<?xml version="1.0" encoding="utf-8"?>
<device xmlns:xsi="http://www.w3.org/2001/XMLSchema-instance" xmlns:xsd="http://www.w3.org/2001/XMLSchema">
  <name>FM33A0XXEV</name>
  <version>1.0</version>
  <description>ARM 32-bit Cortex SC000 Microcontroller based device</description>
  <cpu>
    <name>SC000</name>
    <version>r1p0</version>
    <endian>little</endian>
    <mpuPresent>false</mpuPresent>
    <fpuPresent>false</fpuPresent>
    <nvicPrioBits>3</nvicPrioBits>
    <vendorSystickConfig>false</vendorSystickConfig>
  </cpu>
  <addressUnitBits>8</addressUnitBits>
  <width>32</width>
  <resetValue>0x00000000</resetValue>
  <resetMask>0xFFFFFFFF</resetMask>
  <peripherals>
    <peripheral>
      <name>PMU</name>
      <description>PMU module information</description>
      <groupName>PMU</groupName>
      <baseAddress>0x40002000</baseAddress>
      <size>32</size>
      <access>read-write</access>
      <addressBlock>
        <offset>0</offset>
        <size>0x14</size>
        <usage>registers</usage>
      </addressBlock>
      <registers>
        <register>
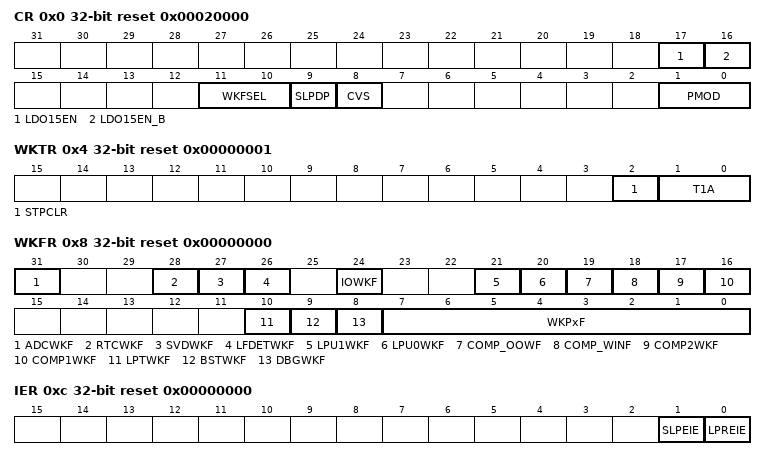
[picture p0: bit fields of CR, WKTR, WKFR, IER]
          <name>CR</name>
          <description>Power Management Control Register</description>
          <addressOffset>0x0</addressOffset>
          <size>32</size>
          <access>read-write</access>
          <resetValue>0x00020000</resetValue>
          <fields>
            <field>
              <name>LDO15EN</name>
              <description>LDO15EN  field description</description>
              <bitRange>[17:17]</bitRange>
              <access>read-only</access>
              <enumeratedValues>
                <enumeratedValue>
                  <name />
                  <description>LDO15处于工作状态</description>
                  <value>1</value>
                </enumeratedValue>
                <enumeratedValue>
                  <name />
                  <description>LDO15被关闭</description>
                  <value>0</value>
                </enumeratedValue>
              </enumeratedValues>
            </field>
            <field>
              <name>LDO15EN_B</name>
              <description>LDO15EN_B  field description</description>
              <bitRange>[16:16]</bitRange>
              <access>read-only</access>
              <enumeratedValues />
            </field>
            <field>
              <name>WKFSEL</name>
              <description>WKFSEL  field description</description>
              <bitRange>[11:10]</bitRange>
              <access>read-write</access>
              <enumeratedValues>
                <enumeratedValue>
                  <name />
                  <description>RCHF-8MHz</description>
                  <value>0</value>
                </enumeratedValue>
                <enumeratedValue>
                  <name />
                  <description>RCHF-16MHz</description>
                  <value>1</value>
                </enumeratedValue>
                <enumeratedValue>
                  <name />
                  <description>RCHF-24MHz</description>
                  <value>2</value>
                </enumeratedValue>
                <enumeratedValue>
                  <name />
                  <description>RCHF-32MHz</description>
                  <value>3</value>
                </enumeratedValue>
              </enumeratedValues>
            </field>
            <field>
              <name>SLPDP</name>
              <description>SLPDP  field description</description>
              <bitRange>[9:9]</bitRange>
              <access>read-write</access>
              <enumeratedValues>
                <enumeratedValue>
                  <name />
                  <description>DeepSleep模式使能，下关闭基准电压源</description>
                  <value>1</value>
                </enumeratedValue>
                <enumeratedValue>
                  <name />
                  <description>常规Sleep模式</description>
                  <value>0</value>
                </enumeratedValue>
              </enumeratedValues>
            </field>
            <field>
              <name>CVS</name>
              <description>CVS  field description</description>
              <bitRange>[8:8]</bitRange>
              <access>read-write</access>
              <enumeratedValues>
                <enumeratedValue>
                  <name />
                  <description>低功耗模式下不使能内核电压调整</description>
                  <value>0</value>
                </enumeratedValue>
                <enumeratedValue>
                  <name />
                  <description>低功耗模式下降低内核电压</description>
                  <value>1</value>
                </enumeratedValue>
              </enumeratedValues>
            </field>
            <field>
              <name>PMOD</name>
              <description>PMOD  field description</description>
              <bitRange>[1:0]</bitRange>
              <access>read-write</access>
              <enumeratedValues>
                <enumeratedValue>
                  <name />
                  <description>Active mode</description>
                  <value>0</value>
                </enumeratedValue>
                <enumeratedValue>
                  <name />
                  <description>LPRUN mode</description>
                  <value>1</value>
                </enumeratedValue>
                <enumeratedValue>
                  <name />
                  <description>Sleep mode / DeepSleep mode</description>
                  <value>2</value>
                </enumeratedValue>
                <enumeratedValue>
                  <name />
                  <description>RFU</description>
                  <value>3</value>
                </enumeratedValue>
              </enumeratedValues>
            </field>
          </fields>
        </register>
        <register>
          <name>WKTR</name>
          <description>Wakeup Time Register</description>
          <addressOffset>0x4</addressOffset>
          <size>32</size>
          <access>read-write</access>
          <resetValue>0x00000001</resetValue>
          <fields>
            <field>
              <name>STPCLR</name>
              <description>STPCLR  field description</description>
              <bitRange>[2:2]</bitRange>
              <access>read-write</access>
              <enumeratedValues>
                <enumeratedValue>
                  <name />
                  <description>Stop信号等待时钟建立后同步清零</description>
                  <value>0</value>
                </enumeratedValue>
                <enumeratedValue>
                  <name />
                  <description>Stop信号异步清零</description>
                  <value>1</value>
                </enumeratedValue>
              </enumeratedValues>
            </field>
            <field>
              <name>T1A</name>
              <description>T1A  field description</description>
              <bitRange>[1:0]</bitRange>
              <access>read-write</access>
              <enumeratedValues>
                <enumeratedValue>
                  <name />
                  <description>0us</description>
                  <value>0</value>
                </enumeratedValue>
                <enumeratedValue>
                  <name />
                  <description>2us</description>
                  <value>1</value>
                </enumeratedValue>
                <enumeratedValue>
                  <name />
                  <description>4us</description>
                  <value>2</value>
                </enumeratedValue>
                <enumeratedValue>
                  <name />
                  <description>8us</description>
                  <value>3</value>
                </enumeratedValue>
              </enumeratedValues>
            </field>
          </fields>
        </register>
        <register>
          <name>WKFR</name>
          <description>Wakeup Source Flags Register</description>
          <addressOffset>0x8</addressOffset>
          <size>32</size>
          <access>read-write</access>
          <resetValue>0x00000000</resetValue>
          <fields>
            <field>
              <name>ADCWKF</name>
              <description>ADCWKF  field description</description>
              <bitRange>[31:31]</bitRange>
              <access>read-only</access>
              <enumeratedValues />
            </field>
            <field>
              <name>RTCWKF</name>
              <description>RTCWKF  field description</description>
              <bitRange>[28:28]</bitRange>
              <access>read-only</access>
              <enumeratedValues />
            </field>
            <field>
              <name>SVDWKF</name>
              <description>SVDWKF  field description</description>
              <bitRange>[27:27]</bitRange>
              <access>read-only</access>
              <enumeratedValues />
            </field>
            <field>
              <name>LFDETWKF</name>
              <description>LFDETWKF  field description</description>
              <bitRange>[26:26]</bitRange>
              <access>read-only</access>
              <enumeratedValues />
            </field>
            <field>
              <name>IOWKF</name>
              <description>IOWKF  field description</description>
              <bitRange>[24:24]</bitRange>
              <access>read-only</access>
              <enumeratedValues />
            </field>
            <field>
              <name>LPU1WKF</name>
              <description>LPU1WKF  field description</description>
              <bitRange>[21:21]</bitRange>
              <access>read-only</access>
              <enumeratedValues />
            </field>
            <field>
              <name>LPU0WKF</name>
              <description>LPU0WKF  field description</description>
              <bitRange>[20:20]</bitRange>
              <access>read-only</access>
              <enumeratedValues />
            </field>
            <field>
              <name>COMP_OOWF</name>
              <description>COMP_OOWF  field description</description>
              <bitRange>[19:19]</bitRange>
              <access>read-only</access>
              <enumeratedValues />
            </field>
            <field>
              <name>COMP_WINF</name>
              <description>COMP_WINF  field description</description>
              <bitRange>[18:18]</bitRange>
              <access>read-only</access>
              <enumeratedValues />
            </field>
            <field>
              <name>COMP2WKF</name>
              <description>COMP2WKF  field description</description>
              <bitRange>[17:17]</bitRange>
              <access>read-only</access>
              <enumeratedValues />
            </field>
            <field>
              <name>COMP1WKF</name>
              <description>COMP1WKF  field description</description>
              <bitRange>[16:16]</bitRange>
              <access>read-only</access>
              <enumeratedValues />
            </field>
            <field>
              <name>LPTWKF</name>
              <description>LPTWKF  field description</description>
              <bitRange>[10:10]</bitRange>
              <access>read-only</access>
              <enumeratedValues />
            </field>
            <field>
              <name>BSTWKF</name>
              <description>BSTWKF  field description</description>
              <bitRange>[9:9]</bitRange>
              <access>read-only</access>
              <enumeratedValues />
            </field>
            <field>
              <name>DBGWKF</name>
              <description>DBGWKF  field description</description>
              <bitRange>[8:8]</bitRange>
              <access>read-write</access>
              <enumeratedValues />
            </field>
            <field>
              <name>WKPxF</name>
              <description>WKPxF  field description</description>
              <bitRange>[7:0]</bitRange>
              <access>read-write</access>
              <enumeratedValues />
            </field>
          </fields>
        </register>
        <register>
          <name>IER</name>
          <description>PMU Interrupt Enable Register</description>
          <addressOffset>0xc</addressOffset>
          <size>32</size>
          <access>read-write</access>
          <resetValue>0x00000000</resetValue>
          <fields>
            <field>
              <name>SLPEIE</name>
              <description>SLPEIE  field description</description>
              <bitRange>[1:1]</bitRange>
              <access>read-write</access>
              <enumeratedValues>
                <enumeratedValue>
                  <name />
                  <description>使能SLEEP错误中断</description>
                  <value>1</value>
                </enumeratedValue>
                <enumeratedValue>
                  <name />
                  <description>禁止SLEEP错误中断</description>
                  <value>0</value>
                </enumeratedValue>
              </enumeratedValues>
            </field>
            <field>
              <name>LPREIE</name>
              <description>LPREIE  field description</description>
              <bitRange>[0:0]</bitRange>
              <access>read-write</access>
              <enumeratedValues>
                <enumeratedValue>
                  <name />
                  <description>使能LPRUN错误中断</description>
                  <value>1</value>
                </enumeratedValue>
                <enumeratedValue>
                  <name />
                  <description>禁止LPRUN错误中断</description>
                  <value>0</value>
                </enumeratedValue>
              </enumeratedValues>
            </field>
          </fields>
        </register>
        <register>
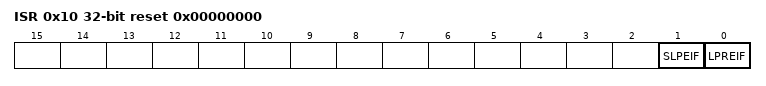
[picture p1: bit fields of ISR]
          <name>ISR</name>
          <description>PMU Interrupt and Status Register</description>
          <addressOffset>0x10</addressOffset>
          <size>32</size>
          <access>read-write</access>
          <resetValue>0x00000000</resetValue>
          <fields>
            <field>
              <name>SLPEIF</name>
              <description>SLPEIF  field description</description>
              <bitRange>[1:1]</bitRange>
              <access>read-write</access>
              <enumeratedValues>
                <enumeratedValue>
                  <name />
                  <description>在PMOD=2’h2后，CPU执行WFI/WFE指令前置位了SLEEPDEEP寄存器时置位</description>
                  <value>1</value>
                </enumeratedValue>
                <enumeratedValue>
                  <name />
                  <description>在PMOD=2’h2后，CPU正确进入SLEEP</description>
                  <value>0</value>
                </enumeratedValue>
              </enumeratedValues>
            </field>
            <field>
              <name>LPREIF</name>
              <description>LPREIF  field description</description>
              <bitRange>[0:0]</bitRange>
              <access>read-write</access>
              <enumeratedValues>
                <enumeratedValue>
                  <name />
                  <description>LPRUN Condition Error，即进入LPRUN时满足如下情况</description>
                  <value>1</value>
                </enumeratedValue>
                <enumeratedValue>
                  <name />
                  <description>LPRUN正常进入</description>
                  <value>0</value>
                </enumeratedValue>
              </enumeratedValues>
            </field>
          </fields>
        </register>
      </registers>
    </peripheral>
    <peripheral>
      <name>DBG</name>
      <description>DBG module information</description>
      <groupName>DBG</groupName>
      <baseAddress>0x40000000</baseAddress>
      <size>32</size>
      <access>read-write</access>
      <addressBlock>
        <offset>0</offset>
        <size>0x8</size>
        <usage>registers</usage>
      </addressBlock>
      <registers>
        <register>
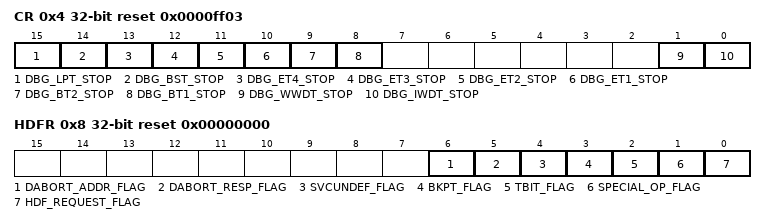
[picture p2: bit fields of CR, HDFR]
          <name>CR</name>
          <description>Debug Configuration Register</description>
          <addressOffset>0x4</addressOffset>
          <size>32</size>
          <access>read-write</access>
          <resetValue>0x0000ff03</resetValue>
          <fields>
            <field>
              <name>DBG_LPT_STOP</name>
              <description>DBG_LPT_STOP  field description</description>
              <bitRange>[15:15]</bitRange>
              <access>read-write</access>
              <enumeratedValues>
                <enumeratedValue>
                  <name />
                  <description>Debug时关闭LPTIM</description>
                  <value>1</value>
                </enumeratedValue>
                <enumeratedValue>
                  <name />
                  <description>Debug时保持LPTIM原来状态</description>
                  <value>0</value>
                </enumeratedValue>
              </enumeratedValues>
            </field>
            <field>
              <name>DBG_BST_STOP</name>
              <description>DBG_BST_STOP  field description</description>
              <bitRange>[14:14]</bitRange>
              <access>read-write</access>
              <enumeratedValues>
                <enumeratedValue>
                  <name />
                  <description>Debug时关闭BSTIM</description>
                  <value>1</value>
                </enumeratedValue>
                <enumeratedValue>
                  <name />
                  <description>Debug时保持BSTIM原来状态</description>
                  <value>0</value>
                </enumeratedValue>
              </enumeratedValues>
            </field>
            <field>
              <name>DBG_ET4_STOP</name>
              <description>DBG_ET4_STOP  field description</description>
              <bitRange>[13:13]</bitRange>
              <access>read-write</access>
              <enumeratedValues>
                <enumeratedValue>
                  <name />
                  <description>Debug时关闭ET4</description>
                  <value>1</value>
                </enumeratedValue>
                <enumeratedValue>
                  <name />
                  <description>Debug时保持ET4原来状态</description>
                  <value>0</value>
                </enumeratedValue>
              </enumeratedValues>
            </field>
            <field>
              <name>DBG_ET3_STOP</name>
              <description>DBG_ET3_STOP  field description</description>
              <bitRange>[12:12]</bitRange>
              <access>read-write</access>
              <enumeratedValues>
                <enumeratedValue>
                  <name />
                  <description>Debug时关闭ET3</description>
                  <value>1</value>
                </enumeratedValue>
                <enumeratedValue>
                  <name />
                  <description>Debug时保持ET3原来状态</description>
                  <value>0</value>
                </enumeratedValue>
              </enumeratedValues>
            </field>
            <field>
              <name>DBG_ET2_STOP</name>
              <description>DBG_ET2_STOP  field description</description>
              <bitRange>[11:11]</bitRange>
              <access>read-write</access>
              <enumeratedValues>
                <enumeratedValue>
                  <name />
                  <description>Debug时关闭ET2</description>
                  <value>1</value>
                </enumeratedValue>
                <enumeratedValue>
                  <name />
                  <description>Debug时保持ET2原来状态</description>
                  <value>0</value>
                </enumeratedValue>
              </enumeratedValues>
            </field>
            <field>
              <name>DBG_ET1_STOP</name>
              <description>DBG_ET1_STOP  field description</description>
              <bitRange>[10:10]</bitRange>
              <access>read-write</access>
              <enumeratedValues>
                <enumeratedValue>
                  <name />
                  <description>Debug时关闭ET1</description>
                  <value>1</value>
                </enumeratedValue>
                <enumeratedValue>
                  <name />
                  <description>Debug时保持ET1原来状态</description>
                  <value>0</value>
                </enumeratedValue>
              </enumeratedValues>
            </field>
            <field>
              <name>DBG_BT2_STOP</name>
              <description>DBG_BT2_STOP  field description</description>
              <bitRange>[9:9]</bitRange>
              <access>read-write</access>
              <enumeratedValues>
                <enumeratedValue>
                  <name />
                  <description>Debug时关闭BT2</description>
                  <value>1</value>
                </enumeratedValue>
                <enumeratedValue>
                  <name />
                  <description>Debug时保持BT2原来状态</description>
                  <value>0</value>
                </enumeratedValue>
              </enumeratedValues>
            </field>
            <field>
              <name>DBG_BT1_STOP</name>
              <description>DBG_BT1_STOP  field description</description>
              <bitRange>[8:8]</bitRange>
              <access>read-write</access>
              <enumeratedValues>
                <enumeratedValue>
                  <name />
                  <description>Debug时关闭BT1</description>
                  <value>1</value>
                </enumeratedValue>
                <enumeratedValue>
                  <name />
                  <description>Debug时保持BT1原来状态</description>
                  <value>0</value>
                </enumeratedValue>
              </enumeratedValues>
            </field>
            <field>
              <name>DBG_WWDT_STOP</name>
              <description>DBG_WWDT_STOP  field description</description>
              <bitRange>[1:1]</bitRange>
              <access>read-write</access>
              <enumeratedValues>
                <enumeratedValue>
                  <name />
                  <description>Debug时关闭WWDT</description>
                  <value>1</value>
                </enumeratedValue>
                <enumeratedValue>
                  <name />
                  <description>Debug时保持WWDT原来状态</description>
                  <value>0</value>
                </enumeratedValue>
              </enumeratedValues>
            </field>
            <field>
              <name>DBG_IWDT_STOP</name>
              <description>DBG_IWDT_STOP  field description</description>
              <bitRange>[0:0]</bitRange>
              <access>read-write</access>
              <enumeratedValues>
                <enumeratedValue>
                  <name />
                  <description>Debug时关闭IWDT</description>
                  <value>1</value>
                </enumeratedValue>
                <enumeratedValue>
                  <name />
                  <description>Debug时保持IWDT开启</description>
                  <value>0</value>
                </enumeratedValue>
              </enumeratedValues>
            </field>
          </fields>
        </register>
        <register>
          <name>HDFR</name>
          <description>HardFault Flag Register</description>
          <addressOffset>0x8</addressOffset>
          <size>32</size>
          <access>read-write</access>
          <resetValue>0x00000000</resetValue>
          <fields>
            <field>
              <name>DABORT_ADDR_FLAG</name>
              <description>DABORT_ADDR_FLAG  field description</description>
              <bitRange>[6:6]</bitRange>
              <access>read-write</access>
              <enumeratedValues>
                <enumeratedValue>
                  <name />
                  <description>地址非对齐访问错误</description>
                  <value>1</value>
                </enumeratedValue>
                <enumeratedValue>
                  <name />
                  <description>未进行地址非对齐访问</description>
                  <value>0</value>
                </enumeratedValue>
              </enumeratedValues>
            </field>
            <field>
              <name>DABORT_RESP_FLAG</name>
              <description>DABORT_RESP_FLAG  field description</description>
              <bitRange>[5:5]</bitRange>
              <access>read-write</access>
              <enumeratedValues>
                <enumeratedValue>
                  <name />
                  <description>总线传输中访问了非法地址导致HRESP为高产生错误</description>
                  <value>1</value>
                </enumeratedValue>
                <enumeratedValue>
                  <name />
                  <description>未访问非法地址</description>
                  <value>0</value>
                </enumeratedValue>
              </enumeratedValues>
            </field>
            <field>
              <name>SVCUNDEF_FLAG</name>
              <description>SVCUNDEF_FLAG  field description</description>
              <bitRange>[4:4]</bitRange>
              <access>read-write</access>
              <enumeratedValues />
            </field>
            <field>
              <name>BKPT_FLAG</name>
              <description>BKPT_FLAG  field description</description>
              <bitRange>[3:3]</bitRange>
              <access>read-write</access>
              <enumeratedValues>
                <enumeratedValue>
                  <name />
                  <description>执行了BKPT指令</description>
                  <value>1</value>
                </enumeratedValue>
                <enumeratedValue>
                  <name />
                  <description>未执行BKPT指令</description>
                  <value>0</value>
                </enumeratedValue>
              </enumeratedValues>
            </field>
            <field>
              <name>TBIT_FLAG</name>
              <description>TBIT_FLAG  field description</description>
              <bitRange>[2:2]</bitRange>
              <access>read-write</access>
              <enumeratedValues>
                <enumeratedValue>
                  <name />
                  <description>切换到ARM状态</description>
                  <value>1</value>
                </enumeratedValue>
                <enumeratedValue>
                  <name />
                  <description>处于Thumb-State</description>
                  <value>0</value>
                </enumeratedValue>
              </enumeratedValues>
            </field>
            <field>
              <name>SPECIAL_OP_FLAG</name>
              <description>SPECIAL_OP_FLAG  field description</description>
              <bitRange>[1:1]</bitRange>
              <access>read-write</access>
              <enumeratedValues>
                <enumeratedValue>
                  <name />
                  <description>执行了特殊指令代码，如试图在XN区域内取指</description>
                  <value>1</value>
                </enumeratedValue>
                <enumeratedValue>
                  <name />
                  <description>无特殊指令代码被执行</description>
                  <value>0</value>
                </enumeratedValue>
              </enumeratedValues>
            </field>
            <field>
              <name>HDF_REQUEST_FLAG</name>
              <description>HDF_REQUEST_FLAG  field description</description>
              <bitRange>[0:0]</bitRange>
              <access>read-write</access>
              <enumeratedValues>
                <enumeratedValue>
                  <name />
                  <description>hardfault 请求</description>
                  <value>1</value>
                </enumeratedValue>
                <enumeratedValue>
                  <name />
                  <description>无hardfault请求</description>
                  <value>0</value>
                </enumeratedValue>
              </enumeratedValues>
            </field>
          </fields>
        </register>
      </registers>
    </peripheral>
    <peripheral>
      <name>FLS</name>
      <description>FLS module information</description>
      <groupName>FLS</groupName>
      <baseAddress>0x40001000</baseAddress>
      <size>32</size>
      <access>read-write</access>
      <addressBlock>
        <offset>0</offset>
        <size>0x58</size>
        <usage>registers</usage>
      </addressBlock>
      <registers>
        <register>
          <name>RDCR</name>
          <description>Flash Read Control Register</description>
          <addressOffset>0x0</addressOffset>
          <size>32</size>
          <access>read-write</access>
          <resetValue>0x00000000</resetValue>
          <fields>
            <field>
              <name>WAIT</name>
              <description>WAIT  field description</description>
              <bitRange>[1:0]</bitRange>
              <access>read-write</access>
              <enumeratedValues>
                <enumeratedValue>
                  <name />
                  <description>0 wait cycle</description>
                  <value>0</value>
                </enumeratedValue>
                <enumeratedValue>
                  <name />
                  <description>0 wait cycle</description>
                  <value>3</value>
                </enumeratedValue>
                <enumeratedValue>
                  <name />
                  <description>1 wait cycle</description>
                  <value>1</value>
                </enumeratedValue>
                <enumeratedValue>
                  <name />
                  <description>2 wait cycles</description>
                  <value>2</value>
                </enumeratedValue>
              </enumeratedValues>
            </field>
          </fields>
        </register>
        <register>
          <name>PFCR</name>
          <description>Flash Prefetch Control Register</description>
          <addressOffset>0x4</addressOffset>
          <size>32</size>
          <access>read-write</access>
          <resetValue>0x00000000</resetValue>
          <fields>
            <field>
              <name>PRFTEN</name>
              <description>PRFTEN  field description</description>
              <bitRange>[0:0]</bitRange>
              <access>read-write</access>
              <enumeratedValues>
                <enumeratedValue>
                  <name />
                  <description>使能Prefetch</description>
                  <value>1</value>
                </enumeratedValue>
                <enumeratedValue>
                  <name />
                  <description>禁止Prefetch</description>
                  <value>0</value>
                </enumeratedValue>
              </enumeratedValues>
            </field>
          </fields>
        </register>
        <register>
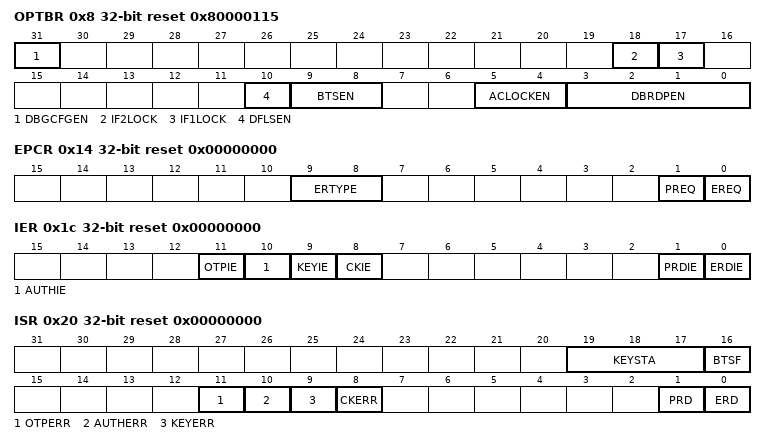
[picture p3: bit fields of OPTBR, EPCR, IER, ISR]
          <name>OPTBR</name>
          <description>Flash Option Bytes Register</description>
          <addressOffset>0x8</addressOffset>
          <size>32</size>
          <access>read-write</access>
          <resetValue>0x80000115</resetValue>
          <fields>
            <field>
              <name>DBGCFGEN</name>
              <description>DBGCFGEN  field description</description>
              <bitRange>[31:31]</bitRange>
              <access>read-only</access>
              <enumeratedValues>
                <enumeratedValue>
                  <name />
                  <description>屏蔽DBGCFG寄存器功能</description>
                  <value>0</value>
                </enumeratedValue>
                <enumeratedValue>
                  <name />
                  <description>DBGCFG寄存器使能</description>
                  <value>1</value>
                </enumeratedValue>
              </enumeratedValues>
            </field>
            <field>
              <name>IF2LOCK</name>
              <description>IF2LOCK  field description</description>
              <bitRange>[18:18]</bitRange>
              <access>read-only</access>
              <enumeratedValues>
                <enumeratedValue>
                  <name />
                  <description>未锁定</description>
                  <value>0</value>
                </enumeratedValue>
                <enumeratedValue>
                  <name />
                  <description>已锁定，锁定后软件不可改写本扇区</description>
                  <value>1</value>
                </enumeratedValue>
              </enumeratedValues>
            </field>
            <field>
              <name>IF1LOCK</name>
              <description>IF1LOCK  field description</description>
              <bitRange>[17:17]</bitRange>
              <access>read-only</access>
              <enumeratedValues>
                <enumeratedValue>
                  <name />
                  <description>未锁定</description>
                  <value>0</value>
                </enumeratedValue>
                <enumeratedValue>
                  <name />
                  <description>已锁定，锁定后软件不可改写本扇区</description>
                  <value>1</value>
                </enumeratedValue>
              </enumeratedValues>
            </field>
            <field>
              <name>DFLSEN</name>
              <description>DFLSEN  field description</description>
              <bitRange>[10:10]</bitRange>
              <access>read-only</access>
              <enumeratedValues>
                <enumeratedValue>
                  <name />
                  <description>无data flash</description>
                  <value>0</value>
                </enumeratedValue>
                <enumeratedValue>
                  <name />
                  <description>有data flash</description>
                  <value>1</value>
                </enumeratedValue>
              </enumeratedValues>
            </field>
            <field>
              <name>BTSEN</name>
              <description>BTSEN  field description</description>
              <bitRange>[9:8]</bitRange>
              <access>read-only</access>
              <enumeratedValues>
                <enumeratedValue>
                  <name />
                  <description>禁止BootSwap功能</description>
                  <value>0</value>
                </enumeratedValue>
                <enumeratedValue>
                  <name />
                  <description>禁止BootSwap功能</description>
                  <value>1</value>
                </enumeratedValue>
                <enumeratedValue>
                  <name />
                  <description>禁止BootSwap功能</description>
                  <value>3</value>
                </enumeratedValue>
                <enumeratedValue>
                  <name />
                  <description>允许BootSwap</description>
                  <value>2</value>
                </enumeratedValue>
              </enumeratedValues>
            </field>
            <field>
              <name>ACLOCKEN</name>
              <description>ACLOCKEN  field description</description>
              <bitRange>[5:4]</bitRange>
              <access>read-only</access>
              <enumeratedValues>
                <enumeratedValue>
                  <name />
                  <description>ACLOCK不使能</description>
                  <value>0</value>
                </enumeratedValue>
                <enumeratedValue>
                  <name />
                  <description>ACLOCK不使能</description>
                  <value>1</value>
                </enumeratedValue>
                <enumeratedValue>
                  <name />
                  <description>ACLOCK不使能</description>
                  <value>3</value>
                </enumeratedValue>
                <enumeratedValue>
                  <name />
                  <description>ACLOCK使能</description>
                  <value>2</value>
                </enumeratedValue>
              </enumeratedValues>
            </field>
            <field>
              <name>DBRDPEN</name>
              <description>DBRDPEN  field description</description>
              <bitRange>[3:0]</bitRange>
              <access>read-only</access>
              <enumeratedValues>
                <enumeratedValue>
                  <name />
                  <description>基本保护</description>
                  <value>f</value>
                </enumeratedValue>
                <enumeratedValue>
                  <name />
                  <description>熔断保护</description>
                  <value>a</value>
                </enumeratedValue>
                <enumeratedValue>
                  <name />
                  <description>DBRDP不使能，无保护</description>
                  <value>0</value>
                </enumeratedValue>
                <enumeratedValue>
                  <name />
                  <description>一旦进入熔断保护状态，无法退出。</description>
                  <value>0</value>
                </enumeratedValue>
              </enumeratedValues>
            </field>
          </fields>
        </register>
        <register>
          <name>EPCR</name>
          <description>Flash Erase/Program Control Register</description>
          <addressOffset>0x14</addressOffset>
          <size>32</size>
          <access>read-write</access>
          <resetValue>0x00000000</resetValue>
          <fields>
            <field>
              <name>ERTYPE</name>
              <description>ERTYPE  field description</description>
              <bitRange>[9:8]</bitRange>
              <access>read-write</access>
              <enumeratedValues>
                <enumeratedValue>
                  <name />
                  <description>Page Erase</description>
                  <value>0</value>
                </enumeratedValue>
                <enumeratedValue>
                  <name />
                  <description>Page Erase</description>
                  <value>3</value>
                </enumeratedValue>
                <enumeratedValue>
                  <name />
                  <description>Sector Erase</description>
                  <value>1</value>
                </enumeratedValue>
                <enumeratedValue>
                  <name />
                  <description>Chip Erase (SWD only)</description>
                  <value>2</value>
                </enumeratedValue>
              </enumeratedValues>
            </field>
            <field>
              <name>PREQ</name>
              <description>PREQ  field description</description>
              <bitRange>[1:1]</bitRange>
              <access>read-write</access>
              <enumeratedValues />
            </field>
            <field>
              <name>EREQ</name>
              <description>EREQ  field description</description>
              <bitRange>[0:0]</bitRange>
              <access>read-write</access>
              <enumeratedValues />
            </field>
          </fields>
        </register>
        <register>
          <name>KEY</name>
          <description>Flash Key Register</description>
          <addressOffset>0x18</addressOffset>
          <size>32</size>
          <access>read-write</access>
          <resetValue>0x00000000</resetValue>
          <fields>
            <field>
              <name>KEY</name>
              <description>KEY  field description</description>
              <bitRange>[31:0]</bitRange>
              <access>write-only</access>
              <enumeratedValues />
            </field>
          </fields>
        </register>
        <register>
          <name>IER</name>
          <description>Flash Interrupt Enable Register</description>
          <addressOffset>0x1c</addressOffset>
          <size>32</size>
          <access>read-write</access>
          <resetValue>0x00000000</resetValue>
          <fields>
            <field>
              <name>OTPIE</name>
              <description>OTPIE  field description</description>
              <bitRange>[11:11]</bitRange>
              <access>read-write</access>
              <enumeratedValues />
            </field>
            <field>
              <name>AUTHIE</name>
              <description>AUTHIE  field description</description>
              <bitRange>[10:10]</bitRange>
              <access>read-write</access>
              <enumeratedValues />
            </field>
            <field>
              <name>KEYIE</name>
              <description>KEYIE  field description</description>
              <bitRange>[9:9]</bitRange>
              <access>read-write</access>
              <enumeratedValues />
            </field>
            <field>
              <name>CKIE</name>
              <description>CKIE  field description</description>
              <bitRange>[8:8]</bitRange>
              <access>read-write</access>
              <enumeratedValues />
            </field>
            <field>
              <name>PRDIE</name>
              <description>PRDIE  field description</description>
              <bitRange>[1:1]</bitRange>
              <access>read-write</access>
              <enumeratedValues />
            </field>
            <field>
              <name>ERDIE</name>
              <description>ERDIE  field description</description>
              <bitRange>[0:0]</bitRange>
              <access>read-write</access>
              <enumeratedValues />
            </field>
          </fields>
        </register>
        <register>
          <name>ISR</name>
          <description>Flash Interrupt Status Register</description>
          <addressOffset>0x20</addressOffset>
          <size>32</size>
          <access>read-write</access>
          <resetValue>0x00000000</resetValue>
          <fields>
            <field>
              <name>KEYSTA</name>
              <description>KEYSTA  field description</description>
              <bitRange>[19:17]</bitRange>
              <access>read-only</access>
              <enumeratedValues>
                <enumeratedValue>
                  <name />
                  <description>Flash写保护状态，未输入KEY</description>
                  <value>0</value>
                </enumeratedValue>
                <enumeratedValue>
                  <name />
                  <description>全擦解锁状态</description>
                  <value>1</value>
                </enumeratedValue>
                <enumeratedValue>
                  <name />
                  <description>扇区擦解锁状态</description>
                  <value>2</value>
                </enumeratedValue>
                <enumeratedValue>
                  <name />
                  <description>编程解锁状态</description>
                  <value>3</value>
                </enumeratedValue>
                <enumeratedValue>
                  <name />
                  <description>KEY错误锁定状态，需要复位才能解锁</description>
                  <value>4</value>
                </enumeratedValue>
                <enumeratedValue>
                  <name />
                  <description>RFU</description>
                  <value>5</value>
                </enumeratedValue>
                <enumeratedValue>
                  <name />
                  <description>RFU</description>
                  <value>6</value>
                </enumeratedValue>
                <enumeratedValue>
                  <name />
                  <description>RFU</description>
                  <value>7</value>
                </enumeratedValue>
              </enumeratedValues>
            </field>
            <field>
              <name>BTSF</name>
              <description>BTSF  field description</description>
              <bitRange>[16:16]</bitRange>
              <access>read-only</access>
              <enumeratedValues>
                <enumeratedValue>
                  <name />
                  <description>启动程序区为Flash物理地址0000H~1FFFH</description>
                  <value>0</value>
                </enumeratedValue>
                <enumeratedValue>
                  <name />
                  <description>启动程序区为Flash物理地址2000H~3FFFH</description>
                  <value>1</value>
                </enumeratedValue>
              </enumeratedValues>
            </field>
            <field>
              <name>OTPERR</name>
              <description>OTPERR  field description</description>
              <bitRange>[11:11]</bitRange>
              <access>read-write</access>
              <enumeratedValues>
                <enumeratedValue>
                  <name />
                  <description>尝试对已编程的OTP字节进行编程</description>
                  <value>1</value>
                </enumeratedValue>
                <enumeratedValue>
                  <name />
                  <description>无OTP编程错误</description>
                  <value>0</value>
                </enumeratedValue>
              </enumeratedValues>
            </field>
            <field>
              <name>AUTHERR</name>
              <description>AUTHERR  field description</description>
              <bitRange>[10:10]</bitRange>
              <access>read-write</access>
              <enumeratedValues>
                <enumeratedValue>
                  <name />
                  <description>Flash访问权限错误</description>
                  <value>1</value>
                </enumeratedValue>
                <enumeratedValue>
                  <name />
                  <description>Flash访问没有发生权限错误</description>
                  <value>0</value>
                </enumeratedValue>
              </enumeratedValues>
            </field>
            <field>
              <name>KEYERR</name>
              <description>KEYERR  field description</description>
              <bitRange>[9:9]</bitRange>
              <access>read-write</access>
              <enumeratedValues />
            </field>
            <field>
              <name>CKERR</name>
              <description>CKERR  field description</description>
              <bitRange>[8:8]</bitRange>
              <access>read-write</access>
              <enumeratedValues />
            </field>
            <field>
              <name>PRD</name>
              <description>PRD  field description</description>
              <bitRange>[1:1]</bitRange>
              <access>read-write</access>
              <enumeratedValues />
            </field>
            <field>
              <name>ERD</name>
              <description>ERD  field description</description>
              <bitRange>[0:0]</bitRange>
              <access>read-write</access>
              <enumeratedValues />
            </field>
          </fields>
        </register>
        <register>
          <name>ACLOCK1</name>
          <description>Flash Application Code Lock Register1</description>
          <addressOffset>0x48</addressOffset>
          <size>32</size>
          <access>read-write</access>
          <resetValue>0x00000000</resetValue>
          <fields>
            <field>
              <name>LOCK1</name>
              <description>LOCK1  field description</description>
              <bitRange>[31:0]</bitRange>
              <access>read-write</access>
              <enumeratedValues>
                <enumeratedValue>
                  <name />
                  <description>当前Block允许SWD和软件读写</description>
                  <value>3</value>
                </enumeratedValue>
                <enumeratedValue>
                  <name />
                  <description>当前Block允许SWD读写，禁止软件读写，软件可以取指</description>
                  <value>1</value>
                </enumeratedValue>
                <enumeratedValue>
                  <name />
                  <description>当前Block允许SWD读写，禁止软件读写，软件可以取指</description>
                  <value>2</value>
                </enumeratedValue>
                <enumeratedValue>
                  <name />
                  <description>当前Block禁止SWD读写，禁止软件读写，软件可以取指</description>
                  <value>0</value>
                </enumeratedValue>
              </enumeratedValues>
            </field>
          </fields>
        </register>
        <register>
          <name>ACLOCK2</name>
          <description>Flash Application Code Lock Register2</description>
          <addressOffset>0x4c</addressOffset>
          <size>32</size>
          <access>read-write</access>
          <resetValue>0x00000000</resetValue>
          <fields>
            <field>
              <name>LOCK2</name>
              <description>LOCK2  field description</description>
              <bitRange>[31:0]</bitRange>
              <access>read-write</access>
              <enumeratedValues>
                <enumeratedValue>
                  <name />
                  <description>当前Block允许SWD和软件读写</description>
                  <value>3</value>
                </enumeratedValue>
                <enumeratedValue>
                  <name />
                  <description>当前Block允许SWD读写，禁止软件读写，软件可以取指</description>
                  <value>1</value>
                </enumeratedValue>
                <enumeratedValue>
                  <name />
                  <description>当前Block允许SWD读写，禁止软件读写，软件可以取指</description>
                  <value>2</value>
                </enumeratedValue>
                <enumeratedValue>
                  <name />
                  <description>当前Block禁止SWD读写，禁止软件读写，软件可以取指</description>
                  <value>0</value>
                </enumeratedValue>
              </enumeratedValues>
            </field>
          </fields>
        </register>
        <register>
          <name>ACLOCK3</name>
          <description>Flash Application Code Lock Register1</description>
          <addressOffset>0x50</addressOffset>
          <size>32</size>
          <access>read-write</access>
          <resetValue>0x00000000</resetValue>
          <fields>
            <field>
              <name>LOCK3</name>
              <description>LOCK3  field description</description>
              <bitRange>[31:0]</bitRange>
              <access>read-write</access>
              <enumeratedValues>
                <enumeratedValue>
                  <name />
                  <description>当前Block允许SWD和软件读写</description>
                  <value>3</value>
                </enumeratedValue>
                <enumeratedValue>
                  <name />
                  <description>当前Block允许SWD读写，禁止软件读写，软件可以取指</description>
                  <value>1</value>
                </enumeratedValue>
                <enumeratedValue>
                  <name />
                  <description>当前Block允许SWD读写，禁止软件读写，软件可以取指</description>
                  <value>2</value>
                </enumeratedValue>
                <enumeratedValue>
                  <name />
                  <description>当前Block禁止SWD读写，禁止软件读写，软件可以取指</description>
                  <value>0</value>
                </enumeratedValue>
              </enumeratedValues>
            </field>
          </fields>
        </register>
        <register>
          <name>ACLOCK4</name>
          <description>Flash Application Code Lock Register2</description>
          <addressOffset>0x54</addressOffset>
          <size>32</size>
          <access>read-write</access>
          <resetValue>0x00000000</resetValue>
          <fields>
            <field>
              <name>LOCK4</name>
              <description>LOCK4  field description</description>
              <bitRange>[31:0]</bitRange>
              <access>read-write</access>
              <enumeratedValues>
                <enumeratedValue>
                  <name />
                  <description>当前Block允许SWD和软件读写</description>
                  <value>3</value>
                </enumeratedValue>
                <enumeratedValue>
                  <name />
                  <description>当前Block允许SWD读写，禁止软件读写，软件可以取指</description>
                  <value>1</value>
                </enumeratedValue>
                <enumeratedValue>
                  <name />
                  <description>当前Block允许SWD读写，禁止软件读写，软件可以取指</description>
                  <value>2</value>
                </enumeratedValue>
                <enumeratedValue>
                  <name />
                  <description>当前Block禁止SWD读写，禁止软件读写，软件可以取指</description>
                  <value>0</value>
                </enumeratedValue>
              </enumeratedValues>
            </field>
          </fields>
        </register>
      </registers>
    </peripheral>
    <peripheral>
      <name>RMU</name>
      <description>RMU module information</description>
      <groupName>RMU</groupName>
      <baseAddress>0x40002800</baseAddress>
      <size>32</size>
      <access>read-write</access>
      <addressBlock>
        <offset>0</offset>
        <size>0x24</size>
        <usage>registers</usage>
      </addressBlock>
      <registers>
        <register>
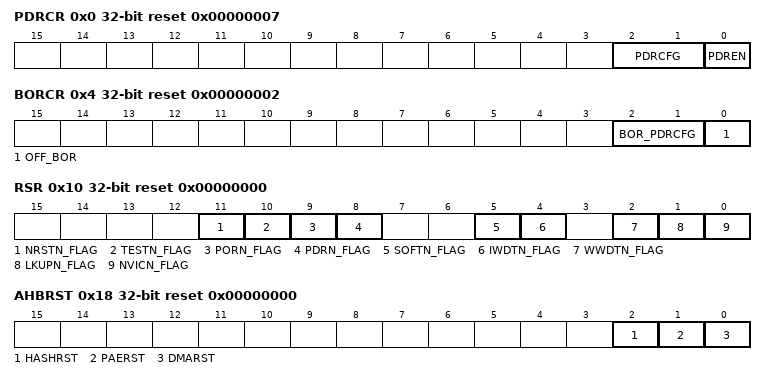
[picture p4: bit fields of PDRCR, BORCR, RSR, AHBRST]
          <name>PDRCR</name>
          <description>PDR Control Register</description>
          <addressOffset>0x0</addressOffset>
          <size>32</size>
          <access>read-write</access>
          <resetValue>0x00000007</resetValue>
          <fields>
            <field>
              <name>PDRCFG</name>
              <description>PDRCFG  field description</description>
              <bitRange>[2:1]</bitRange>
              <access>read-write</access>
              <enumeratedValues>
                <enumeratedValue>
                  <name />
                  <description>1.5V</description>
                  <value>0</value>
                </enumeratedValue>
                <enumeratedValue>
                  <name />
                  <description>1.25V（禁止使用）</description>
                  <value>1</value>
                </enumeratedValue>
                <enumeratedValue>
                  <name />
                  <description>1.35V</description>
                  <value>2</value>
                </enumeratedValue>
                <enumeratedValue>
                  <name />
                  <description>1.4V（默认）</description>
                  <value>3</value>
                </enumeratedValue>
              </enumeratedValues>
            </field>
            <field>
              <name>PDREN</name>
              <description>PDREN  field description</description>
              <bitRange>[0:0]</bitRange>
              <access>read-write</access>
              <enumeratedValues>
                <enumeratedValue>
                  <name />
                  <description>关闭下电复位</description>
                  <value>0</value>
                </enumeratedValue>
                <enumeratedValue>
                  <name />
                  <description>使能下电复位</description>
                  <value>1</value>
                </enumeratedValue>
              </enumeratedValues>
            </field>
          </fields>
        </register>
        <register>
          <name>BORCR</name>
          <description>BOR Control Register</description>
          <addressOffset>0x4</addressOffset>
          <size>32</size>
          <access>read-write</access>
          <resetValue>0x00000002</resetValue>
          <fields>
            <field>
              <name>BOR_PDRCFG</name>
              <description>BOR_PDRCFG  field description</description>
              <bitRange>[2:1]</bitRange>
              <access>read-write</access>
              <enumeratedValues>
                <enumeratedValue>
                  <name />
                  <description>1.7V</description>
                  <value>0</value>
                </enumeratedValue>
                <enumeratedValue>
                  <name />
                  <description>1.6V（默认）</description>
                  <value>1</value>
                </enumeratedValue>
                <enumeratedValue>
                  <name />
                  <description>1.65V</description>
                  <value>2</value>
                </enumeratedValue>
                <enumeratedValue>
                  <name />
                  <description>1.75V</description>
                  <value>3</value>
                </enumeratedValue>
              </enumeratedValues>
            </field>
            <field>
              <name>OFF_BOR</name>
              <description>OFF_BOR  field description</description>
              <bitRange>[0:0]</bitRange>
              <access>read-write</access>
              <enumeratedValues>
                <enumeratedValue>
                  <name />
                  <description>使能BOR</description>
                  <value>0</value>
                </enumeratedValue>
                <enumeratedValue>
                  <name />
                  <description>关闭BOR</description>
                  <value>1</value>
                </enumeratedValue>
              </enumeratedValues>
            </field>
          </fields>
        </register>
        <register>
          <name>RSTCFGR</name>
          <description>Reset Config Register</description>
          <addressOffset>0x8</addressOffset>
          <size>32</size>
          <access>read-write</access>
          <resetValue>0x00000000</resetValue>
          <fields>
            <field>
              <name>LKUPRST_EN</name>
              <description>LKUPRST_EN  field description</description>
              <bitRange>[1:1]</bitRange>
              <access>read-write</access>
              <enumeratedValues>
                <enumeratedValue>
                  <name />
                  <description>使能SC000 LOCKUP复位</description>
                  <value>1</value>
                </enumeratedValue>
                <enumeratedValue>
                  <name />
                  <description>屏蔽SC000 LOCKUP复位</description>
                  <value>0</value>
                </enumeratedValue>
              </enumeratedValues>
            </field>
          </fields>
        </register>
        <register>
          <name>SOFTRST</name>
          <description>Soft Reset Register</description>
          <addressOffset>0xc</addressOffset>
          <size>32</size>
          <access>read-write</access>
          <resetValue>0x00000000</resetValue>
          <fields>
            <field>
              <name>SOFTRST</name>
              <description>SOFTRST  field description</description>
              <bitRange>[31:0]</bitRange>
              <access>write-only</access>
              <enumeratedValues />
            </field>
          </fields>
        </register>
        <register>
          <name>RSR</name>
          <description>Reset Status Register</description>
          <addressOffset>0x10</addressOffset>
          <size>32</size>
          <access>read-write</access>
          <resetValue>0x00000000</resetValue>
          <fields>
            <field>
              <name>NRSTN_FLAG</name>
              <description>NRSTN_FLAG  field description</description>
              <bitRange>[11:11]</bitRange>
              <access>read-write</access>
              <enumeratedValues />
            </field>
            <field>
              <name>TESTN_FLAG</name>
              <description>TESTN_FLAG  field description</description>
              <bitRange>[10:10]</bitRange>
              <access>read-write</access>
              <enumeratedValues />
            </field>
            <field>
              <name>PORN_FLAG</name>
              <description>PORN_FLAG  field description</description>
              <bitRange>[9:9]</bitRange>
              <access>read-write</access>
              <enumeratedValues />
            </field>
            <field>
              <name>PDRN_FLAG</name>
              <description>PDRN_FLAG  field description</description>
              <bitRange>[8:8]</bitRange>
              <access>read-write</access>
              <enumeratedValues />
            </field>
            <field>
              <name>SOFTN_FLAG</name>
              <description>SOFTN_FLAG  field description</description>
              <bitRange>[5:5]</bitRange>
              <access>read-write</access>
              <enumeratedValues />
            </field>
            <field>
              <name>IWDTN_FLAG</name>
              <description>IWDTN_FLAG  field description</description>
              <bitRange>[4:4]</bitRange>
              <access>read-write</access>
              <enumeratedValues />
            </field>
            <field>
              <name>WWDTN_FLAG</name>
              <description>WWDTN_FLAG  field description</description>
              <bitRange>[2:2]</bitRange>
              <access>read-write</access>
              <enumeratedValues />
            </field>
            <field>
              <name>LKUPN_FLAG</name>
              <description>LKUPN_FLAG  field description</description>
              <bitRange>[1:1]</bitRange>
              <access>read-write</access>
              <enumeratedValues />
            </field>
            <field>
              <name>NVICN_FLAG</name>
              <description>NVICN_FLAG  field description</description>
              <bitRange>[0:0]</bitRange>
              <access>read-write</access>
              <enumeratedValues />
            </field>
          </fields>
        </register>
        <register>
          <name>PRSTEN</name>
          <description>Peripheral Reset Enable Register</description>
          <addressOffset>0x14</addressOffset>
          <size>32</size>
          <access>read-write</access>
          <resetValue>0x00000000</resetValue>
          <fields>
            <field>
              <name>PERHRSTEN</name>
              <description>PERHRSTEN  field description</description>
              <bitRange>[31:0]</bitRange>
              <access>write-only</access>
              <enumeratedValues />
            </field>
          </fields>
        </register>
        <register>
          <name>AHBRST</name>
          <description>AHB Peripheral Reset Register</description>
          <addressOffset>0x18</addressOffset>
          <size>32</size>
          <access>read-write</access>
          <resetValue>0x00000000</resetValue>
          <fields>
            <field>
              <name>HASHRST</name>
              <description>HASHRST  field description</description>
              <bitRange>[2:2]</bitRange>
              <access>read-write</access>
              <enumeratedValues>
                <enumeratedValue>
                  <name />
                  <description>不复位</description>
                  <value>0</value>
                </enumeratedValue>
                <enumeratedValue>
                  <name />
                  <description>复位</description>
                  <value>1</value>
                </enumeratedValue>
              </enumeratedValues>
            </field>
            <field>
              <name>PAERST</name>
              <description>PAERST  field description</description>
              <bitRange>[1:1]</bitRange>
              <access>read-write</access>
              <enumeratedValues>
                <enumeratedValue>
                  <name />
                  <description>不复位</description>
                  <value>0</value>
                </enumeratedValue>
                <enumeratedValue>
                  <name />
                  <description>复位</description>
                  <value>1</value>
                </enumeratedValue>
              </enumeratedValues>
            </field>
            <field>
              <name>DMARST</name>
              <description>DMARST  field description</description>
              <bitRange>[0:0]</bitRange>
              <access>read-write</access>
              <enumeratedValues>
                <enumeratedValue>
                  <name />
                  <description>不复位</description>
                  <value>0</value>
                </enumeratedValue>
                <enumeratedValue>
                  <name />
                  <description>复位</description>
                  <value>1</value>
                </enumeratedValue>
              </enumeratedValues>
            </field>
          </fields>
        </register>
        <register>
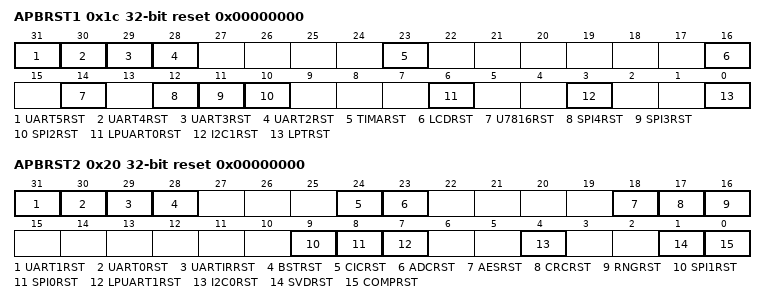
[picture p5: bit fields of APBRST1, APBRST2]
          <name>APBRST1</name>
          <description>APB Peripheral Reset Register1</description>
          <addressOffset>0x1c</addressOffset>
          <size>32</size>
          <access>read-write</access>
          <resetValue>0x00000000</resetValue>
          <fields>
            <field>
              <name>UART5RST</name>
              <description>UART5RST  field description</description>
              <bitRange>[31:31]</bitRange>
              <access>read-write</access>
              <enumeratedValues>
                <enumeratedValue>
                  <name />
                  <description>不复位</description>
                  <value>0</value>
                </enumeratedValue>
                <enumeratedValue>
                  <name />
                  <description>复位</description>
                  <value>1</value>
                </enumeratedValue>
              </enumeratedValues>
            </field>
            <field>
              <name>UART4RST</name>
              <description>UART4RST  field description</description>
              <bitRange>[30:30]</bitRange>
              <access>read-write</access>
              <enumeratedValues>
                <enumeratedValue>
                  <name />
                  <description>不复位</description>
                  <value>0</value>
                </enumeratedValue>
                <enumeratedValue>
                  <name />
                  <description>复位</description>
                  <value>1</value>
                </enumeratedValue>
              </enumeratedValues>
            </field>
            <field>
              <name>UART3RST</name>
              <description>UART3RST  field description</description>
              <bitRange>[29:29]</bitRange>
              <access>read-write</access>
              <enumeratedValues>
                <enumeratedValue>
                  <name />
                  <description>不复位</description>
                  <value>0</value>
                </enumeratedValue>
                <enumeratedValue>
                  <name />
                  <description>复位</description>
                  <value>1</value>
                </enumeratedValue>
              </enumeratedValues>
            </field>
            <field>
              <name>UART2RST</name>
              <description>UART2RST  field description</description>
              <bitRange>[28:28]</bitRange>
              <access>read-write</access>
              <enumeratedValues>
                <enumeratedValue>
                  <name />
                  <description>不复位</description>
                  <value>0</value>
                </enumeratedValue>
                <enumeratedValue>
                  <name />
                  <description>复位</description>
                  <value>1</value>
                </enumeratedValue>
              </enumeratedValues>
            </field>
            <field>
              <name>TIMARST</name>
              <description>TIMARST  field description</description>
              <bitRange>[23:23]</bitRange>
              <access>read-write</access>
              <enumeratedValues>
                <enumeratedValue>
                  <name />
                  <description>不复位</description>
                  <value>0</value>
                </enumeratedValue>
                <enumeratedValue>
                  <name />
                  <description>复位</description>
                  <value>1</value>
                </enumeratedValue>
              </enumeratedValues>
            </field>
            <field>
              <name>LCDRST</name>
              <description>LCDRST  field description</description>
              <bitRange>[16:16]</bitRange>
              <access>read-write</access>
              <enumeratedValues>
                <enumeratedValue>
                  <name />
                  <description>不复位</description>
                  <value>0</value>
                </enumeratedValue>
                <enumeratedValue>
                  <name />
                  <description>复位</description>
                  <value>1</value>
                </enumeratedValue>
              </enumeratedValues>
            </field>
            <field>
              <name>U7816RST</name>
              <description>U7816RST  field description</description>
              <bitRange>[14:14]</bitRange>
              <access>read-write</access>
              <enumeratedValues>
                <enumeratedValue>
                  <name />
                  <description>不复位</description>
                  <value>0</value>
                </enumeratedValue>
                <enumeratedValue>
                  <name />
                  <description>复位</description>
                  <value>1</value>
                </enumeratedValue>
              </enumeratedValues>
            </field>
            <field>
              <name>SPI4RST</name>
              <description>SPI4RST  field description</description>
              <bitRange>[12:12]</bitRange>
              <access>read-write</access>
              <enumeratedValues>
                <enumeratedValue>
                  <name />
                  <description>不复位</description>
                  <value>0</value>
                </enumeratedValue>
                <enumeratedValue>
                  <name />
                  <description>复位</description>
                  <value>1</value>
                </enumeratedValue>
              </enumeratedValues>
            </field>
            <field>
              <name>SPI3RST</name>
              <description>SPI3RST  field description</description>
              <bitRange>[11:11]</bitRange>
              <access>read-write</access>
              <enumeratedValues>
                <enumeratedValue>
                  <name />
                  <description>不复位</description>
                  <value>0</value>
                </enumeratedValue>
                <enumeratedValue>
                  <name />
                  <description>复位</description>
                  <value>1</value>
                </enumeratedValue>
              </enumeratedValues>
            </field>
            <field>
              <name>SPI2RST</name>
              <description>SPI2RST  field description</description>
              <bitRange>[10:10]</bitRange>
              <access>read-write</access>
              <enumeratedValues>
                <enumeratedValue>
                  <name />
                  <description>不复位</description>
                  <value>0</value>
                </enumeratedValue>
                <enumeratedValue>
                  <name />
                  <description>复位</description>
                  <value>1</value>
                </enumeratedValue>
              </enumeratedValues>
            </field>
            <field>
              <name>LPUART0RST</name>
              <description>LPUART0RST  field description</description>
              <bitRange>[6:6]</bitRange>
              <access>read-write</access>
              <enumeratedValues>
                <enumeratedValue>
                  <name />
                  <description>不复位</description>
                  <value>0</value>
                </enumeratedValue>
                <enumeratedValue>
                  <name />
                  <description>复位</description>
                  <value>1</value>
                </enumeratedValue>
              </enumeratedValues>
            </field>
            <field>
              <name>I2C1RST</name>
              <description>I2C1RST  field description</description>
              <bitRange>[3:3]</bitRange>
              <access>read-write</access>
              <enumeratedValues>
                <enumeratedValue>
                  <name />
                  <description>不复位</description>
                  <value>0</value>
                </enumeratedValue>
                <enumeratedValue>
                  <name />
                  <description>复位</description>
                  <value>1</value>
                </enumeratedValue>
              </enumeratedValues>
            </field>
            <field>
              <name>LPTRST</name>
              <description>LPTRST  field description</description>
              <bitRange>[0:0]</bitRange>
              <access>read-write</access>
              <enumeratedValues>
                <enumeratedValue>
                  <name />
                  <description>不复位</description>
                  <value>0</value>
                </enumeratedValue>
                <enumeratedValue>
                  <name />
                  <description>复位</description>
                  <value>1</value>
                </enumeratedValue>
              </enumeratedValues>
            </field>
          </fields>
        </register>
        <register>
          <name>APBRST2</name>
          <description>APB Peripheral Reset Register2</description>
          <addressOffset>0x20</addressOffset>
          <size>32</size>
          <access>read-write</access>
          <resetValue>0x00000000</resetValue>
          <fields>
            <field>
              <name>UART1RST</name>
              <description>UART1RST  field description</description>
              <bitRange>[31:31]</bitRange>
              <access>read-write</access>
              <enumeratedValues>
                <enumeratedValue>
                  <name />
                  <description>不复位</description>
                  <value>0</value>
                </enumeratedValue>
                <enumeratedValue>
                  <name />
                  <description>复位</description>
                  <value>1</value>
                </enumeratedValue>
              </enumeratedValues>
            </field>
            <field>
              <name>UART0RST</name>
              <description>UART0RST  field description</description>
              <bitRange>[30:30]</bitRange>
              <access>read-write</access>
              <enumeratedValues>
                <enumeratedValue>
                  <name />
                  <description>不复位</description>
                  <value>0</value>
                </enumeratedValue>
                <enumeratedValue>
                  <name />
                  <description>复位</description>
                  <value>1</value>
                </enumeratedValue>
              </enumeratedValues>
            </field>
            <field>
              <name>UARTIRRST</name>
              <description>UARTIRRST  field description</description>
              <bitRange>[29:29]</bitRange>
              <access>read-write</access>
              <enumeratedValues>
                <enumeratedValue>
                  <name />
                  <description>不复位</description>
                  <value>0</value>
                </enumeratedValue>
                <enumeratedValue>
                  <name />
                  <description>复位</description>
                  <value>1</value>
                </enumeratedValue>
              </enumeratedValues>
            </field>
            <field>
              <name>BSTRST</name>
              <description>BSTRST  field description</description>
              <bitRange>[28:28]</bitRange>
              <access>read-write</access>
              <enumeratedValues>
                <enumeratedValue>
                  <name />
                  <description>不复位</description>
                  <value>0</value>
                </enumeratedValue>
                <enumeratedValue>
                  <name />
                  <description>复位</description>
                  <value>1</value>
                </enumeratedValue>
              </enumeratedValues>
            </field>
            <field>
              <name>CICRST</name>
              <description>CICRST  field description</description>
              <bitRange>[24:24]</bitRange>
              <access>read-write</access>
              <enumeratedValues>
                <enumeratedValue>
                  <name />
                  <description>不复位</description>
                  <value>0</value>
                </enumeratedValue>
                <enumeratedValue>
                  <name />
                  <description>复位</description>
                  <value>1</value>
                </enumeratedValue>
              </enumeratedValues>
            </field>
            <field>
              <name>ADCRST</name>
              <description>ADCRST  field description</description>
              <bitRange>[23:23]</bitRange>
              <access>read-write</access>
              <enumeratedValues>
                <enumeratedValue>
                  <name />
                  <description>不复位</description>
                  <value>0</value>
                </enumeratedValue>
                <enumeratedValue>
                  <name />
                  <description>复位</description>
                  <value>1</value>
                </enumeratedValue>
              </enumeratedValues>
            </field>
            <field>
              <name>AESRST</name>
              <description>AESRST  field description</description>
              <bitRange>[18:18]</bitRange>
              <access>read-write</access>
              <enumeratedValues>
                <enumeratedValue>
                  <name />
                  <description>不复位</description>
                  <value>0</value>
                </enumeratedValue>
                <enumeratedValue>
                  <name />
                  <description>复位</description>
                  <value>1</value>
                </enumeratedValue>
              </enumeratedValues>
            </field>
            <field>
              <name>CRCRST</name>
              <description>CRCRST  field description</description>
              <bitRange>[17:17]</bitRange>
              <access>read-write</access>
              <enumeratedValues>
                <enumeratedValue>
                  <name />
                  <description>不复位</description>
                  <value>0</value>
                </enumeratedValue>
                <enumeratedValue>
                  <name />
                  <description>复位</description>
                  <value>1</value>
                </enumeratedValue>
              </enumeratedValues>
            </field>
            <field>
              <name>RNGRST</name>
              <description>RNGRST  field description</description>
              <bitRange>[16:16]</bitRange>
              <access>read-write</access>
              <enumeratedValues>
                <enumeratedValue>
                  <name />
                  <description>不复位</description>
                  <value>0</value>
                </enumeratedValue>
                <enumeratedValue>
                  <name />
                  <description>复位</description>
                  <value>1</value>
                </enumeratedValue>
              </enumeratedValues>
            </field>
            <field>
              <name>SPI1RST</name>
              <description>SPI1RST  field description</description>
              <bitRange>[9:9]</bitRange>
              <access>read-write</access>
              <enumeratedValues>
                <enumeratedValue>
                  <name />
                  <description>不复位</description>
                  <value>0</value>
                </enumeratedValue>
                <enumeratedValue>
                  <name />
                  <description>复位</description>
                  <value>1</value>
                </enumeratedValue>
              </enumeratedValues>
            </field>
            <field>
              <name>SPI0RST</name>
              <description>SPI0RST  field description</description>
              <bitRange>[8:8]</bitRange>
              <access>read-write</access>
              <enumeratedValues>
                <enumeratedValue>
                  <name />
                  <description>不复位</description>
                  <value>0</value>
                </enumeratedValue>
                <enumeratedValue>
                  <name />
                  <description>复位</description>
                  <value>1</value>
                </enumeratedValue>
              </enumeratedValues>
            </field>
            <field>
              <name>LPUART1RST</name>
              <description>LPUART1RST  field description</description>
              <bitRange>[7:7]</bitRange>
              <access>read-write</access>
              <enumeratedValues>
                <enumeratedValue>
                  <name />
                  <description>不复位</description>
                  <value>0</value>
                </enumeratedValue>
                <enumeratedValue>
                  <name />
                  <description>复位</description>
                  <value>1</value>
                </enumeratedValue>
              </enumeratedValues>
            </field>
            <field>
              <name>I2C0RST</name>
              <description>I2C0RST  field description</description>
              <bitRange>[4:4]</bitRange>
              <access>read-write</access>
              <enumeratedValues>
                <enumeratedValue>
                  <name />
                  <description>不复位</description>
                  <value>0</value>
                </enumeratedValue>
                <enumeratedValue>
                  <name />
                  <description>复位</description>
                  <value>1</value>
                </enumeratedValue>
              </enumeratedValues>
            </field>
            <field>
              <name>SVDRST</name>
              <description>SVDRST  field description</description>
              <bitRange>[1:1]</bitRange>
              <access>read-write</access>
              <enumeratedValues>
                <enumeratedValue>
                  <name />
                  <description>不复位</description>
                  <value>0</value>
                </enumeratedValue>
                <enumeratedValue>
                  <name />
                  <description>复位</description>
                  <value>1</value>
                </enumeratedValue>
              </enumeratedValues>
            </field>
            <field>
              <name>COMPRST</name>
              <description>COMPRST  field description</description>
              <bitRange>[0:0]</bitRange>
              <access>read-write</access>
              <enumeratedValues>
                <enumeratedValue>
                  <name />
                  <description>不复位</description>
                  <value>0</value>
                </enumeratedValue>
                <enumeratedValue>
                  <name />
                  <description>复位</description>
                  <value>1</value>
                </enumeratedValue>
              </enumeratedValues>
            </field>
          </fields>
        </register>
      </registers>
    </peripheral>
    <peripheral>
      <name>IWDT</name>
      <description>IWDT module information</description>
      <groupName>IWDT</groupName>
      <baseAddress>0x40011400</baseAddress>
      <size>32</size>
      <access>read-write</access>
      <addressBlock>
        <offset>0</offset>
        <size>0xc</size>
        <usage>registers</usage>
      </addressBlock>
      <registers>
        <register>
          <name>SERV</name>
          <description>IWDT Serve Register</description>
          <addressOffset>0x0</addressOffset>
          <size>32</size>
          <access>read-write</access>
          <resetValue>0x00000000</resetValue>
          <fields>
            <field>
              <name>IWDTSERV</name>
              <description>IWDTSERV  field description</description>
              <bitRange>[31:0]</bitRange>
              <access>write-only</access>
              <enumeratedValues />
            </field>
          </fields>
        </register>
        <register>
          <name>CFGR</name>
          <description>IWDT Config Register</description>
          <addressOffset>0x4</addressOffset>
          <size>32</size>
          <access>read-write</access>
          <resetValue>0x00000001</resetValue>
          <fields>
            <field>
              <name>IWDTOVP</name>
              <description>IWDTOVP  field description</description>
              <bitRange>[2:0]</bitRange>
              <access>read-write</access>
              <enumeratedValues>
                <enumeratedValue>
                  <name />
                  <description>125ms</description>
                  <value>0</value>
                </enumeratedValue>
                <enumeratedValue>
                  <name />
                  <description>500ms</description>
                  <value>0</value>
                </enumeratedValue>
                <enumeratedValue>
                  <name />
                  <description>2s</description>
                  <value>0</value>
                </enumeratedValue>
                <enumeratedValue>
                  <name />
                  <description>8s</description>
                  <value>0</value>
                </enumeratedValue>
                <enumeratedValue>
                  <name />
                  <description>当bit2为0时，休眠后仍使用短周期，而bit2为1时，休眠后自动使用4096s；非休眠状态下仅支持125ms/500ms/2s/8s四种周期。</description>
                  <value>0</value>
                </enumeratedValue>
              </enumeratedValues>
            </field>
          </fields>
        </register>
        <register>
          <name>CNTR</name>
          <description>IWDT Counter Register</description>
          <addressOffset>0x8</addressOffset>
          <size>32</size>
          <access>read-write</access>
          <resetValue>0x00000000</resetValue>
          <fields>
            <field>
              <name>IWDTCNT</name>
              <description>IWDTCNT  field description</description>
              <bitRange>[19:0]</bitRange>
              <access>read-only</access>
              <enumeratedValues />
            </field>
          </fields>
        </register>
      </registers>
    </peripheral>
    <peripheral>
      <name>WWDT</name>
      <description>WWDT module information</description>
      <groupName>WWDT</groupName>
      <baseAddress>0x40011800</baseAddress>
      <size>32</size>
      <access>read-write</access>
      <addressBlock>
        <offset>0</offset>
        <size>0x18</size>
        <usage>registers</usage>
      </addressBlock>
      <registers>
        <register>
          <name>CR</name>
          <description>WWDT Control Register</description>
          <addressOffset>0x0</addressOffset>
          <size>32</size>
          <access>read-write</access>
          <resetValue>0x00000000</resetValue>
          <fields>
            <field>
              <name>CON</name>
              <description>CON  field description</description>
              <bitRange>[7:0]</bitRange>
              <access>write-only</access>
              <enumeratedValues />
            </field>
          </fields>
        </register>
        <register>
          <name>CFGR</name>
          <description>WWDT Config Register</description>
          <addressOffset>0x4</addressOffset>
          <size>32</size>
          <access>read-write</access>
          <resetValue>0x00000003</resetValue>
          <fields>
            <field>
              <name>CFG</name>
              <description>CFG  field description</description>
              <bitRange>[2:0]</bitRange>
              <access>read-write</access>
              <enumeratedValues>
                <enumeratedValue>
                  <name />
                  <description>TPCLK * 4096 * 1</description>
                  <value>0</value>
                </enumeratedValue>
                <enumeratedValue>
                  <name />
                  <description>TPCLK * 4096 * 4</description>
                  <value>1</value>
                </enumeratedValue>
                <enumeratedValue>
                  <name />
                  <description>TPCLK * 4096 * 16</description>
                  <value>2</value>
                </enumeratedValue>
                <enumeratedValue>
                  <name />
                  <description>TPCLK * 4096 * 64</description>
                  <value>3</value>
                </enumeratedValue>
                <enumeratedValue>
                  <name />
                  <description>TPCLK * 4096 * 128</description>
                  <value>4</value>
                </enumeratedValue>
                <enumeratedValue>
                  <name />
                  <description>TPCLK * 4096 * 256</description>
                  <value>5</value>
                </enumeratedValue>
                <enumeratedValue>
                  <name />
                  <description>TPCLK * 4096 * 512</description>
                  <value>6</value>
                </enumeratedValue>
                <enumeratedValue>
                  <name />
                  <description>TPCLK * 4096 * 1024</description>
                  <value>7</value>
                </enumeratedValue>
              </enumeratedValues>
            </field>
          </fields>
        </register>
        <register>
          <name>CNTR</name>
          <description>WWDT Counter Register</description>
          <addressOffset>0x8</addressOffset>
          <size>32</size>
          <access>read-write</access>
          <resetValue>0x00000000</resetValue>
          <fields>
            <field>
              <name>CNT</name>
              <description>CNT  field description</description>
              <bitRange>[9:0]</bitRange>
              <access>read-only</access>
              <enumeratedValues />
            </field>
          </fields>
        </register>
        <register>
          <name>IER</name>
          <description>WWDT Interrupt Enable Register</description>
          <addressOffset>0xc</addressOffset>
          <size>32</size>
          <access>read-write</access>
          <resetValue>0x00000000</resetValue>
          <fields>
            <field>
              <name>IE</name>
              <description>IE  field description</description>
              <bitRange>[0:0]</bitRange>
              <access>read-write</access>
              <enumeratedValues>
                <enumeratedValue>
                  <name />
                  <description>中断使能禁止</description>
                  <value>0</value>
                </enumeratedValue>
                <enumeratedValue>
                  <name />
                  <description>中断使能打开</description>
                  <value>1</value>
                </enumeratedValue>
              </enumeratedValues>
            </field>
          </fields>
        </register>
        <register>
          <name>ISR</name>
          <description>WWDT Interrupt Status Register</description>
          <addressOffset>0x10</addressOffset>
          <size>32</size>
          <access>read-write</access>
          <resetValue>0x00000000</resetValue>
          <fields>
            <field>
              <name>NOVF</name>
              <description>NOVF  field description</description>
              <bitRange>[0:0]</bitRange>
              <access>read-write</access>
              <enumeratedValues>
                <enumeratedValue>
                  <name />
                  <description>无中断产生</description>
                  <value>0</value>
                </enumeratedValue>
                <enumeratedValue>
                  <name />
                  <description>中断标志置位</description>
                  <value>1</value>
                </enumeratedValue>
              </enumeratedValues>
            </field>
          </fields>
        </register>
        <register>
          <name>PSCR</name>
          <description>WWDT Prescaler Register</description>
          <addressOffset>0x14</addressOffset>
          <size>32</size>
          <access>read-write</access>
          <resetValue>0x00000000</resetValue>
          <fields>
            <field>
              <name>DIV_CNT</name>
              <description>DIV_CNT  field description</description>
              <bitRange>[11:0]</bitRange>
              <access>read-only</access>
              <enumeratedValues />
            </field>
          </fields>
        </register>
      </registers>
    </peripheral>
    <peripheral>
      <name>CMU</name>
      <description>CMU module information</description>
      <groupName>CMU</groupName>
      <baseAddress>0x40002400</baseAddress>
      <size>32</size>
      <access>read-write</access>
      <addressBlock>
        <offset>0</offset>
        <size>0x38</size>
        <usage>registers</usage>
      </addressBlock>
      <registers>
        <register>
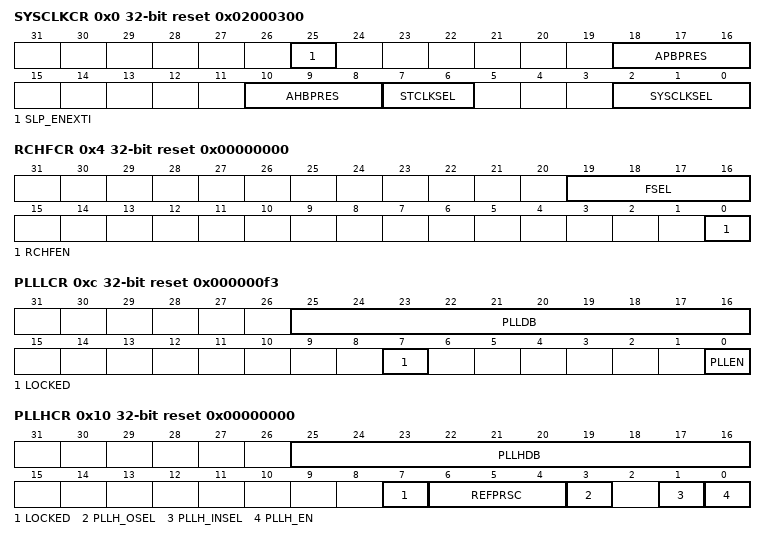
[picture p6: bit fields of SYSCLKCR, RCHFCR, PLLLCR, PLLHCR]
          <name>SYSCLKCR</name>
          <description>System Clock Control Register</description>
          <addressOffset>0x0</addressOffset>
          <size>32</size>
          <access>read-write</access>
          <resetValue>0x02000300</resetValue>
          <fields>
            <field>
              <name>SLP_ENEXTI</name>
              <description>SLP_ENEXTI  field description</description>
              <bitRange>[25:25]</bitRange>
              <access>read-write</access>
              <enumeratedValues>
                <enumeratedValue>
                  <name />
                  <description>Sleep/DeepSleep模式下使能外部引脚中断采样（采样时钟为LSCLK）</description>
                  <value>1</value>
                </enumeratedValue>
                <enumeratedValue>
                  <name />
                  <description>Sleep/DeepSleep模式下禁止外部引脚中断采样（将无法产生EXTI中断）</description>
                  <value>0</value>
                </enumeratedValue>
              </enumeratedValues>
            </field>
            <field>
              <name>APBPRES</name>
              <description>APBPRES  field description</description>
              <bitRange>[18:16]</bitRange>
              <access>read-write</access>
              <enumeratedValues>
                <enumeratedValue>
                  <name />
                  <description>不分频</description>
                  <value>0</value>
                </enumeratedValue>
                <enumeratedValue>
                  <name />
                  <description>2分频</description>
                  <value>4</value>
                </enumeratedValue>
                <enumeratedValue>
                  <name />
                  <description>4分频</description>
                  <value>5</value>
                </enumeratedValue>
                <enumeratedValue>
                  <name />
                  <description>8分频</description>
                  <value>6</value>
                </enumeratedValue>
                <enumeratedValue>
                  <name />
                  <description>16分频</description>
                  <value>7</value>
                </enumeratedValue>
              </enumeratedValues>
            </field>
            <field>
              <name>AHBPRES</name>
              <description>AHBPRES  field description</description>
              <bitRange>[10:8]</bitRange>
              <access>read-write</access>
              <enumeratedValues>
                <enumeratedValue>
                  <name />
                  <description>不分频</description>
                  <value>0</value>
                </enumeratedValue>
                <enumeratedValue>
                  <name />
                  <description>2分频</description>
                  <value>4</value>
                </enumeratedValue>
                <enumeratedValue>
                  <name />
                  <description>4分频</description>
                  <value>5</value>
                </enumeratedValue>
                <enumeratedValue>
                  <name />
                  <description>8分频</description>
                  <value>6</value>
                </enumeratedValue>
                <enumeratedValue>
                  <name />
                  <description>16分频</description>
                  <value>7</value>
                </enumeratedValue>
              </enumeratedValues>
            </field>
            <field>
              <name>STCLKSEL</name>
              <description>STCLKSEL  field description</description>
              <bitRange>[7:6]</bitRange>
              <access>read-write</access>
              <enumeratedValues>
                <enumeratedValue>
                  <name />
                  <description>SCLK</description>
                  <value>0</value>
                </enumeratedValue>
                <enumeratedValue>
                  <name />
                  <description>LSCLK</description>
                  <value>1</value>
                </enumeratedValue>
                <enumeratedValue>
                  <name />
                  <description>RFU</description>
                  <value>2</value>
                </enumeratedValue>
                <enumeratedValue>
                  <name />
                  <description>SYSCLK</description>
                  <value>3</value>
                </enumeratedValue>
              </enumeratedValues>
            </field>
            <field>
              <name>SYSCLKSEL</name>
              <description>SYSCLKSEL  field description</description>
              <bitRange>[2:0]</bitRange>
              <access>read-write</access>
              <enumeratedValues>
                <enumeratedValue>
                  <name />
                  <description>RCHF</description>
                  <value>0</value>
                </enumeratedValue>
                <enumeratedValue>
                  <name />
                  <description>XTHF</description>
                  <value>1</value>
                </enumeratedValue>
                <enumeratedValue>
                  <name />
                  <description>PLL_H</description>
                  <value>2</value>
                </enumeratedValue>
                <enumeratedValue>
                  <name />
                  <description>LSCLK</description>
                  <value>3</value>
                </enumeratedValue>
                <enumeratedValue>
                  <name />
                  <description>RCHF</description>
                  <value>0</value>
                </enumeratedValue>
              </enumeratedValues>
            </field>
          </fields>
        </register>
        <register>
          <name>RCHFCR</name>
          <description>RCHF Control Register</description>
          <addressOffset>0x4</addressOffset>
          <size>32</size>
          <access>read-write</access>
          <resetValue>0x00000000</resetValue>
          <fields>
            <field>
              <name>FSEL</name>
              <description>FSEL  field description</description>
              <bitRange>[19:16]</bitRange>
              <access>read-write</access>
              <enumeratedValues>
                <enumeratedValue>
                  <name />
                  <description>8MHz</description>
                  <value>0</value>
                </enumeratedValue>
                <enumeratedValue>
                  <name />
                  <description>16MHz</description>
                  <value>1</value>
                </enumeratedValue>
                <enumeratedValue>
                  <name />
                  <description>24MHz</description>
                  <value>2</value>
                </enumeratedValue>
                <enumeratedValue>
                  <name />
                  <description>32MHz</description>
                  <value>3</value>
                </enumeratedValue>
                <enumeratedValue>
                  <name />
                  <description>40MHz</description>
                  <value>7</value>
                </enumeratedValue>
                <enumeratedValue>
                  <name />
                  <description>48MHz</description>
                  <value>f</value>
                </enumeratedValue>
                <enumeratedValue>
                  <name />
                  <description>RFU</description>
                  <value>0</value>
                </enumeratedValue>
              </enumeratedValues>
            </field>
            <field>
              <name>RCHFEN</name>
              <description>RCHFEN  field description</description>
              <bitRange>[0:0]</bitRange>
              <access>read-write</access>
              <enumeratedValues>
                <enumeratedValue>
                  <name />
                  <description>使能RCHF</description>
                  <value>1</value>
                </enumeratedValue>
                <enumeratedValue>
                  <name />
                  <description>关闭RCHF</description>
                  <value>0</value>
                </enumeratedValue>
              </enumeratedValues>
            </field>
          </fields>
        </register>
        <register>
          <name>RCHFTR</name>
          <description>RCHF Trim Register</description>
          <addressOffset>0x8</addressOffset>
          <size>32</size>
          <access>read-write</access>
          <resetValue>0x00000000</resetValue>
          <fields>
            <field>
              <name>RCHFTRIM</name>
              <description>RCHFTRIM  field description</description>
              <bitRange>[7:0]</bitRange>
              <access>read-write</access>
              <enumeratedValues />
            </field>
          </fields>
        </register>
        <register>
          <name>PLLLCR</name>
          <description>PLL_L Control Register</description>
          <addressOffset>0xc</addressOffset>
          <size>32</size>
          <access>read-write</access>
          <resetValue>0x000000f3</resetValue>
          <fields>
            <field>
              <name>PLLDB</name>
              <description>PLLDB  field description</description>
              <bitRange>[25:16]</bitRange>
              <access>read-write</access>
              <enumeratedValues />
            </field>
            <field>
              <name>LOCKED</name>
              <description>LOCKED  field description</description>
              <bitRange>[7:7]</bitRange>
              <access>read-only</access>
              <enumeratedValues>
                <enumeratedValue>
                  <name />
                  <description>PLL_L已锁定</description>
                  <value>1</value>
                </enumeratedValue>
                <enumeratedValue>
                  <name />
                  <description>PLL_L未锁定</description>
                  <value>0</value>
                </enumeratedValue>
              </enumeratedValues>
            </field>
            <field>
              <name>PLLEN</name>
              <description>PLLEN  field description</description>
              <bitRange>[0:0]</bitRange>
              <access>read-write</access>
              <enumeratedValues>
                <enumeratedValue>
                  <name />
                  <description>使能PLL</description>
                  <value>1</value>
                </enumeratedValue>
                <enumeratedValue>
                  <name />
                  <description>关闭PLL</description>
                  <value>0</value>
                </enumeratedValue>
              </enumeratedValues>
            </field>
          </fields>
        </register>
        <register>
          <name>PLLHCR</name>
          <description>PLL_H Control Register</description>
          <addressOffset>0x10</addressOffset>
          <size>32</size>
          <access>read-write</access>
          <resetValue>0x00000000</resetValue>
          <fields>
            <field>
              <name>PLLHDB</name>
              <description>PLLHDB  field description</description>
              <bitRange>[25:16]</bitRange>
              <access>read-write</access>
              <enumeratedValues>
                <enumeratedValue>
                  <name />
                  <description>输出32倍频</description>
                  <value>1f</value>
                </enumeratedValue>
                <enumeratedValue>
                  <name />
                  <description>输出48倍频</description>
                  <value>2f</value>
                </enumeratedValue>
              </enumeratedValues>
            </field>
            <field>
              <name>LOCKED</name>
              <description>LOCKED  field description</description>
              <bitRange>[7:7]</bitRange>
              <access>read-only</access>
              <enumeratedValues>
                <enumeratedValue>
                  <name />
                  <description>PLLH已锁定</description>
                  <value>1</value>
                </enumeratedValue>
                <enumeratedValue>
                  <name />
                  <description>PLLH未锁定</description>
                  <value>0</value>
                </enumeratedValue>
              </enumeratedValues>
            </field>
            <field>
              <name>REFPRSC</name>
              <description>REFPRSC  field description</description>
              <bitRange>[6:4]</bitRange>
              <access>read-write</access>
              <enumeratedValues>
                <enumeratedValue>
                  <name />
                  <description>不分频</description>
                  <value>0</value>
                </enumeratedValue>
                <enumeratedValue>
                  <name />
                  <description>2分频</description>
                  <value>1</value>
                </enumeratedValue>
                <enumeratedValue>
                  <name />
                  <description>4分频</description>
                  <value>2</value>
                </enumeratedValue>
                <enumeratedValue>
                  <name />
                  <description>8分频</description>
                  <value>3</value>
                </enumeratedValue>
                <enumeratedValue>
                  <name />
                  <description>12分频</description>
                  <value>4</value>
                </enumeratedValue>
                <enumeratedValue>
                  <name />
                  <description>16分频</description>
                  <value>5</value>
                </enumeratedValue>
                <enumeratedValue>
                  <name />
                  <description>24分频</description>
                  <value>6</value>
                </enumeratedValue>
                <enumeratedValue>
                  <name />
                  <description>32分频</description>
                  <value>7</value>
                </enumeratedValue>
              </enumeratedValues>
            </field>
            <field>
              <name>PLLH_OSEL</name>
              <description>PLLH_OSEL  field description</description>
              <bitRange>[3:3]</bitRange>
              <access>read-write</access>
              <enumeratedValues>
                <enumeratedValue>
                  <name />
                  <description>选择PLLH一倍输出作为数字电路内的PLL时钟</description>
                  <value>0</value>
                </enumeratedValue>
                <enumeratedValue>
                  <name />
                  <description>选择PLLH两倍输出作为数字电路内的PLL时钟</description>
                  <value>1</value>
                </enumeratedValue>
              </enumeratedValues>
            </field>
            <field>
              <name>PLLH_INSEL</name>
              <description>PLLH_INSEL  field description</description>
              <bitRange>[1:1]</bitRange>
              <access>read-write</access>
              <enumeratedValues>
                <enumeratedValue>
                  <name />
                  <description>RCHF</description>
                  <value>0</value>
                </enumeratedValue>
                <enumeratedValue>
                  <name />
                  <description>XTHF</description>
                  <value>1</value>
                </enumeratedValue>
              </enumeratedValues>
            </field>
            <field>
              <name>PLLH_EN</name>
              <description>PLLH_EN  field description</description>
              <bitRange>[0:0]</bitRange>
              <access>read-write</access>
              <enumeratedValues>
                <enumeratedValue>
                  <name />
                  <description>使能PLLH</description>
                  <value>1</value>
                </enumeratedValue>
                <enumeratedValue>
                  <name />
                  <description>关闭PLLH</description>
                  <value>0</value>
                </enumeratedValue>
              </enumeratedValues>
            </field>
          </fields>
        </register>
        <register>
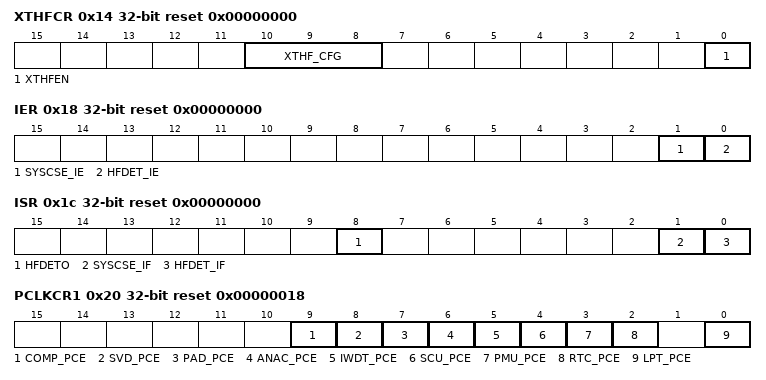
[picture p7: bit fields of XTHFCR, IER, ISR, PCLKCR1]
          <name>XTHFCR</name>
          <description>XTHF Control Register</description>
          <addressOffset>0x14</addressOffset>
          <size>32</size>
          <access>read-write</access>
          <resetValue>0x00000000</resetValue>
          <fields>
            <field>
              <name>XTHF_CFG</name>
              <description>XTHF_CFG  field description</description>
              <bitRange>[10:8]</bitRange>
              <access>read-write</access>
              <enumeratedValues>
                <enumeratedValue>
                  <name />
                  <description>最弱</description>
                  <value>0</value>
                </enumeratedValue>
                <enumeratedValue>
                  <name />
                  <description>最强</description>
                  <value>7</value>
                </enumeratedValue>
              </enumeratedValues>
            </field>
            <field>
              <name>XTHFEN</name>
              <description>XTHFEN  field description</description>
              <bitRange>[0:0]</bitRange>
              <access>read-write</access>
              <enumeratedValues>
                <enumeratedValue>
                  <name />
                  <description>关闭XTHF</description>
                  <value>0</value>
                </enumeratedValue>
                <enumeratedValue>
                  <name />
                  <description>使能XTHF</description>
                  <value>1</value>
                </enumeratedValue>
              </enumeratedValues>
            </field>
          </fields>
        </register>
        <register>
          <name>IER</name>
          <description>CMU Interrupt Enable Register</description>
          <addressOffset>0x18</addressOffset>
          <size>32</size>
          <access>read-write</access>
          <resetValue>0x00000000</resetValue>
          <fields>
            <field>
              <name>SYSCSE_IE</name>
              <description>SYSCSE_IE  field description</description>
              <bitRange>[1:1]</bitRange>
              <access>read-write</access>
              <enumeratedValues />
            </field>
            <field>
              <name>HFDET_IE</name>
              <description>HFDET_IE  field description</description>
              <bitRange>[0:0]</bitRange>
              <access>read-write</access>
              <enumeratedValues />
            </field>
          </fields>
        </register>
        <register>
          <name>ISR</name>
          <description>CMU Interrupt Status Register</description>
          <addressOffset>0x1c</addressOffset>
          <size>32</size>
          <access>read-write</access>
          <resetValue>0x00000000</resetValue>
          <fields>
            <field>
              <name>HFDETO</name>
              <description>HFDETO  field description</description>
              <bitRange>[8:8]</bitRange>
              <access>read-only</access>
              <enumeratedValues>
                <enumeratedValue>
                  <name />
                  <description>XTHF未停振</description>
                  <value>1</value>
                </enumeratedValue>
                <enumeratedValue>
                  <name />
                  <description>XTHF停振</description>
                  <value>0</value>
                </enumeratedValue>
              </enumeratedValues>
            </field>
            <field>
              <name>SYSCSE_IF</name>
              <description>SYSCSE_IF  field description</description>
              <bitRange>[1:1]</bitRange>
              <access>read-write</access>
              <enumeratedValues />
            </field>
            <field>
              <name>HFDET_IF</name>
              <description>HFDET_IF  field description</description>
              <bitRange>[0:0]</bitRange>
              <access>read-write</access>
              <enumeratedValues />
            </field>
          </fields>
        </register>
        <register>
          <name>PCLKCR1</name>
          <description>Peripheral bus Clock Control Register1</description>
          <addressOffset>0x20</addressOffset>
          <size>32</size>
          <access>read-write</access>
          <resetValue>0x00000018</resetValue>
          <fields>
            <field>
              <name>COMP_PCE</name>
              <description>COMP_PCE  field description</description>
              <bitRange>[9:9]</bitRange>
              <access>read-write</access>
              <enumeratedValues />
            </field>
            <field>
              <name>SVD_PCE</name>
              <description>SVD_PCE  field description</description>
              <bitRange>[8:8]</bitRange>
              <access>read-write</access>
              <enumeratedValues />
            </field>
            <field>
              <name>PAD_PCE</name>
              <description>PAD_PCE  field description</description>
              <bitRange>[7:7]</bitRange>
              <access>read-write</access>
              <enumeratedValues />
            </field>
            <field>
              <name>ANAC_PCE</name>
              <description>ANAC_PCE  field description</description>
              <bitRange>[6:6]</bitRange>
              <access>read-write</access>
              <enumeratedValues />
            </field>
            <field>
              <name>IWDT_PCE</name>
              <description>IWDT_PCE  field description</description>
              <bitRange>[5:5]</bitRange>
              <access>read-write</access>
              <enumeratedValues />
            </field>
            <field>
              <name>SCU_PCE</name>
              <description>SCU_PCE  field description</description>
              <bitRange>[4:4]</bitRange>
              <access>read-write</access>
              <enumeratedValues />
            </field>
            <field>
              <name>PMU_PCE</name>
              <description>PMU_PCE  field description</description>
              <bitRange>[3:3]</bitRange>
              <access>read-write</access>
              <enumeratedValues />
            </field>
            <field>
              <name>RTC_PCE</name>
              <description>RTC_PCE  field description</description>
              <bitRange>[2:2]</bitRange>
              <access>read-write</access>
              <enumeratedValues />
            </field>
            <field>
              <name>LPT_PCE</name>
              <description>LPT_PCE  field description</description>
              <bitRange>[0:0]</bitRange>
              <access>read-write</access>
              <enumeratedValues />
            </field>
          </fields>
        </register>
        <register>
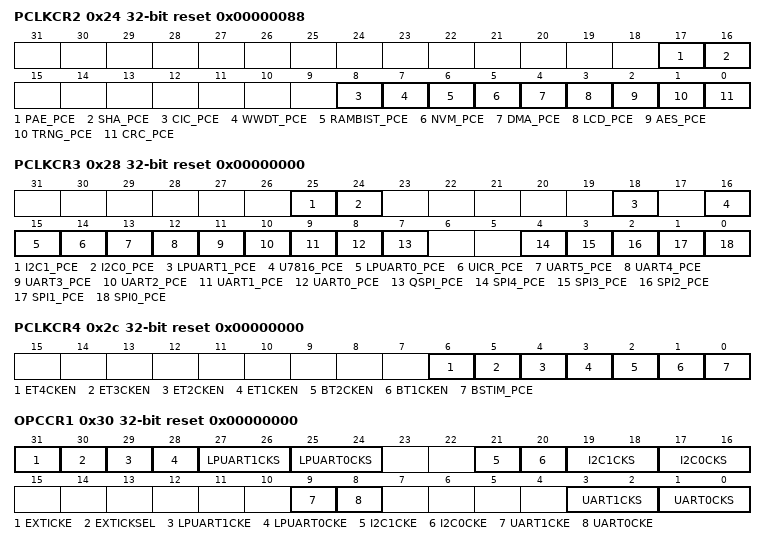
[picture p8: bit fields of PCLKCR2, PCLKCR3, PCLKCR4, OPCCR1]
          <name>PCLKCR2</name>
          <description>Peripheral bus Clock Control Register2</description>
          <addressOffset>0x24</addressOffset>
          <size>32</size>
          <access>read-write</access>
          <resetValue>0x00000088</resetValue>
          <fields>
            <field>
              <name>PAE_PCE</name>
              <description>PAE_PCE  field description</description>
              <bitRange>[17:17]</bitRange>
              <access>read-write</access>
              <enumeratedValues />
            </field>
            <field>
              <name>SHA_PCE</name>
              <description>SHA_PCE  field description</description>
              <bitRange>[16:16]</bitRange>
              <access>read-write</access>
              <enumeratedValues />
            </field>
            <field>
              <name>CIC_PCE</name>
              <description>CIC_PCE  field description</description>
              <bitRange>[8:8]</bitRange>
              <access>read-write</access>
              <enumeratedValues />
            </field>
            <field>
              <name>WWDT_PCE</name>
              <description>WWDT_PCE  field description</description>
              <bitRange>[7:7]</bitRange>
              <access>read-write</access>
              <enumeratedValues />
            </field>
            <field>
              <name>RAMBIST_PCE</name>
              <description>RAMBIST_PCE  field description</description>
              <bitRange>[6:6]</bitRange>
              <access>read-write</access>
              <enumeratedValues />
            </field>
            <field>
              <name>NVM_PCE</name>
              <description>NVM_PCE  field description</description>
              <bitRange>[5:5]</bitRange>
              <access>read-write</access>
              <enumeratedValues />
            </field>
            <field>
              <name>DMA_PCE</name>
              <description>DMA_PCE  field description</description>
              <bitRange>[4:4]</bitRange>
              <access>read-write</access>
              <enumeratedValues />
            </field>
            <field>
              <name>LCD_PCE</name>
              <description>LCD_PCE  field description</description>
              <bitRange>[3:3]</bitRange>
              <access>read-write</access>
              <enumeratedValues />
            </field>
            <field>
              <name>AES_PCE</name>
              <description>AES_PCE  field description</description>
              <bitRange>[2:2]</bitRange>
              <access>read-write</access>
              <enumeratedValues />
            </field>
            <field>
              <name>TRNG_PCE</name>
              <description>TRNG_PCE  field description</description>
              <bitRange>[1:1]</bitRange>
              <access>read-write</access>
              <enumeratedValues />
            </field>
            <field>
              <name>CRC_PCE</name>
              <description>CRC_PCE  field description</description>
              <bitRange>[0:0]</bitRange>
              <access>read-write</access>
              <enumeratedValues />
            </field>
          </fields>
        </register>
        <register>
          <name>PCLKCR3</name>
          <description>Peripheral bus Clock Control Register3</description>
          <addressOffset>0x28</addressOffset>
          <size>32</size>
          <access>read-write</access>
          <resetValue>0x00000000</resetValue>
          <fields>
            <field>
              <name>I2C1_PCE</name>
              <description>I2C1_PCE  field description</description>
              <bitRange>[25:25]</bitRange>
              <access>read-write</access>
              <enumeratedValues />
            </field>
            <field>
              <name>I2C0_PCE</name>
              <description>I2C0_PCE  field description</description>
              <bitRange>[24:24]</bitRange>
              <access>read-write</access>
              <enumeratedValues />
            </field>
            <field>
              <name>LPUART1_PCE</name>
              <description>LPUART1_PCE  field description</description>
              <bitRange>[18:18]</bitRange>
              <access>read-write</access>
              <enumeratedValues />
            </field>
            <field>
              <name>U7816_PCE</name>
              <description>U7816_PCE  field description</description>
              <bitRange>[16:16]</bitRange>
              <access>read-write</access>
              <enumeratedValues />
            </field>
            <field>
              <name>LPUART0_PCE</name>
              <description>LPUART0_PCE  field description</description>
              <bitRange>[15:15]</bitRange>
              <access>read-write</access>
              <enumeratedValues />
            </field>
            <field>
              <name>UICR_PCE</name>
              <description>UICR_PCE  field description</description>
              <bitRange>[14:14]</bitRange>
              <access>read-write</access>
              <enumeratedValues />
            </field>
            <field>
              <name>UART5_PCE</name>
              <description>UART5_PCE  field description</description>
              <bitRange>[13:13]</bitRange>
              <access>read-write</access>
              <enumeratedValues />
            </field>
            <field>
              <name>UART4_PCE</name>
              <description>UART4_PCE  field description</description>
              <bitRange>[12:12]</bitRange>
              <access>read-write</access>
              <enumeratedValues />
            </field>
            <field>
              <name>UART3_PCE</name>
              <description>UART3_PCE  field description</description>
              <bitRange>[11:11]</bitRange>
              <access>read-write</access>
              <enumeratedValues />
            </field>
            <field>
              <name>UART2_PCE</name>
              <description>UART2_PCE  field description</description>
              <bitRange>[10:10]</bitRange>
              <access>read-write</access>
              <enumeratedValues />
            </field>
            <field>
              <name>UART1_PCE</name>
              <description>UART1_PCE  field description</description>
              <bitRange>[9:9]</bitRange>
              <access>read-write</access>
              <enumeratedValues />
            </field>
            <field>
              <name>UART0_PCE</name>
              <description>UART0_PCE  field description</description>
              <bitRange>[8:8]</bitRange>
              <access>read-write</access>
              <enumeratedValues />
            </field>
            <field>
              <name>QSPI_PCE</name>
              <description>QSPI_PCE  field description</description>
              <bitRange>[7:7]</bitRange>
              <access>read-write</access>
              <enumeratedValues />
            </field>
            <field>
              <name>SPI4_PCE</name>
              <description>SPI4_PCE  field description</description>
              <bitRange>[4:4]</bitRange>
              <access>read-write</access>
              <enumeratedValues />
            </field>
            <field>
              <name>SPI3_PCE</name>
              <description>SPI3_PCE  field description</description>
              <bitRange>[3:3]</bitRange>
              <access>read-write</access>
              <enumeratedValues />
            </field>
            <field>
              <name>SPI2_PCE</name>
              <description>SPI2_PCE  field description</description>
              <bitRange>[2:2]</bitRange>
              <access>read-write</access>
              <enumeratedValues />
            </field>
            <field>
              <name>SPI1_PCE</name>
              <description>SPI1_PCE  field description</description>
              <bitRange>[1:1]</bitRange>
              <access>read-write</access>
              <enumeratedValues />
            </field>
            <field>
              <name>SPI0_PCE</name>
              <description>SPI0_PCE  field description</description>
              <bitRange>[0:0]</bitRange>
              <access>read-write</access>
              <enumeratedValues />
            </field>
          </fields>
        </register>
        <register>
          <name>PCLKCR4</name>
          <description>Peripheral bus Clock Control Register4</description>
          <addressOffset>0x2c</addressOffset>
          <size>32</size>
          <access>read-write</access>
          <resetValue>0x00000000</resetValue>
          <fields>
            <field>
              <name>ET4CKEN</name>
              <description>ET4CKEN  field description</description>
              <bitRange>[6:6]</bitRange>
              <access>read-write</access>
              <enumeratedValues />
            </field>
            <field>
              <name>ET3CKEN</name>
              <description>ET3CKEN  field description</description>
              <bitRange>[5:5]</bitRange>
              <access>read-write</access>
              <enumeratedValues />
            </field>
            <field>
              <name>ET2CKEN</name>
              <description>ET2CKEN  field description</description>
              <bitRange>[4:4]</bitRange>
              <access>read-write</access>
              <enumeratedValues />
            </field>
            <field>
              <name>ET1CKEN</name>
              <description>ET1CKEN  field description</description>
              <bitRange>[3:3]</bitRange>
              <access>read-write</access>
              <enumeratedValues />
            </field>
            <field>
              <name>BT2CKEN</name>
              <description>BT2CKEN  field description</description>
              <bitRange>[2:2]</bitRange>
              <access>read-write</access>
              <enumeratedValues />
            </field>
            <field>
              <name>BT1CKEN</name>
              <description>BT1CKEN  field description</description>
              <bitRange>[1:1]</bitRange>
              <access>read-write</access>
              <enumeratedValues />
            </field>
            <field>
              <name>BSTIM_PCE</name>
              <description>BSTIM_PCE  field description</description>
              <bitRange>[0:0]</bitRange>
              <access>read-write</access>
              <enumeratedValues />
            </field>
          </fields>
        </register>
        <register>
          <name>OPCCR1</name>
          <description>Peripheral Operation Clock Control Register1</description>
          <addressOffset>0x30</addressOffset>
          <size>32</size>
          <access>read-write</access>
          <resetValue>0x00000000</resetValue>
          <fields>
            <field>
              <name>EXTICKE</name>
              <description>EXTICKE  field description</description>
              <bitRange>[31:31]</bitRange>
              <access>read-write</access>
              <enumeratedValues />
            </field>
            <field>
              <name>EXTICKSEL</name>
              <description>EXTICKSEL  field description</description>
              <bitRange>[30:30]</bitRange>
              <access>read-write</access>
              <enumeratedValues>
                <enumeratedValue>
                  <name />
                  <description>外部引脚中断使用LSCLK采样</description>
                  <value>1</value>
                </enumeratedValue>
                <enumeratedValue>
                  <name />
                  <description>外部引脚中断使用HCLK采样</description>
                  <value>0</value>
                </enumeratedValue>
              </enumeratedValues>
            </field>
            <field>
              <name>LPUART1CKE</name>
              <description>LPUART1CKE  field description</description>
              <bitRange>[29:29]</bitRange>
              <access>read-write</access>
              <enumeratedValues />
            </field>
            <field>
              <name>LPUART0CKE</name>
              <description>LPUART0CKE  field description</description>
              <bitRange>[28:28]</bitRange>
              <access>read-write</access>
              <enumeratedValues />
            </field>
            <field>
              <name>LPUART1CKS</name>
              <description>LPUART1CKS  field description</description>
              <bitRange>[27:26]</bitRange>
              <access>read-write</access>
              <enumeratedValues>
                <enumeratedValue>
                  <name />
                  <description>LSCLK</description>
                  <value>0</value>
                </enumeratedValue>
                <enumeratedValue>
                  <name />
                  <description>RCHF分频（根据RCHF档位自动分频到32768Hz附近）</description>
                  <value>1</value>
                </enumeratedValue>
                <enumeratedValue>
                  <name />
                  <description>RFU</description>
                  <value>2</value>
                </enumeratedValue>
                <enumeratedValue>
                  <name />
                  <description>RFU</description>
                  <value>3</value>
                </enumeratedValue>
              </enumeratedValues>
            </field>
            <field>
              <name>LPUART0CKS</name>
              <description>LPUART0CKS  field description</description>
              <bitRange>[25:24]</bitRange>
              <access>read-write</access>
              <enumeratedValues>
                <enumeratedValue>
                  <name />
                  <description>LSCLK</description>
                  <value>0</value>
                </enumeratedValue>
                <enumeratedValue>
                  <name />
                  <description>RCHF分频（根据RCHF档位自动分频到32768Hz附近）</description>
                  <value>1</value>
                </enumeratedValue>
                <enumeratedValue>
                  <name />
                  <description>RFU</description>
                  <value>2</value>
                </enumeratedValue>
                <enumeratedValue>
                  <name />
                  <description>RFU</description>
                  <value>3</value>
                </enumeratedValue>
              </enumeratedValues>
            </field>
            <field>
              <name>I2C1CKE</name>
              <description>I2C1CKE  field description</description>
              <bitRange>[21:21]</bitRange>
              <access>read-write</access>
              <enumeratedValues />
            </field>
            <field>
              <name>I2C0CKE</name>
              <description>I2C0CKE  field description</description>
              <bitRange>[20:20]</bitRange>
              <access>read-write</access>
              <enumeratedValues />
            </field>
            <field>
              <name>I2C1CKS</name>
              <description>I2C1CKS  field description</description>
              <bitRange>[19:18]</bitRange>
              <access>read-write</access>
              <enumeratedValues>
                <enumeratedValue>
                  <name />
                  <description>APBCLK</description>
                  <value>0</value>
                </enumeratedValue>
                <enumeratedValue>
                  <name />
                  <description>RCHF</description>
                  <value>1</value>
                </enumeratedValue>
                <enumeratedValue>
                  <name />
                  <description>SYSCLK</description>
                  <value>2</value>
                </enumeratedValue>
                <enumeratedValue>
                  <name />
                  <description>APBCLK</description>
                  <value>3</value>
                </enumeratedValue>
              </enumeratedValues>
            </field>
            <field>
              <name>I2C0CKS</name>
              <description>I2C0CKS  field description</description>
              <bitRange>[17:16]</bitRange>
              <access>read-write</access>
              <enumeratedValues>
                <enumeratedValue>
                  <name />
                  <description>APBCLK</description>
                  <value>0</value>
                </enumeratedValue>
                <enumeratedValue>
                  <name />
                  <description>RCHF</description>
                  <value>1</value>
                </enumeratedValue>
                <enumeratedValue>
                  <name />
                  <description>SYSCLK</description>
                  <value>2</value>
                </enumeratedValue>
                <enumeratedValue>
                  <name />
                  <description>APBCLK</description>
                  <value>3</value>
                </enumeratedValue>
              </enumeratedValues>
            </field>
            <field>
              <name>UART1CKE</name>
              <description>UART1CKE  field description</description>
              <bitRange>[9:9]</bitRange>
              <access>read-write</access>
              <enumeratedValues />
            </field>
            <field>
              <name>UART0CKE</name>
              <description>UART0CKE  field description</description>
              <bitRange>[8:8]</bitRange>
              <access>read-write</access>
              <enumeratedValues />
            </field>
            <field>
              <name>UART1CKS</name>
              <description>UART1CKS  field description</description>
              <bitRange>[3:2]</bitRange>
              <access>read-write</access>
              <enumeratedValues>
                <enumeratedValue>
                  <name />
                  <description>APBCLK</description>
                  <value>0</value>
                </enumeratedValue>
                <enumeratedValue>
                  <name />
                  <description>RCHF</description>
                  <value>1</value>
                </enumeratedValue>
                <enumeratedValue>
                  <name />
                  <description>SYSCLK</description>
                  <value>2</value>
                </enumeratedValue>
                <enumeratedValue>
                  <name />
                  <description>RFU</description>
                  <value>3</value>
                </enumeratedValue>
              </enumeratedValues>
            </field>
            <field>
              <name>UART0CKS</name>
              <description>UART0CKS  field description</description>
              <bitRange>[1:0]</bitRange>
              <access>read-write</access>
              <enumeratedValues>
                <enumeratedValue>
                  <name />
                  <description>APBCLK</description>
                  <value>0</value>
                </enumeratedValue>
                <enumeratedValue>
                  <name />
                  <description>RCHF</description>
                  <value>1</value>
                </enumeratedValue>
                <enumeratedValue>
                  <name />
                  <description>SYSCLK</description>
                  <value>2</value>
                </enumeratedValue>
                <enumeratedValue>
                  <name />
                  <description>RFU</description>
                  <value>3</value>
                </enumeratedValue>
              </enumeratedValues>
            </field>
          </fields>
        </register>
        <register>
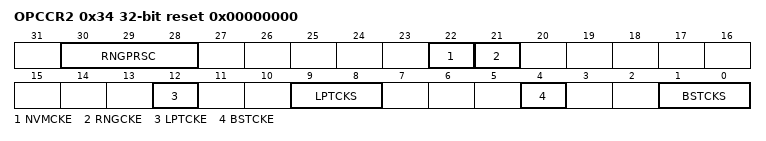
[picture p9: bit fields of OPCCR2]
          <name>OPCCR2</name>
          <description>Peripheral Operation Clock Control Register2</description>
          <addressOffset>0x34</addressOffset>
          <size>32</size>
          <access>read-write</access>
          <resetValue>0x00000000</resetValue>
          <fields>
            <field>
              <name>RNGPRSC</name>
              <description>RNGPRSC  field description</description>
              <bitRange>[30:28]</bitRange>
              <access>read-write</access>
              <enumeratedValues>
                <enumeratedValue>
                  <name />
                  <description>不分频</description>
                  <value>0</value>
                </enumeratedValue>
                <enumeratedValue>
                  <name />
                  <description>2分频</description>
                  <value>1</value>
                </enumeratedValue>
                <enumeratedValue>
                  <name />
                  <description>4分频</description>
                  <value>2</value>
                </enumeratedValue>
                <enumeratedValue>
                  <name />
                  <description>8分频</description>
                  <value>3</value>
                </enumeratedValue>
                <enumeratedValue>
                  <name />
                  <description>16分频</description>
                  <value>4</value>
                </enumeratedValue>
                <enumeratedValue>
                  <name />
                  <description>32分频</description>
                  <value>5</value>
                </enumeratedValue>
                <enumeratedValue>
                  <name />
                  <description>RFU</description>
                  <value>0</value>
                </enumeratedValue>
              </enumeratedValues>
            </field>
            <field>
              <name>NVMCKE</name>
              <description>NVMCKE  field description</description>
              <bitRange>[22:22]</bitRange>
              <access>read-write</access>
              <enumeratedValues />
            </field>
            <field>
              <name>RNGCKE</name>
              <description>RNGCKE  field description</description>
              <bitRange>[21:21]</bitRange>
              <access>read-write</access>
              <enumeratedValues />
            </field>
            <field>
              <name>LPTCKE</name>
              <description>LPTCKE  field description</description>
              <bitRange>[12:12]</bitRange>
              <access>read-write</access>
              <enumeratedValues />
            </field>
            <field>
              <name>LPTCKS</name>
              <description>LPTCKS  field description</description>
              <bitRange>[9:8]</bitRange>
              <access>read-write</access>
              <enumeratedValues>
                <enumeratedValue>
                  <name />
                  <description>APBCLK</description>
                  <value>0</value>
                </enumeratedValue>
                <enumeratedValue>
                  <name />
                  <description>LSCLK</description>
                  <value>1</value>
                </enumeratedValue>
                <enumeratedValue>
                  <name />
                  <description>RCLP</description>
                  <value>2</value>
                </enumeratedValue>
                <enumeratedValue>
                  <name />
                  <description>PLL_L</description>
                  <value>3</value>
                </enumeratedValue>
              </enumeratedValues>
            </field>
            <field>
              <name>BSTCKE</name>
              <description>BSTCKE  field description</description>
              <bitRange>[4:4]</bitRange>
              <access>read-write</access>
              <enumeratedValues />
            </field>
            <field>
              <name>BSTCKS</name>
              <description>BSTCKS  field description</description>
              <bitRange>[1:0]</bitRange>
              <access>read-write</access>
              <enumeratedValues>
                <enumeratedValue>
                  <name />
                  <description>APBCLK</description>
                  <value>0</value>
                </enumeratedValue>
                <enumeratedValue>
                  <name />
                  <description>LSCLK</description>
                  <value>1</value>
                </enumeratedValue>
                <enumeratedValue>
                  <name />
                  <description>RCLP</description>
                  <value>2</value>
                </enumeratedValue>
                <enumeratedValue>
                  <name />
                  <description>SYSCLK</description>
                  <value>3</value>
                </enumeratedValue>
              </enumeratedValues>
            </field>
          </fields>
        </register>
      </registers>
    </peripheral>
    <peripheral>
      <name>CDIF</name>
      <description>CDIF module information</description>
      <groupName>CDIF</groupName>
      <baseAddress>0x4001e000</baseAddress>
      <size>32</size>
      <access>read-write</access>
      <addressBlock>
        <offset>0</offset>
        <size>0x8</size>
        <usage>registers</usage>
      </addressBlock>
      <registers>
        <register>
          <name>CR</name>
          <description>CDIF Control Register</description>
          <addressOffset>0x0</addressOffset>
          <size>32</size>
          <access>read-write</access>
          <resetValue>0x00000005</resetValue>
          <fields>
            <field>
              <name>INTF_EN</name>
              <description>INTF_EN  field description</description>
              <bitRange>[3:0]</bitRange>
              <access>read-write</access>
              <enumeratedValues>
                <enumeratedValue>
                  <name />
                  <description>使能接口</description>
                  <value>a</value>
                </enumeratedValue>
                <enumeratedValue>
                  <name />
                  <description>关闭接口</description>
                  <value>0</value>
                </enumeratedValue>
              </enumeratedValues>
            </field>
          </fields>
        </register>
        <register>
          <name>PSCR</name>
          <description>CDIF Prescaler Register</description>
          <addressOffset>0x4</addressOffset>
          <size>32</size>
          <access>read-write</access>
          <resetValue>0x00000000</resetValue>
          <fields>
            <field>
              <name>PRSC</name>
              <description>PRSC  field description</description>
              <bitRange>[3:0]</bitRange>
              <access>read-write</access>
              <enumeratedValues>
                <enumeratedValue>
                  <name />
                  <description>1分频</description>
                  <value>0</value>
                </enumeratedValue>
                <enumeratedValue>
                  <name />
                  <description>2分频</description>
                  <value>1</value>
                </enumeratedValue>
                <enumeratedValue>
                  <name />
                  <description>4分频</description>
                  <value>2</value>
                </enumeratedValue>
                <enumeratedValue>
                  <name />
                  <description>8分频</description>
                  <value>3</value>
                </enumeratedValue>
                <enumeratedValue>
                  <name />
                  <description>16分频</description>
                  <value>4</value>
                </enumeratedValue>
                <enumeratedValue>
                  <name />
                  <description>32分频</description>
                  <value>5</value>
                </enumeratedValue>
                <enumeratedValue>
                  <name />
                  <description>64分频</description>
                  <value>6</value>
                </enumeratedValue>
                <enumeratedValue>
                  <name />
                  <description>128分频</description>
                  <value>7</value>
                </enumeratedValue>
              </enumeratedValues>
            </field>
          </fields>
        </register>
      </registers>
    </peripheral>
    <peripheral>
      <name>VRTC</name>
      <description>VRTC module information</description>
      <groupName>VRTC</groupName>
      <baseAddress>0x4001f800</baseAddress>
      <size>32</size>
      <access>read-write</access>
      <addressBlock>
        <offset>0</offset>
        <size>0x1c</size>
        <usage>registers</usage>
      </addressBlock>
      <registers>
        <register>
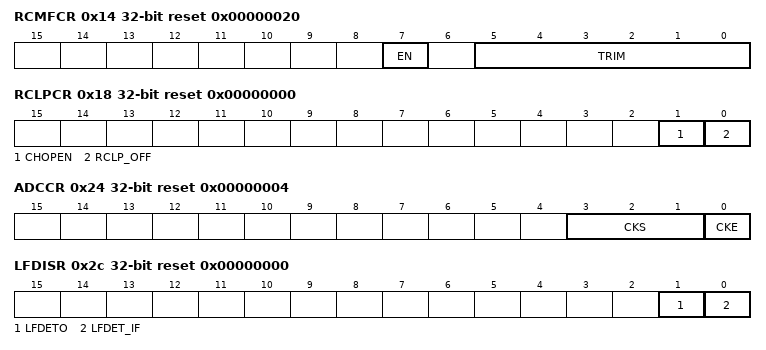
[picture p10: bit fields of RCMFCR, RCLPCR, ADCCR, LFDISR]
          <name>RCMFCR</name>
          <description>RCMF Control Register</description>
          <addressOffset>0x14</addressOffset>
          <size>32</size>
          <access>read-write</access>
          <resetValue>0x00000020</resetValue>
          <fields>
            <field>
              <name>EN</name>
              <description>EN  field description</description>
              <bitRange>[7:7]</bitRange>
              <access>read-write</access>
              <enumeratedValues>
                <enumeratedValue>
                  <name />
                  <description>关闭RCMF</description>
                  <value>0</value>
                </enumeratedValue>
                <enumeratedValue>
                  <name />
                  <description>使能RCMF</description>
                  <value>1</value>
                </enumeratedValue>
              </enumeratedValues>
            </field>
            <field>
              <name>TRIM</name>
              <description>TRIM  field description</description>
              <bitRange>[5:0]</bitRange>
              <access>read-write</access>
              <enumeratedValues />
            </field>
          </fields>
        </register>
        <register>
          <name>RCLPCR</name>
          <description>RCLP Control Register</description>
          <addressOffset>0x18</addressOffset>
          <size>32</size>
          <access>read-write</access>
          <resetValue>0x00000000</resetValue>
          <fields>
            <field>
              <name>CHOPEN</name>
              <description>CHOPEN  field description</description>
              <bitRange>[1:1]</bitRange>
              <access>read-write</access>
              <enumeratedValues />
            </field>
            <field>
              <name>RCLP_OFF</name>
              <description>RCLP_OFF  field description</description>
              <bitRange>[0:0]</bitRange>
              <access>read-write</access>
              <enumeratedValues>
                <enumeratedValue>
                  <name />
                  <description>使能RCLP</description>
                  <value>0</value>
                </enumeratedValue>
                <enumeratedValue>
                  <name />
                  <description>关闭RCLP</description>
                  <value>1</value>
                </enumeratedValue>
              </enumeratedValues>
            </field>
          </fields>
        </register>
        <register>
          <name>RCLPTR</name>
          <description>RCLP Control Register</description>
          <addressOffset>0x1c</addressOffset>
          <size>32</size>
          <access>read-write</access>
          <resetValue>0x00000000</resetValue>
          <fields>
            <field>
              <name>RCLP_TRIM</name>
              <description>RCLP_TRIM  field description</description>
              <bitRange>[7:0]</bitRange>
              <access>read-write</access>
              <enumeratedValues>
                <enumeratedValue>
                  <name />
                  <description>频率最低</description>
                  <value>0</value>
                </enumeratedValue>
                <enumeratedValue>
                  <name />
                  <description>频率最高</description>
                  <value>0</value>
                </enumeratedValue>
              </enumeratedValues>
            </field>
          </fields>
        </register>
        <register>
          <name>XTLFCR</name>
          <description>XTLF Control Register</description>
          <addressOffset>0x20</addressOffset>
          <size>32</size>
          <access>read-write</access>
          <resetValue>0x00000008</resetValue>
          <fields>
            <field>
              <name>XTLFIPW</name>
              <description>XTLFIPW  field description</description>
              <bitRange>[3:0]</bitRange>
              <access>read-write</access>
              <enumeratedValues>
                <enumeratedValue>
                  <name />
                  <description>850nA</description>
                  <value>0</value>
                </enumeratedValue>
                <enumeratedValue>
                  <name />
                  <description>800nA</description>
                  <value>1</value>
                </enumeratedValue>
                <enumeratedValue>
                  <name />
                  <description>750nA</description>
                  <value>2</value>
                </enumeratedValue>
                <enumeratedValue>
                  <name />
                  <description>700nA</description>
                  <value>3</value>
                </enumeratedValue>
                <enumeratedValue>
                  <name />
                  <description>650nA</description>
                  <value>4</value>
                </enumeratedValue>
                <enumeratedValue>
                  <name />
                  <description>600nA</description>
                  <value>5</value>
                </enumeratedValue>
                <enumeratedValue>
                  <name />
                  <description>550nA</description>
                  <value>6</value>
                </enumeratedValue>
                <enumeratedValue>
                  <name />
                  <description>500nA</description>
                  <value>7</value>
                </enumeratedValue>
                <enumeratedValue>
                  <name />
                  <description>450nA (default)</description>
                  <value>8</value>
                </enumeratedValue>
                <enumeratedValue>
                  <name />
                  <description>400nA</description>
                  <value>9</value>
                </enumeratedValue>
                <enumeratedValue>
                  <name />
                  <description>350nA</description>
                  <value>a</value>
                </enumeratedValue>
                <enumeratedValue>
                  <name />
                  <description>300nA</description>
                  <value>b</value>
                </enumeratedValue>
                <enumeratedValue>
                  <name />
                  <description>250nA</description>
                  <value>c</value>
                </enumeratedValue>
                <enumeratedValue>
                  <name />
                  <description>200nA</description>
                  <value>d</value>
                </enumeratedValue>
                <enumeratedValue>
                  <name />
                  <description>150nA</description>
                  <value>e</value>
                </enumeratedValue>
                <enumeratedValue>
                  <name />
                  <description>100nA</description>
                  <value>f</value>
                </enumeratedValue>
              </enumeratedValues>
            </field>
          </fields>
        </register>
        <register>
          <name>ADCCR</name>
          <description>ADC Clock Control Register</description>
          <addressOffset>0x24</addressOffset>
          <size>32</size>
          <access>read-write</access>
          <resetValue>0x00000004</resetValue>
          <fields>
            <field>
              <name>CKS</name>
              <description>CKS  field description</description>
              <bitRange>[3:1]</bitRange>
              <access>read-write</access>
              <enumeratedValues>
                <enumeratedValue>
                  <name />
                  <description>RCMF</description>
                  <value>0</value>
                </enumeratedValue>
                <enumeratedValue>
                  <name />
                  <description>RCMF/2</description>
                  <value>1</value>
                </enumeratedValue>
                <enumeratedValue>
                  <name />
                  <description>RCMF/4</description>
                  <value>2</value>
                </enumeratedValue>
                <enumeratedValue>
                  <name />
                  <description>RCMF/8</description>
                  <value>3</value>
                </enumeratedValue>
                <enumeratedValue>
                  <name />
                  <description>RCMF/16</description>
                  <value>4</value>
                </enumeratedValue>
                <enumeratedValue>
                  <name />
                  <description>RCMF/32</description>
                  <value>5</value>
                </enumeratedValue>
                <enumeratedValue>
                  <name />
                  <description>RCLP</description>
                  <value>6</value>
                </enumeratedValue>
                <enumeratedValue>
                  <name />
                  <description>XTLF</description>
                  <value>7</value>
                </enumeratedValue>
              </enumeratedValues>
            </field>
            <field>
              <name>CKE</name>
              <description>CKE  field description</description>
              <bitRange>[0:0]</bitRange>
              <access>read-write</access>
              <enumeratedValues>
                <enumeratedValue>
                  <name />
                  <description>关闭ADC工作时钟</description>
                  <value>0</value>
                </enumeratedValue>
                <enumeratedValue>
                  <name />
                  <description>使能ADC工作时钟</description>
                  <value>1</value>
                </enumeratedValue>
              </enumeratedValues>
            </field>
          </fields>
        </register>
        <register>
          <name>LFDIER</name>
          <description>LFDET Interrupt Enable Register</description>
          <addressOffset>0x28</addressOffset>
          <size>32</size>
          <access>read-write</access>
          <resetValue>0x00000000</resetValue>
          <fields>
            <field>
              <name>LFDET_IE</name>
              <description>LFDET_IE  field description</description>
              <bitRange>[0:0]</bitRange>
              <access>read-write</access>
              <enumeratedValues />
            </field>
          </fields>
        </register>
        <register>
          <name>LFDISR</name>
          <description>LFDET Interrupt Status Register</description>
          <addressOffset>0x2c</addressOffset>
          <size>32</size>
          <access>read-write</access>
          <resetValue>0x00000000</resetValue>
          <fields>
            <field>
              <name>LFDETO</name>
              <description>LFDETO  field description</description>
              <bitRange>[1:1]</bitRange>
              <access>read-only</access>
              <enumeratedValues>
                <enumeratedValue>
                  <name />
                  <description>XTLF正常</description>
                  <value>1</value>
                </enumeratedValue>
                <enumeratedValue>
                  <name />
                  <description>XTLF停振</description>
                  <value>0</value>
                </enumeratedValue>
              </enumeratedValues>
            </field>
            <field>
              <name>LFDET_IF</name>
              <description>LFDET_IF  field description</description>
              <bitRange>[0:0]</bitRange>
              <access>read-write</access>
              <enumeratedValues />
            </field>
          </fields>
        </register>
      </registers>
    </peripheral>
    <peripheral>
      <name>SVD</name>
      <description>SVD module information</description>
      <groupName>SVD</groupName>
      <baseAddress>0x40012800</baseAddress>
      <size>32</size>
      <access>read-write</access>
      <addressBlock>
        <offset>0</offset>
        <size>0x14</size>
        <usage>registers</usage>
      </addressBlock>
      <registers>
        <register>
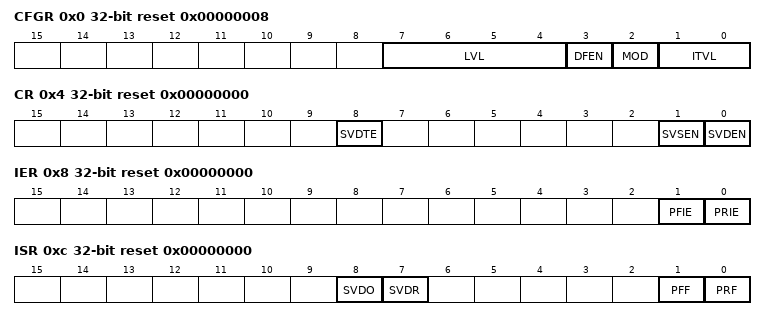
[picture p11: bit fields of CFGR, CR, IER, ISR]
          <name>CFGR</name>
          <description>SVD Config Register</description>
          <addressOffset>0x0</addressOffset>
          <size>32</size>
          <access>read-write</access>
          <resetValue>0x00000008</resetValue>
          <fields>
            <field>
              <name>LVL</name>
              <description>LVL  field description</description>
              <bitRange>[7:4]</bitRange>
              <access>read-write</access>
              <enumeratedValues />
            </field>
            <field>
              <name>DFEN</name>
              <description>DFEN  field description</description>
              <bitRange>[3:3]</bitRange>
              <access>read-write</access>
              <enumeratedValues>
                <enumeratedValue>
                  <name />
                  <description>启动SVD输出的数字滤波</description>
                  <value>1</value>
                </enumeratedValue>
                <enumeratedValue>
                  <name />
                  <description>关闭SVD输出的数字滤波</description>
                  <value>0</value>
                </enumeratedValue>
              </enumeratedValues>
            </field>
            <field>
              <name>MOD</name>
              <description>MOD  field description</description>
              <bitRange>[2:2]</bitRange>
              <access>read-write</access>
              <enumeratedValues>
                <enumeratedValue>
                  <name />
                  <description>间歇使能模式</description>
                  <value>1</value>
                </enumeratedValue>
                <enumeratedValue>
                  <name />
                  <description>常使能模式</description>
                  <value>0</value>
                </enumeratedValue>
                <enumeratedValue>
                  <name />
                  <description>间歇使能模式下必须开启数字滤波</description>
                  <value>0</value>
                </enumeratedValue>
              </enumeratedValues>
            </field>
            <field>
              <name>ITVL</name>
              <description>ITVL  field description</description>
              <bitRange>[1:0]</bitRange>
              <access>read-write</access>
              <enumeratedValues>
                <enumeratedValue>
                  <name />
                  <description>62.5ms</description>
                  <value>0</value>
                </enumeratedValue>
                <enumeratedValue>
                  <name />
                  <description>256ms</description>
                  <value>1</value>
                </enumeratedValue>
                <enumeratedValue>
                  <name />
                  <description>1s</description>
                  <value>2</value>
                </enumeratedValue>
                <enumeratedValue>
                  <name />
                  <description>4s</description>
                  <value>3</value>
                </enumeratedValue>
              </enumeratedValues>
            </field>
          </fields>
        </register>
        <register>
          <name>CR</name>
          <description>SVD Control Register</description>
          <addressOffset>0x4</addressOffset>
          <size>32</size>
          <access>read-write</access>
          <resetValue>0x00000000</resetValue>
          <fields>
            <field>
              <name>SVDTE</name>
              <description>SVDTE  field description</description>
              <bitRange>[8:8]</bitRange>
              <access>read-write</access>
              <enumeratedValues />
            </field>
            <field>
              <name>SVSEN</name>
              <description>SVSEN  field description</description>
              <bitRange>[1:1]</bitRange>
              <access>read-write</access>
              <enumeratedValues>
                <enumeratedValue>
                  <name />
                  <description>SVS通道关闭</description>
                  <value>0</value>
                </enumeratedValue>
                <enumeratedValue>
                  <name />
                  <description>SVS通道使能</description>
                  <value>1</value>
                </enumeratedValue>
              </enumeratedValues>
            </field>
            <field>
              <name>SVDEN</name>
              <description>SVDEN  field description</description>
              <bitRange>[0:0]</bitRange>
              <access>read-write</access>
              <enumeratedValues>
                <enumeratedValue>
                  <name />
                  <description>启动SVD</description>
                  <value>1</value>
                </enumeratedValue>
                <enumeratedValue>
                  <name />
                  <description>关闭SVD</description>
                  <value>0</value>
                </enumeratedValue>
              </enumeratedValues>
            </field>
          </fields>
        </register>
        <register>
          <name>IER</name>
          <description>SVD Interrupt Enable Register</description>
          <addressOffset>0x8</addressOffset>
          <size>32</size>
          <access>read-write</access>
          <resetValue>0x00000000</resetValue>
          <fields>
            <field>
              <name>PFIE</name>
              <description>PFIE  field description</description>
              <bitRange>[1:1]</bitRange>
              <access>read-write</access>
              <enumeratedValues />
            </field>
            <field>
              <name>PRIE</name>
              <description>PRIE  field description</description>
              <bitRange>[0:0]</bitRange>
              <access>read-write</access>
              <enumeratedValues />
            </field>
          </fields>
        </register>
        <register>
          <name>ISR</name>
          <description>SVD Interrupt Status Register</description>
          <addressOffset>0xc</addressOffset>
          <size>32</size>
          <access>read-write</access>
          <resetValue>0x00000000</resetValue>
          <fields>
            <field>
              <name>SVDO</name>
              <description>SVDO  field description</description>
              <bitRange>[8:8]</bitRange>
              <access>read-only</access>
              <enumeratedValues>
                <enumeratedValue>
                  <name />
                  <description>电源电压高于SVD当前阈值</description>
                  <value>1</value>
                </enumeratedValue>
                <enumeratedValue>
                  <name />
                  <description>电源电压低于SVD当前阈值</description>
                  <value>0</value>
                </enumeratedValue>
              </enumeratedValues>
            </field>
            <field>
              <name>SVDR</name>
              <description>SVDR  field description</description>
              <bitRange>[7:7]</bitRange>
              <access>read-only</access>
              <enumeratedValues />
            </field>
            <field>
              <name>PFF</name>
              <description>PFF  field description</description>
              <bitRange>[1:1]</bitRange>
              <access>read-write</access>
              <enumeratedValues />
            </field>
            <field>
              <name>PRF</name>
              <description>PRF  field description</description>
              <bitRange>[0:0]</bitRange>
              <access>read-write</access>
              <enumeratedValues />
            </field>
          </fields>
        </register>
        <register>
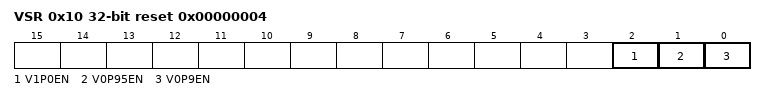
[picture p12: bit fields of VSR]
          <name>VSR</name>
          <description>SVD reference Voltage Select Register</description>
          <addressOffset>0x10</addressOffset>
          <size>32</size>
          <access>read-write</access>
          <resetValue>0x00000004</resetValue>
          <fields>
            <field>
              <name>V1P0EN</name>
              <description>V1P0EN  field description</description>
              <bitRange>[2:2]</bitRange>
              <access>read-write</access>
              <enumeratedValues>
                <enumeratedValue>
                  <name />
                  <description>使能1.0V基准输入</description>
                  <value>1</value>
                </enumeratedValue>
                <enumeratedValue>
                  <name />
                  <description>关闭1.0V基准输入</description>
                  <value>0</value>
                </enumeratedValue>
              </enumeratedValues>
            </field>
            <field>
              <name>V0P95EN</name>
              <description>V0P95EN  field description</description>
              <bitRange>[1:1]</bitRange>
              <access>read-write</access>
              <enumeratedValues>
                <enumeratedValue>
                  <name />
                  <description>使能0.95V基准输入</description>
                  <value>1</value>
                </enumeratedValue>
                <enumeratedValue>
                  <name />
                  <description>关闭0.95V基准输入</description>
                  <value>0</value>
                </enumeratedValue>
              </enumeratedValues>
            </field>
            <field>
              <name>V0P9EN</name>
              <description>V0P9EN  field description</description>
              <bitRange>[0:0]</bitRange>
              <access>read-write</access>
              <enumeratedValues>
                <enumeratedValue>
                  <name />
                  <description>使能0.9V基准输入</description>
                  <value>1</value>
                </enumeratedValue>
                <enumeratedValue>
                  <name />
                  <description>关闭0.9V基准输入</description>
                  <value>0</value>
                </enumeratedValue>
              </enumeratedValues>
            </field>
          </fields>
        </register>
      </registers>
    </peripheral>
    <peripheral>
      <name>AES</name>
      <description>AES module information</description>
      <groupName>AES</groupName>
      <baseAddress>0x40013800</baseAddress>
      <size>32</size>
      <access>read-write</access>
      <addressBlock>
        <offset>0</offset>
        <size>0x54</size>
        <usage>registers</usage>
      </addressBlock>
      <registers>
        <register>
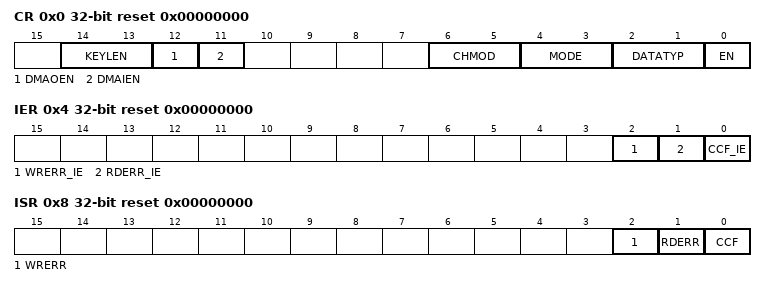
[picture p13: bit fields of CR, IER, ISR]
          <name>CR</name>
          <description>AES Control Register</description>
          <addressOffset>0x0</addressOffset>
          <size>32</size>
          <access>read-write</access>
          <resetValue>0x00000000</resetValue>
          <fields>
            <field>
              <name>KEYLEN</name>
              <description>KEYLEN  field description</description>
              <bitRange>[14:13]</bitRange>
              <access>read-write</access>
              <enumeratedValues>
                <enumeratedValue>
                  <name />
                  <description>128bit</description>
                  <value>0</value>
                </enumeratedValue>
                <enumeratedValue>
                  <name />
                  <description>192bit</description>
                  <value>1</value>
                </enumeratedValue>
                <enumeratedValue>
                  <name />
                  <description>256bit</description>
                  <value>2</value>
                </enumeratedValue>
                <enumeratedValue>
                  <name />
                  <description>保留</description>
                  <value>3</value>
                </enumeratedValue>
              </enumeratedValues>
            </field>
            <field>
              <name>DMAOEN</name>
              <description>DMAOEN  field description</description>
              <bitRange>[12:12]</bitRange>
              <access>read-write</access>
              <enumeratedValues>
                <enumeratedValue>
                  <name />
                  <description>不开启</description>
                  <value>0</value>
                </enumeratedValue>
                <enumeratedValue>
                  <name />
                  <description>开启</description>
                  <value>1</value>
                </enumeratedValue>
              </enumeratedValues>
            </field>
            <field>
              <name>DMAIEN</name>
              <description>DMAIEN  field description</description>
              <bitRange>[11:11]</bitRange>
              <access>read-write</access>
              <enumeratedValues>
                <enumeratedValue>
                  <name />
                  <description>不开启</description>
                  <value>0</value>
                </enumeratedValue>
                <enumeratedValue>
                  <name />
                  <description>开启</description>
                  <value>1</value>
                </enumeratedValue>
              </enumeratedValues>
            </field>
            <field>
              <name>CHMOD</name>
              <description>CHMOD  field description</description>
              <bitRange>[6:5]</bitRange>
              <access>read-write</access>
              <enumeratedValues>
                <enumeratedValue>
                  <name />
                  <description>ECB</description>
                  <value>0</value>
                </enumeratedValue>
                <enumeratedValue>
                  <name />
                  <description>CBC</description>
                  <value>1</value>
                </enumeratedValue>
                <enumeratedValue>
                  <name />
                  <description>CTR</description>
                  <value>2</value>
                </enumeratedValue>
                <enumeratedValue>
                  <name />
                  <description>使用MultH模块</description>
                  <value>3</value>
                </enumeratedValue>
              </enumeratedValues>
            </field>
            <field>
              <name>MODE</name>
              <description>MODE  field description</description>
              <bitRange>[4:3]</bitRange>
              <access>read-write</access>
              <enumeratedValues>
                <enumeratedValue>
                  <name />
                  <description>模式1</description>
                  <value>0</value>
                </enumeratedValue>
                <enumeratedValue>
                  <name />
                  <description>模式2</description>
                  <value>1</value>
                </enumeratedValue>
                <enumeratedValue>
                  <name />
                  <description>模式3</description>
                  <value>2</value>
                </enumeratedValue>
                <enumeratedValue>
                  <name />
                  <description>模式4</description>
                  <value>3</value>
                </enumeratedValue>
              </enumeratedValues>
            </field>
            <field>
              <name>DATATYP</name>
              <description>DATATYP  field description</description>
              <bitRange>[2:1]</bitRange>
              <access>read-write</access>
              <enumeratedValues>
                <enumeratedValue>
                  <name />
                  <description>32bit数据不交换</description>
                  <value>0</value>
                </enumeratedValue>
                <enumeratedValue>
                  <name />
                  <description>16bit数据半字交换</description>
                  <value>1</value>
                </enumeratedValue>
                <enumeratedValue>
                  <name />
                  <description>8bit数据字节交换</description>
                  <value>2</value>
                </enumeratedValue>
                <enumeratedValue>
                  <name />
                  <description>1bit数据比特交换</description>
                  <value>3</value>
                </enumeratedValue>
              </enumeratedValues>
            </field>
            <field>
              <name>EN</name>
              <description>EN  field description</description>
              <bitRange>[0:0]</bitRange>
              <access>read-write</access>
              <enumeratedValues>
                <enumeratedValue>
                  <name />
                  <description>不使能</description>
                  <value>0</value>
                </enumeratedValue>
                <enumeratedValue>
                  <name />
                  <description>使能</description>
                  <value>1</value>
                </enumeratedValue>
              </enumeratedValues>
            </field>
          </fields>
        </register>
        <register>
          <name>IER</name>
          <description>AES Interrupt Enable Register</description>
          <addressOffset>0x4</addressOffset>
          <size>32</size>
          <access>read-write</access>
          <resetValue>0x00000000</resetValue>
          <fields>
            <field>
              <name>WRERR_IE</name>
              <description>WRERR_IE  field description</description>
              <bitRange>[2:2]</bitRange>
              <access>read-write</access>
              <enumeratedValues />
            </field>
            <field>
              <name>RDERR_IE</name>
              <description>RDERR_IE  field description</description>
              <bitRange>[1:1]</bitRange>
              <access>read-write</access>
              <enumeratedValues />
            </field>
            <field>
              <name>CCF_IE</name>
              <description>CCF_IE  field description</description>
              <bitRange>[0:0]</bitRange>
              <access>read-write</access>
              <enumeratedValues />
            </field>
          </fields>
        </register>
        <register>
          <name>ISR</name>
          <description>AES Interrupt Status Register</description>
          <addressOffset>0x8</addressOffset>
          <size>32</size>
          <access>read-write</access>
          <resetValue>0x00000000</resetValue>
          <fields>
            <field>
              <name>WRERR</name>
              <description>WRERR  field description</description>
              <bitRange>[2:2]</bitRange>
              <access>read-write</access>
              <enumeratedValues />
            </field>
            <field>
              <name>RDERR</name>
              <description>RDERR  field description</description>
              <bitRange>[1:1]</bitRange>
              <access>read-write</access>
              <enumeratedValues />
            </field>
            <field>
              <name>CCF</name>
              <description>CCF  field description</description>
              <bitRange>[0:0]</bitRange>
              <access>read-write</access>
              <enumeratedValues>
                <enumeratedValue>
                  <name />
                  <description>计算完成</description>
                  <value>1</value>
                </enumeratedValue>
                <enumeratedValue>
                  <name />
                  <description>计算没有完成</description>
                  <value>0</value>
                </enumeratedValue>
              </enumeratedValues>
            </field>
          </fields>
        </register>
        <register>
          <name>DIR</name>
          <description>AES Data Input Register</description>
          <addressOffset>0xc</addressOffset>
          <size>32</size>
          <access>read-write</access>
          <resetValue>0x00000000</resetValue>
          <fields>
            <field>
              <name>DIN</name>
              <description>DIN  field description</description>
              <bitRange>[31:0]</bitRange>
              <access>read-write</access>
              <enumeratedValues>
                <enumeratedValue>
                  <name />
                  <description>把明文从MSB到LSB分4次写入。</description>
                  <value>0</value>
                </enumeratedValue>
                <enumeratedValue>
                  <name />
                  <description>无需使用数据输入寄存器</description>
                  <value>0</value>
                </enumeratedValue>
                <enumeratedValue>
                  <name />
                  <description>把密文从MSB到LSB分4次写入。</description>
                  <value>0</value>
                </enumeratedValue>
                <enumeratedValue>
                  <name />
                  <description>把乘数A或C从MSB到LSB分4次写入。</description>
                  <value>0</value>
                </enumeratedValue>
              </enumeratedValues>
            </field>
          </fields>
        </register>
        <register>
          <name>DOR</name>
          <description>AES Data Output Register</description>
          <addressOffset>0x10</addressOffset>
          <size>32</size>
          <access>read-write</access>
          <resetValue>0x00000000</resetValue>
          <fields>
            <field>
              <name>DOUT</name>
              <description>DOUT  field description</description>
              <bitRange>[31:0]</bitRange>
              <access>read-only</access>
              <enumeratedValues>
                <enumeratedValue>
                  <name />
                  <description>把密文从MSB到LSB分4次读出。</description>
                  <value>0</value>
                </enumeratedValue>
                <enumeratedValue>
                  <name />
                  <description>无需使用数据输输出寄存器</description>
                  <value>0</value>
                </enumeratedValue>
                <enumeratedValue>
                  <name />
                  <description>把明文从MSB到LSB分4次输出。</description>
                  <value>0</value>
                </enumeratedValue>
                <enumeratedValue>
                  <name />
                  <description>运算结果存储在IVR寄存器中，无需读取AES_DOUTR寄存器。</description>
                  <value>0</value>
                </enumeratedValue>
              </enumeratedValues>
            </field>
          </fields>
        </register>
        <register>
          <name>KEY0</name>
          <description>AES Key Register 0</description>
          <addressOffset>0x14</addressOffset>
          <size>32</size>
          <access>read-write</access>
          <resetValue>0x00000000</resetValue>
          <fields>
            <field>
              <name>KEYx</name>
              <description>KEYx  field description</description>
              <bitRange>[31:0]</bitRange>
              <access>write-only</access>
              <enumeratedValues>
                <enumeratedValue>
                  <name />
                  <description>此寄存器软件只可写，不可读；此寄存器内容不受WWDT复位影响</description>
                  <value>0</value>
                </enumeratedValue>
              </enumeratedValues>
            </field>
          </fields>
        </register>
        <register>
          <name>KEY1</name>
          <description>AES Key Register 1</description>
          <addressOffset>0x18</addressOffset>
          <size>32</size>
          <access>read-write</access>
          <resetValue>0x00000000</resetValue>
          <fields>
            <field>
              <name>KEYx</name>
              <description>KEYx  field description</description>
              <bitRange>[31:0]</bitRange>
              <access>write-only</access>
              <enumeratedValues>
                <enumeratedValue>
                  <name />
                  <description>此寄存器软件只可写，不可读；此寄存器内容不受WWDT复位影响</description>
                  <value>0</value>
                </enumeratedValue>
              </enumeratedValues>
            </field>
          </fields>
        </register>
        <register>
          <name>KEY2</name>
          <description>AES Key Register 2</description>
          <addressOffset>0x1c</addressOffset>
          <size>32</size>
          <access>read-write</access>
          <resetValue>0x00000000</resetValue>
          <fields>
            <field>
              <name>KEYx</name>
              <description>KEYx  field description</description>
              <bitRange>[31:0]</bitRange>
              <access>write-only</access>
              <enumeratedValues>
                <enumeratedValue>
                  <name />
                  <description>此寄存器软件只可写，不可读；此寄存器内容不受WWDT复位影响</description>
                  <value>0</value>
                </enumeratedValue>
              </enumeratedValues>
            </field>
          </fields>
        </register>
        <register>
          <name>KEY3</name>
          <description>AES Key Register 3</description>
          <addressOffset>0x20</addressOffset>
          <size>32</size>
          <access>read-write</access>
          <resetValue>0x00000000</resetValue>
          <fields>
            <field>
              <name>KEYx</name>
              <description>KEYx  field description</description>
              <bitRange>[31:0]</bitRange>
              <access>write-only</access>
              <enumeratedValues>
                <enumeratedValue>
                  <name />
                  <description>此寄存器软件只可写，不可读；此寄存器内容不受WWDT复位影响</description>
                  <value>0</value>
                </enumeratedValue>
              </enumeratedValues>
            </field>
          </fields>
        </register>
        <register>
          <name>KEY4</name>
          <description>AES Key Register 4</description>
          <addressOffset>0x24</addressOffset>
          <size>32</size>
          <access>read-write</access>
          <resetValue>0x00000000</resetValue>
          <fields>
            <field>
              <name>KEYx</name>
              <description>KEYx  field description</description>
              <bitRange>[31:0]</bitRange>
              <access>write-only</access>
              <enumeratedValues>
                <enumeratedValue>
                  <name />
                  <description>此寄存器软件只可写，不可读；此寄存器内容不受WWDT复位影响</description>
                  <value>0</value>
                </enumeratedValue>
              </enumeratedValues>
            </field>
          </fields>
        </register>
        <register>
          <name>KEY5</name>
          <description>AES Key Register 5</description>
          <addressOffset>0x28</addressOffset>
          <size>32</size>
          <access>read-write</access>
          <resetValue>0x00000000</resetValue>
          <fields>
            <field>
              <name>KEYx</name>
              <description>KEYx  field description</description>
              <bitRange>[31:0]</bitRange>
              <access>write-only</access>
              <enumeratedValues>
                <enumeratedValue>
                  <name />
                  <description>此寄存器软件只可写，不可读；此寄存器内容不受WWDT复位影响</description>
                  <value>0</value>
                </enumeratedValue>
              </enumeratedValues>
            </field>
          </fields>
        </register>
        <register>
          <name>KEY6</name>
          <description>AES Key Register 6</description>
          <addressOffset>0x2c</addressOffset>
          <size>32</size>
          <access>read-write</access>
          <resetValue>0x00000000</resetValue>
          <fields>
            <field>
              <name>KEYx</name>
              <description>KEYx  field description</description>
              <bitRange>[31:0]</bitRange>
              <access>write-only</access>
              <enumeratedValues>
                <enumeratedValue>
                  <name />
                  <description>此寄存器软件只可写，不可读；此寄存器内容不受WWDT复位影响</description>
                  <value>0</value>
                </enumeratedValue>
              </enumeratedValues>
            </field>
          </fields>
        </register>
        <register>
          <name>KEY7</name>
          <description>AES Key Register 7</description>
          <addressOffset>0x30</addressOffset>
          <size>32</size>
          <access>read-write</access>
          <resetValue>0x00000000</resetValue>
          <fields>
            <field>
              <name>KEYx</name>
              <description>KEYx  field description</description>
              <bitRange>[31:0]</bitRange>
              <access>write-only</access>
              <enumeratedValues>
                <enumeratedValue>
                  <name />
                  <description>此寄存器软件只可写，不可读；此寄存器内容不受WWDT复位影响</description>
                  <value>0</value>
                </enumeratedValue>
              </enumeratedValues>
            </field>
          </fields>
        </register>
        <register>
          <name>IVR0</name>
          <description>AES Initial Vector Register 0</description>
          <addressOffset>0x34</addressOffset>
          <size>32</size>
          <access>read-write</access>
          <resetValue>0x00000000</resetValue>
          <fields>
            <field>
              <name>IVRx</name>
              <description>IVRx  field description</description>
              <bitRange>[31:0]</bitRange>
              <access>read-write</access>
              <enumeratedValues />
            </field>
          </fields>
        </register>
        <register>
          <name>IVR1</name>
          <description>AES Initial Vector Register 1</description>
          <addressOffset>0x38</addressOffset>
          <size>32</size>
          <access>read-write</access>
          <resetValue>0x00000000</resetValue>
          <fields>
            <field>
              <name>IVRx</name>
              <description>IVRx  field description</description>
              <bitRange>[31:0]</bitRange>
              <access>read-write</access>
              <enumeratedValues />
            </field>
          </fields>
        </register>
        <register>
          <name>IVR2</name>
          <description>AES Initial Vector Register 2</description>
          <addressOffset>0x3c</addressOffset>
          <size>32</size>
          <access>read-write</access>
          <resetValue>0x00000000</resetValue>
          <fields>
            <field>
              <name>IVRx</name>
              <description>IVRx  field description</description>
              <bitRange>[31:0]</bitRange>
              <access>read-write</access>
              <enumeratedValues />
            </field>
          </fields>
        </register>
        <register>
          <name>IVR3</name>
          <description>AES Initial Vector Register 3</description>
          <addressOffset>0x40</addressOffset>
          <size>32</size>
          <access>read-write</access>
          <resetValue>0x00000000</resetValue>
          <fields>
            <field>
              <name>IVRx</name>
              <description>IVRx  field description</description>
              <bitRange>[31:0]</bitRange>
              <access>read-write</access>
              <enumeratedValues />
            </field>
          </fields>
        </register>
        <register>
          <name>H0</name>
          <description>AES MultH parameter Register 0</description>
          <addressOffset>0x44</addressOffset>
          <size>32</size>
          <access>read-write</access>
          <resetValue>0x00000000</resetValue>
          <fields>
            <field>
              <name>Hx</name>
              <description>Hx  field description</description>
              <bitRange>[31:0]</bitRange>
              <access>read-write</access>
              <enumeratedValues />
            </field>
          </fields>
        </register>
        <register>
          <name>H1</name>
          <description>AES MultH parameter Register 1</description>
          <addressOffset>0x48</addressOffset>
          <size>32</size>
          <access>read-write</access>
          <resetValue>0x00000000</resetValue>
          <fields>
            <field>
              <name>Hx</name>
              <description>Hx  field description</description>
              <bitRange>[31:0]</bitRange>
              <access>read-write</access>
              <enumeratedValues />
            </field>
          </fields>
        </register>
        <register>
          <name>H2</name>
          <description>AES MultH parameter Register 2</description>
          <addressOffset>0x4c</addressOffset>
          <size>32</size>
          <access>read-write</access>
          <resetValue>0x00000000</resetValue>
          <fields>
            <field>
              <name>Hx</name>
              <description>Hx  field description</description>
              <bitRange>[31:0]</bitRange>
              <access>read-write</access>
              <enumeratedValues />
            </field>
          </fields>
        </register>
        <register>
          <name>H3</name>
          <description>AES MultH parameter Register 3</description>
          <addressOffset>0x50</addressOffset>
          <size>32</size>
          <access>read-write</access>
          <resetValue>0x00000000</resetValue>
          <fields>
            <field>
              <name>Hx</name>
              <description>Hx  field description</description>
              <bitRange>[31:0]</bitRange>
              <access>read-write</access>
              <enumeratedValues />
            </field>
          </fields>
        </register>
      </registers>
    </peripheral>
    <peripheral>
      <name>PAE</name>
      <description>PAE module information</description>
      <groupName>PAE</groupName>
      <baseAddress>0x40001400</baseAddress>
      <size>32</size>
      <access>read-write</access>
      <addressBlock>
        <offset>0</offset>
        <size>0x20</size>
        <usage>registers</usage>
      </addressBlock>
      <registers>
        <register>
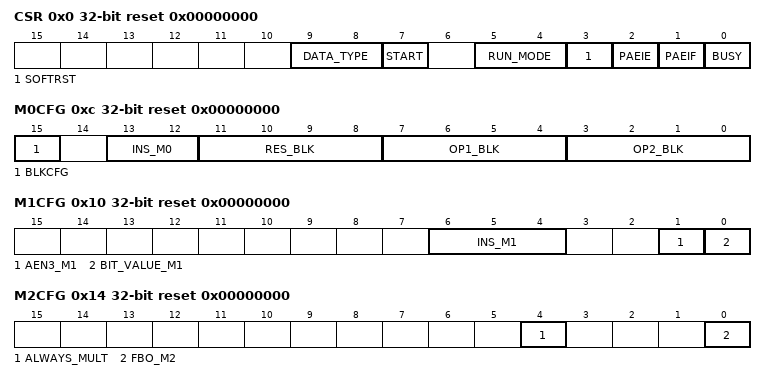
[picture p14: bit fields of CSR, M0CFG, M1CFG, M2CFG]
          <name>CSR</name>
          <description />
          <addressOffset>0x0</addressOffset>
          <size>32</size>
          <access>read-write</access>
          <resetValue>0x00000000</resetValue>
          <fields>
            <field>
              <name>DATA_TYPE</name>
              <description>DATA_TYPE  field description</description>
              <bitRange>[9:8]</bitRange>
              <access>read-write</access>
              <enumeratedValues>
                <enumeratedValue>
                  <name />
                  <description>不交换</description>
                  <value>0</value>
                </enumeratedValue>
                <enumeratedValue>
                  <name />
                  <description>half-word交换</description>
                  <value>1</value>
                </enumeratedValue>
                <enumeratedValue>
                  <name />
                  <description>byte交换</description>
                  <value>2</value>
                </enumeratedValue>
                <enumeratedValue>
                  <name />
                  <description>bit交换</description>
                  <value>3</value>
                </enumeratedValue>
              </enumeratedValues>
            </field>
            <field>
              <name>START</name>
              <description>START  field description</description>
              <bitRange>[7:7]</bitRange>
              <access>write-only</access>
              <enumeratedValues />
            </field>
            <field>
              <name>RUN_MODE</name>
              <description>RUN_MODE  field description</description>
              <bitRange>[5:4]</bitRange>
              <access>read-write</access>
              <enumeratedValues>
                <enumeratedValue>
                  <name />
                  <description />
                  <value>0</value>
                </enumeratedValue>
                <enumeratedValue>
                  <name />
                  <description>模式0，单次模运算，可配置4Block/16Block</description>
                  <value>0</value>
                </enumeratedValue>
                <enumeratedValue>
                  <name />
                  <description>模式1，单次点运算，固定16Block</description>
                  <value>1</value>
                </enumeratedValue>
                <enumeratedValue>
                  <name />
                  <description>模式2，32bit密钥连续RSA运算，固定4Block</description>
                  <value>2</value>
                </enumeratedValue>
                <enumeratedValue>
                  <name />
                  <description>模式3，32bit密钥连续ECC运算，固定16Block</description>
                  <value>3</value>
                </enumeratedValue>
              </enumeratedValues>
            </field>
            <field>
              <name>SOFTRST</name>
              <description>SOFTRST  field description</description>
              <bitRange>[3:3]</bitRange>
              <access>write-only</access>
              <enumeratedValues>
                <enumeratedValue>
                  <name />
                  <description>软件写SOFTRST之后，需插入至少一条NOP指令后，再写入PAE其他寄存器；在SOFTRST操作后立即写PAE寄存器可能写入失败。</description>
                  <value>0</value>
                </enumeratedValue>
              </enumeratedValues>
            </field>
            <field>
              <name>PAEIE</name>
              <description>PAEIE  field description</description>
              <bitRange>[2:2]</bitRange>
              <access>read-write</access>
              <enumeratedValues>
                <enumeratedValue>
                  <name />
                  <description>使能中断输出</description>
                  <value>1</value>
                </enumeratedValue>
                <enumeratedValue>
                  <name />
                  <description>禁止中断输出</description>
                  <value>0</value>
                </enumeratedValue>
              </enumeratedValues>
            </field>
            <field>
              <name>PAEIF</name>
              <description>PAEIF  field description</description>
              <bitRange>[1:1]</bitRange>
              <access>read-write</access>
              <enumeratedValues />
            </field>
            <field>
              <name>BUSY</name>
              <description>BUSY  field description</description>
              <bitRange>[0:0]</bitRange>
              <access>read-only</access>
              <enumeratedValues>
                <enumeratedValue>
                  <name />
                  <description>PAE正在运算中</description>
                  <value>1</value>
                </enumeratedValue>
                <enumeratedValue>
                  <name />
                  <description>PAE空闲</description>
                  <value>0</value>
                </enumeratedValue>
              </enumeratedValues>
            </field>
          </fields>
        </register>
        <register>
          <name>MLR</name>
          <description />
          <addressOffset>0x4</addressOffset>
          <size>32</size>
          <access>read-write</access>
          <resetValue>0x00000000</resetValue>
          <fields>
            <field>
              <name>PAE_MLR</name>
              <description>PAE_MLR  field description</description>
              <bitRange>[5:0]</bitRange>
              <access>read-write</access>
              <enumeratedValues>
                <enumeratedValue>
                  <name />
                  <description />
                  <value>0</value>
                </enumeratedValue>
                <enumeratedValue>
                  <name />
                  <description />
                  <value>0</value>
                </enumeratedValue>
              </enumeratedValues>
            </field>
          </fields>
        </register>
        <register>
          <name>MPR</name>
          <description />
          <addressOffset>0x8</addressOffset>
          <size>32</size>
          <access>read-write</access>
          <resetValue>0x00000000</resetValue>
          <fields>
            <field>
              <name>PAE_MPR</name>
              <description>PAE_MPR  field description</description>
              <bitRange>[31:0]</bitRange>
              <access>write-only</access>
              <enumeratedValues />
            </field>
          </fields>
        </register>
        <register>
          <name>M0CFG</name>
          <description />
          <addressOffset>0xc</addressOffset>
          <size>32</size>
          <access>read-write</access>
          <resetValue>0x00000000</resetValue>
          <fields>
            <field>
              <name>BLKCFG</name>
              <description>BLKCFG  field description</description>
              <bitRange>[15:15]</bitRange>
              <access>read-write</access>
              <enumeratedValues>
                <enumeratedValue>
                  <name />
                  <description>算法RAM配置为16 Block</description>
                  <value>1</value>
                </enumeratedValue>
                <enumeratedValue>
                  <name />
                  <description>算法RAM配置位4 Block</description>
                  <value>0</value>
                </enumeratedValue>
              </enumeratedValues>
            </field>
            <field>
              <name>INS_M0</name>
              <description>INS_M0  field description</description>
              <bitRange>[13:12]</bitRange>
              <access>read-write</access>
              <enumeratedValues>
                <enumeratedValue>
                  <name />
                  <description />
                  <value>0</value>
                </enumeratedValue>
                <enumeratedValue>
                  <name />
                  <description>蒙哥马利模乘</description>
                  <value>0</value>
                </enumeratedValue>
                <enumeratedValue>
                  <name />
                  <description>蒙哥马利模加</description>
                  <value>1</value>
                </enumeratedValue>
                <enumeratedValue>
                  <name />
                  <description>RFU</description>
                  <value>2</value>
                </enumeratedValue>
                <enumeratedValue>
                  <name />
                  <description>蒙哥马利模减</description>
                  <value>3</value>
                </enumeratedValue>
              </enumeratedValues>
            </field>
            <field>
              <name>RES_BLK</name>
              <description>RES_BLK  field description</description>
              <bitRange>[11:8]</bitRange>
              <access>read-write</access>
              <enumeratedValues />
            </field>
            <field>
              <name>OP1_BLK</name>
              <description>OP1_BLK  field description</description>
              <bitRange>[7:4]</bitRange>
              <access>read-write</access>
              <enumeratedValues>
                <enumeratedValue>
                  <name />
                  <description />
                  <value>0</value>
                </enumeratedValue>
              </enumeratedValues>
            </field>
            <field>
              <name>OP2_BLK</name>
              <description>OP2_BLK  field description</description>
              <bitRange>[3:0]</bitRange>
              <access>read-write</access>
              <enumeratedValues>
                <enumeratedValue>
                  <name />
                  <description />
                  <value>0</value>
                </enumeratedValue>
              </enumeratedValues>
            </field>
          </fields>
        </register>
        <register>
          <name>M1CFG</name>
          <description />
          <addressOffset>0x10</addressOffset>
          <size>32</size>
          <access>read-write</access>
          <resetValue>0x00000000</resetValue>
          <fields>
            <field>
              <name>INS_M1</name>
              <description>INS_M1  field description</description>
              <bitRange>[6:4]</bitRange>
              <access>read-write</access>
              <enumeratedValues>
                <enumeratedValue>
                  <name />
                  <description />
                  <value>0</value>
                </enumeratedValue>
                <enumeratedValue>
                  <name />
                  <description>Jacobin坐标倍点运算</description>
                  <value>0</value>
                </enumeratedValue>
                <enumeratedValue>
                  <name />
                  <description>混合坐标点加运算</description>
                  <value>1</value>
                </enumeratedValue>
                <enumeratedValue>
                  <name />
                  <description>RFU</description>
                  <value>2</value>
                </enumeratedValue>
                <enumeratedValue>
                  <name />
                  <description>蒙哥马利点乘倍点运算（ECDBL）</description>
                  <value>3</value>
                </enumeratedValue>
                <enumeratedValue>
                  <name />
                  <description>蒙哥马利点乘倍点点加运算（ECADDDBL）</description>
                  <value>4</value>
                </enumeratedValue>
                <enumeratedValue>
                  <name />
                  <description>蒙哥马利点乘Y坐标恢复运算（ECYRecover）</description>
                  <value>5</value>
                </enumeratedValue>
                <enumeratedValue>
                  <name />
                  <description>RFU</description>
                  <value>6</value>
                </enumeratedValue>
                <enumeratedValue>
                  <name />
                  <description>RFU</description>
                  <value>7</value>
                </enumeratedValue>
              </enumeratedValues>
            </field>
            <field>
              <name>AEN3_M1</name>
              <description>AEN3_M1  field description</description>
              <bitRange>[1:1]</bitRange>
              <access>read-write</access>
              <enumeratedValues>
                <enumeratedValue>
                  <name />
                  <description>A等于-3</description>
                  <value>1</value>
                </enumeratedValue>
                <enumeratedValue>
                  <name />
                  <description>A不等于-3</description>
                  <value>0</value>
                </enumeratedValue>
              </enumeratedValues>
            </field>
            <field>
              <name>BIT_VALUE_M1</name>
              <description>BIT_VALUE_M1  field description</description>
              <bitRange>[0:0]</bitRange>
              <access>read-write</access>
              <enumeratedValues>
                <enumeratedValue>
                  <name />
                  <description>当前位为1</description>
                  <value>1</value>
                </enumeratedValue>
                <enumeratedValue>
                  <name />
                  <description>当前位为0</description>
                  <value>0</value>
                </enumeratedValue>
              </enumeratedValues>
            </field>
          </fields>
        </register>
        <register>
          <name>M2CFG</name>
          <description />
          <addressOffset>0x14</addressOffset>
          <size>32</size>
          <access>read-write</access>
          <resetValue>0x00000000</resetValue>
          <fields>
            <field>
              <name>ALWAYS_MULT</name>
              <description>ALWAYS_MULT  field description</description>
              <bitRange>[4:4]</bitRange>
              <access>read-write</access>
              <enumeratedValues>
                <enumeratedValue>
                  <name />
                  <description>当前密钥位为0时同样进行模乘操作</description>
                  <value>1</value>
                </enumeratedValue>
                <enumeratedValue>
                  <name />
                  <description>当前密钥位为0时不进行模乘操作</description>
                  <value>0</value>
                </enumeratedValue>
              </enumeratedValues>
            </field>
            <field>
              <name>FBO_M2</name>
              <description>FBO_M2  field description</description>
              <bitRange>[0:0]</bitRange>
              <access>read-write</access>
              <enumeratedValues>
                <enumeratedValue>
                  <name />
                  <description>已找到为1的bit</description>
                  <value>1</value>
                </enumeratedValue>
                <enumeratedValue>
                  <name />
                  <description>未找到为1的bit</description>
                  <value>0</value>
                </enumeratedValue>
              </enumeratedValues>
            </field>
          </fields>
        </register>
        <register>
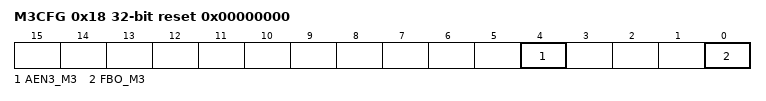
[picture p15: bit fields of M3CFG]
          <name>M3CFG</name>
          <description />
          <addressOffset>0x18</addressOffset>
          <size>32</size>
          <access>read-write</access>
          <resetValue>0x00000000</resetValue>
          <fields>
            <field>
              <name>AEN3_M3</name>
              <description>AEN3_M3  field description</description>
              <bitRange>[4:4]</bitRange>
              <access>read-write</access>
              <enumeratedValues>
                <enumeratedValue>
                  <name />
                  <description>A等于-3</description>
                  <value>1</value>
                </enumeratedValue>
                <enumeratedValue>
                  <name />
                  <description>A不等于-3</description>
                  <value>0</value>
                </enumeratedValue>
              </enumeratedValues>
            </field>
            <field>
              <name>FBO_M3</name>
              <description>FBO_M3  field description</description>
              <bitRange>[0:0]</bitRange>
              <access>read-write</access>
              <enumeratedValues>
                <enumeratedValue>
                  <name />
                  <description>已找到为1的bit</description>
                  <value>1</value>
                </enumeratedValue>
                <enumeratedValue>
                  <name />
                  <description>未找到为1的bit</description>
                  <value>0</value>
                </enumeratedValue>
              </enumeratedValues>
            </field>
          </fields>
        </register>
        <register>
          <name>WORD</name>
          <description />
          <addressOffset>0x1c</addressOffset>
          <size>32</size>
          <access>read-write</access>
          <resetValue>0x00000000</resetValue>
          <fields>
            <field>
              <name>PAE_WORD</name>
              <description>PAE_WORD  field description</description>
              <bitRange>[31:0]</bitRange>
              <access>write-only</access>
              <enumeratedValues />
            </field>
          </fields>
        </register>
      </registers>
    </peripheral>
    <peripheral>
      <name>HASH</name>
      <description>HASH module information</description>
      <groupName>HASH</groupName>
      <baseAddress>0x40001800</baseAddress>
      <size>32</size>
      <access>read-write</access>
      <addressBlock>
        <offset>0</offset>
        <size>0x8</size>
        <usage>registers</usage>
      </addressBlock>
      <registers>
        <register>
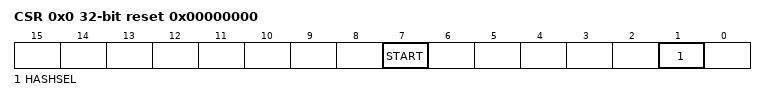
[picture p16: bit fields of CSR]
          <name>CSR</name>
          <description>Hash Control and Status Register</description>
          <addressOffset>0x0</addressOffset>
          <size>32</size>
          <access>read-write</access>
          <resetValue>0x00000000</resetValue>
          <fields>
            <field>
              <name>START</name>
              <description>START  field description</description>
              <bitRange>[7:7]</bitRange>
              <access>read-write</access>
              <enumeratedValues />
            </field>
            <field>
              <name>HASHSEL</name>
              <description>HASHSEL  field description</description>
              <bitRange>[1:1]</bitRange>
              <access>read-write</access>
              <enumeratedValues>
                <enumeratedValue>
                  <name />
                  <description>SHA256</description>
                  <value>0</value>
                </enumeratedValue>
                <enumeratedValue>
                  <name />
                  <description>SHA1</description>
                  <value>1</value>
                </enumeratedValue>
              </enumeratedValues>
            </field>
          </fields>
        </register>
        <register>
          <name>DTR</name>
          <description>Hash Data Type Register</description>
          <addressOffset>0x4</addressOffset>
          <size>32</size>
          <access>read-write</access>
          <resetValue>0x00000000</resetValue>
          <fields>
            <field>
              <name>DATA_TYPE</name>
              <description>DATA_TYPE  field description</description>
              <bitRange>[1:0]</bitRange>
              <access>read-write</access>
              <enumeratedValues>
                <enumeratedValue>
                  <name />
                  <description>不交换</description>
                  <value>0</value>
                </enumeratedValue>
                <enumeratedValue>
                  <name />
                  <description>half-word交换</description>
                  <value>1</value>
                </enumeratedValue>
                <enumeratedValue>
                  <name />
                  <description>byte交换</description>
                  <value>2</value>
                </enumeratedValue>
                <enumeratedValue>
                  <name />
                  <description>bit交换</description>
                  <value>3</value>
                </enumeratedValue>
              </enumeratedValues>
            </field>
          </fields>
        </register>
      </registers>
    </peripheral>
    <peripheral>
      <name>RNG</name>
      <description>RNG module information</description>
      <groupName>RNG</groupName>
      <baseAddress>0x40013c00</baseAddress>
      <size>32</size>
      <access>read-write</access>
      <addressBlock>
        <offset>0</offset>
        <size>0x20</size>
        <usage>registers</usage>
      </addressBlock>
      <registers>
        <register>
          <name>CR</name>
          <description>Random Number Generator Control Register</description>
          <addressOffset>0x0</addressOffset>
          <size>32</size>
          <access>read-write</access>
          <resetValue>0x00000000</resetValue>
          <fields>
            <field>
              <name>EN</name>
              <description>EN  field description</description>
              <bitRange>[0:0]</bitRange>
              <access>read-write</access>
              <enumeratedValues>
                <enumeratedValue>
                  <name />
                  <description>启动RNG</description>
                  <value>1</value>
                </enumeratedValue>
                <enumeratedValue>
                  <name />
                  <description>关闭RNG</description>
                  <value>0</value>
                </enumeratedValue>
              </enumeratedValues>
            </field>
          </fields>
        </register>
        <register>
          <name>DOR</name>
          <description>Random Number Generator Data Output Register</description>
          <addressOffset>0x4</addressOffset>
          <size>32</size>
          <access>read-write</access>
          <resetValue>0x00000000</resetValue>
          <fields>
            <field>
              <name>OUT</name>
              <description>OUT  field description</description>
              <bitRange>[31:0]</bitRange>
              <access>read-only</access>
              <enumeratedValues />
            </field>
          </fields>
        </register>
        <register>
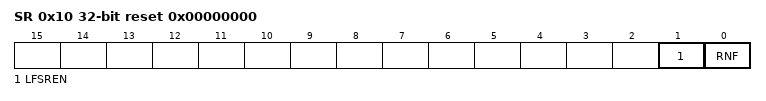
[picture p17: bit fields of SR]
          <name>SR</name>
          <description>Random Number Generator Status Register</description>
          <addressOffset>0x10</addressOffset>
          <size>32</size>
          <access>read-write</access>
          <resetValue>0x00000000</resetValue>
          <fields>
            <field>
              <name>LFSREN</name>
              <description>LFSREN  field description</description>
              <bitRange>[1:1]</bitRange>
              <access>read-only</access>
              <enumeratedValues>
                <enumeratedValue>
                  <name />
                  <description>LFSR在运行中，不可进行CRC验证</description>
                  <value>1</value>
                </enumeratedValue>
                <enumeratedValue>
                  <name />
                  <description>LFSR不在运行中，可进行CRC验证</description>
                  <value>0</value>
                </enumeratedValue>
                <enumeratedValue>
                  <name />
                  <description>本寄存器不会引起模块中断，仅供查询</description>
                  <value>0</value>
                </enumeratedValue>
              </enumeratedValues>
            </field>
            <field>
              <name>RNF</name>
              <description>RNF  field description</description>
              <bitRange>[0:0]</bitRange>
              <access>read-write</access>
              <enumeratedValues>
                <enumeratedValue>
                  <name />
                  <description>随机数未能通过质量检测</description>
                  <value>1</value>
                </enumeratedValue>
                <enumeratedValue>
                  <name />
                  <description>随机数通过质量检测</description>
                  <value>0</value>
                </enumeratedValue>
              </enumeratedValues>
            </field>
          </fields>
        </register>
        <register>
          <name>CRC_CR</name>
          <description>CRC Control Register</description>
          <addressOffset>0x14</addressOffset>
          <size>32</size>
          <access>read-write</access>
          <resetValue>0x00000000</resetValue>
          <fields>
            <field>
              <name>CRCEN</name>
              <description>CRCEN  field description</description>
              <bitRange>[0:0]</bitRange>
              <access>read-write</access>
              <enumeratedValues>
                <enumeratedValue>
                  <name />
                  <description>CRC使能</description>
                  <value>1</value>
                </enumeratedValue>
                <enumeratedValue>
                  <name />
                  <description>CRC关闭</description>
                  <value>0</value>
                </enumeratedValue>
              </enumeratedValues>
            </field>
          </fields>
        </register>
        <register>
          <name>CRC_DIR</name>
          <description>CRC Data input Register</description>
          <addressOffset>0x18</addressOffset>
          <size>32</size>
          <access>read-write</access>
          <resetValue>0x00000000</resetValue>
          <fields>
            <field>
              <name>CRCIN</name>
              <description>CRCIN  field description</description>
              <bitRange>[31:0]</bitRange>
              <access>read-write</access>
              <enumeratedValues />
            </field>
          </fields>
        </register>
        <register>
          <name>CRC_SR</name>
          <description>CRC Status Register</description>
          <addressOffset>0x1c</addressOffset>
          <size>32</size>
          <access>read-write</access>
          <resetValue>0x00000000</resetValue>
          <fields>
            <field>
              <name>CRCDONE</name>
              <description>CRCDONE  field description</description>
              <bitRange>[0:0]</bitRange>
              <access>read-write</access>
              <enumeratedValues>
                <enumeratedValue>
                  <name />
                  <description>CRC计算完成</description>
                  <value>1</value>
                </enumeratedValue>
                <enumeratedValue>
                  <name />
                  <description>CRC计算未完成</description>
                  <value>0</value>
                </enumeratedValue>
              </enumeratedValues>
            </field>
          </fields>
        </register>
      </registers>
    </peripheral>
    <peripheral>
      <name>COMP</name>
      <description>COMP module information</description>
      <groupName>COMP</groupName>
      <baseAddress>0x40015400</baseAddress>
      <size>32</size>
      <access>read-write</access>
      <addressBlock>
        <offset>0</offset>
        <size>0x14</size>
        <usage>registers</usage>
      </addressBlock>
      <registers>
        <register>
          <name>CR1</name>
          <description />
          <addressOffset>0x0</addressOffset>
          <size>32</size>
          <access>read-write</access>
          <resetValue>0x00000000</resetValue>
          <fields>
            <field>
              <name>PWRMOD</name>
              <description>PWRMOD  field description</description>
              <bitRange>[24:24]</bitRange>
              <access>read-write</access>
              <enumeratedValues>
                <enumeratedValue>
                  <name />
                  <description>低功耗模式</description>
                  <value>0</value>
                </enumeratedValue>
                <enumeratedValue>
                  <name />
                  <description>快速模式</description>
                  <value>1</value>
                </enumeratedValue>
              </enumeratedValues>
            </field>
            <field>
              <name>DFLEN</name>
              <description>DFLEN  field description</description>
              <bitRange>[23:19]</bitRange>
              <access>read-write</access>
              <enumeratedValues>
                <enumeratedValue>
                  <name />
                  <description>1次APBCLK采样</description>
                  <value>0</value>
                </enumeratedValue>
                <enumeratedValue>
                  <name />
                  <description>2次APBCLK采样</description>
                  <value>1</value>
                </enumeratedValue>
                <enumeratedValue>
                  <name />
                  <description>32次APBCLK采样</description>
                  <value>1f</value>
                </enumeratedValue>
              </enumeratedValues>
            </field>
            <field>
              <name>WINMODE</name>
              <description>WINMODE  field description</description>
              <bitRange>[18:18]</bitRange>
              <access>read-write</access>
              <enumeratedValues>
                <enumeratedValue>
                  <name />
                  <description>禁止窗口模式</description>
                  <value>0</value>
                </enumeratedValue>
                <enumeratedValue>
                  <name />
                  <description>使能窗口模式</description>
                  <value>1</value>
                </enumeratedValue>
              </enumeratedValues>
            </field>
            <field>
              <name>POLAR</name>
              <description>POLAR  field description</description>
              <bitRange>[17:17]</bitRange>
              <access>read-write</access>
              <enumeratedValues>
                <enumeratedValue>
                  <name />
                  <description>正向输出</description>
                  <value>0</value>
                </enumeratedValue>
                <enumeratedValue>
                  <name />
                  <description>取反输出</description>
                  <value>1</value>
                </enumeratedValue>
              </enumeratedValues>
            </field>
            <field>
              <name>DFEN</name>
              <description>DFEN  field description</description>
              <bitRange>[16:16]</bitRange>
              <access>read-write</access>
              <enumeratedValues>
                <enumeratedValue>
                  <name />
                  <description>禁止输出数字滤波</description>
                  <value>0</value>
                </enumeratedValue>
                <enumeratedValue>
                  <name />
                  <description>使能输出数字滤波</description>
                  <value>1</value>
                </enumeratedValue>
              </enumeratedValues>
            </field>
            <field>
              <name>CMP1OR</name>
              <description>CMP1OR  field description</description>
              <bitRange>[9:9]</bitRange>
              <access>read-only</access>
              <enumeratedValues />
            </field>
            <field>
              <name>CMP1OF</name>
              <description>CMP1OF  field description</description>
              <bitRange>[8:8]</bitRange>
              <access>read-only</access>
              <enumeratedValues />
            </field>
            <field>
              <name>V1NSEL</name>
              <description>V1NSEL  field description</description>
              <bitRange>[6:4]</bitRange>
              <access>read-write</access>
              <enumeratedValues>
                <enumeratedValue>
                  <name />
                  <description>COMP1_INN1</description>
                  <value>0</value>
                </enumeratedValue>
                <enumeratedValue>
                  <name />
                  <description>COMP1_INN2</description>
                  <value>1</value>
                </enumeratedValue>
                <enumeratedValue>
                  <name />
                  <description>VREF</description>
                  <value>2</value>
                </enumeratedValue>
                <enumeratedValue>
                  <name />
                  <description>3/4 VREF</description>
                  <value>3</value>
                </enumeratedValue>
                <enumeratedValue>
                  <name />
                  <description>1/2 VREF</description>
                  <value>4</value>
                </enumeratedValue>
                <enumeratedValue>
                  <name />
                  <description>1/4 VREF</description>
                  <value>5</value>
                </enumeratedValue>
                <enumeratedValue>
                  <name />
                  <description>1/8 VREF</description>
                  <value>6</value>
                </enumeratedValue>
                <enumeratedValue>
                  <name />
                  <description>RFU</description>
                  <value>7</value>
                </enumeratedValue>
              </enumeratedValues>
            </field>
            <field>
              <name>V1PSEL</name>
              <description>V1PSEL  field description</description>
              <bitRange>[2:1]</bitRange>
              <access>read-write</access>
              <enumeratedValues>
                <enumeratedValue>
                  <name />
                  <description>COMP1_INP1</description>
                  <value>0</value>
                </enumeratedValue>
                <enumeratedValue>
                  <name />
                  <description>COMP1_INP2</description>
                  <value>1</value>
                </enumeratedValue>
                <enumeratedValue>
                  <name />
                  <description>COMP1_INP3</description>
                  <value>2</value>
                </enumeratedValue>
                <enumeratedValue>
                  <name />
                  <description>COMP1_INP4</description>
                  <value>3</value>
                </enumeratedValue>
              </enumeratedValues>
            </field>
            <field>
              <name>CMP1EN</name>
              <description>CMP1EN  field description</description>
              <bitRange>[0:0]</bitRange>
              <access>read-write</access>
              <enumeratedValues>
                <enumeratedValue>
                  <name />
                  <description>关闭比较器1</description>
                  <value>0</value>
                </enumeratedValue>
                <enumeratedValue>
                  <name />
                  <description>使能比较器1</description>
                  <value>1</value>
                </enumeratedValue>
              </enumeratedValues>
            </field>
          </fields>
        </register>
        <register>
          <name>CR2</name>
          <description />
          <addressOffset>0x4</addressOffset>
          <size>32</size>
          <access>read-write</access>
          <resetValue>0x00000000</resetValue>
          <fields>
            <field>
              <name>PWRMOD</name>
              <description>PWRMOD  field description</description>
              <bitRange>[24:24]</bitRange>
              <access>read-write</access>
              <enumeratedValues>
                <enumeratedValue>
                  <name />
                  <description>低功耗模式</description>
                  <value>0</value>
                </enumeratedValue>
                <enumeratedValue>
                  <name />
                  <description>快速模式</description>
                  <value>1</value>
                </enumeratedValue>
              </enumeratedValues>
            </field>
            <field>
              <name>DFLEN</name>
              <description>DFLEN  field description</description>
              <bitRange>[23:19]</bitRange>
              <access>read-write</access>
              <enumeratedValues>
                <enumeratedValue>
                  <name />
                  <description>1次APBCLK采样</description>
                  <value>0</value>
                </enumeratedValue>
                <enumeratedValue>
                  <name />
                  <description>2次APBCLK采样</description>
                  <value>1</value>
                </enumeratedValue>
                <enumeratedValue>
                  <name />
                  <description>32次APBCLK采样</description>
                  <value>1f</value>
                </enumeratedValue>
              </enumeratedValues>
            </field>
            <field>
              <name>WINMODE</name>
              <description>WINMODE  field description</description>
              <bitRange>[18:18]</bitRange>
              <access>read-write</access>
              <enumeratedValues>
                <enumeratedValue>
                  <name />
                  <description>禁止窗口模式</description>
                  <value>0</value>
                </enumeratedValue>
                <enumeratedValue>
                  <name />
                  <description>使能窗口模式</description>
                  <value>1</value>
                </enumeratedValue>
              </enumeratedValues>
            </field>
            <field>
              <name>POLAR</name>
              <description>POLAR  field description</description>
              <bitRange>[17:17]</bitRange>
              <access>read-write</access>
              <enumeratedValues>
                <enumeratedValue>
                  <name />
                  <description>正向输出</description>
                  <value>0</value>
                </enumeratedValue>
                <enumeratedValue>
                  <name />
                  <description>取反输出</description>
                  <value>1</value>
                </enumeratedValue>
              </enumeratedValues>
            </field>
            <field>
              <name>DFEN</name>
              <description>DFEN  field description</description>
              <bitRange>[16:16]</bitRange>
              <access>read-write</access>
              <enumeratedValues>
                <enumeratedValue>
                  <name />
                  <description>禁止输出数字滤波</description>
                  <value>0</value>
                </enumeratedValue>
                <enumeratedValue>
                  <name />
                  <description>使能输出数字滤波</description>
                  <value>1</value>
                </enumeratedValue>
              </enumeratedValues>
            </field>
            <field>
              <name>CMP2OR</name>
              <description>CMP2OR  field description</description>
              <bitRange>[9:9]</bitRange>
              <access>read-only</access>
              <enumeratedValues />
            </field>
            <field>
              <name>CMP2OF</name>
              <description>CMP2OF  field description</description>
              <bitRange>[8:8]</bitRange>
              <access>read-only</access>
              <enumeratedValues />
            </field>
            <field>
              <name>V2NSEL</name>
              <description>V2NSEL  field description</description>
              <bitRange>[6:4]</bitRange>
              <access>read-write</access>
              <enumeratedValues>
                <enumeratedValue>
                  <name />
                  <description>COMP2_INN1</description>
                  <value>0</value>
                </enumeratedValue>
                <enumeratedValue>
                  <name />
                  <description>COMP2_INN2</description>
                  <value>1</value>
                </enumeratedValue>
                <enumeratedValue>
                  <name />
                  <description>VREF</description>
                  <value>2</value>
                </enumeratedValue>
                <enumeratedValue>
                  <name />
                  <description>3/4 VREF</description>
                  <value>3</value>
                </enumeratedValue>
                <enumeratedValue>
                  <name />
                  <description>1/2 VREF</description>
                  <value>4</value>
                </enumeratedValue>
                <enumeratedValue>
                  <name />
                  <description>1/4 VREF</description>
                  <value>5</value>
                </enumeratedValue>
                <enumeratedValue>
                  <name />
                  <description>1/8 VREF</description>
                  <value>6</value>
                </enumeratedValue>
                <enumeratedValue>
                  <name />
                  <description>REFIN (PD6)</description>
                  <value>7</value>
                </enumeratedValue>
              </enumeratedValues>
            </field>
            <field>
              <name>V2PSEL</name>
              <description>V2PSEL  field description</description>
              <bitRange>[3:1]</bitRange>
              <access>read-write</access>
              <enumeratedValues>
                <enumeratedValue>
                  <name />
                  <description>COMP2_INP1</description>
                  <value>0</value>
                </enumeratedValue>
                <enumeratedValue>
                  <name />
                  <description>COMP2_INP2</description>
                  <value>1</value>
                </enumeratedValue>
                <enumeratedValue>
                  <name />
                  <description>COMP1_INP1</description>
                  <value>2</value>
                </enumeratedValue>
                <enumeratedValue>
                  <name />
                  <description>COMP1_INP2</description>
                  <value>3</value>
                </enumeratedValue>
                <enumeratedValue>
                  <name />
                  <description>AVREF</description>
                  <value>4</value>
                </enumeratedValue>
                <enumeratedValue>
                  <name />
                  <description>VDD15</description>
                  <value>5</value>
                </enumeratedValue>
                <enumeratedValue>
                  <name />
                  <description>RFU</description>
                  <value>0</value>
                </enumeratedValue>
              </enumeratedValues>
            </field>
            <field>
              <name>CMP2EN</name>
              <description>CMP2EN  field description</description>
              <bitRange>[0:0]</bitRange>
              <access>read-write</access>
              <enumeratedValues>
                <enumeratedValue>
                  <name />
                  <description>关闭比较器2</description>
                  <value>0</value>
                </enumeratedValue>
                <enumeratedValue>
                  <name />
                  <description>使能比较器2</description>
                  <value>1</value>
                </enumeratedValue>
              </enumeratedValues>
            </field>
          </fields>
        </register>
        <register>
          <name>ICR</name>
          <description />
          <addressOffset>0x8</addressOffset>
          <size>32</size>
          <access>read-write</access>
          <resetValue>0x00000040</resetValue>
          <fields>
            <field>
              <name>OOW_IE</name>
              <description>OOW_IE  field description</description>
              <bitRange>[9:9]</bitRange>
              <access>read-write</access>
              <enumeratedValues />
            </field>
            <field>
              <name>WIN_IE</name>
              <description>WIN_IE  field description</description>
              <bitRange>[8:8]</bitRange>
              <access>read-write</access>
              <enumeratedValues />
            </field>
            <field>
              <name>BUFBYP</name>
              <description>BUFBYP  field description</description>
              <bitRange>[7:7]</bitRange>
              <access>read-write</access>
              <enumeratedValues>
                <enumeratedValue>
                  <name />
                  <description>不Bypass比较器Buffer</description>
                  <value>0</value>
                </enumeratedValue>
                <enumeratedValue>
                  <name />
                  <description>Bypass比较器Buffer</description>
                  <value>1</value>
                </enumeratedValue>
              </enumeratedValues>
            </field>
            <field>
              <name>BUF_OFF</name>
              <description>BUF_OFF  field description</description>
              <bitRange>[6:6]</bitRange>
              <access>read-write</access>
              <enumeratedValues>
                <enumeratedValue>
                  <name />
                  <description>使能比较器Buffer</description>
                  <value>0</value>
                </enumeratedValue>
                <enumeratedValue>
                  <name />
                  <description>禁止比较器Buffer</description>
                  <value>1</value>
                </enumeratedValue>
              </enumeratedValues>
            </field>
            <field>
              <name>CMP2SEL</name>
              <description>CMP2SEL  field description</description>
              <bitRange>[5:4]</bitRange>
              <access>read-write</access>
              <enumeratedValues>
                <enumeratedValue>
                  <name />
                  <description>比较器2输出上升或下降沿产生中断</description>
                  <value>0</value>
                </enumeratedValue>
                <enumeratedValue>
                  <name />
                  <description>比较器2输出上升或下降沿产生中断</description>
                  <value>3</value>
                </enumeratedValue>
                <enumeratedValue>
                  <name />
                  <description>比较器2输出上升沿产生中断</description>
                  <value>1</value>
                </enumeratedValue>
                <enumeratedValue>
                  <name />
                  <description>比较器2输出下降沿产生中断</description>
                  <value>2</value>
                </enumeratedValue>
              </enumeratedValues>
            </field>
            <field>
              <name>CMP1SEL</name>
              <description>CMP1SEL  field description</description>
              <bitRange>[3:2]</bitRange>
              <access>read-write</access>
              <enumeratedValues>
                <enumeratedValue>
                  <name />
                  <description>比较器1输出上升或下降沿产生中断</description>
                  <value>0</value>
                </enumeratedValue>
                <enumeratedValue>
                  <name />
                  <description>比较器1输出上升或下降沿产生中断</description>
                  <value>3</value>
                </enumeratedValue>
                <enumeratedValue>
                  <name />
                  <description>比较器1输出上升沿产生中断</description>
                  <value>1</value>
                </enumeratedValue>
                <enumeratedValue>
                  <name />
                  <description>比较器1输出下降沿产生中断</description>
                  <value>2</value>
                </enumeratedValue>
              </enumeratedValues>
            </field>
            <field>
              <name>CMP2IE</name>
              <description>CMP2IE  field description</description>
              <bitRange>[1:1]</bitRange>
              <access>read-write</access>
              <enumeratedValues />
            </field>
            <field>
              <name>CMP1IE</name>
              <description>CMP1IE  field description</description>
              <bitRange>[0:0]</bitRange>
              <access>read-write</access>
              <enumeratedValues />
            </field>
          </fields>
        </register>
        <register>
          <name>ISR</name>
          <description />
          <addressOffset>0xc</addressOffset>
          <size>32</size>
          <access>read-write</access>
          <resetValue>0x00000000</resetValue>
          <fields>
            <field>
              <name>OOW_IF</name>
              <description>OOW_IF  field description</description>
              <bitRange>[3:3]</bitRange>
              <access>read-write</access>
              <enumeratedValues />
            </field>
            <field>
              <name>WIN_IF</name>
              <description>WIN_IF  field description</description>
              <bitRange>[2:2]</bitRange>
              <access>read-write</access>
              <enumeratedValues />
            </field>
            <field>
              <name>CMP2IF</name>
              <description>CMP2IF  field description</description>
              <bitRange>[1:1]</bitRange>
              <access>read-write</access>
              <enumeratedValues />
            </field>
            <field>
              <name>CMP1IF</name>
              <description>CMP1IF  field description</description>
              <bitRange>[0:0]</bitRange>
              <access>read-write</access>
              <enumeratedValues />
            </field>
          </fields>
        </register>
        <register>
          <name>PCR</name>
          <description />
          <addressOffset>0x10</addressOffset>
          <size>32</size>
          <access>read-write</access>
          <resetValue>0x00000000</resetValue>
          <fields>
            <field>
              <name>HSCMPBUF_EN</name>
              <description>HSCMPBUF_EN  field description</description>
              <bitRange>[2:2]</bitRange>
              <access>read-write</access>
              <enumeratedValues>
                <enumeratedValue>
                  <name />
                  <description>关闭</description>
                  <value>0</value>
                </enumeratedValue>
                <enumeratedValue>
                  <name />
                  <description>使能</description>
                  <value>1</value>
                </enumeratedValue>
              </enumeratedValues>
            </field>
            <field>
              <name>HSCMP2_EN</name>
              <description>HSCMP2_EN  field description</description>
              <bitRange>[1:1]</bitRange>
              <access>read-write</access>
              <enumeratedValues>
                <enumeratedValue>
                  <name />
                  <description>关闭</description>
                  <value>0</value>
                </enumeratedValue>
                <enumeratedValue>
                  <name />
                  <description>使能</description>
                  <value>1</value>
                </enumeratedValue>
              </enumeratedValues>
            </field>
            <field>
              <name>HSCMP1_EN</name>
              <description>HSCMP1_EN  field description</description>
              <bitRange>[0:0]</bitRange>
              <access>read-write</access>
              <enumeratedValues>
                <enumeratedValue>
                  <name />
                  <description>关闭</description>
                  <value>0</value>
                </enumeratedValue>
                <enumeratedValue>
                  <name />
                  <description>使能</description>
                  <value>1</value>
                </enumeratedValue>
              </enumeratedValues>
            </field>
          </fields>
        </register>
      </registers>
    </peripheral>
    <peripheral>
      <name>I2C0</name>
      <description>I2C0 module information</description>
      <groupName>I2C</groupName>
      <baseAddress>0x40012400</baseAddress>
      <size>32</size>
      <access>read-write</access>
      <addressBlock>
        <offset>0</offset>
        <size>0x24</size>
        <usage>registers</usage>
      </addressBlock>
      <registers>
        <register>
          <name>CFGR</name>
          <description>I2C0 Master Config Register</description>
          <addressOffset>0x0</addressOffset>
          <size>32</size>
          <access>read-write</access>
          <resetValue>0x00000000</resetValue>
          <fields>
            <field>
              <name>AUTOEND</name>
              <description>AUTOEND  field description</description>
              <bitRange>[17:17]</bitRange>
              <access>read-write</access>
              <enumeratedValues>
                <enumeratedValue>
                  <name />
                  <description>DMA指定长度传输完成后，自动发送STOP时序</description>
                  <value>1</value>
                </enumeratedValue>
                <enumeratedValue>
                  <name />
                  <description>DMA指定长度传输完成后，等待软件接管</description>
                  <value>0</value>
                </enumeratedValue>
              </enumeratedValues>
            </field>
            <field>
              <name>MSP_DMAEN</name>
              <description>MSP_DMAEN  field description</description>
              <bitRange>[16:16]</bitRange>
              <access>read-write</access>
              <enumeratedValues>
                <enumeratedValue>
                  <name />
                  <description>关闭DMA功能</description>
                  <value>0</value>
                </enumeratedValue>
                <enumeratedValue>
                  <name />
                  <description>使能DMA功能</description>
                  <value>1</value>
                </enumeratedValue>
              </enumeratedValues>
            </field>
            <field>
              <name>TOEN</name>
              <description>TOEN  field description</description>
              <bitRange>[1:1]</bitRange>
              <access>read-write</access>
              <enumeratedValues>
                <enumeratedValue>
                  <name />
                  <description>使能超时功能，超时周期由MSPTO寄存器定义</description>
                  <value>1</value>
                </enumeratedValue>
                <enumeratedValue>
                  <name />
                  <description>关闭超时功能</description>
                  <value>0</value>
                </enumeratedValue>
              </enumeratedValues>
            </field>
            <field>
              <name>MSPEN</name>
              <description>MSPEN  field description</description>
              <bitRange>[0:0]</bitRange>
              <access>read-write</access>
              <enumeratedValues />
            </field>
          </fields>
        </register>
        <register>
          <name>CR</name>
          <description>I2C0 Master Control Register</description>
          <addressOffset>0x4</addressOffset>
          <size>32</size>
          <access>read-write</access>
          <resetValue>0x00000000</resetValue>
          <fields>
            <field>
              <name>RCEN</name>
              <description>RCEN  field description</description>
              <bitRange>[3:3]</bitRange>
              <access>read-write</access>
              <enumeratedValues>
                <enumeratedValue>
                  <name />
                  <description>主机接收使能</description>
                  <value>1</value>
                </enumeratedValue>
                <enumeratedValue>
                  <name />
                  <description>接收禁止</description>
                  <value>0</value>
                </enumeratedValue>
              </enumeratedValues>
            </field>
            <field>
              <name>PEN</name>
              <description>PEN  field description</description>
              <bitRange>[2:2]</bitRange>
              <access>read-write</access>
              <enumeratedValues />
            </field>
            <field>
              <name>RSEN</name>
              <description>RSEN  field description</description>
              <bitRange>[1:1]</bitRange>
              <access>read-write</access>
              <enumeratedValues />
            </field>
            <field>
              <name>SEN</name>
              <description>SEN  field description</description>
              <bitRange>[0:0]</bitRange>
              <access>read-write</access>
              <enumeratedValues />
            </field>
          </fields>
        </register>
        <register>
          <name>IER</name>
          <description>I2C0 Master Interrupt Enable Register</description>
          <addressOffset>0x8</addressOffset>
          <size>32</size>
          <access>read-write</access>
          <resetValue>0x00000000</resetValue>
          <fields>
            <field>
              <name>WCOLE</name>
              <description>WCOLE  field description</description>
              <bitRange>[6:6]</bitRange>
              <access>read-write</access>
              <enumeratedValues>
                <enumeratedValue>
                  <name />
                  <description>允许写冲突中断</description>
                  <value>1</value>
                </enumeratedValue>
                <enumeratedValue>
                  <name />
                  <description>禁止写冲突中断</description>
                  <value>0</value>
                </enumeratedValue>
              </enumeratedValues>
            </field>
            <field>
              <name>TOE</name>
              <description>TOE  field description</description>
              <bitRange>[5:5]</bitRange>
              <access>read-write</access>
              <enumeratedValues>
                <enumeratedValue>
                  <name />
                  <description>允许超时中断</description>
                  <value>1</value>
                </enumeratedValue>
                <enumeratedValue>
                  <name />
                  <description>禁止超时中断</description>
                  <value>0</value>
                </enumeratedValue>
              </enumeratedValues>
            </field>
            <field>
              <name>SE</name>
              <description>SE  field description</description>
              <bitRange>[4:4]</bitRange>
              <access>read-write</access>
              <enumeratedValues>
                <enumeratedValue>
                  <name />
                  <description>允许START时序中断</description>
                  <value>1</value>
                </enumeratedValue>
                <enumeratedValue>
                  <name />
                  <description>禁止START时序中断</description>
                  <value>0</value>
                </enumeratedValue>
              </enumeratedValues>
            </field>
            <field>
              <name>PE</name>
              <description>PE  field description</description>
              <bitRange>[3:3]</bitRange>
              <access>read-write</access>
              <enumeratedValues>
                <enumeratedValue>
                  <name />
                  <description>允许STOP时序中断</description>
                  <value>1</value>
                </enumeratedValue>
                <enumeratedValue>
                  <name />
                  <description>禁止STOP时序中断</description>
                  <value>0</value>
                </enumeratedValue>
              </enumeratedValues>
            </field>
            <field>
              <name>NACKE</name>
              <description>NACKE  field description</description>
              <bitRange>[2:2]</bitRange>
              <access>read-write</access>
              <enumeratedValues>
                <enumeratedValue>
                  <name />
                  <description>允许收到NACK产生中断</description>
                  <value>1</value>
                </enumeratedValue>
                <enumeratedValue>
                  <name />
                  <description>禁止产生NACK中断</description>
                  <value>0</value>
                </enumeratedValue>
              </enumeratedValues>
            </field>
            <field>
              <name>TXIE</name>
              <description>TXIE  field description</description>
              <bitRange>[1:1]</bitRange>
              <access>read-write</access>
              <enumeratedValues>
                <enumeratedValue>
                  <name />
                  <description>允许发送完成中断</description>
                  <value>1</value>
                </enumeratedValue>
                <enumeratedValue>
                  <name />
                  <description>禁止发送完成中断</description>
                  <value>0</value>
                </enumeratedValue>
              </enumeratedValues>
            </field>
            <field>
              <name>RXIE</name>
              <description>RXIE  field description</description>
              <bitRange>[0:0]</bitRange>
              <access>read-write</access>
              <enumeratedValues>
                <enumeratedValue>
                  <name />
                  <description>允许接收完成中断</description>
                  <value>1</value>
                </enumeratedValue>
                <enumeratedValue>
                  <name />
                  <description>禁止接收完成中断</description>
                  <value>0</value>
                </enumeratedValue>
              </enumeratedValues>
            </field>
          </fields>
        </register>
        <register>
          <name>ISR</name>
          <description>I2C0 Master Interrupt Status Register</description>
          <addressOffset>0xc</addressOffset>
          <size>32</size>
          <access>read-write</access>
          <resetValue>0x00000000</resetValue>
          <fields>
            <field>
              <name>WCOL</name>
              <description>WCOL  field description</description>
              <bitRange>[6:6]</bitRange>
              <access>read-write</access>
              <enumeratedValues />
            </field>
            <field>
              <name>TO</name>
              <description>TO  field description</description>
              <bitRange>[5:5]</bitRange>
              <access>read-write</access>
              <enumeratedValues>
                <enumeratedValue>
                  <name />
                  <description>发生SCL超时</description>
                  <value>1</value>
                </enumeratedValue>
                <enumeratedValue>
                  <name />
                  <description>没有发生SCL超时</description>
                  <value>0</value>
                </enumeratedValue>
              </enumeratedValues>
            </field>
            <field>
              <name>S</name>
              <description>S  field description</description>
              <bitRange>[4:4]</bitRange>
              <access>read-only</access>
              <enumeratedValues />
            </field>
            <field>
              <name>P</name>
              <description>P  field description</description>
              <bitRange>[3:3]</bitRange>
              <access>read-only</access>
              <enumeratedValues />
            </field>
            <field>
              <name>ACKSTA</name>
              <description>ACKSTA  field description</description>
              <bitRange>[2:2]</bitRange>
              <access>read-write</access>
              <enumeratedValues>
                <enumeratedValue>
                  <name />
                  <description>从机回应NACK</description>
                  <value>1</value>
                </enumeratedValue>
                <enumeratedValue>
                  <name />
                  <description>从机回应ACK</description>
                  <value>0</value>
                </enumeratedValue>
              </enumeratedValues>
            </field>
            <field>
              <name>TXIF</name>
              <description>TXIF  field description</description>
              <bitRange>[1:1]</bitRange>
              <access>read-write</access>
              <enumeratedValues />
            </field>
            <field>
              <name>RXIF</name>
              <description>RXIF  field description</description>
              <bitRange>[0:0]</bitRange>
              <access>read-write</access>
              <enumeratedValues />
            </field>
          </fields>
        </register>
        <register>
          <name>SR</name>
          <description>I2C0 Master Status Register</description>
          <addressOffset>0x10</addressOffset>
          <size>32</size>
          <access>read-write</access>
          <resetValue>0x00000000</resetValue>
          <fields>
            <field>
              <name>BUSY</name>
              <description>BUSY  field description</description>
              <bitRange>[5:5]</bitRange>
              <access>read-only</access>
              <enumeratedValues>
                <enumeratedValue>
                  <name />
                  <description>接口处于读写状态，正在进行数据传输，</description>
                  <value>1</value>
                </enumeratedValue>
                <enumeratedValue>
                  <name />
                  <description>已完成数据传输</description>
                  <value>0</value>
                </enumeratedValue>
              </enumeratedValues>
            </field>
            <field>
              <name>RW_</name>
              <description>RW_  field description</description>
              <bitRange>[4:4]</bitRange>
              <access>read-only</access>
              <enumeratedValues>
                <enumeratedValue>
                  <name />
                  <description>主机从从机读取数据</description>
                  <value>1</value>
                </enumeratedValue>
                <enumeratedValue>
                  <name />
                  <description>主机向从机写入数据</description>
                  <value>0</value>
                </enumeratedValue>
              </enumeratedValues>
            </field>
            <field>
              <name>BF</name>
              <description>BF  field description</description>
              <bitRange>[2:2]</bitRange>
              <access>read-only</access>
              <enumeratedValues>
                <enumeratedValue>
                  <name />
                  <description />
                  <value>0</value>
                </enumeratedValue>
                <enumeratedValue>
                  <name />
                  <description>接收完成，SSPBUF满</description>
                  <value>1</value>
                </enumeratedValue>
                <enumeratedValue>
                  <name />
                  <description>接收未完成，SSPBUF空</description>
                  <value>0</value>
                </enumeratedValue>
                <enumeratedValue>
                  <name />
                  <description />
                  <value>0</value>
                </enumeratedValue>
                <enumeratedValue>
                  <name />
                  <description>正在发送，SSPBUF满</description>
                  <value>1</value>
                </enumeratedValue>
                <enumeratedValue>
                  <name />
                  <description>发送完成，SSPBUF空</description>
                  <value>0</value>
                </enumeratedValue>
              </enumeratedValues>
            </field>
            <field>
              <name>ACKMO</name>
              <description>ACKMO  field description</description>
              <bitRange>[0:0]</bitRange>
              <access>read-write</access>
              <enumeratedValues>
                <enumeratedValue>
                  <name />
                  <description>主机回发NACK</description>
                  <value>1</value>
                </enumeratedValue>
                <enumeratedValue>
                  <name />
                  <description>主机回发ACK</description>
                  <value>0</value>
                </enumeratedValue>
                <enumeratedValue>
                  <name />
                  <description>必须在P标志寄存器被清零的情况下，软件才能置位ACKMO</description>
                  <value>0</value>
                </enumeratedValue>
              </enumeratedValues>
            </field>
          </fields>
        </register>
        <register>
          <name>BRG</name>
          <description>I2C0 Master Baud Rate Generation Register</description>
          <addressOffset>0x14</addressOffset>
          <size>32</size>
          <access>read-write</access>
          <resetValue />
          <fields>
            <field>
              <name>MSPBRGH</name>
              <description>MSPBRGH  field description</description>
              <bitRange>[24:16]</bitRange>
              <access>read-write</access>
              <enumeratedValues />
            </field>
            <field>
              <name>MSPBRGL</name>
              <description>MSPBRGL  field description</description>
              <bitRange>[8:0]</bitRange>
              <access>read-write</access>
              <enumeratedValues />
            </field>
          </fields>
        </register>
        <register>
          <name>BUF</name>
          <description>I2C0 Master Buffer Register</description>
          <addressOffset>0x18</addressOffset>
          <size>32</size>
          <access>read-write</access>
          <resetValue>0x00000000</resetValue>
          <fields>
            <field>
              <name>MSPBUF</name>
              <description>MSPBUF  field description</description>
              <bitRange>[7:0]</bitRange>
              <access>read-write</access>
              <enumeratedValues>
                <enumeratedValue>
                  <name />
                  <description>数据的读写通过对SSPBUF的操作完成。发送时，对SSPBUF执行写操作，同时也载入数据收发移位寄存器(SSPSR)；接收时，SSPBUF与SSPSR组成双缓冲结构，读出数据为SSPBUF的数据。接收完一个字节的数据，SSPSR将数据载入SSPBUF，同时置位I2CIF。SSPSR不是直接寄存器，没有物理地址。</description>
                  <value>0</value>
                </enumeratedValue>
              </enumeratedValues>
            </field>
          </fields>
        </register>
        <register>
          <name>TIMING</name>
          <description>I2C0 Master Timing Register</description>
          <addressOffset>0x1c</addressOffset>
          <size>32</size>
          <access>read-write</access>
          <resetValue />
          <fields>
            <field>
              <name>SDAHD</name>
              <description>SDAHD  field description</description>
              <bitRange>[8:0]</bitRange>
              <access>read-write</access>
              <enumeratedValues />
            </field>
          </fields>
        </register>
        <register>
          <name>TO</name>
          <description>I2C0 Master Time-Out Register</description>
          <addressOffset>0x20</addressOffset>
          <size>32</size>
          <access>read-write</access>
          <resetValue>0x00000f00</resetValue>
          <fields>
            <field>
              <name>TIMEOUT</name>
              <description>TIMEOUT  field description</description>
              <bitRange>[11:0]</bitRange>
              <access>read-write</access>
              <enumeratedValues />
            </field>
          </fields>
        </register>
      </registers>
    </peripheral>
    <peripheral>
      <name>I2C1</name>
      <description>I2C1 module information</description>
      <groupName>I2C</groupName>
      <baseAddress>0x40015000</baseAddress>
      <size>32</size>
      <access>read-write</access>
      <addressBlock>
        <offset>0</offset>
        <size>0x24</size>
        <usage>registers</usage>
      </addressBlock>
      <registers>
        <register>
          <name>CFGR</name>
          <description>I2C1 Master Config Register</description>
          <addressOffset>0x0</addressOffset>
          <size>32</size>
          <access>read-write</access>
          <resetValue>0x00000000</resetValue>
          <fields>
            <field>
              <name>AUTOEND</name>
              <description>AUTOEND  field description</description>
              <bitRange>[17:17]</bitRange>
              <access>read-write</access>
              <enumeratedValues>
                <enumeratedValue>
                  <name />
                  <description>DMA指定长度传输完成后，自动发送STOP时序</description>
                  <value>1</value>
                </enumeratedValue>
                <enumeratedValue>
                  <name />
                  <description>DMA指定长度传输完成后，等待软件接管</description>
                  <value>0</value>
                </enumeratedValue>
              </enumeratedValues>
            </field>
            <field>
              <name>MSP_DMAEN</name>
              <description>MSP_DMAEN  field description</description>
              <bitRange>[16:16]</bitRange>
              <access>read-write</access>
              <enumeratedValues>
                <enumeratedValue>
                  <name />
                  <description>关闭DMA功能</description>
                  <value>0</value>
                </enumeratedValue>
                <enumeratedValue>
                  <name />
                  <description>使能DMA功能</description>
                  <value>1</value>
                </enumeratedValue>
              </enumeratedValues>
            </field>
            <field>
              <name>TOEN</name>
              <description>TOEN  field description</description>
              <bitRange>[1:1]</bitRange>
              <access>read-write</access>
              <enumeratedValues>
                <enumeratedValue>
                  <name />
                  <description>使能超时功能，超时周期由MSPTO寄存器定义</description>
                  <value>1</value>
                </enumeratedValue>
                <enumeratedValue>
                  <name />
                  <description>关闭超时功能</description>
                  <value>0</value>
                </enumeratedValue>
              </enumeratedValues>
            </field>
            <field>
              <name>MSPEN</name>
              <description>MSPEN  field description</description>
              <bitRange>[0:0]</bitRange>
              <access>read-write</access>
              <enumeratedValues />
            </field>
          </fields>
        </register>
        <register>
          <name>CR</name>
          <description>I2C1 Master Control Register</description>
          <addressOffset>0x4</addressOffset>
          <size>32</size>
          <access>read-write</access>
          <resetValue>0x00000000</resetValue>
          <fields>
            <field>
              <name>RCEN</name>
              <description>RCEN  field description</description>
              <bitRange>[3:3]</bitRange>
              <access>read-write</access>
              <enumeratedValues>
                <enumeratedValue>
                  <name />
                  <description>主机接收使能</description>
                  <value>1</value>
                </enumeratedValue>
                <enumeratedValue>
                  <name />
                  <description>接收禁止</description>
                  <value>0</value>
                </enumeratedValue>
              </enumeratedValues>
            </field>
            <field>
              <name>PEN</name>
              <description>PEN  field description</description>
              <bitRange>[2:2]</bitRange>
              <access>read-write</access>
              <enumeratedValues />
            </field>
            <field>
              <name>RSEN</name>
              <description>RSEN  field description</description>
              <bitRange>[1:1]</bitRange>
              <access>read-write</access>
              <enumeratedValues />
            </field>
            <field>
              <name>SEN</name>
              <description>SEN  field description</description>
              <bitRange>[0:0]</bitRange>
              <access>read-write</access>
              <enumeratedValues />
            </field>
          </fields>
        </register>
        <register>
          <name>IER</name>
          <description>I2C1 Master Interrupt Enable Register</description>
          <addressOffset>0x8</addressOffset>
          <size>32</size>
          <access>read-write</access>
          <resetValue>0x00000000</resetValue>
          <fields>
            <field>
              <name>WCOLE</name>
              <description>WCOLE  field description</description>
              <bitRange>[6:6]</bitRange>
              <access>read-write</access>
              <enumeratedValues>
                <enumeratedValue>
                  <name />
                  <description>允许写冲突中断</description>
                  <value>1</value>
                </enumeratedValue>
                <enumeratedValue>
                  <name />
                  <description>禁止写冲突中断</description>
                  <value>0</value>
                </enumeratedValue>
              </enumeratedValues>
            </field>
            <field>
              <name>TOE</name>
              <description>TOE  field description</description>
              <bitRange>[5:5]</bitRange>
              <access>read-write</access>
              <enumeratedValues>
                <enumeratedValue>
                  <name />
                  <description>允许超时中断</description>
                  <value>1</value>
                </enumeratedValue>
                <enumeratedValue>
                  <name />
                  <description>禁止超时中断</description>
                  <value>0</value>
                </enumeratedValue>
              </enumeratedValues>
            </field>
            <field>
              <name>SE</name>
              <description>SE  field description</description>
              <bitRange>[4:4]</bitRange>
              <access>read-write</access>
              <enumeratedValues>
                <enumeratedValue>
                  <name />
                  <description>允许START时序中断</description>
                  <value>1</value>
                </enumeratedValue>
                <enumeratedValue>
                  <name />
                  <description>禁止START时序中断</description>
                  <value>0</value>
                </enumeratedValue>
              </enumeratedValues>
            </field>
            <field>
              <name>PE</name>
              <description>PE  field description</description>
              <bitRange>[3:3]</bitRange>
              <access>read-write</access>
              <enumeratedValues>
                <enumeratedValue>
                  <name />
                  <description>允许STOP时序中断</description>
                  <value>1</value>
                </enumeratedValue>
                <enumeratedValue>
                  <name />
                  <description>禁止STOP时序中断</description>
                  <value>0</value>
                </enumeratedValue>
              </enumeratedValues>
            </field>
            <field>
              <name>NACKE</name>
              <description>NACKE  field description</description>
              <bitRange>[2:2]</bitRange>
              <access>read-write</access>
              <enumeratedValues>
                <enumeratedValue>
                  <name />
                  <description>允许收到NACK产生中断</description>
                  <value>1</value>
                </enumeratedValue>
                <enumeratedValue>
                  <name />
                  <description>禁止产生NACK中断</description>
                  <value>0</value>
                </enumeratedValue>
              </enumeratedValues>
            </field>
            <field>
              <name>TXIE</name>
              <description>TXIE  field description</description>
              <bitRange>[1:1]</bitRange>
              <access>read-write</access>
              <enumeratedValues>
                <enumeratedValue>
                  <name />
                  <description>允许发送完成中断</description>
                  <value>1</value>
                </enumeratedValue>
                <enumeratedValue>
                  <name />
                  <description>禁止发送完成中断</description>
                  <value>0</value>
                </enumeratedValue>
              </enumeratedValues>
            </field>
            <field>
              <name>RXIE</name>
              <description>RXIE  field description</description>
              <bitRange>[0:0]</bitRange>
              <access>read-write</access>
              <enumeratedValues>
                <enumeratedValue>
                  <name />
                  <description>允许接收完成中断</description>
                  <value>1</value>
                </enumeratedValue>
                <enumeratedValue>
                  <name />
                  <description>禁止接收完成中断</description>
                  <value>0</value>
                </enumeratedValue>
              </enumeratedValues>
            </field>
          </fields>
        </register>
        <register>
          <name>ISR</name>
          <description>I2C1 Master Interrupt Status Register</description>
          <addressOffset>0xc</addressOffset>
          <size>32</size>
          <access>read-write</access>
          <resetValue>0x00000000</resetValue>
          <fields>
            <field>
              <name>WCOL</name>
              <description>WCOL  field description</description>
              <bitRange>[6:6]</bitRange>
              <access>read-write</access>
              <enumeratedValues />
            </field>
            <field>
              <name>TO</name>
              <description>TO  field description</description>
              <bitRange>[5:5]</bitRange>
              <access>read-write</access>
              <enumeratedValues>
                <enumeratedValue>
                  <name />
                  <description>发生SCL超时</description>
                  <value>1</value>
                </enumeratedValue>
                <enumeratedValue>
                  <name />
                  <description>没有发生SCL超时</description>
                  <value>0</value>
                </enumeratedValue>
              </enumeratedValues>
            </field>
            <field>
              <name>S</name>
              <description>S  field description</description>
              <bitRange>[4:4]</bitRange>
              <access>read-only</access>
              <enumeratedValues />
            </field>
            <field>
              <name>P</name>
              <description>P  field description</description>
              <bitRange>[3:3]</bitRange>
              <access>read-only</access>
              <enumeratedValues />
            </field>
            <field>
              <name>ACKSTA</name>
              <description>ACKSTA  field description</description>
              <bitRange>[2:2]</bitRange>
              <access>read-write</access>
              <enumeratedValues>
                <enumeratedValue>
                  <name />
                  <description>从机回应NACK</description>
                  <value>1</value>
                </enumeratedValue>
                <enumeratedValue>
                  <name />
                  <description>从机回应ACK</description>
                  <value>0</value>
                </enumeratedValue>
              </enumeratedValues>
            </field>
            <field>
              <name>TXIF</name>
              <description>TXIF  field description</description>
              <bitRange>[1:1]</bitRange>
              <access>read-write</access>
              <enumeratedValues />
            </field>
            <field>
              <name>RXIF</name>
              <description>RXIF  field description</description>
              <bitRange>[0:0]</bitRange>
              <access>read-write</access>
              <enumeratedValues />
            </field>
          </fields>
        </register>
        <register>
          <name>SR</name>
          <description>I2C1 Master Status Register</description>
          <addressOffset>0x10</addressOffset>
          <size>32</size>
          <access>read-write</access>
          <resetValue>0x00000000</resetValue>
          <fields>
            <field>
              <name>BUSY</name>
              <description>BUSY  field description</description>
              <bitRange>[5:5]</bitRange>
              <access>read-only</access>
              <enumeratedValues>
                <enumeratedValue>
                  <name />
                  <description>接口处于读写状态，正在进行数据传输，</description>
                  <value>1</value>
                </enumeratedValue>
                <enumeratedValue>
                  <name />
                  <description>已完成数据传输</description>
                  <value>0</value>
                </enumeratedValue>
              </enumeratedValues>
            </field>
            <field>
              <name>RW_</name>
              <description>RW_  field description</description>
              <bitRange>[4:4]</bitRange>
              <access>read-only</access>
              <enumeratedValues>
                <enumeratedValue>
                  <name />
                  <description>主机从从机读取数据</description>
                  <value>1</value>
                </enumeratedValue>
                <enumeratedValue>
                  <name />
                  <description>主机向从机写入数据</description>
                  <value>0</value>
                </enumeratedValue>
              </enumeratedValues>
            </field>
            <field>
              <name>BF</name>
              <description>BF  field description</description>
              <bitRange>[2:2]</bitRange>
              <access>read-only</access>
              <enumeratedValues>
                <enumeratedValue>
                  <name />
                  <description />
                  <value>0</value>
                </enumeratedValue>
                <enumeratedValue>
                  <name />
                  <description>接收完成，SSPBUF满</description>
                  <value>1</value>
                </enumeratedValue>
                <enumeratedValue>
                  <name />
                  <description>接收未完成，SSPBUF空</description>
                  <value>0</value>
                </enumeratedValue>
                <enumeratedValue>
                  <name />
                  <description />
                  <value>0</value>
                </enumeratedValue>
                <enumeratedValue>
                  <name />
                  <description>正在发送，SSPBUF满</description>
                  <value>1</value>
                </enumeratedValue>
                <enumeratedValue>
                  <name />
                  <description>发送完成，SSPBUF空</description>
                  <value>0</value>
                </enumeratedValue>
              </enumeratedValues>
            </field>
            <field>
              <name>ACKMO</name>
              <description>ACKMO  field description</description>
              <bitRange>[0:0]</bitRange>
              <access>read-write</access>
              <enumeratedValues>
                <enumeratedValue>
                  <name />
                  <description>主机回发NACK</description>
                  <value>1</value>
                </enumeratedValue>
                <enumeratedValue>
                  <name />
                  <description>主机回发ACK</description>
                  <value>0</value>
                </enumeratedValue>
                <enumeratedValue>
                  <name />
                  <description>必须在P标志寄存器被清零的情况下，软件才能置位ACKMO</description>
                  <value>0</value>
                </enumeratedValue>
              </enumeratedValues>
            </field>
          </fields>
        </register>
        <register>
          <name>BRG</name>
          <description>I2C1 Master Baud Rate Generation Register</description>
          <addressOffset>0x14</addressOffset>
          <size>32</size>
          <access>read-write</access>
          <resetValue />
          <fields>
            <field>
              <name>MSPBRGH</name>
              <description>MSPBRGH  field description</description>
              <bitRange>[24:16]</bitRange>
              <access>read-write</access>
              <enumeratedValues />
            </field>
            <field>
              <name>MSPBRGL</name>
              <description>MSPBRGL  field description</description>
              <bitRange>[8:0]</bitRange>
              <access>read-write</access>
              <enumeratedValues />
            </field>
          </fields>
        </register>
        <register>
          <name>BUF</name>
          <description>I2C1 Master Buffer Register</description>
          <addressOffset>0x18</addressOffset>
          <size>32</size>
          <access>read-write</access>
          <resetValue>0x00000000</resetValue>
          <fields>
            <field>
              <name>MSPBUF</name>
              <description>MSPBUF  field description</description>
              <bitRange>[7:0]</bitRange>
              <access>read-write</access>
              <enumeratedValues>
                <enumeratedValue>
                  <name />
                  <description>数据的读写通过对SSPBUF的操作完成。发送时，对SSPBUF执行写操作，同时也载入数据收发移位寄存器(SSPSR)；接收时，SSPBUF与SSPSR组成双缓冲结构，读出数据为SSPBUF的数据。接收完一个字节的数据，SSPSR将数据载入SSPBUF，同时置位I2CIF。SSPSR不是直接寄存器，没有物理地址。</description>
                  <value>0</value>
                </enumeratedValue>
              </enumeratedValues>
            </field>
          </fields>
        </register>
        <register>
          <name>TIMING</name>
          <description>I2C1 Master Timing Register</description>
          <addressOffset>0x1c</addressOffset>
          <size>32</size>
          <access>read-write</access>
          <resetValue />
          <fields>
            <field>
              <name>SDAHD</name>
              <description>SDAHD  field description</description>
              <bitRange>[8:0]</bitRange>
              <access>read-write</access>
              <enumeratedValues />
            </field>
          </fields>
        </register>
        <register>
          <name>TO</name>
          <description>I2C1 Master Time-Out Register</description>
          <addressOffset>0x20</addressOffset>
          <size>32</size>
          <access>read-write</access>
          <resetValue>0x00000f00</resetValue>
          <fields>
            <field>
              <name>TIMEOUT</name>
              <description>TIMEOUT  field description</description>
              <bitRange>[11:0]</bitRange>
              <access>read-write</access>
              <enumeratedValues />
            </field>
          </fields>
        </register>
      </registers>
    </peripheral>
    <peripheral>
      <name>UART</name>
      <description>UART module information</description>
      <groupName>UART</groupName>
      <baseAddress>0x40017c00</baseAddress>
      <size>32</size>
      <access>read-write</access>
      <addressBlock>
        <offset>0</offset>
        <size>0x1c</size>
        <usage>registers</usage>
      </addressBlock>
      <registers>
        <register>
          <name>IRCR</name>
          <description>Infrared modulation Control Register</description>
          <addressOffset>0x0</addressOffset>
          <size>32</size>
          <access>read-write</access>
          <resetValue>0x00000000</resetValue>
          <fields>
            <field>
              <name>IRFLAG</name>
              <description>IRFLAG  field description</description>
              <bitRange>[15:15]</bitRange>
              <access>read-write</access>
              <enumeratedValues>
                <enumeratedValue>
                  <name />
                  <description>正极性</description>
                  <value>0</value>
                </enumeratedValue>
                <enumeratedValue>
                  <name />
                  <description>负极性</description>
                  <value>1</value>
                </enumeratedValue>
              </enumeratedValues>
            </field>
            <field>
              <name>TH</name>
              <description>TH  field description</description>
              <bitRange>[14:11]</bitRange>
              <access>read-write</access>
              <enumeratedValues />
            </field>
            <field>
              <name>TZBRG</name>
              <description>TZBRG  field description</description>
              <bitRange>[10:0]</bitRange>
              <access>read-write</access>
              <enumeratedValues />
            </field>
          </fields>
        </register>
      </registers>
    </peripheral>
    <peripheral>
      <name>UART0</name>
      <description>UART0 module information</description>
      <groupName>UART</groupName>
      <baseAddress>0x40012000</baseAddress>
      <size>32</size>
      <access>read-write</access>
      <addressBlock>
        <offset>0</offset>
        <size>0x1c</size>
        <usage>registers</usage>
      </addressBlock>
      <registers>
        <register>
          <name>CSR</name>
          <description>UART0 Control Status Register</description>
          <addressOffset>0x0</addressOffset>
          <size>32</size>
          <access>read-write</access>
          <resetValue>0x00000000</resetValue>
          <fields>
            <field>
              <name>BUSY</name>
              <description>BUSY  field description</description>
              <bitRange>[24:24]</bitRange>
              <access>read-only</access>
              <enumeratedValues>
                <enumeratedValue>
                  <name />
                  <description>UART正在通信中</description>
                  <value>1</value>
                </enumeratedValue>
                <enumeratedValue>
                  <name />
                  <description>UART空闲</description>
                  <value>0</value>
                </enumeratedValue>
              </enumeratedValues>
            </field>
            <field>
              <name>TXIREN</name>
              <description>TXIREN  field description</description>
              <bitRange>[17:17]</bitRange>
              <access>read-write</access>
              <enumeratedValues>
                <enumeratedValue>
                  <name />
                  <description>使能红外调制发送</description>
                  <value>1</value>
                </enumeratedValue>
                <enumeratedValue>
                  <name />
                  <description>关闭红外调制发送</description>
                  <value>0</value>
                </enumeratedValue>
              </enumeratedValues>
            </field>
            <field>
              <name>RXTOEN</name>
              <description>RXTOEN  field description</description>
              <bitRange>[16:16]</bitRange>
              <access>read-write</access>
              <enumeratedValues>
                <enumeratedValue>
                  <name />
                  <description>使能接收超时功能</description>
                  <value>1</value>
                </enumeratedValue>
                <enumeratedValue>
                  <name />
                  <description>关闭接收超时功能</description>
                  <value>0</value>
                </enumeratedValue>
              </enumeratedValues>
            </field>
            <field>
              <name>IOSWAP</name>
              <description>IOSWAP  field description</description>
              <bitRange>[12:12]</bitRange>
              <access>read-write</access>
              <enumeratedValues>
                <enumeratedValue>
                  <name />
                  <description>默认引脚顺序（与封装图一致）</description>
                  <value>0</value>
                </enumeratedValue>
                <enumeratedValue>
                  <name />
                  <description>交换引脚顺序</description>
                  <value>1</value>
                </enumeratedValue>
              </enumeratedValues>
            </field>
            <field>
              <name>DMATXIFCFG</name>
              <description>DMATXIFCFG  field description</description>
              <bitRange>[10:10]</bitRange>
              <access>read-write</access>
              <enumeratedValues>
                <enumeratedValue>
                  <name />
                  <description>IE=1的情况下，DMA模式下发送完最后一帧后，允许中断信号输出；最后一帧之前的数据帧发送完成后不允许中断信号输出</description>
                  <value>1</value>
                </enumeratedValue>
                <enumeratedValue>
                  <name />
                  <description>是否允许中断信号输出仅由IE决定</description>
                  <value>0</value>
                </enumeratedValue>
              </enumeratedValues>
            </field>
            <field>
              <name>BITORD</name>
              <description>BITORD  field description</description>
              <bitRange>[9:9]</bitRange>
              <access>read-write</access>
              <enumeratedValues>
                <enumeratedValue>
                  <name />
                  <description>LSB first</description>
                  <value>0</value>
                </enumeratedValue>
                <enumeratedValue>
                  <name />
                  <description>MSB first</description>
                  <value>1</value>
                </enumeratedValue>
              </enumeratedValues>
            </field>
            <field>
              <name>STOPCFG</name>
              <description>STOPCFG  field description</description>
              <bitRange>[8:8]</bitRange>
              <access>read-write</access>
              <enumeratedValues>
                <enumeratedValue>
                  <name />
                  <description>1位停止位</description>
                  <value>0</value>
                </enumeratedValue>
                <enumeratedValue>
                  <name />
                  <description>2位停止位</description>
                  <value>1</value>
                </enumeratedValue>
              </enumeratedValues>
            </field>
            <field>
              <name>PDSEL</name>
              <description>PDSEL  field description</description>
              <bitRange>[7:6]</bitRange>
              <access>read-write</access>
              <enumeratedValues>
                <enumeratedValue>
                  <name />
                  <description>7位数据</description>
                  <value>0</value>
                </enumeratedValue>
                <enumeratedValue>
                  <name />
                  <description>8位数据</description>
                  <value>1</value>
                </enumeratedValue>
                <enumeratedValue>
                  <name />
                  <description>9位数据</description>
                  <value>2</value>
                </enumeratedValue>
                <enumeratedValue>
                  <name />
                  <description>6位数据</description>
                  <value>3</value>
                </enumeratedValue>
              </enumeratedValues>
            </field>
            <field>
              <name>PARITY</name>
              <description>PARITY  field description</description>
              <bitRange>[5:4]</bitRange>
              <access>read-write</access>
              <enumeratedValues>
                <enumeratedValue>
                  <name />
                  <description>无校验位</description>
                  <value>0</value>
                </enumeratedValue>
                <enumeratedValue>
                  <name />
                  <description>偶校验</description>
                  <value>1</value>
                </enumeratedValue>
                <enumeratedValue>
                  <name />
                  <description>奇校验</description>
                  <value>2</value>
                </enumeratedValue>
                <enumeratedValue>
                  <name />
                  <description>RFU</description>
                  <value>3</value>
                </enumeratedValue>
              </enumeratedValues>
            </field>
            <field>
              <name>RXPOL</name>
              <description>RXPOL  field description</description>
              <bitRange>[3:3]</bitRange>
              <access>read-write</access>
              <enumeratedValues>
                <enumeratedValue>
                  <name />
                  <description>正向</description>
                  <value>0</value>
                </enumeratedValue>
                <enumeratedValue>
                  <name />
                  <description>取反</description>
                  <value>1</value>
                </enumeratedValue>
              </enumeratedValues>
            </field>
            <field>
              <name>TXPOL</name>
              <description>TXPOL  field description</description>
              <bitRange>[2:2]</bitRange>
              <access>read-write</access>
              <enumeratedValues>
                <enumeratedValue>
                  <name />
                  <description>正向</description>
                  <value>0</value>
                </enumeratedValue>
                <enumeratedValue>
                  <name />
                  <description>取反</description>
                  <value>1</value>
                </enumeratedValue>
              </enumeratedValues>
            </field>
            <field>
              <name>RXEN</name>
              <description>RXEN  field description</description>
              <bitRange>[1:1]</bitRange>
              <access>read-write</access>
              <enumeratedValues />
            </field>
            <field>
              <name>TXEN</name>
              <description>TXEN  field description</description>
              <bitRange>[0:0]</bitRange>
              <access>read-write</access>
              <enumeratedValues />
            </field>
          </fields>
        </register>
        <register>
          <name>IER</name>
          <description>UART0 Interrupt Enable Register</description>
          <addressOffset>0x4</addressOffset>
          <size>32</size>
          <access>read-write</access>
          <resetValue>0x00000000</resetValue>
          <fields>
            <field>
              <name>RXTO_IE</name>
              <description>RXTO_IE  field description</description>
              <bitRange>[11:11]</bitRange>
              <access>read-write</access>
              <enumeratedValues />
            </field>
            <field>
              <name>RXERR_IE</name>
              <description>RXERR_IE  field description</description>
              <bitRange>[10:10]</bitRange>
              <access>read-write</access>
              <enumeratedValues />
            </field>
            <field>
              <name>RXBF_IE</name>
              <description>RXBF_IE  field description</description>
              <bitRange>[8:8]</bitRange>
              <access>read-write</access>
              <enumeratedValues />
            </field>
            <field>
              <name>TXBE_IE</name>
              <description>TXBE_IE  field description</description>
              <bitRange>[1:1]</bitRange>
              <access>read-write</access>
              <enumeratedValues />
            </field>
            <field>
              <name>TXSE_IE</name>
              <description>TXSE_IE  field description</description>
              <bitRange>[0:0]</bitRange>
              <access>read-write</access>
              <enumeratedValues />
            </field>
          </fields>
        </register>
        <register>
          <name>ISR</name>
          <description>UART0 Interrupt Status Register</description>
          <addressOffset>0x8</addressOffset>
          <size>32</size>
          <access>read-write</access>
          <resetValue>0x00000000</resetValue>
          <fields>
            <field>
              <name>PERR</name>
              <description>PERR  field description</description>
              <bitRange>[18:18]</bitRange>
              <access>read-write</access>
              <enumeratedValues />
            </field>
            <field>
              <name>FERR</name>
              <description>FERR  field description</description>
              <bitRange>[17:17]</bitRange>
              <access>read-write</access>
              <enumeratedValues />
            </field>
            <field>
              <name>OERR</name>
              <description>OERR  field description</description>
              <bitRange>[16:16]</bitRange>
              <access>read-write</access>
              <enumeratedValues />
            </field>
            <field>
              <name>RXTO</name>
              <description>RXTO  field description</description>
              <bitRange>[11:11]</bitRange>
              <access>read-write</access>
              <enumeratedValues />
            </field>
            <field>
              <name>RXBF</name>
              <description>RXBF  field description</description>
              <bitRange>[8:8]</bitRange>
              <access>read-write</access>
              <enumeratedValues />
            </field>
            <field>
              <name>TXBE</name>
              <description>TXBE  field description</description>
              <bitRange>[1:1]</bitRange>
              <access>read-write</access>
              <enumeratedValues />
            </field>
            <field>
              <name>TXSE</name>
              <description>TXSE  field description</description>
              <bitRange>[0:0]</bitRange>
              <access>read-write</access>
              <enumeratedValues />
            </field>
          </fields>
        </register>
        <register>
          <name>TODR</name>
          <description>UART0 Time-Out and Delay Register</description>
          <addressOffset>0xc</addressOffset>
          <size>32</size>
          <access>read-write</access>
          <resetValue>0x00000000</resetValue>
          <fields>
            <field>
              <name>TXDLY_LEN</name>
              <description>TXDLY_LEN  field description</description>
              <bitRange>[15:8]</bitRange>
              <access>read-write</access>
              <enumeratedValues />
            </field>
            <field>
              <name>RXTO_LEN</name>
              <description>RXTO_LEN  field description</description>
              <bitRange>[7:0]</bitRange>
              <access>read-write</access>
              <enumeratedValues />
            </field>
          </fields>
        </register>
        <register>
          <name>RXBUF</name>
          <description>UART0 Receive Buffer</description>
          <addressOffset>0x10</addressOffset>
          <size>32</size>
          <access>read-write</access>
          <resetValue />
          <fields>
            <field>
              <name>RXBUF</name>
              <description>RXBUF  field description</description>
              <bitRange>[8:0]</bitRange>
              <access>read-only</access>
              <enumeratedValues />
            </field>
          </fields>
        </register>
        <register>
          <name>TXBUF</name>
          <description>UART0 Transmit Buffer</description>
          <addressOffset>0x14</addressOffset>
          <size>32</size>
          <access>read-write</access>
          <resetValue />
          <fields>
            <field>
              <name>TXBUF</name>
              <description>TXBUF  field description</description>
              <bitRange>[8:0]</bitRange>
              <access>read-write</access>
              <enumeratedValues />
            </field>
          </fields>
        </register>
        <register>
          <name>BGR</name>
          <description>UART0 Baud rate Generator Register</description>
          <addressOffset>0x18</addressOffset>
          <size>32</size>
          <access>read-write</access>
          <resetValue>0x00000341</resetValue>
          <fields>
            <field>
              <name>SPBRG</name>
              <description>SPBRG  field description</description>
              <bitRange>[15:0]</bitRange>
              <access>read-write</access>
              <enumeratedValues />
            </field>
          </fields>
        </register>
      </registers>
    </peripheral>
    <peripheral>
      <name>UART1</name>
      <description>UART1 module information</description>
      <groupName>UART</groupName>
      <baseAddress>0x40016800</baseAddress>
      <size>32</size>
      <access>read-write</access>
      <addressBlock>
        <offset>0</offset>
        <size>0x1c</size>
        <usage>registers</usage>
      </addressBlock>
      <registers>
        <register>
          <name>CSR</name>
          <description>UART1 Control Status Register</description>
          <addressOffset>0x0</addressOffset>
          <size>32</size>
          <access>read-write</access>
          <resetValue>0x00000000</resetValue>
          <fields>
            <field>
              <name>BUSY</name>
              <description>BUSY  field description</description>
              <bitRange>[24:24]</bitRange>
              <access>read-only</access>
              <enumeratedValues>
                <enumeratedValue>
                  <name />
                  <description>UART正在通信中</description>
                  <value>1</value>
                </enumeratedValue>
                <enumeratedValue>
                  <name />
                  <description>UART空闲</description>
                  <value>0</value>
                </enumeratedValue>
              </enumeratedValues>
            </field>
            <field>
              <name>TXIREN</name>
              <description>TXIREN  field description</description>
              <bitRange>[17:17]</bitRange>
              <access>read-write</access>
              <enumeratedValues>
                <enumeratedValue>
                  <name />
                  <description>使能红外调制发送</description>
                  <value>1</value>
                </enumeratedValue>
                <enumeratedValue>
                  <name />
                  <description>关闭红外调制发送</description>
                  <value>0</value>
                </enumeratedValue>
              </enumeratedValues>
            </field>
            <field>
              <name>RXTOEN</name>
              <description>RXTOEN  field description</description>
              <bitRange>[16:16]</bitRange>
              <access>read-write</access>
              <enumeratedValues>
                <enumeratedValue>
                  <name />
                  <description>使能接收超时功能</description>
                  <value>1</value>
                </enumeratedValue>
                <enumeratedValue>
                  <name />
                  <description>关闭接收超时功能</description>
                  <value>0</value>
                </enumeratedValue>
              </enumeratedValues>
            </field>
            <field>
              <name>IOSWAP</name>
              <description>IOSWAP  field description</description>
              <bitRange>[12:12]</bitRange>
              <access>read-write</access>
              <enumeratedValues>
                <enumeratedValue>
                  <name />
                  <description>默认引脚顺序（与封装图一致）</description>
                  <value>0</value>
                </enumeratedValue>
                <enumeratedValue>
                  <name />
                  <description>交换引脚顺序</description>
                  <value>1</value>
                </enumeratedValue>
              </enumeratedValues>
            </field>
            <field>
              <name>DMATXIFCFG</name>
              <description>DMATXIFCFG  field description</description>
              <bitRange>[10:10]</bitRange>
              <access>read-write</access>
              <enumeratedValues>
                <enumeratedValue>
                  <name />
                  <description>IE=1的情况下，DMA模式下发送完最后一帧后，允许中断信号输出；最后一帧之前的数据帧发送完成后不允许中断信号输出</description>
                  <value>1</value>
                </enumeratedValue>
                <enumeratedValue>
                  <name />
                  <description>是否允许中断信号输出仅由IE决定</description>
                  <value>0</value>
                </enumeratedValue>
              </enumeratedValues>
            </field>
            <field>
              <name>BITORD</name>
              <description>BITORD  field description</description>
              <bitRange>[9:9]</bitRange>
              <access>read-write</access>
              <enumeratedValues>
                <enumeratedValue>
                  <name />
                  <description>LSB first</description>
                  <value>0</value>
                </enumeratedValue>
                <enumeratedValue>
                  <name />
                  <description>MSB first</description>
                  <value>1</value>
                </enumeratedValue>
              </enumeratedValues>
            </field>
            <field>
              <name>STOPCFG</name>
              <description>STOPCFG  field description</description>
              <bitRange>[8:8]</bitRange>
              <access>read-write</access>
              <enumeratedValues>
                <enumeratedValue>
                  <name />
                  <description>1位停止位</description>
                  <value>0</value>
                </enumeratedValue>
                <enumeratedValue>
                  <name />
                  <description>2位停止位</description>
                  <value>1</value>
                </enumeratedValue>
              </enumeratedValues>
            </field>
            <field>
              <name>PDSEL</name>
              <description>PDSEL  field description</description>
              <bitRange>[7:6]</bitRange>
              <access>read-write</access>
              <enumeratedValues>
                <enumeratedValue>
                  <name />
                  <description>7位数据</description>
                  <value>0</value>
                </enumeratedValue>
                <enumeratedValue>
                  <name />
                  <description>8位数据</description>
                  <value>1</value>
                </enumeratedValue>
                <enumeratedValue>
                  <name />
                  <description>9位数据</description>
                  <value>2</value>
                </enumeratedValue>
                <enumeratedValue>
                  <name />
                  <description>6位数据</description>
                  <value>3</value>
                </enumeratedValue>
              </enumeratedValues>
            </field>
            <field>
              <name>PARITY</name>
              <description>PARITY  field description</description>
              <bitRange>[5:4]</bitRange>
              <access>read-write</access>
              <enumeratedValues>
                <enumeratedValue>
                  <name />
                  <description>无校验位</description>
                  <value>0</value>
                </enumeratedValue>
                <enumeratedValue>
                  <name />
                  <description>偶校验</description>
                  <value>1</value>
                </enumeratedValue>
                <enumeratedValue>
                  <name />
                  <description>奇校验</description>
                  <value>2</value>
                </enumeratedValue>
                <enumeratedValue>
                  <name />
                  <description>RFU</description>
                  <value>3</value>
                </enumeratedValue>
              </enumeratedValues>
            </field>
            <field>
              <name>RXPOL</name>
              <description>RXPOL  field description</description>
              <bitRange>[3:3]</bitRange>
              <access>read-write</access>
              <enumeratedValues>
                <enumeratedValue>
                  <name />
                  <description>正向</description>
                  <value>0</value>
                </enumeratedValue>
                <enumeratedValue>
                  <name />
                  <description>取反</description>
                  <value>1</value>
                </enumeratedValue>
              </enumeratedValues>
            </field>
            <field>
              <name>TXPOL</name>
              <description>TXPOL  field description</description>
              <bitRange>[2:2]</bitRange>
              <access>read-write</access>
              <enumeratedValues>
                <enumeratedValue>
                  <name />
                  <description>正向</description>
                  <value>0</value>
                </enumeratedValue>
                <enumeratedValue>
                  <name />
                  <description>取反</description>
                  <value>1</value>
                </enumeratedValue>
              </enumeratedValues>
            </field>
            <field>
              <name>RXEN</name>
              <description>RXEN  field description</description>
              <bitRange>[1:1]</bitRange>
              <access>read-write</access>
              <enumeratedValues />
            </field>
            <field>
              <name>TXEN</name>
              <description>TXEN  field description</description>
              <bitRange>[0:0]</bitRange>
              <access>read-write</access>
              <enumeratedValues />
            </field>
          </fields>
        </register>
        <register>
          <name>IER</name>
          <description>UART1 Interrupt Enable Register</description>
          <addressOffset>0x4</addressOffset>
          <size>32</size>
          <access>read-write</access>
          <resetValue>0x00000000</resetValue>
          <fields>
            <field>
              <name>RXTO_IE</name>
              <description>RXTO_IE  field description</description>
              <bitRange>[11:11]</bitRange>
              <access>read-write</access>
              <enumeratedValues />
            </field>
            <field>
              <name>RXERR_IE</name>
              <description>RXERR_IE  field description</description>
              <bitRange>[10:10]</bitRange>
              <access>read-write</access>
              <enumeratedValues />
            </field>
            <field>
              <name>RXBF_IE</name>
              <description>RXBF_IE  field description</description>
              <bitRange>[8:8]</bitRange>
              <access>read-write</access>
              <enumeratedValues />
            </field>
            <field>
              <name>TXBE_IE</name>
              <description>TXBE_IE  field description</description>
              <bitRange>[1:1]</bitRange>
              <access>read-write</access>
              <enumeratedValues />
            </field>
            <field>
              <name>TXSE_IE</name>
              <description>TXSE_IE  field description</description>
              <bitRange>[0:0]</bitRange>
              <access>read-write</access>
              <enumeratedValues />
            </field>
          </fields>
        </register>
        <register>
          <name>ISR</name>
          <description>UART1 Interrupt Status Register</description>
          <addressOffset>0x8</addressOffset>
          <size>32</size>
          <access>read-write</access>
          <resetValue>0x00000000</resetValue>
          <fields>
            <field>
              <name>PERR</name>
              <description>PERR  field description</description>
              <bitRange>[18:18]</bitRange>
              <access>read-write</access>
              <enumeratedValues />
            </field>
            <field>
              <name>FERR</name>
              <description>FERR  field description</description>
              <bitRange>[17:17]</bitRange>
              <access>read-write</access>
              <enumeratedValues />
            </field>
            <field>
              <name>OERR</name>
              <description>OERR  field description</description>
              <bitRange>[16:16]</bitRange>
              <access>read-write</access>
              <enumeratedValues />
            </field>
            <field>
              <name>RXTO</name>
              <description>RXTO  field description</description>
              <bitRange>[11:11]</bitRange>
              <access>read-write</access>
              <enumeratedValues />
            </field>
            <field>
              <name>RXBF</name>
              <description>RXBF  field description</description>
              <bitRange>[8:8]</bitRange>
              <access>read-write</access>
              <enumeratedValues />
            </field>
            <field>
              <name>TXBE</name>
              <description>TXBE  field description</description>
              <bitRange>[1:1]</bitRange>
              <access>read-write</access>
              <enumeratedValues />
            </field>
            <field>
              <name>TXSE</name>
              <description>TXSE  field description</description>
              <bitRange>[0:0]</bitRange>
              <access>read-write</access>
              <enumeratedValues />
            </field>
          </fields>
        </register>
        <register>
          <name>TODR</name>
          <description>UART1 Time-Out and Delay Register</description>
          <addressOffset>0xc</addressOffset>
          <size>32</size>
          <access>read-write</access>
          <resetValue>0x00000000</resetValue>
          <fields>
            <field>
              <name>TXDLY_LEN</name>
              <description>TXDLY_LEN  field description</description>
              <bitRange>[15:8]</bitRange>
              <access>read-write</access>
              <enumeratedValues />
            </field>
            <field>
              <name>RXTO_LEN</name>
              <description>RXTO_LEN  field description</description>
              <bitRange>[7:0]</bitRange>
              <access>read-write</access>
              <enumeratedValues />
            </field>
          </fields>
        </register>
        <register>
          <name>RXBUF</name>
          <description>UART1 Receive Buffer</description>
          <addressOffset>0x10</addressOffset>
          <size>32</size>
          <access>read-write</access>
          <resetValue />
          <fields>
            <field>
              <name>RXBUF</name>
              <description>RXBUF  field description</description>
              <bitRange>[8:0]</bitRange>
              <access>read-only</access>
              <enumeratedValues />
            </field>
          </fields>
        </register>
        <register>
          <name>TXBUF</name>
          <description>UART1 Transmit Buffer</description>
          <addressOffset>0x14</addressOffset>
          <size>32</size>
          <access>read-write</access>
          <resetValue />
          <fields>
            <field>
              <name>TXBUF</name>
              <description>TXBUF  field description</description>
              <bitRange>[8:0]</bitRange>
              <access>read-write</access>
              <enumeratedValues />
            </field>
          </fields>
        </register>
        <register>
          <name>BGR</name>
          <description>UART1 Baud rate Generator Register</description>
          <addressOffset>0x18</addressOffset>
          <size>32</size>
          <access>read-write</access>
          <resetValue>0x00000341</resetValue>
          <fields>
            <field>
              <name>SPBRG</name>
              <description>SPBRG  field description</description>
              <bitRange>[15:0]</bitRange>
              <access>read-write</access>
              <enumeratedValues />
            </field>
          </fields>
        </register>
      </registers>
    </peripheral>
    <peripheral>
      <name>UART2</name>
      <description>UART2 module information</description>
      <groupName>UART</groupName>
      <baseAddress>0x40016c00</baseAddress>
      <size>32</size>
      <access>read-write</access>
      <addressBlock>
        <offset>0</offset>
        <size>0x1c</size>
        <usage>registers</usage>
      </addressBlock>
      <registers>
        <register>
          <name>CSR</name>
          <description>UART2 Control Status Register</description>
          <addressOffset>0x0</addressOffset>
          <size>32</size>
          <access>read-write</access>
          <resetValue>0x00000000</resetValue>
          <fields>
            <field>
              <name>BUSY</name>
              <description>BUSY  field description</description>
              <bitRange>[24:24]</bitRange>
              <access>read-only</access>
              <enumeratedValues>
                <enumeratedValue>
                  <name />
                  <description>UART正在通信中</description>
                  <value>1</value>
                </enumeratedValue>
                <enumeratedValue>
                  <name />
                  <description>UART空闲</description>
                  <value>0</value>
                </enumeratedValue>
              </enumeratedValues>
            </field>
            <field>
              <name>TXIREN</name>
              <description>TXIREN  field description</description>
              <bitRange>[17:17]</bitRange>
              <access>read-write</access>
              <enumeratedValues>
                <enumeratedValue>
                  <name />
                  <description>使能红外调制发送</description>
                  <value>1</value>
                </enumeratedValue>
                <enumeratedValue>
                  <name />
                  <description>关闭红外调制发送</description>
                  <value>0</value>
                </enumeratedValue>
              </enumeratedValues>
            </field>
            <field>
              <name>RXTOEN</name>
              <description>RXTOEN  field description</description>
              <bitRange>[16:16]</bitRange>
              <access>read-write</access>
              <enumeratedValues>
                <enumeratedValue>
                  <name />
                  <description>使能接收超时功能</description>
                  <value>1</value>
                </enumeratedValue>
                <enumeratedValue>
                  <name />
                  <description>关闭接收超时功能</description>
                  <value>0</value>
                </enumeratedValue>
              </enumeratedValues>
            </field>
            <field>
              <name>IOSWAP</name>
              <description>IOSWAP  field description</description>
              <bitRange>[12:12]</bitRange>
              <access>read-write</access>
              <enumeratedValues>
                <enumeratedValue>
                  <name />
                  <description>默认引脚顺序（与封装图一致）</description>
                  <value>0</value>
                </enumeratedValue>
                <enumeratedValue>
                  <name />
                  <description>交换引脚顺序</description>
                  <value>1</value>
                </enumeratedValue>
              </enumeratedValues>
            </field>
            <field>
              <name>DMATXIFCFG</name>
              <description>DMATXIFCFG  field description</description>
              <bitRange>[10:10]</bitRange>
              <access>read-write</access>
              <enumeratedValues>
                <enumeratedValue>
                  <name />
                  <description>IE=1的情况下，DMA模式下发送完最后一帧后，允许中断信号输出；最后一帧之前的数据帧发送完成后不允许中断信号输出</description>
                  <value>1</value>
                </enumeratedValue>
                <enumeratedValue>
                  <name />
                  <description>是否允许中断信号输出仅由IE决定</description>
                  <value>0</value>
                </enumeratedValue>
              </enumeratedValues>
            </field>
            <field>
              <name>BITORD</name>
              <description>BITORD  field description</description>
              <bitRange>[9:9]</bitRange>
              <access>read-write</access>
              <enumeratedValues>
                <enumeratedValue>
                  <name />
                  <description>LSB first</description>
                  <value>0</value>
                </enumeratedValue>
                <enumeratedValue>
                  <name />
                  <description>MSB first</description>
                  <value>1</value>
                </enumeratedValue>
              </enumeratedValues>
            </field>
            <field>
              <name>STOPCFG</name>
              <description>STOPCFG  field description</description>
              <bitRange>[8:8]</bitRange>
              <access>read-write</access>
              <enumeratedValues>
                <enumeratedValue>
                  <name />
                  <description>1位停止位</description>
                  <value>0</value>
                </enumeratedValue>
                <enumeratedValue>
                  <name />
                  <description>2位停止位</description>
                  <value>1</value>
                </enumeratedValue>
              </enumeratedValues>
            </field>
            <field>
              <name>PDSEL</name>
              <description>PDSEL  field description</description>
              <bitRange>[7:6]</bitRange>
              <access>read-write</access>
              <enumeratedValues>
                <enumeratedValue>
                  <name />
                  <description>7位数据</description>
                  <value>0</value>
                </enumeratedValue>
                <enumeratedValue>
                  <name />
                  <description>8位数据</description>
                  <value>1</value>
                </enumeratedValue>
                <enumeratedValue>
                  <name />
                  <description>9位数据</description>
                  <value>2</value>
                </enumeratedValue>
                <enumeratedValue>
                  <name />
                  <description>6位数据</description>
                  <value>3</value>
                </enumeratedValue>
              </enumeratedValues>
            </field>
            <field>
              <name>PARITY</name>
              <description>PARITY  field description</description>
              <bitRange>[5:4]</bitRange>
              <access>read-write</access>
              <enumeratedValues>
                <enumeratedValue>
                  <name />
                  <description>无校验位</description>
                  <value>0</value>
                </enumeratedValue>
                <enumeratedValue>
                  <name />
                  <description>偶校验</description>
                  <value>1</value>
                </enumeratedValue>
                <enumeratedValue>
                  <name />
                  <description>奇校验</description>
                  <value>2</value>
                </enumeratedValue>
                <enumeratedValue>
                  <name />
                  <description>RFU</description>
                  <value>3</value>
                </enumeratedValue>
              </enumeratedValues>
            </field>
            <field>
              <name>RXPOL</name>
              <description>RXPOL  field description</description>
              <bitRange>[3:3]</bitRange>
              <access>read-write</access>
              <enumeratedValues>
                <enumeratedValue>
                  <name />
                  <description>正向</description>
                  <value>0</value>
                </enumeratedValue>
                <enumeratedValue>
                  <name />
                  <description>取反</description>
                  <value>1</value>
                </enumeratedValue>
              </enumeratedValues>
            </field>
            <field>
              <name>TXPOL</name>
              <description>TXPOL  field description</description>
              <bitRange>[2:2]</bitRange>
              <access>read-write</access>
              <enumeratedValues>
                <enumeratedValue>
                  <name />
                  <description>正向</description>
                  <value>0</value>
                </enumeratedValue>
                <enumeratedValue>
                  <name />
                  <description>取反</description>
                  <value>1</value>
                </enumeratedValue>
              </enumeratedValues>
            </field>
            <field>
              <name>RXEN</name>
              <description>RXEN  field description</description>
              <bitRange>[1:1]</bitRange>
              <access>read-write</access>
              <enumeratedValues />
            </field>
            <field>
              <name>TXEN</name>
              <description>TXEN  field description</description>
              <bitRange>[0:0]</bitRange>
              <access>read-write</access>
              <enumeratedValues />
            </field>
          </fields>
        </register>
        <register>
          <name>IER</name>
          <description>UART2 Interrupt Enable Register</description>
          <addressOffset>0x4</addressOffset>
          <size>32</size>
          <access>read-write</access>
          <resetValue>0x00000000</resetValue>
          <fields>
            <field>
              <name>RXTO_IE</name>
              <description>RXTO_IE  field description</description>
              <bitRange>[11:11]</bitRange>
              <access>read-write</access>
              <enumeratedValues />
            </field>
            <field>
              <name>RXERR_IE</name>
              <description>RXERR_IE  field description</description>
              <bitRange>[10:10]</bitRange>
              <access>read-write</access>
              <enumeratedValues />
            </field>
            <field>
              <name>RXBF_IE</name>
              <description>RXBF_IE  field description</description>
              <bitRange>[8:8]</bitRange>
              <access>read-write</access>
              <enumeratedValues />
            </field>
            <field>
              <name>TXBE_IE</name>
              <description>TXBE_IE  field description</description>
              <bitRange>[1:1]</bitRange>
              <access>read-write</access>
              <enumeratedValues />
            </field>
            <field>
              <name>TXSE_IE</name>
              <description>TXSE_IE  field description</description>
              <bitRange>[0:0]</bitRange>
              <access>read-write</access>
              <enumeratedValues />
            </field>
          </fields>
        </register>
        <register>
          <name>ISR</name>
          <description>UART2 Interrupt Status Register</description>
          <addressOffset>0x8</addressOffset>
          <size>32</size>
          <access>read-write</access>
          <resetValue>0x00000000</resetValue>
          <fields>
            <field>
              <name>PERR</name>
              <description>PERR  field description</description>
              <bitRange>[18:18]</bitRange>
              <access>read-write</access>
              <enumeratedValues />
            </field>
            <field>
              <name>FERR</name>
              <description>FERR  field description</description>
              <bitRange>[17:17]</bitRange>
              <access>read-write</access>
              <enumeratedValues />
            </field>
            <field>
              <name>OERR</name>
              <description>OERR  field description</description>
              <bitRange>[16:16]</bitRange>
              <access>read-write</access>
              <enumeratedValues />
            </field>
            <field>
              <name>RXTO</name>
              <description>RXTO  field description</description>
              <bitRange>[11:11]</bitRange>
              <access>read-write</access>
              <enumeratedValues />
            </field>
            <field>
              <name>RXBF</name>
              <description>RXBF  field description</description>
              <bitRange>[8:8]</bitRange>
              <access>read-write</access>
              <enumeratedValues />
            </field>
            <field>
              <name>TXBE</name>
              <description>TXBE  field description</description>
              <bitRange>[1:1]</bitRange>
              <access>read-write</access>
              <enumeratedValues />
            </field>
            <field>
              <name>TXSE</name>
              <description>TXSE  field description</description>
              <bitRange>[0:0]</bitRange>
              <access>read-write</access>
              <enumeratedValues />
            </field>
          </fields>
        </register>
        <register>
          <name>RXBUF</name>
          <description>UART2 Receive Buffer</description>
          <addressOffset>0x10</addressOffset>
          <size>32</size>
          <access>read-write</access>
          <resetValue />
          <fields>
            <field>
              <name>RXBUF</name>
              <description>RXBUF  field description</description>
              <bitRange>[8:0]</bitRange>
              <access>read-only</access>
              <enumeratedValues />
            </field>
          </fields>
        </register>
        <register>
          <name>TXBUF</name>
          <description>UART2 Transmit Buffer</description>
          <addressOffset>0x14</addressOffset>
          <size>32</size>
          <access>read-write</access>
          <resetValue />
          <fields>
            <field>
              <name>TXBUF</name>
              <description>TXBUF  field description</description>
              <bitRange>[8:0]</bitRange>
              <access>read-write</access>
              <enumeratedValues />
            </field>
          </fields>
        </register>
        <register>
          <name>BGR</name>
          <description>UART2 Baud rate Generator Register</description>
          <addressOffset>0x18</addressOffset>
          <size>32</size>
          <access>read-write</access>
          <resetValue>0x00000341</resetValue>
          <fields>
            <field>
              <name>SPBRG</name>
              <description>SPBRG  field description</description>
              <bitRange>[15:0]</bitRange>
              <access>read-write</access>
              <enumeratedValues />
            </field>
          </fields>
        </register>
      </registers>
    </peripheral>
    <peripheral>
      <name>UART3</name>
      <description>UART3 module information</description>
      <groupName>UART</groupName>
      <baseAddress>0x40017000</baseAddress>
      <size>32</size>
      <access>read-write</access>
      <addressBlock>
        <offset>0</offset>
        <size>0x1c</size>
        <usage>registers</usage>
      </addressBlock>
      <registers>
        <register>
          <name>CSR</name>
          <description>UART3 Control Status Register</description>
          <addressOffset>0x0</addressOffset>
          <size>32</size>
          <access>read-write</access>
          <resetValue>0x00000000</resetValue>
          <fields>
            <field>
              <name>BUSY</name>
              <description>BUSY  field description</description>
              <bitRange>[24:24]</bitRange>
              <access>read-only</access>
              <enumeratedValues>
                <enumeratedValue>
                  <name />
                  <description>UART正在通信中</description>
                  <value>1</value>
                </enumeratedValue>
                <enumeratedValue>
                  <name />
                  <description>UART空闲</description>
                  <value>0</value>
                </enumeratedValue>
              </enumeratedValues>
            </field>
            <field>
              <name>TXIREN</name>
              <description>TXIREN  field description</description>
              <bitRange>[17:17]</bitRange>
              <access>read-write</access>
              <enumeratedValues>
                <enumeratedValue>
                  <name />
                  <description>使能红外调制发送</description>
                  <value>1</value>
                </enumeratedValue>
                <enumeratedValue>
                  <name />
                  <description>关闭红外调制发送</description>
                  <value>0</value>
                </enumeratedValue>
              </enumeratedValues>
            </field>
            <field>
              <name>RXTOEN</name>
              <description>RXTOEN  field description</description>
              <bitRange>[16:16]</bitRange>
              <access>read-write</access>
              <enumeratedValues>
                <enumeratedValue>
                  <name />
                  <description>使能接收超时功能</description>
                  <value>1</value>
                </enumeratedValue>
                <enumeratedValue>
                  <name />
                  <description>关闭接收超时功能</description>
                  <value>0</value>
                </enumeratedValue>
              </enumeratedValues>
            </field>
            <field>
              <name>IOSWAP</name>
              <description>IOSWAP  field description</description>
              <bitRange>[12:12]</bitRange>
              <access>read-write</access>
              <enumeratedValues>
                <enumeratedValue>
                  <name />
                  <description>默认引脚顺序（与封装图一致）</description>
                  <value>0</value>
                </enumeratedValue>
                <enumeratedValue>
                  <name />
                  <description>交换引脚顺序</description>
                  <value>1</value>
                </enumeratedValue>
              </enumeratedValues>
            </field>
            <field>
              <name>DMATXIFCFG</name>
              <description>DMATXIFCFG  field description</description>
              <bitRange>[10:10]</bitRange>
              <access>read-write</access>
              <enumeratedValues>
                <enumeratedValue>
                  <name />
                  <description>IE=1的情况下，DMA模式下发送完最后一帧后，允许中断信号输出；最后一帧之前的数据帧发送完成后不允许中断信号输出</description>
                  <value>1</value>
                </enumeratedValue>
                <enumeratedValue>
                  <name />
                  <description>是否允许中断信号输出仅由IE决定</description>
                  <value>0</value>
                </enumeratedValue>
              </enumeratedValues>
            </field>
            <field>
              <name>BITORD</name>
              <description>BITORD  field description</description>
              <bitRange>[9:9]</bitRange>
              <access>read-write</access>
              <enumeratedValues>
                <enumeratedValue>
                  <name />
                  <description>LSB first</description>
                  <value>0</value>
                </enumeratedValue>
                <enumeratedValue>
                  <name />
                  <description>MSB first</description>
                  <value>1</value>
                </enumeratedValue>
              </enumeratedValues>
            </field>
            <field>
              <name>STOPCFG</name>
              <description>STOPCFG  field description</description>
              <bitRange>[8:8]</bitRange>
              <access>read-write</access>
              <enumeratedValues>
                <enumeratedValue>
                  <name />
                  <description>1位停止位</description>
                  <value>0</value>
                </enumeratedValue>
                <enumeratedValue>
                  <name />
                  <description>2位停止位</description>
                  <value>1</value>
                </enumeratedValue>
              </enumeratedValues>
            </field>
            <field>
              <name>PDSEL</name>
              <description>PDSEL  field description</description>
              <bitRange>[7:6]</bitRange>
              <access>read-write</access>
              <enumeratedValues>
                <enumeratedValue>
                  <name />
                  <description>7位数据</description>
                  <value>0</value>
                </enumeratedValue>
                <enumeratedValue>
                  <name />
                  <description>8位数据</description>
                  <value>1</value>
                </enumeratedValue>
                <enumeratedValue>
                  <name />
                  <description>9位数据</description>
                  <value>2</value>
                </enumeratedValue>
                <enumeratedValue>
                  <name />
                  <description>6位数据</description>
                  <value>3</value>
                </enumeratedValue>
              </enumeratedValues>
            </field>
            <field>
              <name>PARITY</name>
              <description>PARITY  field description</description>
              <bitRange>[5:4]</bitRange>
              <access>read-write</access>
              <enumeratedValues>
                <enumeratedValue>
                  <name />
                  <description>无校验位</description>
                  <value>0</value>
                </enumeratedValue>
                <enumeratedValue>
                  <name />
                  <description>偶校验</description>
                  <value>1</value>
                </enumeratedValue>
                <enumeratedValue>
                  <name />
                  <description>奇校验</description>
                  <value>2</value>
                </enumeratedValue>
                <enumeratedValue>
                  <name />
                  <description>RFU</description>
                  <value>3</value>
                </enumeratedValue>
              </enumeratedValues>
            </field>
            <field>
              <name>RXPOL</name>
              <description>RXPOL  field description</description>
              <bitRange>[3:3]</bitRange>
              <access>read-write</access>
              <enumeratedValues>
                <enumeratedValue>
                  <name />
                  <description>正向</description>
                  <value>0</value>
                </enumeratedValue>
                <enumeratedValue>
                  <name />
                  <description>取反</description>
                  <value>1</value>
                </enumeratedValue>
              </enumeratedValues>
            </field>
            <field>
              <name>TXPOL</name>
              <description>TXPOL  field description</description>
              <bitRange>[2:2]</bitRange>
              <access>read-write</access>
              <enumeratedValues>
                <enumeratedValue>
                  <name />
                  <description>正向</description>
                  <value>0</value>
                </enumeratedValue>
                <enumeratedValue>
                  <name />
                  <description>取反</description>
                  <value>1</value>
                </enumeratedValue>
              </enumeratedValues>
            </field>
            <field>
              <name>RXEN</name>
              <description>RXEN  field description</description>
              <bitRange>[1:1]</bitRange>
              <access>read-write</access>
              <enumeratedValues />
            </field>
            <field>
              <name>TXEN</name>
              <description>TXEN  field description</description>
              <bitRange>[0:0]</bitRange>
              <access>read-write</access>
              <enumeratedValues />
            </field>
          </fields>
        </register>
        <register>
          <name>IER</name>
          <description>UART3 Interrupt Enable Register</description>
          <addressOffset>0x4</addressOffset>
          <size>32</size>
          <access>read-write</access>
          <resetValue>0x00000000</resetValue>
          <fields>
            <field>
              <name>RXTO_IE</name>
              <description>RXTO_IE  field description</description>
              <bitRange>[11:11]</bitRange>
              <access>read-write</access>
              <enumeratedValues />
            </field>
            <field>
              <name>RXERR_IE</name>
              <description>RXERR_IE  field description</description>
              <bitRange>[10:10]</bitRange>
              <access>read-write</access>
              <enumeratedValues />
            </field>
            <field>
              <name>RXBF_IE</name>
              <description>RXBF_IE  field description</description>
              <bitRange>[8:8]</bitRange>
              <access>read-write</access>
              <enumeratedValues />
            </field>
            <field>
              <name>TXBE_IE</name>
              <description>TXBE_IE  field description</description>
              <bitRange>[1:1]</bitRange>
              <access>read-write</access>
              <enumeratedValues />
            </field>
            <field>
              <name>TXSE_IE</name>
              <description>TXSE_IE  field description</description>
              <bitRange>[0:0]</bitRange>
              <access>read-write</access>
              <enumeratedValues />
            </field>
          </fields>
        </register>
        <register>
          <name>ISR</name>
          <description>UART3 Interrupt Status Register</description>
          <addressOffset>0x8</addressOffset>
          <size>32</size>
          <access>read-write</access>
          <resetValue>0x00000000</resetValue>
          <fields>
            <field>
              <name>PERR</name>
              <description>PERR  field description</description>
              <bitRange>[18:18]</bitRange>
              <access>read-write</access>
              <enumeratedValues />
            </field>
            <field>
              <name>FERR</name>
              <description>FERR  field description</description>
              <bitRange>[17:17]</bitRange>
              <access>read-write</access>
              <enumeratedValues />
            </field>
            <field>
              <name>OERR</name>
              <description>OERR  field description</description>
              <bitRange>[16:16]</bitRange>
              <access>read-write</access>
              <enumeratedValues />
            </field>
            <field>
              <name>RXTO</name>
              <description>RXTO  field description</description>
              <bitRange>[11:11]</bitRange>
              <access>read-write</access>
              <enumeratedValues />
            </field>
            <field>
              <name>RXBF</name>
              <description>RXBF  field description</description>
              <bitRange>[8:8]</bitRange>
              <access>read-write</access>
              <enumeratedValues />
            </field>
            <field>
              <name>TXBE</name>
              <description>TXBE  field description</description>
              <bitRange>[1:1]</bitRange>
              <access>read-write</access>
              <enumeratedValues />
            </field>
            <field>
              <name>TXSE</name>
              <description>TXSE  field description</description>
              <bitRange>[0:0]</bitRange>
              <access>read-write</access>
              <enumeratedValues />
            </field>
          </fields>
        </register>
        <register>
          <name>RXBUF</name>
          <description>UART3 Receive Buffer</description>
          <addressOffset>0x10</addressOffset>
          <size>32</size>
          <access>read-write</access>
          <resetValue />
          <fields>
            <field>
              <name>RXBUF</name>
              <description>RXBUF  field description</description>
              <bitRange>[8:0]</bitRange>
              <access>read-only</access>
              <enumeratedValues />
            </field>
          </fields>
        </register>
        <register>
          <name>TXBUF</name>
          <description>UART3Transmit Buffer</description>
          <addressOffset>0x14</addressOffset>
          <size>32</size>
          <access>read-write</access>
          <resetValue />
          <fields>
            <field>
              <name>TXBUF</name>
              <description>TXBUF  field description</description>
              <bitRange>[8:0]</bitRange>
              <access>read-write</access>
              <enumeratedValues />
            </field>
          </fields>
        </register>
        <register>
          <name>BGR</name>
          <description>UART3 Baud rate Generator Register</description>
          <addressOffset>0x18</addressOffset>
          <size>32</size>
          <access>read-write</access>
          <resetValue>0x00000341</resetValue>
          <fields>
            <field>
              <name>SPBRG</name>
              <description>SPBRG  field description</description>
              <bitRange>[15:0]</bitRange>
              <access>read-write</access>
              <enumeratedValues />
            </field>
          </fields>
        </register>
      </registers>
    </peripheral>
    <peripheral>
      <name>UART4</name>
      <description>UART4 module information</description>
      <groupName>UART</groupName>
      <baseAddress>0x40017400</baseAddress>
      <size>32</size>
      <access>read-write</access>
      <addressBlock>
        <offset>0</offset>
        <size>0x1c</size>
        <usage>registers</usage>
      </addressBlock>
      <registers>
        <register>
          <name>CSR</name>
          <description>UART4 Control Status Register</description>
          <addressOffset>0x0</addressOffset>
          <size>32</size>
          <access>read-write</access>
          <resetValue>0x00000000</resetValue>
          <fields>
            <field>
              <name>BUSY</name>
              <description>BUSY  field description</description>
              <bitRange>[24:24]</bitRange>
              <access>read-only</access>
              <enumeratedValues>
                <enumeratedValue>
                  <name />
                  <description>UART正在通信中</description>
                  <value>1</value>
                </enumeratedValue>
                <enumeratedValue>
                  <name />
                  <description>UART空闲</description>
                  <value>0</value>
                </enumeratedValue>
              </enumeratedValues>
            </field>
            <field>
              <name>TXIREN</name>
              <description>TXIREN  field description</description>
              <bitRange>[17:17]</bitRange>
              <access>read-write</access>
              <enumeratedValues>
                <enumeratedValue>
                  <name />
                  <description>使能红外调制发送</description>
                  <value>1</value>
                </enumeratedValue>
                <enumeratedValue>
                  <name />
                  <description>关闭红外调制发送</description>
                  <value>0</value>
                </enumeratedValue>
              </enumeratedValues>
            </field>
            <field>
              <name>RXTOEN</name>
              <description>RXTOEN  field description</description>
              <bitRange>[16:16]</bitRange>
              <access>read-write</access>
              <enumeratedValues>
                <enumeratedValue>
                  <name />
                  <description>使能接收超时功能</description>
                  <value>1</value>
                </enumeratedValue>
                <enumeratedValue>
                  <name />
                  <description>关闭接收超时功能</description>
                  <value>0</value>
                </enumeratedValue>
              </enumeratedValues>
            </field>
            <field>
              <name>IOSWAP</name>
              <description>IOSWAP  field description</description>
              <bitRange>[12:12]</bitRange>
              <access>read-write</access>
              <enumeratedValues>
                <enumeratedValue>
                  <name />
                  <description>默认引脚顺序（与封装图一致）</description>
                  <value>0</value>
                </enumeratedValue>
                <enumeratedValue>
                  <name />
                  <description>交换引脚顺序</description>
                  <value>1</value>
                </enumeratedValue>
              </enumeratedValues>
            </field>
            <field>
              <name>DMATXIFCFG</name>
              <description>DMATXIFCFG  field description</description>
              <bitRange>[10:10]</bitRange>
              <access>read-write</access>
              <enumeratedValues>
                <enumeratedValue>
                  <name />
                  <description>IE=1的情况下，DMA模式下发送完最后一帧后，允许中断信号输出；最后一帧之前的数据帧发送完成后不允许中断信号输出</description>
                  <value>1</value>
                </enumeratedValue>
                <enumeratedValue>
                  <name />
                  <description>是否允许中断信号输出仅由IE决定</description>
                  <value>0</value>
                </enumeratedValue>
              </enumeratedValues>
            </field>
            <field>
              <name>BITORD</name>
              <description>BITORD  field description</description>
              <bitRange>[9:9]</bitRange>
              <access>read-write</access>
              <enumeratedValues>
                <enumeratedValue>
                  <name />
                  <description>LSB first</description>
                  <value>0</value>
                </enumeratedValue>
                <enumeratedValue>
                  <name />
                  <description>MSB first</description>
                  <value>1</value>
                </enumeratedValue>
              </enumeratedValues>
            </field>
            <field>
              <name>STOPCFG</name>
              <description>STOPCFG  field description</description>
              <bitRange>[8:8]</bitRange>
              <access>read-write</access>
              <enumeratedValues>
                <enumeratedValue>
                  <name />
                  <description>1位停止位</description>
                  <value>0</value>
                </enumeratedValue>
                <enumeratedValue>
                  <name />
                  <description>2位停止位</description>
                  <value>1</value>
                </enumeratedValue>
              </enumeratedValues>
            </field>
            <field>
              <name>PDSEL</name>
              <description>PDSEL  field description</description>
              <bitRange>[7:6]</bitRange>
              <access>read-write</access>
              <enumeratedValues>
                <enumeratedValue>
                  <name />
                  <description>7位数据</description>
                  <value>0</value>
                </enumeratedValue>
                <enumeratedValue>
                  <name />
                  <description>8位数据</description>
                  <value>1</value>
                </enumeratedValue>
                <enumeratedValue>
                  <name />
                  <description>9位数据</description>
                  <value>2</value>
                </enumeratedValue>
                <enumeratedValue>
                  <name />
                  <description>6位数据</description>
                  <value>3</value>
                </enumeratedValue>
              </enumeratedValues>
            </field>
            <field>
              <name>PARITY</name>
              <description>PARITY  field description</description>
              <bitRange>[5:4]</bitRange>
              <access>read-write</access>
              <enumeratedValues>
                <enumeratedValue>
                  <name />
                  <description>无校验位</description>
                  <value>0</value>
                </enumeratedValue>
                <enumeratedValue>
                  <name />
                  <description>偶校验</description>
                  <value>1</value>
                </enumeratedValue>
                <enumeratedValue>
                  <name />
                  <description>奇校验</description>
                  <value>2</value>
                </enumeratedValue>
                <enumeratedValue>
                  <name />
                  <description>RFU</description>
                  <value>3</value>
                </enumeratedValue>
              </enumeratedValues>
            </field>
            <field>
              <name>RXPOL</name>
              <description>RXPOL  field description</description>
              <bitRange>[3:3]</bitRange>
              <access>read-write</access>
              <enumeratedValues>
                <enumeratedValue>
                  <name />
                  <description>正向</description>
                  <value>0</value>
                </enumeratedValue>
                <enumeratedValue>
                  <name />
                  <description>取反</description>
                  <value>1</value>
                </enumeratedValue>
              </enumeratedValues>
            </field>
            <field>
              <name>TXPOL</name>
              <description>TXPOL  field description</description>
              <bitRange>[2:2]</bitRange>
              <access>read-write</access>
              <enumeratedValues>
                <enumeratedValue>
                  <name />
                  <description>正向</description>
                  <value>0</value>
                </enumeratedValue>
                <enumeratedValue>
                  <name />
                  <description>取反</description>
                  <value>1</value>
                </enumeratedValue>
              </enumeratedValues>
            </field>
            <field>
              <name>RXEN</name>
              <description>RXEN  field description</description>
              <bitRange>[1:1]</bitRange>
              <access>read-write</access>
              <enumeratedValues />
            </field>
            <field>
              <name>TXEN</name>
              <description>TXEN  field description</description>
              <bitRange>[0:0]</bitRange>
              <access>read-write</access>
              <enumeratedValues />
            </field>
          </fields>
        </register>
        <register>
          <name>IER</name>
          <description>UART4 Interrupt Enable Register</description>
          <addressOffset>0x4</addressOffset>
          <size>32</size>
          <access>read-write</access>
          <resetValue>0x00000000</resetValue>
          <fields>
            <field>
              <name>RXTO_IE</name>
              <description>RXTO_IE  field description</description>
              <bitRange>[11:11]</bitRange>
              <access>read-write</access>
              <enumeratedValues />
            </field>
            <field>
              <name>RXERR_IE</name>
              <description>RXERR_IE  field description</description>
              <bitRange>[10:10]</bitRange>
              <access>read-write</access>
              <enumeratedValues />
            </field>
            <field>
              <name>RXBF_IE</name>
              <description>RXBF_IE  field description</description>
              <bitRange>[8:8]</bitRange>
              <access>read-write</access>
              <enumeratedValues />
            </field>
            <field>
              <name>TXBE_IE</name>
              <description>TXBE_IE  field description</description>
              <bitRange>[1:1]</bitRange>
              <access>read-write</access>
              <enumeratedValues />
            </field>
            <field>
              <name>TXSE_IE</name>
              <description>TXSE_IE  field description</description>
              <bitRange>[0:0]</bitRange>
              <access>read-write</access>
              <enumeratedValues />
            </field>
          </fields>
        </register>
        <register>
          <name>ISR</name>
          <description>UART4 Interrupt Status Register</description>
          <addressOffset>0x8</addressOffset>
          <size>32</size>
          <access>read-write</access>
          <resetValue>0x00000000</resetValue>
          <fields>
            <field>
              <name>PERR</name>
              <description>PERR  field description</description>
              <bitRange>[18:18]</bitRange>
              <access>read-write</access>
              <enumeratedValues />
            </field>
            <field>
              <name>FERR</name>
              <description>FERR  field description</description>
              <bitRange>[17:17]</bitRange>
              <access>read-write</access>
              <enumeratedValues />
            </field>
            <field>
              <name>OERR</name>
              <description>OERR  field description</description>
              <bitRange>[16:16]</bitRange>
              <access>read-write</access>
              <enumeratedValues />
            </field>
            <field>
              <name>RXTO</name>
              <description>RXTO  field description</description>
              <bitRange>[11:11]</bitRange>
              <access>read-write</access>
              <enumeratedValues />
            </field>
            <field>
              <name>RXBF</name>
              <description>RXBF  field description</description>
              <bitRange>[8:8]</bitRange>
              <access>read-write</access>
              <enumeratedValues />
            </field>
            <field>
              <name>TXBE</name>
              <description>TXBE  field description</description>
              <bitRange>[1:1]</bitRange>
              <access>read-write</access>
              <enumeratedValues />
            </field>
            <field>
              <name>TXSE</name>
              <description>TXSE  field description</description>
              <bitRange>[0:0]</bitRange>
              <access>read-write</access>
              <enumeratedValues />
            </field>
          </fields>
        </register>
        <register>
          <name>RXBUF</name>
          <description>UART4 Receive Buffer</description>
          <addressOffset>0x10</addressOffset>
          <size>32</size>
          <access>read-write</access>
          <resetValue />
          <fields>
            <field>
              <name>RXBUF</name>
              <description>RXBUF  field description</description>
              <bitRange>[8:0]</bitRange>
              <access>read-only</access>
              <enumeratedValues />
            </field>
          </fields>
        </register>
        <register>
          <name>TXBUF</name>
          <description>UART4 Transmit Buffer</description>
          <addressOffset>0x14</addressOffset>
          <size>32</size>
          <access>read-write</access>
          <resetValue />
          <fields>
            <field>
              <name>TXBUF</name>
              <description>TXBUF  field description</description>
              <bitRange>[8:0]</bitRange>
              <access>read-write</access>
              <enumeratedValues />
            </field>
          </fields>
        </register>
        <register>
          <name>BGR</name>
          <description>UART4 Baud rate Generator Register</description>
          <addressOffset>0x18</addressOffset>
          <size>32</size>
          <access>read-write</access>
          <resetValue>0x00000341</resetValue>
          <fields>
            <field>
              <name>SPBRG</name>
              <description>SPBRG  field description</description>
              <bitRange>[15:0]</bitRange>
              <access>read-write</access>
              <enumeratedValues />
            </field>
          </fields>
        </register>
      </registers>
    </peripheral>
    <peripheral>
      <name>UART5</name>
      <description>UART5 module information</description>
      <groupName>UART</groupName>
      <baseAddress>0x40017800</baseAddress>
      <size>32</size>
      <access>read-write</access>
      <addressBlock>
        <offset>0</offset>
        <size>0x1c</size>
        <usage>registers</usage>
      </addressBlock>
      <registers>
        <register>
          <name>CSR</name>
          <description>UART5 Control Status Register</description>
          <addressOffset>0x0</addressOffset>
          <size>32</size>
          <access>read-write</access>
          <resetValue>0x00000000</resetValue>
          <fields>
            <field>
              <name>BUSY</name>
              <description>BUSY  field description</description>
              <bitRange>[24:24]</bitRange>
              <access>read-only</access>
              <enumeratedValues>
                <enumeratedValue>
                  <name />
                  <description>UART正在通信中</description>
                  <value>1</value>
                </enumeratedValue>
                <enumeratedValue>
                  <name />
                  <description>UART空闲</description>
                  <value>0</value>
                </enumeratedValue>
              </enumeratedValues>
            </field>
            <field>
              <name>TXIREN</name>
              <description>TXIREN  field description</description>
              <bitRange>[17:17]</bitRange>
              <access>read-write</access>
              <enumeratedValues>
                <enumeratedValue>
                  <name />
                  <description>使能红外调制发送</description>
                  <value>1</value>
                </enumeratedValue>
                <enumeratedValue>
                  <name />
                  <description>关闭红外调制发送</description>
                  <value>0</value>
                </enumeratedValue>
              </enumeratedValues>
            </field>
            <field>
              <name>RXTOEN</name>
              <description>RXTOEN  field description</description>
              <bitRange>[16:16]</bitRange>
              <access>read-write</access>
              <enumeratedValues>
                <enumeratedValue>
                  <name />
                  <description>使能接收超时功能</description>
                  <value>1</value>
                </enumeratedValue>
                <enumeratedValue>
                  <name />
                  <description>关闭接收超时功能</description>
                  <value>0</value>
                </enumeratedValue>
              </enumeratedValues>
            </field>
            <field>
              <name>IOSWAP</name>
              <description>IOSWAP  field description</description>
              <bitRange>[12:12]</bitRange>
              <access>read-write</access>
              <enumeratedValues>
                <enumeratedValue>
                  <name />
                  <description>默认引脚顺序（与封装图一致）</description>
                  <value>0</value>
                </enumeratedValue>
                <enumeratedValue>
                  <name />
                  <description>交换引脚顺序</description>
                  <value>1</value>
                </enumeratedValue>
              </enumeratedValues>
            </field>
            <field>
              <name>DMATXIFCFG</name>
              <description>DMATXIFCFG  field description</description>
              <bitRange>[10:10]</bitRange>
              <access>read-write</access>
              <enumeratedValues>
                <enumeratedValue>
                  <name />
                  <description>IE=1的情况下，DMA模式下发送完最后一帧后，允许中断信号输出；最后一帧之前的数据帧发送完成后不允许中断信号输出</description>
                  <value>1</value>
                </enumeratedValue>
                <enumeratedValue>
                  <name />
                  <description>是否允许中断信号输出仅由IE决定</description>
                  <value>0</value>
                </enumeratedValue>
              </enumeratedValues>
            </field>
            <field>
              <name>BITORD</name>
              <description>BITORD  field description</description>
              <bitRange>[9:9]</bitRange>
              <access>read-write</access>
              <enumeratedValues>
                <enumeratedValue>
                  <name />
                  <description>LSB first</description>
                  <value>0</value>
                </enumeratedValue>
                <enumeratedValue>
                  <name />
                  <description>MSB first</description>
                  <value>1</value>
                </enumeratedValue>
              </enumeratedValues>
            </field>
            <field>
              <name>STOPCFG</name>
              <description>STOPCFG  field description</description>
              <bitRange>[8:8]</bitRange>
              <access>read-write</access>
              <enumeratedValues>
                <enumeratedValue>
                  <name />
                  <description>1位停止位</description>
                  <value>0</value>
                </enumeratedValue>
                <enumeratedValue>
                  <name />
                  <description>2位停止位</description>
                  <value>1</value>
                </enumeratedValue>
              </enumeratedValues>
            </field>
            <field>
              <name>PDSEL</name>
              <description>PDSEL  field description</description>
              <bitRange>[7:6]</bitRange>
              <access>read-write</access>
              <enumeratedValues>
                <enumeratedValue>
                  <name />
                  <description>7位数据</description>
                  <value>0</value>
                </enumeratedValue>
                <enumeratedValue>
                  <name />
                  <description>8位数据</description>
                  <value>1</value>
                </enumeratedValue>
                <enumeratedValue>
                  <name />
                  <description>9位数据</description>
                  <value>2</value>
                </enumeratedValue>
                <enumeratedValue>
                  <name />
                  <description>6位数据</description>
                  <value>3</value>
                </enumeratedValue>
              </enumeratedValues>
            </field>
            <field>
              <name>PARITY</name>
              <description>PARITY  field description</description>
              <bitRange>[5:4]</bitRange>
              <access>read-write</access>
              <enumeratedValues>
                <enumeratedValue>
                  <name />
                  <description>无校验位</description>
                  <value>0</value>
                </enumeratedValue>
                <enumeratedValue>
                  <name />
                  <description>偶校验</description>
                  <value>1</value>
                </enumeratedValue>
                <enumeratedValue>
                  <name />
                  <description>奇校验</description>
                  <value>2</value>
                </enumeratedValue>
                <enumeratedValue>
                  <name />
                  <description>RFU</description>
                  <value>3</value>
                </enumeratedValue>
              </enumeratedValues>
            </field>
            <field>
              <name>RXPOL</name>
              <description>RXPOL  field description</description>
              <bitRange>[3:3]</bitRange>
              <access>read-write</access>
              <enumeratedValues>
                <enumeratedValue>
                  <name />
                  <description>正向</description>
                  <value>0</value>
                </enumeratedValue>
                <enumeratedValue>
                  <name />
                  <description>取反</description>
                  <value>1</value>
                </enumeratedValue>
              </enumeratedValues>
            </field>
            <field>
              <name>TXPOL</name>
              <description>TXPOL  field description</description>
              <bitRange>[2:2]</bitRange>
              <access>read-write</access>
              <enumeratedValues>
                <enumeratedValue>
                  <name />
                  <description>正向</description>
                  <value>0</value>
                </enumeratedValue>
                <enumeratedValue>
                  <name />
                  <description>取反</description>
                  <value>1</value>
                </enumeratedValue>
              </enumeratedValues>
            </field>
            <field>
              <name>RXEN</name>
              <description>RXEN  field description</description>
              <bitRange>[1:1]</bitRange>
              <access>read-write</access>
              <enumeratedValues />
            </field>
            <field>
              <name>TXEN</name>
              <description>TXEN  field description</description>
              <bitRange>[0:0]</bitRange>
              <access>read-write</access>
              <enumeratedValues />
            </field>
          </fields>
        </register>
        <register>
          <name>IER</name>
          <description>UART5 Interrupt Enable Register</description>
          <addressOffset>0x4</addressOffset>
          <size>32</size>
          <access>read-write</access>
          <resetValue>0x00000000</resetValue>
          <fields>
            <field>
              <name>RXTO_IE</name>
              <description>RXTO_IE  field description</description>
              <bitRange>[11:11]</bitRange>
              <access>read-write</access>
              <enumeratedValues />
            </field>
            <field>
              <name>RXERR_IE</name>
              <description>RXERR_IE  field description</description>
              <bitRange>[10:10]</bitRange>
              <access>read-write</access>
              <enumeratedValues />
            </field>
            <field>
              <name>RXBF_IE</name>
              <description>RXBF_IE  field description</description>
              <bitRange>[8:8]</bitRange>
              <access>read-write</access>
              <enumeratedValues />
            </field>
            <field>
              <name>TXBE_IE</name>
              <description>TXBE_IE  field description</description>
              <bitRange>[1:1]</bitRange>
              <access>read-write</access>
              <enumeratedValues />
            </field>
            <field>
              <name>TXSE_IE</name>
              <description>TXSE_IE  field description</description>
              <bitRange>[0:0]</bitRange>
              <access>read-write</access>
              <enumeratedValues />
            </field>
          </fields>
        </register>
        <register>
          <name>ISR</name>
          <description>UART5 Interrupt Status Register</description>
          <addressOffset>0x8</addressOffset>
          <size>32</size>
          <access>read-write</access>
          <resetValue>0x00000000</resetValue>
          <fields>
            <field>
              <name>PERR</name>
              <description>PERR  field description</description>
              <bitRange>[18:18]</bitRange>
              <access>read-write</access>
              <enumeratedValues />
            </field>
            <field>
              <name>FERR</name>
              <description>FERR  field description</description>
              <bitRange>[17:17]</bitRange>
              <access>read-write</access>
              <enumeratedValues />
            </field>
            <field>
              <name>OERR</name>
              <description>OERR  field description</description>
              <bitRange>[16:16]</bitRange>
              <access>read-write</access>
              <enumeratedValues />
            </field>
            <field>
              <name>RXTO</name>
              <description>RXTO  field description</description>
              <bitRange>[11:11]</bitRange>
              <access>read-write</access>
              <enumeratedValues />
            </field>
            <field>
              <name>RXBF</name>
              <description>RXBF  field description</description>
              <bitRange>[8:8]</bitRange>
              <access>read-write</access>
              <enumeratedValues />
            </field>
            <field>
              <name>TXBE</name>
              <description>TXBE  field description</description>
              <bitRange>[1:1]</bitRange>
              <access>read-write</access>
              <enumeratedValues />
            </field>
            <field>
              <name>TXSE</name>
              <description>TXSE  field description</description>
              <bitRange>[0:0]</bitRange>
              <access>read-write</access>
              <enumeratedValues />
            </field>
          </fields>
        </register>
        <register>
          <name>RXBUF</name>
          <description>UART5 Receive Buffer</description>
          <addressOffset>0x10</addressOffset>
          <size>32</size>
          <access>read-write</access>
          <resetValue />
          <fields>
            <field>
              <name>RXBUF</name>
              <description>RXBUF  field description</description>
              <bitRange>[8:0]</bitRange>
              <access>read-only</access>
              <enumeratedValues />
            </field>
          </fields>
        </register>
        <register>
          <name>TXBUF</name>
          <description>UART5 Transmit Buffer</description>
          <addressOffset>0x14</addressOffset>
          <size>32</size>
          <access>read-write</access>
          <resetValue />
          <fields>
            <field>
              <name>TXBUF</name>
              <description>TXBUF  field description</description>
              <bitRange>[8:0]</bitRange>
              <access>read-write</access>
              <enumeratedValues />
            </field>
          </fields>
        </register>
        <register>
          <name>BGR</name>
          <description>UART5 Baud rate Generator Register</description>
          <addressOffset>0x18</addressOffset>
          <size>32</size>
          <access>read-write</access>
          <resetValue>0x00000341</resetValue>
          <fields>
            <field>
              <name>SPBRG</name>
              <description>SPBRG  field description</description>
              <bitRange>[15:0]</bitRange>
              <access>read-write</access>
              <enumeratedValues />
            </field>
          </fields>
        </register>
      </registers>
    </peripheral>
    <peripheral>
      <name>LPUART0</name>
      <description>LPUART0 module information</description>
      <groupName>LPUART</groupName>
      <baseAddress>0x40014000</baseAddress>
      <size>32</size>
      <access>read-write</access>
      <addressBlock>
        <offset>0</offset>
        <size>0x1c</size>
        <usage>registers</usage>
      </addressBlock>
      <registers>
        <register>
          <name>CSR</name>
          <description>LPUART0 Control Status Register</description>
          <addressOffset>0x0</addressOffset>
          <size>32</size>
          <access>read-write</access>
          <resetValue>0x00000000</resetValue>
          <fields>
            <field>
              <name>BUSY</name>
              <description>BUSY  field description</description>
              <bitRange>[24:24]</bitRange>
              <access>read-only</access>
              <enumeratedValues>
                <enumeratedValue>
                  <name />
                  <description>LPUART正在通信中</description>
                  <value>1</value>
                </enumeratedValue>
                <enumeratedValue>
                  <name />
                  <description>LPUART空闲</description>
                  <value>0</value>
                </enumeratedValue>
              </enumeratedValues>
            </field>
            <field>
              <name>WKBYTECFG</name>
              <description>WKBYTECFG  field description</description>
              <bitRange>[19:19]</bitRange>
              <access>read-write</access>
              <enumeratedValues>
                <enumeratedValue>
                  <name />
                  <description>接收完1字节，并且奇偶校验和STOP位都正确，才触发唤醒中断</description>
                  <value>1</value>
                </enumeratedValue>
                <enumeratedValue>
                  <name />
                  <description>接收完1字节，不检查校验位和STOP位，直接触发唤醒中断</description>
                  <value>0</value>
                </enumeratedValue>
              </enumeratedValues>
            </field>
            <field>
              <name>RXEV</name>
              <description>RXEV  field description</description>
              <bitRange>[17:16]</bitRange>
              <access>read-write</access>
              <enumeratedValues>
                <enumeratedValue>
                  <name />
                  <description>START位检测唤醒</description>
                  <value>0</value>
                </enumeratedValue>
                <enumeratedValue>
                  <name />
                  <description>1byte数据接收完成</description>
                  <value>1</value>
                </enumeratedValue>
                <enumeratedValue>
                  <name />
                  <description>接收数据匹配成功</description>
                  <value>2</value>
                </enumeratedValue>
                <enumeratedValue>
                  <name />
                  <description>RXD下降沿检测</description>
                  <value>3</value>
                </enumeratedValue>
              </enumeratedValues>
            </field>
            <field>
              <name>DMATXIFCFG</name>
              <description>DMATXIFCFG  field description</description>
              <bitRange>[10:10]</bitRange>
              <access>read-write</access>
              <enumeratedValues>
                <enumeratedValue>
                  <name />
                  <description>IE=1的情况下，DMA模式下发送完最后一帧后，允许中断信号输出；最后一帧之前的数据帧发送完成后不允许中断信号输出</description>
                  <value>1</value>
                </enumeratedValue>
                <enumeratedValue>
                  <name />
                  <description>是否允许中断信号输出仅由IE决定</description>
                  <value>0</value>
                </enumeratedValue>
              </enumeratedValues>
            </field>
            <field>
              <name>BITORD</name>
              <description>BITORD  field description</description>
              <bitRange>[9:9]</bitRange>
              <access>read-write</access>
              <enumeratedValues>
                <enumeratedValue>
                  <name />
                  <description>LSB first</description>
                  <value>0</value>
                </enumeratedValue>
                <enumeratedValue>
                  <name />
                  <description>MSB first</description>
                  <value>1</value>
                </enumeratedValue>
              </enumeratedValues>
            </field>
            <field>
              <name>STOPCFG</name>
              <description>STOPCFG  field description</description>
              <bitRange>[8:8]</bitRange>
              <access>read-write</access>
              <enumeratedValues>
                <enumeratedValue>
                  <name />
                  <description>1位停止位</description>
                  <value>0</value>
                </enumeratedValue>
                <enumeratedValue>
                  <name />
                  <description>2位停止位</description>
                  <value>1</value>
                </enumeratedValue>
              </enumeratedValues>
            </field>
            <field>
              <name>PDSEL</name>
              <description>PDSEL  field description</description>
              <bitRange>[7:6]</bitRange>
              <access>read-write</access>
              <enumeratedValues>
                <enumeratedValue>
                  <name />
                  <description>7位数据</description>
                  <value>0</value>
                </enumeratedValue>
                <enumeratedValue>
                  <name />
                  <description>8位数据</description>
                  <value>1</value>
                </enumeratedValue>
                <enumeratedValue>
                  <name />
                  <description>9位数据</description>
                  <value>2</value>
                </enumeratedValue>
                <enumeratedValue>
                  <name />
                  <description>6位数据</description>
                  <value>3</value>
                </enumeratedValue>
              </enumeratedValues>
            </field>
            <field>
              <name>PARITY</name>
              <description>PARITY  field description</description>
              <bitRange>[5:4]</bitRange>
              <access>read-write</access>
              <enumeratedValues>
                <enumeratedValue>
                  <name />
                  <description>无校验位</description>
                  <value>0</value>
                </enumeratedValue>
                <enumeratedValue>
                  <name />
                  <description>偶校验</description>
                  <value>1</value>
                </enumeratedValue>
                <enumeratedValue>
                  <name />
                  <description>奇校验</description>
                  <value>2</value>
                </enumeratedValue>
                <enumeratedValue>
                  <name />
                  <description>RFU</description>
                  <value>3</value>
                </enumeratedValue>
              </enumeratedValues>
            </field>
            <field>
              <name>RXPOL</name>
              <description>RXPOL  field description</description>
              <bitRange>[3:3]</bitRange>
              <access>read-write</access>
              <enumeratedValues>
                <enumeratedValue>
                  <name />
                  <description>正向</description>
                  <value>0</value>
                </enumeratedValue>
                <enumeratedValue>
                  <name />
                  <description>取反</description>
                  <value>1</value>
                </enumeratedValue>
              </enumeratedValues>
            </field>
            <field>
              <name>TXPOL</name>
              <description>TXPOL  field description</description>
              <bitRange>[2:2]</bitRange>
              <access>read-write</access>
              <enumeratedValues>
                <enumeratedValue>
                  <name />
                  <description>正向</description>
                  <value>0</value>
                </enumeratedValue>
                <enumeratedValue>
                  <name />
                  <description>取反</description>
                  <value>1</value>
                </enumeratedValue>
              </enumeratedValues>
            </field>
            <field>
              <name>RXEN</name>
              <description>RXEN  field description</description>
              <bitRange>[1:1]</bitRange>
              <access>read-write</access>
              <enumeratedValues />
            </field>
            <field>
              <name>TXEN</name>
              <description>TXEN  field description</description>
              <bitRange>[0:0]</bitRange>
              <access>read-write</access>
              <enumeratedValues />
            </field>
          </fields>
        </register>
        <register>
          <name>IER</name>
          <description>LPUART0 Interrupt Enable Register</description>
          <addressOffset>0x4</addressOffset>
          <size>32</size>
          <access>read-write</access>
          <resetValue>0x00000000</resetValue>
          <fields>
            <field>
              <name>RXEV_IE</name>
              <description>RXEV_IE  field description</description>
              <bitRange>[12:12]</bitRange>
              <access>read-write</access>
              <enumeratedValues />
            </field>
            <field>
              <name>RXERR_IE</name>
              <description>RXERR_IE  field description</description>
              <bitRange>[10:10]</bitRange>
              <access>read-write</access>
              <enumeratedValues />
            </field>
            <field>
              <name>RXBF_IE</name>
              <description>RXBF_IE  field description</description>
              <bitRange>[8:8]</bitRange>
              <access>read-write</access>
              <enumeratedValues />
            </field>
            <field>
              <name>TXBE_IE</name>
              <description>TXBE_IE  field description</description>
              <bitRange>[1:1]</bitRange>
              <access>read-write</access>
              <enumeratedValues />
            </field>
            <field>
              <name>TXSE_IE</name>
              <description>TXSE_IE  field description</description>
              <bitRange>[0:0]</bitRange>
              <access>read-write</access>
              <enumeratedValues />
            </field>
          </fields>
        </register>
        <register>
          <name>ISR</name>
          <description>LPUART0 Interrupt Status Register</description>
          <addressOffset>0x8</addressOffset>
          <size>32</size>
          <access>read-write</access>
          <resetValue>0x00000002</resetValue>
          <fields>
            <field>
              <name>RXEVF</name>
              <description>RXEVF  field description</description>
              <bitRange>[24:24]</bitRange>
              <access>read-write</access>
              <enumeratedValues />
            </field>
            <field>
              <name>TXOV</name>
              <description>TXOV  field description</description>
              <bitRange>[19:19]</bitRange>
              <access>read-write</access>
              <enumeratedValues />
            </field>
            <field>
              <name>PERR</name>
              <description>PERR  field description</description>
              <bitRange>[18:18]</bitRange>
              <access>read-write</access>
              <enumeratedValues />
            </field>
            <field>
              <name>FERR</name>
              <description>FERR  field description</description>
              <bitRange>[17:17]</bitRange>
              <access>read-write</access>
              <enumeratedValues />
            </field>
            <field>
              <name>OERR</name>
              <description>OERR  field description</description>
              <bitRange>[16:16]</bitRange>
              <access>read-write</access>
              <enumeratedValues />
            </field>
            <field>
              <name>RXBF</name>
              <description>RXBF  field description</description>
              <bitRange>[8:8]</bitRange>
              <access>read-write</access>
              <enumeratedValues />
            </field>
            <field>
              <name>TXBE</name>
              <description>TXBE  field description</description>
              <bitRange>[1:1]</bitRange>
              <access>read-only</access>
              <enumeratedValues />
            </field>
            <field>
              <name>TXSE</name>
              <description>TXSE  field description</description>
              <bitRange>[0:0]</bitRange>
              <access>read-write</access>
              <enumeratedValues />
            </field>
          </fields>
        </register>
        <register>
          <name>BMR</name>
          <description>LPUART0 Baud rate Modulation Register</description>
          <addressOffset>0xc</addressOffset>
          <size>32</size>
          <access>read-write</access>
          <resetValue>0x00000000</resetValue>
          <fields>
            <field>
              <name>MCTL</name>
              <description>MCTL  field description</description>
              <bitRange>[28:16]</bitRange>
              <access>read-write</access>
              <enumeratedValues />
            </field>
            <field>
              <name>BAUD</name>
              <description>BAUD  field description</description>
              <bitRange>[2:0]</bitRange>
              <access>read-write</access>
              <enumeratedValues>
                <enumeratedValue>
                  <name />
                  <description>9600</description>
                  <value>0</value>
                </enumeratedValue>
                <enumeratedValue>
                  <name />
                  <description>4800</description>
                  <value>1</value>
                </enumeratedValue>
                <enumeratedValue>
                  <name />
                  <description>2400</description>
                  <value>2</value>
                </enumeratedValue>
                <enumeratedValue>
                  <name />
                  <description>1200</description>
                  <value>3</value>
                </enumeratedValue>
                <enumeratedValue>
                  <name />
                  <description>600</description>
                  <value>4</value>
                </enumeratedValue>
                <enumeratedValue>
                  <name />
                  <description>300</description>
                  <value>5</value>
                </enumeratedValue>
                <enumeratedValue>
                  <name />
                  <description>300</description>
                  <value>6</value>
                </enumeratedValue>
                <enumeratedValue>
                  <name />
                  <description>300</description>
                  <value>7</value>
                </enumeratedValue>
              </enumeratedValues>
            </field>
          </fields>
        </register>
        <register>
          <name>RXBUF</name>
          <description>LPUART0 Receive Buffer Register</description>
          <addressOffset>0x10</addressOffset>
          <size>32</size>
          <access>read-write</access>
          <resetValue />
          <fields>
            <field>
              <name>RXBUF</name>
              <description>RXBUF  field description</description>
              <bitRange>[8:0]</bitRange>
              <access>read-only</access>
              <enumeratedValues />
            </field>
          </fields>
        </register>
        <register>
          <name>TXBUF</name>
          <description>LPUART0 Transmit Buffer Register</description>
          <addressOffset>0x14</addressOffset>
          <size>32</size>
          <access>read-write</access>
          <resetValue />
          <fields>
            <field>
              <name>TXBUF</name>
              <description>TXBUF  field description</description>
              <bitRange>[8:0]</bitRange>
              <access>read-write</access>
              <enumeratedValues />
            </field>
          </fields>
        </register>
        <register>
          <name>DMR</name>
          <description>LPUART0 data Matching Register</description>
          <addressOffset>0x18</addressOffset>
          <size>32</size>
          <access>read-write</access>
          <resetValue />
          <fields>
            <field>
              <name>MATD</name>
              <description>MATD  field description</description>
              <bitRange>[8:0]</bitRange>
              <access>read-write</access>
              <enumeratedValues />
            </field>
          </fields>
        </register>
      </registers>
    </peripheral>
    <peripheral>
      <name>LPUART1</name>
      <description>LPUART1 module information</description>
      <groupName>LPUART</groupName>
      <baseAddress>0x40014400</baseAddress>
      <size>32</size>
      <access>read-write</access>
      <addressBlock>
        <offset>0</offset>
        <size>0x1c</size>
        <usage>registers</usage>
      </addressBlock>
      <registers>
        <register>
          <name>CSR</name>
          <description>LPUART1 Control Status Register</description>
          <addressOffset>0x0</addressOffset>
          <size>32</size>
          <access>read-write</access>
          <resetValue>0x00000000</resetValue>
          <fields>
            <field>
              <name>BUSY</name>
              <description>BUSY  field description</description>
              <bitRange>[24:24]</bitRange>
              <access>read-only</access>
              <enumeratedValues>
                <enumeratedValue>
                  <name />
                  <description>LPUART正在通信中</description>
                  <value>1</value>
                </enumeratedValue>
                <enumeratedValue>
                  <name />
                  <description>LPUART空闲</description>
                  <value>0</value>
                </enumeratedValue>
              </enumeratedValues>
            </field>
            <field>
              <name>WKBYTECFG</name>
              <description>WKBYTECFG  field description</description>
              <bitRange>[19:19]</bitRange>
              <access>read-write</access>
              <enumeratedValues>
                <enumeratedValue>
                  <name />
                  <description>接收完1字节，并且奇偶校验和STOP位都正确，才触发唤醒中断</description>
                  <value>1</value>
                </enumeratedValue>
                <enumeratedValue>
                  <name />
                  <description>接收完1字节，不检查校验位和STOP位，直接触发唤醒中断</description>
                  <value>0</value>
                </enumeratedValue>
              </enumeratedValues>
            </field>
            <field>
              <name>RXEV</name>
              <description>RXEV  field description</description>
              <bitRange>[17:16]</bitRange>
              <access>read-write</access>
              <enumeratedValues>
                <enumeratedValue>
                  <name />
                  <description>START位检测唤醒</description>
                  <value>0</value>
                </enumeratedValue>
                <enumeratedValue>
                  <name />
                  <description>1byte数据接收完成</description>
                  <value>1</value>
                </enumeratedValue>
                <enumeratedValue>
                  <name />
                  <description>接收数据匹配成功</description>
                  <value>2</value>
                </enumeratedValue>
                <enumeratedValue>
                  <name />
                  <description>RXD下降沿检测</description>
                  <value>3</value>
                </enumeratedValue>
              </enumeratedValues>
            </field>
            <field>
              <name>DMATXIFCFG</name>
              <description>DMATXIFCFG  field description</description>
              <bitRange>[10:10]</bitRange>
              <access>read-write</access>
              <enumeratedValues>
                <enumeratedValue>
                  <name />
                  <description>IE=1的情况下，DMA模式下发送完最后一帧后，允许中断信号输出；最后一帧之前的数据帧发送完成后不允许中断信号输出</description>
                  <value>1</value>
                </enumeratedValue>
                <enumeratedValue>
                  <name />
                  <description>是否允许中断信号输出仅由IE决定</description>
                  <value>0</value>
                </enumeratedValue>
              </enumeratedValues>
            </field>
            <field>
              <name>BITORD</name>
              <description>BITORD  field description</description>
              <bitRange>[9:9]</bitRange>
              <access>read-write</access>
              <enumeratedValues>
                <enumeratedValue>
                  <name />
                  <description>LSB first</description>
                  <value>0</value>
                </enumeratedValue>
                <enumeratedValue>
                  <name />
                  <description>MSB first</description>
                  <value>1</value>
                </enumeratedValue>
              </enumeratedValues>
            </field>
            <field>
              <name>STOPCFG</name>
              <description>STOPCFG  field description</description>
              <bitRange>[8:8]</bitRange>
              <access>read-write</access>
              <enumeratedValues>
                <enumeratedValue>
                  <name />
                  <description>1位停止位</description>
                  <value>0</value>
                </enumeratedValue>
                <enumeratedValue>
                  <name />
                  <description>2位停止位</description>
                  <value>1</value>
                </enumeratedValue>
              </enumeratedValues>
            </field>
            <field>
              <name>PDSEL</name>
              <description>PDSEL  field description</description>
              <bitRange>[7:6]</bitRange>
              <access>read-write</access>
              <enumeratedValues>
                <enumeratedValue>
                  <name />
                  <description>7位数据</description>
                  <value>0</value>
                </enumeratedValue>
                <enumeratedValue>
                  <name />
                  <description>8位数据</description>
                  <value>1</value>
                </enumeratedValue>
                <enumeratedValue>
                  <name />
                  <description>9位数据</description>
                  <value>2</value>
                </enumeratedValue>
                <enumeratedValue>
                  <name />
                  <description>6位数据</description>
                  <value>3</value>
                </enumeratedValue>
              </enumeratedValues>
            </field>
            <field>
              <name>PARITY</name>
              <description>PARITY  field description</description>
              <bitRange>[5:4]</bitRange>
              <access>read-write</access>
              <enumeratedValues>
                <enumeratedValue>
                  <name />
                  <description>无校验位</description>
                  <value>0</value>
                </enumeratedValue>
                <enumeratedValue>
                  <name />
                  <description>偶校验</description>
                  <value>1</value>
                </enumeratedValue>
                <enumeratedValue>
                  <name />
                  <description>奇校验</description>
                  <value>2</value>
                </enumeratedValue>
                <enumeratedValue>
                  <name />
                  <description>RFU</description>
                  <value>3</value>
                </enumeratedValue>
              </enumeratedValues>
            </field>
            <field>
              <name>RXPOL</name>
              <description>RXPOL  field description</description>
              <bitRange>[3:3]</bitRange>
              <access>read-write</access>
              <enumeratedValues>
                <enumeratedValue>
                  <name />
                  <description>正向</description>
                  <value>0</value>
                </enumeratedValue>
                <enumeratedValue>
                  <name />
                  <description>取反</description>
                  <value>1</value>
                </enumeratedValue>
              </enumeratedValues>
            </field>
            <field>
              <name>TXPOL</name>
              <description>TXPOL  field description</description>
              <bitRange>[2:2]</bitRange>
              <access>read-write</access>
              <enumeratedValues>
                <enumeratedValue>
                  <name />
                  <description>正向</description>
                  <value>0</value>
                </enumeratedValue>
                <enumeratedValue>
                  <name />
                  <description>取反</description>
                  <value>1</value>
                </enumeratedValue>
              </enumeratedValues>
            </field>
            <field>
              <name>RXEN</name>
              <description>RXEN  field description</description>
              <bitRange>[1:1]</bitRange>
              <access>read-write</access>
              <enumeratedValues />
            </field>
            <field>
              <name>TXEN</name>
              <description>TXEN  field description</description>
              <bitRange>[0:0]</bitRange>
              <access>read-write</access>
              <enumeratedValues />
            </field>
          </fields>
        </register>
        <register>
          <name>IER</name>
          <description>LPUART1 Interrupt Enable Register</description>
          <addressOffset>0x4</addressOffset>
          <size>32</size>
          <access>read-write</access>
          <resetValue>0x00000000</resetValue>
          <fields>
            <field>
              <name>RXEV_IE</name>
              <description>RXEV_IE  field description</description>
              <bitRange>[12:12]</bitRange>
              <access>read-write</access>
              <enumeratedValues />
            </field>
            <field>
              <name>RXERR_IE</name>
              <description>RXERR_IE  field description</description>
              <bitRange>[10:10]</bitRange>
              <access>read-write</access>
              <enumeratedValues />
            </field>
            <field>
              <name>RXBF_IE</name>
              <description>RXBF_IE  field description</description>
              <bitRange>[8:8]</bitRange>
              <access>read-write</access>
              <enumeratedValues />
            </field>
            <field>
              <name>TXBE_IE</name>
              <description>TXBE_IE  field description</description>
              <bitRange>[1:1]</bitRange>
              <access>read-write</access>
              <enumeratedValues />
            </field>
            <field>
              <name>TXSE_IE</name>
              <description>TXSE_IE  field description</description>
              <bitRange>[0:0]</bitRange>
              <access>read-write</access>
              <enumeratedValues />
            </field>
          </fields>
        </register>
        <register>
          <name>ISR</name>
          <description>LPUART1 Interrupt Status Register</description>
          <addressOffset>0x8</addressOffset>
          <size>32</size>
          <access>read-write</access>
          <resetValue>0x00000002</resetValue>
          <fields>
            <field>
              <name>RXEVF</name>
              <description>RXEVF  field description</description>
              <bitRange>[24:24]</bitRange>
              <access>read-write</access>
              <enumeratedValues />
            </field>
            <field>
              <name>TXOV</name>
              <description>TXOV  field description</description>
              <bitRange>[19:19]</bitRange>
              <access>read-write</access>
              <enumeratedValues />
            </field>
            <field>
              <name>PERR</name>
              <description>PERR  field description</description>
              <bitRange>[18:18]</bitRange>
              <access>read-write</access>
              <enumeratedValues />
            </field>
            <field>
              <name>FERR</name>
              <description>FERR  field description</description>
              <bitRange>[17:17]</bitRange>
              <access>read-write</access>
              <enumeratedValues />
            </field>
            <field>
              <name>OERR</name>
              <description>OERR  field description</description>
              <bitRange>[16:16]</bitRange>
              <access>read-write</access>
              <enumeratedValues />
            </field>
            <field>
              <name>RXBF</name>
              <description>RXBF  field description</description>
              <bitRange>[8:8]</bitRange>
              <access>read-write</access>
              <enumeratedValues />
            </field>
            <field>
              <name>TXBE</name>
              <description>TXBE  field description</description>
              <bitRange>[1:1]</bitRange>
              <access>read-only</access>
              <enumeratedValues />
            </field>
            <field>
              <name>TXSE</name>
              <description>TXSE  field description</description>
              <bitRange>[0:0]</bitRange>
              <access>read-write</access>
              <enumeratedValues />
            </field>
          </fields>
        </register>
        <register>
          <name>BMR</name>
          <description>LPUART1 Baud rate Modulation Register</description>
          <addressOffset>0xc</addressOffset>
          <size>32</size>
          <access>read-write</access>
          <resetValue>0x00000000</resetValue>
          <fields>
            <field>
              <name>MCTL</name>
              <description>MCTL  field description</description>
              <bitRange>[28:16]</bitRange>
              <access>read-write</access>
              <enumeratedValues />
            </field>
            <field>
              <name>BAUD</name>
              <description>BAUD  field description</description>
              <bitRange>[2:0]</bitRange>
              <access>read-write</access>
              <enumeratedValues>
                <enumeratedValue>
                  <name />
                  <description>9600</description>
                  <value>0</value>
                </enumeratedValue>
                <enumeratedValue>
                  <name />
                  <description>4800</description>
                  <value>1</value>
                </enumeratedValue>
                <enumeratedValue>
                  <name />
                  <description>2400</description>
                  <value>2</value>
                </enumeratedValue>
                <enumeratedValue>
                  <name />
                  <description>1200</description>
                  <value>3</value>
                </enumeratedValue>
                <enumeratedValue>
                  <name />
                  <description>600</description>
                  <value>4</value>
                </enumeratedValue>
                <enumeratedValue>
                  <name />
                  <description>300</description>
                  <value>5</value>
                </enumeratedValue>
                <enumeratedValue>
                  <name />
                  <description>300</description>
                  <value>6</value>
                </enumeratedValue>
                <enumeratedValue>
                  <name />
                  <description>300</description>
                  <value>7</value>
                </enumeratedValue>
              </enumeratedValues>
            </field>
          </fields>
        </register>
        <register>
          <name>RXBUF</name>
          <description>LPUART1 Receive Data Register</description>
          <addressOffset>0x10</addressOffset>
          <size>32</size>
          <access>read-write</access>
          <resetValue />
          <fields>
            <field>
              <name>RXBUF</name>
              <description>RXBUF  field description</description>
              <bitRange>[8:0]</bitRange>
              <access>read-only</access>
              <enumeratedValues />
            </field>
          </fields>
        </register>
        <register>
          <name>TXBUF</name>
          <description>LPUART1 Transmit Data Register</description>
          <addressOffset>0x14</addressOffset>
          <size>32</size>
          <access>read-write</access>
          <resetValue />
          <fields>
            <field>
              <name>TXBUF</name>
              <description>TXBUF  field description</description>
              <bitRange>[8:0]</bitRange>
              <access>read-write</access>
              <enumeratedValues />
            </field>
          </fields>
        </register>
        <register>
          <name>DMR</name>
          <description>LPUART1 data Matching Register</description>
          <addressOffset>0x18</addressOffset>
          <size>32</size>
          <access>read-write</access>
          <resetValue />
          <fields>
            <field>
              <name>MATD</name>
              <description>MATD  field description</description>
              <bitRange>[8:0]</bitRange>
              <access>read-write</access>
              <enumeratedValues />
            </field>
          </fields>
        </register>
      </registers>
    </peripheral>
    <peripheral>
      <name>SPI0</name>
      <description>SPI0 module information</description>
      <groupName>SPI</groupName>
      <baseAddress>0x40010400</baseAddress>
      <size>32</size>
      <access>read-write</access>
      <addressBlock>
        <offset>0</offset>
        <size>0x1c</size>
        <usage>registers</usage>
      </addressBlock>
      <registers>
        <register>
          <name>CR1</name>
          <description>SPI0 Control Register1</description>
          <addressOffset>0x0</addressOffset>
          <size>32</size>
          <access>read-write</access>
          <resetValue>0x00000100</resetValue>
          <fields>
            <field>
              <name>IOSWAP</name>
              <description>IOSWAP  field description</description>
              <bitRange>[11:11]</bitRange>
              <access>read-write</access>
              <enumeratedValues>
                <enumeratedValue>
                  <name />
                  <description>默认引脚顺序</description>
                  <value>0</value>
                </enumeratedValue>
                <enumeratedValue>
                  <name />
                  <description>交换引脚顺序</description>
                  <value>1</value>
                </enumeratedValue>
              </enumeratedValues>
            </field>
            <field>
              <name>MSPA</name>
              <description>MSPA  field description</description>
              <bitRange>[10:10]</bitRange>
              <access>read-write</access>
              <enumeratedValues>
                <enumeratedValue>
                  <name />
                  <description>采样点延迟半个SCK周期</description>
                  <value>1</value>
                </enumeratedValue>
                <enumeratedValue>
                  <name />
                  <description>不调整</description>
                  <value>0</value>
                </enumeratedValue>
              </enumeratedValues>
            </field>
            <field>
              <name>SSPA</name>
              <description>SSPA  field description</description>
              <bitRange>[9:9]</bitRange>
              <access>read-write</access>
              <enumeratedValues>
                <enumeratedValue>
                  <name />
                  <description>提前半个SCK周期发送</description>
                  <value>1</value>
                </enumeratedValue>
                <enumeratedValue>
                  <name />
                  <description>不调整</description>
                  <value>0</value>
                </enumeratedValue>
              </enumeratedValues>
            </field>
            <field>
              <name>MM</name>
              <description>MM  field description</description>
              <bitRange>[8:8]</bitRange>
              <access>read-write</access>
              <enumeratedValues />
            </field>
            <field>
              <name>WAIT</name>
              <description>WAIT  field description</description>
              <bitRange>[7:6]</bitRange>
              <access>read-write</access>
              <enumeratedValues />
            </field>
            <field>
              <name>BAUD</name>
              <description>BAUD  field description</description>
              <bitRange>[5:3]</bitRange>
              <access>read-write</access>
              <enumeratedValues />
            </field>
            <field>
              <name>LSBF</name>
              <description>LSBF  field description</description>
              <bitRange>[2:2]</bitRange>
              <access>read-write</access>
              <enumeratedValues />
            </field>
            <field>
              <name>CPHOL</name>
              <description>CPHOL  field description</description>
              <bitRange>[1:1]</bitRange>
              <access>read-write</access>
              <enumeratedValues />
            </field>
            <field>
              <name>CPHA</name>
              <description>CPHA  field description</description>
              <bitRange>[0:0]</bitRange>
              <access>read-write</access>
              <enumeratedValues />
            </field>
          </fields>
        </register>
        <register>
          <name>CR2</name>
          <description>SPI0 Control Register2</description>
          <addressOffset>0x4</addressOffset>
          <size>32</size>
          <access>read-write</access>
          <resetValue>0x00000054</resetValue>
          <fields>
            <field>
              <name>DUMMY_EN</name>
              <description>DUMMY_EN  field description</description>
              <bitRange>[15:15]</bitRange>
              <access>read-write</access>
              <enumeratedValues>
                <enumeratedValue>
                  <name />
                  <description>不插入dummy cycle</description>
                  <value>0</value>
                </enumeratedValue>
                <enumeratedValue>
                  <name />
                  <description>在读命令之后插入一个dummy cycle</description>
                  <value>1</value>
                </enumeratedValue>
              </enumeratedValues>
            </field>
            <field>
              <name>RXO</name>
              <description>RXO  field description</description>
              <bitRange>[11:11]</bitRange>
              <access>read-write</access>
              <enumeratedValues>
                <enumeratedValue>
                  <name />
                  <description>启动Master的单接收模式</description>
                  <value>1</value>
                </enumeratedValue>
                <enumeratedValue>
                  <name />
                  <description>关闭单接收模式（收发全双工）</description>
                  <value>0</value>
                </enumeratedValue>
              </enumeratedValues>
            </field>
            <field>
              <name>DLEN</name>
              <description>DLEN  field description</description>
              <bitRange>[10:9]</bitRange>
              <access>read-write</access>
              <enumeratedValues>
                <enumeratedValue>
                  <name />
                  <description>8bit</description>
                  <value>0</value>
                </enumeratedValue>
                <enumeratedValue>
                  <name />
                  <description>16bit</description>
                  <value>1</value>
                </enumeratedValue>
                <enumeratedValue>
                  <name />
                  <description>24bit</description>
                  <value>2</value>
                </enumeratedValue>
                <enumeratedValue>
                  <name />
                  <description>32bit</description>
                  <value>3</value>
                </enumeratedValue>
              </enumeratedValues>
            </field>
            <field>
              <name>HALFDUPLEX</name>
              <description>HALFDUPLEX  field description</description>
              <bitRange>[8:8]</bitRange>
              <access>read-write</access>
              <enumeratedValues>
                <enumeratedValue>
                  <name />
                  <description>标准SPI模式，4线全双工</description>
                  <value>0</value>
                </enumeratedValue>
                <enumeratedValue>
                  <name />
                  <description>DCN模式，4线半双工</description>
                  <value>1</value>
                </enumeratedValue>
              </enumeratedValues>
            </field>
            <field>
              <name>HD_RW</name>
              <description>HD_RW  field description</description>
              <bitRange>[7:7]</bitRange>
              <access>read-write</access>
              <enumeratedValues>
                <enumeratedValue>
                  <name />
                  <description>4线半双工协议下主机写入从机</description>
                  <value>0</value>
                </enumeratedValue>
                <enumeratedValue>
                  <name />
                  <description>4线半双工协议下主机读取从机</description>
                  <value>1</value>
                </enumeratedValue>
              </enumeratedValues>
            </field>
            <field>
              <name>CMD8b</name>
              <description>CMD8b  field description</description>
              <bitRange>[6:6]</bitRange>
              <access>read-write</access>
              <enumeratedValues>
                <enumeratedValue>
                  <name />
                  <description>command帧固定为8bit</description>
                  <value>1</value>
                </enumeratedValue>
                <enumeratedValue>
                  <name />
                  <description>command帧长度由DLEN定义</description>
                  <value>0</value>
                </enumeratedValue>
              </enumeratedValues>
            </field>
            <field>
              <name>SSNM</name>
              <description>SSNM  field description</description>
              <bitRange>[5:5]</bitRange>
              <access>read-write</access>
              <enumeratedValues>
                <enumeratedValue>
                  <name />
                  <description>每发送完一帧后Master拉高SSN，维持高电平时间由WAIT寄存器控制</description>
                  <value>1</value>
                </enumeratedValue>
                <enumeratedValue>
                  <name />
                  <description>每发送完一帧后Master保持SSN为低</description>
                  <value>0</value>
                </enumeratedValue>
              </enumeratedValues>
            </field>
            <field>
              <name>TXO_AC</name>
              <description>TXO_AC  field description</description>
              <bitRange>[4:4]</bitRange>
              <access>read-write</access>
              <enumeratedValues />
            </field>
            <field>
              <name>TXO</name>
              <description>TXO  field description</description>
              <bitRange>[3:3]</bitRange>
              <access>read-write</access>
              <enumeratedValues>
                <enumeratedValue>
                  <name />
                  <description>启动Master的单发送模式</description>
                  <value>1</value>
                </enumeratedValue>
                <enumeratedValue>
                  <name />
                  <description>关闭单发送模式（收发全双工）</description>
                  <value>0</value>
                </enumeratedValue>
              </enumeratedValues>
            </field>
            <field>
              <name>SSN</name>
              <description>SSN  field description</description>
              <bitRange>[2:2]</bitRange>
              <access>read-write</access>
              <enumeratedValues>
                <enumeratedValue>
                  <name />
                  <description>SSN输出高电平</description>
                  <value>1</value>
                </enumeratedValue>
                <enumeratedValue>
                  <name />
                  <description>SSN输出低电平</description>
                  <value>0</value>
                </enumeratedValue>
              </enumeratedValues>
            </field>
            <field>
              <name>SSNSEN</name>
              <description>SSNSEN  field description</description>
              <bitRange>[1:1]</bitRange>
              <access>read-write</access>
              <enumeratedValues>
                <enumeratedValue>
                  <name />
                  <description>Master模式下SSN输出由软件控制</description>
                  <value>1</value>
                </enumeratedValue>
                <enumeratedValue>
                  <name />
                  <description>Master模式下SSN输出由硬件自动控制</description>
                  <value>0</value>
                </enumeratedValue>
              </enumeratedValues>
            </field>
            <field>
              <name>SPIEN</name>
              <description>SPIEN  field description</description>
              <bitRange>[0:0]</bitRange>
              <access>read-write</access>
              <enumeratedValues />
            </field>
          </fields>
        </register>
        <register>
          <name>CR3</name>
          <description>SPI0 Control Register3</description>
          <addressOffset>0x8</addressOffset>
          <size>32</size>
          <access>read-write</access>
          <resetValue>0x00000000</resetValue>
          <fields>
            <field>
              <name>TXBFC</name>
              <description>TXBFC  field description</description>
              <bitRange>[3:3]</bitRange>
              <access>write-only</access>
              <enumeratedValues />
            </field>
            <field>
              <name>RXBFC</name>
              <description>RXBFC  field description</description>
              <bitRange>[2:2]</bitRange>
              <access>write-only</access>
              <enumeratedValues />
            </field>
            <field>
              <name>MERRC</name>
              <description>MERRC  field description</description>
              <bitRange>[1:1]</bitRange>
              <access>write-only</access>
              <enumeratedValues />
            </field>
            <field>
              <name>SERRC</name>
              <description>SERRC  field description</description>
              <bitRange>[0:0]</bitRange>
              <access>write-only</access>
              <enumeratedValues />
            </field>
          </fields>
        </register>
        <register>
          <name>IER</name>
          <description>SPI0 Interrupt Enable Register</description>
          <addressOffset>0xc</addressOffset>
          <size>32</size>
          <access>read-write</access>
          <resetValue>0x00000000</resetValue>
          <fields>
            <field>
              <name>ERRIE</name>
              <description>ERRIE  field description</description>
              <bitRange>[2:2]</bitRange>
              <access>read-write</access>
              <enumeratedValues />
            </field>
            <field>
              <name>TXIE</name>
              <description>TXIE  field description</description>
              <bitRange>[1:1]</bitRange>
              <access>read-write</access>
              <enumeratedValues />
            </field>
            <field>
              <name>RXIE</name>
              <description>RXIE  field description</description>
              <bitRange>[0:0]</bitRange>
              <access>read-write</access>
              <enumeratedValues />
            </field>
          </fields>
        </register>
        <register>
          <name>ISR</name>
          <description>SPI0 Status Register</description>
          <addressOffset>0x10</addressOffset>
          <size>32</size>
          <access>read-write</access>
          <resetValue>0x00001002</resetValue>
          <fields>
            <field>
              <name>DCN_TX</name>
              <description>DCN_TX  field description</description>
              <bitRange>[12:12]</bitRange>
              <access>read-write</access>
              <enumeratedValues>
                <enumeratedValue>
                  <name />
                  <description>DCN=0，表示命令帧</description>
                  <value>0</value>
                </enumeratedValue>
                <enumeratedValue>
                  <name />
                  <description>DCN=1，表示数据帧</description>
                  <value>1</value>
                </enumeratedValue>
              </enumeratedValues>
            </field>
            <field>
              <name>RXCOL</name>
              <description>RXCOL  field description</description>
              <bitRange>[10:10]</bitRange>
              <access>read-write</access>
              <enumeratedValues />
            </field>
            <field>
              <name>TXCOL</name>
              <description>TXCOL  field description</description>
              <bitRange>[9:9]</bitRange>
              <access>read-write</access>
              <enumeratedValues />
            </field>
            <field>
              <name>BUSY</name>
              <description>BUSY  field description</description>
              <bitRange>[8:8]</bitRange>
              <access>read-only</access>
              <enumeratedValues>
                <enumeratedValue>
                  <name />
                  <description>SPI传输进行中</description>
                  <value>1</value>
                </enumeratedValue>
                <enumeratedValue>
                  <name />
                  <description>SPI传输空闲</description>
                  <value>0</value>
                </enumeratedValue>
              </enumeratedValues>
            </field>
            <field>
              <name>MERR</name>
              <description>MERR  field description</description>
              <bitRange>[6:6]</bitRange>
              <access>read-only</access>
              <enumeratedValues />
            </field>
            <field>
              <name>SERR</name>
              <description>SERR  field description</description>
              <bitRange>[5:5]</bitRange>
              <access>read-only</access>
              <enumeratedValues />
            </field>
            <field>
              <name>TXBE</name>
              <description>TXBE  field description</description>
              <bitRange>[1:1]</bitRange>
              <access>read-only</access>
              <enumeratedValues>
                <enumeratedValue>
                  <name />
                  <description>发送缓存空，软件写TXBUF清零</description>
                  <value>1</value>
                </enumeratedValue>
                <enumeratedValue>
                  <name />
                  <description>发送缓存满</description>
                  <value>0</value>
                </enumeratedValue>
              </enumeratedValues>
            </field>
            <field>
              <name>RXBF</name>
              <description>RXBF  field description</description>
              <bitRange>[0:0]</bitRange>
              <access>read-only</access>
              <enumeratedValues>
                <enumeratedValue>
                  <name />
                  <description>接收缓存满，软件读RXBUF清零</description>
                  <value>1</value>
                </enumeratedValue>
                <enumeratedValue>
                  <name />
                  <description>接收缓存空</description>
                  <value>0</value>
                </enumeratedValue>
              </enumeratedValues>
            </field>
          </fields>
        </register>
        <register>
          <name>TXBUF</name>
          <description>SPI0 Transmit Buffer</description>
          <addressOffset>0x14</addressOffset>
          <size>32</size>
          <access>read-write</access>
          <resetValue>0x00000000</resetValue>
          <fields>
            <field>
              <name>TXBUF</name>
              <description>TXBUF  field description</description>
              <bitRange>[31:0]</bitRange>
              <access>write-only</access>
              <enumeratedValues />
            </field>
          </fields>
        </register>
        <register>
          <name>RXBUF</name>
          <description>SPI0 Receive Buffer</description>
          <addressOffset>0x18</addressOffset>
          <size>32</size>
          <access>read-write</access>
          <resetValue>0x00000000</resetValue>
          <fields>
            <field>
              <name>RXBUF</name>
              <description>RXBUF  field description</description>
              <bitRange>[31:0]</bitRange>
              <access>read-only</access>
              <enumeratedValues />
            </field>
          </fields>
        </register>
      </registers>
    </peripheral>
    <peripheral>
      <name>SPI1</name>
      <description>SPI1 module information</description>
      <groupName>SPI</groupName>
      <baseAddress>0x40010800</baseAddress>
      <size>32</size>
      <access>read-write</access>
      <addressBlock>
        <offset>0</offset>
        <size>0x1c</size>
        <usage>registers</usage>
      </addressBlock>
      <registers>
        <register>
          <name>CR1</name>
          <description>SPI1 Control Register1</description>
          <addressOffset>0x0</addressOffset>
          <size>32</size>
          <access>read-write</access>
          <resetValue>0x00000100</resetValue>
          <fields>
            <field>
              <name>IOSWAP</name>
              <description>IOSWAP  field description</description>
              <bitRange>[11:11]</bitRange>
              <access>read-write</access>
              <enumeratedValues>
                <enumeratedValue>
                  <name />
                  <description>默认引脚顺序</description>
                  <value>0</value>
                </enumeratedValue>
                <enumeratedValue>
                  <name />
                  <description>交换引脚顺序</description>
                  <value>1</value>
                </enumeratedValue>
              </enumeratedValues>
            </field>
            <field>
              <name>MSPA</name>
              <description>MSPA  field description</description>
              <bitRange>[10:10]</bitRange>
              <access>read-write</access>
              <enumeratedValues>
                <enumeratedValue>
                  <name />
                  <description>采样点延迟半个SCK周期</description>
                  <value>1</value>
                </enumeratedValue>
                <enumeratedValue>
                  <name />
                  <description>不调整</description>
                  <value>0</value>
                </enumeratedValue>
              </enumeratedValues>
            </field>
            <field>
              <name>SSPA</name>
              <description>SSPA  field description</description>
              <bitRange>[9:9]</bitRange>
              <access>read-write</access>
              <enumeratedValues>
                <enumeratedValue>
                  <name />
                  <description>提前半个SCK周期发送</description>
                  <value>1</value>
                </enumeratedValue>
                <enumeratedValue>
                  <name />
                  <description>不调整</description>
                  <value>0</value>
                </enumeratedValue>
              </enumeratedValues>
            </field>
            <field>
              <name>MM</name>
              <description>MM  field description</description>
              <bitRange>[8:8]</bitRange>
              <access>read-write</access>
              <enumeratedValues />
            </field>
            <field>
              <name>WAIT</name>
              <description>WAIT  field description</description>
              <bitRange>[7:6]</bitRange>
              <access>read-write</access>
              <enumeratedValues />
            </field>
            <field>
              <name>BAUD</name>
              <description>BAUD  field description</description>
              <bitRange>[5:3]</bitRange>
              <access>read-write</access>
              <enumeratedValues />
            </field>
            <field>
              <name>LSBF</name>
              <description>LSBF  field description</description>
              <bitRange>[2:2]</bitRange>
              <access>read-write</access>
              <enumeratedValues />
            </field>
            <field>
              <name>CPHOL</name>
              <description>CPHOL  field description</description>
              <bitRange>[1:1]</bitRange>
              <access>read-write</access>
              <enumeratedValues />
            </field>
            <field>
              <name>CPHA</name>
              <description>CPHA  field description</description>
              <bitRange>[0:0]</bitRange>
              <access>read-write</access>
              <enumeratedValues />
            </field>
          </fields>
        </register>
        <register>
          <name>CR2</name>
          <description>SPI1 Control Register2</description>
          <addressOffset>0x4</addressOffset>
          <size>32</size>
          <access>read-write</access>
          <resetValue>0x00000054</resetValue>
          <fields>
            <field>
              <name>DUMMY_EN</name>
              <description>DUMMY_EN  field description</description>
              <bitRange>[15:15]</bitRange>
              <access>read-write</access>
              <enumeratedValues>
                <enumeratedValue>
                  <name />
                  <description>不插入dummy cycle</description>
                  <value>0</value>
                </enumeratedValue>
                <enumeratedValue>
                  <name />
                  <description>在读命令之后插入一个dummy cycle</description>
                  <value>1</value>
                </enumeratedValue>
              </enumeratedValues>
            </field>
            <field>
              <name>RXO</name>
              <description>RXO  field description</description>
              <bitRange>[11:11]</bitRange>
              <access>read-write</access>
              <enumeratedValues>
                <enumeratedValue>
                  <name />
                  <description>启动Master的单接收模式</description>
                  <value>1</value>
                </enumeratedValue>
                <enumeratedValue>
                  <name />
                  <description>关闭单接收模式（收发全双工）</description>
                  <value>0</value>
                </enumeratedValue>
              </enumeratedValues>
            </field>
            <field>
              <name>DLEN</name>
              <description>DLEN  field description</description>
              <bitRange>[10:9]</bitRange>
              <access>read-write</access>
              <enumeratedValues>
                <enumeratedValue>
                  <name />
                  <description>8bit</description>
                  <value>0</value>
                </enumeratedValue>
                <enumeratedValue>
                  <name />
                  <description>16bit</description>
                  <value>1</value>
                </enumeratedValue>
                <enumeratedValue>
                  <name />
                  <description>24bit</description>
                  <value>2</value>
                </enumeratedValue>
                <enumeratedValue>
                  <name />
                  <description>32bit</description>
                  <value>3</value>
                </enumeratedValue>
              </enumeratedValues>
            </field>
            <field>
              <name>HALFDUPLEX</name>
              <description>HALFDUPLEX  field description</description>
              <bitRange>[8:8]</bitRange>
              <access>read-write</access>
              <enumeratedValues>
                <enumeratedValue>
                  <name />
                  <description>标准SPI模式，4线全双工</description>
                  <value>0</value>
                </enumeratedValue>
                <enumeratedValue>
                  <name />
                  <description>DCN模式，4线半双工</description>
                  <value>1</value>
                </enumeratedValue>
              </enumeratedValues>
            </field>
            <field>
              <name>HD_RW</name>
              <description>HD_RW  field description</description>
              <bitRange>[7:7]</bitRange>
              <access>read-write</access>
              <enumeratedValues>
                <enumeratedValue>
                  <name />
                  <description>4线半双工协议下主机写入从机</description>
                  <value>0</value>
                </enumeratedValue>
                <enumeratedValue>
                  <name />
                  <description>4线半双工协议下主机读取从机</description>
                  <value>1</value>
                </enumeratedValue>
              </enumeratedValues>
            </field>
            <field>
              <name>CMD8b</name>
              <description>CMD8b  field description</description>
              <bitRange>[6:6]</bitRange>
              <access>read-write</access>
              <enumeratedValues>
                <enumeratedValue>
                  <name />
                  <description>command帧固定为8bit</description>
                  <value>1</value>
                </enumeratedValue>
                <enumeratedValue>
                  <name />
                  <description>command帧长度由DLEN定义</description>
                  <value>0</value>
                </enumeratedValue>
              </enumeratedValues>
            </field>
            <field>
              <name>SSNM</name>
              <description>SSNM  field description</description>
              <bitRange>[5:5]</bitRange>
              <access>read-write</access>
              <enumeratedValues>
                <enumeratedValue>
                  <name />
                  <description>每发送完一帧后Master拉高SSN，维持高电平时间由WAIT寄存器控制</description>
                  <value>1</value>
                </enumeratedValue>
                <enumeratedValue>
                  <name />
                  <description>每发送完一帧后Master保持SSN为低</description>
                  <value>0</value>
                </enumeratedValue>
              </enumeratedValues>
            </field>
            <field>
              <name>TXO_AC</name>
              <description>TXO_AC  field description</description>
              <bitRange>[4:4]</bitRange>
              <access>read-write</access>
              <enumeratedValues />
            </field>
            <field>
              <name>TXO</name>
              <description>TXO  field description</description>
              <bitRange>[3:3]</bitRange>
              <access>read-write</access>
              <enumeratedValues>
                <enumeratedValue>
                  <name />
                  <description>启动Master的单发送模式</description>
                  <value>1</value>
                </enumeratedValue>
                <enumeratedValue>
                  <name />
                  <description>关闭单发送模式（收发全双工）</description>
                  <value>0</value>
                </enumeratedValue>
              </enumeratedValues>
            </field>
            <field>
              <name>SSN</name>
              <description>SSN  field description</description>
              <bitRange>[2:2]</bitRange>
              <access>read-write</access>
              <enumeratedValues>
                <enumeratedValue>
                  <name />
                  <description>SSN输出高电平</description>
                  <value>1</value>
                </enumeratedValue>
                <enumeratedValue>
                  <name />
                  <description>SSN输出低电平</description>
                  <value>0</value>
                </enumeratedValue>
              </enumeratedValues>
            </field>
            <field>
              <name>SSNSEN</name>
              <description>SSNSEN  field description</description>
              <bitRange>[1:1]</bitRange>
              <access>read-write</access>
              <enumeratedValues>
                <enumeratedValue>
                  <name />
                  <description>Master模式下SSN输出由软件控制</description>
                  <value>1</value>
                </enumeratedValue>
                <enumeratedValue>
                  <name />
                  <description>Master模式下SSN输出由硬件自动控制</description>
                  <value>0</value>
                </enumeratedValue>
              </enumeratedValues>
            </field>
            <field>
              <name>SPIEN</name>
              <description>SPIEN  field description</description>
              <bitRange>[0:0]</bitRange>
              <access>read-write</access>
              <enumeratedValues />
            </field>
          </fields>
        </register>
        <register>
          <name>CR3</name>
          <description>SPI1 Control Register3</description>
          <addressOffset>0x8</addressOffset>
          <size>32</size>
          <access>read-write</access>
          <resetValue>0x00000000</resetValue>
          <fields>
            <field>
              <name>TXBFC</name>
              <description>TXBFC  field description</description>
              <bitRange>[3:3]</bitRange>
              <access>write-only</access>
              <enumeratedValues />
            </field>
            <field>
              <name>RXBFC</name>
              <description>RXBFC  field description</description>
              <bitRange>[2:2]</bitRange>
              <access>write-only</access>
              <enumeratedValues />
            </field>
            <field>
              <name>MERRC</name>
              <description>MERRC  field description</description>
              <bitRange>[1:1]</bitRange>
              <access>write-only</access>
              <enumeratedValues />
            </field>
            <field>
              <name>SERRC</name>
              <description>SERRC  field description</description>
              <bitRange>[0:0]</bitRange>
              <access>write-only</access>
              <enumeratedValues />
            </field>
          </fields>
        </register>
        <register>
          <name>IER</name>
          <description>SPI1 Interrupt Enable Register</description>
          <addressOffset>0xc</addressOffset>
          <size>32</size>
          <access>read-write</access>
          <resetValue>0x00000000</resetValue>
          <fields>
            <field>
              <name>ERRIE</name>
              <description>ERRIE  field description</description>
              <bitRange>[2:2]</bitRange>
              <access>read-write</access>
              <enumeratedValues />
            </field>
            <field>
              <name>TXIE</name>
              <description>TXIE  field description</description>
              <bitRange>[1:1]</bitRange>
              <access>read-write</access>
              <enumeratedValues />
            </field>
            <field>
              <name>RXIE</name>
              <description>RXIE  field description</description>
              <bitRange>[0:0]</bitRange>
              <access>read-write</access>
              <enumeratedValues />
            </field>
          </fields>
        </register>
        <register>
          <name>ISR</name>
          <description>SPI1 Status Register</description>
          <addressOffset>0x10</addressOffset>
          <size>32</size>
          <access>read-write</access>
          <resetValue>0x00001002</resetValue>
          <fields>
            <field>
              <name>DCN_TX</name>
              <description>DCN_TX  field description</description>
              <bitRange>[12:12]</bitRange>
              <access>read-write</access>
              <enumeratedValues>
                <enumeratedValue>
                  <name />
                  <description>DCN=0，表示命令帧</description>
                  <value>0</value>
                </enumeratedValue>
                <enumeratedValue>
                  <name />
                  <description>DCN=1，表示数据帧</description>
                  <value>1</value>
                </enumeratedValue>
              </enumeratedValues>
            </field>
            <field>
              <name>RXCOL</name>
              <description>RXCOL  field description</description>
              <bitRange>[10:10]</bitRange>
              <access>read-write</access>
              <enumeratedValues />
            </field>
            <field>
              <name>TXCOL</name>
              <description>TXCOL  field description</description>
              <bitRange>[9:9]</bitRange>
              <access>read-write</access>
              <enumeratedValues />
            </field>
            <field>
              <name>BUSY</name>
              <description>BUSY  field description</description>
              <bitRange>[8:8]</bitRange>
              <access>read-only</access>
              <enumeratedValues>
                <enumeratedValue>
                  <name />
                  <description>SPI传输进行中</description>
                  <value>1</value>
                </enumeratedValue>
                <enumeratedValue>
                  <name />
                  <description>SPI传输空闲</description>
                  <value>0</value>
                </enumeratedValue>
              </enumeratedValues>
            </field>
            <field>
              <name>MERR</name>
              <description>MERR  field description</description>
              <bitRange>[6:6]</bitRange>
              <access>read-only</access>
              <enumeratedValues />
            </field>
            <field>
              <name>SERR</name>
              <description>SERR  field description</description>
              <bitRange>[5:5]</bitRange>
              <access>read-only</access>
              <enumeratedValues />
            </field>
            <field>
              <name>TXBE</name>
              <description>TXBE  field description</description>
              <bitRange>[1:1]</bitRange>
              <access>read-only</access>
              <enumeratedValues>
                <enumeratedValue>
                  <name />
                  <description>发送缓存空，软件写TXBUF清零</description>
                  <value>1</value>
                </enumeratedValue>
                <enumeratedValue>
                  <name />
                  <description>发送缓存满</description>
                  <value>0</value>
                </enumeratedValue>
              </enumeratedValues>
            </field>
            <field>
              <name>RXBF</name>
              <description>RXBF  field description</description>
              <bitRange>[0:0]</bitRange>
              <access>read-only</access>
              <enumeratedValues>
                <enumeratedValue>
                  <name />
                  <description>接收缓存满，软件读RXBUF清零</description>
                  <value>1</value>
                </enumeratedValue>
                <enumeratedValue>
                  <name />
                  <description>接收缓存空</description>
                  <value>0</value>
                </enumeratedValue>
              </enumeratedValues>
            </field>
          </fields>
        </register>
        <register>
          <name>TXBUF</name>
          <description>SPI1 Transmit Buffer</description>
          <addressOffset>0x14</addressOffset>
          <size>32</size>
          <access>read-write</access>
          <resetValue>0x00000000</resetValue>
          <fields>
            <field>
              <name>TXBUF</name>
              <description>TXBUF  field description</description>
              <bitRange>[31:0]</bitRange>
              <access>write-only</access>
              <enumeratedValues />
            </field>
          </fields>
        </register>
        <register>
          <name>RXBUF</name>
          <description>SPI1 Receive Buffer</description>
          <addressOffset>0x18</addressOffset>
          <size>32</size>
          <access>read-write</access>
          <resetValue>0x00000000</resetValue>
          <fields>
            <field>
              <name>RXBUF</name>
              <description>RXBUF  field description</description>
              <bitRange>[31:0]</bitRange>
              <access>read-only</access>
              <enumeratedValues />
            </field>
          </fields>
        </register>
      </registers>
    </peripheral>
    <peripheral>
      <name>SPI2</name>
      <description>SPI2 module information</description>
      <groupName>SPI</groupName>
      <baseAddress>0x40014800</baseAddress>
      <size>32</size>
      <access>read-write</access>
      <addressBlock>
        <offset>0</offset>
        <size>0x1c</size>
        <usage>registers</usage>
      </addressBlock>
      <registers>
        <register>
          <name>CR1</name>
          <description>SPI2 Control Register1</description>
          <addressOffset>0x0</addressOffset>
          <size>32</size>
          <access>read-write</access>
          <resetValue>0x00000100</resetValue>
          <fields>
            <field>
              <name>IOSWAP</name>
              <description>IOSWAP  field description</description>
              <bitRange>[11:11]</bitRange>
              <access>read-write</access>
              <enumeratedValues>
                <enumeratedValue>
                  <name />
                  <description>默认引脚顺序</description>
                  <value>0</value>
                </enumeratedValue>
                <enumeratedValue>
                  <name />
                  <description>交换引脚顺序</description>
                  <value>1</value>
                </enumeratedValue>
              </enumeratedValues>
            </field>
            <field>
              <name>MSPA</name>
              <description>MSPA  field description</description>
              <bitRange>[10:10]</bitRange>
              <access>read-write</access>
              <enumeratedValues>
                <enumeratedValue>
                  <name />
                  <description>采样点延迟半个SCK周期</description>
                  <value>1</value>
                </enumeratedValue>
                <enumeratedValue>
                  <name />
                  <description>不调整</description>
                  <value>0</value>
                </enumeratedValue>
              </enumeratedValues>
            </field>
            <field>
              <name>SSPA</name>
              <description>SSPA  field description</description>
              <bitRange>[9:9]</bitRange>
              <access>read-write</access>
              <enumeratedValues>
                <enumeratedValue>
                  <name />
                  <description>提前半个SCK周期发送</description>
                  <value>1</value>
                </enumeratedValue>
                <enumeratedValue>
                  <name />
                  <description>不调整</description>
                  <value>0</value>
                </enumeratedValue>
              </enumeratedValues>
            </field>
            <field>
              <name>MM</name>
              <description>MM  field description</description>
              <bitRange>[8:8]</bitRange>
              <access>read-write</access>
              <enumeratedValues />
            </field>
            <field>
              <name>WAIT</name>
              <description>WAIT  field description</description>
              <bitRange>[7:6]</bitRange>
              <access>read-write</access>
              <enumeratedValues />
            </field>
            <field>
              <name>BAUD</name>
              <description>BAUD  field description</description>
              <bitRange>[5:3]</bitRange>
              <access>read-write</access>
              <enumeratedValues />
            </field>
            <field>
              <name>LSBF</name>
              <description>LSBF  field description</description>
              <bitRange>[2:2]</bitRange>
              <access>read-write</access>
              <enumeratedValues />
            </field>
            <field>
              <name>CPHOL</name>
              <description>CPHOL  field description</description>
              <bitRange>[1:1]</bitRange>
              <access>read-write</access>
              <enumeratedValues />
            </field>
            <field>
              <name>CPHA</name>
              <description>CPHA  field description</description>
              <bitRange>[0:0]</bitRange>
              <access>read-write</access>
              <enumeratedValues />
            </field>
          </fields>
        </register>
        <register>
          <name>CR2</name>
          <description>SPI2 Control Register2</description>
          <addressOffset>0x4</addressOffset>
          <size>32</size>
          <access>read-write</access>
          <resetValue>0x00000054</resetValue>
          <fields>
            <field>
              <name>DUMMY_EN</name>
              <description>DUMMY_EN  field description</description>
              <bitRange>[15:15]</bitRange>
              <access>read-write</access>
              <enumeratedValues>
                <enumeratedValue>
                  <name />
                  <description>不插入dummy cycle</description>
                  <value>0</value>
                </enumeratedValue>
                <enumeratedValue>
                  <name />
                  <description>在读命令之后插入一个dummy cycle</description>
                  <value>1</value>
                </enumeratedValue>
              </enumeratedValues>
            </field>
            <field>
              <name>RXO</name>
              <description>RXO  field description</description>
              <bitRange>[11:11]</bitRange>
              <access>read-write</access>
              <enumeratedValues>
                <enumeratedValue>
                  <name />
                  <description>启动Master的单接收模式</description>
                  <value>1</value>
                </enumeratedValue>
                <enumeratedValue>
                  <name />
                  <description>关闭单接收模式（收发全双工）</description>
                  <value>0</value>
                </enumeratedValue>
              </enumeratedValues>
            </field>
            <field>
              <name>DLEN</name>
              <description>DLEN  field description</description>
              <bitRange>[10:9]</bitRange>
              <access>read-write</access>
              <enumeratedValues>
                <enumeratedValue>
                  <name />
                  <description>8bit</description>
                  <value>0</value>
                </enumeratedValue>
                <enumeratedValue>
                  <name />
                  <description>16bit</description>
                  <value>1</value>
                </enumeratedValue>
                <enumeratedValue>
                  <name />
                  <description>24bit</description>
                  <value>2</value>
                </enumeratedValue>
                <enumeratedValue>
                  <name />
                  <description>32bit</description>
                  <value>3</value>
                </enumeratedValue>
              </enumeratedValues>
            </field>
            <field>
              <name>HALFDUPLEX</name>
              <description>HALFDUPLEX  field description</description>
              <bitRange>[8:8]</bitRange>
              <access>read-write</access>
              <enumeratedValues>
                <enumeratedValue>
                  <name />
                  <description>标准SPI模式，4线全双工</description>
                  <value>0</value>
                </enumeratedValue>
                <enumeratedValue>
                  <name />
                  <description>DCN模式，4线半双工</description>
                  <value>1</value>
                </enumeratedValue>
              </enumeratedValues>
            </field>
            <field>
              <name>HD_RW</name>
              <description>HD_RW  field description</description>
              <bitRange>[7:7]</bitRange>
              <access>read-write</access>
              <enumeratedValues>
                <enumeratedValue>
                  <name />
                  <description>4线半双工协议下主机写入从机</description>
                  <value>0</value>
                </enumeratedValue>
                <enumeratedValue>
                  <name />
                  <description>4线半双工协议下主机读取从机</description>
                  <value>1</value>
                </enumeratedValue>
              </enumeratedValues>
            </field>
            <field>
              <name>CMD8b</name>
              <description>CMD8b  field description</description>
              <bitRange>[6:6]</bitRange>
              <access>read-write</access>
              <enumeratedValues>
                <enumeratedValue>
                  <name />
                  <description>command帧固定为8bit</description>
                  <value>1</value>
                </enumeratedValue>
                <enumeratedValue>
                  <name />
                  <description>command帧长度由DLEN定义</description>
                  <value>0</value>
                </enumeratedValue>
              </enumeratedValues>
            </field>
            <field>
              <name>SSNM</name>
              <description>SSNM  field description</description>
              <bitRange>[5:5]</bitRange>
              <access>read-write</access>
              <enumeratedValues>
                <enumeratedValue>
                  <name />
                  <description>每发送完一帧后Master拉高SSN，维持高电平时间由WAIT寄存器控制</description>
                  <value>1</value>
                </enumeratedValue>
                <enumeratedValue>
                  <name />
                  <description>每发送完一帧后Master保持SSN为低</description>
                  <value>0</value>
                </enumeratedValue>
              </enumeratedValues>
            </field>
            <field>
              <name>TXO_AC</name>
              <description>TXO_AC  field description</description>
              <bitRange>[4:4]</bitRange>
              <access>read-write</access>
              <enumeratedValues />
            </field>
            <field>
              <name>TXO</name>
              <description>TXO  field description</description>
              <bitRange>[3:3]</bitRange>
              <access>read-write</access>
              <enumeratedValues>
                <enumeratedValue>
                  <name />
                  <description>启动Master的单发送模式</description>
                  <value>1</value>
                </enumeratedValue>
                <enumeratedValue>
                  <name />
                  <description>关闭单发送模式（收发全双工）</description>
                  <value>0</value>
                </enumeratedValue>
              </enumeratedValues>
            </field>
            <field>
              <name>SSN</name>
              <description>SSN  field description</description>
              <bitRange>[2:2]</bitRange>
              <access>read-write</access>
              <enumeratedValues>
                <enumeratedValue>
                  <name />
                  <description>SSN输出高电平</description>
                  <value>1</value>
                </enumeratedValue>
                <enumeratedValue>
                  <name />
                  <description>SSN输出低电平</description>
                  <value>0</value>
                </enumeratedValue>
              </enumeratedValues>
            </field>
            <field>
              <name>SSNSEN</name>
              <description>SSNSEN  field description</description>
              <bitRange>[1:1]</bitRange>
              <access>read-write</access>
              <enumeratedValues>
                <enumeratedValue>
                  <name />
                  <description>Master模式下SSN输出由软件控制</description>
                  <value>1</value>
                </enumeratedValue>
                <enumeratedValue>
                  <name />
                  <description>Master模式下SSN输出由硬件自动控制</description>
                  <value>0</value>
                </enumeratedValue>
              </enumeratedValues>
            </field>
            <field>
              <name>SPIEN</name>
              <description>SPIEN  field description</description>
              <bitRange>[0:0]</bitRange>
              <access>read-write</access>
              <enumeratedValues />
            </field>
          </fields>
        </register>
        <register>
          <name>CR3</name>
          <description>SPI2 Control Register3</description>
          <addressOffset>0x8</addressOffset>
          <size>32</size>
          <access>read-write</access>
          <resetValue>0x00000000</resetValue>
          <fields>
            <field>
              <name>TXBFC</name>
              <description>TXBFC  field description</description>
              <bitRange>[3:3]</bitRange>
              <access>write-only</access>
              <enumeratedValues />
            </field>
            <field>
              <name>RXBFC</name>
              <description>RXBFC  field description</description>
              <bitRange>[2:2]</bitRange>
              <access>write-only</access>
              <enumeratedValues />
            </field>
            <field>
              <name>MERRC</name>
              <description>MERRC  field description</description>
              <bitRange>[1:1]</bitRange>
              <access>write-only</access>
              <enumeratedValues />
            </field>
            <field>
              <name>SERRC</name>
              <description>SERRC  field description</description>
              <bitRange>[0:0]</bitRange>
              <access>write-only</access>
              <enumeratedValues />
            </field>
          </fields>
        </register>
        <register>
          <name>IER</name>
          <description>SPI2 Interrupt Enable Register</description>
          <addressOffset>0xc</addressOffset>
          <size>32</size>
          <access>read-write</access>
          <resetValue>0x00000000</resetValue>
          <fields>
            <field>
              <name>ERRIE</name>
              <description>ERRIE  field description</description>
              <bitRange>[2:2]</bitRange>
              <access>read-write</access>
              <enumeratedValues />
            </field>
            <field>
              <name>TXIE</name>
              <description>TXIE  field description</description>
              <bitRange>[1:1]</bitRange>
              <access>read-write</access>
              <enumeratedValues />
            </field>
            <field>
              <name>RXIE</name>
              <description>RXIE  field description</description>
              <bitRange>[0:0]</bitRange>
              <access>read-write</access>
              <enumeratedValues />
            </field>
          </fields>
        </register>
        <register>
          <name>ISR</name>
          <description>SPI2 Status Register</description>
          <addressOffset>0x10</addressOffset>
          <size>32</size>
          <access>read-write</access>
          <resetValue>0x00001002</resetValue>
          <fields>
            <field>
              <name>DCN_TX</name>
              <description>DCN_TX  field description</description>
              <bitRange>[12:12]</bitRange>
              <access>read-write</access>
              <enumeratedValues>
                <enumeratedValue>
                  <name />
                  <description>DCN=0，表示命令帧</description>
                  <value>0</value>
                </enumeratedValue>
                <enumeratedValue>
                  <name />
                  <description>DCN=1，表示数据帧</description>
                  <value>1</value>
                </enumeratedValue>
              </enumeratedValues>
            </field>
            <field>
              <name>RXCOL</name>
              <description>RXCOL  field description</description>
              <bitRange>[10:10]</bitRange>
              <access>read-write</access>
              <enumeratedValues />
            </field>
            <field>
              <name>TXCOL</name>
              <description>TXCOL  field description</description>
              <bitRange>[9:9]</bitRange>
              <access>read-write</access>
              <enumeratedValues />
            </field>
            <field>
              <name>BUSY</name>
              <description>BUSY  field description</description>
              <bitRange>[8:8]</bitRange>
              <access>read-only</access>
              <enumeratedValues>
                <enumeratedValue>
                  <name />
                  <description>SPI传输进行中</description>
                  <value>1</value>
                </enumeratedValue>
                <enumeratedValue>
                  <name />
                  <description>SPI传输空闲</description>
                  <value>0</value>
                </enumeratedValue>
              </enumeratedValues>
            </field>
            <field>
              <name>MERR</name>
              <description>MERR  field description</description>
              <bitRange>[6:6]</bitRange>
              <access>read-only</access>
              <enumeratedValues />
            </field>
            <field>
              <name>SERR</name>
              <description>SERR  field description</description>
              <bitRange>[5:5]</bitRange>
              <access>read-only</access>
              <enumeratedValues />
            </field>
            <field>
              <name>TXBE</name>
              <description>TXBE  field description</description>
              <bitRange>[1:1]</bitRange>
              <access>read-only</access>
              <enumeratedValues>
                <enumeratedValue>
                  <name />
                  <description>发送缓存空，软件写TXBUF清零</description>
                  <value>1</value>
                </enumeratedValue>
                <enumeratedValue>
                  <name />
                  <description>发送缓存满</description>
                  <value>0</value>
                </enumeratedValue>
              </enumeratedValues>
            </field>
            <field>
              <name>RXBF</name>
              <description>RXBF  field description</description>
              <bitRange>[0:0]</bitRange>
              <access>read-only</access>
              <enumeratedValues>
                <enumeratedValue>
                  <name />
                  <description>接收缓存满，软件读RXBUF清零</description>
                  <value>1</value>
                </enumeratedValue>
                <enumeratedValue>
                  <name />
                  <description>接收缓存空</description>
                  <value>0</value>
                </enumeratedValue>
              </enumeratedValues>
            </field>
          </fields>
        </register>
        <register>
          <name>TXBUF</name>
          <description>SPI2 Transmit Buffer</description>
          <addressOffset>0x14</addressOffset>
          <size>32</size>
          <access>read-write</access>
          <resetValue>0x00000000</resetValue>
          <fields>
            <field>
              <name>TXBUF</name>
              <description>TXBUF  field description</description>
              <bitRange>[31:0]</bitRange>
              <access>write-only</access>
              <enumeratedValues />
            </field>
          </fields>
        </register>
        <register>
          <name>RXBUF</name>
          <description>SPI2 Receive Buffer</description>
          <addressOffset>0x18</addressOffset>
          <size>32</size>
          <access>read-write</access>
          <resetValue>0x00000000</resetValue>
          <fields>
            <field>
              <name>RXBUF</name>
              <description>RXBUF  field description</description>
              <bitRange>[31:0]</bitRange>
              <access>read-only</access>
              <enumeratedValues />
            </field>
          </fields>
        </register>
      </registers>
    </peripheral>
    <peripheral>
      <name>SPI3</name>
      <description>SPI3 module information</description>
      <groupName>SPI</groupName>
      <baseAddress>0x40014c00</baseAddress>
      <size>32</size>
      <access>read-write</access>
      <addressBlock>
        <offset>0</offset>
        <size>0x1c</size>
        <usage>registers</usage>
      </addressBlock>
      <registers>
        <register>
          <name>CR1</name>
          <description>SPI3 Control Register1</description>
          <addressOffset>0x0</addressOffset>
          <size>32</size>
          <access>read-write</access>
          <resetValue>0x00000100</resetValue>
          <fields>
            <field>
              <name>IOSWAP</name>
              <description>IOSWAP  field description</description>
              <bitRange>[11:11]</bitRange>
              <access>read-write</access>
              <enumeratedValues>
                <enumeratedValue>
                  <name />
                  <description>默认引脚顺序</description>
                  <value>0</value>
                </enumeratedValue>
                <enumeratedValue>
                  <name />
                  <description>交换引脚顺序</description>
                  <value>1</value>
                </enumeratedValue>
              </enumeratedValues>
            </field>
            <field>
              <name>MSPA</name>
              <description>MSPA  field description</description>
              <bitRange>[10:10]</bitRange>
              <access>read-write</access>
              <enumeratedValues>
                <enumeratedValue>
                  <name />
                  <description>采样点延迟半个SCK周期</description>
                  <value>1</value>
                </enumeratedValue>
                <enumeratedValue>
                  <name />
                  <description>不调整</description>
                  <value>0</value>
                </enumeratedValue>
              </enumeratedValues>
            </field>
            <field>
              <name>SSPA</name>
              <description>SSPA  field description</description>
              <bitRange>[9:9]</bitRange>
              <access>read-write</access>
              <enumeratedValues>
                <enumeratedValue>
                  <name />
                  <description>提前半个SCK周期发送</description>
                  <value>1</value>
                </enumeratedValue>
                <enumeratedValue>
                  <name />
                  <description>不调整</description>
                  <value>0</value>
                </enumeratedValue>
              </enumeratedValues>
            </field>
            <field>
              <name>MM</name>
              <description>MM  field description</description>
              <bitRange>[8:8]</bitRange>
              <access>read-write</access>
              <enumeratedValues />
            </field>
            <field>
              <name>WAIT</name>
              <description>WAIT  field description</description>
              <bitRange>[7:6]</bitRange>
              <access>read-write</access>
              <enumeratedValues />
            </field>
            <field>
              <name>BAUD</name>
              <description>BAUD  field description</description>
              <bitRange>[5:3]</bitRange>
              <access>read-write</access>
              <enumeratedValues />
            </field>
            <field>
              <name>LSBF</name>
              <description>LSBF  field description</description>
              <bitRange>[2:2]</bitRange>
              <access>read-write</access>
              <enumeratedValues />
            </field>
            <field>
              <name>CPHOL</name>
              <description>CPHOL  field description</description>
              <bitRange>[1:1]</bitRange>
              <access>read-write</access>
              <enumeratedValues />
            </field>
            <field>
              <name>CPHA</name>
              <description>CPHA  field description</description>
              <bitRange>[0:0]</bitRange>
              <access>read-write</access>
              <enumeratedValues />
            </field>
          </fields>
        </register>
        <register>
          <name>CR2</name>
          <description>SPI3 Control Register2</description>
          <addressOffset>0x4</addressOffset>
          <size>32</size>
          <access>read-write</access>
          <resetValue>0x00000054</resetValue>
          <fields>
            <field>
              <name>DUMMY_EN</name>
              <description>DUMMY_EN  field description</description>
              <bitRange>[15:15]</bitRange>
              <access>read-write</access>
              <enumeratedValues>
                <enumeratedValue>
                  <name />
                  <description>不插入dummy cycle</description>
                  <value>0</value>
                </enumeratedValue>
                <enumeratedValue>
                  <name />
                  <description>在读命令之后插入一个dummy cycle</description>
                  <value>1</value>
                </enumeratedValue>
              </enumeratedValues>
            </field>
            <field>
              <name>RXO</name>
              <description>RXO  field description</description>
              <bitRange>[11:11]</bitRange>
              <access>read-write</access>
              <enumeratedValues>
                <enumeratedValue>
                  <name />
                  <description>启动Master的单接收模式</description>
                  <value>1</value>
                </enumeratedValue>
                <enumeratedValue>
                  <name />
                  <description>关闭单接收模式（收发全双工）</description>
                  <value>0</value>
                </enumeratedValue>
              </enumeratedValues>
            </field>
            <field>
              <name>DLEN</name>
              <description>DLEN  field description</description>
              <bitRange>[10:9]</bitRange>
              <access>read-write</access>
              <enumeratedValues>
                <enumeratedValue>
                  <name />
                  <description>8bit</description>
                  <value>0</value>
                </enumeratedValue>
                <enumeratedValue>
                  <name />
                  <description>16bit</description>
                  <value>1</value>
                </enumeratedValue>
                <enumeratedValue>
                  <name />
                  <description>24bit</description>
                  <value>2</value>
                </enumeratedValue>
                <enumeratedValue>
                  <name />
                  <description>32bit</description>
                  <value>3</value>
                </enumeratedValue>
              </enumeratedValues>
            </field>
            <field>
              <name>HALFDUPLEX</name>
              <description>HALFDUPLEX  field description</description>
              <bitRange>[8:8]</bitRange>
              <access>read-write</access>
              <enumeratedValues>
                <enumeratedValue>
                  <name />
                  <description>标准SPI模式，4线全双工</description>
                  <value>0</value>
                </enumeratedValue>
                <enumeratedValue>
                  <name />
                  <description>DCN模式，4线半双工</description>
                  <value>1</value>
                </enumeratedValue>
              </enumeratedValues>
            </field>
            <field>
              <name>HD_RW</name>
              <description>HD_RW  field description</description>
              <bitRange>[7:7]</bitRange>
              <access>read-write</access>
              <enumeratedValues>
                <enumeratedValue>
                  <name />
                  <description>4线半双工协议下主机写入从机</description>
                  <value>0</value>
                </enumeratedValue>
                <enumeratedValue>
                  <name />
                  <description>4线半双工协议下主机读取从机</description>
                  <value>1</value>
                </enumeratedValue>
              </enumeratedValues>
            </field>
            <field>
              <name>CMD8b</name>
              <description>CMD8b  field description</description>
              <bitRange>[6:6]</bitRange>
              <access>read-write</access>
              <enumeratedValues>
                <enumeratedValue>
                  <name />
                  <description>command帧固定为8bit</description>
                  <value>1</value>
                </enumeratedValue>
                <enumeratedValue>
                  <name />
                  <description>command帧长度由DLEN定义</description>
                  <value>0</value>
                </enumeratedValue>
              </enumeratedValues>
            </field>
            <field>
              <name>SSNM</name>
              <description>SSNM  field description</description>
              <bitRange>[5:5]</bitRange>
              <access>read-write</access>
              <enumeratedValues>
                <enumeratedValue>
                  <name />
                  <description>每发送完一帧后Master拉高SSN，维持高电平时间由WAIT寄存器控制</description>
                  <value>1</value>
                </enumeratedValue>
                <enumeratedValue>
                  <name />
                  <description>每发送完一帧后Master保持SSN为低</description>
                  <value>0</value>
                </enumeratedValue>
              </enumeratedValues>
            </field>
            <field>
              <name>TXO_AC</name>
              <description>TXO_AC  field description</description>
              <bitRange>[4:4]</bitRange>
              <access>read-write</access>
              <enumeratedValues />
            </field>
            <field>
              <name>TXO</name>
              <description>TXO  field description</description>
              <bitRange>[3:3]</bitRange>
              <access>read-write</access>
              <enumeratedValues>
                <enumeratedValue>
                  <name />
                  <description>启动Master的单发送模式</description>
                  <value>1</value>
                </enumeratedValue>
                <enumeratedValue>
                  <name />
                  <description>关闭单发送模式（收发全双工）</description>
                  <value>0</value>
                </enumeratedValue>
              </enumeratedValues>
            </field>
            <field>
              <name>SSN</name>
              <description>SSN  field description</description>
              <bitRange>[2:2]</bitRange>
              <access>read-write</access>
              <enumeratedValues>
                <enumeratedValue>
                  <name />
                  <description>SSN输出高电平</description>
                  <value>1</value>
                </enumeratedValue>
                <enumeratedValue>
                  <name />
                  <description>SSN输出低电平</description>
                  <value>0</value>
                </enumeratedValue>
              </enumeratedValues>
            </field>
            <field>
              <name>SSNSEN</name>
              <description>SSNSEN  field description</description>
              <bitRange>[1:1]</bitRange>
              <access>read-write</access>
              <enumeratedValues>
                <enumeratedValue>
                  <name />
                  <description>Master模式下SSN输出由软件控制</description>
                  <value>1</value>
                </enumeratedValue>
                <enumeratedValue>
                  <name />
                  <description>Master模式下SSN输出由硬件自动控制</description>
                  <value>0</value>
                </enumeratedValue>
              </enumeratedValues>
            </field>
            <field>
              <name>SPIEN</name>
              <description>SPIEN  field description</description>
              <bitRange>[0:0]</bitRange>
              <access>read-write</access>
              <enumeratedValues />
            </field>
          </fields>
        </register>
        <register>
          <name>CR3</name>
          <description>SPI3 Control Register3</description>
          <addressOffset>0x8</addressOffset>
          <size>32</size>
          <access>read-write</access>
          <resetValue>0x00000000</resetValue>
          <fields>
            <field>
              <name>TXBFC</name>
              <description>TXBFC  field description</description>
              <bitRange>[3:3]</bitRange>
              <access>write-only</access>
              <enumeratedValues />
            </field>
            <field>
              <name>RXBFC</name>
              <description>RXBFC  field description</description>
              <bitRange>[2:2]</bitRange>
              <access>write-only</access>
              <enumeratedValues />
            </field>
            <field>
              <name>MERRC</name>
              <description>MERRC  field description</description>
              <bitRange>[1:1]</bitRange>
              <access>write-only</access>
              <enumeratedValues />
            </field>
            <field>
              <name>SERRC</name>
              <description>SERRC  field description</description>
              <bitRange>[0:0]</bitRange>
              <access>write-only</access>
              <enumeratedValues />
            </field>
          </fields>
        </register>
        <register>
          <name>IER</name>
          <description>SPI3 Interrupt Enable Register</description>
          <addressOffset>0xc</addressOffset>
          <size>32</size>
          <access>read-write</access>
          <resetValue>0x00000000</resetValue>
          <fields>
            <field>
              <name>ERRIE</name>
              <description>ERRIE  field description</description>
              <bitRange>[2:2]</bitRange>
              <access>read-write</access>
              <enumeratedValues />
            </field>
            <field>
              <name>TXIE</name>
              <description>TXIE  field description</description>
              <bitRange>[1:1]</bitRange>
              <access>read-write</access>
              <enumeratedValues />
            </field>
            <field>
              <name>RXIE</name>
              <description>RXIE  field description</description>
              <bitRange>[0:0]</bitRange>
              <access>read-write</access>
              <enumeratedValues />
            </field>
          </fields>
        </register>
        <register>
          <name>ISR</name>
          <description>SPI3 Status Register</description>
          <addressOffset>0x10</addressOffset>
          <size>32</size>
          <access>read-write</access>
          <resetValue>0x00001002</resetValue>
          <fields>
            <field>
              <name>DCN_TX</name>
              <description>DCN_TX  field description</description>
              <bitRange>[12:12]</bitRange>
              <access>read-write</access>
              <enumeratedValues>
                <enumeratedValue>
                  <name />
                  <description>DCN=0，表示命令帧</description>
                  <value>0</value>
                </enumeratedValue>
                <enumeratedValue>
                  <name />
                  <description>DCN=1，表示数据帧</description>
                  <value>1</value>
                </enumeratedValue>
              </enumeratedValues>
            </field>
            <field>
              <name>RXCOL</name>
              <description>RXCOL  field description</description>
              <bitRange>[10:10]</bitRange>
              <access>read-write</access>
              <enumeratedValues />
            </field>
            <field>
              <name>TXCOL</name>
              <description>TXCOL  field description</description>
              <bitRange>[9:9]</bitRange>
              <access>read-write</access>
              <enumeratedValues />
            </field>
            <field>
              <name>BUSY</name>
              <description>BUSY  field description</description>
              <bitRange>[8:8]</bitRange>
              <access>read-only</access>
              <enumeratedValues>
                <enumeratedValue>
                  <name />
                  <description>SPI传输进行中</description>
                  <value>1</value>
                </enumeratedValue>
                <enumeratedValue>
                  <name />
                  <description>SPI传输空闲</description>
                  <value>0</value>
                </enumeratedValue>
              </enumeratedValues>
            </field>
            <field>
              <name>MERR</name>
              <description>MERR  field description</description>
              <bitRange>[6:6]</bitRange>
              <access>read-only</access>
              <enumeratedValues />
            </field>
            <field>
              <name>SERR</name>
              <description>SERR  field description</description>
              <bitRange>[5:5]</bitRange>
              <access>read-only</access>
              <enumeratedValues />
            </field>
            <field>
              <name>TXBE</name>
              <description>TXBE  field description</description>
              <bitRange>[1:1]</bitRange>
              <access>read-only</access>
              <enumeratedValues>
                <enumeratedValue>
                  <name />
                  <description>发送缓存空，软件写TXBUF清零</description>
                  <value>1</value>
                </enumeratedValue>
                <enumeratedValue>
                  <name />
                  <description>发送缓存满</description>
                  <value>0</value>
                </enumeratedValue>
              </enumeratedValues>
            </field>
            <field>
              <name>RXBF</name>
              <description>RXBF  field description</description>
              <bitRange>[0:0]</bitRange>
              <access>read-only</access>
              <enumeratedValues>
                <enumeratedValue>
                  <name />
                  <description>接收缓存满，软件读RXBUF清零</description>
                  <value>1</value>
                </enumeratedValue>
                <enumeratedValue>
                  <name />
                  <description>接收缓存空</description>
                  <value>0</value>
                </enumeratedValue>
              </enumeratedValues>
            </field>
          </fields>
        </register>
        <register>
          <name>TXBUF</name>
          <description>SPI3 Transmit Buffer</description>
          <addressOffset>0x14</addressOffset>
          <size>32</size>
          <access>read-write</access>
          <resetValue>0x00000000</resetValue>
          <fields>
            <field>
              <name>TXBUF</name>
              <description>TXBUF  field description</description>
              <bitRange>[31:0]</bitRange>
              <access>write-only</access>
              <enumeratedValues />
            </field>
          </fields>
        </register>
        <register>
          <name>RXBUF</name>
          <description>SPI3 Receive Buffer</description>
          <addressOffset>0x18</addressOffset>
          <size>32</size>
          <access>read-write</access>
          <resetValue>0x00000000</resetValue>
          <fields>
            <field>
              <name>RXBUF</name>
              <description>RXBUF  field description</description>
              <bitRange>[31:0]</bitRange>
              <access>read-only</access>
              <enumeratedValues />
            </field>
          </fields>
        </register>
      </registers>
    </peripheral>
    <peripheral>
      <name>SPI4</name>
      <description>SPI4 module information</description>
      <groupName>SPI</groupName>
      <baseAddress>0x40016400</baseAddress>
      <size>32</size>
      <access>read-write</access>
      <addressBlock>
        <offset>0</offset>
        <size>0x1c</size>
        <usage>registers</usage>
      </addressBlock>
      <registers>
        <register>
          <name>CR1</name>
          <description>SPI4 Control Register1</description>
          <addressOffset>0x0</addressOffset>
          <size>32</size>
          <access>read-write</access>
          <resetValue>0x00000100</resetValue>
          <fields>
            <field>
              <name>IOSWAP</name>
              <description>IOSWAP  field description</description>
              <bitRange>[11:11]</bitRange>
              <access>read-write</access>
              <enumeratedValues>
                <enumeratedValue>
                  <name />
                  <description>默认引脚顺序</description>
                  <value>0</value>
                </enumeratedValue>
                <enumeratedValue>
                  <name />
                  <description>交换引脚顺序</description>
                  <value>1</value>
                </enumeratedValue>
              </enumeratedValues>
            </field>
            <field>
              <name>MSPA</name>
              <description>MSPA  field description</description>
              <bitRange>[10:10]</bitRange>
              <access>read-write</access>
              <enumeratedValues>
                <enumeratedValue>
                  <name />
                  <description>采样点延迟半个SCK周期</description>
                  <value>1</value>
                </enumeratedValue>
                <enumeratedValue>
                  <name />
                  <description>不调整</description>
                  <value>0</value>
                </enumeratedValue>
              </enumeratedValues>
            </field>
            <field>
              <name>SSPA</name>
              <description>SSPA  field description</description>
              <bitRange>[9:9]</bitRange>
              <access>read-write</access>
              <enumeratedValues>
                <enumeratedValue>
                  <name />
                  <description>提前半个SCK周期发送</description>
                  <value>1</value>
                </enumeratedValue>
                <enumeratedValue>
                  <name />
                  <description>不调整</description>
                  <value>0</value>
                </enumeratedValue>
              </enumeratedValues>
            </field>
            <field>
              <name>MM</name>
              <description>MM  field description</description>
              <bitRange>[8:8]</bitRange>
              <access>read-write</access>
              <enumeratedValues />
            </field>
            <field>
              <name>WAIT</name>
              <description>WAIT  field description</description>
              <bitRange>[7:6]</bitRange>
              <access>read-write</access>
              <enumeratedValues />
            </field>
            <field>
              <name>BAUD</name>
              <description>BAUD  field description</description>
              <bitRange>[5:3]</bitRange>
              <access>read-write</access>
              <enumeratedValues />
            </field>
            <field>
              <name>LSBF</name>
              <description>LSBF  field description</description>
              <bitRange>[2:2]</bitRange>
              <access>read-write</access>
              <enumeratedValues />
            </field>
            <field>
              <name>CPHOL</name>
              <description>CPHOL  field description</description>
              <bitRange>[1:1]</bitRange>
              <access>read-write</access>
              <enumeratedValues />
            </field>
            <field>
              <name>CPHA</name>
              <description>CPHA  field description</description>
              <bitRange>[0:0]</bitRange>
              <access>read-write</access>
              <enumeratedValues />
            </field>
          </fields>
        </register>
        <register>
          <name>CR2</name>
          <description>SPI4 Control Register2</description>
          <addressOffset>0x4</addressOffset>
          <size>32</size>
          <access>read-write</access>
          <resetValue>0x00000054</resetValue>
          <fields>
            <field>
              <name>DUMMY_EN</name>
              <description>DUMMY_EN  field description</description>
              <bitRange>[15:15]</bitRange>
              <access>read-write</access>
              <enumeratedValues>
                <enumeratedValue>
                  <name />
                  <description>不插入dummy cycle</description>
                  <value>0</value>
                </enumeratedValue>
                <enumeratedValue>
                  <name />
                  <description>在读命令之后插入一个dummy cycle</description>
                  <value>1</value>
                </enumeratedValue>
              </enumeratedValues>
            </field>
            <field>
              <name>RXO</name>
              <description>RXO  field description</description>
              <bitRange>[11:11]</bitRange>
              <access>read-write</access>
              <enumeratedValues>
                <enumeratedValue>
                  <name />
                  <description>启动Master的单接收模式</description>
                  <value>1</value>
                </enumeratedValue>
                <enumeratedValue>
                  <name />
                  <description>关闭单接收模式（收发全双工）</description>
                  <value>0</value>
                </enumeratedValue>
              </enumeratedValues>
            </field>
            <field>
              <name>DLEN</name>
              <description>DLEN  field description</description>
              <bitRange>[10:9]</bitRange>
              <access>read-write</access>
              <enumeratedValues>
                <enumeratedValue>
                  <name />
                  <description>8bit</description>
                  <value>0</value>
                </enumeratedValue>
                <enumeratedValue>
                  <name />
                  <description>16bit</description>
                  <value>1</value>
                </enumeratedValue>
                <enumeratedValue>
                  <name />
                  <description>24bit</description>
                  <value>2</value>
                </enumeratedValue>
                <enumeratedValue>
                  <name />
                  <description>32bit</description>
                  <value>3</value>
                </enumeratedValue>
              </enumeratedValues>
            </field>
            <field>
              <name>HALFDUPLEX</name>
              <description>HALFDUPLEX  field description</description>
              <bitRange>[8:8]</bitRange>
              <access>read-write</access>
              <enumeratedValues>
                <enumeratedValue>
                  <name />
                  <description>标准SPI模式，4线全双工</description>
                  <value>0</value>
                </enumeratedValue>
                <enumeratedValue>
                  <name />
                  <description>DCN模式，4线半双工</description>
                  <value>1</value>
                </enumeratedValue>
              </enumeratedValues>
            </field>
            <field>
              <name>HD_RW</name>
              <description>HD_RW  field description</description>
              <bitRange>[7:7]</bitRange>
              <access>read-write</access>
              <enumeratedValues>
                <enumeratedValue>
                  <name />
                  <description>4线半双工协议下主机写入从机</description>
                  <value>0</value>
                </enumeratedValue>
                <enumeratedValue>
                  <name />
                  <description>4线半双工协议下主机读取从机</description>
                  <value>1</value>
                </enumeratedValue>
              </enumeratedValues>
            </field>
            <field>
              <name>CMD8b</name>
              <description>CMD8b  field description</description>
              <bitRange>[6:6]</bitRange>
              <access>read-write</access>
              <enumeratedValues>
                <enumeratedValue>
                  <name />
                  <description>command帧固定为8bit</description>
                  <value>1</value>
                </enumeratedValue>
                <enumeratedValue>
                  <name />
                  <description>command帧长度由DLEN定义</description>
                  <value>0</value>
                </enumeratedValue>
              </enumeratedValues>
            </field>
            <field>
              <name>SSNM</name>
              <description>SSNM  field description</description>
              <bitRange>[5:5]</bitRange>
              <access>read-write</access>
              <enumeratedValues>
                <enumeratedValue>
                  <name />
                  <description>每发送完一帧后Master拉高SSN，维持高电平时间由WAIT寄存器控制</description>
                  <value>1</value>
                </enumeratedValue>
                <enumeratedValue>
                  <name />
                  <description>每发送完一帧后Master保持SSN为低</description>
                  <value>0</value>
                </enumeratedValue>
              </enumeratedValues>
            </field>
            <field>
              <name>TXO_AC</name>
              <description>TXO_AC  field description</description>
              <bitRange>[4:4]</bitRange>
              <access>read-write</access>
              <enumeratedValues />
            </field>
            <field>
              <name>TXO</name>
              <description>TXO  field description</description>
              <bitRange>[3:3]</bitRange>
              <access>read-write</access>
              <enumeratedValues>
                <enumeratedValue>
                  <name />
                  <description>启动Master的单发送模式</description>
                  <value>1</value>
                </enumeratedValue>
                <enumeratedValue>
                  <name />
                  <description>关闭单发送模式（收发全双工）</description>
                  <value>0</value>
                </enumeratedValue>
              </enumeratedValues>
            </field>
            <field>
              <name>SSN</name>
              <description>SSN  field description</description>
              <bitRange>[2:2]</bitRange>
              <access>read-write</access>
              <enumeratedValues>
                <enumeratedValue>
                  <name />
                  <description>SSN输出高电平</description>
                  <value>1</value>
                </enumeratedValue>
                <enumeratedValue>
                  <name />
                  <description>SSN输出低电平</description>
                  <value>0</value>
                </enumeratedValue>
              </enumeratedValues>
            </field>
            <field>
              <name>SSNSEN</name>
              <description>SSNSEN  field description</description>
              <bitRange>[1:1]</bitRange>
              <access>read-write</access>
              <enumeratedValues>
                <enumeratedValue>
                  <name />
                  <description>Master模式下SSN输出由软件控制</description>
                  <value>1</value>
                </enumeratedValue>
                <enumeratedValue>
                  <name />
                  <description>Master模式下SSN输出由硬件自动控制</description>
                  <value>0</value>
                </enumeratedValue>
              </enumeratedValues>
            </field>
            <field>
              <name>SPIEN</name>
              <description>SPIEN  field description</description>
              <bitRange>[0:0]</bitRange>
              <access>read-write</access>
              <enumeratedValues />
            </field>
          </fields>
        </register>
        <register>
          <name>CR3</name>
          <description>SPI4 Control Register3</description>
          <addressOffset>0x8</addressOffset>
          <size>32</size>
          <access>read-write</access>
          <resetValue>0x00000000</resetValue>
          <fields>
            <field>
              <name>TXBFC</name>
              <description>TXBFC  field description</description>
              <bitRange>[3:3]</bitRange>
              <access>write-only</access>
              <enumeratedValues />
            </field>
            <field>
              <name>RXBFC</name>
              <description>RXBFC  field description</description>
              <bitRange>[2:2]</bitRange>
              <access>write-only</access>
              <enumeratedValues />
            </field>
            <field>
              <name>MERRC</name>
              <description>MERRC  field description</description>
              <bitRange>[1:1]</bitRange>
              <access>write-only</access>
              <enumeratedValues />
            </field>
            <field>
              <name>SERRC</name>
              <description>SERRC  field description</description>
              <bitRange>[0:0]</bitRange>
              <access>write-only</access>
              <enumeratedValues />
            </field>
          </fields>
        </register>
        <register>
          <name>IER</name>
          <description>SPI4 Interrupt Enable Register</description>
          <addressOffset>0xc</addressOffset>
          <size>32</size>
          <access>read-write</access>
          <resetValue>0x00000000</resetValue>
          <fields>
            <field>
              <name>ERRIE</name>
              <description>ERRIE  field description</description>
              <bitRange>[2:2]</bitRange>
              <access>read-write</access>
              <enumeratedValues />
            </field>
            <field>
              <name>TXIE</name>
              <description>TXIE  field description</description>
              <bitRange>[1:1]</bitRange>
              <access>read-write</access>
              <enumeratedValues />
            </field>
            <field>
              <name>RXIE</name>
              <description>RXIE  field description</description>
              <bitRange>[0:0]</bitRange>
              <access>read-write</access>
              <enumeratedValues />
            </field>
          </fields>
        </register>
        <register>
          <name>ISR</name>
          <description>SPI4 Status Register</description>
          <addressOffset>0x10</addressOffset>
          <size>32</size>
          <access>read-write</access>
          <resetValue>0x00001002</resetValue>
          <fields>
            <field>
              <name>DCN_TX</name>
              <description>DCN_TX  field description</description>
              <bitRange>[12:12]</bitRange>
              <access>read-write</access>
              <enumeratedValues>
                <enumeratedValue>
                  <name />
                  <description>DCN=0，表示命令帧</description>
                  <value>0</value>
                </enumeratedValue>
                <enumeratedValue>
                  <name />
                  <description>DCN=1，表示数据帧</description>
                  <value>1</value>
                </enumeratedValue>
              </enumeratedValues>
            </field>
            <field>
              <name>RXCOL</name>
              <description>RXCOL  field description</description>
              <bitRange>[10:10]</bitRange>
              <access>read-write</access>
              <enumeratedValues />
            </field>
            <field>
              <name>TXCOL</name>
              <description>TXCOL  field description</description>
              <bitRange>[9:9]</bitRange>
              <access>read-write</access>
              <enumeratedValues />
            </field>
            <field>
              <name>BUSY</name>
              <description>BUSY  field description</description>
              <bitRange>[8:8]</bitRange>
              <access>read-only</access>
              <enumeratedValues>
                <enumeratedValue>
                  <name />
                  <description>SPI传输进行中</description>
                  <value>1</value>
                </enumeratedValue>
                <enumeratedValue>
                  <name />
                  <description>SPI传输空闲</description>
                  <value>0</value>
                </enumeratedValue>
              </enumeratedValues>
            </field>
            <field>
              <name>MERR</name>
              <description>MERR  field description</description>
              <bitRange>[6:6]</bitRange>
              <access>read-only</access>
              <enumeratedValues />
            </field>
            <field>
              <name>SERR</name>
              <description>SERR  field description</description>
              <bitRange>[5:5]</bitRange>
              <access>read-only</access>
              <enumeratedValues />
            </field>
            <field>
              <name>TXBE</name>
              <description>TXBE  field description</description>
              <bitRange>[1:1]</bitRange>
              <access>read-only</access>
              <enumeratedValues>
                <enumeratedValue>
                  <name />
                  <description>发送缓存空，软件写TXBUF清零</description>
                  <value>1</value>
                </enumeratedValue>
                <enumeratedValue>
                  <name />
                  <description>发送缓存满</description>
                  <value>0</value>
                </enumeratedValue>
              </enumeratedValues>
            </field>
            <field>
              <name>RXBF</name>
              <description>RXBF  field description</description>
              <bitRange>[0:0]</bitRange>
              <access>read-only</access>
              <enumeratedValues>
                <enumeratedValue>
                  <name />
                  <description>接收缓存满，软件读RXBUF清零</description>
                  <value>1</value>
                </enumeratedValue>
                <enumeratedValue>
                  <name />
                  <description>接收缓存空</description>
                  <value>0</value>
                </enumeratedValue>
              </enumeratedValues>
            </field>
          </fields>
        </register>
        <register>
          <name>TXBUF</name>
          <description>SPI4 Transmit Buffer</description>
          <addressOffset>0x14</addressOffset>
          <size>32</size>
          <access>read-write</access>
          <resetValue>0x00000000</resetValue>
          <fields>
            <field>
              <name>TXBUF</name>
              <description>TXBUF  field description</description>
              <bitRange>[31:0]</bitRange>
              <access>write-only</access>
              <enumeratedValues />
            </field>
          </fields>
        </register>
        <register>
          <name>RXBUF</name>
          <description>SPI4 Receive Buffer</description>
          <addressOffset>0x18</addressOffset>
          <size>32</size>
          <access>read-write</access>
          <resetValue>0x00000000</resetValue>
          <fields>
            <field>
              <name>RXBUF</name>
              <description>RXBUF  field description</description>
              <bitRange>[31:0]</bitRange>
              <access>read-only</access>
              <enumeratedValues />
            </field>
          </fields>
        </register>
      </registers>
    </peripheral>
    <peripheral>
      <name>U7816</name>
      <description>U7816 module information</description>
      <groupName>U7816</groupName>
      <baseAddress>0x40011c00</baseAddress>
      <size>32</size>
      <access>read-write</access>
      <addressBlock>
        <offset>0</offset>
        <size>0x24</size>
        <usage>registers</usage>
      </addressBlock>
      <registers>
        <register>
          <name>CR</name>
          <description>U7816 Control Register</description>
          <addressOffset>0x0</addressOffset>
          <size>32</size>
          <access>read-write</access>
          <resetValue>0x00000000</resetValue>
          <fields>
            <field>
              <name>TXEN</name>
              <description>TXEN  field description</description>
              <bitRange>[5:5]</bitRange>
              <access>read-write</access>
              <enumeratedValues />
            </field>
            <field>
              <name>RXEN</name>
              <description>RXEN  field description</description>
              <bitRange>[4:4]</bitRange>
              <access>read-write</access>
              <enumeratedValues />
            </field>
            <field>
              <name>CKOEN</name>
              <description>CKOEN  field description</description>
              <bitRange>[3:3]</bitRange>
              <access>read-write</access>
              <enumeratedValues />
            </field>
            <field>
              <name>HPUAT</name>
              <description>HPUAT  field description</description>
              <bitRange>[2:2]</bitRange>
              <access>read-write</access>
              <enumeratedValues />
            </field>
            <field>
              <name>HPUEN</name>
              <description>HPUEN  field description</description>
              <bitRange>[1:1]</bitRange>
              <access>read-write</access>
              <enumeratedValues />
            </field>
          </fields>
        </register>
        <register>
          <name>FFR</name>
          <description>U7816 Frame Format Register</description>
          <addressOffset>0x4</addressOffset>
          <size>32</size>
          <access>read-write</access>
          <resetValue>0x00000006</resetValue>
          <fields>
            <field>
              <name>SFREN</name>
              <description>SFREN  field description</description>
              <bitRange>[11:11]</bitRange>
              <access>read-write</access>
              <enumeratedValues />
            </field>
            <field>
              <name>ERSW</name>
              <description>ERSW  field description</description>
              <bitRange>[10:9]</bitRange>
              <access>read-write</access>
              <enumeratedValues />
            </field>
            <field>
              <name>ERSGD</name>
              <description>ERSGD  field description</description>
              <bitRange>[8:8]</bitRange>
              <access>read-write</access>
              <enumeratedValues>
                <enumeratedValue>
                  <name />
                  <description>ERROR SIGNAL</description>
                  <value>0</value>
                </enumeratedValue>
              </enumeratedValues>
            </field>
            <field>
              <name>BGTEN</name>
              <description>BGTEN  field description</description>
              <bitRange>[7:7]</bitRange>
              <access>read-write</access>
              <enumeratedValues />
            </field>
            <field>
              <name>REP_T</name>
              <description>REP_T  field description</description>
              <bitRange>[6:6]</bitRange>
              <access>read-write</access>
              <enumeratedValues />
            </field>
            <field>
              <name>PAR</name>
              <description>PAR  field description</description>
              <bitRange>[5:4]</bitRange>
              <access>read-write</access>
              <enumeratedValues />
            </field>
            <field>
              <name>RFREN</name>
              <description>RFREN  field description</description>
              <bitRange>[3:3]</bitRange>
              <access>read-write</access>
              <enumeratedValues />
            </field>
            <field>
              <name>TREPEN</name>
              <description>TREPEN  field description</description>
              <bitRange>[2:2]</bitRange>
              <access>read-write</access>
              <enumeratedValues />
            </field>
            <field>
              <name>RREPEN</name>
              <description>RREPEN  field description</description>
              <bitRange>[1:1]</bitRange>
              <access>read-write</access>
              <enumeratedValues />
            </field>
            <field>
              <name>DICONV</name>
              <description>DICONV  field description</description>
              <bitRange>[0:0]</bitRange>
              <access>read-write</access>
              <enumeratedValues />
            </field>
          </fields>
        </register>
        <register>
          <name>EGTR</name>
          <description>U7816 Extra Guard Time Register</description>
          <addressOffset>0x8</addressOffset>
          <size>32</size>
          <access>read-write</access>
          <resetValue>0x00000000</resetValue>
          <fields>
            <field>
              <name>TXEGT</name>
              <description>TXEGT  field description</description>
              <bitRange>[7:0]</bitRange>
              <access>read-write</access>
              <enumeratedValues />
            </field>
          </fields>
        </register>
        <register>
          <name>PSC</name>
          <description>U7816 Prescaler Register</description>
          <addressOffset>0xc</addressOffset>
          <size>32</size>
          <access>read-write</access>
          <resetValue>0x00000000</resetValue>
          <fields>
            <field>
              <name>CLKDIV</name>
              <description>CLKDIV  field description</description>
              <bitRange>[4:0]</bitRange>
              <access>read-write</access>
              <enumeratedValues />
            </field>
          </fields>
        </register>
        <register>
          <name>BGR</name>
          <description>U7816 Baud rate Generator Register</description>
          <addressOffset>0x10</addressOffset>
          <size>32</size>
          <access>read-write</access>
          <resetValue>0x00000100</resetValue>
          <fields>
            <field>
              <name>PDIV</name>
              <description>PDIV  field description</description>
              <bitRange>[11:0]</bitRange>
              <access>read-write</access>
              <enumeratedValues>
                <enumeratedValue>
                  <name />
                  <description>PDIV最小可用值是0x1，应用禁止配置0x0</description>
                  <value>0</value>
                </enumeratedValue>
              </enumeratedValues>
            </field>
          </fields>
        </register>
        <register>
          <name>RXBUF</name>
          <description>U7816 Receive Buffer</description>
          <addressOffset>0x14</addressOffset>
          <size>32</size>
          <access>read-write</access>
          <resetValue>0x00000000</resetValue>
          <fields>
            <field>
              <name>RXBUF</name>
              <description>RXBUF  field description</description>
              <bitRange>[7:0]</bitRange>
              <access>read-only</access>
              <enumeratedValues />
            </field>
          </fields>
        </register>
        <register>
          <name>TXBUF</name>
          <description>U7816 Transmit Buffer</description>
          <addressOffset>0x18</addressOffset>
          <size>32</size>
          <access>read-write</access>
          <resetValue>0x00000000</resetValue>
          <fields>
            <field>
              <name>TXBUF</name>
              <description>TXBUF  field description</description>
              <bitRange>[7:0]</bitRange>
              <access>write-only</access>
              <enumeratedValues />
            </field>
          </fields>
        </register>
        <register>
          <name>IER</name>
          <description>U7816 Interrupt Enable Register</description>
          <addressOffset>0x1c</addressOffset>
          <size>32</size>
          <access>read-write</access>
          <resetValue>0x00000000</resetValue>
          <fields>
            <field>
              <name>RXIE</name>
              <description>RXIE  field description</description>
              <bitRange>[2:2]</bitRange>
              <access>read-write</access>
              <enumeratedValues />
            </field>
            <field>
              <name>TXIE</name>
              <description>TXIE  field description</description>
              <bitRange>[1:1]</bitRange>
              <access>read-write</access>
              <enumeratedValues />
            </field>
            <field>
              <name>LSIE</name>
              <description>LSIE  field description</description>
              <bitRange>[0:0]</bitRange>
              <access>read-write</access>
              <enumeratedValues />
            </field>
          </fields>
        </register>
        <register>
          <name>ISR</name>
          <description>U7816 Interrupt Status Register</description>
          <addressOffset>0x20</addressOffset>
          <size>32</size>
          <access>read-write</access>
          <resetValue>0x00000002</resetValue>
          <fields>
            <field>
              <name>WAIT_RPT</name>
              <description>WAIT_RPT  field description</description>
              <bitRange>[18:18]</bitRange>
              <access>read-only</access>
              <enumeratedValues />
            </field>
            <field>
              <name>TXBUSY</name>
              <description>TXBUSY  field description</description>
              <bitRange>[17:17]</bitRange>
              <access>read-only</access>
              <enumeratedValues />
            </field>
            <field>
              <name>RXBUSY</name>
              <description>RXBUSY  field description</description>
              <bitRange>[16:16]</bitRange>
              <access>read-only</access>
              <enumeratedValues />
            </field>
            <field>
              <name>TPARERR</name>
              <description>TPARERR  field description</description>
              <bitRange>[11:11]</bitRange>
              <access>read-write</access>
              <enumeratedValues />
            </field>
            <field>
              <name>RPARERR</name>
              <description>RPARERR  field description</description>
              <bitRange>[10:10]</bitRange>
              <access>read-write</access>
              <enumeratedValues />
            </field>
            <field>
              <name>FRERR</name>
              <description>FRERR  field description</description>
              <bitRange>[9:9]</bitRange>
              <access>read-write</access>
              <enumeratedValues />
            </field>
            <field>
              <name>OVERR</name>
              <description>OVERR  field description</description>
              <bitRange>[8:8]</bitRange>
              <access>read-write</access>
              <enumeratedValues />
            </field>
            <field>
              <name>RXIF</name>
              <description>RXIF  field description</description>
              <bitRange>[2:2]</bitRange>
              <access>read-only</access>
              <enumeratedValues />
            </field>
            <field>
              <name>TXIF</name>
              <description>TXIF  field description</description>
              <bitRange>[1:1]</bitRange>
              <access>read-only</access>
              <enumeratedValues />
            </field>
            <field>
              <name>ERRIF</name>
              <description>ERRIF  field description</description>
              <bitRange>[0:0]</bitRange>
              <access>read-only</access>
              <enumeratedValues />
            </field>
          </fields>
        </register>
      </registers>
    </peripheral>
    <peripheral>
      <name>QSPI</name>
      <description>QSPI module information</description>
      <groupName>QSPI</groupName>
      <baseAddress>0x40000800</baseAddress>
      <size>32</size>
      <access>read-write</access>
      <addressBlock>
        <offset>0</offset>
        <size>0x30</size>
        <usage>registers</usage>
      </addressBlock>
      <registers>
        <register>
          <name>CR</name>
          <description>QSPI Control Register</description>
          <addressOffset>0x0</addressOffset>
          <size>32</size>
          <access>read-write</access>
          <resetValue>0x00000000</resetValue>
          <fields>
            <field>
              <name>PRESCALER</name>
              <description>PRESCALER  field description</description>
              <bitRange>[31:24]</bitRange>
              <access>read-write</access>
              <enumeratedValues>
                <enumeratedValue>
                  <name />
                  <description>FQSPI_CLK = FAHB/2</description>
                  <value>0</value>
                </enumeratedValue>
                <enumeratedValue>
                  <name />
                  <description>FQSPI_CLK = FAHB/2</description>
                  <value>1</value>
                </enumeratedValue>
                <enumeratedValue>
                  <name />
                  <description>FQSPI_CLK = FAHB/3</description>
                  <value>2</value>
                </enumeratedValue>
                <enumeratedValue>
                  <name />
                  <description>FQSPI_CLK = FAHB/256</description>
                  <value>ff</value>
                </enumeratedValue>
                <enumeratedValue>
                  <name />
                  <description>对于奇数分频，时钟占空比不是50%，高电平比低电平长一个AHBCLK周期</description>
                  <value>0</value>
                </enumeratedValue>
              </enumeratedValues>
            </field>
            <field>
              <name>PMM</name>
              <description>PMM  field description</description>
              <bitRange>[23:23]</bitRange>
              <access>read-write</access>
              <enumeratedValues>
                <enumeratedValue>
                  <name />
                  <description>AND模式，所有bit都匹配才置位SMF</description>
                  <value>0</value>
                </enumeratedValue>
                <enumeratedValue>
                  <name />
                  <description>OR模式，至少1bit匹配就会置位SMF</description>
                  <value>1</value>
                </enumeratedValue>
              </enumeratedValues>
            </field>
            <field>
              <name>TOIE</name>
              <description>TOIE  field description</description>
              <bitRange>[20:20]</bitRange>
              <access>read-write</access>
              <enumeratedValues>
                <enumeratedValue>
                  <name />
                  <description>禁止超时中断</description>
                  <value>0</value>
                </enumeratedValue>
                <enumeratedValue>
                  <name />
                  <description>允许超时中断</description>
                  <value>1</value>
                </enumeratedValue>
              </enumeratedValues>
            </field>
            <field>
              <name>SMIE</name>
              <description>SMIE  field description</description>
              <bitRange>[19:19]</bitRange>
              <access>read-write</access>
              <enumeratedValues>
                <enumeratedValue>
                  <name />
                  <description>禁止状态匹配中断</description>
                  <value>0</value>
                </enumeratedValue>
                <enumeratedValue>
                  <name />
                  <description>允许状态匹配中断</description>
                  <value>1</value>
                </enumeratedValue>
              </enumeratedValues>
            </field>
            <field>
              <name>FTIE</name>
              <description>FTIE  field description</description>
              <bitRange>[18:18]</bitRange>
              <access>read-write</access>
              <enumeratedValues>
                <enumeratedValue>
                  <name />
                  <description>禁止FIFO水位中断</description>
                  <value>0</value>
                </enumeratedValue>
                <enumeratedValue>
                  <name />
                  <description>允许FIFO水位中断</description>
                  <value>1</value>
                </enumeratedValue>
              </enumeratedValues>
            </field>
            <field>
              <name>TCIE</name>
              <description>TCIE  field description</description>
              <bitRange>[17:17]</bitRange>
              <access>read-write</access>
              <enumeratedValues>
                <enumeratedValue>
                  <name />
                  <description>禁止传输完成中断</description>
                  <value>0</value>
                </enumeratedValue>
                <enumeratedValue>
                  <name />
                  <description>允许传输完成中断</description>
                  <value>1</value>
                </enumeratedValue>
              </enumeratedValues>
            </field>
            <field>
              <name>TEIE</name>
              <description>TEIE  field description</description>
              <bitRange>[16:16]</bitRange>
              <access>read-write</access>
              <enumeratedValues>
                <enumeratedValue>
                  <name />
                  <description>禁止传输错误中断</description>
                  <value>0</value>
                </enumeratedValue>
                <enumeratedValue>
                  <name />
                  <description>允许传输错误中断</description>
                  <value>1</value>
                </enumeratedValue>
              </enumeratedValues>
            </field>
            <field>
              <name>FIFOTHR</name>
              <description>FIFOTHR  field description</description>
              <bitRange>[11:8]</bitRange>
              <access>read-write</access>
              <enumeratedValues>
                <enumeratedValue>
                  <name />
                  <description />
                  <value>0</value>
                </enumeratedValue>
                <enumeratedValue>
                  <name />
                  <description>FTF在FIFO空字节大于等于1时置位</description>
                  <value>0</value>
                </enumeratedValue>
                <enumeratedValue>
                  <name />
                  <description>FTF在FIFO空字节大于等于2时置位</description>
                  <value>1</value>
                </enumeratedValue>
                <enumeratedValue>
                  <name />
                  <description>FTF在FIFO空字节等于16时置位</description>
                  <value>f</value>
                </enumeratedValue>
                <enumeratedValue>
                  <name />
                  <description />
                  <value>0</value>
                </enumeratedValue>
                <enumeratedValue>
                  <name />
                  <description>FTF在FIFO中字节数大于等于1时置位</description>
                  <value>0</value>
                </enumeratedValue>
                <enumeratedValue>
                  <name />
                  <description>FTF在FIFO中字节数大于等于2时置位</description>
                  <value>1</value>
                </enumeratedValue>
                <enumeratedValue>
                  <name />
                  <description>FTF在FIFO中字节数等于16时置位</description>
                  <value>f</value>
                </enumeratedValue>
              </enumeratedValues>
            </field>
            <field>
              <name>SSHFT</name>
              <description>SSHFT  field description</description>
              <bitRange>[4:4]</bitRange>
              <access>read-write</access>
              <enumeratedValues>
                <enumeratedValue>
                  <name />
                  <description>关闭延迟采样功能</description>
                  <value>0</value>
                </enumeratedValue>
                <enumeratedValue>
                  <name />
                  <description>使能延迟采样功能</description>
                  <value>1</value>
                </enumeratedValue>
              </enumeratedValues>
            </field>
            <field>
              <name>TCEN</name>
              <description>TCEN  field description</description>
              <bitRange>[3:3]</bitRange>
              <access>read-write</access>
              <enumeratedValues>
                <enumeratedValue>
                  <name />
                  <description>关闭超时功能</description>
                  <value>0</value>
                </enumeratedValue>
                <enumeratedValue>
                  <name />
                  <description>使能超时功能</description>
                  <value>1</value>
                </enumeratedValue>
              </enumeratedValues>
            </field>
            <field>
              <name>DMAEN</name>
              <description>DMAEN  field description</description>
              <bitRange>[2:2]</bitRange>
              <access>read-write</access>
              <enumeratedValues>
                <enumeratedValue>
                  <name />
                  <description>DMA功能关闭，QuadSPI不会发送DMA请求</description>
                  <value>0</value>
                </enumeratedValue>
                <enumeratedValue>
                  <name />
                  <description>DMA功能开启，QuadSPI在满足条件时发送DMA请求</description>
                  <value>1</value>
                </enumeratedValue>
              </enumeratedValues>
            </field>
            <field>
              <name>ABORT</name>
              <description>ABORT  field description</description>
              <bitRange>[1:1]</bitRange>
              <access>read-write</access>
              <enumeratedValues />
            </field>
            <field>
              <name>EN</name>
              <description>EN  field description</description>
              <bitRange>[0:0]</bitRange>
              <access>read-write</access>
              <enumeratedValues>
                <enumeratedValue>
                  <name />
                  <description>关闭QuadSPI</description>
                  <value>0</value>
                </enumeratedValue>
                <enumeratedValue>
                  <name />
                  <description>使能QuadSPI</description>
                  <value>1</value>
                </enumeratedValue>
              </enumeratedValues>
            </field>
          </fields>
        </register>
        <register>
          <name>CFGR</name>
          <description>QSPI Config Register</description>
          <addressOffset>0x4</addressOffset>
          <size>32</size>
          <access>read-write</access>
          <resetValue>0x00000000</resetValue>
          <fields>
            <field>
              <name>CSHT</name>
              <description>CSHT  field description</description>
              <bitRange>[10:8]</bitRange>
              <access>read-write</access>
              <enumeratedValues>
                <enumeratedValue>
                  <name />
                  <description>至少1 cycle</description>
                  <value>0</value>
                </enumeratedValue>
                <enumeratedValue>
                  <name />
                  <description>至少2 cycles</description>
                  <value>1</value>
                </enumeratedValue>
                <enumeratedValue>
                  <name />
                  <description>至少8 cycles</description>
                  <value>7</value>
                </enumeratedValue>
              </enumeratedValues>
            </field>
            <field>
              <name>CKMODE</name>
              <description>CKMODE  field description</description>
              <bitRange>[0:0]</bitRange>
              <access>read-write</access>
              <enumeratedValues>
                <enumeratedValue>
                  <name />
                  <description>mode 0</description>
                  <value>0</value>
                </enumeratedValue>
                <enumeratedValue>
                  <name />
                  <description>mode 3</description>
                  <value>1</value>
                </enumeratedValue>
              </enumeratedValues>
            </field>
          </fields>
        </register>
        <register>
          <name>SR</name>
          <description>QSPI Status Register</description>
          <addressOffset>0x8</addressOffset>
          <size>32</size>
          <access>read-write</access>
          <resetValue>0x00000000</resetValue>
          <fields>
            <field>
              <name>FIFOLVL</name>
              <description>FIFOLVL  field description</description>
              <bitRange>[12:8]</bitRange>
              <access>read-only</access>
              <enumeratedValues />
            </field>
            <field>
              <name>BUSY</name>
              <description>BUSY  field description</description>
              <bitRange>[5:5]</bitRange>
              <access>read-only</access>
              <enumeratedValues />
            </field>
            <field>
              <name>TOF</name>
              <description>TOF  field description</description>
              <bitRange>[4:4]</bitRange>
              <access>read-write</access>
              <enumeratedValues />
            </field>
            <field>
              <name>SMF</name>
              <description>SMF  field description</description>
              <bitRange>[3:3]</bitRange>
              <access>read-write</access>
              <enumeratedValues />
            </field>
            <field>
              <name>FTF</name>
              <description>FTF  field description</description>
              <bitRange>[2:2]</bitRange>
              <access>read-only</access>
              <enumeratedValues />
            </field>
            <field>
              <name>TCF</name>
              <description>TCF  field description</description>
              <bitRange>[1:1]</bitRange>
              <access>read-write</access>
              <enumeratedValues />
            </field>
          </fields>
        </register>
        <register>
          <name>DATALEN</name>
          <description>QSPI Data Length Register</description>
          <addressOffset>0xc</addressOffset>
          <size>32</size>
          <access>read-write</access>
          <resetValue>0x00000000</resetValue>
          <fields>
            <field>
              <name>QSPI_DATALEN</name>
              <description>QSPI_DATALEN  field description</description>
              <bitRange>[31:0]</bitRange>
              <access>read-write</access>
              <enumeratedValues />
            </field>
          </fields>
        </register>
        <register>
          <name>CCR</name>
          <description>QSPI Communication Config Register</description>
          <addressOffset>0x10</addressOffset>
          <size>32</size>
          <access>read-write</access>
          <resetValue>0x00000000</resetValue>
          <fields>
            <field>
              <name>CRM</name>
              <description>CRM  field description</description>
              <bitRange>[28:28]</bitRange>
              <access>read-write</access>
              <enumeratedValues>
                <enumeratedValue>
                  <name />
                  <description>每次通信发起时都要发送指令</description>
                  <value>0</value>
                </enumeratedValue>
                <enumeratedValue>
                  <name />
                  <description>只在第一次通信时发送指令</description>
                  <value>1</value>
                </enumeratedValue>
              </enumeratedValues>
            </field>
            <field>
              <name>OPMODE</name>
              <description>OPMODE  field description</description>
              <bitRange>[27:26]</bitRange>
              <access>read-write</access>
              <enumeratedValues>
                <enumeratedValue>
                  <name />
                  <description>外设写模式</description>
                  <value>0</value>
                </enumeratedValue>
                <enumeratedValue>
                  <name />
                  <description>外设读模式</description>
                  <value>1</value>
                </enumeratedValue>
                <enumeratedValue>
                  <name />
                  <description>自动查询模式</description>
                  <value>2</value>
                </enumeratedValue>
                <enumeratedValue>
                  <name />
                  <description>存储器映射模式</description>
                  <value>3</value>
                </enumeratedValue>
              </enumeratedValues>
            </field>
            <field>
              <name>DMODE</name>
              <description>DMODE  field description</description>
              <bitRange>[25:24]</bitRange>
              <access>read-write</access>
              <enumeratedValues>
                <enumeratedValue>
                  <name />
                  <description>无数据</description>
                  <value>0</value>
                </enumeratedValue>
                <enumeratedValue>
                  <name />
                  <description>单线</description>
                  <value>1</value>
                </enumeratedValue>
                <enumeratedValue>
                  <name />
                  <description>双线</description>
                  <value>2</value>
                </enumeratedValue>
                <enumeratedValue>
                  <name />
                  <description>四线</description>
                  <value>3</value>
                </enumeratedValue>
              </enumeratedValues>
            </field>
            <field>
              <name>DUMCYC</name>
              <description>DUMCYC  field description</description>
              <bitRange>[22:18]</bitRange>
              <access>read-write</access>
              <enumeratedValues />
            </field>
            <field>
              <name>ABSIZE</name>
              <description>ABSIZE  field description</description>
              <bitRange>[17:16]</bitRange>
              <access>read-write</access>
              <enumeratedValues>
                <enumeratedValue>
                  <name />
                  <description>8bits alternate bytes</description>
                  <value>0</value>
                </enumeratedValue>
                <enumeratedValue>
                  <name />
                  <description>16bits alternate bytes</description>
                  <value>1</value>
                </enumeratedValue>
                <enumeratedValue>
                  <name />
                  <description>24bits alternate bytes</description>
                  <value>2</value>
                </enumeratedValue>
                <enumeratedValue>
                  <name />
                  <description>32bits alternate bytes</description>
                  <value>3</value>
                </enumeratedValue>
              </enumeratedValues>
            </field>
            <field>
              <name>ABMODE</name>
              <description>ABMODE  field description</description>
              <bitRange>[15:14]</bitRange>
              <access>read-write</access>
              <enumeratedValues>
                <enumeratedValue>
                  <name />
                  <description>无alternate bytes</description>
                  <value>0</value>
                </enumeratedValue>
                <enumeratedValue>
                  <name />
                  <description>单线</description>
                  <value>1</value>
                </enumeratedValue>
                <enumeratedValue>
                  <name />
                  <description>双线</description>
                  <value>2</value>
                </enumeratedValue>
                <enumeratedValue>
                  <name />
                  <description>四线</description>
                  <value>3</value>
                </enumeratedValue>
              </enumeratedValues>
            </field>
            <field>
              <name>ADSIZE</name>
              <description>ADSIZE  field description</description>
              <bitRange>[13:12]</bitRange>
              <access>read-write</access>
              <enumeratedValues>
                <enumeratedValue>
                  <name />
                  <description>8bits地址</description>
                  <value>0</value>
                </enumeratedValue>
                <enumeratedValue>
                  <name />
                  <description>16bits地址</description>
                  <value>1</value>
                </enumeratedValue>
                <enumeratedValue>
                  <name />
                  <description>24bits地址</description>
                  <value>2</value>
                </enumeratedValue>
                <enumeratedValue>
                  <name />
                  <description>32bits地址</description>
                  <value>3</value>
                </enumeratedValue>
              </enumeratedValues>
            </field>
            <field>
              <name>ADMODE</name>
              <description>ADMODE  field description</description>
              <bitRange>[11:10]</bitRange>
              <access>read-write</access>
              <enumeratedValues>
                <enumeratedValue>
                  <name />
                  <description>无地址字节</description>
                  <value>0</value>
                </enumeratedValue>
                <enumeratedValue>
                  <name />
                  <description>单线</description>
                  <value>1</value>
                </enumeratedValue>
                <enumeratedValue>
                  <name />
                  <description>双线</description>
                  <value>2</value>
                </enumeratedValue>
                <enumeratedValue>
                  <name />
                  <description>四线</description>
                  <value>3</value>
                </enumeratedValue>
              </enumeratedValues>
            </field>
            <field>
              <name>IMODE</name>
              <description>IMODE  field description</description>
              <bitRange>[9:8]</bitRange>
              <access>read-write</access>
              <enumeratedValues>
                <enumeratedValue>
                  <name />
                  <description>无指令字节</description>
                  <value>0</value>
                </enumeratedValue>
                <enumeratedValue>
                  <name />
                  <description>单线</description>
                  <value>1</value>
                </enumeratedValue>
                <enumeratedValue>
                  <name />
                  <description>双线</description>
                  <value>2</value>
                </enumeratedValue>
                <enumeratedValue>
                  <name />
                  <description>四线</description>
                  <value>3</value>
                </enumeratedValue>
              </enumeratedValues>
            </field>
            <field>
              <name>INSTRUCTION</name>
              <description>INSTRUCTION  field description</description>
              <bitRange>[7:0]</bitRange>
              <access>read-write</access>
              <enumeratedValues />
            </field>
          </fields>
        </register>
        <register>
          <name>ADDR</name>
          <description>QSPI Address Register</description>
          <addressOffset>0x14</addressOffset>
          <size>32</size>
          <access>read-write</access>
          <resetValue>0x00000000</resetValue>
          <fields>
            <field>
              <name>QSPI_ADDR</name>
              <description>QSPI_ADDR  field description</description>
              <bitRange>[31:0]</bitRange>
              <access>read-write</access>
              <enumeratedValues />
            </field>
          </fields>
        </register>
        <register>
          <name>ABR</name>
          <description>QSPI Alternate Bytes Register</description>
          <addressOffset>0x18</addressOffset>
          <size>32</size>
          <access>read-write</access>
          <resetValue>0x00000000</resetValue>
          <fields>
            <field>
              <name>QSPI_ABR</name>
              <description>QSPI_ABR  field description</description>
              <bitRange>[31:0]</bitRange>
              <access>read-write</access>
              <enumeratedValues />
            </field>
          </fields>
        </register>
        <register>
          <name>DR</name>
          <description>QSPI Data Register</description>
          <addressOffset>0x1c</addressOffset>
          <size>32</size>
          <access>read-write</access>
          <resetValue>0x00000000</resetValue>
          <fields>
            <field>
              <name>QSPI_DATA</name>
              <description>QSPI_DATA  field description</description>
              <bitRange>[31:0]</bitRange>
              <access>read-write</access>
              <enumeratedValues />
            </field>
          </fields>
        </register>
        <register>
          <name>SMSK</name>
          <description>QSPI Status Mask Register</description>
          <addressOffset>0x20</addressOffset>
          <size>32</size>
          <access>read-write</access>
          <resetValue>0x00000000</resetValue>
          <fields>
            <field>
              <name>QSPI_SMSK</name>
              <description>QSPI_SMSK  field description</description>
              <bitRange>[31:0]</bitRange>
              <access>read-write</access>
              <enumeratedValues />
            </field>
          </fields>
        </register>
        <register>
          <name>SMAT</name>
          <description>QSPI Status Match Register</description>
          <addressOffset>0x24</addressOffset>
          <size>32</size>
          <access>read-write</access>
          <resetValue>0x00000000</resetValue>
          <fields>
            <field>
              <name>QSPI_SMAT</name>
              <description>QSPI_SMAT  field description</description>
              <bitRange>[31:0]</bitRange>
              <access>read-write</access>
              <enumeratedValues />
            </field>
          </fields>
        </register>
        <register>
          <name>PITV</name>
          <description>QSPI Polling Interval Register</description>
          <addressOffset>0x28</addressOffset>
          <size>32</size>
          <access>read-write</access>
          <resetValue>0x00000000</resetValue>
          <fields>
            <field>
              <name>QSPI_PITV</name>
              <description>QSPI_PITV  field description</description>
              <bitRange>[15:0]</bitRange>
              <access>read-write</access>
              <enumeratedValues />
            </field>
          </fields>
        </register>
        <register>
          <name>TO</name>
          <description>QSPI Time Out Register</description>
          <addressOffset>0x2c</addressOffset>
          <size>32</size>
          <access>read-write</access>
          <resetValue>0x00000000</resetValue>
          <fields>
            <field>
              <name>QSPI_TO</name>
              <description>QSPI_TO  field description</description>
              <bitRange>[15:0]</bitRange>
              <access>read-write</access>
              <enumeratedValues />
            </field>
          </fields>
        </register>
      </registers>
    </peripheral>
    <peripheral>
      <name>DMA</name>
      <description>DMA module information</description>
      <groupName>DMA</groupName>
      <baseAddress>0x40000400</baseAddress>
      <size>32</size>
      <access>read-write</access>
      <addressBlock>
        <offset>0</offset>
        <size>0x138</size>
        <usage>registers</usage>
      </addressBlock>
      <registers>
        <register>
          <name>GCR</name>
          <description>DMA Global Control Register</description>
          <addressOffset>0x0</addressOffset>
          <size>32</size>
          <access>read-write</access>
          <resetValue>0x00000000</resetValue>
          <fields>
            <field>
              <name>DMA_ADDRERR_EN</name>
              <description>DMA_ADDRERR_EN  field description</description>
              <bitRange>[1:1]</bitRange>
              <access>read-write</access>
              <enumeratedValues>
                <enumeratedValue>
                  <name />
                  <description>允许错误地址中断</description>
                  <value>1</value>
                </enumeratedValue>
                <enumeratedValue>
                  <name />
                  <description>禁止错误地址中断</description>
                  <value>0</value>
                </enumeratedValue>
              </enumeratedValues>
            </field>
            <field>
              <name>DMAEN</name>
              <description>DMAEN  field description</description>
              <bitRange>[0:0]</bitRange>
              <access>read-write</access>
              <enumeratedValues>
                <enumeratedValue>
                  <name />
                  <description>DMA使能</description>
                  <value>1</value>
                </enumeratedValue>
                <enumeratedValue>
                  <name />
                  <description>DMA关闭</description>
                  <value>0</value>
                </enumeratedValue>
              </enumeratedValues>
            </field>
          </fields>
        </register>
        <register>
          <name>CH0CR</name>
          <description>Channel 0 Control Register</description>
          <addressOffset>0x4</addressOffset>
          <size>32</size>
          <access>read-write</access>
          <resetValue>0x00000000</resetValue>
          <fields>
            <field>
              <name>CHxTSIZE</name>
              <description>CHxTSIZE  field description</description>
              <bitRange>[28:16]</bitRange>
              <access>read-write</access>
              <enumeratedValues />
            </field>
            <field>
              <name>CHxPRI</name>
              <description>CHxPRI  field description</description>
              <bitRange>[13:12]</bitRange>
              <access>read-write</access>
              <enumeratedValues>
                <enumeratedValue>
                  <name />
                  <description>Low</description>
                  <value>0</value>
                </enumeratedValue>
                <enumeratedValue>
                  <name />
                  <description>Medium</description>
                  <value>1</value>
                </enumeratedValue>
                <enumeratedValue>
                  <name />
                  <description>High</description>
                  <value>2</value>
                </enumeratedValue>
                <enumeratedValue>
                  <name />
                  <description>Very High</description>
                  <value>3</value>
                </enumeratedValue>
              </enumeratedValues>
            </field>
            <field>
              <name>CHxINC</name>
              <description>CHxINC  field description</description>
              <bitRange>[11:11]</bitRange>
              <access>read-write</access>
              <enumeratedValues>
                <enumeratedValue>
                  <name />
                  <description>RAM地址递增</description>
                  <value>1</value>
                </enumeratedValue>
                <enumeratedValue>
                  <name />
                  <description>RAM地址递减</description>
                  <value>0</value>
                </enumeratedValue>
              </enumeratedValues>
            </field>
            <field>
              <name>CHxSSEL</name>
              <description>CHxSSEL  field description</description>
              <bitRange>[10:8]</bitRange>
              <access>read-write</access>
              <enumeratedValues />
            </field>
            <field>
              <name>CIRC_UPD</name>
              <description>CIRC_UPD  field description</description>
              <bitRange>[7:7]</bitRange>
              <access>read-write</access>
              <enumeratedValues>
                <enumeratedValue>
                  <name />
                  <description>禁止自动更新</description>
                  <value>0</value>
                </enumeratedValue>
                <enumeratedValue>
                  <name />
                  <description>使能自动更新</description>
                  <value>1</value>
                </enumeratedValue>
                <enumeratedValue>
                  <name />
                  <description>仅通道0~6支持此功能，通道7~10无此寄存器</description>
                  <value>0</value>
                </enumeratedValue>
              </enumeratedValues>
            </field>
            <field>
              <name>DIR</name>
              <description>DIR  field description</description>
              <bitRange>[6:6]</bitRange>
              <access>read-write</access>
              <enumeratedValues>
                <enumeratedValue>
                  <name />
                  <description>从外设读取数据写入RAM</description>
                  <value>0</value>
                </enumeratedValue>
                <enumeratedValue>
                  <name />
                  <description>从RAM读取数据写入外设</description>
                  <value>1</value>
                </enumeratedValue>
              </enumeratedValues>
            </field>
            <field>
              <name>BDW</name>
              <description>BDW  field description</description>
              <bitRange>[5:4]</bitRange>
              <access>read-write</access>
              <enumeratedValues>
                <enumeratedValue>
                  <name />
                  <description>字节，8bit</description>
                  <value>0</value>
                </enumeratedValue>
                <enumeratedValue>
                  <name />
                  <description>半字，16bit</description>
                  <value>1</value>
                </enumeratedValue>
                <enumeratedValue>
                  <name />
                  <description>字，32bit</description>
                  <value>2</value>
                </enumeratedValue>
                <enumeratedValue>
                  <name />
                  <description>RFU</description>
                  <value>3</value>
                </enumeratedValue>
              </enumeratedValues>
            </field>
            <field>
              <name>CIRC</name>
              <description>CIRC  field description</description>
              <bitRange>[3:3]</bitRange>
              <access>read-write</access>
              <enumeratedValues>
                <enumeratedValue>
                  <name />
                  <description>关闭循环模式</description>
                  <value>0</value>
                </enumeratedValue>
                <enumeratedValue>
                  <name />
                  <description>使能循环模式</description>
                  <value>1</value>
                </enumeratedValue>
              </enumeratedValues>
            </field>
            <field>
              <name>CHxFTIE</name>
              <description>CHxFTIE  field description</description>
              <bitRange>[2:2]</bitRange>
              <access>read-write</access>
              <enumeratedValues>
                <enumeratedValue>
                  <name />
                  <description>使能传输完成中断</description>
                  <value>1</value>
                </enumeratedValue>
                <enumeratedValue>
                  <name />
                  <description>关闭传输完成中断</description>
                  <value>0</value>
                </enumeratedValue>
              </enumeratedValues>
            </field>
            <field>
              <name>CHxHTIE</name>
              <description>CHxHTIE  field description</description>
              <bitRange>[1:1]</bitRange>
              <access>read-write</access>
              <enumeratedValues>
                <enumeratedValue>
                  <name />
                  <description>使能半程中断</description>
                  <value>1</value>
                </enumeratedValue>
                <enumeratedValue>
                  <name />
                  <description>关闭半程中断</description>
                  <value>0</value>
                </enumeratedValue>
              </enumeratedValues>
            </field>
            <field>
              <name>CHxEN</name>
              <description>CHxEN  field description</description>
              <bitRange>[0:0]</bitRange>
              <access>read-write</access>
              <enumeratedValues>
                <enumeratedValue>
                  <name />
                  <description>启动通道0</description>
                  <value>1</value>
                </enumeratedValue>
                <enumeratedValue>
                  <name />
                  <description>关闭通道0</description>
                  <value>0</value>
                </enumeratedValue>
              </enumeratedValues>
            </field>
          </fields>
        </register>
        <register>
          <name>CH0MAR</name>
          <description>Channel 0 Memory Address Register</description>
          <addressOffset>0x8</addressOffset>
          <size>32</size>
          <access>read-write</access>
          <resetValue>0x00000000</resetValue>
          <fields>
            <field>
              <name>CHxMEMAD</name>
              <description>CHxMEMAD  field description</description>
              <bitRange>[31:0]</bitRange>
              <access>read-write</access>
              <enumeratedValues>
                <enumeratedValue>
                  <name />
                  <description>此指针禁止指向0x00080000~0x1FFFFFFF地址，这段地址为flash保留信息区，指向这段地址可能在DMA访问中导致不可预计的结果</description>
                  <value>0</value>
                </enumeratedValue>
              </enumeratedValues>
            </field>
          </fields>
        </register>
        <register>
          <name>CH1CR</name>
          <description>Channel 1 Control Register</description>
          <addressOffset>0xc</addressOffset>
          <size>32</size>
          <access>read-write</access>
          <resetValue>0x00000000</resetValue>
          <fields>
            <field>
              <name>CHxTSIZE</name>
              <description>CHxTSIZE  field description</description>
              <bitRange>[28:16]</bitRange>
              <access>read-write</access>
              <enumeratedValues />
            </field>
            <field>
              <name>CHxPRI</name>
              <description>CHxPRI  field description</description>
              <bitRange>[13:12]</bitRange>
              <access>read-write</access>
              <enumeratedValues>
                <enumeratedValue>
                  <name />
                  <description>Low</description>
                  <value>0</value>
                </enumeratedValue>
                <enumeratedValue>
                  <name />
                  <description>Medium</description>
                  <value>1</value>
                </enumeratedValue>
                <enumeratedValue>
                  <name />
                  <description>High</description>
                  <value>2</value>
                </enumeratedValue>
                <enumeratedValue>
                  <name />
                  <description>Very High</description>
                  <value>3</value>
                </enumeratedValue>
              </enumeratedValues>
            </field>
            <field>
              <name>CHxINC</name>
              <description>CHxINC  field description</description>
              <bitRange>[11:11]</bitRange>
              <access>read-write</access>
              <enumeratedValues>
                <enumeratedValue>
                  <name />
                  <description>RAM地址递增</description>
                  <value>1</value>
                </enumeratedValue>
                <enumeratedValue>
                  <name />
                  <description>RAM地址递减</description>
                  <value>0</value>
                </enumeratedValue>
              </enumeratedValues>
            </field>
            <field>
              <name>CHxSSEL</name>
              <description>CHxSSEL  field description</description>
              <bitRange>[10:8]</bitRange>
              <access>read-write</access>
              <enumeratedValues />
            </field>
            <field>
              <name>CIRC_UPD</name>
              <description>CIRC_UPD  field description</description>
              <bitRange>[7:7]</bitRange>
              <access>read-write</access>
              <enumeratedValues>
                <enumeratedValue>
                  <name />
                  <description>禁止自动更新</description>
                  <value>0</value>
                </enumeratedValue>
                <enumeratedValue>
                  <name />
                  <description>使能自动更新</description>
                  <value>1</value>
                </enumeratedValue>
                <enumeratedValue>
                  <name />
                  <description>仅通道0~6支持此功能，通道7~10无此寄存器</description>
                  <value>0</value>
                </enumeratedValue>
              </enumeratedValues>
            </field>
            <field>
              <name>DIR</name>
              <description>DIR  field description</description>
              <bitRange>[6:6]</bitRange>
              <access>read-write</access>
              <enumeratedValues>
                <enumeratedValue>
                  <name />
                  <description>从外设读取数据写入RAM</description>
                  <value>0</value>
                </enumeratedValue>
                <enumeratedValue>
                  <name />
                  <description>从RAM读取数据写入外设</description>
                  <value>1</value>
                </enumeratedValue>
              </enumeratedValues>
            </field>
            <field>
              <name>BDW</name>
              <description>BDW  field description</description>
              <bitRange>[5:4]</bitRange>
              <access>read-write</access>
              <enumeratedValues>
                <enumeratedValue>
                  <name />
                  <description>字节，8bit</description>
                  <value>0</value>
                </enumeratedValue>
                <enumeratedValue>
                  <name />
                  <description>半字，16bit</description>
                  <value>1</value>
                </enumeratedValue>
                <enumeratedValue>
                  <name />
                  <description>字，32bit</description>
                  <value>2</value>
                </enumeratedValue>
                <enumeratedValue>
                  <name />
                  <description>RFU</description>
                  <value>3</value>
                </enumeratedValue>
              </enumeratedValues>
            </field>
            <field>
              <name>CIRC</name>
              <description>CIRC  field description</description>
              <bitRange>[3:3]</bitRange>
              <access>read-write</access>
              <enumeratedValues>
                <enumeratedValue>
                  <name />
                  <description>关闭循环模式</description>
                  <value>0</value>
                </enumeratedValue>
                <enumeratedValue>
                  <name />
                  <description>使能循环模式</description>
                  <value>1</value>
                </enumeratedValue>
              </enumeratedValues>
            </field>
            <field>
              <name>CHxFTIE</name>
              <description>CHxFTIE  field description</description>
              <bitRange>[2:2]</bitRange>
              <access>read-write</access>
              <enumeratedValues>
                <enumeratedValue>
                  <name />
                  <description>使能传输完成中断</description>
                  <value>1</value>
                </enumeratedValue>
                <enumeratedValue>
                  <name />
                  <description>关闭传输完成中断</description>
                  <value>0</value>
                </enumeratedValue>
              </enumeratedValues>
            </field>
            <field>
              <name>CHxHTIE</name>
              <description>CHxHTIE  field description</description>
              <bitRange>[1:1]</bitRange>
              <access>read-write</access>
              <enumeratedValues>
                <enumeratedValue>
                  <name />
                  <description>使能半程中断</description>
                  <value>1</value>
                </enumeratedValue>
                <enumeratedValue>
                  <name />
                  <description>关闭半程中断</description>
                  <value>0</value>
                </enumeratedValue>
              </enumeratedValues>
            </field>
            <field>
              <name>CHxEN</name>
              <description>CHxEN  field description</description>
              <bitRange>[0:0]</bitRange>
              <access>read-write</access>
              <enumeratedValues>
                <enumeratedValue>
                  <name />
                  <description>启动通道0</description>
                  <value>1</value>
                </enumeratedValue>
                <enumeratedValue>
                  <name />
                  <description>关闭通道0</description>
                  <value>0</value>
                </enumeratedValue>
              </enumeratedValues>
            </field>
          </fields>
        </register>
        <register>
          <name>CH1MAR</name>
          <description>Channel 1 Memory Address Register</description>
          <addressOffset>0x10</addressOffset>
          <size>32</size>
          <access>read-write</access>
          <resetValue>0x00000000</resetValue>
          <fields>
            <field>
              <name>CHxMEMAD</name>
              <description>CHxMEMAD  field description</description>
              <bitRange>[31:0]</bitRange>
              <access>read-write</access>
              <enumeratedValues>
                <enumeratedValue>
                  <name />
                  <description>此指针禁止指向0x00080000~0x1FFFFFFF地址，这段地址为flash保留信息区，指向这段地址可能在DMA访问中导致不可预计的结果</description>
                  <value>0</value>
                </enumeratedValue>
              </enumeratedValues>
            </field>
          </fields>
        </register>
        <register>
          <name>CH2CR</name>
          <description>Channel 2 Control Register</description>
          <addressOffset>0x14</addressOffset>
          <size>32</size>
          <access>read-write</access>
          <resetValue>0x00000000</resetValue>
          <fields>
            <field>
              <name>CHxTSIZE</name>
              <description>CHxTSIZE  field description</description>
              <bitRange>[28:16]</bitRange>
              <access>read-write</access>
              <enumeratedValues />
            </field>
            <field>
              <name>CHxPRI</name>
              <description>CHxPRI  field description</description>
              <bitRange>[13:12]</bitRange>
              <access>read-write</access>
              <enumeratedValues>
                <enumeratedValue>
                  <name />
                  <description>Low</description>
                  <value>0</value>
                </enumeratedValue>
                <enumeratedValue>
                  <name />
                  <description>Medium</description>
                  <value>1</value>
                </enumeratedValue>
                <enumeratedValue>
                  <name />
                  <description>High</description>
                  <value>2</value>
                </enumeratedValue>
                <enumeratedValue>
                  <name />
                  <description>Very High</description>
                  <value>3</value>
                </enumeratedValue>
              </enumeratedValues>
            </field>
            <field>
              <name>CHxINC</name>
              <description>CHxINC  field description</description>
              <bitRange>[11:11]</bitRange>
              <access>read-write</access>
              <enumeratedValues>
                <enumeratedValue>
                  <name />
                  <description>RAM地址递增</description>
                  <value>1</value>
                </enumeratedValue>
                <enumeratedValue>
                  <name />
                  <description>RAM地址递减</description>
                  <value>0</value>
                </enumeratedValue>
              </enumeratedValues>
            </field>
            <field>
              <name>CHxSSEL</name>
              <description>CHxSSEL  field description</description>
              <bitRange>[10:8]</bitRange>
              <access>read-write</access>
              <enumeratedValues />
            </field>
            <field>
              <name>CIRC_UPD</name>
              <description>CIRC_UPD  field description</description>
              <bitRange>[7:7]</bitRange>
              <access>read-write</access>
              <enumeratedValues>
                <enumeratedValue>
                  <name />
                  <description>禁止自动更新</description>
                  <value>0</value>
                </enumeratedValue>
                <enumeratedValue>
                  <name />
                  <description>使能自动更新</description>
                  <value>1</value>
                </enumeratedValue>
                <enumeratedValue>
                  <name />
                  <description>仅通道0~6支持此功能，通道7~10无此寄存器</description>
                  <value>0</value>
                </enumeratedValue>
              </enumeratedValues>
            </field>
            <field>
              <name>DIR</name>
              <description>DIR  field description</description>
              <bitRange>[6:6]</bitRange>
              <access>read-write</access>
              <enumeratedValues>
                <enumeratedValue>
                  <name />
                  <description>从外设读取数据写入RAM</description>
                  <value>0</value>
                </enumeratedValue>
                <enumeratedValue>
                  <name />
                  <description>从RAM读取数据写入外设</description>
                  <value>1</value>
                </enumeratedValue>
              </enumeratedValues>
            </field>
            <field>
              <name>BDW</name>
              <description>BDW  field description</description>
              <bitRange>[5:4]</bitRange>
              <access>read-write</access>
              <enumeratedValues>
                <enumeratedValue>
                  <name />
                  <description>字节，8bit</description>
                  <value>0</value>
                </enumeratedValue>
                <enumeratedValue>
                  <name />
                  <description>半字，16bit</description>
                  <value>1</value>
                </enumeratedValue>
                <enumeratedValue>
                  <name />
                  <description>字，32bit</description>
                  <value>2</value>
                </enumeratedValue>
                <enumeratedValue>
                  <name />
                  <description>RFU</description>
                  <value>3</value>
                </enumeratedValue>
              </enumeratedValues>
            </field>
            <field>
              <name>CIRC</name>
              <description>CIRC  field description</description>
              <bitRange>[3:3]</bitRange>
              <access>read-write</access>
              <enumeratedValues>
                <enumeratedValue>
                  <name />
                  <description>关闭循环模式</description>
                  <value>0</value>
                </enumeratedValue>
                <enumeratedValue>
                  <name />
                  <description>使能循环模式</description>
                  <value>1</value>
                </enumeratedValue>
              </enumeratedValues>
            </field>
            <field>
              <name>CHxFTIE</name>
              <description>CHxFTIE  field description</description>
              <bitRange>[2:2]</bitRange>
              <access>read-write</access>
              <enumeratedValues>
                <enumeratedValue>
                  <name />
                  <description>使能传输完成中断</description>
                  <value>1</value>
                </enumeratedValue>
                <enumeratedValue>
                  <name />
                  <description>关闭传输完成中断</description>
                  <value>0</value>
                </enumeratedValue>
              </enumeratedValues>
            </field>
            <field>
              <name>CHxHTIE</name>
              <description>CHxHTIE  field description</description>
              <bitRange>[1:1]</bitRange>
              <access>read-write</access>
              <enumeratedValues>
                <enumeratedValue>
                  <name />
                  <description>使能半程中断</description>
                  <value>1</value>
                </enumeratedValue>
                <enumeratedValue>
                  <name />
                  <description>关闭半程中断</description>
                  <value>0</value>
                </enumeratedValue>
              </enumeratedValues>
            </field>
            <field>
              <name>CHxEN</name>
              <description>CHxEN  field description</description>
              <bitRange>[0:0]</bitRange>
              <access>read-write</access>
              <enumeratedValues>
                <enumeratedValue>
                  <name />
                  <description>启动通道0</description>
                  <value>1</value>
                </enumeratedValue>
                <enumeratedValue>
                  <name />
                  <description>关闭通道0</description>
                  <value>0</value>
                </enumeratedValue>
              </enumeratedValues>
            </field>
          </fields>
        </register>
        <register>
          <name>CH2MAR</name>
          <description>Channel 2 Memory Address Register</description>
          <addressOffset>0x18</addressOffset>
          <size>32</size>
          <access>read-write</access>
          <resetValue>0x00000000</resetValue>
          <fields>
            <field>
              <name>CHxMEMAD</name>
              <description>CHxMEMAD  field description</description>
              <bitRange>[31:0]</bitRange>
              <access>read-write</access>
              <enumeratedValues>
                <enumeratedValue>
                  <name />
                  <description>此指针禁止指向0x00080000~0x1FFFFFFF地址，这段地址为flash保留信息区，指向这段地址可能在DMA访问中导致不可预计的结果</description>
                  <value>0</value>
                </enumeratedValue>
              </enumeratedValues>
            </field>
          </fields>
        </register>
        <register>
          <name>CH3CR</name>
          <description>Channel 3 Control Register</description>
          <addressOffset>0x1c</addressOffset>
          <size>32</size>
          <access>read-write</access>
          <resetValue>0x00000000</resetValue>
          <fields>
            <field>
              <name>CHxTSIZE</name>
              <description>CHxTSIZE  field description</description>
              <bitRange>[28:16]</bitRange>
              <access>read-write</access>
              <enumeratedValues />
            </field>
            <field>
              <name>CHxPRI</name>
              <description>CHxPRI  field description</description>
              <bitRange>[13:12]</bitRange>
              <access>read-write</access>
              <enumeratedValues>
                <enumeratedValue>
                  <name />
                  <description>Low</description>
                  <value>0</value>
                </enumeratedValue>
                <enumeratedValue>
                  <name />
                  <description>Medium</description>
                  <value>1</value>
                </enumeratedValue>
                <enumeratedValue>
                  <name />
                  <description>High</description>
                  <value>2</value>
                </enumeratedValue>
                <enumeratedValue>
                  <name />
                  <description>Very High</description>
                  <value>3</value>
                </enumeratedValue>
              </enumeratedValues>
            </field>
            <field>
              <name>CHxINC</name>
              <description>CHxINC  field description</description>
              <bitRange>[11:11]</bitRange>
              <access>read-write</access>
              <enumeratedValues>
                <enumeratedValue>
                  <name />
                  <description>RAM地址递增</description>
                  <value>1</value>
                </enumeratedValue>
                <enumeratedValue>
                  <name />
                  <description>RAM地址递减</description>
                  <value>0</value>
                </enumeratedValue>
              </enumeratedValues>
            </field>
            <field>
              <name>CHxSSEL</name>
              <description>CHxSSEL  field description</description>
              <bitRange>[10:8]</bitRange>
              <access>read-write</access>
              <enumeratedValues />
            </field>
            <field>
              <name>CIRC_UPD</name>
              <description>CIRC_UPD  field description</description>
              <bitRange>[7:7]</bitRange>
              <access>read-write</access>
              <enumeratedValues>
                <enumeratedValue>
                  <name />
                  <description>禁止自动更新</description>
                  <value>0</value>
                </enumeratedValue>
                <enumeratedValue>
                  <name />
                  <description>使能自动更新</description>
                  <value>1</value>
                </enumeratedValue>
                <enumeratedValue>
                  <name />
                  <description>仅通道0~6支持此功能，通道7~10无此寄存器</description>
                  <value>0</value>
                </enumeratedValue>
              </enumeratedValues>
            </field>
            <field>
              <name>DIR</name>
              <description>DIR  field description</description>
              <bitRange>[6:6]</bitRange>
              <access>read-write</access>
              <enumeratedValues>
                <enumeratedValue>
                  <name />
                  <description>从外设读取数据写入RAM</description>
                  <value>0</value>
                </enumeratedValue>
                <enumeratedValue>
                  <name />
                  <description>从RAM读取数据写入外设</description>
                  <value>1</value>
                </enumeratedValue>
              </enumeratedValues>
            </field>
            <field>
              <name>BDW</name>
              <description>BDW  field description</description>
              <bitRange>[5:4]</bitRange>
              <access>read-write</access>
              <enumeratedValues>
                <enumeratedValue>
                  <name />
                  <description>字节，8bit</description>
                  <value>0</value>
                </enumeratedValue>
                <enumeratedValue>
                  <name />
                  <description>半字，16bit</description>
                  <value>1</value>
                </enumeratedValue>
                <enumeratedValue>
                  <name />
                  <description>字，32bit</description>
                  <value>2</value>
                </enumeratedValue>
                <enumeratedValue>
                  <name />
                  <description>RFU</description>
                  <value>3</value>
                </enumeratedValue>
              </enumeratedValues>
            </field>
            <field>
              <name>CIRC</name>
              <description>CIRC  field description</description>
              <bitRange>[3:3]</bitRange>
              <access>read-write</access>
              <enumeratedValues>
                <enumeratedValue>
                  <name />
                  <description>关闭循环模式</description>
                  <value>0</value>
                </enumeratedValue>
                <enumeratedValue>
                  <name />
                  <description>使能循环模式</description>
                  <value>1</value>
                </enumeratedValue>
              </enumeratedValues>
            </field>
            <field>
              <name>CHxFTIE</name>
              <description>CHxFTIE  field description</description>
              <bitRange>[2:2]</bitRange>
              <access>read-write</access>
              <enumeratedValues>
                <enumeratedValue>
                  <name />
                  <description>使能传输完成中断</description>
                  <value>1</value>
                </enumeratedValue>
                <enumeratedValue>
                  <name />
                  <description>关闭传输完成中断</description>
                  <value>0</value>
                </enumeratedValue>
              </enumeratedValues>
            </field>
            <field>
              <name>CHxHTIE</name>
              <description>CHxHTIE  field description</description>
              <bitRange>[1:1]</bitRange>
              <access>read-write</access>
              <enumeratedValues>
                <enumeratedValue>
                  <name />
                  <description>使能半程中断</description>
                  <value>1</value>
                </enumeratedValue>
                <enumeratedValue>
                  <name />
                  <description>关闭半程中断</description>
                  <value>0</value>
                </enumeratedValue>
              </enumeratedValues>
            </field>
            <field>
              <name>CHxEN</name>
              <description>CHxEN  field description</description>
              <bitRange>[0:0]</bitRange>
              <access>read-write</access>
              <enumeratedValues>
                <enumeratedValue>
                  <name />
                  <description>启动通道0</description>
                  <value>1</value>
                </enumeratedValue>
                <enumeratedValue>
                  <name />
                  <description>关闭通道0</description>
                  <value>0</value>
                </enumeratedValue>
              </enumeratedValues>
            </field>
          </fields>
        </register>
        <register>
          <name>CH3MAR</name>
          <description>Channel 3 Memory Address Register</description>
          <addressOffset>0x20</addressOffset>
          <size>32</size>
          <access>read-write</access>
          <resetValue>0x00000000</resetValue>
          <fields>
            <field>
              <name>CHxMEMAD</name>
              <description>CHxMEMAD  field description</description>
              <bitRange>[31:0]</bitRange>
              <access>read-write</access>
              <enumeratedValues>
                <enumeratedValue>
                  <name />
                  <description>此指针禁止指向0x00080000~0x1FFFFFFF地址，这段地址为flash保留信息区，指向这段地址可能在DMA访问中导致不可预计的结果</description>
                  <value>0</value>
                </enumeratedValue>
              </enumeratedValues>
            </field>
          </fields>
        </register>
        <register>
          <name>CH4CR</name>
          <description>Channel 4 Control Register</description>
          <addressOffset>0x24</addressOffset>
          <size>32</size>
          <access>read-write</access>
          <resetValue>0x00000000</resetValue>
          <fields>
            <field>
              <name>CHxTSIZE</name>
              <description>CHxTSIZE  field description</description>
              <bitRange>[28:16]</bitRange>
              <access>read-write</access>
              <enumeratedValues />
            </field>
            <field>
              <name>CHxPRI</name>
              <description>CHxPRI  field description</description>
              <bitRange>[13:12]</bitRange>
              <access>read-write</access>
              <enumeratedValues>
                <enumeratedValue>
                  <name />
                  <description>Low</description>
                  <value>0</value>
                </enumeratedValue>
                <enumeratedValue>
                  <name />
                  <description>Medium</description>
                  <value>1</value>
                </enumeratedValue>
                <enumeratedValue>
                  <name />
                  <description>High</description>
                  <value>2</value>
                </enumeratedValue>
                <enumeratedValue>
                  <name />
                  <description>Very High</description>
                  <value>3</value>
                </enumeratedValue>
              </enumeratedValues>
            </field>
            <field>
              <name>CHxINC</name>
              <description>CHxINC  field description</description>
              <bitRange>[11:11]</bitRange>
              <access>read-write</access>
              <enumeratedValues>
                <enumeratedValue>
                  <name />
                  <description>RAM地址递增</description>
                  <value>1</value>
                </enumeratedValue>
                <enumeratedValue>
                  <name />
                  <description>RAM地址递减</description>
                  <value>0</value>
                </enumeratedValue>
              </enumeratedValues>
            </field>
            <field>
              <name>CHxSSEL</name>
              <description>CHxSSEL  field description</description>
              <bitRange>[10:8]</bitRange>
              <access>read-write</access>
              <enumeratedValues />
            </field>
            <field>
              <name>CIRC_UPD</name>
              <description>CIRC_UPD  field description</description>
              <bitRange>[7:7]</bitRange>
              <access>read-write</access>
              <enumeratedValues>
                <enumeratedValue>
                  <name />
                  <description>禁止自动更新</description>
                  <value>0</value>
                </enumeratedValue>
                <enumeratedValue>
                  <name />
                  <description>使能自动更新</description>
                  <value>1</value>
                </enumeratedValue>
                <enumeratedValue>
                  <name />
                  <description>仅通道0~6支持此功能，通道7~10无此寄存器</description>
                  <value>0</value>
                </enumeratedValue>
              </enumeratedValues>
            </field>
            <field>
              <name>DIR</name>
              <description>DIR  field description</description>
              <bitRange>[6:6]</bitRange>
              <access>read-write</access>
              <enumeratedValues>
                <enumeratedValue>
                  <name />
                  <description>从外设读取数据写入RAM</description>
                  <value>0</value>
                </enumeratedValue>
                <enumeratedValue>
                  <name />
                  <description>从RAM读取数据写入外设</description>
                  <value>1</value>
                </enumeratedValue>
              </enumeratedValues>
            </field>
            <field>
              <name>BDW</name>
              <description>BDW  field description</description>
              <bitRange>[5:4]</bitRange>
              <access>read-write</access>
              <enumeratedValues>
                <enumeratedValue>
                  <name />
                  <description>字节，8bit</description>
                  <value>0</value>
                </enumeratedValue>
                <enumeratedValue>
                  <name />
                  <description>半字，16bit</description>
                  <value>1</value>
                </enumeratedValue>
                <enumeratedValue>
                  <name />
                  <description>字，32bit</description>
                  <value>2</value>
                </enumeratedValue>
                <enumeratedValue>
                  <name />
                  <description>RFU</description>
                  <value>3</value>
                </enumeratedValue>
              </enumeratedValues>
            </field>
            <field>
              <name>CIRC</name>
              <description>CIRC  field description</description>
              <bitRange>[3:3]</bitRange>
              <access>read-write</access>
              <enumeratedValues>
                <enumeratedValue>
                  <name />
                  <description>关闭循环模式</description>
                  <value>0</value>
                </enumeratedValue>
                <enumeratedValue>
                  <name />
                  <description>使能循环模式</description>
                  <value>1</value>
                </enumeratedValue>
              </enumeratedValues>
            </field>
            <field>
              <name>CHxFTIE</name>
              <description>CHxFTIE  field description</description>
              <bitRange>[2:2]</bitRange>
              <access>read-write</access>
              <enumeratedValues>
                <enumeratedValue>
                  <name />
                  <description>使能传输完成中断</description>
                  <value>1</value>
                </enumeratedValue>
                <enumeratedValue>
                  <name />
                  <description>关闭传输完成中断</description>
                  <value>0</value>
                </enumeratedValue>
              </enumeratedValues>
            </field>
            <field>
              <name>CHxHTIE</name>
              <description>CHxHTIE  field description</description>
              <bitRange>[1:1]</bitRange>
              <access>read-write</access>
              <enumeratedValues>
                <enumeratedValue>
                  <name />
                  <description>使能半程中断</description>
                  <value>1</value>
                </enumeratedValue>
                <enumeratedValue>
                  <name />
                  <description>关闭半程中断</description>
                  <value>0</value>
                </enumeratedValue>
              </enumeratedValues>
            </field>
            <field>
              <name>CHxEN</name>
              <description>CHxEN  field description</description>
              <bitRange>[0:0]</bitRange>
              <access>read-write</access>
              <enumeratedValues>
                <enumeratedValue>
                  <name />
                  <description>启动通道0</description>
                  <value>1</value>
                </enumeratedValue>
                <enumeratedValue>
                  <name />
                  <description>关闭通道0</description>
                  <value>0</value>
                </enumeratedValue>
              </enumeratedValues>
            </field>
          </fields>
        </register>
        <register>
          <name>CH4MAR</name>
          <description>Channel 4 Memory Address Register</description>
          <addressOffset>0x28</addressOffset>
          <size>32</size>
          <access>read-write</access>
          <resetValue>0x00000000</resetValue>
          <fields>
            <field>
              <name>CHxMEMAD</name>
              <description>CHxMEMAD  field description</description>
              <bitRange>[31:0]</bitRange>
              <access>read-write</access>
              <enumeratedValues>
                <enumeratedValue>
                  <name />
                  <description>此指针禁止指向0x00080000~0x1FFFFFFF地址，这段地址为flash保留信息区，指向这段地址可能在DMA访问中导致不可预计的结果</description>
                  <value>0</value>
                </enumeratedValue>
              </enumeratedValues>
            </field>
          </fields>
        </register>
        <register>
          <name>CH5CR</name>
          <description>Channel 5 Control Register</description>
          <addressOffset>0x2c</addressOffset>
          <size>32</size>
          <access>read-write</access>
          <resetValue>0x00000000</resetValue>
          <fields>
            <field>
              <name>CHxTSIZE</name>
              <description>CHxTSIZE  field description</description>
              <bitRange>[28:16]</bitRange>
              <access>read-write</access>
              <enumeratedValues />
            </field>
            <field>
              <name>CHxPRI</name>
              <description>CHxPRI  field description</description>
              <bitRange>[13:12]</bitRange>
              <access>read-write</access>
              <enumeratedValues>
                <enumeratedValue>
                  <name />
                  <description>Low</description>
                  <value>0</value>
                </enumeratedValue>
                <enumeratedValue>
                  <name />
                  <description>Medium</description>
                  <value>1</value>
                </enumeratedValue>
                <enumeratedValue>
                  <name />
                  <description>High</description>
                  <value>2</value>
                </enumeratedValue>
                <enumeratedValue>
                  <name />
                  <description>Very High</description>
                  <value>3</value>
                </enumeratedValue>
              </enumeratedValues>
            </field>
            <field>
              <name>CHxINC</name>
              <description>CHxINC  field description</description>
              <bitRange>[11:11]</bitRange>
              <access>read-write</access>
              <enumeratedValues>
                <enumeratedValue>
                  <name />
                  <description>RAM地址递增</description>
                  <value>1</value>
                </enumeratedValue>
                <enumeratedValue>
                  <name />
                  <description>RAM地址递减</description>
                  <value>0</value>
                </enumeratedValue>
              </enumeratedValues>
            </field>
            <field>
              <name>CHxSSEL</name>
              <description>CHxSSEL  field description</description>
              <bitRange>[10:8]</bitRange>
              <access>read-write</access>
              <enumeratedValues />
            </field>
            <field>
              <name>CIRC_UPD</name>
              <description>CIRC_UPD  field description</description>
              <bitRange>[7:7]</bitRange>
              <access>read-write</access>
              <enumeratedValues>
                <enumeratedValue>
                  <name />
                  <description>禁止自动更新</description>
                  <value>0</value>
                </enumeratedValue>
                <enumeratedValue>
                  <name />
                  <description>使能自动更新</description>
                  <value>1</value>
                </enumeratedValue>
                <enumeratedValue>
                  <name />
                  <description>仅通道0~6支持此功能，通道7~10无此寄存器</description>
                  <value>0</value>
                </enumeratedValue>
              </enumeratedValues>
            </field>
            <field>
              <name>DIR</name>
              <description>DIR  field description</description>
              <bitRange>[6:6]</bitRange>
              <access>read-write</access>
              <enumeratedValues>
                <enumeratedValue>
                  <name />
                  <description>从外设读取数据写入RAM</description>
                  <value>0</value>
                </enumeratedValue>
                <enumeratedValue>
                  <name />
                  <description>从RAM读取数据写入外设</description>
                  <value>1</value>
                </enumeratedValue>
              </enumeratedValues>
            </field>
            <field>
              <name>BDW</name>
              <description>BDW  field description</description>
              <bitRange>[5:4]</bitRange>
              <access>read-write</access>
              <enumeratedValues>
                <enumeratedValue>
                  <name />
                  <description>字节，8bit</description>
                  <value>0</value>
                </enumeratedValue>
                <enumeratedValue>
                  <name />
                  <description>半字，16bit</description>
                  <value>1</value>
                </enumeratedValue>
                <enumeratedValue>
                  <name />
                  <description>字，32bit</description>
                  <value>2</value>
                </enumeratedValue>
                <enumeratedValue>
                  <name />
                  <description>RFU</description>
                  <value>3</value>
                </enumeratedValue>
              </enumeratedValues>
            </field>
            <field>
              <name>CIRC</name>
              <description>CIRC  field description</description>
              <bitRange>[3:3]</bitRange>
              <access>read-write</access>
              <enumeratedValues>
                <enumeratedValue>
                  <name />
                  <description>关闭循环模式</description>
                  <value>0</value>
                </enumeratedValue>
                <enumeratedValue>
                  <name />
                  <description>使能循环模式</description>
                  <value>1</value>
                </enumeratedValue>
              </enumeratedValues>
            </field>
            <field>
              <name>CHxFTIE</name>
              <description>CHxFTIE  field description</description>
              <bitRange>[2:2]</bitRange>
              <access>read-write</access>
              <enumeratedValues>
                <enumeratedValue>
                  <name />
                  <description>使能传输完成中断</description>
                  <value>1</value>
                </enumeratedValue>
                <enumeratedValue>
                  <name />
                  <description>关闭传输完成中断</description>
                  <value>0</value>
                </enumeratedValue>
              </enumeratedValues>
            </field>
            <field>
              <name>CHxHTIE</name>
              <description>CHxHTIE  field description</description>
              <bitRange>[1:1]</bitRange>
              <access>read-write</access>
              <enumeratedValues>
                <enumeratedValue>
                  <name />
                  <description>使能半程中断</description>
                  <value>1</value>
                </enumeratedValue>
                <enumeratedValue>
                  <name />
                  <description>关闭半程中断</description>
                  <value>0</value>
                </enumeratedValue>
              </enumeratedValues>
            </field>
            <field>
              <name>CHxEN</name>
              <description>CHxEN  field description</description>
              <bitRange>[0:0]</bitRange>
              <access>read-write</access>
              <enumeratedValues>
                <enumeratedValue>
                  <name />
                  <description>启动通道0</description>
                  <value>1</value>
                </enumeratedValue>
                <enumeratedValue>
                  <name />
                  <description>关闭通道0</description>
                  <value>0</value>
                </enumeratedValue>
              </enumeratedValues>
            </field>
          </fields>
        </register>
        <register>
          <name>CH5MAR</name>
          <description>Channel 5 Memory Address Register</description>
          <addressOffset>0x30</addressOffset>
          <size>32</size>
          <access>read-write</access>
          <resetValue>0x00000000</resetValue>
          <fields>
            <field>
              <name>CHxMEMAD</name>
              <description>CHxMEMAD  field description</description>
              <bitRange>[31:0]</bitRange>
              <access>read-write</access>
              <enumeratedValues>
                <enumeratedValue>
                  <name />
                  <description>此指针禁止指向0x00080000~0x1FFFFFFF地址，这段地址为flash保留信息区，指向这段地址可能在DMA访问中导致不可预计的结果</description>
                  <value>0</value>
                </enumeratedValue>
              </enumeratedValues>
            </field>
          </fields>
        </register>
        <register>
          <name>CH6CR</name>
          <description>Channel 6 Control Register</description>
          <addressOffset>0x34</addressOffset>
          <size>32</size>
          <access>read-write</access>
          <resetValue>0x00000000</resetValue>
          <fields>
            <field>
              <name>CHxTSIZE</name>
              <description>CHxTSIZE  field description</description>
              <bitRange>[28:16]</bitRange>
              <access>read-write</access>
              <enumeratedValues />
            </field>
            <field>
              <name>CHxPRI</name>
              <description>CHxPRI  field description</description>
              <bitRange>[13:12]</bitRange>
              <access>read-write</access>
              <enumeratedValues>
                <enumeratedValue>
                  <name />
                  <description>Low</description>
                  <value>0</value>
                </enumeratedValue>
                <enumeratedValue>
                  <name />
                  <description>Medium</description>
                  <value>1</value>
                </enumeratedValue>
                <enumeratedValue>
                  <name />
                  <description>High</description>
                  <value>2</value>
                </enumeratedValue>
                <enumeratedValue>
                  <name />
                  <description>Very High</description>
                  <value>3</value>
                </enumeratedValue>
              </enumeratedValues>
            </field>
            <field>
              <name>CHxINC</name>
              <description>CHxINC  field description</description>
              <bitRange>[11:11]</bitRange>
              <access>read-write</access>
              <enumeratedValues>
                <enumeratedValue>
                  <name />
                  <description>RAM地址递增</description>
                  <value>1</value>
                </enumeratedValue>
                <enumeratedValue>
                  <name />
                  <description>RAM地址递减</description>
                  <value>0</value>
                </enumeratedValue>
              </enumeratedValues>
            </field>
            <field>
              <name>CHxSSEL</name>
              <description>CHxSSEL  field description</description>
              <bitRange>[10:8]</bitRange>
              <access>read-write</access>
              <enumeratedValues />
            </field>
            <field>
              <name>CIRC_UPD</name>
              <description>CIRC_UPD  field description</description>
              <bitRange>[7:7]</bitRange>
              <access>read-write</access>
              <enumeratedValues>
                <enumeratedValue>
                  <name />
                  <description>禁止自动更新</description>
                  <value>0</value>
                </enumeratedValue>
                <enumeratedValue>
                  <name />
                  <description>使能自动更新</description>
                  <value>1</value>
                </enumeratedValue>
                <enumeratedValue>
                  <name />
                  <description>仅通道0~6支持此功能，通道7~10无此寄存器</description>
                  <value>0</value>
                </enumeratedValue>
              </enumeratedValues>
            </field>
            <field>
              <name>DIR</name>
              <description>DIR  field description</description>
              <bitRange>[6:6]</bitRange>
              <access>read-write</access>
              <enumeratedValues>
                <enumeratedValue>
                  <name />
                  <description>从外设读取数据写入RAM</description>
                  <value>0</value>
                </enumeratedValue>
                <enumeratedValue>
                  <name />
                  <description>从RAM读取数据写入外设</description>
                  <value>1</value>
                </enumeratedValue>
              </enumeratedValues>
            </field>
            <field>
              <name>BDW</name>
              <description>BDW  field description</description>
              <bitRange>[5:4]</bitRange>
              <access>read-write</access>
              <enumeratedValues>
                <enumeratedValue>
                  <name />
                  <description>字节，8bit</description>
                  <value>0</value>
                </enumeratedValue>
                <enumeratedValue>
                  <name />
                  <description>半字，16bit</description>
                  <value>1</value>
                </enumeratedValue>
                <enumeratedValue>
                  <name />
                  <description>字，32bit</description>
                  <value>2</value>
                </enumeratedValue>
                <enumeratedValue>
                  <name />
                  <description>RFU</description>
                  <value>3</value>
                </enumeratedValue>
              </enumeratedValues>
            </field>
            <field>
              <name>CIRC</name>
              <description>CIRC  field description</description>
              <bitRange>[3:3]</bitRange>
              <access>read-write</access>
              <enumeratedValues>
                <enumeratedValue>
                  <name />
                  <description>关闭循环模式</description>
                  <value>0</value>
                </enumeratedValue>
                <enumeratedValue>
                  <name />
                  <description>使能循环模式</description>
                  <value>1</value>
                </enumeratedValue>
              </enumeratedValues>
            </field>
            <field>
              <name>CHxFTIE</name>
              <description>CHxFTIE  field description</description>
              <bitRange>[2:2]</bitRange>
              <access>read-write</access>
              <enumeratedValues>
                <enumeratedValue>
                  <name />
                  <description>使能传输完成中断</description>
                  <value>1</value>
                </enumeratedValue>
                <enumeratedValue>
                  <name />
                  <description>关闭传输完成中断</description>
                  <value>0</value>
                </enumeratedValue>
              </enumeratedValues>
            </field>
            <field>
              <name>CHxHTIE</name>
              <description>CHxHTIE  field description</description>
              <bitRange>[1:1]</bitRange>
              <access>read-write</access>
              <enumeratedValues>
                <enumeratedValue>
                  <name />
                  <description>使能半程中断</description>
                  <value>1</value>
                </enumeratedValue>
                <enumeratedValue>
                  <name />
                  <description>关闭半程中断</description>
                  <value>0</value>
                </enumeratedValue>
              </enumeratedValues>
            </field>
            <field>
              <name>CHxEN</name>
              <description>CHxEN  field description</description>
              <bitRange>[0:0]</bitRange>
              <access>read-write</access>
              <enumeratedValues>
                <enumeratedValue>
                  <name />
                  <description>启动通道0</description>
                  <value>1</value>
                </enumeratedValue>
                <enumeratedValue>
                  <name />
                  <description>关闭通道0</description>
                  <value>0</value>
                </enumeratedValue>
              </enumeratedValues>
            </field>
          </fields>
        </register>
        <register>
          <name>CH7CR</name>
          <description>Channel 7 Control Register</description>
          <addressOffset>0x3c</addressOffset>
          <size>32</size>
          <access>read-write</access>
          <resetValue>0x00000000</resetValue>
          <fields>
            <field>
              <name>CHxTSIZE</name>
              <description>CHxTSIZE  field description</description>
              <bitRange>[28:16]</bitRange>
              <access>read-write</access>
              <enumeratedValues />
            </field>
            <field>
              <name>CHxPRI</name>
              <description>CHxPRI  field description</description>
              <bitRange>[13:12]</bitRange>
              <access>read-write</access>
              <enumeratedValues>
                <enumeratedValue>
                  <name />
                  <description>Low</description>
                  <value>0</value>
                </enumeratedValue>
                <enumeratedValue>
                  <name />
                  <description>Medium</description>
                  <value>1</value>
                </enumeratedValue>
                <enumeratedValue>
                  <name />
                  <description>High</description>
                  <value>2</value>
                </enumeratedValue>
                <enumeratedValue>
                  <name />
                  <description>Very High</description>
                  <value>3</value>
                </enumeratedValue>
              </enumeratedValues>
            </field>
            <field>
              <name>CHxINC</name>
              <description>CHxINC  field description</description>
              <bitRange>[11:11]</bitRange>
              <access>read-write</access>
              <enumeratedValues>
                <enumeratedValue>
                  <name />
                  <description>RAM地址递增</description>
                  <value>1</value>
                </enumeratedValue>
                <enumeratedValue>
                  <name />
                  <description>RAM地址递减</description>
                  <value>0</value>
                </enumeratedValue>
              </enumeratedValues>
            </field>
            <field>
              <name>CHxSSEL</name>
              <description>CHxSSEL  field description</description>
              <bitRange>[10:8]</bitRange>
              <access>read-write</access>
              <enumeratedValues />
            </field>
            <field>
              <name>CIRC_UPD</name>
              <description>CIRC_UPD  field description</description>
              <bitRange>[7:7]</bitRange>
              <access>read-write</access>
              <enumeratedValues>
                <enumeratedValue>
                  <name />
                  <description>禁止自动更新</description>
                  <value>0</value>
                </enumeratedValue>
                <enumeratedValue>
                  <name />
                  <description>使能自动更新</description>
                  <value>1</value>
                </enumeratedValue>
                <enumeratedValue>
                  <name />
                  <description>仅通道0~6支持此功能，通道7~10无此寄存器</description>
                  <value>0</value>
                </enumeratedValue>
              </enumeratedValues>
            </field>
            <field>
              <name>DIR</name>
              <description>DIR  field description</description>
              <bitRange>[6:6]</bitRange>
              <access>read-write</access>
              <enumeratedValues>
                <enumeratedValue>
                  <name />
                  <description>从外设读取数据写入RAM</description>
                  <value>0</value>
                </enumeratedValue>
                <enumeratedValue>
                  <name />
                  <description>从RAM读取数据写入外设</description>
                  <value>1</value>
                </enumeratedValue>
              </enumeratedValues>
            </field>
            <field>
              <name>BDW</name>
              <description>BDW  field description</description>
              <bitRange>[5:4]</bitRange>
              <access>read-write</access>
              <enumeratedValues>
                <enumeratedValue>
                  <name />
                  <description>字节，8bit</description>
                  <value>0</value>
                </enumeratedValue>
                <enumeratedValue>
                  <name />
                  <description>半字，16bit</description>
                  <value>1</value>
                </enumeratedValue>
                <enumeratedValue>
                  <name />
                  <description>字，32bit</description>
                  <value>2</value>
                </enumeratedValue>
                <enumeratedValue>
                  <name />
                  <description>RFU</description>
                  <value>3</value>
                </enumeratedValue>
              </enumeratedValues>
            </field>
            <field>
              <name>CIRC</name>
              <description>CIRC  field description</description>
              <bitRange>[3:3]</bitRange>
              <access>read-write</access>
              <enumeratedValues>
                <enumeratedValue>
                  <name />
                  <description>关闭循环模式</description>
                  <value>0</value>
                </enumeratedValue>
                <enumeratedValue>
                  <name />
                  <description>使能循环模式</description>
                  <value>1</value>
                </enumeratedValue>
              </enumeratedValues>
            </field>
            <field>
              <name>CHxFTIE</name>
              <description>CHxFTIE  field description</description>
              <bitRange>[2:2]</bitRange>
              <access>read-write</access>
              <enumeratedValues>
                <enumeratedValue>
                  <name />
                  <description>使能传输完成中断</description>
                  <value>1</value>
                </enumeratedValue>
                <enumeratedValue>
                  <name />
                  <description>关闭传输完成中断</description>
                  <value>0</value>
                </enumeratedValue>
              </enumeratedValues>
            </field>
            <field>
              <name>CHxHTIE</name>
              <description>CHxHTIE  field description</description>
              <bitRange>[1:1]</bitRange>
              <access>read-write</access>
              <enumeratedValues>
                <enumeratedValue>
                  <name />
                  <description>使能半程中断</description>
                  <value>1</value>
                </enumeratedValue>
                <enumeratedValue>
                  <name />
                  <description>关闭半程中断</description>
                  <value>0</value>
                </enumeratedValue>
              </enumeratedValues>
            </field>
            <field>
              <name>CHxEN</name>
              <description>CHxEN  field description</description>
              <bitRange>[0:0]</bitRange>
              <access>read-write</access>
              <enumeratedValues>
                <enumeratedValue>
                  <name />
                  <description>启动通道0</description>
                  <value>1</value>
                </enumeratedValue>
                <enumeratedValue>
                  <name />
                  <description>关闭通道0</description>
                  <value>0</value>
                </enumeratedValue>
              </enumeratedValues>
            </field>
          </fields>
        </register>
        <register>
          <name>CH7MAR</name>
          <description>Channel 7 Memory Address Register</description>
          <addressOffset>0x40</addressOffset>
          <size>32</size>
          <access>read-write</access>
          <resetValue>0x00000000</resetValue>
          <fields>
            <field>
              <name>CHxMEMAD</name>
              <description>CHxMEMAD  field description</description>
              <bitRange>[31:0]</bitRange>
              <access>read-write</access>
              <enumeratedValues>
                <enumeratedValue>
                  <name />
                  <description>此指针禁止指向0x00080000~0x1FFFFFFF地址，这段地址为flash保留信息区，指向这段地址可能在DMA访问中导致不可预计的结果</description>
                  <value>0</value>
                </enumeratedValue>
              </enumeratedValues>
            </field>
          </fields>
        </register>
        <register>
          <name>CH8CR</name>
          <description>Channel 8 Control Register</description>
          <addressOffset>0x44</addressOffset>
          <size>32</size>
          <access>read-write</access>
          <resetValue>0x00000000</resetValue>
          <fields>
            <field>
              <name>CHxTSIZE</name>
              <description>CHxTSIZE  field description</description>
              <bitRange>[28:16]</bitRange>
              <access>read-write</access>
              <enumeratedValues />
            </field>
            <field>
              <name>CHxPRI</name>
              <description>CHxPRI  field description</description>
              <bitRange>[13:12]</bitRange>
              <access>read-write</access>
              <enumeratedValues>
                <enumeratedValue>
                  <name />
                  <description>Low</description>
                  <value>0</value>
                </enumeratedValue>
                <enumeratedValue>
                  <name />
                  <description>Medium</description>
                  <value>1</value>
                </enumeratedValue>
                <enumeratedValue>
                  <name />
                  <description>High</description>
                  <value>2</value>
                </enumeratedValue>
                <enumeratedValue>
                  <name />
                  <description>Very High</description>
                  <value>3</value>
                </enumeratedValue>
              </enumeratedValues>
            </field>
            <field>
              <name>CHxINC</name>
              <description>CHxINC  field description</description>
              <bitRange>[11:11]</bitRange>
              <access>read-write</access>
              <enumeratedValues>
                <enumeratedValue>
                  <name />
                  <description>RAM地址递增</description>
                  <value>1</value>
                </enumeratedValue>
                <enumeratedValue>
                  <name />
                  <description>RAM地址递减</description>
                  <value>0</value>
                </enumeratedValue>
              </enumeratedValues>
            </field>
            <field>
              <name>CHxSSEL</name>
              <description>CHxSSEL  field description</description>
              <bitRange>[10:8]</bitRange>
              <access>read-write</access>
              <enumeratedValues />
            </field>
            <field>
              <name>CIRC_UPD</name>
              <description>CIRC_UPD  field description</description>
              <bitRange>[7:7]</bitRange>
              <access>read-write</access>
              <enumeratedValues>
                <enumeratedValue>
                  <name />
                  <description>禁止自动更新</description>
                  <value>0</value>
                </enumeratedValue>
                <enumeratedValue>
                  <name />
                  <description>使能自动更新</description>
                  <value>1</value>
                </enumeratedValue>
                <enumeratedValue>
                  <name />
                  <description>仅通道0~6支持此功能，通道7~10无此寄存器</description>
                  <value>0</value>
                </enumeratedValue>
              </enumeratedValues>
            </field>
            <field>
              <name>DIR</name>
              <description>DIR  field description</description>
              <bitRange>[6:6]</bitRange>
              <access>read-write</access>
              <enumeratedValues>
                <enumeratedValue>
                  <name />
                  <description>从外设读取数据写入RAM</description>
                  <value>0</value>
                </enumeratedValue>
                <enumeratedValue>
                  <name />
                  <description>从RAM读取数据写入外设</description>
                  <value>1</value>
                </enumeratedValue>
              </enumeratedValues>
            </field>
            <field>
              <name>BDW</name>
              <description>BDW  field description</description>
              <bitRange>[5:4]</bitRange>
              <access>read-write</access>
              <enumeratedValues>
                <enumeratedValue>
                  <name />
                  <description>字节，8bit</description>
                  <value>0</value>
                </enumeratedValue>
                <enumeratedValue>
                  <name />
                  <description>半字，16bit</description>
                  <value>1</value>
                </enumeratedValue>
                <enumeratedValue>
                  <name />
                  <description>字，32bit</description>
                  <value>2</value>
                </enumeratedValue>
                <enumeratedValue>
                  <name />
                  <description>RFU</description>
                  <value>3</value>
                </enumeratedValue>
              </enumeratedValues>
            </field>
            <field>
              <name>CIRC</name>
              <description>CIRC  field description</description>
              <bitRange>[3:3]</bitRange>
              <access>read-write</access>
              <enumeratedValues>
                <enumeratedValue>
                  <name />
                  <description>关闭循环模式</description>
                  <value>0</value>
                </enumeratedValue>
                <enumeratedValue>
                  <name />
                  <description>使能循环模式</description>
                  <value>1</value>
                </enumeratedValue>
              </enumeratedValues>
            </field>
            <field>
              <name>CHxFTIE</name>
              <description>CHxFTIE  field description</description>
              <bitRange>[2:2]</bitRange>
              <access>read-write</access>
              <enumeratedValues>
                <enumeratedValue>
                  <name />
                  <description>使能传输完成中断</description>
                  <value>1</value>
                </enumeratedValue>
                <enumeratedValue>
                  <name />
                  <description>关闭传输完成中断</description>
                  <value>0</value>
                </enumeratedValue>
              </enumeratedValues>
            </field>
            <field>
              <name>CHxHTIE</name>
              <description>CHxHTIE  field description</description>
              <bitRange>[1:1]</bitRange>
              <access>read-write</access>
              <enumeratedValues>
                <enumeratedValue>
                  <name />
                  <description>使能半程中断</description>
                  <value>1</value>
                </enumeratedValue>
                <enumeratedValue>
                  <name />
                  <description>关闭半程中断</description>
                  <value>0</value>
                </enumeratedValue>
              </enumeratedValues>
            </field>
            <field>
              <name>CHxEN</name>
              <description>CHxEN  field description</description>
              <bitRange>[0:0]</bitRange>
              <access>read-write</access>
              <enumeratedValues>
                <enumeratedValue>
                  <name />
                  <description>启动通道0</description>
                  <value>1</value>
                </enumeratedValue>
                <enumeratedValue>
                  <name />
                  <description>关闭通道0</description>
                  <value>0</value>
                </enumeratedValue>
              </enumeratedValues>
            </field>
          </fields>
        </register>
        <register>
          <name>CH8MAR</name>
          <description>Channel 8 Memory Address Register</description>
          <addressOffset>0x48</addressOffset>
          <size>32</size>
          <access>read-write</access>
          <resetValue>0x00000000</resetValue>
          <fields>
            <field>
              <name>CHxMEMAD</name>
              <description>CHxMEMAD  field description</description>
              <bitRange>[31:0]</bitRange>
              <access>read-write</access>
              <enumeratedValues>
                <enumeratedValue>
                  <name />
                  <description>此指针禁止指向0x00080000~0x1FFFFFFF地址，这段地址为flash保留信息区，指向这段地址可能在DMA访问中导致不可预计的结果</description>
                  <value>0</value>
                </enumeratedValue>
              </enumeratedValues>
            </field>
          </fields>
        </register>
        <register>
          <name>CH9CR</name>
          <description>Channel 9 Control Register</description>
          <addressOffset>0x4c</addressOffset>
          <size>32</size>
          <access>read-write</access>
          <resetValue>0x00000000</resetValue>
          <fields>
            <field>
              <name>CHxTSIZE</name>
              <description>CHxTSIZE  field description</description>
              <bitRange>[28:16]</bitRange>
              <access>read-write</access>
              <enumeratedValues />
            </field>
            <field>
              <name>CHxPRI</name>
              <description>CHxPRI  field description</description>
              <bitRange>[13:12]</bitRange>
              <access>read-write</access>
              <enumeratedValues>
                <enumeratedValue>
                  <name />
                  <description>Low</description>
                  <value>0</value>
                </enumeratedValue>
                <enumeratedValue>
                  <name />
                  <description>Medium</description>
                  <value>1</value>
                </enumeratedValue>
                <enumeratedValue>
                  <name />
                  <description>High</description>
                  <value>2</value>
                </enumeratedValue>
                <enumeratedValue>
                  <name />
                  <description>Very High</description>
                  <value>3</value>
                </enumeratedValue>
              </enumeratedValues>
            </field>
            <field>
              <name>CHxINC</name>
              <description>CHxINC  field description</description>
              <bitRange>[11:11]</bitRange>
              <access>read-write</access>
              <enumeratedValues>
                <enumeratedValue>
                  <name />
                  <description>RAM地址递增</description>
                  <value>1</value>
                </enumeratedValue>
                <enumeratedValue>
                  <name />
                  <description>RAM地址递减</description>
                  <value>0</value>
                </enumeratedValue>
              </enumeratedValues>
            </field>
            <field>
              <name>CHxSSEL</name>
              <description>CHxSSEL  field description</description>
              <bitRange>[10:8]</bitRange>
              <access>read-write</access>
              <enumeratedValues />
            </field>
            <field>
              <name>CIRC_UPD</name>
              <description>CIRC_UPD  field description</description>
              <bitRange>[7:7]</bitRange>
              <access>read-write</access>
              <enumeratedValues>
                <enumeratedValue>
                  <name />
                  <description>禁止自动更新</description>
                  <value>0</value>
                </enumeratedValue>
                <enumeratedValue>
                  <name />
                  <description>使能自动更新</description>
                  <value>1</value>
                </enumeratedValue>
                <enumeratedValue>
                  <name />
                  <description>仅通道0~6支持此功能，通道7~10无此寄存器</description>
                  <value>0</value>
                </enumeratedValue>
              </enumeratedValues>
            </field>
            <field>
              <name>DIR</name>
              <description>DIR  field description</description>
              <bitRange>[6:6]</bitRange>
              <access>read-write</access>
              <enumeratedValues>
                <enumeratedValue>
                  <name />
                  <description>从外设读取数据写入RAM</description>
                  <value>0</value>
                </enumeratedValue>
                <enumeratedValue>
                  <name />
                  <description>从RAM读取数据写入外设</description>
                  <value>1</value>
                </enumeratedValue>
              </enumeratedValues>
            </field>
            <field>
              <name>BDW</name>
              <description>BDW  field description</description>
              <bitRange>[5:4]</bitRange>
              <access>read-write</access>
              <enumeratedValues>
                <enumeratedValue>
                  <name />
                  <description>字节，8bit</description>
                  <value>0</value>
                </enumeratedValue>
                <enumeratedValue>
                  <name />
                  <description>半字，16bit</description>
                  <value>1</value>
                </enumeratedValue>
                <enumeratedValue>
                  <name />
                  <description>字，32bit</description>
                  <value>2</value>
                </enumeratedValue>
                <enumeratedValue>
                  <name />
                  <description>RFU</description>
                  <value>3</value>
                </enumeratedValue>
              </enumeratedValues>
            </field>
            <field>
              <name>CIRC</name>
              <description>CIRC  field description</description>
              <bitRange>[3:3]</bitRange>
              <access>read-write</access>
              <enumeratedValues>
                <enumeratedValue>
                  <name />
                  <description>关闭循环模式</description>
                  <value>0</value>
                </enumeratedValue>
                <enumeratedValue>
                  <name />
                  <description>使能循环模式</description>
                  <value>1</value>
                </enumeratedValue>
              </enumeratedValues>
            </field>
            <field>
              <name>CHxFTIE</name>
              <description>CHxFTIE  field description</description>
              <bitRange>[2:2]</bitRange>
              <access>read-write</access>
              <enumeratedValues>
                <enumeratedValue>
                  <name />
                  <description>使能传输完成中断</description>
                  <value>1</value>
                </enumeratedValue>
                <enumeratedValue>
                  <name />
                  <description>关闭传输完成中断</description>
                  <value>0</value>
                </enumeratedValue>
              </enumeratedValues>
            </field>
            <field>
              <name>CHxHTIE</name>
              <description>CHxHTIE  field description</description>
              <bitRange>[1:1]</bitRange>
              <access>read-write</access>
              <enumeratedValues>
                <enumeratedValue>
                  <name />
                  <description>使能半程中断</description>
                  <value>1</value>
                </enumeratedValue>
                <enumeratedValue>
                  <name />
                  <description>关闭半程中断</description>
                  <value>0</value>
                </enumeratedValue>
              </enumeratedValues>
            </field>
            <field>
              <name>CHxEN</name>
              <description>CHxEN  field description</description>
              <bitRange>[0:0]</bitRange>
              <access>read-write</access>
              <enumeratedValues>
                <enumeratedValue>
                  <name />
                  <description>启动通道0</description>
                  <value>1</value>
                </enumeratedValue>
                <enumeratedValue>
                  <name />
                  <description>关闭通道0</description>
                  <value>0</value>
                </enumeratedValue>
              </enumeratedValues>
            </field>
          </fields>
        </register>
        <register>
          <name>CH9MAR</name>
          <description>Channel 9 Memory Address Register</description>
          <addressOffset>0x50</addressOffset>
          <size>32</size>
          <access>read-write</access>
          <resetValue>0x00000000</resetValue>
          <fields>
            <field>
              <name>CHxMEMAD</name>
              <description>CHxMEMAD  field description</description>
              <bitRange>[31:0]</bitRange>
              <access>read-write</access>
              <enumeratedValues>
                <enumeratedValue>
                  <name />
                  <description>此指针禁止指向0x00080000~0x1FFFFFFF地址，这段地址为flash保留信息区，指向这段地址可能在DMA访问中导致不可预计的结果</description>
                  <value>0</value>
                </enumeratedValue>
              </enumeratedValues>
            </field>
          </fields>
        </register>
        <register>
          <name>CH10CR</name>
          <description>Channel 10 Control Register</description>
          <addressOffset>0x54</addressOffset>
          <size>32</size>
          <access>read-write</access>
          <resetValue>0x00000000</resetValue>
          <fields>
            <field>
              <name>CHxTSIZE</name>
              <description>CHxTSIZE  field description</description>
              <bitRange>[28:16]</bitRange>
              <access>read-write</access>
              <enumeratedValues />
            </field>
            <field>
              <name>CHxPRI</name>
              <description>CHxPRI  field description</description>
              <bitRange>[13:12]</bitRange>
              <access>read-write</access>
              <enumeratedValues>
                <enumeratedValue>
                  <name />
                  <description>Low</description>
                  <value>0</value>
                </enumeratedValue>
                <enumeratedValue>
                  <name />
                  <description>Medium</description>
                  <value>1</value>
                </enumeratedValue>
                <enumeratedValue>
                  <name />
                  <description>High</description>
                  <value>2</value>
                </enumeratedValue>
                <enumeratedValue>
                  <name />
                  <description>Very High</description>
                  <value>3</value>
                </enumeratedValue>
              </enumeratedValues>
            </field>
            <field>
              <name>CHxINC</name>
              <description>CHxINC  field description</description>
              <bitRange>[11:11]</bitRange>
              <access>read-write</access>
              <enumeratedValues>
                <enumeratedValue>
                  <name />
                  <description>RAM地址递增</description>
                  <value>1</value>
                </enumeratedValue>
                <enumeratedValue>
                  <name />
                  <description>RAM地址递减</description>
                  <value>0</value>
                </enumeratedValue>
              </enumeratedValues>
            </field>
            <field>
              <name>CHxSSEL</name>
              <description>CHxSSEL  field description</description>
              <bitRange>[10:8]</bitRange>
              <access>read-write</access>
              <enumeratedValues />
            </field>
            <field>
              <name>CIRC_UPD</name>
              <description>CIRC_UPD  field description</description>
              <bitRange>[7:7]</bitRange>
              <access>read-write</access>
              <enumeratedValues>
                <enumeratedValue>
                  <name />
                  <description>禁止自动更新</description>
                  <value>0</value>
                </enumeratedValue>
                <enumeratedValue>
                  <name />
                  <description>使能自动更新</description>
                  <value>1</value>
                </enumeratedValue>
                <enumeratedValue>
                  <name />
                  <description>仅通道0~6支持此功能，通道7~10无此寄存器</description>
                  <value>0</value>
                </enumeratedValue>
              </enumeratedValues>
            </field>
            <field>
              <name>DIR</name>
              <description>DIR  field description</description>
              <bitRange>[6:6]</bitRange>
              <access>read-write</access>
              <enumeratedValues>
                <enumeratedValue>
                  <name />
                  <description>从外设读取数据写入RAM</description>
                  <value>0</value>
                </enumeratedValue>
                <enumeratedValue>
                  <name />
                  <description>从RAM读取数据写入外设</description>
                  <value>1</value>
                </enumeratedValue>
              </enumeratedValues>
            </field>
            <field>
              <name>BDW</name>
              <description>BDW  field description</description>
              <bitRange>[5:4]</bitRange>
              <access>read-write</access>
              <enumeratedValues>
                <enumeratedValue>
                  <name />
                  <description>字节，8bit</description>
                  <value>0</value>
                </enumeratedValue>
                <enumeratedValue>
                  <name />
                  <description>半字，16bit</description>
                  <value>1</value>
                </enumeratedValue>
                <enumeratedValue>
                  <name />
                  <description>字，32bit</description>
                  <value>2</value>
                </enumeratedValue>
                <enumeratedValue>
                  <name />
                  <description>RFU</description>
                  <value>3</value>
                </enumeratedValue>
              </enumeratedValues>
            </field>
            <field>
              <name>CIRC</name>
              <description>CIRC  field description</description>
              <bitRange>[3:3]</bitRange>
              <access>read-write</access>
              <enumeratedValues>
                <enumeratedValue>
                  <name />
                  <description>关闭循环模式</description>
                  <value>0</value>
                </enumeratedValue>
                <enumeratedValue>
                  <name />
                  <description>使能循环模式</description>
                  <value>1</value>
                </enumeratedValue>
              </enumeratedValues>
            </field>
            <field>
              <name>CHxFTIE</name>
              <description>CHxFTIE  field description</description>
              <bitRange>[2:2]</bitRange>
              <access>read-write</access>
              <enumeratedValues>
                <enumeratedValue>
                  <name />
                  <description>使能传输完成中断</description>
                  <value>1</value>
                </enumeratedValue>
                <enumeratedValue>
                  <name />
                  <description>关闭传输完成中断</description>
                  <value>0</value>
                </enumeratedValue>
              </enumeratedValues>
            </field>
            <field>
              <name>CHxHTIE</name>
              <description>CHxHTIE  field description</description>
              <bitRange>[1:1]</bitRange>
              <access>read-write</access>
              <enumeratedValues>
                <enumeratedValue>
                  <name />
                  <description>使能半程中断</description>
                  <value>1</value>
                </enumeratedValue>
                <enumeratedValue>
                  <name />
                  <description>关闭半程中断</description>
                  <value>0</value>
                </enumeratedValue>
              </enumeratedValues>
            </field>
            <field>
              <name>CHxEN</name>
              <description>CHxEN  field description</description>
              <bitRange>[0:0]</bitRange>
              <access>read-write</access>
              <enumeratedValues>
                <enumeratedValue>
                  <name />
                  <description>启动通道0</description>
                  <value>1</value>
                </enumeratedValue>
                <enumeratedValue>
                  <name />
                  <description>关闭通道0</description>
                  <value>0</value>
                </enumeratedValue>
              </enumeratedValues>
            </field>
          </fields>
        </register>
        <register>
          <name>CH10MAR</name>
          <description>Channel 10 Memory Address Register</description>
          <addressOffset>0x58</addressOffset>
          <size>32</size>
          <access>read-write</access>
          <resetValue>0x00000000</resetValue>
          <fields>
            <field>
              <name>CHxMEMAD</name>
              <description>CHxMEMAD  field description</description>
              <bitRange>[31:0]</bitRange>
              <access>read-write</access>
              <enumeratedValues>
                <enumeratedValue>
                  <name />
                  <description>此指针禁止指向0x00080000~0x1FFFFFFF地址，这段地址为flash保留信息区，指向这段地址可能在DMA访问中导致不可预计的结果</description>
                  <value>0</value>
                </enumeratedValue>
              </enumeratedValues>
            </field>
          </fields>
        </register>
        <register>
          <name>CH11CR</name>
          <description>Channel 11 Control Register</description>
          <addressOffset>0x5c</addressOffset>
          <size>32</size>
          <access>read-write</access>
          <resetValue>0x00000000</resetValue>
          <fields>
            <field>
              <name>CH11TSIZE</name>
              <description>CH11TSIZE  field description</description>
              <bitRange>[28:16]</bitRange>
              <access>read-write</access>
              <enumeratedValues />
            </field>
            <field>
              <name>CH11PRI</name>
              <description>CH11PRI  field description</description>
              <bitRange>[13:12]</bitRange>
              <access>read-write</access>
              <enumeratedValues>
                <enumeratedValue>
                  <name />
                  <description>Low</description>
                  <value>0</value>
                </enumeratedValue>
                <enumeratedValue>
                  <name />
                  <description>Medium</description>
                  <value>1</value>
                </enumeratedValue>
                <enumeratedValue>
                  <name />
                  <description>High</description>
                  <value>2</value>
                </enumeratedValue>
                <enumeratedValue>
                  <name />
                  <description>Very High</description>
                  <value>3</value>
                </enumeratedValue>
              </enumeratedValues>
            </field>
            <field>
              <name>CH11DIR</name>
              <description>CH11DIR  field description</description>
              <bitRange>[10:10]</bitRange>
              <access>read-write</access>
              <enumeratedValues>
                <enumeratedValue>
                  <name />
                  <description>Flash-&gt;RAM传输</description>
                  <value>1</value>
                </enumeratedValue>
                <enumeratedValue>
                  <name />
                  <description>RAM-&gt;Flash传输</description>
                  <value>0</value>
                </enumeratedValue>
              </enumeratedValues>
            </field>
            <field>
              <name>CH11RI</name>
              <description>CH11RI  field description</description>
              <bitRange>[9:9]</bitRange>
              <access>read-write</access>
              <enumeratedValues>
                <enumeratedValue>
                  <name />
                  <description>RAM地址递增</description>
                  <value>1</value>
                </enumeratedValue>
                <enumeratedValue>
                  <name />
                  <description>RAM地址递减</description>
                  <value>0</value>
                </enumeratedValue>
              </enumeratedValues>
            </field>
            <field>
              <name>CH11FI</name>
              <description>CH11FI  field description</description>
              <bitRange>[8:8]</bitRange>
              <access>read-write</access>
              <enumeratedValues>
                <enumeratedValue>
                  <name />
                  <description>Flash地址递增</description>
                  <value>1</value>
                </enumeratedValue>
                <enumeratedValue>
                  <name />
                  <description>Flash地址递减</description>
                  <value>0</value>
                </enumeratedValue>
              </enumeratedValues>
            </field>
            <field>
              <name>CH11FTIE</name>
              <description>CH11FTIE  field description</description>
              <bitRange>[2:2]</bitRange>
              <access>read-write</access>
              <enumeratedValues>
                <enumeratedValue>
                  <name />
                  <description>使能传输完成中断</description>
                  <value>1</value>
                </enumeratedValue>
                <enumeratedValue>
                  <name />
                  <description>关闭传输完成中断</description>
                  <value>0</value>
                </enumeratedValue>
              </enumeratedValues>
            </field>
            <field>
              <name>CH11HTIE</name>
              <description>CH11HTIE  field description</description>
              <bitRange>[1:1]</bitRange>
              <access>read-write</access>
              <enumeratedValues>
                <enumeratedValue>
                  <name />
                  <description>使能半程中断</description>
                  <value>1</value>
                </enumeratedValue>
                <enumeratedValue>
                  <name />
                  <description>关闭半程中断</description>
                  <value>0</value>
                </enumeratedValue>
              </enumeratedValues>
            </field>
            <field>
              <name>CH11EN</name>
              <description>CH11EN  field description</description>
              <bitRange>[0:0]</bitRange>
              <access>read-write</access>
              <enumeratedValues>
                <enumeratedValue>
                  <name />
                  <description>启动通道0</description>
                  <value>1</value>
                </enumeratedValue>
                <enumeratedValue>
                  <name />
                  <description>关闭通道0</description>
                  <value>0</value>
                </enumeratedValue>
              </enumeratedValues>
            </field>
          </fields>
        </register>
        <register>
          <name>CH11FAR</name>
          <description>Channel 11 Flash Address Register</description>
          <addressOffset>0x60</addressOffset>
          <size>32</size>
          <access>read-write</access>
          <resetValue>0x00000000</resetValue>
          <fields>
            <field>
              <name>CH11FLSAD</name>
              <description>CH11FLSAD  field description</description>
              <bitRange>[14:0]</bitRange>
              <access>read-write</access>
              <enumeratedValues />
            </field>
          </fields>
        </register>
        <register>
          <name>CH11RAR</name>
          <description>Channel 11 RAM Address Register</description>
          <addressOffset>0x64</addressOffset>
          <size>32</size>
          <access>read-write</access>
          <resetValue>0x00000000</resetValue>
          <fields>
            <field>
              <name>CH7RAMAD</name>
              <description>CH7RAMAD  field description</description>
              <bitRange>[14:0]</bitRange>
              <access>read-write</access>
              <enumeratedValues />
            </field>
          </fields>
        </register>
        <register>
          <name>ISR</name>
          <description>DMA Interrupt Status Register</description>
          <addressOffset>0x68</addressOffset>
          <size>32</size>
          <access>read-write</access>
          <resetValue>0x00000000</resetValue>
          <fields>
            <field>
              <name>DMA_ADDRERR</name>
              <description>DMA_ADDRERR  field description</description>
              <bitRange>[28:28]</bitRange>
              <access>read-write</access>
              <enumeratedValues />
            </field>
            <field>
              <name>DMACHFT</name>
              <description>DMACHFT  field description</description>
              <bitRange>[27:16]</bitRange>
              <access>read-write</access>
              <enumeratedValues>
                <enumeratedValue>
                  <name />
                  <description>对应通道传输完成</description>
                  <value>1</value>
                </enumeratedValue>
                <enumeratedValue>
                  <name />
                  <description>对应通道传输未完成</description>
                  <value>0</value>
                </enumeratedValue>
              </enumeratedValues>
            </field>
            <field>
              <name>DMACHHT</name>
              <description>DMACHHT  field description</description>
              <bitRange>[11:0]</bitRange>
              <access>read-write</access>
              <enumeratedValues />
            </field>
          </fields>
        </register>
        <register>
          <name>CH0CSR</name>
          <description>Channel 0 Control Shadow Register</description>
          <addressOffset>0x100</addressOffset>
          <size>32</size>
          <access>read-write</access>
          <resetValue>0x00000000</resetValue>
          <fields>
            <field>
              <name>CHxTSIZE_SDW</name>
              <description>CHxTSIZE_SDW  field description</description>
              <bitRange>[28:16]</bitRange>
              <access>read-write</access>
              <enumeratedValues />
            </field>
            <field>
              <name>CHxINC_SDW</name>
              <description>CHxINC_SDW  field description</description>
              <bitRange>[11:11]</bitRange>
              <access>read-write</access>
              <enumeratedValues />
            </field>
          </fields>
        </register>
        <register>
          <name>CH0MASR</name>
          <description>Channel 0 Memory Address Shadow Register</description>
          <addressOffset>0x104</addressOffset>
          <size>32</size>
          <access>read-write</access>
          <resetValue>0x00000000</resetValue>
          <fields>
            <field>
              <name>CHxMAD_SDW</name>
              <description>CHxMAD_SDW  field description</description>
              <bitRange>[31:0]</bitRange>
              <access>read-write</access>
              <enumeratedValues />
            </field>
          </fields>
        </register>
        <register>
          <name>CH1CSR</name>
          <description>Channel 0 Control Shadow Register</description>
          <addressOffset>0x108</addressOffset>
          <size>32</size>
          <access>read-write</access>
          <resetValue>0x00000000</resetValue>
          <fields>
            <field>
              <name>CHxTSIZE_SDW</name>
              <description>CHxTSIZE_SDW  field description</description>
              <bitRange>[28:16]</bitRange>
              <access>read-write</access>
              <enumeratedValues />
            </field>
            <field>
              <name>CHxINC_SDW</name>
              <description>CHxINC_SDW  field description</description>
              <bitRange>[11:11]</bitRange>
              <access>read-write</access>
              <enumeratedValues />
            </field>
          </fields>
        </register>
        <register>
          <name>CH1MASR</name>
          <description>Channel 0 Memory Address Shadow Register</description>
          <addressOffset>0x10c</addressOffset>
          <size>32</size>
          <access>read-write</access>
          <resetValue>0x00000000</resetValue>
          <fields>
            <field>
              <name>CHxMAD_SDW</name>
              <description>CHxMAD_SDW  field description</description>
              <bitRange>[31:0]</bitRange>
              <access>read-write</access>
              <enumeratedValues />
            </field>
          </fields>
        </register>
        <register>
          <name>CH2CSR</name>
          <description>Channel 0 Control Shadow Register</description>
          <addressOffset>0x110</addressOffset>
          <size>32</size>
          <access>read-write</access>
          <resetValue>0x00000000</resetValue>
          <fields>
            <field>
              <name>CHxTSIZE_SDW</name>
              <description>CHxTSIZE_SDW  field description</description>
              <bitRange>[28:16]</bitRange>
              <access>read-write</access>
              <enumeratedValues />
            </field>
            <field>
              <name>CHxINC_SDW</name>
              <description>CHxINC_SDW  field description</description>
              <bitRange>[11:11]</bitRange>
              <access>read-write</access>
              <enumeratedValues />
            </field>
          </fields>
        </register>
        <register>
          <name>CH2MASR</name>
          <description>Channel 0 Memory Address Shadow Register</description>
          <addressOffset>0x114</addressOffset>
          <size>32</size>
          <access>read-write</access>
          <resetValue>0x00000000</resetValue>
          <fields>
            <field>
              <name>CHxMAD_SDW</name>
              <description>CHxMAD_SDW  field description</description>
              <bitRange>[31:0]</bitRange>
              <access>read-write</access>
              <enumeratedValues />
            </field>
          </fields>
        </register>
        <register>
          <name>CH3CSR</name>
          <description>Channel 0 Control Shadow Register</description>
          <addressOffset>0x118</addressOffset>
          <size>32</size>
          <access>read-write</access>
          <resetValue>0x00000000</resetValue>
          <fields>
            <field>
              <name>CHxTSIZE_SDW</name>
              <description>CHxTSIZE_SDW  field description</description>
              <bitRange>[28:16]</bitRange>
              <access>read-write</access>
              <enumeratedValues />
            </field>
            <field>
              <name>CHxINC_SDW</name>
              <description>CHxINC_SDW  field description</description>
              <bitRange>[11:11]</bitRange>
              <access>read-write</access>
              <enumeratedValues />
            </field>
          </fields>
        </register>
        <register>
          <name>CH3MASR</name>
          <description>Channel 0 Memory Address Shadow Register</description>
          <addressOffset>0x11c</addressOffset>
          <size>32</size>
          <access>read-write</access>
          <resetValue>0x00000000</resetValue>
          <fields>
            <field>
              <name>CHxMAD_SDW</name>
              <description>CHxMAD_SDW  field description</description>
              <bitRange>[31:0]</bitRange>
              <access>read-write</access>
              <enumeratedValues />
            </field>
          </fields>
        </register>
        <register>
          <name>CH4CSR</name>
          <description>Channel 0 Control Shadow Register</description>
          <addressOffset>0x120</addressOffset>
          <size>32</size>
          <access>read-write</access>
          <resetValue>0x00000000</resetValue>
          <fields>
            <field>
              <name>CHxTSIZE_SDW</name>
              <description>CHxTSIZE_SDW  field description</description>
              <bitRange>[28:16]</bitRange>
              <access>read-write</access>
              <enumeratedValues />
            </field>
            <field>
              <name>CHxINC_SDW</name>
              <description>CHxINC_SDW  field description</description>
              <bitRange>[11:11]</bitRange>
              <access>read-write</access>
              <enumeratedValues />
            </field>
          </fields>
        </register>
        <register>
          <name>CH4MASR</name>
          <description>Channel 0 Memory Address Shadow Register</description>
          <addressOffset>0x124</addressOffset>
          <size>32</size>
          <access>read-write</access>
          <resetValue>0x00000000</resetValue>
          <fields>
            <field>
              <name>CHxMAD_SDW</name>
              <description>CHxMAD_SDW  field description</description>
              <bitRange>[31:0]</bitRange>
              <access>read-write</access>
              <enumeratedValues />
            </field>
          </fields>
        </register>
        <register>
          <name>CH5CSR</name>
          <description>Channel 0 Control Shadow Register</description>
          <addressOffset>0x128</addressOffset>
          <size>32</size>
          <access>read-write</access>
          <resetValue>0x00000000</resetValue>
          <fields>
            <field>
              <name>CHxTSIZE_SDW</name>
              <description>CHxTSIZE_SDW  field description</description>
              <bitRange>[28:16]</bitRange>
              <access>read-write</access>
              <enumeratedValues />
            </field>
            <field>
              <name>CHxINC_SDW</name>
              <description>CHxINC_SDW  field description</description>
              <bitRange>[11:11]</bitRange>
              <access>read-write</access>
              <enumeratedValues />
            </field>
          </fields>
        </register>
        <register>
          <name>CH5MASR</name>
          <description>Channel 0 Memory Address Shadow Register</description>
          <addressOffset>0x12c</addressOffset>
          <size>32</size>
          <access>read-write</access>
          <resetValue>0x00000000</resetValue>
          <fields>
            <field>
              <name>CHxMAD_SDW</name>
              <description>CHxMAD_SDW  field description</description>
              <bitRange>[31:0]</bitRange>
              <access>read-write</access>
              <enumeratedValues />
            </field>
          </fields>
        </register>
        <register>
          <name>CH6CSR</name>
          <description>Channel 0 Control Shadow Register</description>
          <addressOffset>0x130</addressOffset>
          <size>32</size>
          <access>read-write</access>
          <resetValue>0x00000000</resetValue>
          <fields>
            <field>
              <name>CHxTSIZE_SDW</name>
              <description>CHxTSIZE_SDW  field description</description>
              <bitRange>[28:16]</bitRange>
              <access>read-write</access>
              <enumeratedValues />
            </field>
            <field>
              <name>CHxINC_SDW</name>
              <description>CHxINC_SDW  field description</description>
              <bitRange>[11:11]</bitRange>
              <access>read-write</access>
              <enumeratedValues />
            </field>
          </fields>
        </register>
        <register>
          <name>CH6MASR</name>
          <description>Channel 0 Memory Address Shadow Register</description>
          <addressOffset>0x134</addressOffset>
          <size>32</size>
          <access>read-write</access>
          <resetValue>0x00000000</resetValue>
          <fields>
            <field>
              <name>CHxMAD_SDW</name>
              <description>CHxMAD_SDW  field description</description>
              <bitRange>[31:0]</bitRange>
              <access>read-write</access>
              <enumeratedValues />
            </field>
          </fields>
        </register>
      </registers>
    </peripheral>
    <peripheral>
      <name>CRC</name>
      <description>CRC module information</description>
      <groupName>CRC</groupName>
      <baseAddress>0x40010000</baseAddress>
      <size>32</size>
      <access>read-write</access>
      <addressBlock>
        <offset>0</offset>
        <size>0x20</size>
        <usage>registers</usage>
      </addressBlock>
      <registers>
        <register>
          <name>DR</name>
          <description>CRC Data Register</description>
          <addressOffset>0x0</addressOffset>
          <size>32</size>
          <access>read-write</access>
          <resetValue>0x00000000</resetValue>
          <fields>
            <field>
              <name>DR</name>
              <description>DR  field description</description>
              <bitRange>[31:0]</bitRange>
              <access>read-write</access>
              <enumeratedValues>
                <enumeratedValue>
                  <name />
                  <description>若word操作使能，则对CRCDR[31:0]进行计算，共4次byte运算（由低到高）；否则对CRCDR[7:0]进行计算，共1次byte运算。</description>
                  <value>0</value>
                </enumeratedValue>
                <enumeratedValue>
                  <name />
                  <description>若为7位多项式结果保存在CRCDR[6:0]，若为8位多项式结果保存在CRCDR[7:0]，若为16位多项式结果保存在CRCDR[15:0]，若为32位多项式结果保存在CRCDR[31:0]。</description>
                  <value>0</value>
                </enumeratedValue>
              </enumeratedValues>
            </field>
          </fields>
        </register>
        <register>
          <name>CR</name>
          <description>CRC Control Register</description>
          <addressOffset>0x4</addressOffset>
          <size>32</size>
          <access>read-write</access>
          <resetValue>0x00000001</resetValue>
          <fields>
            <field>
              <name>OPWD</name>
              <description>OPWD  field description</description>
              <bitRange>[9:9]</bitRange>
              <access>read-write</access>
              <enumeratedValues>
                <enumeratedValue>
                  <name />
                  <description>字节操作，CRC计算仅针对CRCDR最低字节进行</description>
                  <value>0</value>
                </enumeratedValue>
                <enumeratedValue>
                  <name />
                  <description>字操作，CRC计算针对CRCDR全部4字节进行</description>
                  <value>1</value>
                </enumeratedValue>
              </enumeratedValues>
            </field>
            <field>
              <name>PARA</name>
              <description>PARA  field description</description>
              <bitRange>[8:8]</bitRange>
              <access>read-write</access>
              <enumeratedValues>
                <enumeratedValue>
                  <name />
                  <description>串行运算，计算1个字节需要8个时钟周期</description>
                  <value>0</value>
                </enumeratedValue>
                <enumeratedValue>
                  <name />
                  <description>并行计算，计算1个字节需要1个时钟周期</description>
                  <value>1</value>
                </enumeratedValue>
              </enumeratedValues>
            </field>
            <field>
              <name>RFLTIN</name>
              <description>RFLTIN  field description</description>
              <bitRange>[7:6]</bitRange>
              <access>read-write</access>
              <enumeratedValues>
                <enumeratedValue>
                  <name />
                  <description>输入不反转</description>
                  <value>0</value>
                </enumeratedValue>
                <enumeratedValue>
                  <name />
                  <description>输入按字节反转</description>
                  <value>1</value>
                </enumeratedValue>
                <enumeratedValue>
                  <name />
                  <description>输入按半字反转</description>
                  <value>2</value>
                </enumeratedValue>
                <enumeratedValue>
                  <name />
                  <description>输入按字反转</description>
                  <value>3</value>
                </enumeratedValue>
                <enumeratedValue>
                  <name />
                  <description>计算数据为0x11223344，</description>
                  <value>0</value>
                </enumeratedValue>
              </enumeratedValues>
            </field>
            <field>
              <name>RFLTO</name>
              <description>RFLTO  field description</description>
              <bitRange>[5:5]</bitRange>
              <access>read-write</access>
              <enumeratedValues>
                <enumeratedValue>
                  <name />
                  <description>输出不反转</description>
                  <value>0</value>
                </enumeratedValue>
                <enumeratedValue>
                  <name />
                  <description>输出按字节反转</description>
                  <value>1</value>
                </enumeratedValue>
                <enumeratedValue>
                  <name />
                  <description />
                  <value>0</value>
                </enumeratedValue>
                <enumeratedValue>
                  <name />
                  <description>此结果不一定为最终输出结果，还需要看XOR是否为1，详见本寄存器bit2说明</description>
                  <value>0</value>
                </enumeratedValue>
              </enumeratedValues>
            </field>
            <field>
              <name>RES</name>
              <description>RES  field description</description>
              <bitRange>[4:4]</bitRange>
              <access>read-only</access>
              <enumeratedValues>
                <enumeratedValue>
                  <name />
                  <description>CRC结果为0</description>
                  <value>0</value>
                </enumeratedValue>
                <enumeratedValue>
                  <name />
                  <description>CRC结果非全0</description>
                  <value>1</value>
                </enumeratedValue>
              </enumeratedValues>
            </field>
            <field>
              <name>BUSY</name>
              <description>BUSY  field description</description>
              <bitRange>[3:3]</bitRange>
              <access>read-only</access>
              <enumeratedValues>
                <enumeratedValue>
                  <name />
                  <description>CRC运算结束</description>
                  <value>0</value>
                </enumeratedValue>
                <enumeratedValue>
                  <name />
                  <description>CRC运算进行中</description>
                  <value>1</value>
                </enumeratedValue>
              </enumeratedValues>
            </field>
            <field>
              <name>XOR</name>
              <description>XOR  field description</description>
              <bitRange>[2:2]</bitRange>
              <access>read-write</access>
              <enumeratedValues>
                <enumeratedValue>
                  <name />
                  <description>输出不异或CRC_XOR寄存器</description>
                  <value>0</value>
                </enumeratedValue>
                <enumeratedValue>
                  <name />
                  <description>输出异或CRC_XOR寄存器</description>
                  <value>1</value>
                </enumeratedValue>
              </enumeratedValues>
            </field>
            <field>
              <name>SEL</name>
              <description>SEL  field description</description>
              <bitRange>[1:0]</bitRange>
              <access>read-write</access>
              <enumeratedValues>
                <enumeratedValue>
                  <name />
                  <description>32位</description>
                  <value>0</value>
                </enumeratedValue>
                <enumeratedValue>
                  <name />
                  <description>16位</description>
                  <value>1</value>
                </enumeratedValue>
                <enumeratedValue>
                  <name />
                  <description>8位</description>
                  <value>2</value>
                </enumeratedValue>
                <enumeratedValue>
                  <name />
                  <description>7位</description>
                  <value>3</value>
                </enumeratedValue>
              </enumeratedValues>
            </field>
          </fields>
        </register>
        <register>
          <name>LFSR</name>
          <description>CRC Linear Feedback Shift Register</description>
          <addressOffset>0x8</addressOffset>
          <size>32</size>
          <access>read-write</access>
          <resetValue>0x00000000</resetValue>
          <fields>
            <field>
              <name>LFSR</name>
              <description>LFSR  field description</description>
              <bitRange>[31:0]</bitRange>
              <access>read-write</access>
              <enumeratedValues />
            </field>
          </fields>
        </register>
        <register>
          <name>XOR</name>
          <description>CRC output XOR Register</description>
          <addressOffset>0xc</addressOffset>
          <size>32</size>
          <access>read-write</access>
          <resetValue>0x00000000</resetValue>
          <fields>
            <field>
              <name>XOR</name>
              <description>XOR  field description</description>
              <bitRange>[31:0]</bitRange>
              <access>read-write</access>
              <enumeratedValues />
            </field>
          </fields>
        </register>
        <register>
          <name>POLY</name>
          <description>CRC Polynominal Register</description>
          <addressOffset>0x1c</addressOffset>
          <size>32</size>
          <access>read-write</access>
          <resetValue>0x00000000</resetValue>
          <fields>
            <field>
              <name>POLY</name>
              <description>POLY  field description</description>
              <bitRange>[31:0]</bitRange>
              <access>read-write</access>
              <enumeratedValues />
            </field>
          </fields>
        </register>
      </registers>
    </peripheral>
    <peripheral>
      <name>BT1</name>
      <description>BT1 module information</description>
      <groupName>BT</groupName>
      <baseAddress>0x40013000</baseAddress>
      <size>32</size>
      <access>read-write</access>
      <addressBlock>
        <offset>0</offset>
        <size>0x44</size>
        <usage>registers</usage>
      </addressBlock>
      <registers>
        <register>
          <name>CR1</name>
          <description>Basic Timer 1 Control Register 1</description>
          <addressOffset>0x0</addressOffset>
          <size>32</size>
          <access>read-write</access>
          <resetValue>0x00000000</resetValue>
          <fields>
            <field>
              <name>CHEN</name>
              <description>CHEN  field description</description>
              <bitRange>[7:7]</bitRange>
              <access>read-write</access>
              <enumeratedValues>
                <enumeratedValue>
                  <name />
                  <description>启动高8bit计数器，在计数器模式下启动时将预置数值和加载值分别加载至计数器和比较寄存器；捕捉模式下启动时计数器由零开始自由计数，计数到0xFFFF后产生溢出信号然后由零开始重新计数，捕捉功能只工作在16位模式；在16位的定时/计数和捕捉模式下CHEN作为16位计数器的启动控制，CLEN自动失效</description>
                  <value>1</value>
                </enumeratedValue>
                <enumeratedValue>
                  <name />
                  <description>停止高8bit计数器</description>
                  <value>0</value>
                </enumeratedValue>
              </enumeratedValues>
            </field>
            <field>
              <name>CLEN</name>
              <description>CLEN  field description</description>
              <bitRange>[6:6]</bitRange>
              <access>read-write</access>
              <enumeratedValues>
                <enumeratedValue>
                  <name />
                  <description>启动低8bit计数器，在计数器模式下启动时将预置数值和加载值分别加载至计数器和比较寄存器；捕捉模式下启动时计数器由零开始自由计数，计数到0xFFFF后产生溢出信号然后由零开始重新计数，捕捉功能只工作在16位模式；在16位的定时/计数和捕捉模式下CHEN作为计数器的启动控制，CLEN自动失效</description>
                  <value>1</value>
                </enumeratedValue>
                <enumeratedValue>
                  <name />
                  <description>停止低8bit计数器计数</description>
                  <value>0</value>
                </enumeratedValue>
              </enumeratedValues>
            </field>
            <field>
              <name>MODE</name>
              <description>MODE  field description</description>
              <bitRange>[5:5]</bitRange>
              <access>read-write</access>
              <enumeratedValues>
                <enumeratedValue>
                  <name />
                  <description>16位捕捉模式</description>
                  <value>1</value>
                </enumeratedValue>
                <enumeratedValue>
                  <name />
                  <description>8位定时/计数模式，若高位计数器计数源选择为低位计数器的溢出信号，则可实现16位定时/计数模式</description>
                  <value>0</value>
                </enumeratedValue>
              </enumeratedValues>
            </field>
            <field>
              <name>EDGESEL</name>
              <description>EDGESEL  field description</description>
              <bitRange>[4:4]</bitRange>
              <access>read-write</access>
              <enumeratedValues>
                <enumeratedValue>
                  <name />
                  <description>计数模式采样计数源下降沿，周期捕捉模式时下沿捕捉</description>
                  <value>1</value>
                </enumeratedValue>
                <enumeratedValue>
                  <name />
                  <description>计数模式采样计数源上升沿，周期捕捉模式时上沿捕捉</description>
                  <value>0</value>
                </enumeratedValue>
                <enumeratedValue>
                  <name />
                  <description>不支持系统时钟的下降沿计数，捕捉源和计数源为系统时钟时选择下降沿将不会有效计数。</description>
                  <value>0</value>
                </enumeratedValue>
              </enumeratedValues>
            </field>
            <field>
              <name>CAPMOD</name>
              <description>CAPMOD  field description</description>
              <bitRange>[3:3]</bitRange>
              <access>read-write</access>
              <enumeratedValues>
                <enumeratedValue>
                  <name />
                  <description>脉冲宽度捕捉</description>
                  <value>1</value>
                </enumeratedValue>
                <enumeratedValue>
                  <name />
                  <description>脉冲周期捕捉</description>
                  <value>0</value>
                </enumeratedValue>
              </enumeratedValues>
            </field>
            <field>
              <name>CAPCLR</name>
              <description>CAPCLR  field description</description>
              <bitRange>[2:2]</bitRange>
              <access>read-write</access>
              <enumeratedValues>
                <enumeratedValue>
                  <name />
                  <description>不论在脉冲宽度还是周期捕捉情况下，捕捉到第一个沿后将计数器清零产生中断，捕捉到第二个沿后锁存（锁存到高低位预置数寄存器）计数值并同时清零计数器</description>
                  <value>1</value>
                </enumeratedValue>
                <enumeratedValue>
                  <name />
                  <description>捕捉不清零，计数器一直自由计数</description>
                  <value>0</value>
                </enumeratedValue>
              </enumeratedValues>
            </field>
            <field>
              <name>CAPONCE</name>
              <description>CAPONCE  field description</description>
              <bitRange>[1:1]</bitRange>
              <access>read-write</access>
              <enumeratedValues>
                <enumeratedValue>
                  <name />
                  <description>单次捕捉有效，在捕捉到一次脉冲宽度或脉冲周期后计数器停止，若需要再次捕捉需重新启动</description>
                  <value>1</value>
                </enumeratedValue>
                <enumeratedValue>
                  <name />
                  <description>连续捕捉</description>
                  <value>0</value>
                </enumeratedValue>
              </enumeratedValues>
            </field>
            <field>
              <name>PWM</name>
              <description>PWM  field description</description>
              <bitRange>[0:0]</bitRange>
              <access>read-write</access>
              <enumeratedValues>
                <enumeratedValue>
                  <name />
                  <description>PWM输出使能</description>
                  <value>1</value>
                </enumeratedValue>
                <enumeratedValue>
                  <name />
                  <description>PWM 输出不使能</description>
                  <value>0</value>
                </enumeratedValue>
              </enumeratedValues>
            </field>
          </fields>
        </register>
        <register>
          <name>CR2</name>
          <description>Basic Timer 1 Control Register 2</description>
          <addressOffset>0x4</addressOffset>
          <size>32</size>
          <access>read-write</access>
          <resetValue>0x00000000</resetValue>
          <fields>
            <field>
              <name>SIG2SEL</name>
              <description>SIG2SEL  field description</description>
              <bitRange>[7:7]</bitRange>
              <access>read-write</access>
              <enumeratedValues>
                <enumeratedValue>
                  <name />
                  <description>内部计数源信号选择Group2</description>
                  <value>1</value>
                </enumeratedValue>
                <enumeratedValue>
                  <name />
                  <description>内部计数源信号选择Group1</description>
                  <value>0</value>
                </enumeratedValue>
              </enumeratedValues>
            </field>
            <field>
              <name>SIG1SEL</name>
              <description>SIG1SEL  field description</description>
              <bitRange>[6:6]</bitRange>
              <access>read-write</access>
              <enumeratedValues>
                <enumeratedValue>
                  <name />
                  <description>内部捕捉源信号选择Group1</description>
                  <value>1</value>
                </enumeratedValue>
                <enumeratedValue>
                  <name />
                  <description>内部捕捉源信号选择Group2</description>
                  <value>0</value>
                </enumeratedValue>
              </enumeratedValues>
            </field>
            <field>
              <name>CNTHSEL</name>
              <description>CNTHSEL  field description</description>
              <bitRange>[5:4]</bitRange>
              <access>read-write</access>
              <enumeratedValues>
                <enumeratedValue>
                  <name />
                  <description>选择ET1的低位计数器的溢出信号，与低位计数器组成16位计数器</description>
                  <value>0</value>
                </enumeratedValue>
                <enumeratedValue>
                  <name />
                  <description>选择ET1的低位计数器的溢出信号，与低位计数器组成16位计数器</description>
                  <value>3</value>
                </enumeratedValue>
                <enumeratedValue>
                  <name />
                  <description>选择内部捕捉源信号</description>
                  <value>1</value>
                </enumeratedValue>
                <enumeratedValue>
                  <name />
                  <description>选择内部计数源信号或外部DIR输入组合信号</description>
                  <value>2</value>
                </enumeratedValue>
              </enumeratedValues>
            </field>
            <field>
              <name>DIREN</name>
              <description>DIREN  field description</description>
              <bitRange>[3:3]</bitRange>
              <access>read-write</access>
              <enumeratedValues>
                <enumeratedValue>
                  <name />
                  <description>外部输入的DIR信号有效，此时高低位计数器是否计数可由外部输入的DIR信号控制。</description>
                  <value>1</value>
                </enumeratedValue>
                <enumeratedValue>
                  <name />
                  <description>外部输入的DIR信号无效，此时高低位计数器是否计数将由内部控制信号控制。</description>
                  <value>0</value>
                </enumeratedValue>
              </enumeratedValues>
            </field>
            <field>
              <name>STDIR</name>
              <description>STDIR  field description</description>
              <bitRange>[2:2]</bitRange>
              <access>read-write</access>
              <enumeratedValues>
                <enumeratedValue>
                  <name />
                  <description>内部DIR信号为高电平，则高8位计数器计数</description>
                  <value>1</value>
                </enumeratedValue>
              </enumeratedValues>
            </field>
            <field>
              <name>SRCSEL</name>
              <description>SRCSEL  field description</description>
              <bitRange>[1:1]</bitRange>
              <access>read-write</access>
              <enumeratedValues>
                <enumeratedValue>
                  <name />
                  <description>低位计数器计数使能端选则由寄存器STDIR或外部EX_SIG2输入控制。</description>
                  <value>0</value>
                </enumeratedValue>
              </enumeratedValues>
            </field>
            <field>
              <name>DIRPO</name>
              <description>DIRPO  field description</description>
              <bitRange>[0:0]</bitRange>
              <access>read-write</access>
              <enumeratedValues>
                <enumeratedValue>
                  <name />
                  <description>对外部输入DIR信号EX_SIG2反向</description>
                  <value>1</value>
                </enumeratedValue>
                <enumeratedValue>
                  <name />
                  <description>对外部输入DIR信号EX_SIG2不反向</description>
                  <value>0</value>
                </enumeratedValue>
              </enumeratedValues>
            </field>
          </fields>
        </register>
        <register>
          <name>CFGR1</name>
          <description>Basic Timer 1 Config Register 1</description>
          <addressOffset>0x8</addressOffset>
          <size>32</size>
          <access>read-write</access>
          <resetValue>0x00000000</resetValue>
          <fields>
            <field>
              <name>RTCSEL2</name>
              <description>RTCSEL2  field description</description>
              <bitRange>[7:6]</bitRange>
              <access>read-write</access>
              <enumeratedValues>
                <enumeratedValue>
                  <name />
                  <description>32768Hz，XTLF时钟输出</description>
                  <value>0</value>
                </enumeratedValue>
                <enumeratedValue>
                  <name />
                  <description>RTCSec，由RTC模块输出的秒信号</description>
                  <value>1</value>
                </enumeratedValue>
                <enumeratedValue>
                  <name />
                  <description>RTCMin，由RTC模块输出的分钟信号</description>
                  <value>2</value>
                </enumeratedValue>
                <enumeratedValue>
                  <name />
                  <description>RFU</description>
                  <value>3</value>
                </enumeratedValue>
              </enumeratedValues>
            </field>
            <field>
              <name>RTCSEL1</name>
              <description>RTCSEL1  field description</description>
              <bitRange>[5:4]</bitRange>
              <access>read-write</access>
              <enumeratedValues>
                <enumeratedValue>
                  <name />
                  <description>32768Hz，XTLF时钟输出</description>
                  <value>0</value>
                </enumeratedValue>
                <enumeratedValue>
                  <name />
                  <description>RTCSec，由RTC模块输出的秒信号</description>
                  <value>1</value>
                </enumeratedValue>
                <enumeratedValue>
                  <name />
                  <description>RTCMin，由RTC模块输出的分钟信号</description>
                  <value>2</value>
                </enumeratedValue>
                <enumeratedValue>
                  <name />
                  <description>RFU</description>
                  <value>3</value>
                </enumeratedValue>
              </enumeratedValues>
            </field>
            <field>
              <name>GRP2SEL</name>
              <description>GRP2SEL  field description</description>
              <bitRange>[3:2]</bitRange>
              <access>read-write</access>
              <enumeratedValues>
                <enumeratedValue>
                  <name />
                  <description>APBCLK</description>
                  <value>0</value>
                </enumeratedValue>
                <enumeratedValue>
                  <name />
                  <description>RTCOUT2</description>
                  <value>1</value>
                </enumeratedValue>
                <enumeratedValue>
                  <name />
                  <description>IN_SIG2，内部输入信号2</description>
                  <value>2</value>
                </enumeratedValue>
                <enumeratedValue>
                  <name />
                  <description>EX_SIG2，外部输入信号2</description>
                  <value>3</value>
                </enumeratedValue>
                <enumeratedValue>
                  <name />
                  <description>不支持APBCLK的下降沿捕捉和计数，捕捉源和计数源为APBCLK时选择下降沿将不会有效捕捉和计数。</description>
                  <value>0</value>
                </enumeratedValue>
              </enumeratedValues>
            </field>
            <field>
              <name>GRP1SEL</name>
              <description>GRP1SEL  field description</description>
              <bitRange>[1:0]</bitRange>
              <access>read-write</access>
              <enumeratedValues>
                <enumeratedValue>
                  <name />
                  <description>APBCLK</description>
                  <value>0</value>
                </enumeratedValue>
                <enumeratedValue>
                  <name />
                  <description>RTCOUT1</description>
                  <value>1</value>
                </enumeratedValue>
                <enumeratedValue>
                  <name />
                  <description>IN_SIG1，内部输入信号1</description>
                  <value>2</value>
                </enumeratedValue>
                <enumeratedValue>
                  <name />
                  <description>EX_SIG1，外部输入信号1</description>
                  <value>3</value>
                </enumeratedValue>
                <enumeratedValue>
                  <name />
                  <description>不支持APBCLK的下降沿捕捉和计数，捕捉源和计数源为APBCLK时选择下降沿将不会有效捕捉和计数。</description>
                  <value>0</value>
                </enumeratedValue>
              </enumeratedValues>
            </field>
          </fields>
        </register>
        <register>
          <name>CFGR2</name>
          <description>Basic Timer 1 Config Register 2</description>
          <addressOffset>0xc</addressOffset>
          <size>32</size>
          <access>read-write</access>
          <resetValue>0x00000000</resetValue>
          <fields>
            <field>
              <name>EXSEL2</name>
              <description>EXSEL2  field description</description>
              <bitRange>[7:6]</bitRange>
              <access>read-write</access>
              <enumeratedValues>
                <enumeratedValue>
                  <name />
                  <description>BT1_IN0/BT2_IN0</description>
                  <value>0</value>
                </enumeratedValue>
                <enumeratedValue>
                  <name />
                  <description>BT1_IN1/BT2_IN1</description>
                  <value>1</value>
                </enumeratedValue>
                <enumeratedValue>
                  <name />
                  <description>BT1_IN2/BT2_IN2</description>
                  <value>2</value>
                </enumeratedValue>
                <enumeratedValue>
                  <name />
                  <description>BT1_IN3/BT2_IN3</description>
                  <value>3</value>
                </enumeratedValue>
              </enumeratedValues>
            </field>
            <field>
              <name>EXSEL1</name>
              <description>EXSEL1  field description</description>
              <bitRange>[5:4]</bitRange>
              <access>read-write</access>
              <enumeratedValues>
                <enumeratedValue>
                  <name />
                  <description>BT1_IN0/BT2_IN0</description>
                  <value>0</value>
                </enumeratedValue>
                <enumeratedValue>
                  <name />
                  <description>BT1_IN1/BT2_IN1</description>
                  <value>1</value>
                </enumeratedValue>
                <enumeratedValue>
                  <name />
                  <description>BT1_IN2/BT2_IN2</description>
                  <value>2</value>
                </enumeratedValue>
                <enumeratedValue>
                  <name />
                  <description>BT1_IN3/BT2_IN3</description>
                  <value>3</value>
                </enumeratedValue>
              </enumeratedValues>
            </field>
            <field>
              <name>INSEL2</name>
              <description>INSEL2  field description</description>
              <bitRange>[3:2]</bitRange>
              <access>read-write</access>
              <enumeratedValues>
                <enumeratedValue>
                  <name />
                  <description>UART_RX3/UART_RX3</description>
                  <value>0</value>
                </enumeratedValue>
                <enumeratedValue>
                  <name />
                  <description>UART_RX4/UART_RX4</description>
                  <value>1</value>
                </enumeratedValue>
                <enumeratedValue>
                  <name />
                  <description>UART_RX5/UART_RX5</description>
                  <value>2</value>
                </enumeratedValue>
                <enumeratedValue>
                  <name />
                  <description>RCLP/BT1_OUT</description>
                  <value>3</value>
                </enumeratedValue>
              </enumeratedValues>
            </field>
            <field>
              <name>INSEL1</name>
              <description>INSEL1  field description</description>
              <bitRange>[1:0]</bitRange>
              <access>read-write</access>
              <enumeratedValues>
                <enumeratedValue>
                  <name />
                  <description>UART_RX0/UART_RX0</description>
                  <value>0</value>
                </enumeratedValue>
                <enumeratedValue>
                  <name />
                  <description>UART_RX1/UART_RX1</description>
                  <value>1</value>
                </enumeratedValue>
                <enumeratedValue>
                  <name />
                  <description>UART_RX2/UART_RX2</description>
                  <value>2</value>
                </enumeratedValue>
                <enumeratedValue>
                  <name />
                  <description>RCLP/RCLP</description>
                  <value>3</value>
                </enumeratedValue>
              </enumeratedValues>
            </field>
          </fields>
        </register>
        <register>
          <name>PRES</name>
          <description>Basic Timer 1 Prescaler Register</description>
          <addressOffset>0x10</addressOffset>
          <size>32</size>
          <access>read-write</access>
          <resetValue>0x00000000</resetValue>
          <fields>
            <field>
              <name>PRESCALE</name>
              <description>PRESCALE  field description</description>
              <bitRange>[7:0]</bitRange>
              <access>read-write</access>
              <enumeratedValues />
            </field>
          </fields>
        </register>
        <register>
          <name>LOADCR</name>
          <description>Basic Timer 1 Load Control Register</description>
          <addressOffset>0x14</addressOffset>
          <size>32</size>
          <access>read-write</access>
          <resetValue>0x00000000</resetValue>
          <fields>
            <field>
              <name>LHEN</name>
              <description>LHEN  field description</description>
              <bitRange>[4:4]</bitRange>
              <access>read-write</access>
              <enumeratedValues />
            </field>
            <field>
              <name>LLEN</name>
              <description>LLEN  field description</description>
              <bitRange>[0:0]</bitRange>
              <access>read-write</access>
              <enumeratedValues />
            </field>
          </fields>
        </register>
        <register>
          <name>CNTL</name>
          <description>Basic Timer 1 Counter Low</description>
          <addressOffset>0x18</addressOffset>
          <size>32</size>
          <access>read-write</access>
          <resetValue>0x00000000</resetValue>
          <fields>
            <field>
              <name>CNTL</name>
              <description>CNTL  field description</description>
              <bitRange>[7:0]</bitRange>
              <access>read-only</access>
              <enumeratedValues />
            </field>
          </fields>
        </register>
        <register>
          <name>CNTH</name>
          <description>Basic Timer 1 Counter High</description>
          <addressOffset>0x1c</addressOffset>
          <size>32</size>
          <access>read-write</access>
          <resetValue>0x00000000</resetValue>
          <fields>
            <field>
              <name>CNTH</name>
              <description>CNTH  field description</description>
              <bitRange>[7:0]</bitRange>
              <access>read-only</access>
              <enumeratedValues />
            </field>
          </fields>
        </register>
        <register>
          <name>PRESET</name>
          <description>Basic Timer 1 Preset Register</description>
          <addressOffset>0x20</addressOffset>
          <size>32</size>
          <access>read-write</access>
          <resetValue>0x00000000</resetValue>
          <fields>
            <field>
              <name>PRESETH</name>
              <description>PRESETH  field description</description>
              <bitRange>[15:8]</bitRange>
              <access>read-write</access>
              <enumeratedValues />
            </field>
            <field>
              <name>PRESETL</name>
              <description>PRESETL  field description</description>
              <bitRange>[7:0]</bitRange>
              <access>read-write</access>
              <enumeratedValues />
            </field>
          </fields>
        </register>
        <register>
          <name>LOADL</name>
          <description>Basic Timer 1 Load Register Low</description>
          <addressOffset>0x24</addressOffset>
          <size>32</size>
          <access>read-write</access>
          <resetValue>0x00000000</resetValue>
          <fields>
            <field>
              <name>LOADL</name>
              <description>LOADL  field description</description>
              <bitRange>[7:0]</bitRange>
              <access>read-write</access>
              <enumeratedValues />
            </field>
          </fields>
        </register>
        <register>
          <name>LOADH</name>
          <description>Basic Timer 1 Load Register High</description>
          <addressOffset>0x28</addressOffset>
          <size>32</size>
          <access>read-write</access>
          <resetValue>0x00000000</resetValue>
          <fields>
            <field>
              <name>LOADH</name>
              <description>LOADH  field description</description>
              <bitRange>[7:0]</bitRange>
              <access>read-write</access>
              <enumeratedValues />
            </field>
          </fields>
        </register>
        <register>
          <name>CMPL</name>
          <description>Basic Timer 1 Compare Register Low</description>
          <addressOffset>0x2c</addressOffset>
          <size>32</size>
          <access>read-write</access>
          <resetValue>0x00000000</resetValue>
          <fields>
            <field>
              <name>CMPL</name>
              <description>CMPL  field description</description>
              <bitRange>[7:0]</bitRange>
              <access>read-write</access>
              <enumeratedValues />
            </field>
          </fields>
        </register>
        <register>
          <name>CMPH</name>
          <description>Basic Timer 1 Compare Register High</description>
          <addressOffset>0x30</addressOffset>
          <size>32</size>
          <access>read-write</access>
          <resetValue>0x00000000</resetValue>
          <fields>
            <field>
              <name>CMPH</name>
              <description>CMPH  field description</description>
              <bitRange>[7:0]</bitRange>
              <access>read-write</access>
              <enumeratedValues />
            </field>
          </fields>
        </register>
        <register>
          <name>OUTCNT</name>
          <description>Basic Timer 1 Output Counter</description>
          <addressOffset>0x34</addressOffset>
          <size>32</size>
          <access>read-write</access>
          <resetValue>0x00000000</resetValue>
          <fields>
            <field>
              <name>OUTCNT</name>
              <description>OUTCNT  field description</description>
              <bitRange>[11:0]</bitRange>
              <access>read-write</access>
              <enumeratedValues />
            </field>
          </fields>
        </register>
        <register>
          <name>OCR</name>
          <description>Basic Timer 1 Output Control Register</description>
          <addressOffset>0x38</addressOffset>
          <size>32</size>
          <access>read-write</access>
          <resetValue>0x00000000</resetValue>
          <fields>
            <field>
              <name>OUTCLR</name>
              <description>OUTCLR  field description</description>
              <bitRange>[5:5]</bitRange>
              <access>read-write</access>
              <enumeratedValues>
                <enumeratedValue>
                  <name />
                  <description>输出清零，若设置了输出反向则清零后输出为高电平，反之为低电平（只适用于OUTMOD输出模式=1输出之前反向电平的情况，OUTMOD输出模式=0输出脉冲模式无效）</description>
                  <value>1</value>
                </enumeratedValue>
                <enumeratedValue>
                  <name />
                  <description>写入无效</description>
                  <value>0</value>
                </enumeratedValue>
              </enumeratedValues>
            </field>
            <field>
              <name>OUTINV</name>
              <description>OUTINV  field description</description>
              <bitRange>[4:4]</bitRange>
              <access>read-write</access>
              <enumeratedValues>
                <enumeratedValue>
                  <name />
                  <description>输出电平取反（CHEN/CLEN有效后，ETOUT信号输出本信号在CHEN/CLEN有效之前的状态）</description>
                  <value>1</value>
                </enumeratedValue>
                <enumeratedValue>
                  <name />
                  <description>输出电平不取反（CHEN/CLEN有效后，ETOUT信号输出本信号在CHEN/CLEN有效之前状态的反态）</description>
                  <value>0</value>
                </enumeratedValue>
              </enumeratedValues>
            </field>
            <field>
              <name>OUTMOD</name>
              <description>OUTMOD  field description</description>
              <bitRange>[3:3]</bitRange>
              <access>read-write</access>
              <enumeratedValues>
                <enumeratedValue>
                  <name />
                  <description>输出之前的反向电平</description>
                  <value>1</value>
                </enumeratedValue>
                <enumeratedValue>
                  <name />
                  <description>输出脉冲，脉冲宽度可调</description>
                  <value>0</value>
                </enumeratedValue>
              </enumeratedValues>
            </field>
            <field>
              <name>OUTSEL</name>
              <description>OUTSEL  field description</description>
              <bitRange>[2:0]</bitRange>
              <access>read-write</access>
              <enumeratedValues>
                <enumeratedValue>
                  <name />
                  <description>输出高位计数器的比较信号，只在计数模式有效。</description>
                  <value>0</value>
                </enumeratedValue>
                <enumeratedValue>
                  <name />
                  <description>输出低位计数器的比较信号，只在计数模式有效。</description>
                  <value>1</value>
                </enumeratedValue>
                <enumeratedValue>
                  <name />
                  <description>直接输出Group1的输入信号，计数模式、捕捉模式有效。</description>
                  <value>2</value>
                </enumeratedValue>
                <enumeratedValue>
                  <name />
                  <description>直接输出Group2的输入信号，计数模式、捕捉模式有效。</description>
                  <value>3</value>
                </enumeratedValue>
                <enumeratedValue>
                  <name />
                  <description>PWM输出</description>
                  <value>0</value>
                </enumeratedValue>
                <enumeratedValue>
                  <name />
                  <description>输出信号不能配置为APBCLK的同频信号，实际得到的结果为正向输出高电平，反向输出低电平</description>
                  <value>0</value>
                </enumeratedValue>
              </enumeratedValues>
            </field>
          </fields>
        </register>
        <register>
          <name>IER</name>
          <description>Basic Timer 1 Interrupt Enable Register</description>
          <addressOffset>0x3c</addressOffset>
          <size>32</size>
          <access>read-write</access>
          <resetValue>0x00000000</resetValue>
          <fields>
            <field>
              <name>CMPHIE</name>
              <description>CMPHIE  field description</description>
              <bitRange>[4:4]</bitRange>
              <access>read-write</access>
              <enumeratedValues>
                <enumeratedValue>
                  <name />
                  <description>中断使能</description>
                  <value>1</value>
                </enumeratedValue>
                <enumeratedValue>
                  <name />
                  <description>中断禁止</description>
                  <value>0</value>
                </enumeratedValue>
              </enumeratedValues>
            </field>
            <field>
              <name>CMPLIE</name>
              <description>CMPLIE  field description</description>
              <bitRange>[3:3]</bitRange>
              <access>read-write</access>
              <enumeratedValues>
                <enumeratedValue>
                  <name />
                  <description>中断使能</description>
                  <value>1</value>
                </enumeratedValue>
                <enumeratedValue>
                  <name />
                  <description>中断禁止</description>
                  <value>0</value>
                </enumeratedValue>
              </enumeratedValues>
            </field>
            <field>
              <name>OVHIE</name>
              <description>OVHIE  field description</description>
              <bitRange>[2:2]</bitRange>
              <access>read-write</access>
              <enumeratedValues>
                <enumeratedValue>
                  <name />
                  <description>中断使能</description>
                  <value>1</value>
                </enumeratedValue>
                <enumeratedValue>
                  <name />
                  <description>中断禁止</description>
                  <value>0</value>
                </enumeratedValue>
              </enumeratedValues>
            </field>
            <field>
              <name>OVLIE</name>
              <description>OVLIE  field description</description>
              <bitRange>[1:1]</bitRange>
              <access>read-write</access>
              <enumeratedValues>
                <enumeratedValue>
                  <name />
                  <description>中断使能</description>
                  <value>1</value>
                </enumeratedValue>
                <enumeratedValue>
                  <name />
                  <description>中断禁止</description>
                  <value>0</value>
                </enumeratedValue>
              </enumeratedValues>
            </field>
            <field>
              <name>CAPIE</name>
              <description>CAPIE  field description</description>
              <bitRange>[0:0]</bitRange>
              <access>read-write</access>
              <enumeratedValues>
                <enumeratedValue>
                  <name />
                  <description>中断使能</description>
                  <value>1</value>
                </enumeratedValue>
                <enumeratedValue>
                  <name />
                  <description>中断禁止</description>
                  <value>0</value>
                </enumeratedValue>
              </enumeratedValues>
            </field>
          </fields>
        </register>
        <register>
          <name>ISR</name>
          <description>Basic Timer 1 Interrupt Status Register</description>
          <addressOffset>0x40</addressOffset>
          <size>32</size>
          <access>read-write</access>
          <resetValue>0x00000000</resetValue>
          <fields>
            <field>
              <name>EDGESTA</name>
              <description>EDGESTA  field description</description>
              <bitRange>[5:5]</bitRange>
              <access>read-only</access>
              <enumeratedValues>
                <enumeratedValue>
                  <name />
                  <description>脉冲宽度捕捉模式时表示捕捉到下沿</description>
                  <value>1</value>
                </enumeratedValue>
                <enumeratedValue>
                  <name />
                  <description>脉冲宽度捕捉模式时表示捕捉到上沿</description>
                  <value>0</value>
                </enumeratedValue>
              </enumeratedValues>
            </field>
            <field>
              <name>CMPHIF</name>
              <description>CMPHIF  field description</description>
              <bitRange>[4:4]</bitRange>
              <access>read-write</access>
              <enumeratedValues>
                <enumeratedValue>
                  <name />
                  <description>当前计数器的值大于等于比较寄存器的值，该信号将重新加载新的加载寄存器的值到工作寄存器。</description>
                  <value>1</value>
                </enumeratedValue>
                <enumeratedValue>
                  <name />
                  <description>当前计数器的值小于比较寄存器的值</description>
                  <value>0</value>
                </enumeratedValue>
              </enumeratedValues>
            </field>
            <field>
              <name>CMPLIF</name>
              <description>CMPLIF  field description</description>
              <bitRange>[3:3]</bitRange>
              <access>read-write</access>
              <enumeratedValues>
                <enumeratedValue>
                  <name />
                  <description>当前计数器的值大于等于比较寄存器的值，该信号将重新加载新的加载寄存器的值到工作寄存器。</description>
                  <value>1</value>
                </enumeratedValue>
                <enumeratedValue>
                  <name />
                  <description>当前计数器的值小于比较寄存器的值</description>
                  <value>0</value>
                </enumeratedValue>
              </enumeratedValues>
            </field>
            <field>
              <name>OVHIF</name>
              <description>OVHIF  field description</description>
              <bitRange>[2:2]</bitRange>
              <access>read-write</access>
              <enumeratedValues>
                <enumeratedValue>
                  <name />
                  <description>产生计数溢出</description>
                  <value>1</value>
                </enumeratedValue>
                <enumeratedValue>
                  <name />
                  <description>未产生溢出</description>
                  <value>0</value>
                </enumeratedValue>
              </enumeratedValues>
            </field>
            <field>
              <name>OVLIF</name>
              <description>OVLIF  field description</description>
              <bitRange>[1:1]</bitRange>
              <access>read-write</access>
              <enumeratedValues>
                <enumeratedValue>
                  <name />
                  <description>产生计数溢出</description>
                  <value>1</value>
                </enumeratedValue>
                <enumeratedValue>
                  <name />
                  <description>未产生溢出</description>
                  <value>0</value>
                </enumeratedValue>
              </enumeratedValues>
            </field>
            <field>
              <name>CAPIF</name>
              <description>CAPIF  field description</description>
              <bitRange>[0:0]</bitRange>
              <access>read-write</access>
              <enumeratedValues>
                <enumeratedValue>
                  <name />
                  <description>捕捉到指定的沿</description>
                  <value>1</value>
                </enumeratedValue>
                <enumeratedValue>
                  <name />
                  <description>未捕捉到指定的沿</description>
                  <value>0</value>
                </enumeratedValue>
              </enumeratedValues>
            </field>
          </fields>
        </register>
      </registers>
    </peripheral>
    <peripheral>
      <name>BT2</name>
      <description>BT2 module information</description>
      <groupName>BT</groupName>
      <baseAddress>0x40013044</baseAddress>
      <size>32</size>
      <access>read-write</access>
      <addressBlock>
        <offset>0</offset>
        <size>0x44</size>
        <usage>registers</usage>
      </addressBlock>
      <registers>
        <register>
          <name>CR1</name>
          <description>Basic Timer2 Control Register 1</description>
          <addressOffset>0x0</addressOffset>
          <size>32</size>
          <access>read-write</access>
          <resetValue>0x00000000</resetValue>
          <fields>
            <field>
              <name>CHEN</name>
              <description>CHEN  field description</description>
              <bitRange>[7:7]</bitRange>
              <access>read-write</access>
              <enumeratedValues>
                <enumeratedValue>
                  <name />
                  <description>启动高8bit计数器，在计数器模式下启动时将预置数值和加载值分别加载至计数器和比较寄存器；捕捉模式下启动时计数器由零开始自由计数，计数到0xFFFF后产生溢出信号然后由零开始重新计数，捕捉功能只工作在16位模式；在16位的定时/计数和捕捉模式下CHEN作为16位计数器的启动控制，CLEN自动失效</description>
                  <value>1</value>
                </enumeratedValue>
                <enumeratedValue>
                  <name />
                  <description>停止高8bit计数器</description>
                  <value>0</value>
                </enumeratedValue>
              </enumeratedValues>
            </field>
            <field>
              <name>CLEN</name>
              <description>CLEN  field description</description>
              <bitRange>[6:6]</bitRange>
              <access>read-write</access>
              <enumeratedValues>
                <enumeratedValue>
                  <name />
                  <description>启动低8bit计数器，在计数器模式下启动时将预置数值和加载值分别加载至计数器和比较寄存器；捕捉模式下启动时计数器由零开始自由计数，计数到0xFFFF后产生溢出信号然后由零开始重新计数，捕捉功能只工作在16位模式；在16位的定时/计数和捕捉模式下CHEN作为计数器的启动控制，CLEN自动失效</description>
                  <value>1</value>
                </enumeratedValue>
                <enumeratedValue>
                  <name />
                  <description>停止低8bit计数器计数</description>
                  <value>0</value>
                </enumeratedValue>
              </enumeratedValues>
            </field>
            <field>
              <name>MODE</name>
              <description>MODE  field description</description>
              <bitRange>[5:5]</bitRange>
              <access>read-write</access>
              <enumeratedValues>
                <enumeratedValue>
                  <name />
                  <description>16位捕捉模式</description>
                  <value>1</value>
                </enumeratedValue>
                <enumeratedValue>
                  <name />
                  <description>8位定时/计数模式，若高位计数器计数源选择为低位计数器的溢出信号，则可实现16位定时/计数模式</description>
                  <value>0</value>
                </enumeratedValue>
              </enumeratedValues>
            </field>
            <field>
              <name>EDGESEL</name>
              <description>EDGESEL  field description</description>
              <bitRange>[4:4]</bitRange>
              <access>read-write</access>
              <enumeratedValues>
                <enumeratedValue>
                  <name />
                  <description>计数模式采样计数源下降沿，周期捕捉模式时下沿捕捉</description>
                  <value>1</value>
                </enumeratedValue>
                <enumeratedValue>
                  <name />
                  <description>计数模式采样计数源上升沿，周期捕捉模式时上沿捕捉</description>
                  <value>0</value>
                </enumeratedValue>
                <enumeratedValue>
                  <name />
                  <description>不支持系统时钟的下降沿计数，捕捉源和计数源为系统时钟时选择下降沿将不会有效计数。</description>
                  <value>0</value>
                </enumeratedValue>
              </enumeratedValues>
            </field>
            <field>
              <name>CAPMOD</name>
              <description>CAPMOD  field description</description>
              <bitRange>[3:3]</bitRange>
              <access>read-write</access>
              <enumeratedValues>
                <enumeratedValue>
                  <name />
                  <description>脉冲宽度捕捉</description>
                  <value>1</value>
                </enumeratedValue>
                <enumeratedValue>
                  <name />
                  <description>脉冲周期捕捉</description>
                  <value>0</value>
                </enumeratedValue>
              </enumeratedValues>
            </field>
            <field>
              <name>CAPCLR</name>
              <description>CAPCLR  field description</description>
              <bitRange>[2:2]</bitRange>
              <access>read-write</access>
              <enumeratedValues>
                <enumeratedValue>
                  <name />
                  <description>不论在脉冲宽度还是周期捕捉情况下，捕捉到第一个沿后将计数器清零产生中断，捕捉到第二个沿后锁存（锁存到高低位预置数寄存器）计数值并同时清零计数器</description>
                  <value>1</value>
                </enumeratedValue>
                <enumeratedValue>
                  <name />
                  <description>捕捉不清零，计数器一直自由计数</description>
                  <value>0</value>
                </enumeratedValue>
              </enumeratedValues>
            </field>
            <field>
              <name>CAPONCE</name>
              <description>CAPONCE  field description</description>
              <bitRange>[1:1]</bitRange>
              <access>read-write</access>
              <enumeratedValues>
                <enumeratedValue>
                  <name />
                  <description>单次捕捉有效，在捕捉到一次脉冲宽度或脉冲周期后计数器停止，若需要再次捕捉需重新启动</description>
                  <value>1</value>
                </enumeratedValue>
                <enumeratedValue>
                  <name />
                  <description>连续捕捉</description>
                  <value>0</value>
                </enumeratedValue>
              </enumeratedValues>
            </field>
            <field>
              <name>PWM</name>
              <description>PWM  field description</description>
              <bitRange>[0:0]</bitRange>
              <access>read-write</access>
              <enumeratedValues>
                <enumeratedValue>
                  <name />
                  <description>PWM输出使能</description>
                  <value>1</value>
                </enumeratedValue>
                <enumeratedValue>
                  <name />
                  <description>PWM 输出不使能</description>
                  <value>0</value>
                </enumeratedValue>
              </enumeratedValues>
            </field>
          </fields>
        </register>
        <register>
          <name>CR2</name>
          <description>Basic Timer2 Control Register 2</description>
          <addressOffset>0x4</addressOffset>
          <size>32</size>
          <access>read-write</access>
          <resetValue>0x00000000</resetValue>
          <fields>
            <field>
              <name>SIG2SEL</name>
              <description>SIG2SEL  field description</description>
              <bitRange>[7:7]</bitRange>
              <access>read-write</access>
              <enumeratedValues>
                <enumeratedValue>
                  <name />
                  <description>内部计数源信号选择Group2</description>
                  <value>1</value>
                </enumeratedValue>
                <enumeratedValue>
                  <name />
                  <description>内部计数源信号选择Group1</description>
                  <value>0</value>
                </enumeratedValue>
              </enumeratedValues>
            </field>
            <field>
              <name>SIG1SEL</name>
              <description>SIG1SEL  field description</description>
              <bitRange>[6:6]</bitRange>
              <access>read-write</access>
              <enumeratedValues>
                <enumeratedValue>
                  <name />
                  <description>内部捕捉源信号选择Group1</description>
                  <value>1</value>
                </enumeratedValue>
                <enumeratedValue>
                  <name />
                  <description>内部捕捉源信号选择Group2</description>
                  <value>0</value>
                </enumeratedValue>
              </enumeratedValues>
            </field>
            <field>
              <name>CNTHSEL</name>
              <description>CNTHSEL  field description</description>
              <bitRange>[5:4]</bitRange>
              <access>read-write</access>
              <enumeratedValues>
                <enumeratedValue>
                  <name />
                  <description>选择ET1的低位计数器的溢出信号，与低位计数器组成16位计数器</description>
                  <value>0</value>
                </enumeratedValue>
                <enumeratedValue>
                  <name />
                  <description>选择ET1的低位计数器的溢出信号，与低位计数器组成16位计数器</description>
                  <value>3</value>
                </enumeratedValue>
                <enumeratedValue>
                  <name />
                  <description>选择内部捕捉源信号</description>
                  <value>1</value>
                </enumeratedValue>
                <enumeratedValue>
                  <name />
                  <description>选择内部计数源信号或外部DIR输入组合信号</description>
                  <value>2</value>
                </enumeratedValue>
              </enumeratedValues>
            </field>
            <field>
              <name>DIREN</name>
              <description>DIREN  field description</description>
              <bitRange>[3:3]</bitRange>
              <access>read-write</access>
              <enumeratedValues>
                <enumeratedValue>
                  <name />
                  <description>外部输入的DIR信号有效，此时高低位计数器是否计数可由外部输入的DIR信号控制。</description>
                  <value>1</value>
                </enumeratedValue>
                <enumeratedValue>
                  <name />
                  <description>外部输入的DIR信号无效，此时高低位计数器是否计数将由内部控制信号控制。</description>
                  <value>0</value>
                </enumeratedValue>
              </enumeratedValues>
            </field>
            <field>
              <name>STDIR</name>
              <description>STDIR  field description</description>
              <bitRange>[2:2]</bitRange>
              <access>read-write</access>
              <enumeratedValues>
                <enumeratedValue>
                  <name />
                  <description>内部DIR信号为高电平，则高8位计数器计数</description>
                  <value>1</value>
                </enumeratedValue>
              </enumeratedValues>
            </field>
            <field>
              <name>SRCSEL</name>
              <description>SRCSEL  field description</description>
              <bitRange>[1:1]</bitRange>
              <access>read-write</access>
              <enumeratedValues>
                <enumeratedValue>
                  <name />
                  <description>低位计数器计数使能端选则由寄存器STDIR或外部EX_SIG2输入控制。</description>
                  <value>0</value>
                </enumeratedValue>
              </enumeratedValues>
            </field>
            <field>
              <name>DIRPO</name>
              <description>DIRPO  field description</description>
              <bitRange>[0:0]</bitRange>
              <access>read-write</access>
              <enumeratedValues>
                <enumeratedValue>
                  <name />
                  <description>对外部输入DIR信号EX_SIG2反向</description>
                  <value>1</value>
                </enumeratedValue>
                <enumeratedValue>
                  <name />
                  <description>对外部输入DIR信号EX_SIG2不反向</description>
                  <value>0</value>
                </enumeratedValue>
              </enumeratedValues>
            </field>
          </fields>
        </register>
        <register>
          <name>CFGR1</name>
          <description>Basic Timer2 Config Register 1</description>
          <addressOffset>0x8</addressOffset>
          <size>32</size>
          <access>read-write</access>
          <resetValue>0x00000000</resetValue>
          <fields>
            <field>
              <name>RTCSEL2</name>
              <description>RTCSEL2  field description</description>
              <bitRange>[7:6]</bitRange>
              <access>read-write</access>
              <enumeratedValues>
                <enumeratedValue>
                  <name />
                  <description>32768Hz，XTLF时钟输出</description>
                  <value>0</value>
                </enumeratedValue>
                <enumeratedValue>
                  <name />
                  <description>RTCSec，由RTC模块输出的秒信号</description>
                  <value>1</value>
                </enumeratedValue>
                <enumeratedValue>
                  <name />
                  <description>RTCMin，由RTC模块输出的分钟信号</description>
                  <value>2</value>
                </enumeratedValue>
                <enumeratedValue>
                  <name />
                  <description>RFU</description>
                  <value>3</value>
                </enumeratedValue>
              </enumeratedValues>
            </field>
            <field>
              <name>RTCSEL1</name>
              <description>RTCSEL1  field description</description>
              <bitRange>[5:4]</bitRange>
              <access>read-write</access>
              <enumeratedValues>
                <enumeratedValue>
                  <name />
                  <description>32768Hz，XTLF时钟输出</description>
                  <value>0</value>
                </enumeratedValue>
                <enumeratedValue>
                  <name />
                  <description>RTCSec，由RTC模块输出的秒信号</description>
                  <value>1</value>
                </enumeratedValue>
                <enumeratedValue>
                  <name />
                  <description>RTCMin，由RTC模块输出的分钟信号</description>
                  <value>2</value>
                </enumeratedValue>
                <enumeratedValue>
                  <name />
                  <description>RFU</description>
                  <value>3</value>
                </enumeratedValue>
              </enumeratedValues>
            </field>
            <field>
              <name>GRP2SEL</name>
              <description>GRP2SEL  field description</description>
              <bitRange>[3:2]</bitRange>
              <access>read-write</access>
              <enumeratedValues>
                <enumeratedValue>
                  <name />
                  <description>APBCLK</description>
                  <value>0</value>
                </enumeratedValue>
                <enumeratedValue>
                  <name />
                  <description>RTCOUT2</description>
                  <value>1</value>
                </enumeratedValue>
                <enumeratedValue>
                  <name />
                  <description>IN_SIG2，内部输入信号2</description>
                  <value>2</value>
                </enumeratedValue>
                <enumeratedValue>
                  <name />
                  <description>EX_SIG2，外部输入信号2</description>
                  <value>3</value>
                </enumeratedValue>
                <enumeratedValue>
                  <name />
                  <description>不支持APBCLK的下降沿捕捉和计数，捕捉源和计数源为APBCLK时选择下降沿将不会有效捕捉和计数。</description>
                  <value>0</value>
                </enumeratedValue>
              </enumeratedValues>
            </field>
            <field>
              <name>GRP1SEL</name>
              <description>GRP1SEL  field description</description>
              <bitRange>[1:0]</bitRange>
              <access>read-write</access>
              <enumeratedValues>
                <enumeratedValue>
                  <name />
                  <description>APBCLK</description>
                  <value>0</value>
                </enumeratedValue>
                <enumeratedValue>
                  <name />
                  <description>RTCOUT1</description>
                  <value>1</value>
                </enumeratedValue>
                <enumeratedValue>
                  <name />
                  <description>IN_SIG1，内部输入信号1</description>
                  <value>2</value>
                </enumeratedValue>
                <enumeratedValue>
                  <name />
                  <description>EX_SIG1，外部输入信号1</description>
                  <value>3</value>
                </enumeratedValue>
                <enumeratedValue>
                  <name />
                  <description>不支持APBCLK的下降沿捕捉和计数，捕捉源和计数源为APBCLK时选择下降沿将不会有效捕捉和计数。</description>
                  <value>0</value>
                </enumeratedValue>
              </enumeratedValues>
            </field>
          </fields>
        </register>
        <register>
          <name>CFGR2</name>
          <description>Basic Timer2 Config Register 2</description>
          <addressOffset>0xc</addressOffset>
          <size>32</size>
          <access>read-write</access>
          <resetValue>0x00000000</resetValue>
          <fields>
            <field>
              <name>EXSEL2</name>
              <description>EXSEL2  field description</description>
              <bitRange>[7:6]</bitRange>
              <access>read-write</access>
              <enumeratedValues>
                <enumeratedValue>
                  <name />
                  <description>BT1_IN0/BT2_IN0</description>
                  <value>0</value>
                </enumeratedValue>
                <enumeratedValue>
                  <name />
                  <description>BT1_IN1/BT2_IN1</description>
                  <value>1</value>
                </enumeratedValue>
                <enumeratedValue>
                  <name />
                  <description>BT1_IN2/BT2_IN2</description>
                  <value>2</value>
                </enumeratedValue>
                <enumeratedValue>
                  <name />
                  <description>BT1_IN3/BT2_IN3</description>
                  <value>3</value>
                </enumeratedValue>
              </enumeratedValues>
            </field>
            <field>
              <name>EXSEL1</name>
              <description>EXSEL1  field description</description>
              <bitRange>[5:4]</bitRange>
              <access>read-write</access>
              <enumeratedValues>
                <enumeratedValue>
                  <name />
                  <description>BT1_IN0/BT2_IN0</description>
                  <value>0</value>
                </enumeratedValue>
                <enumeratedValue>
                  <name />
                  <description>BT1_IN1/BT2_IN1</description>
                  <value>1</value>
                </enumeratedValue>
                <enumeratedValue>
                  <name />
                  <description>BT1_IN2/BT2_IN2</description>
                  <value>2</value>
                </enumeratedValue>
                <enumeratedValue>
                  <name />
                  <description>BT1_IN3/BT2_IN3</description>
                  <value>3</value>
                </enumeratedValue>
              </enumeratedValues>
            </field>
            <field>
              <name>INSEL2</name>
              <description>INSEL2  field description</description>
              <bitRange>[3:2]</bitRange>
              <access>read-write</access>
              <enumeratedValues>
                <enumeratedValue>
                  <name />
                  <description>UART_RX3/UART_RX3</description>
                  <value>0</value>
                </enumeratedValue>
                <enumeratedValue>
                  <name />
                  <description>UART_RX4/UART_RX4</description>
                  <value>1</value>
                </enumeratedValue>
                <enumeratedValue>
                  <name />
                  <description>UART_RX5/UART_RX5</description>
                  <value>2</value>
                </enumeratedValue>
                <enumeratedValue>
                  <name />
                  <description>RCLP/BT1_OUT</description>
                  <value>3</value>
                </enumeratedValue>
              </enumeratedValues>
            </field>
            <field>
              <name>INSEL1</name>
              <description>INSEL1  field description</description>
              <bitRange>[1:0]</bitRange>
              <access>read-write</access>
              <enumeratedValues>
                <enumeratedValue>
                  <name />
                  <description>UART_RX0/UART_RX0</description>
                  <value>0</value>
                </enumeratedValue>
                <enumeratedValue>
                  <name />
                  <description>UART_RX1/UART_RX1</description>
                  <value>1</value>
                </enumeratedValue>
                <enumeratedValue>
                  <name />
                  <description>UART_RX2/UART_RX2</description>
                  <value>2</value>
                </enumeratedValue>
                <enumeratedValue>
                  <name />
                  <description>RCLP/RCLP</description>
                  <value>3</value>
                </enumeratedValue>
              </enumeratedValues>
            </field>
          </fields>
        </register>
        <register>
          <name>PRES</name>
          <description>Basic Timer2 Prescaler Register</description>
          <addressOffset>0x10</addressOffset>
          <size>32</size>
          <access>read-write</access>
          <resetValue>0x00000000</resetValue>
          <fields>
            <field>
              <name>PRESCALE</name>
              <description>PRESCALE  field description</description>
              <bitRange>[7:0]</bitRange>
              <access>read-write</access>
              <enumeratedValues />
            </field>
          </fields>
        </register>
        <register>
          <name>LOADCR</name>
          <description>Basic Timer2 Load Control Register</description>
          <addressOffset>0x14</addressOffset>
          <size>32</size>
          <access>read-write</access>
          <resetValue>0x00000000</resetValue>
          <fields>
            <field>
              <name>LHEN</name>
              <description>LHEN  field description</description>
              <bitRange>[4:4]</bitRange>
              <access>read-write</access>
              <enumeratedValues />
            </field>
            <field>
              <name>LLEN</name>
              <description>LLEN  field description</description>
              <bitRange>[0:0]</bitRange>
              <access>read-write</access>
              <enumeratedValues />
            </field>
          </fields>
        </register>
        <register>
          <name>CNTL</name>
          <description>Basic Timer2 Counter Low</description>
          <addressOffset>0x18</addressOffset>
          <size>32</size>
          <access>read-write</access>
          <resetValue>0x00000000</resetValue>
          <fields>
            <field>
              <name>CNTL</name>
              <description>CNTL  field description</description>
              <bitRange>[7:0]</bitRange>
              <access>read-only</access>
              <enumeratedValues />
            </field>
          </fields>
        </register>
        <register>
          <name>CNTH</name>
          <description>Basic Timer2 Counter High</description>
          <addressOffset>0x1c</addressOffset>
          <size>32</size>
          <access>read-write</access>
          <resetValue>0x00000000</resetValue>
          <fields>
            <field>
              <name>CNTH</name>
              <description>CNTH  field description</description>
              <bitRange>[7:0]</bitRange>
              <access>read-only</access>
              <enumeratedValues />
            </field>
          </fields>
        </register>
        <register>
          <name>PRESET</name>
          <description>Basic Timer2 Preset Register</description>
          <addressOffset>0x20</addressOffset>
          <size>32</size>
          <access>read-write</access>
          <resetValue>0x00000000</resetValue>
          <fields>
            <field>
              <name>PRESETH</name>
              <description>PRESETH  field description</description>
              <bitRange>[15:8]</bitRange>
              <access>read-write</access>
              <enumeratedValues />
            </field>
            <field>
              <name>PRESETL</name>
              <description>PRESETL  field description</description>
              <bitRange>[7:0]</bitRange>
              <access>read-write</access>
              <enumeratedValues />
            </field>
          </fields>
        </register>
        <register>
          <name>LOADL</name>
          <description>Basic Timer2 Load Register Low</description>
          <addressOffset>0x24</addressOffset>
          <size>32</size>
          <access>read-write</access>
          <resetValue>0x00000000</resetValue>
          <fields>
            <field>
              <name>LOADL</name>
              <description>LOADL  field description</description>
              <bitRange>[7:0]</bitRange>
              <access>read-write</access>
              <enumeratedValues />
            </field>
          </fields>
        </register>
        <register>
          <name>LOADH</name>
          <description>Basic Timer2 Load Register High</description>
          <addressOffset>0x28</addressOffset>
          <size>32</size>
          <access>read-write</access>
          <resetValue>0x00000000</resetValue>
          <fields>
            <field>
              <name>LOADH</name>
              <description>LOADH  field description</description>
              <bitRange>[7:0]</bitRange>
              <access>read-write</access>
              <enumeratedValues />
            </field>
          </fields>
        </register>
        <register>
          <name>CMPL</name>
          <description>Basic Timer2 Compare Register Low</description>
          <addressOffset>0x2c</addressOffset>
          <size>32</size>
          <access>read-write</access>
          <resetValue>0x00000000</resetValue>
          <fields>
            <field>
              <name>CMPL</name>
              <description>CMPL  field description</description>
              <bitRange>[7:0]</bitRange>
              <access>read-write</access>
              <enumeratedValues />
            </field>
          </fields>
        </register>
        <register>
          <name>CMPH</name>
          <description>Basic Timer2 Compare Register High</description>
          <addressOffset>0x30</addressOffset>
          <size>32</size>
          <access>read-write</access>
          <resetValue>0x00000000</resetValue>
          <fields>
            <field>
              <name>CMPH</name>
              <description>CMPH  field description</description>
              <bitRange>[7:0]</bitRange>
              <access>read-write</access>
              <enumeratedValues />
            </field>
          </fields>
        </register>
        <register>
          <name>OUTCNT</name>
          <description>Basic Timer2 Output Counter</description>
          <addressOffset>0x34</addressOffset>
          <size>32</size>
          <access>read-write</access>
          <resetValue>0x00000000</resetValue>
          <fields>
            <field>
              <name>OUTCNT</name>
              <description>OUTCNT  field description</description>
              <bitRange>[11:0]</bitRange>
              <access>read-write</access>
              <enumeratedValues />
            </field>
          </fields>
        </register>
        <register>
          <name>OCR</name>
          <description>Basic Timer2 Output Control Register</description>
          <addressOffset>0x38</addressOffset>
          <size>32</size>
          <access>read-write</access>
          <resetValue>0x00000000</resetValue>
          <fields>
            <field>
              <name>OUTCLR</name>
              <description>OUTCLR  field description</description>
              <bitRange>[5:5]</bitRange>
              <access>read-write</access>
              <enumeratedValues>
                <enumeratedValue>
                  <name />
                  <description>输出清零，若设置了输出反向则清零后输出为高电平，反之为低电平（只适用于OUTMOD输出模式=1输出之前反向电平的情况，OUTMOD输出模式=0输出脉冲模式无效）</description>
                  <value>1</value>
                </enumeratedValue>
                <enumeratedValue>
                  <name />
                  <description>写入无效</description>
                  <value>0</value>
                </enumeratedValue>
              </enumeratedValues>
            </field>
            <field>
              <name>OUTINV</name>
              <description>OUTINV  field description</description>
              <bitRange>[4:4]</bitRange>
              <access>read-write</access>
              <enumeratedValues>
                <enumeratedValue>
                  <name />
                  <description>输出电平取反（CHEN/CLEN有效后，ETOUT信号输出本信号在CHEN/CLEN有效之前的状态）</description>
                  <value>1</value>
                </enumeratedValue>
                <enumeratedValue>
                  <name />
                  <description>输出电平不取反（CHEN/CLEN有效后，ETOUT信号输出本信号在CHEN/CLEN有效之前状态的反态）</description>
                  <value>0</value>
                </enumeratedValue>
              </enumeratedValues>
            </field>
            <field>
              <name>OUTMOD</name>
              <description>OUTMOD  field description</description>
              <bitRange>[3:3]</bitRange>
              <access>read-write</access>
              <enumeratedValues>
                <enumeratedValue>
                  <name />
                  <description>输出之前的反向电平</description>
                  <value>1</value>
                </enumeratedValue>
                <enumeratedValue>
                  <name />
                  <description>输出脉冲，脉冲宽度可调</description>
                  <value>0</value>
                </enumeratedValue>
              </enumeratedValues>
            </field>
            <field>
              <name>OUTSEL</name>
              <description>OUTSEL  field description</description>
              <bitRange>[2:0]</bitRange>
              <access>read-write</access>
              <enumeratedValues>
                <enumeratedValue>
                  <name />
                  <description>输出高位计数器的比较信号，只在计数模式有效。</description>
                  <value>0</value>
                </enumeratedValue>
                <enumeratedValue>
                  <name />
                  <description>输出低位计数器的比较信号，只在计数模式有效。</description>
                  <value>1</value>
                </enumeratedValue>
                <enumeratedValue>
                  <name />
                  <description>直接输出Group1的输入信号，计数模式、捕捉模式有效。</description>
                  <value>2</value>
                </enumeratedValue>
                <enumeratedValue>
                  <name />
                  <description>直接输出Group2的输入信号，计数模式、捕捉模式有效。</description>
                  <value>3</value>
                </enumeratedValue>
                <enumeratedValue>
                  <name />
                  <description>PWM输出</description>
                  <value>0</value>
                </enumeratedValue>
                <enumeratedValue>
                  <name />
                  <description>输出信号不能配置为APBCLK的同频信号，实际得到的结果为正向输出高电平，反向输出低电平</description>
                  <value>0</value>
                </enumeratedValue>
              </enumeratedValues>
            </field>
          </fields>
        </register>
        <register>
          <name>IER</name>
          <description>Basic Timer2 Interrupt Enable Register</description>
          <addressOffset>0x3c</addressOffset>
          <size>32</size>
          <access>read-write</access>
          <resetValue>0x00000000</resetValue>
          <fields>
            <field>
              <name>CMPHIE</name>
              <description>CMPHIE  field description</description>
              <bitRange>[4:4]</bitRange>
              <access>read-write</access>
              <enumeratedValues>
                <enumeratedValue>
                  <name />
                  <description>中断使能</description>
                  <value>1</value>
                </enumeratedValue>
                <enumeratedValue>
                  <name />
                  <description>中断禁止</description>
                  <value>0</value>
                </enumeratedValue>
              </enumeratedValues>
            </field>
            <field>
              <name>CMPLIE</name>
              <description>CMPLIE  field description</description>
              <bitRange>[3:3]</bitRange>
              <access>read-write</access>
              <enumeratedValues>
                <enumeratedValue>
                  <name />
                  <description>中断使能</description>
                  <value>1</value>
                </enumeratedValue>
                <enumeratedValue>
                  <name />
                  <description>中断禁止</description>
                  <value>0</value>
                </enumeratedValue>
              </enumeratedValues>
            </field>
            <field>
              <name>OVHIE</name>
              <description>OVHIE  field description</description>
              <bitRange>[2:2]</bitRange>
              <access>read-write</access>
              <enumeratedValues>
                <enumeratedValue>
                  <name />
                  <description>中断使能</description>
                  <value>1</value>
                </enumeratedValue>
                <enumeratedValue>
                  <name />
                  <description>中断禁止</description>
                  <value>0</value>
                </enumeratedValue>
              </enumeratedValues>
            </field>
            <field>
              <name>OVLIE</name>
              <description>OVLIE  field description</description>
              <bitRange>[1:1]</bitRange>
              <access>read-write</access>
              <enumeratedValues>
                <enumeratedValue>
                  <name />
                  <description>中断使能</description>
                  <value>1</value>
                </enumeratedValue>
                <enumeratedValue>
                  <name />
                  <description>中断禁止</description>
                  <value>0</value>
                </enumeratedValue>
              </enumeratedValues>
            </field>
            <field>
              <name>CAPIE</name>
              <description>CAPIE  field description</description>
              <bitRange>[0:0]</bitRange>
              <access>read-write</access>
              <enumeratedValues>
                <enumeratedValue>
                  <name />
                  <description>中断使能</description>
                  <value>1</value>
                </enumeratedValue>
                <enumeratedValue>
                  <name />
                  <description>中断禁止</description>
                  <value>0</value>
                </enumeratedValue>
              </enumeratedValues>
            </field>
          </fields>
        </register>
        <register>
          <name>ISR</name>
          <description>Basic Timer2 Interrupt Status Register</description>
          <addressOffset>0x40</addressOffset>
          <size>32</size>
          <access>read-write</access>
          <resetValue>0x00000000</resetValue>
          <fields>
            <field>
              <name>EDGESTA</name>
              <description>EDGESTA  field description</description>
              <bitRange>[5:5]</bitRange>
              <access>read-only</access>
              <enumeratedValues>
                <enumeratedValue>
                  <name />
                  <description>脉冲宽度捕捉模式时表示捕捉到下沿</description>
                  <value>1</value>
                </enumeratedValue>
                <enumeratedValue>
                  <name />
                  <description>脉冲宽度捕捉模式时表示捕捉到上沿</description>
                  <value>0</value>
                </enumeratedValue>
              </enumeratedValues>
            </field>
            <field>
              <name>CMPHIF</name>
              <description>CMPHIF  field description</description>
              <bitRange>[4:4]</bitRange>
              <access>read-write</access>
              <enumeratedValues>
                <enumeratedValue>
                  <name />
                  <description>当前计数器的值大于等于比较寄存器的值，该信号将重新加载新的加载寄存器的值到工作寄存器。</description>
                  <value>1</value>
                </enumeratedValue>
                <enumeratedValue>
                  <name />
                  <description>当前计数器的值小于比较寄存器的值</description>
                  <value>0</value>
                </enumeratedValue>
              </enumeratedValues>
            </field>
            <field>
              <name>CMPLIF</name>
              <description>CMPLIF  field description</description>
              <bitRange>[3:3]</bitRange>
              <access>read-write</access>
              <enumeratedValues>
                <enumeratedValue>
                  <name />
                  <description>当前计数器的值大于等于比较寄存器的值，该信号将重新加载新的加载寄存器的值到工作寄存器。</description>
                  <value>1</value>
                </enumeratedValue>
                <enumeratedValue>
                  <name />
                  <description>当前计数器的值小于比较寄存器的值</description>
                  <value>0</value>
                </enumeratedValue>
              </enumeratedValues>
            </field>
            <field>
              <name>OVHIF</name>
              <description>OVHIF  field description</description>
              <bitRange>[2:2]</bitRange>
              <access>read-write</access>
              <enumeratedValues>
                <enumeratedValue>
                  <name />
                  <description>产生计数溢出</description>
                  <value>1</value>
                </enumeratedValue>
                <enumeratedValue>
                  <name />
                  <description>未产生溢出</description>
                  <value>0</value>
                </enumeratedValue>
              </enumeratedValues>
            </field>
            <field>
              <name>OVLIF</name>
              <description>OVLIF  field description</description>
              <bitRange>[1:1]</bitRange>
              <access>read-write</access>
              <enumeratedValues>
                <enumeratedValue>
                  <name />
                  <description>产生计数溢出</description>
                  <value>1</value>
                </enumeratedValue>
                <enumeratedValue>
                  <name />
                  <description>未产生溢出</description>
                  <value>0</value>
                </enumeratedValue>
              </enumeratedValues>
            </field>
            <field>
              <name>CAPIF</name>
              <description>CAPIF  field description</description>
              <bitRange>[0:0]</bitRange>
              <access>read-write</access>
              <enumeratedValues>
                <enumeratedValue>
                  <name />
                  <description>捕捉到指定的沿</description>
                  <value>1</value>
                </enumeratedValue>
                <enumeratedValue>
                  <name />
                  <description>未捕捉到指定的沿</description>
                  <value>0</value>
                </enumeratedValue>
              </enumeratedValues>
            </field>
          </fields>
        </register>
      </registers>
    </peripheral>
    <peripheral>
      <name>ET1</name>
      <description>ET1 module information</description>
      <groupName>ET</groupName>
      <baseAddress>0x40013090</baseAddress>
      <size>32</size>
      <access>read-write</access>
      <addressBlock>
        <offset>0</offset>
        <size>0x20</size>
        <usage>registers</usage>
      </addressBlock>
      <registers>
        <register>
          <name>CR</name>
          <description>ET1 Control Register</description>
          <addressOffset>0x0</addressOffset>
          <size>32</size>
          <access>read-write</access>
          <resetValue>0x00000000</resetValue>
          <fields>
            <field>
              <name>OPOL</name>
              <description>OPOL  field description</description>
              <bitRange>[10:10]</bitRange>
              <access>read-write</access>
              <enumeratedValues>
                <enumeratedValue>
                  <name />
                  <description>输出不取反</description>
                  <value>0</value>
                </enumeratedValue>
                <enumeratedValue>
                  <name />
                  <description>输出取反</description>
                  <value>1</value>
                </enumeratedValue>
              </enumeratedValues>
            </field>
            <field>
              <name>EXFLT</name>
              <description>EXFLT  field description</description>
              <bitRange>[9:9]</bitRange>
              <access>read-write</access>
              <enumeratedValues />
            </field>
            <field>
              <name>PWM</name>
              <description>PWM  field description</description>
              <bitRange>[8:8]</bitRange>
              <access>read-write</access>
              <enumeratedValues />
            </field>
            <field>
              <name>CEN</name>
              <description>CEN  field description</description>
              <bitRange>[7:7]</bitRange>
              <access>read-write</access>
              <enumeratedValues />
            </field>
            <field>
              <name>MOD</name>
              <description>MOD  field description</description>
              <bitRange>[6:6]</bitRange>
              <access>read-write</access>
              <enumeratedValues />
            </field>
            <field>
              <name>CASEN</name>
              <description>CASEN  field description</description>
              <bitRange>[5:5]</bitRange>
              <access>read-write</access>
              <enumeratedValues />
            </field>
            <field>
              <name>EDGESEL</name>
              <description>EDGESEL  field description</description>
              <bitRange>[4:4]</bitRange>
              <access>read-write</access>
              <enumeratedValues />
            </field>
            <field>
              <name>CAPMOD</name>
              <description>CAPMOD  field description</description>
              <bitRange>[3:3]</bitRange>
              <access>read-write</access>
              <enumeratedValues />
            </field>
            <field>
              <name>CAPCLR</name>
              <description>CAPCLR  field description</description>
              <bitRange>[2:2]</bitRange>
              <access>read-write</access>
              <enumeratedValues>
                <enumeratedValue>
                  <name />
                  <description>使能后计数器保持0，捕捉到第一个有效沿之后timer才开始计数</description>
                  <value>0</value>
                </enumeratedValue>
              </enumeratedValues>
            </field>
            <field>
              <name>CAPONCE</name>
              <description>CAPONCE  field description</description>
              <bitRange>[1:1]</bitRange>
              <access>read-write</access>
              <enumeratedValues />
            </field>
            <field>
              <name>CAPEDGE</name>
              <description>CAPEDGE  field description</description>
              <bitRange>[0:0]</bitRange>
              <access>read-write</access>
              <enumeratedValues />
            </field>
          </fields>
        </register>
        <register>
          <name>INSR</name>
          <description>ET1 Input Select Register</description>
          <addressOffset>0x4</addressOffset>
          <size>32</size>
          <access>read-write</access>
          <resetValue>0x00000000</resetValue>
          <fields>
            <field>
              <name>SIG2SEL</name>
              <description>SIG2SEL  field description</description>
              <bitRange>[7:7]</bitRange>
              <access>read-write</access>
              <enumeratedValues>
                <enumeratedValue>
                  <name />
                  <description>扩展定时器3的内部信号2选择Group1</description>
                  <value>1</value>
                </enumeratedValue>
                <enumeratedValue>
                  <name />
                  <description>扩展定时器3的内部信号2选择Group2</description>
                  <value>0</value>
                </enumeratedValue>
              </enumeratedValues>
            </field>
            <field>
              <name>SIG1SEL</name>
              <description>SIG1SEL  field description</description>
              <bitRange>[6:6]</bitRange>
              <access>read-write</access>
              <enumeratedValues>
                <enumeratedValue>
                  <name />
                  <description>扩展定时器3的内部信号1选择Group2</description>
                  <value>1</value>
                </enumeratedValue>
                <enumeratedValue>
                  <name />
                  <description>扩展定时器3的内部信号1选择Group1</description>
                  <value>0</value>
                </enumeratedValue>
              </enumeratedValues>
            </field>
            <field>
              <name>GRP2SEL</name>
              <description>GRP2SEL  field description</description>
              <bitRange>[4:2]</bitRange>
              <access>read-write</access>
              <enumeratedValues>
                <enumeratedValue>
                  <name />
                  <description>UART0_RX</description>
                  <value>0</value>
                </enumeratedValue>
                <enumeratedValue>
                  <name />
                  <description>UART1_RX</description>
                  <value>1</value>
                </enumeratedValue>
                <enumeratedValue>
                  <name />
                  <description>XTLF</description>
                  <value>2</value>
                </enumeratedValue>
                <enumeratedValue>
                  <name />
                  <description>ET1_IN1</description>
                  <value>3</value>
                </enumeratedValue>
                <enumeratedValue>
                  <name />
                  <description>ET1_IN2</description>
                  <value>4</value>
                </enumeratedValue>
                <enumeratedValue>
                  <name />
                  <description>CMP1O（比较器1输出）</description>
                  <value>5</value>
                </enumeratedValue>
                <enumeratedValue>
                  <name />
                  <description>CMP2O（比较器2输出）</description>
                  <value>6</value>
                </enumeratedValue>
                <enumeratedValue>
                  <name />
                  <description>RCMF</description>
                  <value>7</value>
                </enumeratedValue>
                <enumeratedValue>
                  <name />
                  <description>UART2_RX</description>
                  <value>0</value>
                </enumeratedValue>
                <enumeratedValue>
                  <name />
                  <description>UART3_RX</description>
                  <value>1</value>
                </enumeratedValue>
                <enumeratedValue>
                  <name />
                  <description>XTLF</description>
                  <value>2</value>
                </enumeratedValue>
                <enumeratedValue>
                  <name />
                  <description>ET2_IN1</description>
                  <value>3</value>
                </enumeratedValue>
                <enumeratedValue>
                  <name />
                  <description>ET2_IN2</description>
                  <value>4</value>
                </enumeratedValue>
                <enumeratedValue>
                  <name />
                  <description>CMP1O（比较器1输出）</description>
                  <value>5</value>
                </enumeratedValue>
                <enumeratedValue>
                  <name />
                  <description>CMP2O（比较器2输出）</description>
                  <value>6</value>
                </enumeratedValue>
                <enumeratedValue>
                  <name />
                  <description>RCMF</description>
                  <value>7</value>
                </enumeratedValue>
                <enumeratedValue>
                  <name />
                  <description>ET3_IN1</description>
                  <value>0</value>
                </enumeratedValue>
                <enumeratedValue>
                  <name />
                  <description>XTLF</description>
                  <value>1</value>
                </enumeratedValue>
                <enumeratedValue>
                  <name />
                  <description>UART4_RX</description>
                  <value>2</value>
                </enumeratedValue>
                <enumeratedValue>
                  <name />
                  <description>UART5_RX</description>
                  <value>3</value>
                </enumeratedValue>
                <enumeratedValue>
                  <name />
                  <description>RTCSEC</description>
                  <value>4</value>
                </enumeratedValue>
                <enumeratedValue>
                  <name />
                  <description>RFU</description>
                  <value>5</value>
                </enumeratedValue>
                <enumeratedValue>
                  <name />
                  <description>RFU</description>
                  <value>6</value>
                </enumeratedValue>
                <enumeratedValue>
                  <name />
                  <description>RFU</description>
                  <value>7</value>
                </enumeratedValue>
                <enumeratedValue>
                  <name />
                  <description>ET4_IN1</description>
                  <value>0</value>
                </enumeratedValue>
                <enumeratedValue>
                  <name />
                  <description>XTLF</description>
                  <value>1</value>
                </enumeratedValue>
                <enumeratedValue>
                  <name />
                  <description>UART_RX2</description>
                  <value>2</value>
                </enumeratedValue>
                <enumeratedValue>
                  <name />
                  <description>UART_RX0</description>
                  <value>3</value>
                </enumeratedValue>
                <enumeratedValue>
                  <name />
                  <description>CMP1O（比较器1输出）</description>
                  <value>4</value>
                </enumeratedValue>
                <enumeratedValue>
                  <name />
                  <description>CMP2O（比较器2输出）</description>
                  <value>5</value>
                </enumeratedValue>
                <enumeratedValue>
                  <name />
                  <description>RTCSEC</description>
                  <value>6</value>
                </enumeratedValue>
                <enumeratedValue>
                  <name />
                  <description>RCMF</description>
                  <value>7</value>
                </enumeratedValue>
              </enumeratedValues>
            </field>
            <field>
              <name>GRP1SEL</name>
              <description>GRP1SEL  field description</description>
              <bitRange>[1:0]</bitRange>
              <access>read-write</access>
              <enumeratedValues>
                <enumeratedValue>
                  <name />
                  <description>APBCLK</description>
                  <value>0</value>
                </enumeratedValue>
                <enumeratedValue>
                  <name />
                  <description>XTLF</description>
                  <value>1</value>
                </enumeratedValue>
                <enumeratedValue>
                  <name />
                  <description>RCLP</description>
                  <value>2</value>
                </enumeratedValue>
                <enumeratedValue>
                  <name />
                  <description>ET1_IN0</description>
                  <value>3</value>
                </enumeratedValue>
                <enumeratedValue>
                  <name />
                  <description>APBCLK</description>
                  <value>0</value>
                </enumeratedValue>
                <enumeratedValue>
                  <name />
                  <description>XTLF</description>
                  <value>1</value>
                </enumeratedValue>
                <enumeratedValue>
                  <name />
                  <description>RCLP</description>
                  <value>2</value>
                </enumeratedValue>
                <enumeratedValue>
                  <name />
                  <description>ET2_IN0</description>
                  <value>3</value>
                </enumeratedValue>
                <enumeratedValue>
                  <name />
                  <description>APBCLK</description>
                  <value>0</value>
                </enumeratedValue>
                <enumeratedValue>
                  <name />
                  <description>ET3_IN0</description>
                  <value>1</value>
                </enumeratedValue>
                <enumeratedValue>
                  <name />
                  <description>RTCSEC</description>
                  <value>2</value>
                </enumeratedValue>
                <enumeratedValue>
                  <name />
                  <description>RCLP</description>
                  <value>3</value>
                </enumeratedValue>
                <enumeratedValue>
                  <name />
                  <description>APBCLK</description>
                  <value>0</value>
                </enumeratedValue>
                <enumeratedValue>
                  <name />
                  <description>ET4_IN0</description>
                  <value>1</value>
                </enumeratedValue>
                <enumeratedValue>
                  <name />
                  <description>RTC64HZ</description>
                  <value>2</value>
                </enumeratedValue>
                <enumeratedValue>
                  <name />
                  <description>RCMF</description>
                  <value>3</value>
                </enumeratedValue>
              </enumeratedValues>
            </field>
          </fields>
        </register>
        <register>
          <name>PSCR1</name>
          <description>ET1 Prescaler Register1</description>
          <addressOffset>0x8</addressOffset>
          <size>32</size>
          <access>read-write</access>
          <resetValue>0x00000000</resetValue>
          <fields>
            <field>
              <name>PRESCALE1</name>
              <description>PRESCALE1  field description</description>
              <bitRange>[7:0]</bitRange>
              <access>read-write</access>
              <enumeratedValues />
            </field>
          </fields>
        </register>
        <register>
          <name>PSCR2</name>
          <description>ET1 Prescaler Register2</description>
          <addressOffset>0xc</addressOffset>
          <size>32</size>
          <access>read-write</access>
          <resetValue>0x00000000</resetValue>
          <fields>
            <field>
              <name>PRESCALE2</name>
              <description>PRESCALE2  field description</description>
              <bitRange>[7:0]</bitRange>
              <access>read-write</access>
              <enumeratedValues />
            </field>
          </fields>
        </register>
        <register>
          <name>IVR</name>
          <description>ET1 Initial Value Register</description>
          <addressOffset>0x10</addressOffset>
          <size>32</size>
          <access>read-write</access>
          <resetValue>0x00000000</resetValue>
          <fields>
            <field>
              <name>INITVALUE</name>
              <description>INITVALUE  field description</description>
              <bitRange>[15:0]</bitRange>
              <access>read-write</access>
              <enumeratedValues />
            </field>
          </fields>
        </register>
        <register>
          <name>CMPR</name>
          <description>ET1 Compare Register</description>
          <addressOffset>0x14</addressOffset>
          <size>32</size>
          <access>read-write</access>
          <resetValue>0x00000000</resetValue>
          <fields>
            <field>
              <name>CMP</name>
              <description>CMP  field description</description>
              <bitRange>[15:0]</bitRange>
              <access>read-write</access>
              <enumeratedValues />
            </field>
          </fields>
        </register>
        <register>
          <name>IER</name>
          <description>ET1 Interrupt Enable Register</description>
          <addressOffset>0x18</addressOffset>
          <size>32</size>
          <access>read-write</access>
          <resetValue>0x00000000</resetValue>
          <fields>
            <field>
              <name>CMPIE</name>
              <description>CMPIE  field description</description>
              <bitRange>[2:2]</bitRange>
              <access>read-write</access>
              <enumeratedValues>
                <enumeratedValue>
                  <name />
                  <description>使能</description>
                  <value>1</value>
                </enumeratedValue>
                <enumeratedValue>
                  <name />
                  <description>禁止</description>
                  <value>0</value>
                </enumeratedValue>
              </enumeratedValues>
            </field>
            <field>
              <name>CAPIE</name>
              <description>CAPIE  field description</description>
              <bitRange>[1:1]</bitRange>
              <access>read-write</access>
              <enumeratedValues>
                <enumeratedValue>
                  <name />
                  <description>使能</description>
                  <value>1</value>
                </enumeratedValue>
                <enumeratedValue>
                  <name />
                  <description>禁止</description>
                  <value>0</value>
                </enumeratedValue>
              </enumeratedValues>
            </field>
            <field>
              <name>OVIE</name>
              <description>OVIE  field description</description>
              <bitRange>[0:0]</bitRange>
              <access>read-write</access>
              <enumeratedValues>
                <enumeratedValue>
                  <name />
                  <description>使能</description>
                  <value>1</value>
                </enumeratedValue>
                <enumeratedValue>
                  <name />
                  <description>禁止</description>
                  <value>0</value>
                </enumeratedValue>
              </enumeratedValues>
            </field>
          </fields>
        </register>
        <register>
          <name>ISR</name>
          <description>ET1 Interrupt Status Register</description>
          <addressOffset>0x1c</addressOffset>
          <size>32</size>
          <access>read-write</access>
          <resetValue>0x00000000</resetValue>
          <fields>
            <field>
              <name>CMPIF</name>
              <description>CMPIF  field description</description>
              <bitRange>[3:3]</bitRange>
              <access>read-write</access>
              <enumeratedValues>
                <enumeratedValue>
                  <name />
                  <description>当前计数器的值大于等于比较寄存器的值</description>
                  <value>1</value>
                </enumeratedValue>
                <enumeratedValue>
                  <name />
                  <description>当前计数器的值小于比较寄存器的值</description>
                  <value>0</value>
                </enumeratedValue>
              </enumeratedValues>
            </field>
            <field>
              <name>EDGESTA</name>
              <description>EDGESTA  field description</description>
              <bitRange>[2:2]</bitRange>
              <access>read-write</access>
              <enumeratedValues>
                <enumeratedValue>
                  <name />
                  <description>脉冲宽度捕捉模式时表示捕捉到下沿</description>
                  <value>1</value>
                </enumeratedValue>
                <enumeratedValue>
                  <name />
                  <description>脉冲宽度捕捉模式时表示捕捉到上沿</description>
                  <value>0</value>
                </enumeratedValue>
              </enumeratedValues>
            </field>
            <field>
              <name>CAPIF</name>
              <description>CAPIF  field description</description>
              <bitRange>[1:1]</bitRange>
              <access>read-write</access>
              <enumeratedValues>
                <enumeratedValue>
                  <name />
                  <description>捕捉到指定的沿</description>
                  <value>1</value>
                </enumeratedValue>
                <enumeratedValue>
                  <name />
                  <description>未捕捉到指定的沿</description>
                  <value>0</value>
                </enumeratedValue>
              </enumeratedValues>
            </field>
            <field>
              <name>OVIF</name>
              <description>OVIF  field description</description>
              <bitRange>[0:0]</bitRange>
              <access>read-write</access>
              <enumeratedValues>
                <enumeratedValue>
                  <name />
                  <description>产生计数溢出</description>
                  <value>1</value>
                </enumeratedValue>
                <enumeratedValue>
                  <name />
                  <description>未产生溢出</description>
                  <value>0</value>
                </enumeratedValue>
              </enumeratedValues>
            </field>
          </fields>
        </register>
      </registers>
    </peripheral>
    <peripheral>
      <name>ET2</name>
      <description>ET2 module information</description>
      <groupName>ET</groupName>
      <baseAddress>0x400130b0</baseAddress>
      <size>32</size>
      <access>read-write</access>
      <addressBlock>
        <offset>0</offset>
        <size>0x20</size>
        <usage>registers</usage>
      </addressBlock>
      <registers>
        <register>
          <name>CR</name>
          <description>ET2 Control Register</description>
          <addressOffset>0x0</addressOffset>
          <size>32</size>
          <access>read-write</access>
          <resetValue>0x00000000</resetValue>
          <fields>
            <field>
              <name>OPOL</name>
              <description>OPOL  field description</description>
              <bitRange>[10:10]</bitRange>
              <access>read-write</access>
              <enumeratedValues>
                <enumeratedValue>
                  <name />
                  <description>输出不取反</description>
                  <value>0</value>
                </enumeratedValue>
                <enumeratedValue>
                  <name />
                  <description>输出取反</description>
                  <value>1</value>
                </enumeratedValue>
              </enumeratedValues>
            </field>
            <field>
              <name>EXFLT</name>
              <description>EXFLT  field description</description>
              <bitRange>[9:9]</bitRange>
              <access>read-write</access>
              <enumeratedValues />
            </field>
            <field>
              <name>PWM</name>
              <description>PWM  field description</description>
              <bitRange>[8:8]</bitRange>
              <access>read-write</access>
              <enumeratedValues />
            </field>
            <field>
              <name>CEN</name>
              <description>CEN  field description</description>
              <bitRange>[7:7]</bitRange>
              <access>read-write</access>
              <enumeratedValues />
            </field>
            <field>
              <name>MOD</name>
              <description>MOD  field description</description>
              <bitRange>[6:6]</bitRange>
              <access>read-write</access>
              <enumeratedValues />
            </field>
            <field>
              <name>CASEN</name>
              <description>CASEN  field description</description>
              <bitRange>[5:5]</bitRange>
              <access>read-write</access>
              <enumeratedValues />
            </field>
            <field>
              <name>EDGESEL</name>
              <description>EDGESEL  field description</description>
              <bitRange>[4:4]</bitRange>
              <access>read-write</access>
              <enumeratedValues />
            </field>
            <field>
              <name>CAPMOD</name>
              <description>CAPMOD  field description</description>
              <bitRange>[3:3]</bitRange>
              <access>read-write</access>
              <enumeratedValues />
            </field>
            <field>
              <name>CAPCLR</name>
              <description>CAPCLR  field description</description>
              <bitRange>[2:2]</bitRange>
              <access>read-write</access>
              <enumeratedValues>
                <enumeratedValue>
                  <name />
                  <description>使能后计数器保持0，捕捉到第一个有效沿之后timer才开始计数</description>
                  <value>0</value>
                </enumeratedValue>
              </enumeratedValues>
            </field>
            <field>
              <name>CAPONCE</name>
              <description>CAPONCE  field description</description>
              <bitRange>[1:1]</bitRange>
              <access>read-write</access>
              <enumeratedValues />
            </field>
            <field>
              <name>CAPEDGE</name>
              <description>CAPEDGE  field description</description>
              <bitRange>[0:0]</bitRange>
              <access>read-write</access>
              <enumeratedValues />
            </field>
          </fields>
        </register>
        <register>
          <name>INSR</name>
          <description>ET2 Input Select Register</description>
          <addressOffset>0x4</addressOffset>
          <size>32</size>
          <access>read-write</access>
          <resetValue>0x00000000</resetValue>
          <fields>
            <field>
              <name>SIG2SEL</name>
              <description>SIG2SEL  field description</description>
              <bitRange>[7:7]</bitRange>
              <access>read-write</access>
              <enumeratedValues>
                <enumeratedValue>
                  <name />
                  <description>扩展定时器3的内部信号2选择Group1</description>
                  <value>1</value>
                </enumeratedValue>
                <enumeratedValue>
                  <name />
                  <description>扩展定时器3的内部信号2选择Group2</description>
                  <value>0</value>
                </enumeratedValue>
              </enumeratedValues>
            </field>
            <field>
              <name>SIG1SEL</name>
              <description>SIG1SEL  field description</description>
              <bitRange>[6:6]</bitRange>
              <access>read-write</access>
              <enumeratedValues>
                <enumeratedValue>
                  <name />
                  <description>扩展定时器3的内部信号1选择Group2</description>
                  <value>1</value>
                </enumeratedValue>
                <enumeratedValue>
                  <name />
                  <description>扩展定时器3的内部信号1选择Group1</description>
                  <value>0</value>
                </enumeratedValue>
              </enumeratedValues>
            </field>
            <field>
              <name>GRP2SEL</name>
              <description>GRP2SEL  field description</description>
              <bitRange>[4:2]</bitRange>
              <access>read-write</access>
              <enumeratedValues>
                <enumeratedValue>
                  <name />
                  <description>UART0_RX</description>
                  <value>0</value>
                </enumeratedValue>
                <enumeratedValue>
                  <name />
                  <description>UART1_RX</description>
                  <value>1</value>
                </enumeratedValue>
                <enumeratedValue>
                  <name />
                  <description>XTLF</description>
                  <value>2</value>
                </enumeratedValue>
                <enumeratedValue>
                  <name />
                  <description>ET1_IN1</description>
                  <value>3</value>
                </enumeratedValue>
                <enumeratedValue>
                  <name />
                  <description>ET1_IN2</description>
                  <value>4</value>
                </enumeratedValue>
                <enumeratedValue>
                  <name />
                  <description>CMP1O（比较器1输出）</description>
                  <value>5</value>
                </enumeratedValue>
                <enumeratedValue>
                  <name />
                  <description>CMP2O（比较器2输出）</description>
                  <value>6</value>
                </enumeratedValue>
                <enumeratedValue>
                  <name />
                  <description>RCMF</description>
                  <value>7</value>
                </enumeratedValue>
                <enumeratedValue>
                  <name />
                  <description>UART2_RX</description>
                  <value>0</value>
                </enumeratedValue>
                <enumeratedValue>
                  <name />
                  <description>UART3_RX</description>
                  <value>1</value>
                </enumeratedValue>
                <enumeratedValue>
                  <name />
                  <description>XTLF</description>
                  <value>2</value>
                </enumeratedValue>
                <enumeratedValue>
                  <name />
                  <description>ET2_IN1</description>
                  <value>3</value>
                </enumeratedValue>
                <enumeratedValue>
                  <name />
                  <description>ET2_IN2</description>
                  <value>4</value>
                </enumeratedValue>
                <enumeratedValue>
                  <name />
                  <description>CMP1O（比较器1输出）</description>
                  <value>5</value>
                </enumeratedValue>
                <enumeratedValue>
                  <name />
                  <description>CMP2O（比较器2输出）</description>
                  <value>6</value>
                </enumeratedValue>
                <enumeratedValue>
                  <name />
                  <description>RCMF</description>
                  <value>7</value>
                </enumeratedValue>
                <enumeratedValue>
                  <name />
                  <description>ET3_IN1</description>
                  <value>0</value>
                </enumeratedValue>
                <enumeratedValue>
                  <name />
                  <description>XTLF</description>
                  <value>1</value>
                </enumeratedValue>
                <enumeratedValue>
                  <name />
                  <description>UART4_RX</description>
                  <value>2</value>
                </enumeratedValue>
                <enumeratedValue>
                  <name />
                  <description>UART5_RX</description>
                  <value>3</value>
                </enumeratedValue>
                <enumeratedValue>
                  <name />
                  <description>RTCSEC</description>
                  <value>4</value>
                </enumeratedValue>
                <enumeratedValue>
                  <name />
                  <description>RFU</description>
                  <value>5</value>
                </enumeratedValue>
                <enumeratedValue>
                  <name />
                  <description>RFU</description>
                  <value>6</value>
                </enumeratedValue>
                <enumeratedValue>
                  <name />
                  <description>RFU</description>
                  <value>7</value>
                </enumeratedValue>
                <enumeratedValue>
                  <name />
                  <description>ET4_IN1</description>
                  <value>0</value>
                </enumeratedValue>
                <enumeratedValue>
                  <name />
                  <description>XTLF</description>
                  <value>1</value>
                </enumeratedValue>
                <enumeratedValue>
                  <name />
                  <description>UART_RX2</description>
                  <value>2</value>
                </enumeratedValue>
                <enumeratedValue>
                  <name />
                  <description>UART_RX0</description>
                  <value>3</value>
                </enumeratedValue>
                <enumeratedValue>
                  <name />
                  <description>CMP1O（比较器1输出）</description>
                  <value>4</value>
                </enumeratedValue>
                <enumeratedValue>
                  <name />
                  <description>CMP2O（比较器2输出）</description>
                  <value>5</value>
                </enumeratedValue>
                <enumeratedValue>
                  <name />
                  <description>RTCSEC</description>
                  <value>6</value>
                </enumeratedValue>
                <enumeratedValue>
                  <name />
                  <description>RCMF</description>
                  <value>7</value>
                </enumeratedValue>
              </enumeratedValues>
            </field>
            <field>
              <name>GRP1SEL</name>
              <description>GRP1SEL  field description</description>
              <bitRange>[1:0]</bitRange>
              <access>read-write</access>
              <enumeratedValues>
                <enumeratedValue>
                  <name />
                  <description>APBCLK</description>
                  <value>0</value>
                </enumeratedValue>
                <enumeratedValue>
                  <name />
                  <description>XTLF</description>
                  <value>1</value>
                </enumeratedValue>
                <enumeratedValue>
                  <name />
                  <description>RCLP</description>
                  <value>2</value>
                </enumeratedValue>
                <enumeratedValue>
                  <name />
                  <description>ET1_IN0</description>
                  <value>3</value>
                </enumeratedValue>
                <enumeratedValue>
                  <name />
                  <description>APBCLK</description>
                  <value>0</value>
                </enumeratedValue>
                <enumeratedValue>
                  <name />
                  <description>XTLF</description>
                  <value>1</value>
                </enumeratedValue>
                <enumeratedValue>
                  <name />
                  <description>RCLP</description>
                  <value>2</value>
                </enumeratedValue>
                <enumeratedValue>
                  <name />
                  <description>ET2_IN0</description>
                  <value>3</value>
                </enumeratedValue>
                <enumeratedValue>
                  <name />
                  <description>APBCLK</description>
                  <value>0</value>
                </enumeratedValue>
                <enumeratedValue>
                  <name />
                  <description>ET3_IN0</description>
                  <value>1</value>
                </enumeratedValue>
                <enumeratedValue>
                  <name />
                  <description>RTCSEC</description>
                  <value>2</value>
                </enumeratedValue>
                <enumeratedValue>
                  <name />
                  <description>RCLP</description>
                  <value>3</value>
                </enumeratedValue>
                <enumeratedValue>
                  <name />
                  <description>APBCLK</description>
                  <value>0</value>
                </enumeratedValue>
                <enumeratedValue>
                  <name />
                  <description>ET4_IN0</description>
                  <value>1</value>
                </enumeratedValue>
                <enumeratedValue>
                  <name />
                  <description>RTC64HZ</description>
                  <value>2</value>
                </enumeratedValue>
                <enumeratedValue>
                  <name />
                  <description>RCMF</description>
                  <value>3</value>
                </enumeratedValue>
              </enumeratedValues>
            </field>
          </fields>
        </register>
        <register>
          <name>PSCR1</name>
          <description>ET2 Prescaler Register1</description>
          <addressOffset>0x8</addressOffset>
          <size>32</size>
          <access>read-write</access>
          <resetValue>0x00000000</resetValue>
          <fields>
            <field>
              <name>PRESCALE1</name>
              <description>PRESCALE1  field description</description>
              <bitRange>[7:0]</bitRange>
              <access>read-write</access>
              <enumeratedValues />
            </field>
          </fields>
        </register>
        <register>
          <name>PSCR2</name>
          <description>ET2 Prescaler Register2</description>
          <addressOffset>0xc</addressOffset>
          <size>32</size>
          <access>read-write</access>
          <resetValue>0x00000000</resetValue>
          <fields>
            <field>
              <name>PRESCALE2</name>
              <description>PRESCALE2  field description</description>
              <bitRange>[7:0]</bitRange>
              <access>read-write</access>
              <enumeratedValues />
            </field>
          </fields>
        </register>
        <register>
          <name>IVR</name>
          <description>ET2 Initial Value Register</description>
          <addressOffset>0x10</addressOffset>
          <size>32</size>
          <access>read-write</access>
          <resetValue>0x00000000</resetValue>
          <fields>
            <field>
              <name>INITVALUE</name>
              <description>INITVALUE  field description</description>
              <bitRange>[15:0]</bitRange>
              <access>read-write</access>
              <enumeratedValues />
            </field>
          </fields>
        </register>
        <register>
          <name>CMPR</name>
          <description>ET2 Compare Register</description>
          <addressOffset>0x14</addressOffset>
          <size>32</size>
          <access>read-write</access>
          <resetValue>0x00000000</resetValue>
          <fields>
            <field>
              <name>CMP</name>
              <description>CMP  field description</description>
              <bitRange>[15:0]</bitRange>
              <access>read-write</access>
              <enumeratedValues />
            </field>
          </fields>
        </register>
        <register>
          <name>IER</name>
          <description>ET2 Interrupt Enable Register</description>
          <addressOffset>0x18</addressOffset>
          <size>32</size>
          <access>read-write</access>
          <resetValue>0x00000000</resetValue>
          <fields>
            <field>
              <name>CMPIE</name>
              <description>CMPIE  field description</description>
              <bitRange>[2:2]</bitRange>
              <access>read-write</access>
              <enumeratedValues>
                <enumeratedValue>
                  <name />
                  <description>使能</description>
                  <value>1</value>
                </enumeratedValue>
                <enumeratedValue>
                  <name />
                  <description>禁止</description>
                  <value>0</value>
                </enumeratedValue>
              </enumeratedValues>
            </field>
            <field>
              <name>CAPIE</name>
              <description>CAPIE  field description</description>
              <bitRange>[1:1]</bitRange>
              <access>read-write</access>
              <enumeratedValues>
                <enumeratedValue>
                  <name />
                  <description>使能</description>
                  <value>1</value>
                </enumeratedValue>
                <enumeratedValue>
                  <name />
                  <description>禁止</description>
                  <value>0</value>
                </enumeratedValue>
              </enumeratedValues>
            </field>
            <field>
              <name>OVIE</name>
              <description>OVIE  field description</description>
              <bitRange>[0:0]</bitRange>
              <access>read-write</access>
              <enumeratedValues>
                <enumeratedValue>
                  <name />
                  <description>使能</description>
                  <value>1</value>
                </enumeratedValue>
                <enumeratedValue>
                  <name />
                  <description>禁止</description>
                  <value>0</value>
                </enumeratedValue>
              </enumeratedValues>
            </field>
          </fields>
        </register>
        <register>
          <name>ISR</name>
          <description>ET2 Interrupt Status Register</description>
          <addressOffset>0x1c</addressOffset>
          <size>32</size>
          <access>read-write</access>
          <resetValue>0x00000000</resetValue>
          <fields>
            <field>
              <name>CMPIF</name>
              <description>CMPIF  field description</description>
              <bitRange>[3:3]</bitRange>
              <access>read-write</access>
              <enumeratedValues>
                <enumeratedValue>
                  <name />
                  <description>当前计数器的值大于等于比较寄存器的值</description>
                  <value>1</value>
                </enumeratedValue>
                <enumeratedValue>
                  <name />
                  <description>当前计数器的值小于比较寄存器的值</description>
                  <value>0</value>
                </enumeratedValue>
              </enumeratedValues>
            </field>
            <field>
              <name>EDGESTA</name>
              <description>EDGESTA  field description</description>
              <bitRange>[2:2]</bitRange>
              <access>read-write</access>
              <enumeratedValues>
                <enumeratedValue>
                  <name />
                  <description>脉冲宽度捕捉模式时表示捕捉到下沿</description>
                  <value>1</value>
                </enumeratedValue>
                <enumeratedValue>
                  <name />
                  <description>脉冲宽度捕捉模式时表示捕捉到上沿</description>
                  <value>0</value>
                </enumeratedValue>
              </enumeratedValues>
            </field>
            <field>
              <name>CAPIF</name>
              <description>CAPIF  field description</description>
              <bitRange>[1:1]</bitRange>
              <access>read-write</access>
              <enumeratedValues>
                <enumeratedValue>
                  <name />
                  <description>捕捉到指定的沿</description>
                  <value>1</value>
                </enumeratedValue>
                <enumeratedValue>
                  <name />
                  <description>未捕捉到指定的沿</description>
                  <value>0</value>
                </enumeratedValue>
              </enumeratedValues>
            </field>
            <field>
              <name>OVIF</name>
              <description>OVIF  field description</description>
              <bitRange>[0:0]</bitRange>
              <access>read-write</access>
              <enumeratedValues>
                <enumeratedValue>
                  <name />
                  <description>产生计数溢出</description>
                  <value>1</value>
                </enumeratedValue>
                <enumeratedValue>
                  <name />
                  <description>未产生溢出</description>
                  <value>0</value>
                </enumeratedValue>
              </enumeratedValues>
            </field>
          </fields>
        </register>
      </registers>
    </peripheral>
    <peripheral>
      <name>ET3</name>
      <description>ET3 module information</description>
      <groupName>ET</groupName>
      <baseAddress>0x400130d0</baseAddress>
      <size>32</size>
      <access>read-write</access>
      <addressBlock>
        <offset>0</offset>
        <size>0x20</size>
        <usage>registers</usage>
      </addressBlock>
      <registers>
        <register>
          <name>CR</name>
          <description>ET3 Control Register</description>
          <addressOffset>0x0</addressOffset>
          <size>32</size>
          <access>read-write</access>
          <resetValue>0x00000000</resetValue>
          <fields>
            <field>
              <name>OPOL</name>
              <description>OPOL  field description</description>
              <bitRange>[10:10]</bitRange>
              <access>read-write</access>
              <enumeratedValues>
                <enumeratedValue>
                  <name />
                  <description>输出不取反</description>
                  <value>0</value>
                </enumeratedValue>
                <enumeratedValue>
                  <name />
                  <description>输出取反</description>
                  <value>1</value>
                </enumeratedValue>
              </enumeratedValues>
            </field>
            <field>
              <name>EXFLT</name>
              <description>EXFLT  field description</description>
              <bitRange>[9:9]</bitRange>
              <access>read-write</access>
              <enumeratedValues />
            </field>
            <field>
              <name>PWM</name>
              <description>PWM  field description</description>
              <bitRange>[8:8]</bitRange>
              <access>read-write</access>
              <enumeratedValues />
            </field>
            <field>
              <name>CEN</name>
              <description>CEN  field description</description>
              <bitRange>[7:7]</bitRange>
              <access>read-write</access>
              <enumeratedValues />
            </field>
            <field>
              <name>MOD</name>
              <description>MOD  field description</description>
              <bitRange>[6:6]</bitRange>
              <access>read-write</access>
              <enumeratedValues />
            </field>
            <field>
              <name>CASEN</name>
              <description>CASEN  field description</description>
              <bitRange>[5:5]</bitRange>
              <access>read-write</access>
              <enumeratedValues />
            </field>
            <field>
              <name>EDGESEL</name>
              <description>EDGESEL  field description</description>
              <bitRange>[4:4]</bitRange>
              <access>read-write</access>
              <enumeratedValues />
            </field>
            <field>
              <name>CAPMOD</name>
              <description>CAPMOD  field description</description>
              <bitRange>[3:3]</bitRange>
              <access>read-write</access>
              <enumeratedValues />
            </field>
            <field>
              <name>CAPCLR</name>
              <description>CAPCLR  field description</description>
              <bitRange>[2:2]</bitRange>
              <access>read-write</access>
              <enumeratedValues>
                <enumeratedValue>
                  <name />
                  <description>使能后计数器保持0，捕捉到第一个有效沿之后timer才开始计数</description>
                  <value>0</value>
                </enumeratedValue>
              </enumeratedValues>
            </field>
            <field>
              <name>CAPONCE</name>
              <description>CAPONCE  field description</description>
              <bitRange>[1:1]</bitRange>
              <access>read-write</access>
              <enumeratedValues />
            </field>
            <field>
              <name>CAPEDGE</name>
              <description>CAPEDGE  field description</description>
              <bitRange>[0:0]</bitRange>
              <access>read-write</access>
              <enumeratedValues />
            </field>
          </fields>
        </register>
        <register>
          <name>INSR</name>
          <description>ET3 Input Select Register</description>
          <addressOffset>0x4</addressOffset>
          <size>32</size>
          <access>read-write</access>
          <resetValue>0x00000000</resetValue>
          <fields>
            <field>
              <name>SIG2SEL</name>
              <description>SIG2SEL  field description</description>
              <bitRange>[7:7]</bitRange>
              <access>read-write</access>
              <enumeratedValues>
                <enumeratedValue>
                  <name />
                  <description>扩展定时器3的内部信号2选择Group1</description>
                  <value>1</value>
                </enumeratedValue>
                <enumeratedValue>
                  <name />
                  <description>扩展定时器3的内部信号2选择Group2</description>
                  <value>0</value>
                </enumeratedValue>
              </enumeratedValues>
            </field>
            <field>
              <name>SIG1SEL</name>
              <description>SIG1SEL  field description</description>
              <bitRange>[6:6]</bitRange>
              <access>read-write</access>
              <enumeratedValues>
                <enumeratedValue>
                  <name />
                  <description>扩展定时器3的内部信号1选择Group2</description>
                  <value>1</value>
                </enumeratedValue>
                <enumeratedValue>
                  <name />
                  <description>扩展定时器3的内部信号1选择Group1</description>
                  <value>0</value>
                </enumeratedValue>
              </enumeratedValues>
            </field>
            <field>
              <name>GRP2SEL</name>
              <description>GRP2SEL  field description</description>
              <bitRange>[4:2]</bitRange>
              <access>read-write</access>
              <enumeratedValues>
                <enumeratedValue>
                  <name />
                  <description>UART0_RX</description>
                  <value>0</value>
                </enumeratedValue>
                <enumeratedValue>
                  <name />
                  <description>UART1_RX</description>
                  <value>1</value>
                </enumeratedValue>
                <enumeratedValue>
                  <name />
                  <description>XTLF</description>
                  <value>2</value>
                </enumeratedValue>
                <enumeratedValue>
                  <name />
                  <description>ET1_IN1</description>
                  <value>3</value>
                </enumeratedValue>
                <enumeratedValue>
                  <name />
                  <description>ET1_IN2</description>
                  <value>4</value>
                </enumeratedValue>
                <enumeratedValue>
                  <name />
                  <description>CMP1O（比较器1输出）</description>
                  <value>5</value>
                </enumeratedValue>
                <enumeratedValue>
                  <name />
                  <description>CMP2O（比较器2输出）</description>
                  <value>6</value>
                </enumeratedValue>
                <enumeratedValue>
                  <name />
                  <description>RCMF</description>
                  <value>7</value>
                </enumeratedValue>
                <enumeratedValue>
                  <name />
                  <description>UART2_RX</description>
                  <value>0</value>
                </enumeratedValue>
                <enumeratedValue>
                  <name />
                  <description>UART3_RX</description>
                  <value>1</value>
                </enumeratedValue>
                <enumeratedValue>
                  <name />
                  <description>XTLF</description>
                  <value>2</value>
                </enumeratedValue>
                <enumeratedValue>
                  <name />
                  <description>ET2_IN1</description>
                  <value>3</value>
                </enumeratedValue>
                <enumeratedValue>
                  <name />
                  <description>ET2_IN2</description>
                  <value>4</value>
                </enumeratedValue>
                <enumeratedValue>
                  <name />
                  <description>CMP1O（比较器1输出）</description>
                  <value>5</value>
                </enumeratedValue>
                <enumeratedValue>
                  <name />
                  <description>CMP2O（比较器2输出）</description>
                  <value>6</value>
                </enumeratedValue>
                <enumeratedValue>
                  <name />
                  <description>RCMF</description>
                  <value>7</value>
                </enumeratedValue>
                <enumeratedValue>
                  <name />
                  <description>ET3_IN1</description>
                  <value>0</value>
                </enumeratedValue>
                <enumeratedValue>
                  <name />
                  <description>XTLF</description>
                  <value>1</value>
                </enumeratedValue>
                <enumeratedValue>
                  <name />
                  <description>UART4_RX</description>
                  <value>2</value>
                </enumeratedValue>
                <enumeratedValue>
                  <name />
                  <description>UART5_RX</description>
                  <value>3</value>
                </enumeratedValue>
                <enumeratedValue>
                  <name />
                  <description>RTCSEC</description>
                  <value>4</value>
                </enumeratedValue>
                <enumeratedValue>
                  <name />
                  <description>RFU</description>
                  <value>5</value>
                </enumeratedValue>
                <enumeratedValue>
                  <name />
                  <description>RFU</description>
                  <value>6</value>
                </enumeratedValue>
                <enumeratedValue>
                  <name />
                  <description>RFU</description>
                  <value>7</value>
                </enumeratedValue>
                <enumeratedValue>
                  <name />
                  <description>ET4_IN1</description>
                  <value>0</value>
                </enumeratedValue>
                <enumeratedValue>
                  <name />
                  <description>XTLF</description>
                  <value>1</value>
                </enumeratedValue>
                <enumeratedValue>
                  <name />
                  <description>UART_RX2</description>
                  <value>2</value>
                </enumeratedValue>
                <enumeratedValue>
                  <name />
                  <description>UART_RX0</description>
                  <value>3</value>
                </enumeratedValue>
                <enumeratedValue>
                  <name />
                  <description>CMP1O（比较器1输出）</description>
                  <value>4</value>
                </enumeratedValue>
                <enumeratedValue>
                  <name />
                  <description>CMP2O（比较器2输出）</description>
                  <value>5</value>
                </enumeratedValue>
                <enumeratedValue>
                  <name />
                  <description>RTCSEC</description>
                  <value>6</value>
                </enumeratedValue>
                <enumeratedValue>
                  <name />
                  <description>RCMF</description>
                  <value>7</value>
                </enumeratedValue>
              </enumeratedValues>
            </field>
            <field>
              <name>GRP1SEL</name>
              <description>GRP1SEL  field description</description>
              <bitRange>[1:0]</bitRange>
              <access>read-write</access>
              <enumeratedValues>
                <enumeratedValue>
                  <name />
                  <description>APBCLK</description>
                  <value>0</value>
                </enumeratedValue>
                <enumeratedValue>
                  <name />
                  <description>XTLF</description>
                  <value>1</value>
                </enumeratedValue>
                <enumeratedValue>
                  <name />
                  <description>RCLP</description>
                  <value>2</value>
                </enumeratedValue>
                <enumeratedValue>
                  <name />
                  <description>ET1_IN0</description>
                  <value>3</value>
                </enumeratedValue>
                <enumeratedValue>
                  <name />
                  <description>APBCLK</description>
                  <value>0</value>
                </enumeratedValue>
                <enumeratedValue>
                  <name />
                  <description>XTLF</description>
                  <value>1</value>
                </enumeratedValue>
                <enumeratedValue>
                  <name />
                  <description>RCLP</description>
                  <value>2</value>
                </enumeratedValue>
                <enumeratedValue>
                  <name />
                  <description>ET2_IN0</description>
                  <value>3</value>
                </enumeratedValue>
                <enumeratedValue>
                  <name />
                  <description>APBCLK</description>
                  <value>0</value>
                </enumeratedValue>
                <enumeratedValue>
                  <name />
                  <description>ET3_IN0</description>
                  <value>1</value>
                </enumeratedValue>
                <enumeratedValue>
                  <name />
                  <description>RTCSEC</description>
                  <value>2</value>
                </enumeratedValue>
                <enumeratedValue>
                  <name />
                  <description>RCLP</description>
                  <value>3</value>
                </enumeratedValue>
                <enumeratedValue>
                  <name />
                  <description>APBCLK</description>
                  <value>0</value>
                </enumeratedValue>
                <enumeratedValue>
                  <name />
                  <description>ET4_IN0</description>
                  <value>1</value>
                </enumeratedValue>
                <enumeratedValue>
                  <name />
                  <description>RTC64HZ</description>
                  <value>2</value>
                </enumeratedValue>
                <enumeratedValue>
                  <name />
                  <description>RCMF</description>
                  <value>3</value>
                </enumeratedValue>
              </enumeratedValues>
            </field>
          </fields>
        </register>
        <register>
          <name>PSCR1</name>
          <description>ET3 Prescaler Register1</description>
          <addressOffset>0x8</addressOffset>
          <size>32</size>
          <access>read-write</access>
          <resetValue>0x00000000</resetValue>
          <fields>
            <field>
              <name>PRESCALE1</name>
              <description>PRESCALE1  field description</description>
              <bitRange>[7:0]</bitRange>
              <access>read-write</access>
              <enumeratedValues />
            </field>
          </fields>
        </register>
        <register>
          <name>PSCR2</name>
          <description>ET3 Prescaler Register2</description>
          <addressOffset>0xc</addressOffset>
          <size>32</size>
          <access>read-write</access>
          <resetValue>0x00000000</resetValue>
          <fields>
            <field>
              <name>PRESCALE2</name>
              <description>PRESCALE2  field description</description>
              <bitRange>[7:0]</bitRange>
              <access>read-write</access>
              <enumeratedValues />
            </field>
          </fields>
        </register>
        <register>
          <name>IVR</name>
          <description>ET3 Initial Value Register</description>
          <addressOffset>0x10</addressOffset>
          <size>32</size>
          <access>read-write</access>
          <resetValue>0x00000000</resetValue>
          <fields>
            <field>
              <name>INITVALUE</name>
              <description>INITVALUE  field description</description>
              <bitRange>[15:0]</bitRange>
              <access>read-write</access>
              <enumeratedValues />
            </field>
          </fields>
        </register>
        <register>
          <name>CMPR</name>
          <description>ET3 Compare Register</description>
          <addressOffset>0x14</addressOffset>
          <size>32</size>
          <access>read-write</access>
          <resetValue>0x00000000</resetValue>
          <fields>
            <field>
              <name>CMP</name>
              <description>CMP  field description</description>
              <bitRange>[15:0]</bitRange>
              <access>read-write</access>
              <enumeratedValues />
            </field>
          </fields>
        </register>
        <register>
          <name>IER</name>
          <description>ET3 Interrupt Enable Register</description>
          <addressOffset>0x18</addressOffset>
          <size>32</size>
          <access>read-write</access>
          <resetValue>0x00000000</resetValue>
          <fields>
            <field>
              <name>CMPIE</name>
              <description>CMPIE  field description</description>
              <bitRange>[2:2]</bitRange>
              <access>read-write</access>
              <enumeratedValues>
                <enumeratedValue>
                  <name />
                  <description>使能</description>
                  <value>1</value>
                </enumeratedValue>
                <enumeratedValue>
                  <name />
                  <description>禁止</description>
                  <value>0</value>
                </enumeratedValue>
              </enumeratedValues>
            </field>
            <field>
              <name>CAPIE</name>
              <description>CAPIE  field description</description>
              <bitRange>[1:1]</bitRange>
              <access>read-write</access>
              <enumeratedValues>
                <enumeratedValue>
                  <name />
                  <description>使能</description>
                  <value>1</value>
                </enumeratedValue>
                <enumeratedValue>
                  <name />
                  <description>禁止</description>
                  <value>0</value>
                </enumeratedValue>
              </enumeratedValues>
            </field>
            <field>
              <name>OVIE</name>
              <description>OVIE  field description</description>
              <bitRange>[0:0]</bitRange>
              <access>read-write</access>
              <enumeratedValues>
                <enumeratedValue>
                  <name />
                  <description>使能</description>
                  <value>1</value>
                </enumeratedValue>
                <enumeratedValue>
                  <name />
                  <description>禁止</description>
                  <value>0</value>
                </enumeratedValue>
              </enumeratedValues>
            </field>
          </fields>
        </register>
        <register>
          <name>ISR</name>
          <description>ET3 Interrupt Status Register</description>
          <addressOffset>0x1c</addressOffset>
          <size>32</size>
          <access>read-write</access>
          <resetValue>0x00000000</resetValue>
          <fields>
            <field>
              <name>CMPIF</name>
              <description>CMPIF  field description</description>
              <bitRange>[3:3]</bitRange>
              <access>read-write</access>
              <enumeratedValues>
                <enumeratedValue>
                  <name />
                  <description>当前计数器的值大于等于比较寄存器的值</description>
                  <value>1</value>
                </enumeratedValue>
                <enumeratedValue>
                  <name />
                  <description>当前计数器的值小于比较寄存器的值</description>
                  <value>0</value>
                </enumeratedValue>
              </enumeratedValues>
            </field>
            <field>
              <name>EDGESTA</name>
              <description>EDGESTA  field description</description>
              <bitRange>[2:2]</bitRange>
              <access>read-write</access>
              <enumeratedValues>
                <enumeratedValue>
                  <name />
                  <description>脉冲宽度捕捉模式时表示捕捉到下沿</description>
                  <value>1</value>
                </enumeratedValue>
                <enumeratedValue>
                  <name />
                  <description>脉冲宽度捕捉模式时表示捕捉到上沿</description>
                  <value>0</value>
                </enumeratedValue>
              </enumeratedValues>
            </field>
            <field>
              <name>CAPIF</name>
              <description>CAPIF  field description</description>
              <bitRange>[1:1]</bitRange>
              <access>read-write</access>
              <enumeratedValues>
                <enumeratedValue>
                  <name />
                  <description>捕捉到指定的沿</description>
                  <value>1</value>
                </enumeratedValue>
                <enumeratedValue>
                  <name />
                  <description>未捕捉到指定的沿</description>
                  <value>0</value>
                </enumeratedValue>
              </enumeratedValues>
            </field>
            <field>
              <name>OVIF</name>
              <description>OVIF  field description</description>
              <bitRange>[0:0]</bitRange>
              <access>read-write</access>
              <enumeratedValues>
                <enumeratedValue>
                  <name />
                  <description>产生计数溢出</description>
                  <value>1</value>
                </enumeratedValue>
                <enumeratedValue>
                  <name />
                  <description>未产生溢出</description>
                  <value>0</value>
                </enumeratedValue>
              </enumeratedValues>
            </field>
          </fields>
        </register>
      </registers>
    </peripheral>
    <peripheral>
      <name>ET4</name>
      <description>ET4 module information</description>
      <groupName>ET</groupName>
      <baseAddress>0x400130f0</baseAddress>
      <size>32</size>
      <access>read-write</access>
      <addressBlock>
        <offset>0</offset>
        <size>0x20</size>
        <usage>registers</usage>
      </addressBlock>
      <registers>
        <register>
          <name>CR</name>
          <description>ET4 Control Register</description>
          <addressOffset>0x0</addressOffset>
          <size>32</size>
          <access>read-write</access>
          <resetValue>0x00000000</resetValue>
          <fields>
            <field>
              <name>OPOL</name>
              <description>OPOL  field description</description>
              <bitRange>[10:10]</bitRange>
              <access>read-write</access>
              <enumeratedValues>
                <enumeratedValue>
                  <name />
                  <description>输出不取反</description>
                  <value>0</value>
                </enumeratedValue>
                <enumeratedValue>
                  <name />
                  <description>输出取反</description>
                  <value>1</value>
                </enumeratedValue>
              </enumeratedValues>
            </field>
            <field>
              <name>EXFLT</name>
              <description>EXFLT  field description</description>
              <bitRange>[9:9]</bitRange>
              <access>read-write</access>
              <enumeratedValues />
            </field>
            <field>
              <name>PWM</name>
              <description>PWM  field description</description>
              <bitRange>[8:8]</bitRange>
              <access>read-write</access>
              <enumeratedValues />
            </field>
            <field>
              <name>CEN</name>
              <description>CEN  field description</description>
              <bitRange>[7:7]</bitRange>
              <access>read-write</access>
              <enumeratedValues />
            </field>
            <field>
              <name>MOD</name>
              <description>MOD  field description</description>
              <bitRange>[6:6]</bitRange>
              <access>read-write</access>
              <enumeratedValues />
            </field>
            <field>
              <name>CASEN</name>
              <description>CASEN  field description</description>
              <bitRange>[5:5]</bitRange>
              <access>read-write</access>
              <enumeratedValues />
            </field>
            <field>
              <name>EDGESEL</name>
              <description>EDGESEL  field description</description>
              <bitRange>[4:4]</bitRange>
              <access>read-write</access>
              <enumeratedValues />
            </field>
            <field>
              <name>CAPMOD</name>
              <description>CAPMOD  field description</description>
              <bitRange>[3:3]</bitRange>
              <access>read-write</access>
              <enumeratedValues />
            </field>
            <field>
              <name>CAPCLR</name>
              <description>CAPCLR  field description</description>
              <bitRange>[2:2]</bitRange>
              <access>read-write</access>
              <enumeratedValues>
                <enumeratedValue>
                  <name />
                  <description>使能后计数器保持0，捕捉到第一个有效沿之后timer才开始计数</description>
                  <value>0</value>
                </enumeratedValue>
              </enumeratedValues>
            </field>
            <field>
              <name>CAPONCE</name>
              <description>CAPONCE  field description</description>
              <bitRange>[1:1]</bitRange>
              <access>read-write</access>
              <enumeratedValues />
            </field>
            <field>
              <name>CAPEDGE</name>
              <description>CAPEDGE  field description</description>
              <bitRange>[0:0]</bitRange>
              <access>read-write</access>
              <enumeratedValues />
            </field>
          </fields>
        </register>
        <register>
          <name>INSR</name>
          <description>ET4 Input Select Register</description>
          <addressOffset>0x4</addressOffset>
          <size>32</size>
          <access>read-write</access>
          <resetValue>0x00000000</resetValue>
          <fields>
            <field>
              <name>SIG2SEL</name>
              <description>SIG2SEL  field description</description>
              <bitRange>[7:7]</bitRange>
              <access>read-write</access>
              <enumeratedValues>
                <enumeratedValue>
                  <name />
                  <description>扩展定时器3的内部信号2选择Group1</description>
                  <value>1</value>
                </enumeratedValue>
                <enumeratedValue>
                  <name />
                  <description>扩展定时器3的内部信号2选择Group2</description>
                  <value>0</value>
                </enumeratedValue>
              </enumeratedValues>
            </field>
            <field>
              <name>SIG1SEL</name>
              <description>SIG1SEL  field description</description>
              <bitRange>[6:6]</bitRange>
              <access>read-write</access>
              <enumeratedValues>
                <enumeratedValue>
                  <name />
                  <description>扩展定时器3的内部信号1选择Group2</description>
                  <value>1</value>
                </enumeratedValue>
                <enumeratedValue>
                  <name />
                  <description>扩展定时器3的内部信号1选择Group1</description>
                  <value>0</value>
                </enumeratedValue>
              </enumeratedValues>
            </field>
            <field>
              <name>GRP2SEL</name>
              <description>GRP2SEL  field description</description>
              <bitRange>[4:2]</bitRange>
              <access>read-write</access>
              <enumeratedValues>
                <enumeratedValue>
                  <name />
                  <description>UART0_RX</description>
                  <value>0</value>
                </enumeratedValue>
                <enumeratedValue>
                  <name />
                  <description>UART1_RX</description>
                  <value>1</value>
                </enumeratedValue>
                <enumeratedValue>
                  <name />
                  <description>XTLF</description>
                  <value>2</value>
                </enumeratedValue>
                <enumeratedValue>
                  <name />
                  <description>ET1_IN1</description>
                  <value>3</value>
                </enumeratedValue>
                <enumeratedValue>
                  <name />
                  <description>ET1_IN2</description>
                  <value>4</value>
                </enumeratedValue>
                <enumeratedValue>
                  <name />
                  <description>CMP1O（比较器1输出）</description>
                  <value>5</value>
                </enumeratedValue>
                <enumeratedValue>
                  <name />
                  <description>CMP2O（比较器2输出）</description>
                  <value>6</value>
                </enumeratedValue>
                <enumeratedValue>
                  <name />
                  <description>RCMF</description>
                  <value>7</value>
                </enumeratedValue>
                <enumeratedValue>
                  <name />
                  <description>UART2_RX</description>
                  <value>0</value>
                </enumeratedValue>
                <enumeratedValue>
                  <name />
                  <description>UART3_RX</description>
                  <value>1</value>
                </enumeratedValue>
                <enumeratedValue>
                  <name />
                  <description>XTLF</description>
                  <value>2</value>
                </enumeratedValue>
                <enumeratedValue>
                  <name />
                  <description>ET2_IN1</description>
                  <value>3</value>
                </enumeratedValue>
                <enumeratedValue>
                  <name />
                  <description>ET2_IN2</description>
                  <value>4</value>
                </enumeratedValue>
                <enumeratedValue>
                  <name />
                  <description>CMP1O（比较器1输出）</description>
                  <value>5</value>
                </enumeratedValue>
                <enumeratedValue>
                  <name />
                  <description>CMP2O（比较器2输出）</description>
                  <value>6</value>
                </enumeratedValue>
                <enumeratedValue>
                  <name />
                  <description>RCMF</description>
                  <value>7</value>
                </enumeratedValue>
                <enumeratedValue>
                  <name />
                  <description>ET3_IN1</description>
                  <value>0</value>
                </enumeratedValue>
                <enumeratedValue>
                  <name />
                  <description>XTLF</description>
                  <value>1</value>
                </enumeratedValue>
                <enumeratedValue>
                  <name />
                  <description>UART4_RX</description>
                  <value>2</value>
                </enumeratedValue>
                <enumeratedValue>
                  <name />
                  <description>UART5_RX</description>
                  <value>3</value>
                </enumeratedValue>
                <enumeratedValue>
                  <name />
                  <description>RTCSEC</description>
                  <value>4</value>
                </enumeratedValue>
                <enumeratedValue>
                  <name />
                  <description>RFU</description>
                  <value>5</value>
                </enumeratedValue>
                <enumeratedValue>
                  <name />
                  <description>RFU</description>
                  <value>6</value>
                </enumeratedValue>
                <enumeratedValue>
                  <name />
                  <description>RFU</description>
                  <value>7</value>
                </enumeratedValue>
                <enumeratedValue>
                  <name />
                  <description>ET4_IN1</description>
                  <value>0</value>
                </enumeratedValue>
                <enumeratedValue>
                  <name />
                  <description>XTLF</description>
                  <value>1</value>
                </enumeratedValue>
                <enumeratedValue>
                  <name />
                  <description>UART_RX2</description>
                  <value>2</value>
                </enumeratedValue>
                <enumeratedValue>
                  <name />
                  <description>UART_RX0</description>
                  <value>3</value>
                </enumeratedValue>
                <enumeratedValue>
                  <name />
                  <description>CMP1O（比较器1输出）</description>
                  <value>4</value>
                </enumeratedValue>
                <enumeratedValue>
                  <name />
                  <description>CMP2O（比较器2输出）</description>
                  <value>5</value>
                </enumeratedValue>
                <enumeratedValue>
                  <name />
                  <description>RTCSEC</description>
                  <value>6</value>
                </enumeratedValue>
                <enumeratedValue>
                  <name />
                  <description>RCMF</description>
                  <value>7</value>
                </enumeratedValue>
              </enumeratedValues>
            </field>
            <field>
              <name>GRP1SEL</name>
              <description>GRP1SEL  field description</description>
              <bitRange>[1:0]</bitRange>
              <access>read-write</access>
              <enumeratedValues>
                <enumeratedValue>
                  <name />
                  <description>APBCLK</description>
                  <value>0</value>
                </enumeratedValue>
                <enumeratedValue>
                  <name />
                  <description>XTLF</description>
                  <value>1</value>
                </enumeratedValue>
                <enumeratedValue>
                  <name />
                  <description>RCLP</description>
                  <value>2</value>
                </enumeratedValue>
                <enumeratedValue>
                  <name />
                  <description>ET1_IN0</description>
                  <value>3</value>
                </enumeratedValue>
                <enumeratedValue>
                  <name />
                  <description>APBCLK</description>
                  <value>0</value>
                </enumeratedValue>
                <enumeratedValue>
                  <name />
                  <description>XTLF</description>
                  <value>1</value>
                </enumeratedValue>
                <enumeratedValue>
                  <name />
                  <description>RCLP</description>
                  <value>2</value>
                </enumeratedValue>
                <enumeratedValue>
                  <name />
                  <description>ET2_IN0</description>
                  <value>3</value>
                </enumeratedValue>
                <enumeratedValue>
                  <name />
                  <description>APBCLK</description>
                  <value>0</value>
                </enumeratedValue>
                <enumeratedValue>
                  <name />
                  <description>ET3_IN0</description>
                  <value>1</value>
                </enumeratedValue>
                <enumeratedValue>
                  <name />
                  <description>RTCSEC</description>
                  <value>2</value>
                </enumeratedValue>
                <enumeratedValue>
                  <name />
                  <description>RCLP</description>
                  <value>3</value>
                </enumeratedValue>
                <enumeratedValue>
                  <name />
                  <description>APBCLK</description>
                  <value>0</value>
                </enumeratedValue>
                <enumeratedValue>
                  <name />
                  <description>ET4_IN0</description>
                  <value>1</value>
                </enumeratedValue>
                <enumeratedValue>
                  <name />
                  <description>RTC64HZ</description>
                  <value>2</value>
                </enumeratedValue>
                <enumeratedValue>
                  <name />
                  <description>RCMF</description>
                  <value>3</value>
                </enumeratedValue>
              </enumeratedValues>
            </field>
          </fields>
        </register>
        <register>
          <name>PSCR1</name>
          <description>ET4 Prescaler Register1</description>
          <addressOffset>0x8</addressOffset>
          <size>32</size>
          <access>read-write</access>
          <resetValue>0x00000000</resetValue>
          <fields>
            <field>
              <name>PRESCALE1</name>
              <description>PRESCALE1  field description</description>
              <bitRange>[7:0]</bitRange>
              <access>read-write</access>
              <enumeratedValues />
            </field>
          </fields>
        </register>
        <register>
          <name>PSCR2</name>
          <description>ET4 Prescaler Register2</description>
          <addressOffset>0xc</addressOffset>
          <size>32</size>
          <access>read-write</access>
          <resetValue>0x00000000</resetValue>
          <fields>
            <field>
              <name>PRESCALE2</name>
              <description>PRESCALE2  field description</description>
              <bitRange>[7:0]</bitRange>
              <access>read-write</access>
              <enumeratedValues />
            </field>
          </fields>
        </register>
        <register>
          <name>IVR</name>
          <description>ET4 Initial Value Register</description>
          <addressOffset>0x10</addressOffset>
          <size>32</size>
          <access>read-write</access>
          <resetValue>0x00000000</resetValue>
          <fields>
            <field>
              <name>INITVALUE</name>
              <description>INITVALUE  field description</description>
              <bitRange>[15:0]</bitRange>
              <access>read-write</access>
              <enumeratedValues />
            </field>
          </fields>
        </register>
        <register>
          <name>CMPR</name>
          <description>ET4 Compare Register</description>
          <addressOffset>0x14</addressOffset>
          <size>32</size>
          <access>read-write</access>
          <resetValue>0x00000000</resetValue>
          <fields>
            <field>
              <name>CMP</name>
              <description>CMP  field description</description>
              <bitRange>[15:0]</bitRange>
              <access>read-write</access>
              <enumeratedValues />
            </field>
          </fields>
        </register>
        <register>
          <name>IER</name>
          <description>ET4 Interrupt Enable Register</description>
          <addressOffset>0x18</addressOffset>
          <size>32</size>
          <access>read-write</access>
          <resetValue>0x00000000</resetValue>
          <fields>
            <field>
              <name>CMPIE</name>
              <description>CMPIE  field description</description>
              <bitRange>[2:2]</bitRange>
              <access>read-write</access>
              <enumeratedValues>
                <enumeratedValue>
                  <name />
                  <description>使能</description>
                  <value>1</value>
                </enumeratedValue>
                <enumeratedValue>
                  <name />
                  <description>禁止</description>
                  <value>0</value>
                </enumeratedValue>
              </enumeratedValues>
            </field>
            <field>
              <name>CAPIE</name>
              <description>CAPIE  field description</description>
              <bitRange>[1:1]</bitRange>
              <access>read-write</access>
              <enumeratedValues>
                <enumeratedValue>
                  <name />
                  <description>使能</description>
                  <value>1</value>
                </enumeratedValue>
                <enumeratedValue>
                  <name />
                  <description>禁止</description>
                  <value>0</value>
                </enumeratedValue>
              </enumeratedValues>
            </field>
            <field>
              <name>OVIE</name>
              <description>OVIE  field description</description>
              <bitRange>[0:0]</bitRange>
              <access>read-write</access>
              <enumeratedValues>
                <enumeratedValue>
                  <name />
                  <description>使能</description>
                  <value>1</value>
                </enumeratedValue>
                <enumeratedValue>
                  <name />
                  <description>禁止</description>
                  <value>0</value>
                </enumeratedValue>
              </enumeratedValues>
            </field>
          </fields>
        </register>
        <register>
          <name>ISR</name>
          <description>ET4 Interrupt Status Register</description>
          <addressOffset>0x1c</addressOffset>
          <size>32</size>
          <access>read-write</access>
          <resetValue>0x00000000</resetValue>
          <fields>
            <field>
              <name>CMPIF</name>
              <description>CMPIF  field description</description>
              <bitRange>[3:3]</bitRange>
              <access>read-write</access>
              <enumeratedValues>
                <enumeratedValue>
                  <name />
                  <description>当前计数器的值大于等于比较寄存器的值</description>
                  <value>1</value>
                </enumeratedValue>
                <enumeratedValue>
                  <name />
                  <description>当前计数器的值小于比较寄存器的值</description>
                  <value>0</value>
                </enumeratedValue>
              </enumeratedValues>
            </field>
            <field>
              <name>EDGESTA</name>
              <description>EDGESTA  field description</description>
              <bitRange>[2:2]</bitRange>
              <access>read-write</access>
              <enumeratedValues>
                <enumeratedValue>
                  <name />
                  <description>脉冲宽度捕捉模式时表示捕捉到下沿</description>
                  <value>1</value>
                </enumeratedValue>
                <enumeratedValue>
                  <name />
                  <description>脉冲宽度捕捉模式时表示捕捉到上沿</description>
                  <value>0</value>
                </enumeratedValue>
              </enumeratedValues>
            </field>
            <field>
              <name>CAPIF</name>
              <description>CAPIF  field description</description>
              <bitRange>[1:1]</bitRange>
              <access>read-write</access>
              <enumeratedValues>
                <enumeratedValue>
                  <name />
                  <description>捕捉到指定的沿</description>
                  <value>1</value>
                </enumeratedValue>
                <enumeratedValue>
                  <name />
                  <description>未捕捉到指定的沿</description>
                  <value>0</value>
                </enumeratedValue>
              </enumeratedValues>
            </field>
            <field>
              <name>OVIF</name>
              <description>OVIF  field description</description>
              <bitRange>[0:0]</bitRange>
              <access>read-write</access>
              <enumeratedValues>
                <enumeratedValue>
                  <name />
                  <description>产生计数溢出</description>
                  <value>1</value>
                </enumeratedValue>
                <enumeratedValue>
                  <name />
                  <description>未产生溢出</description>
                  <value>0</value>
                </enumeratedValue>
              </enumeratedValues>
            </field>
          </fields>
        </register>
      </registers>
    </peripheral>
	<peripheral>
            <name>ETCNT</name>
            <description>EXTENDED TIMER COUNTER Registers</description>
            <groupName>ETIMER</groupName>
            <baseAddress>0x40013110</baseAddress>
            <size>32</size>
            <access>read-write</access>
            <addressBlock>
                <offset>0</offset>
                <size>0x020</size>
                <usage>registers</usage>
            </addressBlock>
            <registers>
                <!--ET1CNT: ETIMER1 COUNTER REGISTER-->
                <register>
                    <name>ET1CNT</name>
                    <description>ETIMER1 COUNTER REGISTER</description>
                    <addressOffset>0x00</addressOffset>
                    <size>32</size>
                    <access>read-write</access>
                    <resetValue>0x00000000</resetValue>
                    <fields>
                        <!--ETxCNT-->
                        <field>
                            <name>ETxCNT</name>
                            <description>ETIMER COUNTER</description>
                            <bitRange>[15:0]</bitRange>
                            <access>read-write</access>
                        </field>
                    </fields>
                </register>
                <!--ET2CNT: ETIMER2 COUNTER REGISTER-->
                <register>
                    <name>ET2CNT</name>
                    <description>ETIMER2 COUNTER REGISTER</description>
                    <addressOffset>0x04</addressOffset>
                    <size>32</size>
                    <access>read-write</access>
                    <resetValue>0x00000000</resetValue>
                    <fields>
                        <!--ETxCNT-->
                        <field>
                            <name>ETxCNT</name>
                            <description>ETIMER COUNTER</description>
                            <bitRange>[15:0]</bitRange>
                            <access>read-write</access>
                        </field>
                    </fields>
                </register>
                <!--ET3CNT: ETIMER3 COUNTER REGISTER-->
                <register>
                    <name>ET3CNT</name>
                    <description>ETIMER3 COUNTER REGISTER</description>
                    <addressOffset>0x08</addressOffset>
                    <size>32</size>
                    <access>read-write</access>
                    <resetValue>0x00000000</resetValue>
                    <fields>
                        <!--ETxCNT-->
                        <field>
                            <name>ETxCNT</name>
                            <description>ETIMER COUNTER</description>
                            <bitRange>[15:0]</bitRange>
                            <access>read-write</access>
                        </field>
                    </fields>
                </register>
                <!--ET4CNT: ETIMER4 COUNTER REGISTER-->
                <register>
                    <name>ET4CNT</name>
                    <description>ETIMER4 COUNTER REGISTER</description>
                    <addressOffset>0x0C</addressOffset>
                    <size>32</size>
                    <access>read-write</access>
                    <resetValue>0x00000000</resetValue>
                    <fields>
                        <!--ETxCNT-->
                        <field>
                            <name>ETxCNT</name>
                            <description>ETIMER COUNTER</description>
                            <bitRange>[15:0]</bitRange>
                            <access>read-write</access>
                        </field>
                    </fields>
                </register>
            </registers>
        </peripheral>
    <peripheral>
      <name>BSTIM</name>
      <description>BSTIM module information</description>
      <groupName>BSTIM</groupName>
      <baseAddress>0x40016000</baseAddress>
      <size>32</size>
      <access>read-write</access>
      <addressBlock>
        <offset>0</offset>
        <size>0x30</size>
        <usage>registers</usage>
      </addressBlock>
      <registers>
        <register>
          <name>CR1</name>
          <description>BSTIM Control Register1</description>
          <addressOffset>0x0</addressOffset>
          <size>32</size>
          <access>read-write</access>
          <resetValue>0x00000000</resetValue>
          <fields>
            <field>
              <name>ARPE</name>
              <description>ARPE  field description</description>
              <bitRange>[7:7]</bitRange>
              <access>read-write</access>
              <enumeratedValues>
                <enumeratedValue>
                  <name />
                  <description>ARR寄存器不使能preload</description>
                  <value>0</value>
                </enumeratedValue>
                <enumeratedValue>
                  <name />
                  <description>ARR寄存器使能preload</description>
                  <value>1</value>
                </enumeratedValue>
              </enumeratedValues>
            </field>
            <field>
              <name>OPM</name>
              <description>OPM  field description</description>
              <bitRange>[3:3]</bitRange>
              <access>read-write</access>
              <enumeratedValues>
                <enumeratedValue>
                  <name />
                  <description>Update Event发生时计数器不停止</description>
                  <value>0</value>
                </enumeratedValue>
                <enumeratedValue>
                  <name />
                  <description>Update Event发生时计数器停止（自动清零CEN）</description>
                  <value>1</value>
                </enumeratedValue>
              </enumeratedValues>
            </field>
            <field>
              <name>URS</name>
              <description>URS  field description</description>
              <bitRange>[2:2]</bitRange>
              <access>read-write</access>
              <enumeratedValues>
                <enumeratedValue>
                  <name />
                  <description>以下事件能够产生update中断</description>
                  <value>0</value>
                </enumeratedValue>
                <enumeratedValue>
                  <name />
                  <description>仅计数器上溢出或下溢出会产生update中断或DMA请求</description>
                  <value>1</value>
                </enumeratedValue>
              </enumeratedValues>
            </field>
            <field>
              <name>UDIS</name>
              <description>UDIS  field description</description>
              <bitRange>[1:1]</bitRange>
              <access>read-write</access>
              <enumeratedValues>
                <enumeratedValue>
                  <name />
                  <description>使能update事件；以下事件发生时产生update事件</description>
                  <value>0</value>
                </enumeratedValue>
                <enumeratedValue>
                  <name />
                  <description>禁止update事件，不更新shadow寄存器。当UG置位或从机控制器收到硬件reset时重新初始化计数器和预分频器。</description>
                  <value>1</value>
                </enumeratedValue>
              </enumeratedValues>
            </field>
            <field>
              <name>CEN</name>
              <description>CEN  field description</description>
              <bitRange>[0:0]</bitRange>
              <access>read-write</access>
              <enumeratedValues>
                <enumeratedValue>
                  <name />
                  <description>计数器关闭</description>
                  <value>0</value>
                </enumeratedValue>
                <enumeratedValue>
                  <name />
                  <description>计数器使能</description>
                  <value>1</value>
                </enumeratedValue>
                <enumeratedValue>
                  <name />
                  <description>外部触发模式可以自动置位CEN</description>
                  <value>0</value>
                </enumeratedValue>
              </enumeratedValues>
            </field>
          </fields>
        </register>
        <register>
          <name>CR2</name>
          <description>BSTIM Control Register2</description>
          <addressOffset>0x4</addressOffset>
          <size>32</size>
          <access>read-write</access>
          <resetValue>0x00000000</resetValue>
          <fields>
            <field>
              <name>MMS</name>
              <description>MMS  field description</description>
              <bitRange>[6:4]</bitRange>
              <access>read-write</access>
              <enumeratedValues>
                <enumeratedValue>
                  <name />
                  <description>BSTIM_EGR的UG寄存器被用作TRGO</description>
                  <value>0</value>
                </enumeratedValue>
                <enumeratedValue>
                  <name />
                  <description>计数器使能信号CNT_EN被用作TRGO，可用于同时启动多个定时器</description>
                  <value>1</value>
                </enumeratedValue>
                <enumeratedValue>
                  <name />
                  <description>UE（update event）信号被用作TRGO</description>
                  <value>2</value>
                </enumeratedValue>
                <enumeratedValue>
                  <name />
                  <description>RFU</description>
                  <value>3</value>
                </enumeratedValue>
                <enumeratedValue>
                  <name />
                  <description>RFU</description>
                  <value>4</value>
                </enumeratedValue>
                <enumeratedValue>
                  <name />
                  <description>RFU</description>
                  <value>7</value>
                </enumeratedValue>
                <enumeratedValue>
                  <name />
                  <description>从机定时器或ADC必须事先使能工作时钟，才能接收主机定时器发送的TRGO</description>
                  <value>0</value>
                </enumeratedValue>
              </enumeratedValues>
            </field>
          </fields>
        </register>
        <register>
          <name>IER</name>
          <description>BSTIM Interrupt Enable Register</description>
          <addressOffset>0xc</addressOffset>
          <size>32</size>
          <access>read-write</access>
          <resetValue>0x00000000</resetValue>
          <fields>
            <field>
              <name>UIE</name>
              <description>UIE  field description</description>
              <bitRange>[0:0]</bitRange>
              <access>read-write</access>
              <enumeratedValues>
                <enumeratedValue>
                  <name />
                  <description>禁止Update事件中断</description>
                  <value>0</value>
                </enumeratedValue>
                <enumeratedValue>
                  <name />
                  <description>允许Update事件中断</description>
                  <value>1</value>
                </enumeratedValue>
              </enumeratedValues>
            </field>
          </fields>
        </register>
        <register>
          <name>ISR</name>
          <description>BSTIM Interrupt Status Register</description>
          <addressOffset>0x10</addressOffset>
          <size>32</size>
          <access>read-write</access>
          <resetValue>0x00000000</resetValue>
          <fields>
            <field>
              <name>UIF</name>
              <description>UIF  field description</description>
              <bitRange>[0:0]</bitRange>
              <access>read-write</access>
              <enumeratedValues />
            </field>
          </fields>
        </register>
        <register>
          <name>EGR</name>
          <description>BSTIM Event Generation Register</description>
          <addressOffset>0x14</addressOffset>
          <size>32</size>
          <access>read-write</access>
          <resetValue>0x00000000</resetValue>
          <fields>
            <field>
              <name>UG</name>
              <description>UG  field description</description>
              <bitRange>[0:0]</bitRange>
              <access>write-only</access>
              <enumeratedValues />
            </field>
          </fields>
        </register>
        <register>
          <name>CNTR</name>
          <description>BSTIM Counter Register</description>
          <addressOffset>0x24</addressOffset>
          <size>32</size>
          <access>read-write</access>
          <resetValue>0x00000000</resetValue>
          <fields>
            <field>
              <name>CNT</name>
              <description>CNT  field description</description>
              <bitRange>[31:0]</bitRange>
              <access>read-write</access>
              <enumeratedValues />
            </field>
          </fields>
        </register>
        <register>
          <name>PSCR</name>
          <description>BSTIM Prescaler Register</description>
          <addressOffset>0x28</addressOffset>
          <size>32</size>
          <access>read-write</access>
          <resetValue>0x00000000</resetValue>
          <fields>
            <field>
              <name>PSC</name>
              <description>PSC  field description</description>
              <bitRange>[31:0]</bitRange>
              <access>read-write</access>
              <enumeratedValues />
            </field>
          </fields>
        </register>
        <register>
          <name>ARR</name>
          <description>BSTIM Auto-Reload Register</description>
          <addressOffset>0x2c</addressOffset>
          <size>32</size>
          <access>read-write</access>
          <resetValue>0x00000000</resetValue>
          <fields>
            <field>
              <name>ARR</name>
              <description>ARR  field description</description>
              <bitRange>[31:0]</bitRange>
              <access>read-write</access>
              <enumeratedValues />
            </field>
          </fields>
        </register>
      </registers>
    </peripheral>
    <peripheral>
      <name>LPTIM</name>
      <description>LPTIM module information</description>
      <groupName>LPTIM</groupName>
      <baseAddress>0x40013400</baseAddress>
      <size>32</size>
      <access>read-write</access>
      <addressBlock>
        <offset>0</offset>
        <size>0x30</size>
        <usage>registers</usage>
      </addressBlock>
      <registers>
        <register>
          <name>CFGR</name>
          <description>LPTIM Config Register</description>
          <addressOffset>0x0</addressOffset>
          <size>32</size>
          <access>read-write</access>
          <resetValue>0x00000000</resetValue>
          <fields>
            <field>
              <name>ETR_AFEN</name>
              <description>ETR_AFEN  field description</description>
              <bitRange>[24:24]</bitRange>
              <access>read-write</access>
              <enumeratedValues>
                <enumeratedValue>
                  <name />
                  <description>关闭模拟滤波</description>
                  <value>0</value>
                </enumeratedValue>
                <enumeratedValue>
                  <name />
                  <description>使能模拟滤波，滤波宽度约100ns</description>
                  <value>1</value>
                </enumeratedValue>
              </enumeratedValues>
            </field>
            <field>
              <name>PSCSEL</name>
              <description>PSCSEL  field description</description>
              <bitRange>[14:14]</bitRange>
              <access>read-write</access>
              <enumeratedValues>
                <enumeratedValue>
                  <name />
                  <description>CLKSEL选择的时钟</description>
                  <value>0</value>
                </enumeratedValue>
                <enumeratedValue>
                  <name />
                  <description>LPTETRF</description>
                  <value>1</value>
                </enumeratedValue>
              </enumeratedValues>
            </field>
            <field>
              <name>DIVSEL</name>
              <description>DIVSEL  field description</description>
              <bitRange>[12:10]</bitRange>
              <access>read-write</access>
              <enumeratedValues>
                <enumeratedValue>
                  <name />
                  <description>1分频</description>
                  <value>0</value>
                </enumeratedValue>
                <enumeratedValue>
                  <name />
                  <description>2分频</description>
                  <value>1</value>
                </enumeratedValue>
                <enumeratedValue>
                  <name />
                  <description>4分频</description>
                  <value>2</value>
                </enumeratedValue>
                <enumeratedValue>
                  <name />
                  <description>8分频</description>
                  <value>3</value>
                </enumeratedValue>
                <enumeratedValue>
                  <name />
                  <description>16分频</description>
                  <value>4</value>
                </enumeratedValue>
                <enumeratedValue>
                  <name />
                  <description>32分频</description>
                  <value>5</value>
                </enumeratedValue>
                <enumeratedValue>
                  <name />
                  <description>64分频</description>
                  <value>6</value>
                </enumeratedValue>
                <enumeratedValue>
                  <name />
                  <description>128分频</description>
                  <value>7</value>
                </enumeratedValue>
              </enumeratedValues>
            </field>
            <field>
              <name>EDGESEL</name>
              <description>EDGESEL  field description</description>
              <bitRange>[7:7]</bitRange>
              <access>read-write</access>
              <enumeratedValues>
                <enumeratedValue>
                  <name />
                  <description>LPT_ETR的上升沿计数</description>
                  <value>0</value>
                </enumeratedValue>
                <enumeratedValue>
                  <name />
                  <description>LPT_ETR的下降沿计数</description>
                  <value>1</value>
                </enumeratedValue>
              </enumeratedValues>
            </field>
            <field>
              <name>TRIGCFG</name>
              <description>TRIGCFG  field description</description>
              <bitRange>[6:5]</bitRange>
              <access>read-write</access>
              <enumeratedValues />
            </field>
            <field>
              <name>ONST</name>
              <description>ONST  field description</description>
              <bitRange>[2:2]</bitRange>
              <access>read-write</access>
              <enumeratedValues>
                <enumeratedValue>
                  <name />
                  <description>连续计数模式</description>
                  <value>0</value>
                </enumeratedValue>
                <enumeratedValue>
                  <name />
                  <description>单次计数模式</description>
                  <value>1</value>
                </enumeratedValue>
              </enumeratedValues>
            </field>
            <field>
              <name>TMODE</name>
              <description>TMODE  field description</description>
              <bitRange>[1:0]</bitRange>
              <access>read-write</access>
              <enumeratedValues>
                <enumeratedValue>
                  <name />
                  <description>普通定时器模式</description>
                  <value>0</value>
                </enumeratedValue>
                <enumeratedValue>
                  <name />
                  <description>Trigger脉冲触发计数模式</description>
                  <value>1</value>
                </enumeratedValue>
                <enumeratedValue>
                  <name />
                  <description>外部异步脉冲计数模式</description>
                  <value>2</value>
                </enumeratedValue>
                <enumeratedValue>
                  <name />
                  <description>Timeout模式</description>
                  <value>3</value>
                </enumeratedValue>
              </enumeratedValues>
            </field>
          </fields>
        </register>
        <register>
          <name>CNTR</name>
          <description>LPTIM Counter Register</description>
          <addressOffset>0x4</addressOffset>
          <size>32</size>
          <access>read-write</access>
          <resetValue>0x00000000</resetValue>
          <fields>
            <field>
              <name>CNT32</name>
              <description>CNT32  field description</description>
              <bitRange>[31:0]</bitRange>
              <access>read-only</access>
              <enumeratedValues />
            </field>
          </fields>
        </register>
        <register>
          <name>CCSR</name>
          <description>LPTIM Capture/Compare Control and Status Register</description>
          <addressOffset>0x8</addressOffset>
          <size>32</size>
          <access>read-write</access>
          <resetValue>0x00000000</resetValue>
          <fields>
            <field>
              <name>CAP1SSEL</name>
              <description>CAP1SSEL  field description</description>
              <bitRange>[25:24]</bitRange>
              <access>read-write</access>
              <enumeratedValues>
                <enumeratedValue>
                  <name />
                  <description>LPT_CH1输入</description>
                  <value>0</value>
                </enumeratedValue>
                <enumeratedValue>
                  <name />
                  <description>XTLF</description>
                  <value>1</value>
                </enumeratedValue>
                <enumeratedValue>
                  <name />
                  <description>RCLP</description>
                  <value>2</value>
                </enumeratedValue>
                <enumeratedValue>
                  <name />
                  <description>RCMF</description>
                  <value>3</value>
                </enumeratedValue>
              </enumeratedValues>
            </field>
            <field>
              <name>CAP4EDGE</name>
              <description>CAP4EDGE  field description</description>
              <bitRange>[23:23]</bitRange>
              <access>read-write</access>
              <enumeratedValues>
                <enumeratedValue>
                  <name />
                  <description>上升沿</description>
                  <value>0</value>
                </enumeratedValue>
                <enumeratedValue>
                  <name />
                  <description>下降沿</description>
                  <value>1</value>
                </enumeratedValue>
              </enumeratedValues>
            </field>
            <field>
              <name>CAP3EDGE</name>
              <description>CAP3EDGE  field description</description>
              <bitRange>[22:22]</bitRange>
              <access>read-write</access>
              <enumeratedValues>
                <enumeratedValue>
                  <name />
                  <description>上升沿</description>
                  <value>0</value>
                </enumeratedValue>
                <enumeratedValue>
                  <name />
                  <description>下降沿</description>
                  <value>1</value>
                </enumeratedValue>
              </enumeratedValues>
            </field>
            <field>
              <name>CAP2EDGE</name>
              <description>CAP2EDGE  field description</description>
              <bitRange>[21:21]</bitRange>
              <access>read-write</access>
              <enumeratedValues>
                <enumeratedValue>
                  <name />
                  <description>上升沿</description>
                  <value>0</value>
                </enumeratedValue>
                <enumeratedValue>
                  <name />
                  <description>下降沿</description>
                  <value>1</value>
                </enumeratedValue>
              </enumeratedValues>
            </field>
            <field>
              <name>CAP1EDGE</name>
              <description>CAP1EDGE  field description</description>
              <bitRange>[20:20]</bitRange>
              <access>read-write</access>
              <enumeratedValues>
                <enumeratedValue>
                  <name />
                  <description>上升沿</description>
                  <value>0</value>
                </enumeratedValue>
                <enumeratedValue>
                  <name />
                  <description>下降沿</description>
                  <value>1</value>
                </enumeratedValue>
              </enumeratedValues>
            </field>
            <field>
              <name>POLAR4</name>
              <description>POLAR4  field description</description>
              <bitRange>[19:19]</bitRange>
              <access>read-write</access>
              <enumeratedValues>
                <enumeratedValue>
                  <name />
                  <description>正极性波形，起始为低，计数值==比较值时置高，计数值==ARR时恢复为低</description>
                  <value>0</value>
                </enumeratedValue>
                <enumeratedValue>
                  <name />
                  <description>负极性波形，正极性波形取反</description>
                  <value>1</value>
                </enumeratedValue>
              </enumeratedValues>
            </field>
            <field>
              <name>POLAR3</name>
              <description>POLAR3  field description</description>
              <bitRange>[18:18]</bitRange>
              <access>read-write</access>
              <enumeratedValues>
                <enumeratedValue>
                  <name />
                  <description>正极性波形，起始为低，计数值==比较值时置高，计数值==ARR时恢复为低</description>
                  <value>0</value>
                </enumeratedValue>
                <enumeratedValue>
                  <name />
                  <description>负极性波形，正极性波形取反</description>
                  <value>1</value>
                </enumeratedValue>
              </enumeratedValues>
            </field>
            <field>
              <name>POLAR2</name>
              <description>POLAR2  field description</description>
              <bitRange>[17:17]</bitRange>
              <access>read-write</access>
              <enumeratedValues>
                <enumeratedValue>
                  <name />
                  <description>正极性波形，起始为低，计数值==比较值时置高，计数值==ARR时恢复为低</description>
                  <value>0</value>
                </enumeratedValue>
                <enumeratedValue>
                  <name />
                  <description>负极性波形，正极性波形取反</description>
                  <value>1</value>
                </enumeratedValue>
              </enumeratedValues>
            </field>
            <field>
              <name>POLAR1</name>
              <description>POLAR1  field description</description>
              <bitRange>[16:16]</bitRange>
              <access>read-write</access>
              <enumeratedValues>
                <enumeratedValue>
                  <name />
                  <description>正极性波形，起始为低，计数值==比较值时置高，计数值==ARR时恢复为低</description>
                  <value>0</value>
                </enumeratedValue>
                <enumeratedValue>
                  <name />
                  <description>负极性波形，正极性波形取反</description>
                  <value>1</value>
                </enumeratedValue>
              </enumeratedValues>
            </field>
            <field>
              <name>CAPCFG4</name>
              <description>CAPCFG4  field description</description>
              <bitRange>[15:14]</bitRange>
              <access>read-write</access>
              <enumeratedValues>
                <enumeratedValue>
                  <name />
                  <description>上升沿捕捉</description>
                  <value>0</value>
                </enumeratedValue>
                <enumeratedValue>
                  <name />
                  <description>下降沿捕捉</description>
                  <value>1</value>
                </enumeratedValue>
                <enumeratedValue>
                  <name />
                  <description>上升下降沿捕捉</description>
                  <value>2</value>
                </enumeratedValue>
                <enumeratedValue>
                  <name />
                  <description>RFU</description>
                  <value>3</value>
                </enumeratedValue>
              </enumeratedValues>
            </field>
            <field>
              <name>CAPCFG3</name>
              <description>CAPCFG3  field description</description>
              <bitRange>[13:12]</bitRange>
              <access>read-write</access>
              <enumeratedValues>
                <enumeratedValue>
                  <name />
                  <description>上升沿捕捉</description>
                  <value>0</value>
                </enumeratedValue>
                <enumeratedValue>
                  <name />
                  <description>下降沿捕捉</description>
                  <value>1</value>
                </enumeratedValue>
                <enumeratedValue>
                  <name />
                  <description>上升下降沿捕捉</description>
                  <value>2</value>
                </enumeratedValue>
                <enumeratedValue>
                  <name />
                  <description>RFU</description>
                  <value>3</value>
                </enumeratedValue>
              </enumeratedValues>
            </field>
            <field>
              <name>CAPCFG2</name>
              <description>CAPCFG2  field description</description>
              <bitRange>[11:10]</bitRange>
              <access>read-write</access>
              <enumeratedValues>
                <enumeratedValue>
                  <name />
                  <description>上升沿捕捉</description>
                  <value>0</value>
                </enumeratedValue>
                <enumeratedValue>
                  <name />
                  <description>下降沿捕捉</description>
                  <value>1</value>
                </enumeratedValue>
                <enumeratedValue>
                  <name />
                  <description>上升下降沿捕捉</description>
                  <value>2</value>
                </enumeratedValue>
                <enumeratedValue>
                  <name />
                  <description>RFU</description>
                  <value>3</value>
                </enumeratedValue>
              </enumeratedValues>
            </field>
            <field>
              <name>CAPCFG1</name>
              <description>CAPCFG1  field description</description>
              <bitRange>[9:8]</bitRange>
              <access>read-write</access>
              <enumeratedValues>
                <enumeratedValue>
                  <name />
                  <description>上升沿捕捉</description>
                  <value>0</value>
                </enumeratedValue>
                <enumeratedValue>
                  <name />
                  <description>下降沿捕捉</description>
                  <value>1</value>
                </enumeratedValue>
                <enumeratedValue>
                  <name />
                  <description>上升下降沿捕捉</description>
                  <value>2</value>
                </enumeratedValue>
                <enumeratedValue>
                  <name />
                  <description>RFU</description>
                  <value>3</value>
                </enumeratedValue>
              </enumeratedValues>
            </field>
            <field>
              <name>CC4S</name>
              <description>CC4S  field description</description>
              <bitRange>[7:6]</bitRange>
              <access>read-write</access>
              <enumeratedValues>
                <enumeratedValue>
                  <name />
                  <description>禁止通道4捕捉/比较功能</description>
                  <value>0</value>
                </enumeratedValue>
                <enumeratedValue>
                  <name />
                  <description>使能通道4捕捉功能（LPT32_CH4为输入）</description>
                  <value>1</value>
                </enumeratedValue>
                <enumeratedValue>
                  <name />
                  <description>使能通道4比较功能（LPT32_CH4为输出）</description>
                  <value>2</value>
                </enumeratedValue>
              </enumeratedValues>
            </field>
            <field>
              <name>CC3S</name>
              <description>CC3S  field description</description>
              <bitRange>[5:4]</bitRange>
              <access>read-write</access>
              <enumeratedValues>
                <enumeratedValue>
                  <name />
                  <description>禁止通道3捕捉/比较功能</description>
                  <value>0</value>
                </enumeratedValue>
                <enumeratedValue>
                  <name />
                  <description>使能通道3捕捉功能（LPT32_CH3为输入）</description>
                  <value>1</value>
                </enumeratedValue>
                <enumeratedValue>
                  <name />
                  <description>使能通道3比较功能（LPT32_CH3为输出）</description>
                  <value>2</value>
                </enumeratedValue>
              </enumeratedValues>
            </field>
            <field>
              <name>CC2S</name>
              <description>CC2S  field description</description>
              <bitRange>[3:2]</bitRange>
              <access>read-write</access>
              <enumeratedValues>
                <enumeratedValue>
                  <name />
                  <description>禁止通道2捕捉/比较功能</description>
                  <value>0</value>
                </enumeratedValue>
                <enumeratedValue>
                  <name />
                  <description>使能通道2捕捉功能（LPT32_CH2为输入）</description>
                  <value>1</value>
                </enumeratedValue>
                <enumeratedValue>
                  <name />
                  <description>使能通道2比较功能（LPT32_CH2为输出）</description>
                  <value>2</value>
                </enumeratedValue>
              </enumeratedValues>
            </field>
            <field>
              <name>CC1S</name>
              <description>CC1S  field description</description>
              <bitRange>[1:0]</bitRange>
              <access>read-write</access>
              <enumeratedValues>
                <enumeratedValue>
                  <name />
                  <description>禁止通道1捕捉/比较功能</description>
                  <value>0</value>
                </enumeratedValue>
                <enumeratedValue>
                  <name />
                  <description>使能通道1捕捉功能（LPT32_CH1为输入）</description>
                  <value>1</value>
                </enumeratedValue>
                <enumeratedValue>
                  <name />
                  <description>使能通道1比较功能（LPT32_CH1为输出）</description>
                  <value>2</value>
                </enumeratedValue>
              </enumeratedValues>
            </field>
          </fields>
        </register>
        <register>
          <name>ARR</name>
          <description>LPTIM Auto-Reload Register</description>
          <addressOffset>0xc</addressOffset>
          <size>32</size>
          <access>read-write</access>
          <resetValue>0x00000000</resetValue>
          <fields>
            <field>
              <name>ARR</name>
              <description>ARR  field description</description>
              <bitRange>[31:0]</bitRange>
              <access>read-write</access>
              <enumeratedValues />
            </field>
          </fields>
        </register>
        <register>
          <name>IER</name>
          <description>LPTIM Interrupt Enable Register</description>
          <addressOffset>0x10</addressOffset>
          <size>32</size>
          <access>read-write</access>
          <resetValue>0x00000000</resetValue>
          <fields>
            <field>
              <name>OVR4IE</name>
              <description>OVR4IE  field description</description>
              <bitRange>[11:11]</bitRange>
              <access>read-write</access>
              <enumeratedValues>
                <enumeratedValue>
                  <name />
                  <description>允许中断</description>
                  <value>1</value>
                </enumeratedValue>
                <enumeratedValue>
                  <name />
                  <description>禁止中断</description>
                  <value>0</value>
                </enumeratedValue>
              </enumeratedValues>
            </field>
            <field>
              <name>OVR3IE</name>
              <description>OVR3IE  field description</description>
              <bitRange>[10:10]</bitRange>
              <access>read-write</access>
              <enumeratedValues>
                <enumeratedValue>
                  <name />
                  <description>允许中断</description>
                  <value>1</value>
                </enumeratedValue>
                <enumeratedValue>
                  <name />
                  <description>禁止中断</description>
                  <value>0</value>
                </enumeratedValue>
              </enumeratedValues>
            </field>
            <field>
              <name>OVR2IE</name>
              <description>OVR2IE  field description</description>
              <bitRange>[9:9]</bitRange>
              <access>read-write</access>
              <enumeratedValues>
                <enumeratedValue>
                  <name />
                  <description>允许中断</description>
                  <value>1</value>
                </enumeratedValue>
                <enumeratedValue>
                  <name />
                  <description>禁止中断</description>
                  <value>0</value>
                </enumeratedValue>
              </enumeratedValues>
            </field>
            <field>
              <name>OVR1IE</name>
              <description>OVR1IE  field description</description>
              <bitRange>[8:8]</bitRange>
              <access>read-write</access>
              <enumeratedValues>
                <enumeratedValue>
                  <name />
                  <description>允许中断</description>
                  <value>1</value>
                </enumeratedValue>
                <enumeratedValue>
                  <name />
                  <description>禁止中断</description>
                  <value>0</value>
                </enumeratedValue>
              </enumeratedValues>
            </field>
            <field>
              <name>TRIGIE</name>
              <description>TRIGIE  field description</description>
              <bitRange>[7:7]</bitRange>
              <access>read-write</access>
              <enumeratedValues>
                <enumeratedValue>
                  <name />
                  <description>外部触发到来中断使能</description>
                  <value>1</value>
                </enumeratedValue>
                <enumeratedValue>
                  <name />
                  <description>外部触发到来中断禁止</description>
                  <value>0</value>
                </enumeratedValue>
              </enumeratedValues>
            </field>
            <field>
              <name>OVIE</name>
              <description>OVIE  field description</description>
              <bitRange>[6:6]</bitRange>
              <access>read-write</access>
              <enumeratedValues>
                <enumeratedValue>
                  <name />
                  <description>计数器溢出中断使能</description>
                  <value>1</value>
                </enumeratedValue>
                <enumeratedValue>
                  <name />
                  <description>计数器溢出中断禁止</description>
                  <value>0</value>
                </enumeratedValue>
              </enumeratedValues>
            </field>
            <field>
              <name>CC4IE</name>
              <description>CC4IE  field description</description>
              <bitRange>[3:3]</bitRange>
              <access>read-write</access>
              <enumeratedValues>
                <enumeratedValue>
                  <name />
                  <description>捕捉/比较通道2中断使能</description>
                  <value>1</value>
                </enumeratedValue>
                <enumeratedValue>
                  <name />
                  <description>捕捉/比较通道2中断禁止</description>
                  <value>0</value>
                </enumeratedValue>
              </enumeratedValues>
            </field>
            <field>
              <name>CC3IE</name>
              <description>CC3IE  field description</description>
              <bitRange>[2:2]</bitRange>
              <access>read-write</access>
              <enumeratedValues>
                <enumeratedValue>
                  <name />
                  <description>捕捉/比较通道1中断使能</description>
                  <value>1</value>
                </enumeratedValue>
                <enumeratedValue>
                  <name />
                  <description>捕捉/比较通道1中断禁止</description>
                  <value>0</value>
                </enumeratedValue>
              </enumeratedValues>
            </field>
            <field>
              <name>CC2IE</name>
              <description>CC2IE  field description</description>
              <bitRange>[1:1]</bitRange>
              <access>read-write</access>
              <enumeratedValues>
                <enumeratedValue>
                  <name />
                  <description>捕捉/比较通道2中断使能</description>
                  <value>1</value>
                </enumeratedValue>
                <enumeratedValue>
                  <name />
                  <description>捕捉/比较通道2中断禁止</description>
                  <value>0</value>
                </enumeratedValue>
              </enumeratedValues>
            </field>
            <field>
              <name>CC1IE</name>
              <description>CC1IE  field description</description>
              <bitRange>[0:0]</bitRange>
              <access>read-write</access>
              <enumeratedValues>
                <enumeratedValue>
                  <name />
                  <description>捕捉/比较通道1中断使能</description>
                  <value>1</value>
                </enumeratedValue>
                <enumeratedValue>
                  <name />
                  <description>捕捉/比较通道1中断禁止</description>
                  <value>0</value>
                </enumeratedValue>
              </enumeratedValues>
            </field>
          </fields>
        </register>
        <register>
          <name>ISR</name>
          <description>LPTIM Interrupt Status Register</description>
          <addressOffset>0x14</addressOffset>
          <size>32</size>
          <access>read-write</access>
          <resetValue>0x00000000</resetValue>
          <fields>
            <field>
              <name>CAP4OVR</name>
              <description>CAP4OVR  field description</description>
              <bitRange>[11:11]</bitRange>
              <access>read-write</access>
              <enumeratedValues>
                <enumeratedValue>
                  <name />
                  <description>输入捕捉模式下，CC4IF为1时出现新的捕捉，发生overrun</description>
                  <value>1</value>
                </enumeratedValue>
                <enumeratedValue>
                  <name />
                  <description>没有发生overrun</description>
                  <value>0</value>
                </enumeratedValue>
              </enumeratedValues>
            </field>
            <field>
              <name>CAP3OVR</name>
              <description>CAP3OVR  field description</description>
              <bitRange>[10:10]</bitRange>
              <access>read-write</access>
              <enumeratedValues>
                <enumeratedValue>
                  <name />
                  <description>输入捕捉模式下，CC3IF为1时出现新的捕捉，发生overrun</description>
                  <value>1</value>
                </enumeratedValue>
                <enumeratedValue>
                  <name />
                  <description>没有发生overrun</description>
                  <value>0</value>
                </enumeratedValue>
              </enumeratedValues>
            </field>
            <field>
              <name>CAP2OVR</name>
              <description>CAP2OVR  field description</description>
              <bitRange>[9:9]</bitRange>
              <access>read-write</access>
              <enumeratedValues>
                <enumeratedValue>
                  <name />
                  <description>输入捕捉模式下，CC2IF为1时出现新的捕捉，发生overrun</description>
                  <value>1</value>
                </enumeratedValue>
                <enumeratedValue>
                  <name />
                  <description>没有发生overrun</description>
                  <value>0</value>
                </enumeratedValue>
              </enumeratedValues>
            </field>
            <field>
              <name>CAP1OVR</name>
              <description>CAP1OVR  field description</description>
              <bitRange>[8:8]</bitRange>
              <access>read-write</access>
              <enumeratedValues>
                <enumeratedValue>
                  <name />
                  <description>输入捕捉模式下，CC1IF为1时出现新的捕捉，发生overrun</description>
                  <value>1</value>
                </enumeratedValue>
                <enumeratedValue>
                  <name />
                  <description>没有发生overrun</description>
                  <value>0</value>
                </enumeratedValue>
              </enumeratedValues>
            </field>
            <field>
              <name>TRIGIF</name>
              <description>TRIGIF  field description</description>
              <bitRange>[7:7]</bitRange>
              <access>read-write</access>
              <enumeratedValues>
                <enumeratedValue>
                  <name />
                  <description>外部触发到来中断产生</description>
                  <value>1</value>
                </enumeratedValue>
                <enumeratedValue>
                  <name />
                  <description>无中断产生</description>
                  <value>0</value>
                </enumeratedValue>
              </enumeratedValues>
            </field>
            <field>
              <name>OVIF</name>
              <description>OVIF  field description</description>
              <bitRange>[6:6]</bitRange>
              <access>read-write</access>
              <enumeratedValues>
                <enumeratedValue>
                  <name />
                  <description>计数器溢出中断产生</description>
                  <value>1</value>
                </enumeratedValue>
                <enumeratedValue>
                  <name />
                  <description>无中断产生</description>
                  <value>0</value>
                </enumeratedValue>
              </enumeratedValues>
            </field>
            <field>
              <name>CC4IF</name>
              <description>CC4IF  field description</description>
              <bitRange>[3:3]</bitRange>
              <access>read-write</access>
              <enumeratedValues>
                <enumeratedValue>
                  <name />
                  <description>计数器值和比较值4匹配，或者发生捕捉事件</description>
                  <value>1</value>
                </enumeratedValue>
                <enumeratedValue>
                  <name />
                  <description>无中断产生</description>
                  <value>0</value>
                </enumeratedValue>
              </enumeratedValues>
            </field>
            <field>
              <name>CC3IF</name>
              <description>CC3IF  field description</description>
              <bitRange>[2:2]</bitRange>
              <access>read-write</access>
              <enumeratedValues>
                <enumeratedValue>
                  <name />
                  <description>计数器值和比较值3匹配，或者发生捕捉事件</description>
                  <value>1</value>
                </enumeratedValue>
                <enumeratedValue>
                  <name />
                  <description>无中断产生</description>
                  <value>0</value>
                </enumeratedValue>
              </enumeratedValues>
            </field>
            <field>
              <name>CC2IF</name>
              <description>CC2IF  field description</description>
              <bitRange>[1:1]</bitRange>
              <access>read-write</access>
              <enumeratedValues>
                <enumeratedValue>
                  <name />
                  <description>计数器值和比较值2匹配，或者发生捕捉事件</description>
                  <value>1</value>
                </enumeratedValue>
                <enumeratedValue>
                  <name />
                  <description>无中断产生</description>
                  <value>0</value>
                </enumeratedValue>
              </enumeratedValues>
            </field>
            <field>
              <name>CC1IF</name>
              <description>CC1IF  field description</description>
              <bitRange>[0:0]</bitRange>
              <access>read-write</access>
              <enumeratedValues>
                <enumeratedValue>
                  <name />
                  <description>计数器值和比较值1匹配，或者发生捕捉事件</description>
                  <value>1</value>
                </enumeratedValue>
                <enumeratedValue>
                  <name />
                  <description>无中断产生</description>
                  <value>0</value>
                </enumeratedValue>
              </enumeratedValues>
            </field>
          </fields>
        </register>
        <register>
          <name>CR</name>
          <description>LPTIM Control Register</description>
          <addressOffset>0x18</addressOffset>
          <size>32</size>
          <access>read-write</access>
          <resetValue>0x00000000</resetValue>
          <fields>
            <field>
              <name>EN</name>
              <description>EN  field description</description>
              <bitRange>[0:0]</bitRange>
              <access>read-write</access>
              <enumeratedValues>
                <enumeratedValue>
                  <name />
                  <description>使能计数器计数</description>
                  <value>1</value>
                </enumeratedValue>
                <enumeratedValue>
                  <name />
                  <description>禁止计数器计数</description>
                  <value>0</value>
                </enumeratedValue>
              </enumeratedValues>
            </field>
          </fields>
        </register>
        <register>
          <name>CCR1</name>
          <description>LPTIM Capture/Compare Register1</description>
          <addressOffset>0x20</addressOffset>
          <size>32</size>
          <access>read-write</access>
          <resetValue>0x00000000</resetValue>
          <fields>
            <field>
              <name>CCR1</name>
              <description>CCR1  field description</description>
              <bitRange>[31:0]</bitRange>
              <access>read-write</access>
              <enumeratedValues />
            </field>
          </fields>
        </register>
        <register>
          <name>CCR2</name>
          <description>LPTIM Capture/Compare Register2</description>
          <addressOffset>0x24</addressOffset>
          <size>32</size>
          <access>read-write</access>
          <resetValue>0x00000000</resetValue>
          <fields>
            <field>
              <name>CCR2</name>
              <description>CCR2  field description</description>
              <bitRange>[31:0]</bitRange>
              <access>read-write</access>
              <enumeratedValues />
            </field>
          </fields>
        </register>
        <register>
          <name>CCR3</name>
          <description>LPTIM Capture/Compare Register3</description>
          <addressOffset>0x28</addressOffset>
          <size>32</size>
          <access>read-write</access>
          <resetValue>0x00000000</resetValue>
          <fields>
            <field>
              <name>CCR3</name>
              <description>CCR3  field description</description>
              <bitRange>[31:0]</bitRange>
              <access>read-write</access>
              <enumeratedValues />
            </field>
          </fields>
        </register>
        <register>
          <name>CCR4</name>
          <description>LPTIM Capture/Compare Register4</description>
          <addressOffset>0x2c</addressOffset>
          <size>32</size>
          <access>read-write</access>
          <resetValue>0x00000000</resetValue>
          <fields>
            <field>
              <name>CCR4</name>
              <description>CCR4  field description</description>
              <bitRange>[31:0]</bitRange>
              <access>read-write</access>
              <enumeratedValues />
            </field>
          </fields>
        </register>
      </registers>
    </peripheral>
    <peripheral>
      <name>RTC</name>
      <description>RTC module information</description>
      <groupName>RTC</groupName>
      <baseAddress>0x40011000</baseAddress>
      <size>32</size>
      <access>read-write</access>
      <addressBlock>
        <offset>0</offset>
        <size>0x80</size>
        <usage>registers</usage>
      </addressBlock>
      <registers>
        <register>
          <name>WER</name>
          <description>RTC Write Enable Register</description>
          <addressOffset>0x0</addressOffset>
          <size>32</size>
          <access>read-write</access>
          <resetValue>0x00000000</resetValue>
          <fields>
            <field>
              <name>RTCWE</name>
              <description>RTCWE  field description</description>
              <bitRange>[0:0]</bitRange>
              <access>read-write</access>
              <enumeratedValues />
            </field>
          </fields>
        </register>
        <register>
          <name>IER</name>
          <description>RTC Interrupt Enable Register</description>
          <addressOffset>0x4</addressOffset>
          <size>32</size>
          <access>read-write</access>
          <resetValue>0x00000000</resetValue>
          <fields>
            <field>
              <name>ADJ_IE</name>
              <description>ADJ_IE  field description</description>
              <bitRange>[12:12]</bitRange>
              <access>read-write</access>
              <enumeratedValues>
                <enumeratedValue>
                  <name />
                  <description>中断使能打开</description>
                  <value>1</value>
                </enumeratedValue>
                <enumeratedValue>
                  <name />
                  <description>中断使能禁止</description>
                  <value>0</value>
                </enumeratedValue>
              </enumeratedValues>
            </field>
            <field>
              <name>ALARM_IE</name>
              <description>ALARM_IE  field description</description>
              <bitRange>[11:11]</bitRange>
              <access>read-write</access>
              <enumeratedValues>
                <enumeratedValue>
                  <name />
                  <description>中断使能打开</description>
                  <value>1</value>
                </enumeratedValue>
                <enumeratedValue>
                  <name />
                  <description>中断使能禁止</description>
                  <value>0</value>
                </enumeratedValue>
              </enumeratedValues>
            </field>
            <field>
              <name>1KHZ_IE</name>
              <description>1KHZ_IE  field description</description>
              <bitRange>[10:10]</bitRange>
              <access>read-write</access>
              <enumeratedValues>
                <enumeratedValue>
                  <name />
                  <description>中断使能打开</description>
                  <value>1</value>
                </enumeratedValue>
                <enumeratedValue>
                  <name />
                  <description>中断使能禁止</description>
                  <value>0</value>
                </enumeratedValue>
              </enumeratedValues>
            </field>
            <field>
              <name>256HZ_IE</name>
              <description>256HZ_IE  field description</description>
              <bitRange>[9:9]</bitRange>
              <access>read-write</access>
              <enumeratedValues>
                <enumeratedValue>
                  <name />
                  <description>中断使能打开</description>
                  <value>1</value>
                </enumeratedValue>
                <enumeratedValue>
                  <name />
                  <description>中断使能禁止</description>
                  <value>0</value>
                </enumeratedValue>
              </enumeratedValues>
            </field>
            <field>
              <name>64HZ_IE</name>
              <description>64HZ_IE  field description</description>
              <bitRange>[8:8]</bitRange>
              <access>read-write</access>
              <enumeratedValues>
                <enumeratedValue>
                  <name />
                  <description>中断使能打开</description>
                  <value>1</value>
                </enumeratedValue>
                <enumeratedValue>
                  <name />
                  <description>中断使能禁止</description>
                  <value>0</value>
                </enumeratedValue>
              </enumeratedValues>
            </field>
            <field>
              <name>16HZ_IE</name>
              <description>16HZ_IE  field description</description>
              <bitRange>[7:7]</bitRange>
              <access>read-write</access>
              <enumeratedValues>
                <enumeratedValue>
                  <name />
                  <description>中断使能打开</description>
                  <value>1</value>
                </enumeratedValue>
                <enumeratedValue>
                  <name />
                  <description>中断使能禁止</description>
                  <value>0</value>
                </enumeratedValue>
              </enumeratedValues>
            </field>
            <field>
              <name>8HZ_IE</name>
              <description>8HZ_IE  field description</description>
              <bitRange>[6:6]</bitRange>
              <access>read-write</access>
              <enumeratedValues>
                <enumeratedValue>
                  <name />
                  <description>中断使能打开</description>
                  <value>1</value>
                </enumeratedValue>
                <enumeratedValue>
                  <name />
                  <description>中断使能禁止</description>
                  <value>0</value>
                </enumeratedValue>
              </enumeratedValues>
            </field>
            <field>
              <name>4HZ_IE</name>
              <description>4HZ_IE  field description</description>
              <bitRange>[5:5]</bitRange>
              <access>read-write</access>
              <enumeratedValues>
                <enumeratedValue>
                  <name />
                  <description>中断使能打开</description>
                  <value>1</value>
                </enumeratedValue>
                <enumeratedValue>
                  <name />
                  <description>中断使能禁止</description>
                  <value>0</value>
                </enumeratedValue>
              </enumeratedValues>
            </field>
            <field>
              <name>2HZ_IE</name>
              <description>2HZ_IE  field description</description>
              <bitRange>[4:4]</bitRange>
              <access>read-write</access>
              <enumeratedValues>
                <enumeratedValue>
                  <name />
                  <description>中断使能打开</description>
                  <value>1</value>
                </enumeratedValue>
                <enumeratedValue>
                  <name />
                  <description>中断使能禁止</description>
                  <value>0</value>
                </enumeratedValue>
              </enumeratedValues>
            </field>
            <field>
              <name>SEC_IE</name>
              <description>SEC_IE  field description</description>
              <bitRange>[3:3]</bitRange>
              <access>read-write</access>
              <enumeratedValues>
                <enumeratedValue>
                  <name />
                  <description>中断使能打开</description>
                  <value>1</value>
                </enumeratedValue>
                <enumeratedValue>
                  <name />
                  <description>中断使能禁止</description>
                  <value>0</value>
                </enumeratedValue>
              </enumeratedValues>
            </field>
            <field>
              <name>MIN_IE</name>
              <description>MIN_IE  field description</description>
              <bitRange>[2:2]</bitRange>
              <access>read-write</access>
              <enumeratedValues>
                <enumeratedValue>
                  <name />
                  <description>中断使能打开</description>
                  <value>1</value>
                </enumeratedValue>
                <enumeratedValue>
                  <name />
                  <description>中断使能禁止</description>
                  <value>0</value>
                </enumeratedValue>
              </enumeratedValues>
            </field>
            <field>
              <name>HOUR_IE</name>
              <description>HOUR_IE  field description</description>
              <bitRange>[1:1]</bitRange>
              <access>read-write</access>
              <enumeratedValues>
                <enumeratedValue>
                  <name />
                  <description>中断使能打开</description>
                  <value>1</value>
                </enumeratedValue>
                <enumeratedValue>
                  <name />
                  <description>中断使能禁止</description>
                  <value>0</value>
                </enumeratedValue>
              </enumeratedValues>
            </field>
            <field>
              <name>DATE_IE</name>
              <description>DATE_IE  field description</description>
              <bitRange>[0:0]</bitRange>
              <access>read-write</access>
              <enumeratedValues>
                <enumeratedValue>
                  <name />
                  <description>中断使能打开</description>
                  <value>1</value>
                </enumeratedValue>
                <enumeratedValue>
                  <name />
                  <description>中断使能禁止</description>
                  <value>0</value>
                </enumeratedValue>
              </enumeratedValues>
            </field>
          </fields>
        </register>
        <register>
          <name>ISR</name>
          <description>RTC Interrupt Status Register</description>
          <addressOffset>0x8</addressOffset>
          <size>32</size>
          <access>read-write</access>
          <resetValue>0x00000000</resetValue>
          <fields>
            <field>
              <name>ADJ_IF</name>
              <description>ADJ_IF  field description</description>
              <bitRange>[12:12]</bitRange>
              <access>read-write</access>
              <enumeratedValues>
                <enumeratedValue>
                  <name />
                  <description>中断置位</description>
                  <value>1</value>
                </enumeratedValue>
                <enumeratedValue>
                  <name />
                  <description>无中断产生</description>
                  <value>0</value>
                </enumeratedValue>
              </enumeratedValues>
            </field>
            <field>
              <name>ALARM_IF</name>
              <description>ALARM_IF  field description</description>
              <bitRange>[11:11]</bitRange>
              <access>read-write</access>
              <enumeratedValues>
                <enumeratedValue>
                  <name />
                  <description>中断置位</description>
                  <value>1</value>
                </enumeratedValue>
                <enumeratedValue>
                  <name />
                  <description>无中断产生</description>
                  <value>0</value>
                </enumeratedValue>
              </enumeratedValues>
            </field>
            <field>
              <name>1KHZ_IF</name>
              <description>1KHZ_IF  field description</description>
              <bitRange>[10:10]</bitRange>
              <access>read-write</access>
              <enumeratedValues>
                <enumeratedValue>
                  <name />
                  <description>中断置位</description>
                  <value>1</value>
                </enumeratedValue>
                <enumeratedValue>
                  <name />
                  <description>无中断产生</description>
                  <value>0</value>
                </enumeratedValue>
              </enumeratedValues>
            </field>
            <field>
              <name>256HZ_IF</name>
              <description>256HZ_IF  field description</description>
              <bitRange>[9:9]</bitRange>
              <access>read-write</access>
              <enumeratedValues>
                <enumeratedValue>
                  <name />
                  <description>中断置位</description>
                  <value>1</value>
                </enumeratedValue>
                <enumeratedValue>
                  <name />
                  <description>无中断产生</description>
                  <value>0</value>
                </enumeratedValue>
              </enumeratedValues>
            </field>
            <field>
              <name>64HZ_IF</name>
              <description>64HZ_IF  field description</description>
              <bitRange>[8:8]</bitRange>
              <access>read-write</access>
              <enumeratedValues>
                <enumeratedValue>
                  <name />
                  <description>中断置位</description>
                  <value>1</value>
                </enumeratedValue>
                <enumeratedValue>
                  <name />
                  <description>无中断产生</description>
                  <value>0</value>
                </enumeratedValue>
              </enumeratedValues>
            </field>
            <field>
              <name>16HZ_IF</name>
              <description>16HZ_IF  field description</description>
              <bitRange>[7:7]</bitRange>
              <access>read-write</access>
              <enumeratedValues>
                <enumeratedValue>
                  <name />
                  <description>中断置位</description>
                  <value>1</value>
                </enumeratedValue>
                <enumeratedValue>
                  <name />
                  <description>无中断产生</description>
                  <value>0</value>
                </enumeratedValue>
              </enumeratedValues>
            </field>
            <field>
              <name>8HZ_IF</name>
              <description>8HZ_IF  field description</description>
              <bitRange>[6:6]</bitRange>
              <access>read-write</access>
              <enumeratedValues>
                <enumeratedValue>
                  <name />
                  <description>中断置位</description>
                  <value>1</value>
                </enumeratedValue>
                <enumeratedValue>
                  <name />
                  <description>无中断产生</description>
                  <value>0</value>
                </enumeratedValue>
              </enumeratedValues>
            </field>
            <field>
              <name>4HZ_IF</name>
              <description>4HZ_IF  field description</description>
              <bitRange>[5:5]</bitRange>
              <access>read-write</access>
              <enumeratedValues>
                <enumeratedValue>
                  <name />
                  <description>中断置位</description>
                  <value>1</value>
                </enumeratedValue>
                <enumeratedValue>
                  <name />
                  <description>无中断产生</description>
                  <value>0</value>
                </enumeratedValue>
              </enumeratedValues>
            </field>
            <field>
              <name>2HZ_IF</name>
              <description>2HZ_IF  field description</description>
              <bitRange>[4:4]</bitRange>
              <access>read-write</access>
              <enumeratedValues>
                <enumeratedValue>
                  <name />
                  <description>中断置位</description>
                  <value>1</value>
                </enumeratedValue>
                <enumeratedValue>
                  <name />
                  <description>无中断产生</description>
                  <value>0</value>
                </enumeratedValue>
              </enumeratedValues>
            </field>
            <field>
              <name>SEC_IF</name>
              <description>SEC_IF  field description</description>
              <bitRange>[3:3]</bitRange>
              <access>read-write</access>
              <enumeratedValues>
                <enumeratedValue>
                  <name />
                  <description>中断置位</description>
                  <value>1</value>
                </enumeratedValue>
                <enumeratedValue>
                  <name />
                  <description>无中断产生</description>
                  <value>0</value>
                </enumeratedValue>
              </enumeratedValues>
            </field>
            <field>
              <name>MIN_IF</name>
              <description>MIN_IF  field description</description>
              <bitRange>[2:2]</bitRange>
              <access>read-write</access>
              <enumeratedValues>
                <enumeratedValue>
                  <name />
                  <description>中断置位</description>
                  <value>1</value>
                </enumeratedValue>
                <enumeratedValue>
                  <name />
                  <description>无中断产生</description>
                  <value>0</value>
                </enumeratedValue>
              </enumeratedValues>
            </field>
            <field>
              <name>HOUR_IF</name>
              <description>HOUR_IF  field description</description>
              <bitRange>[1:1]</bitRange>
              <access>read-write</access>
              <enumeratedValues>
                <enumeratedValue>
                  <name />
                  <description>中断置位</description>
                  <value>1</value>
                </enumeratedValue>
                <enumeratedValue>
                  <name />
                  <description>无中断产生</description>
                  <value>0</value>
                </enumeratedValue>
              </enumeratedValues>
            </field>
            <field>
              <name>DATE_IF</name>
              <description>DATE_IF  field description</description>
              <bitRange>[0:0]</bitRange>
              <access>read-write</access>
              <enumeratedValues>
                <enumeratedValue>
                  <name />
                  <description>中断置位</description>
                  <value>1</value>
                </enumeratedValue>
                <enumeratedValue>
                  <name />
                  <description>无中断产生</description>
                  <value>0</value>
                </enumeratedValue>
              </enumeratedValues>
            </field>
          </fields>
        </register>
        <register>
          <name>BCDSEC</name>
          <description>RTC BCD Second register</description>
          <addressOffset>0xc</addressOffset>
          <size>32</size>
          <access>read-write</access>
          <resetValue>0x00000000</resetValue>
          <fields>
            <field>
              <name>BCDSEC</name>
              <description>BCDSEC  field description</description>
              <bitRange>[6:0]</bitRange>
              <access>read-write</access>
              <enumeratedValues />
            </field>
          </fields>
        </register>
        <register>
          <name>BCDMIN</name>
          <description>RTC BCD Minute register</description>
          <addressOffset>0x10</addressOffset>
          <size>32</size>
          <access>read-write</access>
          <resetValue>0x00000000</resetValue>
          <fields>
            <field>
              <name>BCDMIN</name>
              <description>BCDMIN  field description</description>
              <bitRange>[6:0]</bitRange>
              <access>read-write</access>
              <enumeratedValues />
            </field>
          </fields>
        </register>
        <register>
          <name>BCDHOUR</name>
          <description>RTC BCD Hour register</description>
          <addressOffset>0x14</addressOffset>
          <size>32</size>
          <access>read-write</access>
          <resetValue>0x00000000</resetValue>
          <fields>
            <field>
              <name>BCDHOUR</name>
              <description>BCDHOUR  field description</description>
              <bitRange>[5:0]</bitRange>
              <access>read-write</access>
              <enumeratedValues />
            </field>
          </fields>
        </register>
        <register>
          <name>BCDDATE</name>
          <description>RTC BCD Date register</description>
          <addressOffset>0x18</addressOffset>
          <size>32</size>
          <access>read-write</access>
          <resetValue>0x00000000</resetValue>
          <fields>
            <field>
              <name>BCDDATE</name>
              <description>BCDDATE  field description</description>
              <bitRange>[5:0]</bitRange>
              <access>read-write</access>
              <enumeratedValues />
            </field>
          </fields>
        </register>
        <register>
          <name>BCDWEEK</name>
          <description>RTC BCD Week register</description>
          <addressOffset>0x1c</addressOffset>
          <size>32</size>
          <access>read-write</access>
          <resetValue>0x00000000</resetValue>
          <fields>
            <field>
              <name>BCDWEEK</name>
              <description>BCDWEEK  field description</description>
              <bitRange>[2:0]</bitRange>
              <access>read-write</access>
              <enumeratedValues />
            </field>
          </fields>
        </register>
        <register>
          <name>BCDMONTH</name>
          <description>RTC BCD Month register</description>
          <addressOffset>0x20</addressOffset>
          <size>32</size>
          <access>read-write</access>
          <resetValue>0x00000000</resetValue>
          <fields>
            <field>
              <name>BCDMONTH</name>
              <description>BCDMONTH  field description</description>
              <bitRange>[4:0]</bitRange>
              <access>read-write</access>
              <enumeratedValues />
            </field>
          </fields>
        </register>
        <register>
          <name>BCDYEAR</name>
          <description>RTC BCD Year register</description>
          <addressOffset>0x24</addressOffset>
          <size>32</size>
          <access>read-write</access>
          <resetValue>0x00000000</resetValue>
          <fields>
            <field>
              <name>BCDYEAR</name>
              <description>BCDYEAR  field description</description>
              <bitRange>[7:0]</bitRange>
              <access>read-write</access>
              <enumeratedValues />
            </field>
          </fields>
        </register>
        <register>
          <name>ALARM</name>
          <description>RTC Alarm Register</description>
          <addressOffset>0x28</addressOffset>
          <size>32</size>
          <access>read-write</access>
          <resetValue>0x00000000</resetValue>
          <fields>
            <field>
              <name>ALMEN</name>
              <description>ALMEN  field description</description>
              <bitRange>[31:31]</bitRange>
              <access>read-write</access>
              <enumeratedValues>
                <enumeratedValue>
                  <name />
                  <description>使能Alarm功能</description>
                  <value>1</value>
                </enumeratedValue>
                <enumeratedValue>
                  <name />
                  <description>禁止Alarm功能</description>
                  <value>0</value>
                </enumeratedValue>
              </enumeratedValues>
            </field>
            <field>
              <name>ALARMHOUR</name>
              <description>ALARMHOUR  field description</description>
              <bitRange>[21:16]</bitRange>
              <access>read-write</access>
              <enumeratedValues />
            </field>
            <field>
              <name>ALARMMIN</name>
              <description>ALARMMIN  field description</description>
              <bitRange>[14:8]</bitRange>
              <access>read-write</access>
              <enumeratedValues />
            </field>
            <field>
              <name>ALARMSEC</name>
              <description>ALARMSEC  field description</description>
              <bitRange>[6:0]</bitRange>
              <access>read-write</access>
              <enumeratedValues />
            </field>
          </fields>
        </register>
        <register>
          <name>TMSEL</name>
          <description>RTC Time Mark Select</description>
          <addressOffset>0x2c</addressOffset>
          <size>32</size>
          <access>read-write</access>
          <resetValue>0x00000000</resetValue>
          <fields>
            <field>
              <name>FSEL</name>
              <description>FSEL  field description</description>
              <bitRange>[3:0]</bitRange>
              <access>read-write</access>
              <enumeratedValues>
                <enumeratedValue>
                  <name />
                  <description />
                  <value>0</value>
                </enumeratedValue>
                <enumeratedValue>
                  <name />
                  <description>输出PLL分频得到的精确1秒方波</description>
                  <value>0</value>
                </enumeratedValue>
                <enumeratedValue>
                  <name />
                  <description>输出PLL分频的可变占空比的精确秒时标</description>
                  <value>1</value>
                </enumeratedValue>
                <enumeratedValue>
                  <name />
                  <description>输出秒计数器进位信号，高电平宽度1s</description>
                  <value>2</value>
                </enumeratedValue>
                <enumeratedValue>
                  <name />
                  <description>输出分计数器进位信号，高电平宽度1s</description>
                  <value>3</value>
                </enumeratedValue>
                <enumeratedValue>
                  <name />
                  <description>输出小时计数器进位信号，高电平宽度1s</description>
                  <value>4</value>
                </enumeratedValue>
                <enumeratedValue>
                  <name />
                  <description>输出天计数器进位信号，高电平宽度1s</description>
                  <value>5</value>
                </enumeratedValue>
                <enumeratedValue>
                  <name />
                  <description>输出闹钟匹配信号</description>
                  <value>6</value>
                </enumeratedValue>
                <enumeratedValue>
                  <name />
                  <description>输出256秒方波信号</description>
                  <value>7</value>
                </enumeratedValue>
                <enumeratedValue>
                  <name />
                  <description>反向输出PLL分频的可变占空比的精确秒时标</description>
                  <value>8</value>
                </enumeratedValue>
                <enumeratedValue>
                  <name />
                  <description>反向输出秒计数器进位信号</description>
                  <value>9</value>
                </enumeratedValue>
                <enumeratedValue>
                  <name />
                  <description>反向输出分计数器进位信号</description>
                  <value>a</value>
                </enumeratedValue>
                <enumeratedValue>
                  <name />
                  <description>反向输出小时计数器进位信号</description>
                  <value>b</value>
                </enumeratedValue>
                <enumeratedValue>
                  <name />
                  <description>反向输出天计数器进位信号</description>
                  <value>c</value>
                </enumeratedValue>
                <enumeratedValue>
                  <name />
                  <description>反向输出闹钟匹配信号</description>
                  <value>d</value>
                </enumeratedValue>
                <enumeratedValue>
                  <name />
                  <description>反向输出PLL分频的精确1s方波信号</description>
                  <value>e</value>
                </enumeratedValue>
                <enumeratedValue>
                  <name />
                  <description>输出RTC内部秒时标方波</description>
                  <value>f</value>
                </enumeratedValue>
              </enumeratedValues>
            </field>
          </fields>
        </register>
        <register>
          <name>ADJUST</name>
          <description>RTC time Adjust Register</description>
          <addressOffset>0x30</addressOffset>
          <size>32</size>
          <access>read-write</access>
          <resetValue>0x00000000</resetValue>
          <fields>
            <field>
              <name>ADJUST</name>
              <description>ADJUST  field description</description>
              <bitRange>[12:0]</bitRange>
              <access>read-write</access>
              <enumeratedValues />
            </field>
          </fields>
        </register>
        <register>
          <name>ADSIGN</name>
          <description>RTC time Adjust Sign Register</description>
          <addressOffset>0x34</addressOffset>
          <size>32</size>
          <access>read-write</access>
          <resetValue>0x00000000</resetValue>
          <fields>
            <field>
              <name>ADSIGN</name>
              <description>ADSIGN  field description</description>
              <bitRange>[0:0]</bitRange>
              <access>read-write</access>
              <enumeratedValues>
                <enumeratedValue>
                  <name />
                  <description>表示增加计数初值</description>
                  <value>0</value>
                </enumeratedValue>
                <enumeratedValue>
                  <name />
                  <description>表示减少计数初值</description>
                  <value>1</value>
                </enumeratedValue>
              </enumeratedValues>
            </field>
          </fields>
        </register>
        <register>
          <name>VCAL</name>
          <description>RTC Virtual Calibration Register</description>
          <addressOffset>0x38</addressOffset>
          <size>32</size>
          <access>read-write</access>
          <resetValue>0x00000000</resetValue>
          <fields>
            <field>
              <name>PR1SEN</name>
              <description>PR1SEN  field description</description>
              <bitRange>[0:0]</bitRange>
              <access>read-write</access>
              <enumeratedValues>
                <enumeratedValue>
                  <name />
                  <description>表示禁止虚拟调校功能</description>
                  <value>0</value>
                </enumeratedValue>
                <enumeratedValue>
                  <name />
                  <description>表示使能虚拟调校功能</description>
                  <value>1</value>
                </enumeratedValue>
              </enumeratedValues>
            </field>
          </fields>
        </register>
        <register>
          <name>MSCNT</name>
          <description>RTC Milli-Second Register</description>
          <addressOffset>0x3c</addressOffset>
          <size>32</size>
          <access>read-write</access>
          <resetValue>0x00000000</resetValue>
          <fields>
            <field>
              <name>MSCNT</name>
              <description>MSCNT  field description</description>
              <bitRange>[7:0]</bitRange>
              <access>read-write</access>
              <enumeratedValues>
                <enumeratedValue>
                  <name />
                  <description>有效位8bit，精度3.9ms</description>
                  <value>0</value>
                </enumeratedValue>
                <enumeratedValue>
                  <name />
                  <description>有效位8bit，精度3.9ms</description>
                  <value>3</value>
                </enumeratedValue>
                <enumeratedValue>
                  <name />
                  <description>有效值7bit，精度7.8ms</description>
                  <value>0</value>
                </enumeratedValue>
                <enumeratedValue>
                  <name />
                  <description>有效值6bit，精度15.625ms</description>
                  <value>0</value>
                </enumeratedValue>
              </enumeratedValues>
            </field>
          </fields>
        </register>
        <register>
          <name>CALSTEP</name>
          <description>RTC Calibration Step Register</description>
          <addressOffset>0x40</addressOffset>
          <size>32</size>
          <access>read-write</access>
          <resetValue>0x00000000</resetValue>
          <fields>
            <field>
              <name>CALSTEP</name>
              <description>CALSTEP  field description</description>
              <bitRange>[1:0]</bitRange>
              <access>read-write</access>
              <enumeratedValues>
                <enumeratedValue>
                  <name />
                  <description>0.06ppm（精度+/-0.03ppm）</description>
                  <value>2</value>
                </enumeratedValue>
                <enumeratedValue>
                  <name />
                  <description>0.119ppm（精度+/-0.06ppm）</description>
                  <value>1</value>
                </enumeratedValue>
                <enumeratedValue>
                  <name />
                  <description>0.238ppm（精度+/-0.119ppm）</description>
                  <value>0</value>
                </enumeratedValue>
                <enumeratedValue>
                  <name />
                  <description>0.238ppm（精度+/-0.119ppm）</description>
                  <value>3</value>
                </enumeratedValue>
              </enumeratedValues>
            </field>
          </fields>
        </register>
        <register>
          <name>ADCNT</name>
          <description>RTC Adjust Counter Register</description>
          <addressOffset>0x44</addressOffset>
          <size>32</size>
          <access>read-write</access>
          <resetValue />
          <fields>
            <field>
              <name>ADJCNT</name>
              <description>ADJCNT  field description</description>
              <bitRange>[8:0]</bitRange>
              <access>read-only</access>
              <enumeratedValues />
            </field>
          </fields>
        </register>
        <register>
          <name>SSR</name>
          <description>RTC Sub-Second Register</description>
          <addressOffset>0x48</addressOffset>
          <size>32</size>
          <access>read-write</access>
          <resetValue>0x00000000</resetValue>
          <fields>
            <field>
              <name>SSR</name>
              <description>SSR  field description</description>
              <bitRange>[5:0]</bitRange>
              <access>read-only</access>
              <enumeratedValues />
            </field>
          </fields>
        </register>
        <register>
          <name>SSA</name>
          <description>RTC Sub-Second Alarm Register</description>
          <addressOffset>0x4c</addressOffset>
          <size>32</size>
          <access>read-write</access>
          <resetValue>0x00000000</resetValue>
          <fields>
            <field>
              <name>SSAEN</name>
              <description>SSAEN  field description</description>
              <bitRange>[7:7]</bitRange>
              <access>read-write</access>
              <enumeratedValues>
                <enumeratedValue>
                  <name />
                  <description>使能亚秒闹钟功能</description>
                  <value>1</value>
                </enumeratedValue>
                <enumeratedValue>
                  <name />
                  <description>禁止亚秒闹钟功能</description>
                  <value>0</value>
                </enumeratedValue>
              </enumeratedValues>
            </field>
            <field>
              <name>SS_ALARM</name>
              <description>SS_ALARM  field description</description>
              <bitRange>[5:0]</bitRange>
              <access>read-write</access>
              <enumeratedValues />
            </field>
          </fields>
        </register>
        <register>
          <name>DTR</name>
          <description>RTC Time Mark Duty Cycle Register</description>
          <addressOffset>0x50</addressOffset>
          <size>32</size>
          <access>read-write</access>
          <resetValue />
          <fields>
            <field>
              <name>DUTY</name>
              <description>DUTY  field description</description>
              <bitRange>[24:0]</bitRange>
              <access>read-write</access>
              <enumeratedValues />
            </field>
          </fields>
        </register>
        <register>
          <name>CR</name>
          <description>RTC Control Register</description>
          <addressOffset>0x7c</addressOffset>
          <size>32</size>
          <access>read-write</access>
          <resetValue>0x00000000</resetValue>
          <fields>
            <field>
              <name>RTC_EN</name>
              <description>RTC_EN  field description</description>
              <bitRange>[0:0]</bitRange>
              <access>read-write</access>
              <enumeratedValues>
                <enumeratedValue>
                  <name />
                  <description>使能RTC走时</description>
                  <value>1</value>
                </enumeratedValue>
                <enumeratedValue>
                  <name />
                  <description>停止RTC走时</description>
                  <value>0</value>
                </enumeratedValue>
              </enumeratedValues>
            </field>
          </fields>
        </register>
      </registers>
    </peripheral>  
    <peripheral>
      <name>LCD</name>
      <description>LCD module information</description>
      <groupName>LCD</groupName>
      <baseAddress>0x40010c00</baseAddress>
      <size>32</size>
      <access>read-write</access>
      <addressBlock>
        <offset>0</offset>
        <size>0x60</size>
        <usage>registers</usage>
      </addressBlock>
      <registers>
        <register>
          <name>CR</name>
          <description>LCD Control Register</description>
          <addressOffset>0x0</addressOffset>
          <size>32</size>
          <access>read-write</access>
          <resetValue>0x00010e00</resetValue>
          <fields>
            <field>
              <name>SCFSEL</name>
              <description>SCFSEL  field description</description>
              <bitRange>[22:20]</bitRange>
              <access>read-write</access>
              <enumeratedValues>
                <enumeratedValue>
                  <name />
                  <description>当选择110或111档位时，如果频率低于帧频*2*COM，则输出结果与000档位相同；当帧频率设置较高时，使用000档位可能导致驱动脉冲频率太高无法正常输</description>
                  <value>0</value>
                </enumeratedValue>
              </enumeratedValues>
            </field>
            <field>
              <name>SC_CTRL</name>
              <description>SC_CTRL  field description</description>
              <bitRange>[19:18]</bitRange>
              <access>read-write</access>
              <enumeratedValues />
            </field>
            <field>
              <name>IC_CTRL</name>
              <description>IC_CTRL  field description</description>
              <bitRange>[17:16]</bitRange>
              <access>read-write</access>
              <enumeratedValues>
                <enumeratedValue>
                  <name />
                  <description>电流最大</description>
                  <value>0</value>
                </enumeratedValue>
                <enumeratedValue>
                  <name />
                  <description>电流次大</description>
                  <value>1</value>
                </enumeratedValue>
                <enumeratedValue>
                  <name />
                  <description>电流次小</description>
                  <value>2</value>
                </enumeratedValue>
                <enumeratedValue>
                  <name />
                  <description>电流最小</description>
                  <value>3</value>
                </enumeratedValue>
              </enumeratedValues>
            </field>
            <field>
              <name>ENMODE</name>
              <description>ENMODE  field description</description>
              <bitRange>[15:15]</bitRange>
              <access>read-write</access>
              <enumeratedValues>
                <enumeratedValue>
                  <name />
                  <description>RFU</description>
                  <value>0</value>
                </enumeratedValue>
                <enumeratedValue>
                  <name />
                  <description>片内电阻型驱动</description>
                  <value>1</value>
                </enumeratedValue>
              </enumeratedValues>
            </field>
            <field>
              <name>FLICK</name>
              <description>FLICK  field description</description>
              <bitRange>[14:14]</bitRange>
              <access>read-write</access>
              <enumeratedValues>
                <enumeratedValue>
                  <name />
                  <description>显示闪烁，闪烁频率由TON和TOFF寄存器设置</description>
                  <value>1</value>
                </enumeratedValue>
                <enumeratedValue>
                  <name />
                  <description>关闭闪烁</description>
                  <value>0</value>
                </enumeratedValue>
              </enumeratedValues>
            </field>
            <field>
              <name>BIAS</name>
              <description>BIAS  field description</description>
              <bitRange>[11:8]</bitRange>
              <access>read-write</access>
              <enumeratedValues />
            </field>
            <field>
              <name>BIASMD</name>
              <description>BIASMD  field description</description>
              <bitRange>[5:5]</bitRange>
              <access>read-write</access>
              <enumeratedValues>
                <enumeratedValue>
                  <name />
                  <description>1/3 Bias</description>
                  <value>1</value>
                </enumeratedValue>
                <enumeratedValue>
                  <name />
                  <description>1/4 Bias</description>
                  <value>0</value>
                </enumeratedValue>
              </enumeratedValues>
            </field>
            <field>
              <name>ANTIPOLAR</name>
              <description>ANTIPOLAR  field description</description>
              <bitRange>[4:4]</bitRange>
              <access>read-write</access>
              <enumeratedValues>
                <enumeratedValue>
                  <name />
                  <description>COM和SEG在LCD关闭情况下接地</description>
                  <value>1</value>
                </enumeratedValue>
                <enumeratedValue>
                  <name />
                  <description>COM和SEG在LCD关闭情况下浮空</description>
                  <value>0</value>
                </enumeratedValue>
              </enumeratedValues>
            </field>
            <field>
              <name>WFT</name>
              <description>WFT  field description</description>
              <bitRange>[3:3]</bitRange>
              <access>read-write</access>
              <enumeratedValues>
                <enumeratedValue>
                  <name />
                  <description>B类波形</description>
                  <value>1</value>
                </enumeratedValue>
                <enumeratedValue>
                  <name />
                  <description>A类波形</description>
                  <value>0</value>
                </enumeratedValue>
              </enumeratedValues>
            </field>
            <field>
              <name>LMUX</name>
              <description>LMUX  field description</description>
              <bitRange>[2:1]</bitRange>
              <access>read-write</access>
              <enumeratedValues>
                <enumeratedValue>
                  <name />
                  <description>4COM</description>
                  <value>0</value>
                </enumeratedValue>
                <enumeratedValue>
                  <name />
                  <description>6COM</description>
                  <value>1</value>
                </enumeratedValue>
                <enumeratedValue>
                  <name />
                  <description>8COM</description>
                  <value>2</value>
                </enumeratedValue>
                <enumeratedValue>
                  <name />
                  <description>8COM</description>
                  <value>3</value>
                </enumeratedValue>
              </enumeratedValues>
            </field>
            <field>
              <name>EN</name>
              <description>EN  field description</description>
              <bitRange>[0:0]</bitRange>
              <access>read-write</access>
              <enumeratedValues>
                <enumeratedValue>
                  <name />
                  <description>启动LCD显示</description>
                  <value>1</value>
                </enumeratedValue>
                <enumeratedValue>
                  <name />
                  <description>关闭LCD显示</description>
                  <value>0</value>
                </enumeratedValue>
              </enumeratedValues>
            </field>
          </fields>
        </register>
        <register>
          <name>TEST</name>
          <description>LCD test Register</description>
          <addressOffset>0x4</addressOffset>
          <size>32</size>
          <access>read-write</access>
          <resetValue>0x00000000</resetValue>
          <fields>
            <field>
              <name>LCCTRL</name>
              <description>LCCTRL  field description</description>
              <bitRange>[7:7]</bitRange>
              <access>read-write</access>
              <enumeratedValues />
            </field>
            <field>
              <name>TESTEN</name>
              <description>TESTEN  field description</description>
              <bitRange>[0:0]</bitRange>
              <access>read-write</access>
              <enumeratedValues>
                <enumeratedValue>
                  <name />
                  <description>LCD测试模式使能。在LCD测试模式下，LCD引脚静态输出模拟直流电平，所有与动态扫描时间以及扫描波形相关寄存器设置无效</description>
                  <value>1</value>
                </enumeratedValue>
                <enumeratedValue>
                  <name />
                  <description>正常工作模式，测试模式无效，相关测试寄存器控制无效</description>
                  <value>0</value>
                </enumeratedValue>
              </enumeratedValues>
            </field>
          </fields>
        </register>
        <register>
          <name>FCR</name>
          <description>LCD Frequency Control Register</description>
          <addressOffset>0x8</addressOffset>
          <size>32</size>
          <access>read-write</access>
          <resetValue>0x00000000</resetValue>
          <fields>
            <field>
              <name>DF</name>
              <description>DF  field description</description>
              <bitRange>[7:0]</bitRange>
              <access>read-write</access>
              <enumeratedValues />
            </field>
          </fields>
        </register>
        <register>
          <name>FLKT</name>
          <description>LCD Flick Time Register</description>
          <addressOffset>0xc</addressOffset>
          <size>32</size>
          <access>read-write</access>
          <resetValue>0x00000000</resetValue>
          <fields>
            <field>
              <name>TOFF</name>
              <description>TOFF  field description</description>
              <bitRange>[15:8]</bitRange>
              <access>read-write</access>
              <enumeratedValues />
            </field>
            <field>
              <name>TON</name>
              <description>TON  field description</description>
              <bitRange>[7:0]</bitRange>
              <access>read-write</access>
              <enumeratedValues />
            </field>
          </fields>
        </register>
        <register>
          <name>IER</name>
          <description>LCD Interrupt Enable Register</description>
          <addressOffset>0x14</addressOffset>
          <size>32</size>
          <access>read-write</access>
          <resetValue>0x00000000</resetValue>
          <fields>
            <field>
              <name>DONIE</name>
              <description>DONIE  field description</description>
              <bitRange>[1:1]</bitRange>
              <access>read-write</access>
              <enumeratedValues>
                <enumeratedValue>
                  <name />
                  <description>显示点亮中断使能</description>
                  <value>1</value>
                </enumeratedValue>
                <enumeratedValue>
                  <name />
                  <description>显示点亮中断禁止</description>
                  <value>0</value>
                </enumeratedValue>
              </enumeratedValues>
            </field>
            <field>
              <name>DOFFIE</name>
              <description>DOFFIE  field description</description>
              <bitRange>[0:0]</bitRange>
              <access>read-write</access>
              <enumeratedValues>
                <enumeratedValue>
                  <name />
                  <description>显示熄灭中断使能</description>
                  <value>1</value>
                </enumeratedValue>
                <enumeratedValue>
                  <name />
                  <description>显示熄灭中断禁止</description>
                  <value>0</value>
                </enumeratedValue>
              </enumeratedValues>
            </field>
          </fields>
        </register>
        <register>
          <name>ISR</name>
          <description>LCD Interrupt Status Register</description>
          <addressOffset>0x18</addressOffset>
          <size>32</size>
          <access>read-write</access>
          <resetValue>0x00000000</resetValue>
          <fields>
            <field>
              <name>DONIF</name>
              <description>DONIF  field description</description>
              <bitRange>[1:1]</bitRange>
              <access>read-write</access>
              <enumeratedValues />
            </field>
            <field>
              <name>DOFFIF</name>
              <description>DOFFIF  field description</description>
              <bitRange>[0:0]</bitRange>
              <access>read-write</access>
              <enumeratedValues />
            </field>
          </fields>
        </register>
        <register>
          <name>DATA0</name>
          <description>LCD data buffer registers 0</description>
          <addressOffset>0x24</addressOffset>
          <size>32</size>
          <access>read-write</access>
          <resetValue>0x00000000</resetValue>
          <fields>
            <field>
              <name>DSDA</name>
              <description>DSDA  field description</description>
              <bitRange>[31:0]</bitRange>
              <access>read-write</access>
              <enumeratedValues />
            </field>
          </fields>
        </register>
        <register>
          <name>DATA1</name>
          <description>LCD data buffer registers 1</description>
          <addressOffset>0x28</addressOffset>
          <size>32</size>
          <access>read-write</access>
          <resetValue>0x00000000</resetValue>
          <fields>
            <field>
              <name>DSDA</name>
              <description>DSDA  field description</description>
              <bitRange>[31:0]</bitRange>
              <access>read-write</access>
              <enumeratedValues />
            </field>
          </fields>
        </register>
        <register>
          <name>DATA2</name>
          <description>LCD data buffer registers 2</description>
          <addressOffset>0x2c</addressOffset>
          <size>32</size>
          <access>read-write</access>
          <resetValue>0x00000000</resetValue>
          <fields>
            <field>
              <name>DSDA</name>
              <description>DSDA  field description</description>
              <bitRange>[31:0]</bitRange>
              <access>read-write</access>
              <enumeratedValues />
            </field>
          </fields>
        </register>
        <register>
          <name>DATA3</name>
          <description>LCD data buffer registers 3</description>
          <addressOffset>0x30</addressOffset>
          <size>32</size>
          <access>read-write</access>
          <resetValue>0x00000000</resetValue>
          <fields>
            <field>
              <name>DSDA</name>
              <description>DSDA  field description</description>
              <bitRange>[31:0]</bitRange>
              <access>read-write</access>
              <enumeratedValues />
            </field>
          </fields>
        </register>
        <register>
          <name>DATA4</name>
          <description>LCD data buffer registers 4</description>
          <addressOffset>0x34</addressOffset>
          <size>32</size>
          <access>read-write</access>
          <resetValue>0x00000000</resetValue>
          <fields>
            <field>
              <name>DSDA</name>
              <description>DSDA  field description</description>
              <bitRange>[31:0]</bitRange>
              <access>read-write</access>
              <enumeratedValues />
            </field>
          </fields>
        </register>
        <register>
          <name>DATA5</name>
          <description>LCD data buffer registers 5</description>
          <addressOffset>0x38</addressOffset>
          <size>32</size>
          <access>read-write</access>
          <resetValue>0x00000000</resetValue>
          <fields>
            <field>
              <name>DSDA</name>
              <description>DSDA  field description</description>
              <bitRange>[31:0]</bitRange>
              <access>read-write</access>
              <enumeratedValues />
            </field>
          </fields>
        </register>
        <register>
          <name>DATA6</name>
          <description>LCD data buffer registers 6</description>
          <addressOffset>0x3c</addressOffset>
          <size>32</size>
          <access>read-write</access>
          <resetValue>0x00000000</resetValue>
          <fields>
            <field>
              <name>DSDA</name>
              <description>DSDA  field description</description>
              <bitRange>[31:0]</bitRange>
              <access>read-write</access>
              <enumeratedValues />
            </field>
          </fields>
        </register>
        <register>
          <name>DATA7</name>
          <description>LCD data buffer registers 7</description>
          <addressOffset>0x40</addressOffset>
          <size>32</size>
          <access>read-write</access>
          <resetValue>0x00000000</resetValue>
          <fields>
            <field>
              <name>DSDA</name>
              <description>DSDA  field description</description>
              <bitRange>[31:0]</bitRange>
              <access>read-write</access>
              <enumeratedValues />
            </field>
          </fields>
        </register>
        <register>
          <name>COMEN</name>
          <description>LCD COM Enable Register</description>
          <addressOffset>0x50</addressOffset>
          <size>32</size>
          <access>read-write</access>
          <resetValue>0x00000000</resetValue>
          <fields>
            <field>
              <name>COMEN</name>
              <description>COMEN  field description</description>
              <bitRange>[3:0]</bitRange>
              <access>read-write</access>
              <enumeratedValues>
                <enumeratedValue>
                  <name />
                  <description>COM输出使能</description>
                  <value>1</value>
                </enumeratedValue>
                <enumeratedValue>
                  <name />
                  <description>COM输出禁止</description>
                  <value>0</value>
                </enumeratedValue>
              </enumeratedValues>
            </field>
          </fields>
        </register>
        <register>
          <name>SEGEN0</name>
          <description>LCD SEG Enable Register0</description>
          <addressOffset>0x54</addressOffset>
          <size>32</size>
          <access>read-write</access>
          <resetValue>0x00000000</resetValue>
          <fields>
            <field>
              <name>SEGENx</name>
              <description>SEGENx  field description</description>
              <bitRange>[31:0]</bitRange>
              <access>read-write</access>
              <enumeratedValues />
            </field>
          </fields>
        </register>
        <register>
          <name>SEGEN1</name>
          <description>LCD SEG Enable Register1</description>
          <addressOffset>0x58</addressOffset>
          <size>32</size>
          <access>read-write</access>
          <resetValue>0x00000000</resetValue>
          <fields>
            <field>
              <name>SEGENx</name>
              <description>SEGENx  field description</description>
              <bitRange>[11:0]</bitRange>
              <access>read-write</access>
              <enumeratedValues>
                <enumeratedValue>
                  <name />
                  <description>SEG输出使能</description>
                  <value>1</value>
                </enumeratedValue>
                <enumeratedValue>
                  <name />
                  <description>SEG输出禁止</description>
                  <value>0</value>
                </enumeratedValue>
              </enumeratedValues>
            </field>
          </fields>
        </register>
        <register>
          <name>BSTCR</name>
          <description>LCD Boost Control Register</description>
          <addressOffset>0x5c</addressOffset>
          <size>32</size>
          <access>read-write</access>
          <resetValue>0x00000010</resetValue>
          <fields>
            <field>
              <name>OSC_CFG</name>
              <description>OSC_CFG  field description</description>
              <bitRange>[15:12]</bitRange>
              <access>read-write</access>
              <enumeratedValues />
            </field>
            <field>
              <name>BUF_OFF</name>
              <description>BUF_OFF  field description</description>
              <bitRange>[9:9]</bitRange>
              <access>read-write</access>
              <enumeratedValues>
                <enumeratedValue>
                  <name />
                  <description>关闭Buffer</description>
                  <value>1</value>
                </enumeratedValue>
                <enumeratedValue>
                  <name />
                  <description>打开Buffer</description>
                  <value>0</value>
                </enumeratedValue>
              </enumeratedValues>
            </field>
            <field>
              <name>BUFBYP</name>
              <description>BUFBYP  field description</description>
              <bitRange>[8:8]</bitRange>
              <access>read-write</access>
              <enumeratedValues>
                <enumeratedValue>
                  <name />
                  <description>Bypass Buffer</description>
                  <value>1</value>
                </enumeratedValue>
                <enumeratedValue>
                  <name />
                  <description>不Bypass</description>
                  <value>0</value>
                </enumeratedValue>
              </enumeratedValues>
            </field>
            <field>
              <name>VLCDPD</name>
              <description>VLCDPD  field description</description>
              <bitRange>[7:7]</bitRange>
              <access>read-write</access>
              <enumeratedValues>
                <enumeratedValue>
                  <name />
                  <description>开启VLCD下拉</description>
                  <value>1</value>
                </enumeratedValue>
                <enumeratedValue>
                  <name />
                  <description>关闭VLCD下拉</description>
                  <value>0</value>
                </enumeratedValue>
              </enumeratedValues>
            </field>
            <field>
              <name>VLCDCFG</name>
              <description>VLCDCFG  field description</description>
              <bitRange>[5:2]</bitRange>
              <access>read-write</access>
              <enumeratedValues>
                <enumeratedValue>
                  <name />
                  <description>2.5V</description>
                  <value>0</value>
                </enumeratedValue>
                <enumeratedValue>
                  <name />
                  <description>2.75V</description>
                  <value>1</value>
                </enumeratedValue>
                <enumeratedValue>
                  <name />
                  <description>3.0V</description>
                  <value>2</value>
                </enumeratedValue>
                <enumeratedValue>
                  <name />
                  <description>3.25V</description>
                  <value>3</value>
                </enumeratedValue>
                <enumeratedValue>
                  <name />
                  <description>3.5V</description>
                  <value>4</value>
                </enumeratedValue>
                <enumeratedValue>
                  <name />
                  <description>3.75V</description>
                  <value>5</value>
                </enumeratedValue>
                <enumeratedValue>
                  <name />
                  <description>4.0V</description>
                  <value>6</value>
                </enumeratedValue>
                <enumeratedValue>
                  <name />
                  <description>4.25V</description>
                  <value>7</value>
                </enumeratedValue>
                <enumeratedValue>
                  <name />
                  <description>4.5V</description>
                  <value>8</value>
                </enumeratedValue>
                <enumeratedValue>
                  <name />
                  <description>4.75V</description>
                  <value>9</value>
                </enumeratedValue>
                <enumeratedValue>
                  <name />
                  <description>5.0V</description>
                  <value>a</value>
                </enumeratedValue>
                <enumeratedValue>
                  <name />
                  <description>5.25V</description>
                  <value>b</value>
                </enumeratedValue>
                <enumeratedValue>
                  <name />
                  <description>5.5V</description>
                  <value>c</value>
                </enumeratedValue>
                <enumeratedValue>
                  <name />
                  <description>RFU</description>
                  <value>0</value>
                </enumeratedValue>
              </enumeratedValues>
            </field>
            <field>
              <name>BOOST_TEN</name>
              <description>BOOST_TEN  field description</description>
              <bitRange>[1:1]</bitRange>
              <access>read-write</access>
              <enumeratedValues>
                <enumeratedValue>
                  <name />
                  <description>Booster测试模式</description>
                  <value>1</value>
                </enumeratedValue>
                <enumeratedValue>
                  <name />
                  <description>正常模式</description>
                  <value>0</value>
                </enumeratedValue>
              </enumeratedValues>
            </field>
            <field>
              <name>BOOST_EN</name>
              <description>BOOST_EN  field description</description>
              <bitRange>[0:0]</bitRange>
              <access>read-write</access>
              <enumeratedValues>
                <enumeratedValue>
                  <name />
                  <description>开启VLCD Booster</description>
                  <value>1</value>
                </enumeratedValue>
                <enumeratedValue>
                  <name />
                  <description>关闭VLCD Booster</description>
                  <value>0</value>
                </enumeratedValue>
              </enumeratedValues>
            </field>
          </fields>
        </register>
      </registers>
    </peripheral>
    <peripheral>
      <name>ADC</name>
      <description>ADC module information</description>
      <groupName>ADC</groupName>
      <baseAddress>0x4001fa00</baseAddress>
      <size>32</size>
      <access>read-write</access>
      <addressBlock>
        <offset>0</offset>
        <size>0x14</size>
        <usage>registers</usage>
      </addressBlock>
      <registers>
        <register>
          <name>CR</name>
          <description>ADC Control Register</description>
          <addressOffset>0x0</addressOffset>
          <size>32</size>
          <access>read-write</access>
          <resetValue>0x00000000</resetValue>
          <fields>
            <field>
              <name>ADC_IE</name>
              <description>ADC_IE  field description</description>
              <bitRange>[7:7]</bitRange>
              <access>read-write</access>
              <enumeratedValues />
            </field>
            <field>
              <name>ACC_IE</name>
              <description>ACC_IE  field description</description>
              <bitRange>[6:6]</bitRange>
              <access>read-write</access>
              <enumeratedValues />
            </field>
            <field>
              <name>HPEN</name>
              <description>HPEN  field description</description>
              <bitRange>[3:3]</bitRange>
              <access>read-write</access>
              <enumeratedValues>
                <enumeratedValue>
                  <name />
                  <description>低功耗模式，工作时钟最高1MHz</description>
                  <value>0</value>
                </enumeratedValue>
                <enumeratedValue>
                  <name />
                  <description>高功耗模式，工作时钟最高2MHz</description>
                  <value>1</value>
                </enumeratedValue>
              </enumeratedValues>
            </field>
            <field>
              <name>MODE</name>
              <description>MODE  field description</description>
              <bitRange>[2:2]</bitRange>
              <access>read-write</access>
              <enumeratedValues>
                <enumeratedValue>
                  <name />
                  <description>内部累加器模式</description>
                  <value>0</value>
                </enumeratedValue>
                <enumeratedValue>
                  <name />
                  <description>外部累加器或CIC模式</description>
                  <value>1</value>
                </enumeratedValue>
              </enumeratedValues>
            </field>
            <field>
              <name>RSTCTRL_EN</name>
              <description>RSTCTRL_EN  field description</description>
              <bitRange>[1:1]</bitRange>
              <access>read-write</access>
              <enumeratedValues>
                <enumeratedValue>
                  <name />
                  <description>禁止积分器外部复位</description>
                  <value>0</value>
                </enumeratedValue>
                <enumeratedValue>
                  <name />
                  <description>允许积分器外部复位</description>
                  <value>1</value>
                </enumeratedValue>
              </enumeratedValues>
            </field>
            <field>
              <name>EN</name>
              <description>EN  field description</description>
              <bitRange>[0:0]</bitRange>
              <access>read-write</access>
              <enumeratedValues>
                <enumeratedValue>
                  <name />
                  <description>ADC不使能</description>
                  <value>0</value>
                </enumeratedValue>
                <enumeratedValue>
                  <name />
                  <description>ADC使能</description>
                  <value>1</value>
                </enumeratedValue>
                <enumeratedValue>
                  <name />
                  <description>RTC_B执行自动温补时，硬件会周期性自动使能ADC</description>
                  <value>0</value>
                </enumeratedValue>
              </enumeratedValues>
            </field>
          </fields>
        </register>
        <register>
          <name>TRIM</name>
          <description>ADC Trim Register</description>
          <addressOffset>0x4</addressOffset>
          <size>32</size>
          <access>read-write</access>
          <resetValue>0x00000000</resetValue>
          <fields>
            <field>
              <name>ADC_TRIM</name>
              <description>ADC_TRIM  field description</description>
              <bitRange>[10:0]</bitRange>
              <access>read-write</access>
              <enumeratedValues>
                <enumeratedValue>
                  <name />
                  <description>Period = TRIM*2*TADC_CLK</description>
                  <value>0</value>
                </enumeratedValue>
              </enumeratedValues>
            </field>
          </fields>
        </register>
        <register>
          <name>DR</name>
          <description>ADC Data Register</description>
          <addressOffset>0x8</addressOffset>
          <size>32</size>
          <access>read-write</access>
          <resetValue>0x00000000</resetValue>
          <fields>
            <field>
              <name>ADC_DATA</name>
              <description>ADC_DATA  field description</description>
              <bitRange>[15:0]</bitRange>
              <access>read-only</access>
              <enumeratedValues />
            </field>
          </fields>
        </register>
        <register>
          <name>ISR</name>
          <description>ADC Interrupt Status Regsiter</description>
          <addressOffset>0xc</addressOffset>
          <size>32</size>
          <access>read-write</access>
          <resetValue>0x00000000</resetValue>
          <fields>
            <field>
              <name>INIT_RDY</name>
              <description>INIT_RDY  field description</description>
              <bitRange>[9:9]</bitRange>
              <access>read-only</access>
              <enumeratedValues>
                <enumeratedValue>
                  <name />
                  <description>ADC还未完成初始化</description>
                  <value>0</value>
                </enumeratedValue>
                <enumeratedValue>
                  <name />
                  <description>ADC完成初始化</description>
                  <value>1</value>
                </enumeratedValue>
                <enumeratedValue>
                  <name />
                  <description>MODE=1，ADC_EN置位后，等待MODE_CTRL_DELAY时间之后，此标志置位，表示ADC内部积分器建立完成。MODE=0时，工作时序由ADC内部自行控制，此标志无效。</description>
                  <value>0</value>
                </enumeratedValue>
              </enumeratedValues>
            </field>
            <field>
              <name>ACC_IF</name>
              <description>ACC_IF  field description</description>
              <bitRange>[8:8]</bitRange>
              <access>read-write</access>
              <enumeratedValues />
            </field>
            <field>
              <name>ADC_DONE</name>
              <description>ADC_DONE  field description</description>
              <bitRange>[1:1]</bitRange>
              <access>read-only</access>
              <enumeratedValues />
            </field>
            <field>
              <name>ADC_IF</name>
              <description>ADC_IF  field description</description>
              <bitRange>[0:0]</bitRange>
              <access>read-write</access>
              <enumeratedValues />
            </field>
          </fields>
        </register>
        <register>
          <name>CFGR</name>
          <description>ADC Config Register</description>
          <addressOffset>0x10</addressOffset>
          <size>32</size>
          <access>read-write</access>
          <resetValue>0x00000000</resetValue>
          <fields>
            <field>
              <name>ACC_PERIOD</name>
              <description>ACC_PERIOD  field description</description>
              <bitRange>[18:16]</bitRange>
              <access>read-write</access>
              <enumeratedValues>
                <enumeratedValue>
                  <name />
                  <description>1023（对应结果10bit）</description>
                  <value>0</value>
                </enumeratedValue>
                <enumeratedValue>
                  <name />
                  <description>2047（对应结果11bit）</description>
                  <value>1</value>
                </enumeratedValue>
                <enumeratedValue>
                  <name />
                  <description>4095（对应结果12bit）</description>
                  <value>2</value>
                </enumeratedValue>
                <enumeratedValue>
                  <name />
                  <description>8191（对应结果13bit）</description>
                  <value>3</value>
                </enumeratedValue>
                <enumeratedValue>
                  <name />
                  <description>16383（对应结果14bit）</description>
                  <value>4</value>
                </enumeratedValue>
                <enumeratedValue>
                  <name />
                  <description>4095</description>
                  <value>0</value>
                </enumeratedValue>
              </enumeratedValues>
            </field>
            <field>
              <name>RST_CTRL_DELAY</name>
              <description>RST_CTRL_DELAY  field description</description>
              <bitRange>[15:8]</bitRange>
              <access>read-write</access>
              <enumeratedValues>
                <enumeratedValue>
                  <name />
                  <description>不延迟</description>
                  <value>0</value>
                </enumeratedValue>
                <enumeratedValue>
                  <name />
                  <description>延迟255个ADC_CLK</description>
                  <value>ff</value>
                </enumeratedValue>
                <enumeratedValue>
                  <name />
                  <description>复位值为16个时钟周期，不得修改为小于16的数值</description>
                  <value>0</value>
                </enumeratedValue>
              </enumeratedValues>
            </field>
            <field>
              <name>BUFEN</name>
              <description>BUFEN  field description</description>
              <bitRange>[5:5]</bitRange>
              <access>read-write</access>
              <enumeratedValues />
            </field>
            <field>
              <name>BUFSEL</name>
              <description>BUFSEL  field description</description>
              <bitRange>[3:0]</bitRange>
              <access>read-write</access>
              <enumeratedValues>
                <enumeratedValue>
                  <name />
                  <description>ADC_IN1</description>
                  <value>1</value>
                </enumeratedValue>
                <enumeratedValue>
                  <name />
                  <description>ADC_IN2</description>
                  <value>2</value>
                </enumeratedValue>
                <enumeratedValue>
                  <name />
                  <description>ADC_IN3</description>
                  <value>3</value>
                </enumeratedValue>
                <enumeratedValue>
                  <name />
                  <description>ADC_IN4</description>
                  <value>4</value>
                </enumeratedValue>
                <enumeratedValue>
                  <name />
                  <description>ADC_IN5</description>
                  <value>5</value>
                </enumeratedValue>
                <enumeratedValue>
                  <name />
                  <description>ADC_IN6</description>
                  <value>6</value>
                </enumeratedValue>
                <enumeratedValue>
                  <name />
                  <description>ADC_IN7</description>
                  <value>7</value>
                </enumeratedValue>
                <enumeratedValue>
                  <name />
                  <description>ADC_IN8</description>
                  <value>8</value>
                </enumeratedValue>
                <enumeratedValue>
                  <name />
                  <description>ADC_IN9</description>
                  <value>9</value>
                </enumeratedValue>
                <enumeratedValue>
                  <name />
                  <description>ADC_IN10</description>
                  <value>a</value>
                </enumeratedValue>
                <enumeratedValue>
                  <name />
                  <description>ADC_IN11</description>
                  <value>b</value>
                </enumeratedValue>
                <enumeratedValue>
                  <name />
                  <description>ADC_IN12</description>
                  <value>c</value>
                </enumeratedValue>
                <enumeratedValue>
                  <name />
                  <description>VBAT</description>
                  <value>e</value>
                </enumeratedValue>
              </enumeratedValues>
            </field>
          </fields>
        </register>
      </registers>
    </peripheral>
    <peripheral>
      <name>CIC</name>
      <description>CIC module information</description>
      <groupName>CIC</groupName>
      <baseAddress>0x40015c00</baseAddress>
      <size>32</size>
      <access>read-write</access>
      <addressBlock>
        <offset>0</offset>
        <size>0x14</size>
        <usage>registers</usage>
      </addressBlock>
      <registers>
        <register>
          <name>DR</name>
          <description>CIC Output Data Register</description>
          <addressOffset>0x0</addressOffset>
          <size>32</size>
          <access>read-write</access>
          <resetValue>0x00000000</resetValue>
          <fields>
            <field>
              <name>ADC_CIC_DATA</name>
              <description>ADC_CIC_DATA  field description</description>
              <bitRange>[23:0]</bitRange>
              <access>read-only</access>
              <enumeratedValues />
            </field>
          </fields>
        </register>
        <register>
          <name>OS</name>
          <description>CIC Output Offset Register</description>
          <addressOffset>0x4</addressOffset>
          <size>32</size>
          <access>read-write</access>
          <resetValue>0x00000000</resetValue>
          <fields>
            <field>
              <name>ADC_CIC_OS</name>
              <description>ADC_CIC_OS  field description</description>
              <bitRange>[23:0]</bitRange>
              <access>read-write</access>
              <enumeratedValues />
            </field>
          </fields>
        </register>
        <register>
          <name>USDR</name>
          <description>CIC Unsigned Data Register</description>
          <addressOffset>0x8</addressOffset>
          <size>32</size>
          <access>read-write</access>
          <resetValue>0x00000000</resetValue>
          <fields>
            <field>
              <name>ADC_CIC_USDR</name>
              <description>ADC_CIC_USDR  field description</description>
              <bitRange>[23:0]</bitRange>
              <access>read-only</access>
              <enumeratedValues />
            </field>
          </fields>
        </register>
        <register>
          <name>CR</name>
          <description>CIC Control Register</description>
          <addressOffset>0xc</addressOffset>
          <size>32</size>
          <access>read-write</access>
          <resetValue>0x00000006</resetValue>
          <fields>
            <field>
              <name>CIC_EN</name>
              <description>CIC_EN  field description</description>
              <bitRange>[31:31]</bitRange>
              <access>read-write</access>
              <enumeratedValues>
                <enumeratedValue>
                  <name />
                  <description>关闭CIC</description>
                  <value>0</value>
                </enumeratedValue>
                <enumeratedValue>
                  <name />
                  <description>使能CIC</description>
                  <value>1</value>
                </enumeratedValue>
              </enumeratedValues>
            </field>
            <field>
              <name>NS_DISC</name>
              <description>NS_DISC  field description</description>
              <bitRange>[15:8]</bitRange>
              <access>read-write</access>
              <enumeratedValues />
            </field>
            <field>
              <name>OVR_IE</name>
              <description>OVR_IE  field description</description>
              <bitRange>[7:7]</bitRange>
              <access>read-write</access>
              <enumeratedValues>
                <enumeratedValue>
                  <name />
                  <description>禁止CIC溢出中断</description>
                  <value>0</value>
                </enumeratedValue>
                <enumeratedValue>
                  <name />
                  <description>允许CIC溢出中断</description>
                  <value>1</value>
                </enumeratedValue>
              </enumeratedValues>
            </field>
            <field>
              <name>CIC_IE</name>
              <description>CIC_IE  field description</description>
              <bitRange>[6:6]</bitRange>
              <access>read-write</access>
              <enumeratedValues>
                <enumeratedValue>
                  <name />
                  <description>禁止CIC中断</description>
                  <value>0</value>
                </enumeratedValue>
                <enumeratedValue>
                  <name />
                  <description>允许CIC中断，当CIC_IF置位时产生中断事件</description>
                  <value>1</value>
                </enumeratedValue>
              </enumeratedValues>
            </field>
            <field>
              <name>TRUNC</name>
              <description>TRUNC  field description</description>
              <bitRange>[5:3]</bitRange>
              <access>read-write</access>
              <enumeratedValues />
            </field>
            <field>
              <name>OSR</name>
              <description>OSR  field description</description>
              <bitRange>[2:0]</bitRange>
              <access>read-write</access>
              <enumeratedValues>
                <enumeratedValue>
                  <name />
                  <description>x8</description>
                  <value>0</value>
                </enumeratedValue>
                <enumeratedValue>
                  <name />
                  <description>x16</description>
                  <value>1</value>
                </enumeratedValue>
                <enumeratedValue>
                  <name />
                  <description>x32</description>
                  <value>2</value>
                </enumeratedValue>
                <enumeratedValue>
                  <name />
                  <description>x64</description>
                  <value>3</value>
                </enumeratedValue>
                <enumeratedValue>
                  <name />
                  <description>x128</description>
                  <value>4</value>
                </enumeratedValue>
                <enumeratedValue>
                  <name />
                  <description>x256</description>
                  <value>5</value>
                </enumeratedValue>
                <enumeratedValue>
                  <name />
                  <description>x512</description>
                  <value>6</value>
                </enumeratedValue>
                <enumeratedValue>
                  <name />
                  <description>x1024</description>
                  <value>7</value>
                </enumeratedValue>
              </enumeratedValues>
            </field>
          </fields>
        </register>
        <register>
          <name>ISR</name>
          <description>CIC Interrupt Status Register</description>
          <addressOffset>0x10</addressOffset>
          <size>32</size>
          <access>read-write</access>
          <resetValue>0x00000000</resetValue>
          <fields>
            <field>
              <name>CIC_OVR</name>
              <description>CIC_OVR  field description</description>
              <bitRange>[1:1]</bitRange>
              <access>read-write</access>
              <enumeratedValues />
            </field>
            <field>
              <name>CIC_IF</name>
              <description>CIC_IF  field description</description>
              <bitRange>[0:0]</bitRange>
              <access>read-write</access>
              <enumeratedValues />
            </field>
          </fields>
        </register>
      </registers>
    </peripheral>
    <peripheral>
      <name>GPIOA</name>
      <description>GPIOA module information</description>
      <groupName>GPIO</groupName>
      <baseAddress>0x40000c00</baseAddress>
      <size>32</size>
      <access>read-write</access>
      <addressBlock>
        <offset>0</offset>
        <size>0x2c</size>
        <usage>registers</usage>
      </addressBlock>
      <registers>
        <register>
          <name>INEN</name>
          <description>GPIOA Input Enable Register</description>
          <addressOffset>0x0</addressOffset>
          <size>32</size>
          <access>read-write</access>
          <resetValue>0x00000000</resetValue>
          <fields>
            <field>
              <name>PxINEN</name>
              <description>PxINEN  field description</description>
              <bitRange>[15:0]</bitRange>
              <access>read-write</access>
              <enumeratedValues>
                <enumeratedValue>
                  <name />
                  <description>关闭输入使能</description>
                  <value>0</value>
                </enumeratedValue>
                <enumeratedValue>
                  <name />
                  <description>打开输入使能</description>
                  <value>1</value>
                </enumeratedValue>
              </enumeratedValues>
            </field>
          </fields>
        </register>
        <register>
          <name>PUEN</name>
          <description>GPIOA Pull-Up Enable Register</description>
          <addressOffset>0x4</addressOffset>
          <size>32</size>
          <access>read-write</access>
          <resetValue>0x00000000</resetValue>
          <fields>
            <field>
              <name>PxPUEN</name>
              <description>PxPUEN  field description</description>
              <bitRange>[15:0]</bitRange>
              <access>read-write</access>
              <enumeratedValues>
                <enumeratedValue>
                  <name />
                  <description>关闭上拉</description>
                  <value>0</value>
                </enumeratedValue>
                <enumeratedValue>
                  <name />
                  <description>使能上拉</description>
                  <value>1</value>
                </enumeratedValue>
              </enumeratedValues>
            </field>
          </fields>
        </register>
        <register>
          <name>ODEN</name>
          <description>GPIOA Open-Drain Enable Register</description>
          <addressOffset>0x8</addressOffset>
          <size>32</size>
          <access>read-write</access>
          <resetValue>0x00000000</resetValue>
          <fields>
            <field>
              <name>PxODEN</name>
              <description>PxODEN  field description</description>
              <bitRange>[15:0]</bitRange>
              <access>read-write</access>
              <enumeratedValues>
                <enumeratedValue>
                  <name />
                  <description>关闭开漏输出</description>
                  <value>0</value>
                </enumeratedValue>
                <enumeratedValue>
                  <name />
                  <description>使能开漏输出</description>
                  <value>1</value>
                </enumeratedValue>
              </enumeratedValues>
            </field>
          </fields>
        </register>
        <register>
          <name>FCR</name>
          <description>GPIOA Function Control Register</description>
          <addressOffset>0xc</addressOffset>
          <size>32</size>
          <access>read-write</access>
          <resetValue>0x00000000</resetValue>
          <fields>
            <field>
              <name>Px15FCR</name>
              <description>Px15FCR  field description</description>
              <bitRange>[31:30]</bitRange>
              <access>read-write</access>
              <enumeratedValues>
                <enumeratedValue>
                  <name />
                  <description>GPIO输入</description>
                  <value>0</value>
                </enumeratedValue>
                <enumeratedValue>
                  <name />
                  <description>GPIO输出</description>
                  <value>1</value>
                </enumeratedValue>
                <enumeratedValue>
                  <name />
                  <description>Digital function</description>
                  <value>2</value>
                </enumeratedValue>
                <enumeratedValue>
                  <name />
                  <description>Analog function</description>
                  <value>3</value>
                </enumeratedValue>
              </enumeratedValues>
            </field>
            <field>
              <name>Px14FCR</name>
              <description>Px14FCR  field description</description>
              <bitRange>[29:28]</bitRange>
              <access>read-write</access>
              <enumeratedValues>
                <enumeratedValue>
                  <name />
                  <description>GPIO输入</description>
                  <value>0</value>
                </enumeratedValue>
                <enumeratedValue>
                  <name />
                  <description>GPIO输出</description>
                  <value>1</value>
                </enumeratedValue>
                <enumeratedValue>
                  <name />
                  <description>Digital function</description>
                  <value>2</value>
                </enumeratedValue>
                <enumeratedValue>
                  <name />
                  <description>Analog function</description>
                  <value>3</value>
                </enumeratedValue>
              </enumeratedValues>
            </field>
            <field>
              <name>Px13FCR</name>
              <description>Px13FCR  field description</description>
              <bitRange>[27:26]</bitRange>
              <access>read-write</access>
              <enumeratedValues>
                <enumeratedValue>
                  <name />
                  <description>GPIO输入</description>
                  <value>0</value>
                </enumeratedValue>
                <enumeratedValue>
                  <name />
                  <description>GPIO输出</description>
                  <value>1</value>
                </enumeratedValue>
                <enumeratedValue>
                  <name />
                  <description>Digital function</description>
                  <value>2</value>
                </enumeratedValue>
                <enumeratedValue>
                  <name />
                  <description>Analog function</description>
                  <value>3</value>
                </enumeratedValue>
              </enumeratedValues>
            </field>
            <field>
              <name>Px12FCR</name>
              <description>Px12FCR  field description</description>
              <bitRange>[25:24]</bitRange>
              <access>read-write</access>
              <enumeratedValues>
                <enumeratedValue>
                  <name />
                  <description>GPIO输入</description>
                  <value>0</value>
                </enumeratedValue>
                <enumeratedValue>
                  <name />
                  <description>GPIO输出</description>
                  <value>1</value>
                </enumeratedValue>
                <enumeratedValue>
                  <name />
                  <description>Digital function</description>
                  <value>2</value>
                </enumeratedValue>
                <enumeratedValue>
                  <name />
                  <description>Analog function</description>
                  <value>3</value>
                </enumeratedValue>
              </enumeratedValues>
            </field>
            <field>
              <name>Px11FCR</name>
              <description>Px11FCR  field description</description>
              <bitRange>[23:22]</bitRange>
              <access>read-write</access>
              <enumeratedValues>
                <enumeratedValue>
                  <name />
                  <description>GPIO输入</description>
                  <value>0</value>
                </enumeratedValue>
                <enumeratedValue>
                  <name />
                  <description>GPIO输出</description>
                  <value>1</value>
                </enumeratedValue>
                <enumeratedValue>
                  <name />
                  <description>Digital function</description>
                  <value>2</value>
                </enumeratedValue>
                <enumeratedValue>
                  <name />
                  <description>Analog function</description>
                  <value>3</value>
                </enumeratedValue>
              </enumeratedValues>
            </field>
            <field>
              <name>Px10FCR</name>
              <description>Px10FCR  field description</description>
              <bitRange>[21:20]</bitRange>
              <access>read-write</access>
              <enumeratedValues>
                <enumeratedValue>
                  <name />
                  <description>GPIO输入</description>
                  <value>0</value>
                </enumeratedValue>
                <enumeratedValue>
                  <name />
                  <description>GPIO输出</description>
                  <value>1</value>
                </enumeratedValue>
                <enumeratedValue>
                  <name />
                  <description>Digital function</description>
                  <value>2</value>
                </enumeratedValue>
                <enumeratedValue>
                  <name />
                  <description>Analog function</description>
                  <value>3</value>
                </enumeratedValue>
              </enumeratedValues>
            </field>
            <field>
              <name>Px9FCR</name>
              <description>Px9FCR  field description</description>
              <bitRange>[19:18]</bitRange>
              <access>read-write</access>
              <enumeratedValues>
                <enumeratedValue>
                  <name />
                  <description>GPIO输入</description>
                  <value>0</value>
                </enumeratedValue>
                <enumeratedValue>
                  <name />
                  <description>GPIO输出</description>
                  <value>1</value>
                </enumeratedValue>
                <enumeratedValue>
                  <name />
                  <description>Digital function</description>
                  <value>2</value>
                </enumeratedValue>
                <enumeratedValue>
                  <name />
                  <description>Analog function</description>
                  <value>3</value>
                </enumeratedValue>
              </enumeratedValues>
            </field>
            <field>
              <name>Px8FCR</name>
              <description>Px8FCR  field description</description>
              <bitRange>[17:16]</bitRange>
              <access>read-write</access>
              <enumeratedValues>
                <enumeratedValue>
                  <name />
                  <description>GPIO输入</description>
                  <value>0</value>
                </enumeratedValue>
                <enumeratedValue>
                  <name />
                  <description>GPIO输出</description>
                  <value>1</value>
                </enumeratedValue>
                <enumeratedValue>
                  <name />
                  <description>Digital function</description>
                  <value>2</value>
                </enumeratedValue>
                <enumeratedValue>
                  <name />
                  <description>Analog function</description>
                  <value>3</value>
                </enumeratedValue>
              </enumeratedValues>
            </field>
            <field>
              <name>Px7FCR</name>
              <description>Px7FCR  field description</description>
              <bitRange>[15:14]</bitRange>
              <access>read-write</access>
              <enumeratedValues>
                <enumeratedValue>
                  <name />
                  <description>GPIO输入</description>
                  <value>0</value>
                </enumeratedValue>
                <enumeratedValue>
                  <name />
                  <description>GPIO输出</description>
                  <value>1</value>
                </enumeratedValue>
                <enumeratedValue>
                  <name />
                  <description>Digital function</description>
                  <value>2</value>
                </enumeratedValue>
                <enumeratedValue>
                  <name />
                  <description>Analog function</description>
                  <value>3</value>
                </enumeratedValue>
              </enumeratedValues>
            </field>
            <field>
              <name>Px6FCR</name>
              <description>Px6FCR  field description</description>
              <bitRange>[13:12]</bitRange>
              <access>read-write</access>
              <enumeratedValues>
                <enumeratedValue>
                  <name />
                  <description>GPIO输入</description>
                  <value>0</value>
                </enumeratedValue>
                <enumeratedValue>
                  <name />
                  <description>GPIO输出</description>
                  <value>1</value>
                </enumeratedValue>
                <enumeratedValue>
                  <name />
                  <description>Digital function</description>
                  <value>2</value>
                </enumeratedValue>
                <enumeratedValue>
                  <name />
                  <description>Analog function</description>
                  <value>3</value>
                </enumeratedValue>
              </enumeratedValues>
            </field>
            <field>
              <name>Px5FCR</name>
              <description>Px5FCR  field description</description>
              <bitRange>[11:10]</bitRange>
              <access>read-write</access>
              <enumeratedValues>
                <enumeratedValue>
                  <name />
                  <description>GPIO输入</description>
                  <value>0</value>
                </enumeratedValue>
                <enumeratedValue>
                  <name />
                  <description>GPIO输出</description>
                  <value>1</value>
                </enumeratedValue>
                <enumeratedValue>
                  <name />
                  <description>Digital function</description>
                  <value>2</value>
                </enumeratedValue>
                <enumeratedValue>
                  <name />
                  <description>Analog function</description>
                  <value>3</value>
                </enumeratedValue>
              </enumeratedValues>
            </field>
            <field>
              <name>Px4FCR</name>
              <description>Px4FCR  field description</description>
              <bitRange>[9:8]</bitRange>
              <access>read-write</access>
              <enumeratedValues>
                <enumeratedValue>
                  <name />
                  <description>GPIO输入</description>
                  <value>0</value>
                </enumeratedValue>
                <enumeratedValue>
                  <name />
                  <description>GPIO输出</description>
                  <value>1</value>
                </enumeratedValue>
                <enumeratedValue>
                  <name />
                  <description>Digital function</description>
                  <value>2</value>
                </enumeratedValue>
                <enumeratedValue>
                  <name />
                  <description>Analog function</description>
                  <value>3</value>
                </enumeratedValue>
              </enumeratedValues>
            </field>
            <field>
              <name>Px3FCR</name>
              <description>Px3FCR  field description</description>
              <bitRange>[7:6]</bitRange>
              <access>read-write</access>
              <enumeratedValues>
                <enumeratedValue>
                  <name />
                  <description>GPIO输入</description>
                  <value>0</value>
                </enumeratedValue>
                <enumeratedValue>
                  <name />
                  <description>GPIO输出</description>
                  <value>1</value>
                </enumeratedValue>
                <enumeratedValue>
                  <name />
                  <description>Digital function</description>
                  <value>2</value>
                </enumeratedValue>
                <enumeratedValue>
                  <name />
                  <description>Analog function</description>
                  <value>3</value>
                </enumeratedValue>
              </enumeratedValues>
            </field>
            <field>
              <name>Px2FCR</name>
              <description>Px2FCR  field description</description>
              <bitRange>[5:4]</bitRange>
              <access>read-write</access>
              <enumeratedValues>
                <enumeratedValue>
                  <name />
                  <description>GPIO输入</description>
                  <value>0</value>
                </enumeratedValue>
                <enumeratedValue>
                  <name />
                  <description>GPIO输出</description>
                  <value>1</value>
                </enumeratedValue>
                <enumeratedValue>
                  <name />
                  <description>Digital function</description>
                  <value>2</value>
                </enumeratedValue>
                <enumeratedValue>
                  <name />
                  <description>Analog function</description>
                  <value>3</value>
                </enumeratedValue>
              </enumeratedValues>
            </field>
            <field>
              <name>Px1FCR</name>
              <description>Px1FCR  field description</description>
              <bitRange>[3:2]</bitRange>
              <access>read-write</access>
              <enumeratedValues>
                <enumeratedValue>
                  <name />
                  <description>GPIO输入</description>
                  <value>0</value>
                </enumeratedValue>
                <enumeratedValue>
                  <name />
                  <description>GPIO输出</description>
                  <value>1</value>
                </enumeratedValue>
                <enumeratedValue>
                  <name />
                  <description>Digital function</description>
                  <value>2</value>
                </enumeratedValue>
                <enumeratedValue>
                  <name />
                  <description>Analog function</description>
                  <value>3</value>
                </enumeratedValue>
              </enumeratedValues>
            </field>
            <field>
              <name>Px0FCR</name>
              <description>Px0FCR  field description</description>
              <bitRange>[1:0]</bitRange>
              <access>read-write</access>
              <enumeratedValues>
                <enumeratedValue>
                  <name />
                  <description>GPIO输入</description>
                  <value>0</value>
                </enumeratedValue>
                <enumeratedValue>
                  <name />
                  <description>GPIO输出</description>
                  <value>1</value>
                </enumeratedValue>
                <enumeratedValue>
                  <name />
                  <description>Digital function</description>
                  <value>2</value>
                </enumeratedValue>
                <enumeratedValue>
                  <name />
                  <description>Analog function</description>
                  <value>3</value>
                </enumeratedValue>
              </enumeratedValues>
            </field>
          </fields>
        </register>
        <register>
          <name>DO</name>
          <description>GPIOA Data Output Register</description>
          <addressOffset>0x10</addressOffset>
          <size>32</size>
          <access>read-write</access>
          <resetValue>0x00000000</resetValue>
          <fields>
            <field>
              <name>PxDO</name>
              <description>PxDO  field description</description>
              <bitRange>[15:0]</bitRange>
              <access>read-write</access>
              <enumeratedValues />
            </field>
          </fields>
        </register>
        <register>
          <name>DSET</name>
          <description>GPIOA Data Set Register</description>
          <addressOffset>0x14</addressOffset>
          <size>32</size>
          <access>read-write</access>
          <resetValue>0x00000000</resetValue>
          <fields>
            <field>
              <name>PxSET</name>
              <description>PxSET  field description</description>
              <bitRange>[15:0]</bitRange>
              <access>write-only</access>
              <enumeratedValues>
                <enumeratedValue>
                  <name />
                  <description>向PADSET写0x0000_8000，则PADO[15]置位，其余位保持不变。</description>
                  <value>0</value>
                </enumeratedValue>
              </enumeratedValues>
            </field>
          </fields>
        </register>
        <register>
          <name>DRST</name>
          <description>GPIOA Data Reset Register</description>
          <addressOffset>0x18</addressOffset>
          <size>32</size>
          <access>read-write</access>
          <resetValue>0x00000000</resetValue>
          <fields>
            <field>
              <name>PxRESET</name>
              <description>PxRESET  field description</description>
              <bitRange>[15:0]</bitRange>
              <access>write-only</access>
              <enumeratedValues>
                <enumeratedValue>
                  <name />
                  <description>向PADRST写0x0000_8000，则PADO[15]清零，其余位保持不变</description>
                  <value>0</value>
                </enumeratedValue>
              </enumeratedValues>
            </field>
          </fields>
        </register>
        <register>
          <name>DIN</name>
          <description>GPIOA Data Input Register</description>
          <addressOffset>0x1c</addressOffset>
          <size>32</size>
          <access>read-write</access>
          <resetValue>0x00000000</resetValue>
          <fields>
            <field>
              <name>PxDIN</name>
              <description>PxDIN  field description</description>
              <bitRange>[15:0]</bitRange>
              <access>read-only</access>
              <enumeratedValues />
            </field>
          </fields>
        </register>
        <register>
          <name>DFS</name>
          <description>GPIOA Digital Function Select</description>
          <addressOffset>0x20</addressOffset>
          <size>32</size>
          <access>read-write</access>
          <resetValue>0x00000000</resetValue>
          <fields>
            <field>
              <name>PxDFS</name>
              <description>PxDFS  field description</description>
              <bitRange>[15:0]</bitRange>
              <access>read-write</access>
              <enumeratedValues />
            </field>
          </fields>
        </register>
        <register>
          <name>ANEN</name>
          <description>GPIOAAnalog channel Enable Register</description>
          <addressOffset>0x28</addressOffset>
          <size>32</size>
          <access>read-write</access>
          <resetValue>0x00000000</resetValue>
          <fields>
            <field>
              <name>PxANEN</name>
              <description>PxANEN  field description</description>
              <bitRange>[15:0]</bitRange>
              <access>read-write</access>
              <enumeratedValues>
                <enumeratedValue>
                  <name />
                  <description>使能IO模拟开关</description>
                  <value>1</value>
                </enumeratedValue>
                <enumeratedValue>
                  <name />
                  <description>关闭IO模拟开关</description>
                  <value>0</value>
                </enumeratedValue>
              </enumeratedValues>
            </field>
          </fields>
        </register>
      </registers>
    </peripheral>
    <peripheral>
      <name>GPIOB</name>
      <description>GPIOB module information</description>
      <groupName>GPIO</groupName>
      <baseAddress>0x40000c40</baseAddress>
      <size>32</size>
      <access>read-write</access>
      <addressBlock>
        <offset>0</offset>
        <size>0x2c</size>
        <usage>registers</usage>
      </addressBlock>
      <registers>
        <register>
          <name>INEN</name>
          <description>GPIOB Input Enable Register</description>
          <addressOffset>0x0</addressOffset>
          <size>32</size>
          <access>read-write</access>
          <resetValue>0x00000000</resetValue>
          <fields>
            <field>
              <name>PxINEN</name>
              <description>PxINEN  field description</description>
              <bitRange>[15:0]</bitRange>
              <access>read-write</access>
              <enumeratedValues>
                <enumeratedValue>
                  <name />
                  <description>关闭输入使能</description>
                  <value>0</value>
                </enumeratedValue>
                <enumeratedValue>
                  <name />
                  <description>打开输入使能</description>
                  <value>1</value>
                </enumeratedValue>
              </enumeratedValues>
            </field>
          </fields>
        </register>
        <register>
          <name>PUEN</name>
          <description>GPIOB Pull-Up Enable Register</description>
          <addressOffset>0x4</addressOffset>
          <size>32</size>
          <access>read-write</access>
          <resetValue>0x00000000</resetValue>
          <fields>
            <field>
              <name>PxPUEN</name>
              <description>PxPUEN  field description</description>
              <bitRange>[15:0]</bitRange>
              <access>read-write</access>
              <enumeratedValues>
                <enumeratedValue>
                  <name />
                  <description>关闭上拉</description>
                  <value>0</value>
                </enumeratedValue>
                <enumeratedValue>
                  <name />
                  <description>使能上拉</description>
                  <value>1</value>
                </enumeratedValue>
              </enumeratedValues>
            </field>
          </fields>
        </register>
        <register>
          <name>ODEN</name>
          <description>GPIOB Opeb-Drain Enable Register</description>
          <addressOffset>0x8</addressOffset>
          <size>32</size>
          <access>read-write</access>
          <resetValue>0x00000000</resetValue>
          <fields>
            <field>
              <name>PxODEN</name>
              <description>PxODEN  field description</description>
              <bitRange>[15:0]</bitRange>
              <access>read-write</access>
              <enumeratedValues>
                <enumeratedValue>
                  <name />
                  <description>关闭开漏输出</description>
                  <value>0</value>
                </enumeratedValue>
                <enumeratedValue>
                  <name />
                  <description>使能开漏输出</description>
                  <value>1</value>
                </enumeratedValue>
              </enumeratedValues>
            </field>
          </fields>
        </register>
        <register>
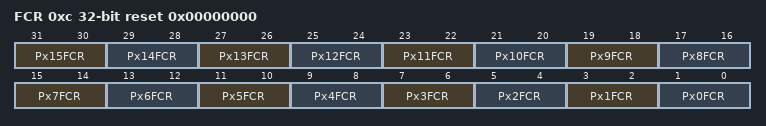
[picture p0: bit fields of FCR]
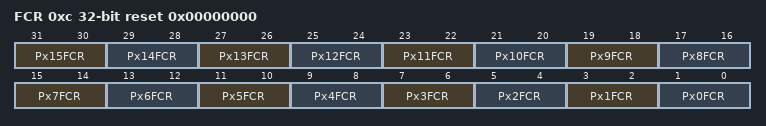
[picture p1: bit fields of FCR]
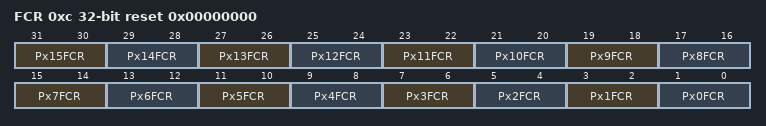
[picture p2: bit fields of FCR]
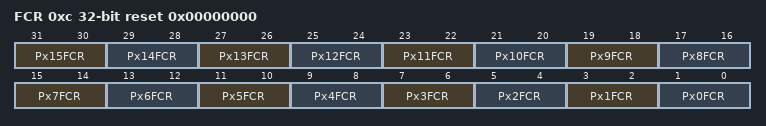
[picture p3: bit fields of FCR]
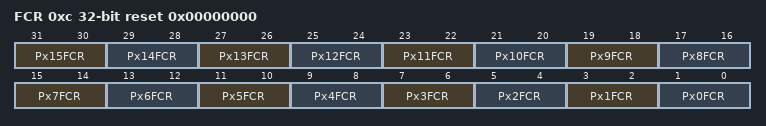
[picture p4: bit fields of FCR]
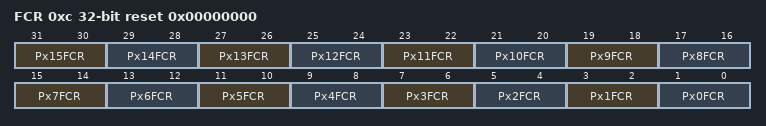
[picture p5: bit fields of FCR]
          <name>FCR</name>
          <description>GPIOB Function Control Register</description>
          <addressOffset>0xc</addressOffset>
          <size>32</size>
          <access>read-write</access>
          <resetValue>0x00000000</resetValue>
          <fields>
            <field>
              <name>Px15FCR</name>
              <description>Px15FCR  field description</description>
              <bitRange>[31:30]</bitRange>
              <access>read-write</access>
              <enumeratedValues>
                <enumeratedValue>
                  <name />
                  <description>GPIO输入</description>
                  <value>0</value>
                </enumeratedValue>
                <enumeratedValue>
                  <name />
                  <description>GPIO输出</description>
                  <value>1</value>
                </enumeratedValue>
                <enumeratedValue>
                  <name />
                  <description>Digital function</description>
                  <value>2</value>
                </enumeratedValue>
                <enumeratedValue>
                  <name />
                  <description>Analog function</description>
                  <value>3</value>
                </enumeratedValue>
              </enumeratedValues>
            </field>
            <field>
              <name>Px14FCR</name>
              <description>Px14FCR  field description</description>
              <bitRange>[29:28]</bitRange>
              <access>read-write</access>
              <enumeratedValues>
                <enumeratedValue>
                  <name />
                  <description>GPIO输入</description>
                  <value>0</value>
                </enumeratedValue>
                <enumeratedValue>
                  <name />
                  <description>GPIO输出</description>
                  <value>1</value>
                </enumeratedValue>
                <enumeratedValue>
                  <name />
                  <description>Digital function</description>
                  <value>2</value>
                </enumeratedValue>
                <enumeratedValue>
                  <name />
                  <description>Analog function</description>
                  <value>3</value>
                </enumeratedValue>
              </enumeratedValues>
            </field>
            <field>
              <name>Px13FCR</name>
              <description>Px13FCR  field description</description>
              <bitRange>[27:26]</bitRange>
              <access>read-write</access>
              <enumeratedValues>
                <enumeratedValue>
                  <name />
                  <description>GPIO输入</description>
                  <value>0</value>
                </enumeratedValue>
                <enumeratedValue>
                  <name />
                  <description>GPIO输出</description>
                  <value>1</value>
                </enumeratedValue>
                <enumeratedValue>
                  <name />
                  <description>Digital function</description>
                  <value>2</value>
                </enumeratedValue>
                <enumeratedValue>
                  <name />
                  <description>Analog function</description>
                  <value>3</value>
                </enumeratedValue>
              </enumeratedValues>
            </field>
            <field>
              <name>Px12FCR</name>
              <description>Px12FCR  field description</description>
              <bitRange>[25:24]</bitRange>
              <access>read-write</access>
              <enumeratedValues>
                <enumeratedValue>
                  <name />
                  <description>GPIO输入</description>
                  <value>0</value>
                </enumeratedValue>
                <enumeratedValue>
                  <name />
                  <description>GPIO输出</description>
                  <value>1</value>
                </enumeratedValue>
                <enumeratedValue>
                  <name />
                  <description>Digital function</description>
                  <value>2</value>
                </enumeratedValue>
                <enumeratedValue>
                  <name />
                  <description>Analog function</description>
                  <value>3</value>
                </enumeratedValue>
              </enumeratedValues>
            </field>
            <field>
              <name>Px11FCR</name>
              <description>Px11FCR  field description</description>
              <bitRange>[23:22]</bitRange>
              <access>read-write</access>
              <enumeratedValues>
                <enumeratedValue>
                  <name />
                  <description>GPIO输入</description>
                  <value>0</value>
                </enumeratedValue>
                <enumeratedValue>
                  <name />
                  <description>GPIO输出</description>
                  <value>1</value>
                </enumeratedValue>
                <enumeratedValue>
                  <name />
                  <description>Digital function</description>
                  <value>2</value>
                </enumeratedValue>
                <enumeratedValue>
                  <name />
                  <description>Analog function</description>
                  <value>3</value>
                </enumeratedValue>
              </enumeratedValues>
            </field>
            <field>
              <name>Px10FCR</name>
              <description>Px10FCR  field description</description>
              <bitRange>[21:20]</bitRange>
              <access>read-write</access>
              <enumeratedValues>
                <enumeratedValue>
                  <name />
                  <description>GPIO输入</description>
                  <value>0</value>
                </enumeratedValue>
                <enumeratedValue>
                  <name />
                  <description>GPIO输出</description>
                  <value>1</value>
                </enumeratedValue>
                <enumeratedValue>
                  <name />
                  <description>Digital function</description>
                  <value>2</value>
                </enumeratedValue>
                <enumeratedValue>
                  <name />
                  <description>Analog function</description>
                  <value>3</value>
                </enumeratedValue>
              </enumeratedValues>
            </field>
            <field>
              <name>Px9FCR</name>
              <description>Px9FCR  field description</description>
              <bitRange>[19:18]</bitRange>
              <access>read-write</access>
              <enumeratedValues>
                <enumeratedValue>
                  <name />
                  <description>GPIO输入</description>
                  <value>0</value>
                </enumeratedValue>
                <enumeratedValue>
                  <name />
                  <description>GPIO输出</description>
                  <value>1</value>
                </enumeratedValue>
                <enumeratedValue>
                  <name />
                  <description>Digital function</description>
                  <value>2</value>
                </enumeratedValue>
                <enumeratedValue>
                  <name />
                  <description>Analog function</description>
                  <value>3</value>
                </enumeratedValue>
              </enumeratedValues>
            </field>
            <field>
              <name>Px8FCR</name>
              <description>Px8FCR  field description</description>
              <bitRange>[17:16]</bitRange>
              <access>read-write</access>
              <enumeratedValues>
                <enumeratedValue>
                  <name />
                  <description>GPIO输入</description>
                  <value>0</value>
                </enumeratedValue>
                <enumeratedValue>
                  <name />
                  <description>GPIO输出</description>
                  <value>1</value>
                </enumeratedValue>
                <enumeratedValue>
                  <name />
                  <description>Digital function</description>
                  <value>2</value>
                </enumeratedValue>
                <enumeratedValue>
                  <name />
                  <description>Analog function</description>
                  <value>3</value>
                </enumeratedValue>
              </enumeratedValues>
            </field>
            <field>
              <name>Px7FCR</name>
              <description>Px7FCR  field description</description>
              <bitRange>[15:14]</bitRange>
              <access>read-write</access>
              <enumeratedValues>
                <enumeratedValue>
                  <name />
                  <description>GPIO输入</description>
                  <value>0</value>
                </enumeratedValue>
                <enumeratedValue>
                  <name />
                  <description>GPIO输出</description>
                  <value>1</value>
                </enumeratedValue>
                <enumeratedValue>
                  <name />
                  <description>Digital function</description>
                  <value>2</value>
                </enumeratedValue>
                <enumeratedValue>
                  <name />
                  <description>Analog function</description>
                  <value>3</value>
                </enumeratedValue>
              </enumeratedValues>
            </field>
            <field>
              <name>Px6FCR</name>
              <description>Px6FCR  field description</description>
              <bitRange>[13:12]</bitRange>
              <access>read-write</access>
              <enumeratedValues>
                <enumeratedValue>
                  <name />
                  <description>GPIO输入</description>
                  <value>0</value>
                </enumeratedValue>
                <enumeratedValue>
                  <name />
                  <description>GPIO输出</description>
                  <value>1</value>
                </enumeratedValue>
                <enumeratedValue>
                  <name />
                  <description>Digital function</description>
                  <value>2</value>
                </enumeratedValue>
                <enumeratedValue>
                  <name />
                  <description>Analog function</description>
                  <value>3</value>
                </enumeratedValue>
              </enumeratedValues>
            </field>
            <field>
              <name>Px5FCR</name>
              <description>Px5FCR  field description</description>
              <bitRange>[11:10]</bitRange>
              <access>read-write</access>
              <enumeratedValues>
                <enumeratedValue>
                  <name />
                  <description>GPIO输入</description>
                  <value>0</value>
                </enumeratedValue>
                <enumeratedValue>
                  <name />
                  <description>GPIO输出</description>
                  <value>1</value>
                </enumeratedValue>
                <enumeratedValue>
                  <name />
                  <description>Digital function</description>
                  <value>2</value>
                </enumeratedValue>
                <enumeratedValue>
                  <name />
                  <description>Analog function</description>
                  <value>3</value>
                </enumeratedValue>
              </enumeratedValues>
            </field>
            <field>
              <name>Px4FCR</name>
              <description>Px4FCR  field description</description>
              <bitRange>[9:8]</bitRange>
              <access>read-write</access>
              <enumeratedValues>
                <enumeratedValue>
                  <name />
                  <description>GPIO输入</description>
                  <value>0</value>
                </enumeratedValue>
                <enumeratedValue>
                  <name />
                  <description>GPIO输出</description>
                  <value>1</value>
                </enumeratedValue>
                <enumeratedValue>
                  <name />
                  <description>Digital function</description>
                  <value>2</value>
                </enumeratedValue>
                <enumeratedValue>
                  <name />
                  <description>Analog function</description>
                  <value>3</value>
                </enumeratedValue>
              </enumeratedValues>
            </field>
            <field>
              <name>Px3FCR</name>
              <description>Px3FCR  field description</description>
              <bitRange>[7:6]</bitRange>
              <access>read-write</access>
              <enumeratedValues>
                <enumeratedValue>
                  <name />
                  <description>GPIO输入</description>
                  <value>0</value>
                </enumeratedValue>
                <enumeratedValue>
                  <name />
                  <description>GPIO输出</description>
                  <value>1</value>
                </enumeratedValue>
                <enumeratedValue>
                  <name />
                  <description>Digital function</description>
                  <value>2</value>
                </enumeratedValue>
                <enumeratedValue>
                  <name />
                  <description>Analog function</description>
                  <value>3</value>
                </enumeratedValue>
              </enumeratedValues>
            </field>
            <field>
              <name>Px2FCR</name>
              <description>Px2FCR  field description</description>
              <bitRange>[5:4]</bitRange>
              <access>read-write</access>
              <enumeratedValues>
                <enumeratedValue>
                  <name />
                  <description>GPIO输入</description>
                  <value>0</value>
                </enumeratedValue>
                <enumeratedValue>
                  <name />
                  <description>GPIO输出</description>
                  <value>1</value>
                </enumeratedValue>
                <enumeratedValue>
                  <name />
                  <description>Digital function</description>
                  <value>2</value>
                </enumeratedValue>
                <enumeratedValue>
                  <name />
                  <description>Analog function</description>
                  <value>3</value>
                </enumeratedValue>
              </enumeratedValues>
            </field>
            <field>
              <name>Px1FCR</name>
              <description>Px1FCR  field description</description>
              <bitRange>[3:2]</bitRange>
              <access>read-write</access>
              <enumeratedValues>
                <enumeratedValue>
                  <name />
                  <description>GPIO输入</description>
                  <value>0</value>
                </enumeratedValue>
                <enumeratedValue>
                  <name />
                  <description>GPIO输出</description>
                  <value>1</value>
                </enumeratedValue>
                <enumeratedValue>
                  <name />
                  <description>Digital function</description>
                  <value>2</value>
                </enumeratedValue>
                <enumeratedValue>
                  <name />
                  <description>Analog function</description>
                  <value>3</value>
                </enumeratedValue>
              </enumeratedValues>
            </field>
            <field>
              <name>Px0FCR</name>
              <description>Px0FCR  field description</description>
              <bitRange>[1:0]</bitRange>
              <access>read-write</access>
              <enumeratedValues>
                <enumeratedValue>
                  <name />
                  <description>GPIO输入</description>
                  <value>0</value>
                </enumeratedValue>
                <enumeratedValue>
                  <name />
                  <description>GPIO输出</description>
                  <value>1</value>
                </enumeratedValue>
                <enumeratedValue>
                  <name />
                  <description>Digital function</description>
                  <value>2</value>
                </enumeratedValue>
                <enumeratedValue>
                  <name />
                  <description>Analog function</description>
                  <value>3</value>
                </enumeratedValue>
              </enumeratedValues>
            </field>
          </fields>
        </register>
        <register>
          <name>DO</name>
          <description>GPIOB Data Output Register</description>
          <addressOffset>0x10</addressOffset>
          <size>32</size>
          <access>read-write</access>
          <resetValue>0x00000000</resetValue>
          <fields>
            <field>
              <name>PxDO</name>
              <description>PxDO  field description</description>
              <bitRange>[15:0]</bitRange>
              <access>read-write</access>
              <enumeratedValues />
            </field>
          </fields>
        </register>
        <register>
          <name>DSET</name>
          <description>GPIOB Data Set Register</description>
          <addressOffset>0x14</addressOffset>
          <size>32</size>
          <access>read-write</access>
          <resetValue>0x00000000</resetValue>
          <fields>
            <field>
              <name>PxSET</name>
              <description>PxSET  field description</description>
              <bitRange>[15:0]</bitRange>
              <access>write-only</access>
              <enumeratedValues>
                <enumeratedValue>
                  <name />
                  <description>向PADSET写0x0000_8000，则PADO[15]置位，其余位保持不变。</description>
                  <value>0</value>
                </enumeratedValue>
              </enumeratedValues>
            </field>
          </fields>
        </register>
        <register>
          <name>DRST</name>
          <description>GPIOB Data Reset Register</description>
          <addressOffset>0x18</addressOffset>
          <size>32</size>
          <access>read-write</access>
          <resetValue>0x00000000</resetValue>
          <fields>
            <field>
              <name>PxRESET</name>
              <description>PxRESET  field description</description>
              <bitRange>[15:0]</bitRange>
              <access>write-only</access>
              <enumeratedValues>
                <enumeratedValue>
                  <name />
                  <description>向PADRST写0x0000_8000，则PADO[15]清零，其余位保持不变</description>
                  <value>0</value>
                </enumeratedValue>
              </enumeratedValues>
            </field>
          </fields>
        </register>
        <register>
          <name>DIN</name>
          <description>GPIOBData Input Register</description>
          <addressOffset>0x1c</addressOffset>
          <size>32</size>
          <access>read-write</access>
          <resetValue>0x00000000</resetValue>
          <fields>
            <field>
              <name>PxDIN</name>
              <description>PxDIN  field description</description>
              <bitRange>[15:0]</bitRange>
              <access>read-only</access>
              <enumeratedValues />
            </field>
          </fields>
        </register>
        <register>
          <name>DFS</name>
          <description>GPIOB Digital Function Select</description>
          <addressOffset>0x20</addressOffset>
          <size>32</size>
          <access>read-write</access>
          <resetValue>0x00000000</resetValue>
          <fields>
            <field>
              <name>PxDFS</name>
              <description>PxDFS  field description</description>
              <bitRange>[15:0]</bitRange>
              <access>read-write</access>
              <enumeratedValues />
            </field>
          </fields>
        </register>
        <register>
          <name>ANEN</name>
          <description>GPIOB Analog channel Enable Register</description>
          <addressOffset>0x28</addressOffset>
          <size>32</size>
          <access>read-write</access>
          <resetValue>0x00000000</resetValue>
          <fields>
            <field>
              <name>PxANEN</name>
              <description>PxANEN  field description</description>
              <bitRange>[15:0]</bitRange>
              <access>read-write</access>
              <enumeratedValues>
                <enumeratedValue>
                  <name />
                  <description>使能IO模拟开关</description>
                  <value>1</value>
                </enumeratedValue>
                <enumeratedValue>
                  <name />
                  <description>关闭IO模拟开关</description>
                  <value>0</value>
                </enumeratedValue>
              </enumeratedValues>
            </field>
          </fields>
        </register>
      </registers>
    </peripheral>
    <peripheral>
      <name>GPIOC</name>
      <description>GPIOC module information</description>
      <groupName>GPIO</groupName>
      <baseAddress>0x40000c80</baseAddress>
      <size>32</size>
      <access>read-write</access>
      <addressBlock>
        <offset>0</offset>
        <size>0x2c</size>
        <usage>registers</usage>
      </addressBlock>
      <registers>
        <register>
          <name>INEN</name>
          <description>GPIOC Input Enable Register</description>
          <addressOffset>0x0</addressOffset>
          <size>32</size>
          <access>read-write</access>
          <resetValue>0x00000000</resetValue>
          <fields>
            <field>
              <name>PxINEN</name>
              <description>PxINEN  field description</description>
              <bitRange>[15:0]</bitRange>
              <access>read-write</access>
              <enumeratedValues>
                <enumeratedValue>
                  <name />
                  <description>关闭输入使能</description>
                  <value>0</value>
                </enumeratedValue>
                <enumeratedValue>
                  <name />
                  <description>打开输入使能</description>
                  <value>1</value>
                </enumeratedValue>
              </enumeratedValues>
            </field>
          </fields>
        </register>
        <register>
          <name>PUEN</name>
          <description>GPIOC Pull-Up Enable Register</description>
          <addressOffset>0x4</addressOffset>
          <size>32</size>
          <access>read-write</access>
          <resetValue>0x00000000</resetValue>
          <fields>
            <field>
              <name>PxPUEN</name>
              <description>PxPUEN  field description</description>
              <bitRange>[15:0]</bitRange>
              <access>read-write</access>
              <enumeratedValues>
                <enumeratedValue>
                  <name />
                  <description>关闭上拉</description>
                  <value>0</value>
                </enumeratedValue>
                <enumeratedValue>
                  <name />
                  <description>使能上拉</description>
                  <value>1</value>
                </enumeratedValue>
              </enumeratedValues>
            </field>
          </fields>
        </register>
        <register>
          <name>ODEN</name>
          <description>GPIOC Opeb-Drain Enable Register</description>
          <addressOffset>0x8</addressOffset>
          <size>32</size>
          <access>read-write</access>
          <resetValue>0x00000000</resetValue>
          <fields>
            <field>
              <name>PxODEN</name>
              <description>PxODEN  field description</description>
              <bitRange>[15:0]</bitRange>
              <access>read-write</access>
              <enumeratedValues>
                <enumeratedValue>
                  <name />
                  <description>关闭开漏输出</description>
                  <value>0</value>
                </enumeratedValue>
                <enumeratedValue>
                  <name />
                  <description>使能开漏输出</description>
                  <value>1</value>
                </enumeratedValue>
              </enumeratedValues>
            </field>
          </fields>
        </register>
        <register>
          <name>FCR</name>
          <description>GPIOC Function Control Register</description>
          <addressOffset>0xc</addressOffset>
          <size>32</size>
          <access>read-write</access>
          <resetValue>0x00000000</resetValue>
          <fields>
            <field>
              <name>Px15FCR</name>
              <description>Px15FCR  field description</description>
              <bitRange>[31:30]</bitRange>
              <access>read-write</access>
              <enumeratedValues>
                <enumeratedValue>
                  <name />
                  <description>GPIO输入</description>
                  <value>0</value>
                </enumeratedValue>
                <enumeratedValue>
                  <name />
                  <description>GPIO输出</description>
                  <value>1</value>
                </enumeratedValue>
                <enumeratedValue>
                  <name />
                  <description>Digital function</description>
                  <value>2</value>
                </enumeratedValue>
                <enumeratedValue>
                  <name />
                  <description>Analog function</description>
                  <value>3</value>
                </enumeratedValue>
              </enumeratedValues>
            </field>
            <field>
              <name>Px14FCR</name>
              <description>Px14FCR  field description</description>
              <bitRange>[29:28]</bitRange>
              <access>read-write</access>
              <enumeratedValues>
                <enumeratedValue>
                  <name />
                  <description>GPIO输入</description>
                  <value>0</value>
                </enumeratedValue>
                <enumeratedValue>
                  <name />
                  <description>GPIO输出</description>
                  <value>1</value>
                </enumeratedValue>
                <enumeratedValue>
                  <name />
                  <description>Digital function</description>
                  <value>2</value>
                </enumeratedValue>
                <enumeratedValue>
                  <name />
                  <description>Analog function</description>
                  <value>3</value>
                </enumeratedValue>
              </enumeratedValues>
            </field>
            <field>
              <name>Px13FCR</name>
              <description>Px13FCR  field description</description>
              <bitRange>[27:26]</bitRange>
              <access>read-write</access>
              <enumeratedValues>
                <enumeratedValue>
                  <name />
                  <description>GPIO输入</description>
                  <value>0</value>
                </enumeratedValue>
                <enumeratedValue>
                  <name />
                  <description>GPIO输出</description>
                  <value>1</value>
                </enumeratedValue>
                <enumeratedValue>
                  <name />
                  <description>Digital function</description>
                  <value>2</value>
                </enumeratedValue>
                <enumeratedValue>
                  <name />
                  <description>Analog function</description>
                  <value>3</value>
                </enumeratedValue>
              </enumeratedValues>
            </field>
            <field>
              <name>Px12FCR</name>
              <description>Px12FCR  field description</description>
              <bitRange>[25:24]</bitRange>
              <access>read-write</access>
              <enumeratedValues>
                <enumeratedValue>
                  <name />
                  <description>GPIO输入</description>
                  <value>0</value>
                </enumeratedValue>
                <enumeratedValue>
                  <name />
                  <description>GPIO输出</description>
                  <value>1</value>
                </enumeratedValue>
                <enumeratedValue>
                  <name />
                  <description>Digital function</description>
                  <value>2</value>
                </enumeratedValue>
                <enumeratedValue>
                  <name />
                  <description>Analog function</description>
                  <value>3</value>
                </enumeratedValue>
              </enumeratedValues>
            </field>
            <field>
              <name>Px11FCR</name>
              <description>Px11FCR  field description</description>
              <bitRange>[23:22]</bitRange>
              <access>read-write</access>
              <enumeratedValues>
                <enumeratedValue>
                  <name />
                  <description>GPIO输入</description>
                  <value>0</value>
                </enumeratedValue>
                <enumeratedValue>
                  <name />
                  <description>GPIO输出</description>
                  <value>1</value>
                </enumeratedValue>
                <enumeratedValue>
                  <name />
                  <description>Digital function</description>
                  <value>2</value>
                </enumeratedValue>
                <enumeratedValue>
                  <name />
                  <description>Analog function</description>
                  <value>3</value>
                </enumeratedValue>
              </enumeratedValues>
            </field>
            <field>
              <name>Px10FCR</name>
              <description>Px10FCR  field description</description>
              <bitRange>[21:20]</bitRange>
              <access>read-write</access>
              <enumeratedValues>
                <enumeratedValue>
                  <name />
                  <description>GPIO输入</description>
                  <value>0</value>
                </enumeratedValue>
                <enumeratedValue>
                  <name />
                  <description>GPIO输出</description>
                  <value>1</value>
                </enumeratedValue>
                <enumeratedValue>
                  <name />
                  <description>Digital function</description>
                  <value>2</value>
                </enumeratedValue>
                <enumeratedValue>
                  <name />
                  <description>Analog function</description>
                  <value>3</value>
                </enumeratedValue>
              </enumeratedValues>
            </field>
            <field>
              <name>Px9FCR</name>
              <description>Px9FCR  field description</description>
              <bitRange>[19:18]</bitRange>
              <access>read-write</access>
              <enumeratedValues>
                <enumeratedValue>
                  <name />
                  <description>GPIO输入</description>
                  <value>0</value>
                </enumeratedValue>
                <enumeratedValue>
                  <name />
                  <description>GPIO输出</description>
                  <value>1</value>
                </enumeratedValue>
                <enumeratedValue>
                  <name />
                  <description>Digital function</description>
                  <value>2</value>
                </enumeratedValue>
                <enumeratedValue>
                  <name />
                  <description>Analog function</description>
                  <value>3</value>
                </enumeratedValue>
              </enumeratedValues>
            </field>
            <field>
              <name>Px8FCR</name>
              <description>Px8FCR  field description</description>
              <bitRange>[17:16]</bitRange>
              <access>read-write</access>
              <enumeratedValues>
                <enumeratedValue>
                  <name />
                  <description>GPIO输入</description>
                  <value>0</value>
                </enumeratedValue>
                <enumeratedValue>
                  <name />
                  <description>GPIO输出</description>
                  <value>1</value>
                </enumeratedValue>
                <enumeratedValue>
                  <name />
                  <description>Digital function</description>
                  <value>2</value>
                </enumeratedValue>
                <enumeratedValue>
                  <name />
                  <description>Analog function</description>
                  <value>3</value>
                </enumeratedValue>
              </enumeratedValues>
            </field>
            <field>
              <name>Px7FCR</name>
              <description>Px7FCR  field description</description>
              <bitRange>[15:14]</bitRange>
              <access>read-write</access>
              <enumeratedValues>
                <enumeratedValue>
                  <name />
                  <description>GPIO输入</description>
                  <value>0</value>
                </enumeratedValue>
                <enumeratedValue>
                  <name />
                  <description>GPIO输出</description>
                  <value>1</value>
                </enumeratedValue>
                <enumeratedValue>
                  <name />
                  <description>Digital function</description>
                  <value>2</value>
                </enumeratedValue>
                <enumeratedValue>
                  <name />
                  <description>Analog function</description>
                  <value>3</value>
                </enumeratedValue>
              </enumeratedValues>
            </field>
            <field>
              <name>Px6FCR</name>
              <description>Px6FCR  field description</description>
              <bitRange>[13:12]</bitRange>
              <access>read-write</access>
              <enumeratedValues>
                <enumeratedValue>
                  <name />
                  <description>GPIO输入</description>
                  <value>0</value>
                </enumeratedValue>
                <enumeratedValue>
                  <name />
                  <description>GPIO输出</description>
                  <value>1</value>
                </enumeratedValue>
                <enumeratedValue>
                  <name />
                  <description>Digital function</description>
                  <value>2</value>
                </enumeratedValue>
                <enumeratedValue>
                  <name />
                  <description>Analog function</description>
                  <value>3</value>
                </enumeratedValue>
              </enumeratedValues>
            </field>
            <field>
              <name>Px5FCR</name>
              <description>Px5FCR  field description</description>
              <bitRange>[11:10]</bitRange>
              <access>read-write</access>
              <enumeratedValues>
                <enumeratedValue>
                  <name />
                  <description>GPIO输入</description>
                  <value>0</value>
                </enumeratedValue>
                <enumeratedValue>
                  <name />
                  <description>GPIO输出</description>
                  <value>1</value>
                </enumeratedValue>
                <enumeratedValue>
                  <name />
                  <description>Digital function</description>
                  <value>2</value>
                </enumeratedValue>
                <enumeratedValue>
                  <name />
                  <description>Analog function</description>
                  <value>3</value>
                </enumeratedValue>
              </enumeratedValues>
            </field>
            <field>
              <name>Px4FCR</name>
              <description>Px4FCR  field description</description>
              <bitRange>[9:8]</bitRange>
              <access>read-write</access>
              <enumeratedValues>
                <enumeratedValue>
                  <name />
                  <description>GPIO输入</description>
                  <value>0</value>
                </enumeratedValue>
                <enumeratedValue>
                  <name />
                  <description>GPIO输出</description>
                  <value>1</value>
                </enumeratedValue>
                <enumeratedValue>
                  <name />
                  <description>Digital function</description>
                  <value>2</value>
                </enumeratedValue>
                <enumeratedValue>
                  <name />
                  <description>Analog function</description>
                  <value>3</value>
                </enumeratedValue>
              </enumeratedValues>
            </field>
            <field>
              <name>Px3FCR</name>
              <description>Px3FCR  field description</description>
              <bitRange>[7:6]</bitRange>
              <access>read-write</access>
              <enumeratedValues>
                <enumeratedValue>
                  <name />
                  <description>GPIO输入</description>
                  <value>0</value>
                </enumeratedValue>
                <enumeratedValue>
                  <name />
                  <description>GPIO输出</description>
                  <value>1</value>
                </enumeratedValue>
                <enumeratedValue>
                  <name />
                  <description>Digital function</description>
                  <value>2</value>
                </enumeratedValue>
                <enumeratedValue>
                  <name />
                  <description>Analog function</description>
                  <value>3</value>
                </enumeratedValue>
              </enumeratedValues>
            </field>
            <field>
              <name>Px2FCR</name>
              <description>Px2FCR  field description</description>
              <bitRange>[5:4]</bitRange>
              <access>read-write</access>
              <enumeratedValues>
                <enumeratedValue>
                  <name />
                  <description>GPIO输入</description>
                  <value>0</value>
                </enumeratedValue>
                <enumeratedValue>
                  <name />
                  <description>GPIO输出</description>
                  <value>1</value>
                </enumeratedValue>
                <enumeratedValue>
                  <name />
                  <description>Digital function</description>
                  <value>2</value>
                </enumeratedValue>
                <enumeratedValue>
                  <name />
                  <description>Analog function</description>
                  <value>3</value>
                </enumeratedValue>
              </enumeratedValues>
            </field>
            <field>
              <name>Px1FCR</name>
              <description>Px1FCR  field description</description>
              <bitRange>[3:2]</bitRange>
              <access>read-write</access>
              <enumeratedValues>
                <enumeratedValue>
                  <name />
                  <description>GPIO输入</description>
                  <value>0</value>
                </enumeratedValue>
                <enumeratedValue>
                  <name />
                  <description>GPIO输出</description>
                  <value>1</value>
                </enumeratedValue>
                <enumeratedValue>
                  <name />
                  <description>Digital function</description>
                  <value>2</value>
                </enumeratedValue>
                <enumeratedValue>
                  <name />
                  <description>Analog function</description>
                  <value>3</value>
                </enumeratedValue>
              </enumeratedValues>
            </field>
            <field>
              <name>Px0FCR</name>
              <description>Px0FCR  field description</description>
              <bitRange>[1:0]</bitRange>
              <access>read-write</access>
              <enumeratedValues>
                <enumeratedValue>
                  <name />
                  <description>GPIO输入</description>
                  <value>0</value>
                </enumeratedValue>
                <enumeratedValue>
                  <name />
                  <description>GPIO输出</description>
                  <value>1</value>
                </enumeratedValue>
                <enumeratedValue>
                  <name />
                  <description>Digital function</description>
                  <value>2</value>
                </enumeratedValue>
                <enumeratedValue>
                  <name />
                  <description>Analog function</description>
                  <value>3</value>
                </enumeratedValue>
              </enumeratedValues>
            </field>
          </fields>
        </register>
        <register>
          <name>DO</name>
          <description>GPIOC Data Output Register</description>
          <addressOffset>0x10</addressOffset>
          <size>32</size>
          <access>read-write</access>
          <resetValue>0x00000000</resetValue>
          <fields>
            <field>
              <name>PxDO</name>
              <description>PxDO  field description</description>
              <bitRange>[15:0]</bitRange>
              <access>read-write</access>
              <enumeratedValues />
            </field>
          </fields>
        </register>
        <register>
          <name>DSET</name>
          <description>GPIOC Data Set Register</description>
          <addressOffset>0x14</addressOffset>
          <size>32</size>
          <access>read-write</access>
          <resetValue>0x00000000</resetValue>
          <fields>
            <field>
              <name>PxSET</name>
              <description>PxSET  field description</description>
              <bitRange>[15:0]</bitRange>
              <access>write-only</access>
              <enumeratedValues>
                <enumeratedValue>
                  <name />
                  <description>向PADSET写0x0000_8000，则PADO[15]置位，其余位保持不变。</description>
                  <value>0</value>
                </enumeratedValue>
              </enumeratedValues>
            </field>
          </fields>
        </register>
        <register>
          <name>DRST</name>
          <description>GPIOC Data Reset Register</description>
          <addressOffset>0x18</addressOffset>
          <size>32</size>
          <access>read-write</access>
          <resetValue>0x00000000</resetValue>
          <fields>
            <field>
              <name>PxRESET</name>
              <description>PxRESET  field description</description>
              <bitRange>[15:0]</bitRange>
              <access>write-only</access>
              <enumeratedValues>
                <enumeratedValue>
                  <name />
                  <description>向PADRST写0x0000_8000，则PADO[15]清零，其余位保持不变</description>
                  <value>0</value>
                </enumeratedValue>
              </enumeratedValues>
            </field>
          </fields>
        </register>
        <register>
          <name>DIN</name>
          <description>GPIOC Data Input Register</description>
          <addressOffset>0x1c</addressOffset>
          <size>32</size>
          <access>read-write</access>
          <resetValue>0x00000000</resetValue>
          <fields>
            <field>
              <name>PxDIN</name>
              <description>PxDIN  field description</description>
              <bitRange>[15:0]</bitRange>
              <access>read-only</access>
              <enumeratedValues />
            </field>
          </fields>
        </register>
        <register>
          <name>DFS</name>
          <description>GPIOC Digital Function Select</description>
          <addressOffset>0x20</addressOffset>
          <size>32</size>
          <access>read-write</access>
          <resetValue>0x00000000</resetValue>
          <fields>
            <field>
              <name>PxDFS</name>
              <description>PxDFS  field description</description>
              <bitRange>[15:0]</bitRange>
              <access>read-write</access>
              <enumeratedValues />
            </field>
          </fields>
        </register>
        <register>
          <name>ANEN</name>
          <description>GPIOC Analog channel Enable Register</description>
          <addressOffset>0x28</addressOffset>
          <size>32</size>
          <access>read-write</access>
          <resetValue>0x00000000</resetValue>
          <fields>
            <field>
              <name>PxANEN</name>
              <description>PxANEN  field description</description>
              <bitRange>[15:0]</bitRange>
              <access>read-write</access>
              <enumeratedValues>
                <enumeratedValue>
                  <name />
                  <description>使能IO模拟开关</description>
                  <value>1</value>
                </enumeratedValue>
                <enumeratedValue>
                  <name />
                  <description>关闭IO模拟开关</description>
                  <value>0</value>
                </enumeratedValue>
              </enumeratedValues>
            </field>
          </fields>
        </register>
      </registers>
    </peripheral>
    <peripheral>
      <name>GPIOD</name>
      <description>GPIOD module information</description>
      <groupName>GPIO</groupName>
      <baseAddress>0x40000cc0</baseAddress>
      <size>32</size>
      <access>read-write</access>
      <addressBlock>
        <offset>0</offset>
        <size>0x2c</size>
        <usage>registers</usage>
      </addressBlock>
      <registers>
        <register>
          <name>INEN</name>
          <description>GPIOD Input Enable Register</description>
          <addressOffset>0x0</addressOffset>
          <size>32</size>
          <access>read-write</access>
          <resetValue>0x00000000</resetValue>
          <fields>
            <field>
              <name>PxINEN</name>
              <description>PxINEN  field description</description>
              <bitRange>[15:0]</bitRange>
              <access>read-write</access>
              <enumeratedValues>
                <enumeratedValue>
                  <name />
                  <description>关闭输入使能</description>
                  <value>0</value>
                </enumeratedValue>
                <enumeratedValue>
                  <name />
                  <description>打开输入使能</description>
                  <value>1</value>
                </enumeratedValue>
              </enumeratedValues>
            </field>
          </fields>
        </register>
        <register>
          <name>PUEN</name>
          <description>GPIOD Pull-Up Enable Register</description>
          <addressOffset>0x4</addressOffset>
          <size>32</size>
          <access>read-write</access>
          <resetValue>0x00000000</resetValue>
          <fields>
            <field>
              <name>PxPUEN</name>
              <description>PxPUEN  field description</description>
              <bitRange>[15:0]</bitRange>
              <access>read-write</access>
              <enumeratedValues>
                <enumeratedValue>
                  <name />
                  <description>关闭上拉</description>
                  <value>0</value>
                </enumeratedValue>
                <enumeratedValue>
                  <name />
                  <description>使能上拉</description>
                  <value>1</value>
                </enumeratedValue>
              </enumeratedValues>
            </field>
          </fields>
        </register>
        <register>
          <name>ODEN</name>
          <description>GPIOD Opeb-Drain Enable Register</description>
          <addressOffset>0x8</addressOffset>
          <size>32</size>
          <access>read-write</access>
          <resetValue>0x00000000</resetValue>
          <fields>
            <field>
              <name>PxODEN</name>
              <description>PxODEN  field description</description>
              <bitRange>[15:0]</bitRange>
              <access>read-write</access>
              <enumeratedValues>
                <enumeratedValue>
                  <name />
                  <description>关闭开漏输出</description>
                  <value>0</value>
                </enumeratedValue>
                <enumeratedValue>
                  <name />
                  <description>使能开漏输出</description>
                  <value>1</value>
                </enumeratedValue>
              </enumeratedValues>
            </field>
          </fields>
        </register>
        <register>
          <name>FCR</name>
          <description>GPIOD Function Control Register</description>
          <addressOffset>0xc</addressOffset>
          <size>32</size>
          <access>read-write</access>
          <resetValue>0x00000000</resetValue>
          <fields>
            <field>
              <name>Px15FCR</name>
              <description>Px15FCR  field description</description>
              <bitRange>[31:30]</bitRange>
              <access>read-write</access>
              <enumeratedValues>
                <enumeratedValue>
                  <name />
                  <description>GPIO输入</description>
                  <value>0</value>
                </enumeratedValue>
                <enumeratedValue>
                  <name />
                  <description>GPIO输出</description>
                  <value>1</value>
                </enumeratedValue>
                <enumeratedValue>
                  <name />
                  <description>Digital function</description>
                  <value>2</value>
                </enumeratedValue>
                <enumeratedValue>
                  <name />
                  <description>Analog function</description>
                  <value>3</value>
                </enumeratedValue>
              </enumeratedValues>
            </field>
            <field>
              <name>Px14FCR</name>
              <description>Px14FCR  field description</description>
              <bitRange>[29:28]</bitRange>
              <access>read-write</access>
              <enumeratedValues>
                <enumeratedValue>
                  <name />
                  <description>GPIO输入</description>
                  <value>0</value>
                </enumeratedValue>
                <enumeratedValue>
                  <name />
                  <description>GPIO输出</description>
                  <value>1</value>
                </enumeratedValue>
                <enumeratedValue>
                  <name />
                  <description>Digital function</description>
                  <value>2</value>
                </enumeratedValue>
                <enumeratedValue>
                  <name />
                  <description>Analog function</description>
                  <value>3</value>
                </enumeratedValue>
              </enumeratedValues>
            </field>
            <field>
              <name>Px13FCR</name>
              <description>Px13FCR  field description</description>
              <bitRange>[27:26]</bitRange>
              <access>read-write</access>
              <enumeratedValues>
                <enumeratedValue>
                  <name />
                  <description>GPIO输入</description>
                  <value>0</value>
                </enumeratedValue>
                <enumeratedValue>
                  <name />
                  <description>GPIO输出</description>
                  <value>1</value>
                </enumeratedValue>
                <enumeratedValue>
                  <name />
                  <description>Digital function</description>
                  <value>2</value>
                </enumeratedValue>
                <enumeratedValue>
                  <name />
                  <description>Analog function</description>
                  <value>3</value>
                </enumeratedValue>
              </enumeratedValues>
            </field>
            <field>
              <name>Px12FCR</name>
              <description>Px12FCR  field description</description>
              <bitRange>[25:24]</bitRange>
              <access>read-write</access>
              <enumeratedValues>
                <enumeratedValue>
                  <name />
                  <description>GPIO输入</description>
                  <value>0</value>
                </enumeratedValue>
                <enumeratedValue>
                  <name />
                  <description>GPIO输出</description>
                  <value>1</value>
                </enumeratedValue>
                <enumeratedValue>
                  <name />
                  <description>Digital function</description>
                  <value>2</value>
                </enumeratedValue>
                <enumeratedValue>
                  <name />
                  <description>Analog function</description>
                  <value>3</value>
                </enumeratedValue>
              </enumeratedValues>
            </field>
            <field>
              <name>Px11FCR</name>
              <description>Px11FCR  field description</description>
              <bitRange>[23:22]</bitRange>
              <access>read-write</access>
              <enumeratedValues>
                <enumeratedValue>
                  <name />
                  <description>GPIO输入</description>
                  <value>0</value>
                </enumeratedValue>
                <enumeratedValue>
                  <name />
                  <description>GPIO输出</description>
                  <value>1</value>
                </enumeratedValue>
                <enumeratedValue>
                  <name />
                  <description>Digital function</description>
                  <value>2</value>
                </enumeratedValue>
                <enumeratedValue>
                  <name />
                  <description>Analog function</description>
                  <value>3</value>
                </enumeratedValue>
              </enumeratedValues>
            </field>
            <field>
              <name>Px10FCR</name>
              <description>Px10FCR  field description</description>
              <bitRange>[21:20]</bitRange>
              <access>read-write</access>
              <enumeratedValues>
                <enumeratedValue>
                  <name />
                  <description>GPIO输入</description>
                  <value>0</value>
                </enumeratedValue>
                <enumeratedValue>
                  <name />
                  <description>GPIO输出</description>
                  <value>1</value>
                </enumeratedValue>
                <enumeratedValue>
                  <name />
                  <description>Digital function</description>
                  <value>2</value>
                </enumeratedValue>
                <enumeratedValue>
                  <name />
                  <description>Analog function</description>
                  <value>3</value>
                </enumeratedValue>
              </enumeratedValues>
            </field>
            <field>
              <name>Px9FCR</name>
              <description>Px9FCR  field description</description>
              <bitRange>[19:18]</bitRange>
              <access>read-write</access>
              <enumeratedValues>
                <enumeratedValue>
                  <name />
                  <description>GPIO输入</description>
                  <value>0</value>
                </enumeratedValue>
                <enumeratedValue>
                  <name />
                  <description>GPIO输出</description>
                  <value>1</value>
                </enumeratedValue>
                <enumeratedValue>
                  <name />
                  <description>Digital function</description>
                  <value>2</value>
                </enumeratedValue>
                <enumeratedValue>
                  <name />
                  <description>Analog function</description>
                  <value>3</value>
                </enumeratedValue>
              </enumeratedValues>
            </field>
            <field>
              <name>Px8FCR</name>
              <description>Px8FCR  field description</description>
              <bitRange>[17:16]</bitRange>
              <access>read-write</access>
              <enumeratedValues>
                <enumeratedValue>
                  <name />
                  <description>GPIO输入</description>
                  <value>0</value>
                </enumeratedValue>
                <enumeratedValue>
                  <name />
                  <description>GPIO输出</description>
                  <value>1</value>
                </enumeratedValue>
                <enumeratedValue>
                  <name />
                  <description>Digital function</description>
                  <value>2</value>
                </enumeratedValue>
                <enumeratedValue>
                  <name />
                  <description>Analog function</description>
                  <value>3</value>
                </enumeratedValue>
              </enumeratedValues>
            </field>
            <field>
              <name>Px7FCR</name>
              <description>Px7FCR  field description</description>
              <bitRange>[15:14]</bitRange>
              <access>read-write</access>
              <enumeratedValues>
                <enumeratedValue>
                  <name />
                  <description>GPIO输入</description>
                  <value>0</value>
                </enumeratedValue>
                <enumeratedValue>
                  <name />
                  <description>GPIO输出</description>
                  <value>1</value>
                </enumeratedValue>
                <enumeratedValue>
                  <name />
                  <description>Digital function</description>
                  <value>2</value>
                </enumeratedValue>
                <enumeratedValue>
                  <name />
                  <description>Analog function</description>
                  <value>3</value>
                </enumeratedValue>
              </enumeratedValues>
            </field>
            <field>
              <name>Px6FCR</name>
              <description>Px6FCR  field description</description>
              <bitRange>[13:12]</bitRange>
              <access>read-write</access>
              <enumeratedValues>
                <enumeratedValue>
                  <name />
                  <description>GPIO输入</description>
                  <value>0</value>
                </enumeratedValue>
                <enumeratedValue>
                  <name />
                  <description>GPIO输出</description>
                  <value>1</value>
                </enumeratedValue>
                <enumeratedValue>
                  <name />
                  <description>Digital function</description>
                  <value>2</value>
                </enumeratedValue>
                <enumeratedValue>
                  <name />
                  <description>Analog function</description>
                  <value>3</value>
                </enumeratedValue>
              </enumeratedValues>
            </field>
            <field>
              <name>Px5FCR</name>
              <description>Px5FCR  field description</description>
              <bitRange>[11:10]</bitRange>
              <access>read-write</access>
              <enumeratedValues>
                <enumeratedValue>
                  <name />
                  <description>GPIO输入</description>
                  <value>0</value>
                </enumeratedValue>
                <enumeratedValue>
                  <name />
                  <description>GPIO输出</description>
                  <value>1</value>
                </enumeratedValue>
                <enumeratedValue>
                  <name />
                  <description>Digital function</description>
                  <value>2</value>
                </enumeratedValue>
                <enumeratedValue>
                  <name />
                  <description>Analog function</description>
                  <value>3</value>
                </enumeratedValue>
              </enumeratedValues>
            </field>
            <field>
              <name>Px4FCR</name>
              <description>Px4FCR  field description</description>
              <bitRange>[9:8]</bitRange>
              <access>read-write</access>
              <enumeratedValues>
                <enumeratedValue>
                  <name />
                  <description>GPIO输入</description>
                  <value>0</value>
                </enumeratedValue>
                <enumeratedValue>
                  <name />
                  <description>GPIO输出</description>
                  <value>1</value>
                </enumeratedValue>
                <enumeratedValue>
                  <name />
                  <description>Digital function</description>
                  <value>2</value>
                </enumeratedValue>
                <enumeratedValue>
                  <name />
                  <description>Analog function</description>
                  <value>3</value>
                </enumeratedValue>
              </enumeratedValues>
            </field>
            <field>
              <name>Px3FCR</name>
              <description>Px3FCR  field description</description>
              <bitRange>[7:6]</bitRange>
              <access>read-write</access>
              <enumeratedValues>
                <enumeratedValue>
                  <name />
                  <description>GPIO输入</description>
                  <value>0</value>
                </enumeratedValue>
                <enumeratedValue>
                  <name />
                  <description>GPIO输出</description>
                  <value>1</value>
                </enumeratedValue>
                <enumeratedValue>
                  <name />
                  <description>Digital function</description>
                  <value>2</value>
                </enumeratedValue>
                <enumeratedValue>
                  <name />
                  <description>Analog function</description>
                  <value>3</value>
                </enumeratedValue>
              </enumeratedValues>
            </field>
            <field>
              <name>Px2FCR</name>
              <description>Px2FCR  field description</description>
              <bitRange>[5:4]</bitRange>
              <access>read-write</access>
              <enumeratedValues>
                <enumeratedValue>
                  <name />
                  <description>GPIO输入</description>
                  <value>0</value>
                </enumeratedValue>
                <enumeratedValue>
                  <name />
                  <description>GPIO输出</description>
                  <value>1</value>
                </enumeratedValue>
                <enumeratedValue>
                  <name />
                  <description>Digital function</description>
                  <value>2</value>
                </enumeratedValue>
                <enumeratedValue>
                  <name />
                  <description>Analog function</description>
                  <value>3</value>
                </enumeratedValue>
              </enumeratedValues>
            </field>
            <field>
              <name>Px1FCR</name>
              <description>Px1FCR  field description</description>
              <bitRange>[3:2]</bitRange>
              <access>read-write</access>
              <enumeratedValues>
                <enumeratedValue>
                  <name />
                  <description>GPIO输入</description>
                  <value>0</value>
                </enumeratedValue>
                <enumeratedValue>
                  <name />
                  <description>GPIO输出</description>
                  <value>1</value>
                </enumeratedValue>
                <enumeratedValue>
                  <name />
                  <description>Digital function</description>
                  <value>2</value>
                </enumeratedValue>
                <enumeratedValue>
                  <name />
                  <description>Analog function</description>
                  <value>3</value>
                </enumeratedValue>
              </enumeratedValues>
            </field>
            <field>
              <name>Px0FCR</name>
              <description>Px0FCR  field description</description>
              <bitRange>[1:0]</bitRange>
              <access>read-write</access>
              <enumeratedValues>
                <enumeratedValue>
                  <name />
                  <description>GPIO输入</description>
                  <value>0</value>
                </enumeratedValue>
                <enumeratedValue>
                  <name />
                  <description>GPIO输出</description>
                  <value>1</value>
                </enumeratedValue>
                <enumeratedValue>
                  <name />
                  <description>Digital function</description>
                  <value>2</value>
                </enumeratedValue>
                <enumeratedValue>
                  <name />
                  <description>Analog function</description>
                  <value>3</value>
                </enumeratedValue>
              </enumeratedValues>
            </field>
          </fields>
        </register>
        <register>
          <name>DO</name>
          <description>GPIOD Data Output Register</description>
          <addressOffset>0x10</addressOffset>
          <size>32</size>
          <access>read-write</access>
          <resetValue>0x00000000</resetValue>
          <fields>
            <field>
              <name>PxDO</name>
              <description>PxDO  field description</description>
              <bitRange>[15:0]</bitRange>
              <access>read-write</access>
              <enumeratedValues />
            </field>
          </fields>
        </register>
        <register>
          <name>DSET</name>
          <description>GPIOD Data Set Register</description>
          <addressOffset>0x14</addressOffset>
          <size>32</size>
          <access>read-write</access>
          <resetValue>0x00000000</resetValue>
          <fields>
            <field>
              <name>PxSET</name>
              <description>PxSET  field description</description>
              <bitRange>[15:0]</bitRange>
              <access>write-only</access>
              <enumeratedValues>
                <enumeratedValue>
                  <name />
                  <description>向PADSET写0x0000_8000，则PADO[15]置位，其余位保持不变。</description>
                  <value>0</value>
                </enumeratedValue>
              </enumeratedValues>
            </field>
          </fields>
        </register>
        <register>
          <name>DRST</name>
          <description>GPIOD Data Reset Register</description>
          <addressOffset>0x18</addressOffset>
          <size>32</size>
          <access>read-write</access>
          <resetValue>0x00000000</resetValue>
          <fields>
            <field>
              <name>PxRESET</name>
              <description>PxRESET  field description</description>
              <bitRange>[15:0]</bitRange>
              <access>write-only</access>
              <enumeratedValues>
                <enumeratedValue>
                  <name />
                  <description>向PADRST写0x0000_8000，则PADO[15]清零，其余位保持不变</description>
                  <value>0</value>
                </enumeratedValue>
              </enumeratedValues>
            </field>
          </fields>
        </register>
        <register>
          <name>DIN</name>
          <description>GPIOD Data Input Register</description>
          <addressOffset>0x1c</addressOffset>
          <size>32</size>
          <access>read-write</access>
          <resetValue>0x00000000</resetValue>
          <fields>
            <field>
              <name>PxDIN</name>
              <description>PxDIN  field description</description>
              <bitRange>[15:0]</bitRange>
              <access>read-only</access>
              <enumeratedValues />
            </field>
          </fields>
        </register>
        <register>
          <name>DFS</name>
          <description>GPIOD Digital Function Select</description>
          <addressOffset>0x20</addressOffset>
          <size>32</size>
          <access>read-write</access>
          <resetValue>0x00000000</resetValue>
          <fields>
            <field>
              <name>PxDFS</name>
              <description>PxDFS  field description</description>
              <bitRange>[15:0]</bitRange>
              <access>read-write</access>
              <enumeratedValues />
            </field>
          </fields>
        </register>
        <register>
          <name>ANEN</name>
          <description>GPIOD Analog channel Enable Register</description>
          <addressOffset>0x28</addressOffset>
          <size>32</size>
          <access>read-write</access>
          <resetValue>0x00000000</resetValue>
          <fields>
            <field>
              <name>PxANEN</name>
              <description>PxANEN  field description</description>
              <bitRange>[15:0]</bitRange>
              <access>read-write</access>
              <enumeratedValues>
                <enumeratedValue>
                  <name />
                  <description>使能IO模拟开关</description>
                  <value>1</value>
                </enumeratedValue>
                <enumeratedValue>
                  <name />
                  <description>关闭IO模拟开关</description>
                  <value>0</value>
                </enumeratedValue>
              </enumeratedValues>
            </field>
          </fields>
        </register>
      </registers>
    </peripheral>
    <peripheral>
      <name>GPIOE</name>
      <description>GPIOE module information</description>
      <groupName>GPIO</groupName>
      <baseAddress>0x40000d00</baseAddress>
      <size>32</size>
      <access>read-write</access>
      <addressBlock>
        <offset>0</offset>
        <size>0x2c</size>
        <usage>registers</usage>
      </addressBlock>
      <registers>
        <register>
          <name>INEN</name>
          <description>GPIOE Input Enable Register</description>
          <addressOffset>0x0</addressOffset>
          <size>32</size>
          <access>read-write</access>
          <resetValue>0x00000000</resetValue>
          <fields>
            <field>
              <name>PxINEN</name>
              <description>PxINEN  field description</description>
              <bitRange>[15:0]</bitRange>
              <access>read-write</access>
              <enumeratedValues>
                <enumeratedValue>
                  <name />
                  <description>关闭输入使能</description>
                  <value>0</value>
                </enumeratedValue>
                <enumeratedValue>
                  <name />
                  <description>打开输入使能</description>
                  <value>1</value>
                </enumeratedValue>
              </enumeratedValues>
            </field>
          </fields>
        </register>
        <register>
          <name>PUEN</name>
          <description>GPIOE Pull-Up Enable Register</description>
          <addressOffset>0x4</addressOffset>
          <size>32</size>
          <access>read-write</access>
          <resetValue>0x00000000</resetValue>
          <fields>
            <field>
              <name>PxPUEN</name>
              <description>PxPUEN  field description</description>
              <bitRange>[15:0]</bitRange>
              <access>read-write</access>
              <enumeratedValues>
                <enumeratedValue>
                  <name />
                  <description>关闭上拉</description>
                  <value>0</value>
                </enumeratedValue>
                <enumeratedValue>
                  <name />
                  <description>使能上拉</description>
                  <value>1</value>
                </enumeratedValue>
              </enumeratedValues>
            </field>
          </fields>
        </register>
        <register>
          <name>ODEN</name>
          <description>GPIOE Opeb-Drain Enable Register</description>
          <addressOffset>0x8</addressOffset>
          <size>32</size>
          <access>read-write</access>
          <resetValue>0x00000000</resetValue>
          <fields>
            <field>
              <name>PxODEN</name>
              <description>PxODEN  field description</description>
              <bitRange>[15:0]</bitRange>
              <access>read-write</access>
              <enumeratedValues>
                <enumeratedValue>
                  <name />
                  <description>关闭开漏输出</description>
                  <value>0</value>
                </enumeratedValue>
                <enumeratedValue>
                  <name />
                  <description>使能开漏输出</description>
                  <value>1</value>
                </enumeratedValue>
              </enumeratedValues>
            </field>
          </fields>
        </register>
        <register>
          <name>FCR</name>
          <description>GPIOE Function Control Register</description>
          <addressOffset>0xc</addressOffset>
          <size>32</size>
          <access>read-write</access>
          <resetValue>0x00000000</resetValue>
          <fields>
            <field>
              <name>Px15FCR</name>
              <description>Px15FCR  field description</description>
              <bitRange>[31:30]</bitRange>
              <access>read-write</access>
              <enumeratedValues>
                <enumeratedValue>
                  <name />
                  <description>GPIO输入</description>
                  <value>0</value>
                </enumeratedValue>
                <enumeratedValue>
                  <name />
                  <description>GPIO输出</description>
                  <value>1</value>
                </enumeratedValue>
                <enumeratedValue>
                  <name />
                  <description>Digital function</description>
                  <value>2</value>
                </enumeratedValue>
                <enumeratedValue>
                  <name />
                  <description>Analog function</description>
                  <value>3</value>
                </enumeratedValue>
              </enumeratedValues>
            </field>
            <field>
              <name>Px14FCR</name>
              <description>Px14FCR  field description</description>
              <bitRange>[29:28]</bitRange>
              <access>read-write</access>
              <enumeratedValues>
                <enumeratedValue>
                  <name />
                  <description>GPIO输入</description>
                  <value>0</value>
                </enumeratedValue>
                <enumeratedValue>
                  <name />
                  <description>GPIO输出</description>
                  <value>1</value>
                </enumeratedValue>
                <enumeratedValue>
                  <name />
                  <description>Digital function</description>
                  <value>2</value>
                </enumeratedValue>
                <enumeratedValue>
                  <name />
                  <description>Analog function</description>
                  <value>3</value>
                </enumeratedValue>
              </enumeratedValues>
            </field>
            <field>
              <name>Px13FCR</name>
              <description>Px13FCR  field description</description>
              <bitRange>[27:26]</bitRange>
              <access>read-write</access>
              <enumeratedValues>
                <enumeratedValue>
                  <name />
                  <description>GPIO输入</description>
                  <value>0</value>
                </enumeratedValue>
                <enumeratedValue>
                  <name />
                  <description>GPIO输出</description>
                  <value>1</value>
                </enumeratedValue>
                <enumeratedValue>
                  <name />
                  <description>Digital function</description>
                  <value>2</value>
                </enumeratedValue>
                <enumeratedValue>
                  <name />
                  <description>Analog function</description>
                  <value>3</value>
                </enumeratedValue>
              </enumeratedValues>
            </field>
            <field>
              <name>Px12FCR</name>
              <description>Px12FCR  field description</description>
              <bitRange>[25:24]</bitRange>
              <access>read-write</access>
              <enumeratedValues>
                <enumeratedValue>
                  <name />
                  <description>GPIO输入</description>
                  <value>0</value>
                </enumeratedValue>
                <enumeratedValue>
                  <name />
                  <description>GPIO输出</description>
                  <value>1</value>
                </enumeratedValue>
                <enumeratedValue>
                  <name />
                  <description>Digital function</description>
                  <value>2</value>
                </enumeratedValue>
                <enumeratedValue>
                  <name />
                  <description>Analog function</description>
                  <value>3</value>
                </enumeratedValue>
              </enumeratedValues>
            </field>
            <field>
              <name>Px11FCR</name>
              <description>Px11FCR  field description</description>
              <bitRange>[23:22]</bitRange>
              <access>read-write</access>
              <enumeratedValues>
                <enumeratedValue>
                  <name />
                  <description>GPIO输入</description>
                  <value>0</value>
                </enumeratedValue>
                <enumeratedValue>
                  <name />
                  <description>GPIO输出</description>
                  <value>1</value>
                </enumeratedValue>
                <enumeratedValue>
                  <name />
                  <description>Digital function</description>
                  <value>2</value>
                </enumeratedValue>
                <enumeratedValue>
                  <name />
                  <description>Analog function</description>
                  <value>3</value>
                </enumeratedValue>
              </enumeratedValues>
            </field>
            <field>
              <name>Px10FCR</name>
              <description>Px10FCR  field description</description>
              <bitRange>[21:20]</bitRange>
              <access>read-write</access>
              <enumeratedValues>
                <enumeratedValue>
                  <name />
                  <description>GPIO输入</description>
                  <value>0</value>
                </enumeratedValue>
                <enumeratedValue>
                  <name />
                  <description>GPIO输出</description>
                  <value>1</value>
                </enumeratedValue>
                <enumeratedValue>
                  <name />
                  <description>Digital function</description>
                  <value>2</value>
                </enumeratedValue>
                <enumeratedValue>
                  <name />
                  <description>Analog function</description>
                  <value>3</value>
                </enumeratedValue>
              </enumeratedValues>
            </field>
            <field>
              <name>Px9FCR</name>
              <description>Px9FCR  field description</description>
              <bitRange>[19:18]</bitRange>
              <access>read-write</access>
              <enumeratedValues>
                <enumeratedValue>
                  <name />
                  <description>GPIO输入</description>
                  <value>0</value>
                </enumeratedValue>
                <enumeratedValue>
                  <name />
                  <description>GPIO输出</description>
                  <value>1</value>
                </enumeratedValue>
                <enumeratedValue>
                  <name />
                  <description>Digital function</description>
                  <value>2</value>
                </enumeratedValue>
                <enumeratedValue>
                  <name />
                  <description>Analog function</description>
                  <value>3</value>
                </enumeratedValue>
              </enumeratedValues>
            </field>
            <field>
              <name>Px8FCR</name>
              <description>Px8FCR  field description</description>
              <bitRange>[17:16]</bitRange>
              <access>read-write</access>
              <enumeratedValues>
                <enumeratedValue>
                  <name />
                  <description>GPIO输入</description>
                  <value>0</value>
                </enumeratedValue>
                <enumeratedValue>
                  <name />
                  <description>GPIO输出</description>
                  <value>1</value>
                </enumeratedValue>
                <enumeratedValue>
                  <name />
                  <description>Digital function</description>
                  <value>2</value>
                </enumeratedValue>
                <enumeratedValue>
                  <name />
                  <description>Analog function</description>
                  <value>3</value>
                </enumeratedValue>
              </enumeratedValues>
            </field>
            <field>
              <name>Px7FCR</name>
              <description>Px7FCR  field description</description>
              <bitRange>[15:14]</bitRange>
              <access>read-write</access>
              <enumeratedValues>
                <enumeratedValue>
                  <name />
                  <description>GPIO输入</description>
                  <value>0</value>
                </enumeratedValue>
                <enumeratedValue>
                  <name />
                  <description>GPIO输出</description>
                  <value>1</value>
                </enumeratedValue>
                <enumeratedValue>
                  <name />
                  <description>Digital function</description>
                  <value>2</value>
                </enumeratedValue>
                <enumeratedValue>
                  <name />
                  <description>Analog function</description>
                  <value>3</value>
                </enumeratedValue>
              </enumeratedValues>
            </field>
            <field>
              <name>Px6FCR</name>
              <description>Px6FCR  field description</description>
              <bitRange>[13:12]</bitRange>
              <access>read-write</access>
              <enumeratedValues>
                <enumeratedValue>
                  <name />
                  <description>GPIO输入</description>
                  <value>0</value>
                </enumeratedValue>
                <enumeratedValue>
                  <name />
                  <description>GPIO输出</description>
                  <value>1</value>
                </enumeratedValue>
                <enumeratedValue>
                  <name />
                  <description>Digital function</description>
                  <value>2</value>
                </enumeratedValue>
                <enumeratedValue>
                  <name />
                  <description>Analog function</description>
                  <value>3</value>
                </enumeratedValue>
              </enumeratedValues>
            </field>
            <field>
              <name>Px5FCR</name>
              <description>Px5FCR  field description</description>
              <bitRange>[11:10]</bitRange>
              <access>read-write</access>
              <enumeratedValues>
                <enumeratedValue>
                  <name />
                  <description>GPIO输入</description>
                  <value>0</value>
                </enumeratedValue>
                <enumeratedValue>
                  <name />
                  <description>GPIO输出</description>
                  <value>1</value>
                </enumeratedValue>
                <enumeratedValue>
                  <name />
                  <description>Digital function</description>
                  <value>2</value>
                </enumeratedValue>
                <enumeratedValue>
                  <name />
                  <description>Analog function</description>
                  <value>3</value>
                </enumeratedValue>
              </enumeratedValues>
            </field>
            <field>
              <name>Px4FCR</name>
              <description>Px4FCR  field description</description>
              <bitRange>[9:8]</bitRange>
              <access>read-write</access>
              <enumeratedValues>
                <enumeratedValue>
                  <name />
                  <description>GPIO输入</description>
                  <value>0</value>
                </enumeratedValue>
                <enumeratedValue>
                  <name />
                  <description>GPIO输出</description>
                  <value>1</value>
                </enumeratedValue>
                <enumeratedValue>
                  <name />
                  <description>Digital function</description>
                  <value>2</value>
                </enumeratedValue>
                <enumeratedValue>
                  <name />
                  <description>Analog function</description>
                  <value>3</value>
                </enumeratedValue>
              </enumeratedValues>
            </field>
            <field>
              <name>Px3FCR</name>
              <description>Px3FCR  field description</description>
              <bitRange>[7:6]</bitRange>
              <access>read-write</access>
              <enumeratedValues>
                <enumeratedValue>
                  <name />
                  <description>GPIO输入</description>
                  <value>0</value>
                </enumeratedValue>
                <enumeratedValue>
                  <name />
                  <description>GPIO输出</description>
                  <value>1</value>
                </enumeratedValue>
                <enumeratedValue>
                  <name />
                  <description>Digital function</description>
                  <value>2</value>
                </enumeratedValue>
                <enumeratedValue>
                  <name />
                  <description>Analog function</description>
                  <value>3</value>
                </enumeratedValue>
              </enumeratedValues>
            </field>
            <field>
              <name>Px2FCR</name>
              <description>Px2FCR  field description</description>
              <bitRange>[5:4]</bitRange>
              <access>read-write</access>
              <enumeratedValues>
                <enumeratedValue>
                  <name />
                  <description>GPIO输入</description>
                  <value>0</value>
                </enumeratedValue>
                <enumeratedValue>
                  <name />
                  <description>GPIO输出</description>
                  <value>1</value>
                </enumeratedValue>
                <enumeratedValue>
                  <name />
                  <description>Digital function</description>
                  <value>2</value>
                </enumeratedValue>
                <enumeratedValue>
                  <name />
                  <description>Analog function</description>
                  <value>3</value>
                </enumeratedValue>
              </enumeratedValues>
            </field>
            <field>
              <name>Px1FCR</name>
              <description>Px1FCR  field description</description>
              <bitRange>[3:2]</bitRange>
              <access>read-write</access>
              <enumeratedValues>
                <enumeratedValue>
                  <name />
                  <description>GPIO输入</description>
                  <value>0</value>
                </enumeratedValue>
                <enumeratedValue>
                  <name />
                  <description>GPIO输出</description>
                  <value>1</value>
                </enumeratedValue>
                <enumeratedValue>
                  <name />
                  <description>Digital function</description>
                  <value>2</value>
                </enumeratedValue>
                <enumeratedValue>
                  <name />
                  <description>Analog function</description>
                  <value>3</value>
                </enumeratedValue>
              </enumeratedValues>
            </field>
            <field>
              <name>Px0FCR</name>
              <description>Px0FCR  field description</description>
              <bitRange>[1:0]</bitRange>
              <access>read-write</access>
              <enumeratedValues>
                <enumeratedValue>
                  <name />
                  <description>GPIO输入</description>
                  <value>0</value>
                </enumeratedValue>
                <enumeratedValue>
                  <name />
                  <description>GPIO输出</description>
                  <value>1</value>
                </enumeratedValue>
                <enumeratedValue>
                  <name />
                  <description>Digital function</description>
                  <value>2</value>
                </enumeratedValue>
                <enumeratedValue>
                  <name />
                  <description>Analog function</description>
                  <value>3</value>
                </enumeratedValue>
              </enumeratedValues>
            </field>
          </fields>
        </register>
        <register>
          <name>DO</name>
          <description>GPIOE Data Output Register</description>
          <addressOffset>0x10</addressOffset>
          <size>32</size>
          <access>read-write</access>
          <resetValue>0x00000000</resetValue>
          <fields>
            <field>
              <name>PxDO</name>
              <description>PxDO  field description</description>
              <bitRange>[15:0]</bitRange>
              <access>read-write</access>
              <enumeratedValues />
            </field>
          </fields>
        </register>
        <register>
          <name>DSET</name>
          <description>GPIOE Data Set Register</description>
          <addressOffset>0x14</addressOffset>
          <size>32</size>
          <access>read-write</access>
          <resetValue>0x00000000</resetValue>
          <fields>
            <field>
              <name>PxSET</name>
              <description>PxSET  field description</description>
              <bitRange>[15:0]</bitRange>
              <access>write-only</access>
              <enumeratedValues>
                <enumeratedValue>
                  <name />
                  <description>向PADSET写0x0000_8000，则PADO[15]置位，其余位保持不变。</description>
                  <value>0</value>
                </enumeratedValue>
              </enumeratedValues>
            </field>
          </fields>
        </register>
        <register>
          <name>DRST</name>
          <description>GPIOE Data Reset Register</description>
          <addressOffset>0x18</addressOffset>
          <size>32</size>
          <access>read-write</access>
          <resetValue>0x00000000</resetValue>
          <fields>
            <field>
              <name>PxRESET</name>
              <description>PxRESET  field description</description>
              <bitRange>[15:0]</bitRange>
              <access>write-only</access>
              <enumeratedValues>
                <enumeratedValue>
                  <name />
                  <description>向PADRST写0x0000_8000，则PADO[15]清零，其余位保持不变</description>
                  <value>0</value>
                </enumeratedValue>
              </enumeratedValues>
            </field>
          </fields>
        </register>
        <register>
          <name>DIN</name>
          <description>GPIOE Data Input Register</description>
          <addressOffset>0x1c</addressOffset>
          <size>32</size>
          <access>read-write</access>
          <resetValue>0x00000000</resetValue>
          <fields>
            <field>
              <name>PxDIN</name>
              <description>PxDIN  field description</description>
              <bitRange>[15:0]</bitRange>
              <access>read-only</access>
              <enumeratedValues />
            </field>
          </fields>
        </register>
        <register>
          <name>DFS</name>
          <description>GPIOE Digital Function Select</description>
          <addressOffset>0x20</addressOffset>
          <size>32</size>
          <access>read-write</access>
          <resetValue>0x00000000</resetValue>
          <fields>
            <field>
              <name>PxDFS</name>
              <description>PxDFS  field description</description>
              <bitRange>[15:0]</bitRange>
              <access>read-write</access>
              <enumeratedValues />
            </field>
          </fields>
        </register>
        <register>
          <name>ANEN</name>
          <description>GPIOE Analog channel Enable Register</description>
          <addressOffset>0x28</addressOffset>
          <size>32</size>
          <access>read-write</access>
          <resetValue>0x00000000</resetValue>
          <fields>
            <field>
              <name>PxANEN</name>
              <description>PxANEN  field description</description>
              <bitRange>[15:0]</bitRange>
              <access>read-write</access>
              <enumeratedValues>
                <enumeratedValue>
                  <name />
                  <description>使能IO模拟开关</description>
                  <value>1</value>
                </enumeratedValue>
                <enumeratedValue>
                  <name />
                  <description>关闭IO模拟开关</description>
                  <value>0</value>
                </enumeratedValue>
              </enumeratedValues>
            </field>
          </fields>
        </register>
      </registers>
    </peripheral>
    <peripheral>
      <name>GPIOF</name>
      <description>GPIOF module information</description>
      <groupName>GPIO</groupName>
      <baseAddress>0x40000d40</baseAddress>
      <size>32</size>
      <access>read-write</access>
      <addressBlock>
        <offset>0</offset>
        <size>0x2c</size>
        <usage>registers</usage>
      </addressBlock>
      <registers>
        <register>
          <name>INEN</name>
          <description>GPIOF Input Enable Register</description>
          <addressOffset>0x0</addressOffset>
          <size>32</size>
          <access>read-write</access>
          <resetValue>0x00000000</resetValue>
          <fields>
            <field>
              <name>PxINEN</name>
              <description>PxINEN  field description</description>
              <bitRange>[15:0]</bitRange>
              <access>read-write</access>
              <enumeratedValues>
                <enumeratedValue>
                  <name />
                  <description>关闭输入使能</description>
                  <value>0</value>
                </enumeratedValue>
                <enumeratedValue>
                  <name />
                  <description>打开输入使能</description>
                  <value>1</value>
                </enumeratedValue>
              </enumeratedValues>
            </field>
          </fields>
        </register>
        <register>
          <name>PUEN</name>
          <description>GPIOF Pull-Up Enable Register</description>
          <addressOffset>0x4</addressOffset>
          <size>32</size>
          <access>read-write</access>
          <resetValue>0x00000000</resetValue>
          <fields>
            <field>
              <name>PxPUEN</name>
              <description>PxPUEN  field description</description>
              <bitRange>[15:0]</bitRange>
              <access>read-write</access>
              <enumeratedValues>
                <enumeratedValue>
                  <name />
                  <description>关闭上拉</description>
                  <value>0</value>
                </enumeratedValue>
                <enumeratedValue>
                  <name />
                  <description>使能上拉</description>
                  <value>1</value>
                </enumeratedValue>
              </enumeratedValues>
            </field>
          </fields>
        </register>
        <register>
          <name>ODEN</name>
          <description>GPIOF Opeb-Drain Enable Register</description>
          <addressOffset>0x8</addressOffset>
          <size>32</size>
          <access>read-write</access>
          <resetValue>0x00000000</resetValue>
          <fields>
            <field>
              <name>PxODEN</name>
              <description>PxODEN  field description</description>
              <bitRange>[15:0]</bitRange>
              <access>read-write</access>
              <enumeratedValues>
                <enumeratedValue>
                  <name />
                  <description>关闭开漏输出</description>
                  <value>0</value>
                </enumeratedValue>
                <enumeratedValue>
                  <name />
                  <description>使能开漏输出</description>
                  <value>1</value>
                </enumeratedValue>
              </enumeratedValues>
            </field>
          </fields>
        </register>
        <register>
          <name>FCR</name>
          <description>GPIOF Function Control Register</description>
          <addressOffset>0xc</addressOffset>
          <size>32</size>
          <access>read-write</access>
          <resetValue>0x00000000</resetValue>
          <fields>
            <field>
              <name>Px15FCR</name>
              <description>Px15FCR  field description</description>
              <bitRange>[31:30]</bitRange>
              <access>read-write</access>
              <enumeratedValues>
                <enumeratedValue>
                  <name />
                  <description>GPIO输入</description>
                  <value>0</value>
                </enumeratedValue>
                <enumeratedValue>
                  <name />
                  <description>GPIO输出</description>
                  <value>1</value>
                </enumeratedValue>
                <enumeratedValue>
                  <name />
                  <description>Digital function</description>
                  <value>2</value>
                </enumeratedValue>
                <enumeratedValue>
                  <name />
                  <description>Analog function</description>
                  <value>3</value>
                </enumeratedValue>
              </enumeratedValues>
            </field>
            <field>
              <name>Px14FCR</name>
              <description>Px14FCR  field description</description>
              <bitRange>[29:28]</bitRange>
              <access>read-write</access>
              <enumeratedValues>
                <enumeratedValue>
                  <name />
                  <description>GPIO输入</description>
                  <value>0</value>
                </enumeratedValue>
                <enumeratedValue>
                  <name />
                  <description>GPIO输出</description>
                  <value>1</value>
                </enumeratedValue>
                <enumeratedValue>
                  <name />
                  <description>Digital function</description>
                  <value>2</value>
                </enumeratedValue>
                <enumeratedValue>
                  <name />
                  <description>Analog function</description>
                  <value>3</value>
                </enumeratedValue>
              </enumeratedValues>
            </field>
            <field>
              <name>Px13FCR</name>
              <description>Px13FCR  field description</description>
              <bitRange>[27:26]</bitRange>
              <access>read-write</access>
              <enumeratedValues>
                <enumeratedValue>
                  <name />
                  <description>GPIO输入</description>
                  <value>0</value>
                </enumeratedValue>
                <enumeratedValue>
                  <name />
                  <description>GPIO输出</description>
                  <value>1</value>
                </enumeratedValue>
                <enumeratedValue>
                  <name />
                  <description>Digital function</description>
                  <value>2</value>
                </enumeratedValue>
                <enumeratedValue>
                  <name />
                  <description>Analog function</description>
                  <value>3</value>
                </enumeratedValue>
              </enumeratedValues>
            </field>
            <field>
              <name>Px12FCR</name>
              <description>Px12FCR  field description</description>
              <bitRange>[25:24]</bitRange>
              <access>read-write</access>
              <enumeratedValues>
                <enumeratedValue>
                  <name />
                  <description>GPIO输入</description>
                  <value>0</value>
                </enumeratedValue>
                <enumeratedValue>
                  <name />
                  <description>GPIO输出</description>
                  <value>1</value>
                </enumeratedValue>
                <enumeratedValue>
                  <name />
                  <description>Digital function</description>
                  <value>2</value>
                </enumeratedValue>
                <enumeratedValue>
                  <name />
                  <description>Analog function</description>
                  <value>3</value>
                </enumeratedValue>
              </enumeratedValues>
            </field>
            <field>
              <name>Px11FCR</name>
              <description>Px11FCR  field description</description>
              <bitRange>[23:22]</bitRange>
              <access>read-write</access>
              <enumeratedValues>
                <enumeratedValue>
                  <name />
                  <description>GPIO输入</description>
                  <value>0</value>
                </enumeratedValue>
                <enumeratedValue>
                  <name />
                  <description>GPIO输出</description>
                  <value>1</value>
                </enumeratedValue>
                <enumeratedValue>
                  <name />
                  <description>Digital function</description>
                  <value>2</value>
                </enumeratedValue>
                <enumeratedValue>
                  <name />
                  <description>Analog function</description>
                  <value>3</value>
                </enumeratedValue>
              </enumeratedValues>
            </field>
            <field>
              <name>Px10FCR</name>
              <description>Px10FCR  field description</description>
              <bitRange>[21:20]</bitRange>
              <access>read-write</access>
              <enumeratedValues>
                <enumeratedValue>
                  <name />
                  <description>GPIO输入</description>
                  <value>0</value>
                </enumeratedValue>
                <enumeratedValue>
                  <name />
                  <description>GPIO输出</description>
                  <value>1</value>
                </enumeratedValue>
                <enumeratedValue>
                  <name />
                  <description>Digital function</description>
                  <value>2</value>
                </enumeratedValue>
                <enumeratedValue>
                  <name />
                  <description>Analog function</description>
                  <value>3</value>
                </enumeratedValue>
              </enumeratedValues>
            </field>
            <field>
              <name>Px9FCR</name>
              <description>Px9FCR  field description</description>
              <bitRange>[19:18]</bitRange>
              <access>read-write</access>
              <enumeratedValues>
                <enumeratedValue>
                  <name />
                  <description>GPIO输入</description>
                  <value>0</value>
                </enumeratedValue>
                <enumeratedValue>
                  <name />
                  <description>GPIO输出</description>
                  <value>1</value>
                </enumeratedValue>
                <enumeratedValue>
                  <name />
                  <description>Digital function</description>
                  <value>2</value>
                </enumeratedValue>
                <enumeratedValue>
                  <name />
                  <description>Analog function</description>
                  <value>3</value>
                </enumeratedValue>
              </enumeratedValues>
            </field>
            <field>
              <name>Px8FCR</name>
              <description>Px8FCR  field description</description>
              <bitRange>[17:16]</bitRange>
              <access>read-write</access>
              <enumeratedValues>
                <enumeratedValue>
                  <name />
                  <description>GPIO输入</description>
                  <value>0</value>
                </enumeratedValue>
                <enumeratedValue>
                  <name />
                  <description>GPIO输出</description>
                  <value>1</value>
                </enumeratedValue>
                <enumeratedValue>
                  <name />
                  <description>Digital function</description>
                  <value>2</value>
                </enumeratedValue>
                <enumeratedValue>
                  <name />
                  <description>Analog function</description>
                  <value>3</value>
                </enumeratedValue>
              </enumeratedValues>
            </field>
            <field>
              <name>Px7FCR</name>
              <description>Px7FCR  field description</description>
              <bitRange>[15:14]</bitRange>
              <access>read-write</access>
              <enumeratedValues>
                <enumeratedValue>
                  <name />
                  <description>GPIO输入</description>
                  <value>0</value>
                </enumeratedValue>
                <enumeratedValue>
                  <name />
                  <description>GPIO输出</description>
                  <value>1</value>
                </enumeratedValue>
                <enumeratedValue>
                  <name />
                  <description>Digital function</description>
                  <value>2</value>
                </enumeratedValue>
                <enumeratedValue>
                  <name />
                  <description>Analog function</description>
                  <value>3</value>
                </enumeratedValue>
              </enumeratedValues>
            </field>
            <field>
              <name>Px6FCR</name>
              <description>Px6FCR  field description</description>
              <bitRange>[13:12]</bitRange>
              <access>read-write</access>
              <enumeratedValues>
                <enumeratedValue>
                  <name />
                  <description>GPIO输入</description>
                  <value>0</value>
                </enumeratedValue>
                <enumeratedValue>
                  <name />
                  <description>GPIO输出</description>
                  <value>1</value>
                </enumeratedValue>
                <enumeratedValue>
                  <name />
                  <description>Digital function</description>
                  <value>2</value>
                </enumeratedValue>
                <enumeratedValue>
                  <name />
                  <description>Analog function</description>
                  <value>3</value>
                </enumeratedValue>
              </enumeratedValues>
            </field>
            <field>
              <name>Px5FCR</name>
              <description>Px5FCR  field description</description>
              <bitRange>[11:10]</bitRange>
              <access>read-write</access>
              <enumeratedValues>
                <enumeratedValue>
                  <name />
                  <description>GPIO输入</description>
                  <value>0</value>
                </enumeratedValue>
                <enumeratedValue>
                  <name />
                  <description>GPIO输出</description>
                  <value>1</value>
                </enumeratedValue>
                <enumeratedValue>
                  <name />
                  <description>Digital function</description>
                  <value>2</value>
                </enumeratedValue>
                <enumeratedValue>
                  <name />
                  <description>Analog function</description>
                  <value>3</value>
                </enumeratedValue>
              </enumeratedValues>
            </field>
            <field>
              <name>Px4FCR</name>
              <description>Px4FCR  field description</description>
              <bitRange>[9:8]</bitRange>
              <access>read-write</access>
              <enumeratedValues>
                <enumeratedValue>
                  <name />
                  <description>GPIO输入</description>
                  <value>0</value>
                </enumeratedValue>
                <enumeratedValue>
                  <name />
                  <description>GPIO输出</description>
                  <value>1</value>
                </enumeratedValue>
                <enumeratedValue>
                  <name />
                  <description>Digital function</description>
                  <value>2</value>
                </enumeratedValue>
                <enumeratedValue>
                  <name />
                  <description>Analog function</description>
                  <value>3</value>
                </enumeratedValue>
              </enumeratedValues>
            </field>
            <field>
              <name>Px3FCR</name>
              <description>Px3FCR  field description</description>
              <bitRange>[7:6]</bitRange>
              <access>read-write</access>
              <enumeratedValues>
                <enumeratedValue>
                  <name />
                  <description>GPIO输入</description>
                  <value>0</value>
                </enumeratedValue>
                <enumeratedValue>
                  <name />
                  <description>GPIO输出</description>
                  <value>1</value>
                </enumeratedValue>
                <enumeratedValue>
                  <name />
                  <description>Digital function</description>
                  <value>2</value>
                </enumeratedValue>
                <enumeratedValue>
                  <name />
                  <description>Analog function</description>
                  <value>3</value>
                </enumeratedValue>
              </enumeratedValues>
            </field>
            <field>
              <name>Px2FCR</name>
              <description>Px2FCR  field description</description>
              <bitRange>[5:4]</bitRange>
              <access>read-write</access>
              <enumeratedValues>
                <enumeratedValue>
                  <name />
                  <description>GPIO输入</description>
                  <value>0</value>
                </enumeratedValue>
                <enumeratedValue>
                  <name />
                  <description>GPIO输出</description>
                  <value>1</value>
                </enumeratedValue>
                <enumeratedValue>
                  <name />
                  <description>Digital function</description>
                  <value>2</value>
                </enumeratedValue>
                <enumeratedValue>
                  <name />
                  <description>Analog function</description>
                  <value>3</value>
                </enumeratedValue>
              </enumeratedValues>
            </field>
            <field>
              <name>Px1FCR</name>
              <description>Px1FCR  field description</description>
              <bitRange>[3:2]</bitRange>
              <access>read-write</access>
              <enumeratedValues>
                <enumeratedValue>
                  <name />
                  <description>GPIO输入</description>
                  <value>0</value>
                </enumeratedValue>
                <enumeratedValue>
                  <name />
                  <description>GPIO输出</description>
                  <value>1</value>
                </enumeratedValue>
                <enumeratedValue>
                  <name />
                  <description>Digital function</description>
                  <value>2</value>
                </enumeratedValue>
                <enumeratedValue>
                  <name />
                  <description>Analog function</description>
                  <value>3</value>
                </enumeratedValue>
              </enumeratedValues>
            </field>
            <field>
              <name>Px0FCR</name>
              <description>Px0FCR  field description</description>
              <bitRange>[1:0]</bitRange>
              <access>read-write</access>
              <enumeratedValues>
                <enumeratedValue>
                  <name />
                  <description>GPIO输入</description>
                  <value>0</value>
                </enumeratedValue>
                <enumeratedValue>
                  <name />
                  <description>GPIO输出</description>
                  <value>1</value>
                </enumeratedValue>
                <enumeratedValue>
                  <name />
                  <description>Digital function</description>
                  <value>2</value>
                </enumeratedValue>
                <enumeratedValue>
                  <name />
                  <description>Analog function</description>
                  <value>3</value>
                </enumeratedValue>
              </enumeratedValues>
            </field>
          </fields>
        </register>
        <register>
          <name>DO</name>
          <description>GPIOF Data Output Register</description>
          <addressOffset>0x10</addressOffset>
          <size>32</size>
          <access>read-write</access>
          <resetValue>0x00000000</resetValue>
          <fields>
            <field>
              <name>PxDO</name>
              <description>PxDO  field description</description>
              <bitRange>[15:0]</bitRange>
              <access>read-write</access>
              <enumeratedValues />
            </field>
          </fields>
        </register>
        <register>
          <name>DSET</name>
          <description>GPIOF Data Set Register</description>
          <addressOffset>0x14</addressOffset>
          <size>32</size>
          <access>read-write</access>
          <resetValue>0x00000000</resetValue>
          <fields>
            <field>
              <name>PxSET</name>
              <description>PxSET  field description</description>
              <bitRange>[15:0]</bitRange>
              <access>write-only</access>
              <enumeratedValues>
                <enumeratedValue>
                  <name />
                  <description>向PADSET写0x0000_8000，则PADO[15]置位，其余位保持不变。</description>
                  <value>0</value>
                </enumeratedValue>
              </enumeratedValues>
            </field>
          </fields>
        </register>
        <register>
          <name>DRST</name>
          <description>GPIOF Data Reset Register</description>
          <addressOffset>0x18</addressOffset>
          <size>32</size>
          <access>read-write</access>
          <resetValue>0x00000000</resetValue>
          <fields>
            <field>
              <name>PxRESET</name>
              <description>PxRESET  field description</description>
              <bitRange>[15:0]</bitRange>
              <access>write-only</access>
              <enumeratedValues>
                <enumeratedValue>
                  <name />
                  <description>向PADRST写0x0000_8000，则PADO[15]清零，其余位保持不变</description>
                  <value>0</value>
                </enumeratedValue>
              </enumeratedValues>
            </field>
          </fields>
        </register>
        <register>
          <name>DIN</name>
          <description>GPIOF Data Input Register</description>
          <addressOffset>0x1c</addressOffset>
          <size>32</size>
          <access>read-write</access>
          <resetValue>0x00000000</resetValue>
          <fields>
            <field>
              <name>PxDIN</name>
              <description>PxDIN  field description</description>
              <bitRange>[15:0]</bitRange>
              <access>read-only</access>
              <enumeratedValues />
            </field>
          </fields>
        </register>
        <register>
          <name>DFS</name>
          <description>GPIOF Digital Function Select</description>
          <addressOffset>0x20</addressOffset>
          <size>32</size>
          <access>read-write</access>
          <resetValue>0x00000000</resetValue>
          <fields>
            <field>
              <name>PxDFS</name>
              <description>PxDFS  field description</description>
              <bitRange>[15:0]</bitRange>
              <access>read-write</access>
              <enumeratedValues />
            </field>
          </fields>
        </register>
        <register>
          <name>ANEN</name>
          <description>GPIOF Analog channel Enable Register</description>
          <addressOffset>0x28</addressOffset>
          <size>32</size>
          <access>read-write</access>
          <resetValue>0x00000000</resetValue>
          <fields>
            <field>
              <name>PxANEN</name>
              <description>PxANEN  field description</description>
              <bitRange>[15:0]</bitRange>
              <access>read-write</access>
              <enumeratedValues>
                <enumeratedValue>
                  <name />
                  <description>使能IO模拟开关</description>
                  <value>1</value>
                </enumeratedValue>
                <enumeratedValue>
                  <name />
                  <description>关闭IO模拟开关</description>
                  <value>0</value>
                </enumeratedValue>
              </enumeratedValues>
            </field>
          </fields>
        </register>
      </registers>
    </peripheral>
    <peripheral>
      <name>GPIOG</name>
      <description>GPIOG module information</description>
      <groupName>GPIO</groupName>
      <baseAddress>0x40000d80</baseAddress>
      <size>32</size>
      <access>read-write</access>
      <addressBlock>
        <offset>0</offset>
        <size>0x2c</size>
        <usage>registers</usage>
      </addressBlock>
      <registers>
        <register>
          <name>INEN</name>
          <description>GPIOG Input Enable Register</description>
          <addressOffset>0x0</addressOffset>
          <size>32</size>
          <access>read-write</access>
          <resetValue>0x00000000</resetValue>
          <fields>
            <field>
              <name>PxINEN</name>
              <description>PxINEN  field description</description>
              <bitRange>[15:0]</bitRange>
              <access>read-write</access>
              <enumeratedValues>
                <enumeratedValue>
                  <name />
                  <description>关闭输入使能</description>
                  <value>0</value>
                </enumeratedValue>
                <enumeratedValue>
                  <name />
                  <description>打开输入使能</description>
                  <value>1</value>
                </enumeratedValue>
              </enumeratedValues>
            </field>
          </fields>
        </register>
        <register>
          <name>PUEN</name>
          <description>GPIOG Pull-Up Enable Register</description>
          <addressOffset>0x4</addressOffset>
          <size>32</size>
          <access>read-write</access>
          <resetValue>0x00000000</resetValue>
          <fields>
            <field>
              <name>PxPUEN</name>
              <description>PxPUEN  field description</description>
              <bitRange>[15:0]</bitRange>
              <access>read-write</access>
              <enumeratedValues>
                <enumeratedValue>
                  <name />
                  <description>关闭上拉</description>
                  <value>0</value>
                </enumeratedValue>
                <enumeratedValue>
                  <name />
                  <description>使能上拉</description>
                  <value>1</value>
                </enumeratedValue>
              </enumeratedValues>
            </field>
          </fields>
        </register>
        <register>
          <name>ODEN</name>
          <description>GPIOG Opeb-Drain Enable Register</description>
          <addressOffset>0x8</addressOffset>
          <size>32</size>
          <access>read-write</access>
          <resetValue>0x00000000</resetValue>
          <fields>
            <field>
              <name>PxODEN</name>
              <description>PxODEN  field description</description>
              <bitRange>[15:0]</bitRange>
              <access>read-write</access>
              <enumeratedValues>
                <enumeratedValue>
                  <name />
                  <description>关闭开漏输出</description>
                  <value>0</value>
                </enumeratedValue>
                <enumeratedValue>
                  <name />
                  <description>使能开漏输出</description>
                  <value>1</value>
                </enumeratedValue>
              </enumeratedValues>
            </field>
          </fields>
        </register>
        <register>
          <name>FCR</name>
          <description>GPIOG Function Control Register</description>
          <addressOffset>0xc</addressOffset>
          <size>32</size>
          <access>read-write</access>
          <resetValue>0x00000000</resetValue>
          <fields>
            <field>
              <name>Px15FCR</name>
              <description>Px15FCR  field description</description>
              <bitRange>[31:30]</bitRange>
              <access>read-write</access>
              <enumeratedValues>
                <enumeratedValue>
                  <name />
                  <description>GPIO输入</description>
                  <value>0</value>
                </enumeratedValue>
                <enumeratedValue>
                  <name />
                  <description>GPIO输出</description>
                  <value>1</value>
                </enumeratedValue>
                <enumeratedValue>
                  <name />
                  <description>Digital function</description>
                  <value>2</value>
                </enumeratedValue>
                <enumeratedValue>
                  <name />
                  <description>Analog function</description>
                  <value>3</value>
                </enumeratedValue>
              </enumeratedValues>
            </field>
            <field>
              <name>Px14FCR</name>
              <description>Px14FCR  field description</description>
              <bitRange>[29:28]</bitRange>
              <access>read-write</access>
              <enumeratedValues>
                <enumeratedValue>
                  <name />
                  <description>GPIO输入</description>
                  <value>0</value>
                </enumeratedValue>
                <enumeratedValue>
                  <name />
                  <description>GPIO输出</description>
                  <value>1</value>
                </enumeratedValue>
                <enumeratedValue>
                  <name />
                  <description>Digital function</description>
                  <value>2</value>
                </enumeratedValue>
                <enumeratedValue>
                  <name />
                  <description>Analog function</description>
                  <value>3</value>
                </enumeratedValue>
              </enumeratedValues>
            </field>
            <field>
              <name>Px13FCR</name>
              <description>Px13FCR  field description</description>
              <bitRange>[27:26]</bitRange>
              <access>read-write</access>
              <enumeratedValues>
                <enumeratedValue>
                  <name />
                  <description>GPIO输入</description>
                  <value>0</value>
                </enumeratedValue>
                <enumeratedValue>
                  <name />
                  <description>GPIO输出</description>
                  <value>1</value>
                </enumeratedValue>
                <enumeratedValue>
                  <name />
                  <description>Digital function</description>
                  <value>2</value>
                </enumeratedValue>
                <enumeratedValue>
                  <name />
                  <description>Analog function</description>
                  <value>3</value>
                </enumeratedValue>
              </enumeratedValues>
            </field>
            <field>
              <name>Px12FCR</name>
              <description>Px12FCR  field description</description>
              <bitRange>[25:24]</bitRange>
              <access>read-write</access>
              <enumeratedValues>
                <enumeratedValue>
                  <name />
                  <description>GPIO输入</description>
                  <value>0</value>
                </enumeratedValue>
                <enumeratedValue>
                  <name />
                  <description>GPIO输出</description>
                  <value>1</value>
                </enumeratedValue>
                <enumeratedValue>
                  <name />
                  <description>Digital function</description>
                  <value>2</value>
                </enumeratedValue>
                <enumeratedValue>
                  <name />
                  <description>Analog function</description>
                  <value>3</value>
                </enumeratedValue>
              </enumeratedValues>
            </field>
            <field>
              <name>Px11FCR</name>
              <description>Px11FCR  field description</description>
              <bitRange>[23:22]</bitRange>
              <access>read-write</access>
              <enumeratedValues>
                <enumeratedValue>
                  <name />
                  <description>GPIO输入</description>
                  <value>0</value>
                </enumeratedValue>
                <enumeratedValue>
                  <name />
                  <description>GPIO输出</description>
                  <value>1</value>
                </enumeratedValue>
                <enumeratedValue>
                  <name />
                  <description>Digital function</description>
                  <value>2</value>
                </enumeratedValue>
                <enumeratedValue>
                  <name />
                  <description>Analog function</description>
                  <value>3</value>
                </enumeratedValue>
              </enumeratedValues>
            </field>
            <field>
              <name>Px10FCR</name>
              <description>Px10FCR  field description</description>
              <bitRange>[21:20]</bitRange>
              <access>read-write</access>
              <enumeratedValues>
                <enumeratedValue>
                  <name />
                  <description>GPIO输入</description>
                  <value>0</value>
                </enumeratedValue>
                <enumeratedValue>
                  <name />
                  <description>GPIO输出</description>
                  <value>1</value>
                </enumeratedValue>
                <enumeratedValue>
                  <name />
                  <description>Digital function</description>
                  <value>2</value>
                </enumeratedValue>
                <enumeratedValue>
                  <name />
                  <description>Analog function</description>
                  <value>3</value>
                </enumeratedValue>
              </enumeratedValues>
            </field>
            <field>
              <name>Px9FCR</name>
              <description>Px9FCR  field description</description>
              <bitRange>[19:18]</bitRange>
              <access>read-write</access>
              <enumeratedValues>
                <enumeratedValue>
                  <name />
                  <description>GPIO输入</description>
                  <value>0</value>
                </enumeratedValue>
                <enumeratedValue>
                  <name />
                  <description>GPIO输出</description>
                  <value>1</value>
                </enumeratedValue>
                <enumeratedValue>
                  <name />
                  <description>Digital function</description>
                  <value>2</value>
                </enumeratedValue>
                <enumeratedValue>
                  <name />
                  <description>Analog function</description>
                  <value>3</value>
                </enumeratedValue>
              </enumeratedValues>
            </field>
            <field>
              <name>Px8FCR</name>
              <description>Px8FCR  field description</description>
              <bitRange>[17:16]</bitRange>
              <access>read-write</access>
              <enumeratedValues>
                <enumeratedValue>
                  <name />
                  <description>GPIO输入</description>
                  <value>0</value>
                </enumeratedValue>
                <enumeratedValue>
                  <name />
                  <description>GPIO输出</description>
                  <value>1</value>
                </enumeratedValue>
                <enumeratedValue>
                  <name />
                  <description>Digital function</description>
                  <value>2</value>
                </enumeratedValue>
                <enumeratedValue>
                  <name />
                  <description>Analog function</description>
                  <value>3</value>
                </enumeratedValue>
              </enumeratedValues>
            </field>
            <field>
              <name>Px7FCR</name>
              <description>Px7FCR  field description</description>
              <bitRange>[15:14]</bitRange>
              <access>read-write</access>
              <enumeratedValues>
                <enumeratedValue>
                  <name />
                  <description>GPIO输入</description>
                  <value>0</value>
                </enumeratedValue>
                <enumeratedValue>
                  <name />
                  <description>GPIO输出</description>
                  <value>1</value>
                </enumeratedValue>
                <enumeratedValue>
                  <name />
                  <description>Digital function</description>
                  <value>2</value>
                </enumeratedValue>
                <enumeratedValue>
                  <name />
                  <description>Analog function</description>
                  <value>3</value>
                </enumeratedValue>
              </enumeratedValues>
            </field>
            <field>
              <name>Px6FCR</name>
              <description>Px6FCR  field description</description>
              <bitRange>[13:12]</bitRange>
              <access>read-write</access>
              <enumeratedValues>
                <enumeratedValue>
                  <name />
                  <description>GPIO输入</description>
                  <value>0</value>
                </enumeratedValue>
                <enumeratedValue>
                  <name />
                  <description>GPIO输出</description>
                  <value>1</value>
                </enumeratedValue>
                <enumeratedValue>
                  <name />
                  <description>Digital function</description>
                  <value>2</value>
                </enumeratedValue>
                <enumeratedValue>
                  <name />
                  <description>Analog function</description>
                  <value>3</value>
                </enumeratedValue>
              </enumeratedValues>
            </field>
            <field>
              <name>Px5FCR</name>
              <description>Px5FCR  field description</description>
              <bitRange>[11:10]</bitRange>
              <access>read-write</access>
              <enumeratedValues>
                <enumeratedValue>
                  <name />
                  <description>GPIO输入</description>
                  <value>0</value>
                </enumeratedValue>
                <enumeratedValue>
                  <name />
                  <description>GPIO输出</description>
                  <value>1</value>
                </enumeratedValue>
                <enumeratedValue>
                  <name />
                  <description>Digital function</description>
                  <value>2</value>
                </enumeratedValue>
                <enumeratedValue>
                  <name />
                  <description>Analog function</description>
                  <value>3</value>
                </enumeratedValue>
              </enumeratedValues>
            </field>
            <field>
              <name>Px4FCR</name>
              <description>Px4FCR  field description</description>
              <bitRange>[9:8]</bitRange>
              <access>read-write</access>
              <enumeratedValues>
                <enumeratedValue>
                  <name />
                  <description>GPIO输入</description>
                  <value>0</value>
                </enumeratedValue>
                <enumeratedValue>
                  <name />
                  <description>GPIO输出</description>
                  <value>1</value>
                </enumeratedValue>
                <enumeratedValue>
                  <name />
                  <description>Digital function</description>
                  <value>2</value>
                </enumeratedValue>
                <enumeratedValue>
                  <name />
                  <description>Analog function</description>
                  <value>3</value>
                </enumeratedValue>
              </enumeratedValues>
            </field>
            <field>
              <name>Px3FCR</name>
              <description>Px3FCR  field description</description>
              <bitRange>[7:6]</bitRange>
              <access>read-write</access>
              <enumeratedValues>
                <enumeratedValue>
                  <name />
                  <description>GPIO输入</description>
                  <value>0</value>
                </enumeratedValue>
                <enumeratedValue>
                  <name />
                  <description>GPIO输出</description>
                  <value>1</value>
                </enumeratedValue>
                <enumeratedValue>
                  <name />
                  <description>Digital function</description>
                  <value>2</value>
                </enumeratedValue>
                <enumeratedValue>
                  <name />
                  <description>Analog function</description>
                  <value>3</value>
                </enumeratedValue>
              </enumeratedValues>
            </field>
            <field>
              <name>Px2FCR</name>
              <description>Px2FCR  field description</description>
              <bitRange>[5:4]</bitRange>
              <access>read-write</access>
              <enumeratedValues>
                <enumeratedValue>
                  <name />
                  <description>GPIO输入</description>
                  <value>0</value>
                </enumeratedValue>
                <enumeratedValue>
                  <name />
                  <description>GPIO输出</description>
                  <value>1</value>
                </enumeratedValue>
                <enumeratedValue>
                  <name />
                  <description>Digital function</description>
                  <value>2</value>
                </enumeratedValue>
                <enumeratedValue>
                  <name />
                  <description>Analog function</description>
                  <value>3</value>
                </enumeratedValue>
              </enumeratedValues>
            </field>
            <field>
              <name>Px1FCR</name>
              <description>Px1FCR  field description</description>
              <bitRange>[3:2]</bitRange>
              <access>read-write</access>
              <enumeratedValues>
                <enumeratedValue>
                  <name />
                  <description>GPIO输入</description>
                  <value>0</value>
                </enumeratedValue>
                <enumeratedValue>
                  <name />
                  <description>GPIO输出</description>
                  <value>1</value>
                </enumeratedValue>
                <enumeratedValue>
                  <name />
                  <description>Digital function</description>
                  <value>2</value>
                </enumeratedValue>
                <enumeratedValue>
                  <name />
                  <description>Analog function</description>
                  <value>3</value>
                </enumeratedValue>
              </enumeratedValues>
            </field>
            <field>
              <name>Px0FCR</name>
              <description>Px0FCR  field description</description>
              <bitRange>[1:0]</bitRange>
              <access>read-write</access>
              <enumeratedValues>
                <enumeratedValue>
                  <name />
                  <description>GPIO输入</description>
                  <value>0</value>
                </enumeratedValue>
                <enumeratedValue>
                  <name />
                  <description>GPIO输出</description>
                  <value>1</value>
                </enumeratedValue>
                <enumeratedValue>
                  <name />
                  <description>Digital function</description>
                  <value>2</value>
                </enumeratedValue>
                <enumeratedValue>
                  <name />
                  <description>Analog function</description>
                  <value>3</value>
                </enumeratedValue>
              </enumeratedValues>
            </field>
          </fields>
        </register>
        <register>
          <name>DO</name>
          <description>GPIOG Data Output Register</description>
          <addressOffset>0x10</addressOffset>
          <size>32</size>
          <access>read-write</access>
          <resetValue>0x00000000</resetValue>
          <fields>
            <field>
              <name>PxDO</name>
              <description>PxDO  field description</description>
              <bitRange>[15:0]</bitRange>
              <access>read-write</access>
              <enumeratedValues />
            </field>
          </fields>
        </register>
        <register>
          <name>DSET</name>
          <description>GPIOG Data Set Register</description>
          <addressOffset>0x14</addressOffset>
          <size>32</size>
          <access>read-write</access>
          <resetValue>0x00000000</resetValue>
          <fields>
            <field>
              <name>PxSET</name>
              <description>PxSET  field description</description>
              <bitRange>[15:0]</bitRange>
              <access>write-only</access>
              <enumeratedValues>
                <enumeratedValue>
                  <name />
                  <description>向PADSET写0x0000_8000，则PADO[15]置位，其余位保持不变。</description>
                  <value>0</value>
                </enumeratedValue>
              </enumeratedValues>
            </field>
          </fields>
        </register>
        <register>
          <name>DRST</name>
          <description>GPIOG Data Reset Register</description>
          <addressOffset>0x18</addressOffset>
          <size>32</size>
          <access>read-write</access>
          <resetValue>0x00000000</resetValue>
          <fields>
            <field>
              <name>PxRESET</name>
              <description>PxRESET  field description</description>
              <bitRange>[15:0]</bitRange>
              <access>write-only</access>
              <enumeratedValues>
                <enumeratedValue>
                  <name />
                  <description>向PADRST写0x0000_8000，则PADO[15]清零，其余位保持不变</description>
                  <value>0</value>
                </enumeratedValue>
              </enumeratedValues>
            </field>
          </fields>
        </register>
        <register>
          <name>DIN</name>
          <description>GPIOG Data Input Register</description>
          <addressOffset>0x1c</addressOffset>
          <size>32</size>
          <access>read-write</access>
          <resetValue>0x00000000</resetValue>
          <fields>
            <field>
              <name>PxDIN</name>
              <description>PxDIN  field description</description>
              <bitRange>[15:0]</bitRange>
              <access>read-only</access>
              <enumeratedValues />
            </field>
          </fields>
        </register>
        <register>
          <name>DFS</name>
          <description>GPIOG Digital Function Select</description>
          <addressOffset>0x20</addressOffset>
          <size>32</size>
          <access>read-write</access>
          <resetValue>0x00000000</resetValue>
          <fields>
            <field>
              <name>PxDFS</name>
              <description>PxDFS  field description</description>
              <bitRange>[15:0]</bitRange>
              <access>read-write</access>
              <enumeratedValues />
            </field>
          </fields>
        </register>
        <register>
          <name>ANEN</name>
          <description>GPIOG Analog channel Enable Register</description>
          <addressOffset>0x28</addressOffset>
          <size>32</size>
          <access>read-write</access>
          <resetValue>0x00000000</resetValue>
          <fields>
            <field>
              <name>PxANEN</name>
              <description>PxANEN  field description</description>
              <bitRange>[15:0]</bitRange>
              <access>read-write</access>
              <enumeratedValues>
                <enumeratedValue>
                  <name />
                  <description>使能IO模拟开关</description>
                  <value>1</value>
                </enumeratedValue>
                <enumeratedValue>
                  <name />
                  <description>关闭IO模拟开关</description>
                  <value>0</value>
                </enumeratedValue>
              </enumeratedValues>
            </field>
          </fields>
        </register>
      </registers>
    </peripheral>
    <peripheral>
      <name>GPIO</name>
      <description>GPIO module information</description>
      <groupName>GPIO</groupName>
      <baseAddress>0x40000dc0</baseAddress>
      <size>32</size>
      <access>read-write</access>
      <addressBlock>
        <offset>0</offset>
        <size>0x144</size>
        <usage>registers</usage>
      </addressBlock>
      <registers>
        <register>
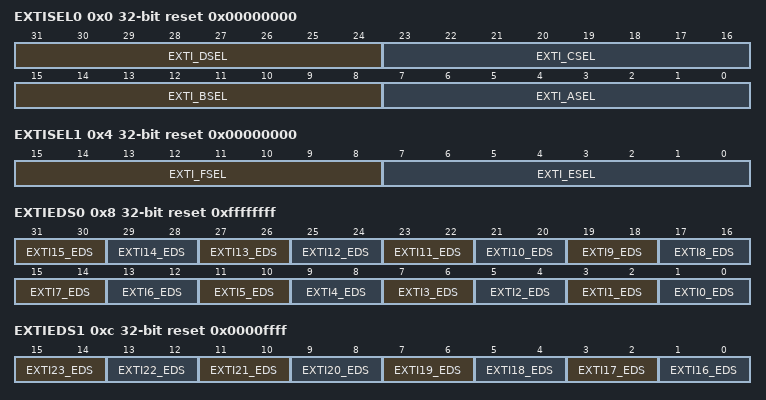
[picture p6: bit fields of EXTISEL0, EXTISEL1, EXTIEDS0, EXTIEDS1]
          <name>EXTISEL0</name>
          <description>External Interrupt input Select Register0</description>
          <addressOffset>0x0</addressOffset>
          <size>32</size>
          <access>read-write</access>
          <resetValue>0x00000000</resetValue>
          <fields>
            <field>
              <name>EXTI_DSEL</name>
              <description>EXTI_DSEL  field description</description>
              <bitRange>[31:24]</bitRange>
              <access>read-write</access>
              <enumeratedValues>
                <enumeratedValue>
                  <name />
                  <description>PD8</description>
                  <value>0</value>
                </enumeratedValue>
                <enumeratedValue>
                  <name />
                  <description>PD9</description>
                  <value>1</value>
                </enumeratedValue>
                <enumeratedValue>
                  <name />
                  <description>PD10</description>
                  <value>2</value>
                </enumeratedValue>
                <enumeratedValue>
                  <name />
                  <description>PD11</description>
                  <value>3</value>
                </enumeratedValue>
                <enumeratedValue>
                  <name />
                  <description>PD4</description>
                  <value>0</value>
                </enumeratedValue>
                <enumeratedValue>
                  <name />
                  <description>PD5</description>
                  <value>1</value>
                </enumeratedValue>
                <enumeratedValue>
                  <name />
                  <description>PD6</description>
                  <value>2</value>
                </enumeratedValue>
                <enumeratedValue>
                  <name />
                  <description>PD7</description>
                  <value>3</value>
                </enumeratedValue>
                <enumeratedValue>
                  <name />
                  <description>PD0</description>
                  <value>0</value>
                </enumeratedValue>
                <enumeratedValue>
                  <name />
                  <description>PD1</description>
                  <value>1</value>
                </enumeratedValue>
                <enumeratedValue>
                  <name />
                  <description>PD2</description>
                  <value>2</value>
                </enumeratedValue>
                <enumeratedValue>
                  <name />
                  <description>PD3</description>
                  <value>3</value>
                </enumeratedValue>
              </enumeratedValues>
            </field>
            <field>
              <name>EXTI_CSEL</name>
              <description>EXTI_CSEL  field description</description>
              <bitRange>[23:16]</bitRange>
              <access>read-write</access>
              <enumeratedValues>
                <enumeratedValue>
                  <name />
                  <description>PC8</description>
                  <value>0</value>
                </enumeratedValue>
                <enumeratedValue>
                  <name />
                  <description>PC9</description>
                  <value>1</value>
                </enumeratedValue>
                <enumeratedValue>
                  <name />
                  <description>PC10</description>
                  <value>2</value>
                </enumeratedValue>
                <enumeratedValue>
                  <name />
                  <description>PC11</description>
                  <value>3</value>
                </enumeratedValue>
                <enumeratedValue>
                  <name />
                  <description>PC4</description>
                  <value>0</value>
                </enumeratedValue>
                <enumeratedValue>
                  <name />
                  <description>PC5</description>
                  <value>1</value>
                </enumeratedValue>
                <enumeratedValue>
                  <name />
                  <description>PC6</description>
                  <value>2</value>
                </enumeratedValue>
                <enumeratedValue>
                  <name />
                  <description>PC7</description>
                  <value>3</value>
                </enumeratedValue>
                <enumeratedValue>
                  <name />
                  <description>PC0</description>
                  <value>0</value>
                </enumeratedValue>
                <enumeratedValue>
                  <name />
                  <description>PC1</description>
                  <value>1</value>
                </enumeratedValue>
                <enumeratedValue>
                  <name />
                  <description>PC2</description>
                  <value>2</value>
                </enumeratedValue>
                <enumeratedValue>
                  <name />
                  <description>PC3</description>
                  <value>3</value>
                </enumeratedValue>
              </enumeratedValues>
            </field>
            <field>
              <name>EXTI_BSEL</name>
              <description>EXTI_BSEL  field description</description>
              <bitRange>[15:8]</bitRange>
              <access>read-write</access>
              <enumeratedValues>
                <enumeratedValue>
                  <name />
                  <description>PB12</description>
                  <value>0</value>
                </enumeratedValue>
                <enumeratedValue>
                  <name />
                  <description>PB13</description>
                  <value>1</value>
                </enumeratedValue>
                <enumeratedValue>
                  <name />
                  <description>PB14</description>
                  <value>2</value>
                </enumeratedValue>
                <enumeratedValue>
                  <name />
                  <description>PB15</description>
                  <value>3</value>
                </enumeratedValue>
                <enumeratedValue>
                  <name />
                  <description>PB8</description>
                  <value>0</value>
                </enumeratedValue>
                <enumeratedValue>
                  <name />
                  <description>PB9</description>
                  <value>1</value>
                </enumeratedValue>
                <enumeratedValue>
                  <name />
                  <description>PB10</description>
                  <value>2</value>
                </enumeratedValue>
                <enumeratedValue>
                  <name />
                  <description>PB11</description>
                  <value>3</value>
                </enumeratedValue>
                <enumeratedValue>
                  <name />
                  <description>PB4</description>
                  <value>0</value>
                </enumeratedValue>
                <enumeratedValue>
                  <name />
                  <description>PB5</description>
                  <value>1</value>
                </enumeratedValue>
                <enumeratedValue>
                  <name />
                  <description>PB6</description>
                  <value>2</value>
                </enumeratedValue>
                <enumeratedValue>
                  <name />
                  <description>PB7</description>
                  <value>3</value>
                </enumeratedValue>
                <enumeratedValue>
                  <name />
                  <description>PB0</description>
                  <value>0</value>
                </enumeratedValue>
                <enumeratedValue>
                  <name />
                  <description>PB1</description>
                  <value>1</value>
                </enumeratedValue>
                <enumeratedValue>
                  <name />
                  <description>PB2</description>
                  <value>2</value>
                </enumeratedValue>
                <enumeratedValue>
                  <name />
                  <description>PB3</description>
                  <value>3</value>
                </enumeratedValue>
              </enumeratedValues>
            </field>
            <field>
              <name>EXTI_ASEL</name>
              <description>EXTI_ASEL  field description</description>
              <bitRange>[7:0]</bitRange>
              <access>read-write</access>
              <enumeratedValues>
                <enumeratedValue>
                  <name />
                  <description>PA12</description>
                  <value>0</value>
                </enumeratedValue>
                <enumeratedValue>
                  <name />
                  <description>PA13</description>
                  <value>1</value>
                </enumeratedValue>
                <enumeratedValue>
                  <name />
                  <description>PA14</description>
                  <value>2</value>
                </enumeratedValue>
                <enumeratedValue>
                  <name />
                  <description>PA15</description>
                  <value>3</value>
                </enumeratedValue>
                <enumeratedValue>
                  <name />
                  <description>PA8</description>
                  <value>0</value>
                </enumeratedValue>
                <enumeratedValue>
                  <name />
                  <description>PA9</description>
                  <value>1</value>
                </enumeratedValue>
                <enumeratedValue>
                  <name />
                  <description>PA10</description>
                  <value>2</value>
                </enumeratedValue>
                <enumeratedValue>
                  <name />
                  <description>PA11</description>
                  <value>3</value>
                </enumeratedValue>
                <enumeratedValue>
                  <name />
                  <description>PA4</description>
                  <value>0</value>
                </enumeratedValue>
                <enumeratedValue>
                  <name />
                  <description>PA5</description>
                  <value>1</value>
                </enumeratedValue>
                <enumeratedValue>
                  <name />
                  <description>PA6</description>
                  <value>2</value>
                </enumeratedValue>
                <enumeratedValue>
                  <name />
                  <description>PA7</description>
                  <value>3</value>
                </enumeratedValue>
                <enumeratedValue>
                  <name />
                  <description>PA0</description>
                  <value>0</value>
                </enumeratedValue>
                <enumeratedValue>
                  <name />
                  <description>PA1</description>
                  <value>1</value>
                </enumeratedValue>
                <enumeratedValue>
                  <name />
                  <description>PA2</description>
                  <value>2</value>
                </enumeratedValue>
                <enumeratedValue>
                  <name />
                  <description>PA3</description>
                  <value>3</value>
                </enumeratedValue>
              </enumeratedValues>
            </field>
          </fields>
        </register>
        <register>
          <name>EXTISEL1</name>
          <description>External Interrupt input Select Register1</description>
          <addressOffset>0x4</addressOffset>
          <size>32</size>
          <access>read-write</access>
          <resetValue>0x00000000</resetValue>
          <fields>
            <field>
              <name>EXTI_FSEL</name>
              <description>EXTI_FSEL  field description</description>
              <bitRange>[15:8]</bitRange>
              <access>read-write</access>
              <enumeratedValues>
                <enumeratedValue>
                  <name />
                  <description>PF8</description>
                  <value>0</value>
                </enumeratedValue>
                <enumeratedValue>
                  <name />
                  <description>PF9</description>
                  <value>1</value>
                </enumeratedValue>
                <enumeratedValue>
                  <name />
                  <description>PF10</description>
                  <value>2</value>
                </enumeratedValue>
                <enumeratedValue>
                  <name />
                  <description>PF11</description>
                  <value>3</value>
                </enumeratedValue>
                <enumeratedValue>
                  <name />
                  <description>PF4</description>
                  <value>0</value>
                </enumeratedValue>
                <enumeratedValue>
                  <name />
                  <description>PF5</description>
                  <value>1</value>
                </enumeratedValue>
                <enumeratedValue>
                  <name />
                  <description>PF6</description>
                  <value>2</value>
                </enumeratedValue>
                <enumeratedValue>
                  <name />
                  <description>PF7</description>
                  <value>3</value>
                </enumeratedValue>
                <enumeratedValue>
                  <name />
                  <description>PF0</description>
                  <value>0</value>
                </enumeratedValue>
                <enumeratedValue>
                  <name />
                  <description>PF1</description>
                  <value>1</value>
                </enumeratedValue>
                <enumeratedValue>
                  <name />
                  <description>PF2</description>
                  <value>2</value>
                </enumeratedValue>
                <enumeratedValue>
                  <name />
                  <description>PF3</description>
                  <value>3</value>
                </enumeratedValue>
              </enumeratedValues>
            </field>
            <field>
              <name>EXTI_ESEL</name>
              <description>EXTI_ESEL  field description</description>
              <bitRange>[7:0]</bitRange>
              <access>read-write</access>
              <enumeratedValues>
                <enumeratedValue>
                  <name />
                  <description>PE8</description>
                  <value>0</value>
                </enumeratedValue>
                <enumeratedValue>
                  <name />
                  <description>PE9</description>
                  <value>1</value>
                </enumeratedValue>
                <enumeratedValue>
                  <name />
                  <description>PE10</description>
                  <value>2</value>
                </enumeratedValue>
                <enumeratedValue>
                  <name />
                  <description>PE11</description>
                  <value>3</value>
                </enumeratedValue>
                <enumeratedValue>
                  <name />
                  <description>PE4</description>
                  <value>0</value>
                </enumeratedValue>
                <enumeratedValue>
                  <name />
                  <description>PE5</description>
                  <value>1</value>
                </enumeratedValue>
                <enumeratedValue>
                  <name />
                  <description>PE6</description>
                  <value>2</value>
                </enumeratedValue>
                <enumeratedValue>
                  <name />
                  <description>PE7</description>
                  <value>3</value>
                </enumeratedValue>
                <enumeratedValue>
                  <name />
                  <description>PE0</description>
                  <value>0</value>
                </enumeratedValue>
                <enumeratedValue>
                  <name />
                  <description>PE1</description>
                  <value>1</value>
                </enumeratedValue>
                <enumeratedValue>
                  <name />
                  <description>PE2</description>
                  <value>2</value>
                </enumeratedValue>
                <enumeratedValue>
                  <name />
                  <description>PE3</description>
                  <value>3</value>
                </enumeratedValue>
              </enumeratedValues>
            </field>
          </fields>
        </register>
        <register>
          <name>EXTIEDS0</name>
          <description>External Interrupt Edge Select and Enable Register0</description>
          <addressOffset>0x8</addressOffset>
          <size>32</size>
          <access>read-write</access>
          <resetValue>0xffffffff</resetValue>
          <fields>
            <field>
              <name>EXTI15_EDS</name>
              <description>EXTI15_EDS  field description</description>
              <bitRange>[31:30]</bitRange>
              <access>read-write</access>
              <enumeratedValues>
                <enumeratedValue>
                  <name />
                  <description>rising</description>
                  <value>0</value>
                </enumeratedValue>
                <enumeratedValue>
                  <name />
                  <description>falling</description>
                  <value>1</value>
                </enumeratedValue>
                <enumeratedValue>
                  <name />
                  <description>both</description>
                  <value>2</value>
                </enumeratedValue>
                <enumeratedValue>
                  <name />
                  <description>disable</description>
                  <value>3</value>
                </enumeratedValue>
              </enumeratedValues>
            </field>
            <field>
              <name>EXTI14_EDS</name>
              <description>EXTI14_EDS  field description</description>
              <bitRange>[29:28]</bitRange>
              <access>read-write</access>
              <enumeratedValues>
                <enumeratedValue>
                  <name />
                  <description>rising</description>
                  <value>0</value>
                </enumeratedValue>
                <enumeratedValue>
                  <name />
                  <description>falling</description>
                  <value>1</value>
                </enumeratedValue>
                <enumeratedValue>
                  <name />
                  <description>both</description>
                  <value>2</value>
                </enumeratedValue>
                <enumeratedValue>
                  <name />
                  <description>disable</description>
                  <value>3</value>
                </enumeratedValue>
              </enumeratedValues>
            </field>
            <field>
              <name>EXTI13_EDS</name>
              <description>EXTI13_EDS  field description</description>
              <bitRange>[27:26]</bitRange>
              <access>read-write</access>
              <enumeratedValues>
                <enumeratedValue>
                  <name />
                  <description>rising</description>
                  <value>0</value>
                </enumeratedValue>
                <enumeratedValue>
                  <name />
                  <description>falling</description>
                  <value>1</value>
                </enumeratedValue>
                <enumeratedValue>
                  <name />
                  <description>both</description>
                  <value>2</value>
                </enumeratedValue>
                <enumeratedValue>
                  <name />
                  <description>disable</description>
                  <value>3</value>
                </enumeratedValue>
              </enumeratedValues>
            </field>
            <field>
              <name>EXTI12_EDS</name>
              <description>EXTI12_EDS  field description</description>
              <bitRange>[25:24]</bitRange>
              <access>read-write</access>
              <enumeratedValues>
                <enumeratedValue>
                  <name />
                  <description>rising</description>
                  <value>0</value>
                </enumeratedValue>
                <enumeratedValue>
                  <name />
                  <description>falling</description>
                  <value>1</value>
                </enumeratedValue>
                <enumeratedValue>
                  <name />
                  <description>both</description>
                  <value>2</value>
                </enumeratedValue>
                <enumeratedValue>
                  <name />
                  <description>disable</description>
                  <value>3</value>
                </enumeratedValue>
              </enumeratedValues>
            </field>
            <field>
              <name>EXTI11_EDS</name>
              <description>EXTI11_EDS  field description</description>
              <bitRange>[23:22]</bitRange>
              <access>read-write</access>
              <enumeratedValues>
                <enumeratedValue>
                  <name />
                  <description>rising</description>
                  <value>0</value>
                </enumeratedValue>
                <enumeratedValue>
                  <name />
                  <description>falling</description>
                  <value>1</value>
                </enumeratedValue>
                <enumeratedValue>
                  <name />
                  <description>both</description>
                  <value>2</value>
                </enumeratedValue>
                <enumeratedValue>
                  <name />
                  <description>disable</description>
                  <value>3</value>
                </enumeratedValue>
              </enumeratedValues>
            </field>
            <field>
              <name>EXTI10_EDS</name>
              <description>EXTI10_EDS  field description</description>
              <bitRange>[21:20]</bitRange>
              <access>read-write</access>
              <enumeratedValues>
                <enumeratedValue>
                  <name />
                  <description>rising</description>
                  <value>0</value>
                </enumeratedValue>
                <enumeratedValue>
                  <name />
                  <description>falling</description>
                  <value>1</value>
                </enumeratedValue>
                <enumeratedValue>
                  <name />
                  <description>both</description>
                  <value>2</value>
                </enumeratedValue>
                <enumeratedValue>
                  <name />
                  <description>disable</description>
                  <value>3</value>
                </enumeratedValue>
              </enumeratedValues>
            </field>
            <field>
              <name>EXTI9_EDS</name>
              <description>EXTI9_EDS  field description</description>
              <bitRange>[19:18]</bitRange>
              <access>read-write</access>
              <enumeratedValues>
                <enumeratedValue>
                  <name />
                  <description>rising</description>
                  <value>0</value>
                </enumeratedValue>
                <enumeratedValue>
                  <name />
                  <description>falling</description>
                  <value>1</value>
                </enumeratedValue>
                <enumeratedValue>
                  <name />
                  <description>both</description>
                  <value>2</value>
                </enumeratedValue>
                <enumeratedValue>
                  <name />
                  <description>disable</description>
                  <value>3</value>
                </enumeratedValue>
              </enumeratedValues>
            </field>
            <field>
              <name>EXTI8_EDS</name>
              <description>EXTI8_EDS  field description</description>
              <bitRange>[17:16]</bitRange>
              <access>read-write</access>
              <enumeratedValues>
                <enumeratedValue>
                  <name />
                  <description>rising</description>
                  <value>0</value>
                </enumeratedValue>
                <enumeratedValue>
                  <name />
                  <description>falling</description>
                  <value>1</value>
                </enumeratedValue>
                <enumeratedValue>
                  <name />
                  <description>both</description>
                  <value>2</value>
                </enumeratedValue>
                <enumeratedValue>
                  <name />
                  <description>disable</description>
                  <value>3</value>
                </enumeratedValue>
              </enumeratedValues>
            </field>
            <field>
              <name>EXTI7_EDS</name>
              <description>EXTI7_EDS  field description</description>
              <bitRange>[15:14]</bitRange>
              <access>read-write</access>
              <enumeratedValues>
                <enumeratedValue>
                  <name />
                  <description>rising</description>
                  <value>0</value>
                </enumeratedValue>
                <enumeratedValue>
                  <name />
                  <description>falling</description>
                  <value>1</value>
                </enumeratedValue>
                <enumeratedValue>
                  <name />
                  <description>both</description>
                  <value>2</value>
                </enumeratedValue>
                <enumeratedValue>
                  <name />
                  <description>disable</description>
                  <value>3</value>
                </enumeratedValue>
              </enumeratedValues>
            </field>
            <field>
              <name>EXTI6_EDS</name>
              <description>EXTI6_EDS  field description</description>
              <bitRange>[13:12]</bitRange>
              <access>read-write</access>
              <enumeratedValues>
                <enumeratedValue>
                  <name />
                  <description>rising</description>
                  <value>0</value>
                </enumeratedValue>
                <enumeratedValue>
                  <name />
                  <description>falling</description>
                  <value>1</value>
                </enumeratedValue>
                <enumeratedValue>
                  <name />
                  <description>both</description>
                  <value>2</value>
                </enumeratedValue>
                <enumeratedValue>
                  <name />
                  <description>disable</description>
                  <value>3</value>
                </enumeratedValue>
              </enumeratedValues>
            </field>
            <field>
              <name>EXTI5_EDS</name>
              <description>EXTI5_EDS  field description</description>
              <bitRange>[11:10]</bitRange>
              <access>read-write</access>
              <enumeratedValues>
                <enumeratedValue>
                  <name />
                  <description>rising</description>
                  <value>0</value>
                </enumeratedValue>
                <enumeratedValue>
                  <name />
                  <description>falling</description>
                  <value>1</value>
                </enumeratedValue>
                <enumeratedValue>
                  <name />
                  <description>both</description>
                  <value>2</value>
                </enumeratedValue>
                <enumeratedValue>
                  <name />
                  <description>disable</description>
                  <value>3</value>
                </enumeratedValue>
              </enumeratedValues>
            </field>
            <field>
              <name>EXTI4_EDS</name>
              <description>EXTI4_EDS  field description</description>
              <bitRange>[9:8]</bitRange>
              <access>read-write</access>
              <enumeratedValues>
                <enumeratedValue>
                  <name />
                  <description>rising</description>
                  <value>0</value>
                </enumeratedValue>
                <enumeratedValue>
                  <name />
                  <description>falling</description>
                  <value>1</value>
                </enumeratedValue>
                <enumeratedValue>
                  <name />
                  <description>both</description>
                  <value>2</value>
                </enumeratedValue>
                <enumeratedValue>
                  <name />
                  <description>disable</description>
                  <value>3</value>
                </enumeratedValue>
              </enumeratedValues>
            </field>
            <field>
              <name>EXTI3_EDS</name>
              <description>EXTI3_EDS  field description</description>
              <bitRange>[7:6]</bitRange>
              <access>read-write</access>
              <enumeratedValues>
                <enumeratedValue>
                  <name />
                  <description>rising</description>
                  <value>0</value>
                </enumeratedValue>
                <enumeratedValue>
                  <name />
                  <description>falling</description>
                  <value>1</value>
                </enumeratedValue>
                <enumeratedValue>
                  <name />
                  <description>both</description>
                  <value>2</value>
                </enumeratedValue>
                <enumeratedValue>
                  <name />
                  <description>disable</description>
                  <value>3</value>
                </enumeratedValue>
              </enumeratedValues>
            </field>
            <field>
              <name>EXTI2_EDS</name>
              <description>EXTI2_EDS  field description</description>
              <bitRange>[5:4]</bitRange>
              <access>read-write</access>
              <enumeratedValues>
                <enumeratedValue>
                  <name />
                  <description>rising</description>
                  <value>0</value>
                </enumeratedValue>
                <enumeratedValue>
                  <name />
                  <description>falling</description>
                  <value>1</value>
                </enumeratedValue>
                <enumeratedValue>
                  <name />
                  <description>both</description>
                  <value>2</value>
                </enumeratedValue>
                <enumeratedValue>
                  <name />
                  <description>disable</description>
                  <value>3</value>
                </enumeratedValue>
              </enumeratedValues>
            </field>
            <field>
              <name>EXTI1_EDS</name>
              <description>EXTI1_EDS  field description</description>
              <bitRange>[3:2]</bitRange>
              <access>read-write</access>
              <enumeratedValues>
                <enumeratedValue>
                  <name />
                  <description>rising</description>
                  <value>0</value>
                </enumeratedValue>
                <enumeratedValue>
                  <name />
                  <description>falling</description>
                  <value>1</value>
                </enumeratedValue>
                <enumeratedValue>
                  <name />
                  <description>both</description>
                  <value>2</value>
                </enumeratedValue>
                <enumeratedValue>
                  <name />
                  <description>disable</description>
                  <value>3</value>
                </enumeratedValue>
              </enumeratedValues>
            </field>
            <field>
              <name>EXTI0_EDS</name>
              <description>EXTI0_EDS  field description</description>
              <bitRange>[1:0]</bitRange>
              <access>read-write</access>
              <enumeratedValues>
                <enumeratedValue>
                  <name />
                  <description>rising</description>
                  <value>0</value>
                </enumeratedValue>
                <enumeratedValue>
                  <name />
                  <description>falling</description>
                  <value>1</value>
                </enumeratedValue>
                <enumeratedValue>
                  <name />
                  <description>both</description>
                  <value>2</value>
                </enumeratedValue>
                <enumeratedValue>
                  <name />
                  <description>disable</description>
                  <value>3</value>
                </enumeratedValue>
              </enumeratedValues>
            </field>
          </fields>
        </register>
        <register>
          <name>EXTIEDS1</name>
          <description>External Interrupt Edge Select and Enable Register1</description>
          <addressOffset>0xc</addressOffset>
          <size>32</size>
          <access>read-write</access>
          <resetValue>0x0000ffff</resetValue>
          <fields>
            <field>
              <name>EXTI23_EDS</name>
              <description>EXTI23_EDS  field description</description>
              <bitRange>[15:14]</bitRange>
              <access>read-write</access>
              <enumeratedValues>
                <enumeratedValue>
                  <name />
                  <description>rising</description>
                  <value>0</value>
                </enumeratedValue>
                <enumeratedValue>
                  <name />
                  <description>falling</description>
                  <value>1</value>
                </enumeratedValue>
                <enumeratedValue>
                  <name />
                  <description>both</description>
                  <value>2</value>
                </enumeratedValue>
                <enumeratedValue>
                  <name />
                  <description>disable</description>
                  <value>3</value>
                </enumeratedValue>
              </enumeratedValues>
            </field>
            <field>
              <name>EXTI22_EDS</name>
              <description>EXTI22_EDS  field description</description>
              <bitRange>[13:12]</bitRange>
              <access>read-write</access>
              <enumeratedValues>
                <enumeratedValue>
                  <name />
                  <description>rising</description>
                  <value>0</value>
                </enumeratedValue>
                <enumeratedValue>
                  <name />
                  <description>falling</description>
                  <value>1</value>
                </enumeratedValue>
                <enumeratedValue>
                  <name />
                  <description>both</description>
                  <value>2</value>
                </enumeratedValue>
                <enumeratedValue>
                  <name />
                  <description>disable</description>
                  <value>3</value>
                </enumeratedValue>
              </enumeratedValues>
            </field>
            <field>
              <name>EXTI21_EDS</name>
              <description>EXTI21_EDS  field description</description>
              <bitRange>[11:10]</bitRange>
              <access>read-write</access>
              <enumeratedValues>
                <enumeratedValue>
                  <name />
                  <description>rising</description>
                  <value>0</value>
                </enumeratedValue>
                <enumeratedValue>
                  <name />
                  <description>falling</description>
                  <value>1</value>
                </enumeratedValue>
                <enumeratedValue>
                  <name />
                  <description>both</description>
                  <value>2</value>
                </enumeratedValue>
                <enumeratedValue>
                  <name />
                  <description>disable</description>
                  <value>3</value>
                </enumeratedValue>
              </enumeratedValues>
            </field>
            <field>
              <name>EXTI20_EDS</name>
              <description>EXTI20_EDS  field description</description>
              <bitRange>[9:8]</bitRange>
              <access>read-write</access>
              <enumeratedValues>
                <enumeratedValue>
                  <name />
                  <description>rising</description>
                  <value>0</value>
                </enumeratedValue>
                <enumeratedValue>
                  <name />
                  <description>falling</description>
                  <value>1</value>
                </enumeratedValue>
                <enumeratedValue>
                  <name />
                  <description>both</description>
                  <value>2</value>
                </enumeratedValue>
                <enumeratedValue>
                  <name />
                  <description>disable</description>
                  <value>3</value>
                </enumeratedValue>
              </enumeratedValues>
            </field>
            <field>
              <name>EXTI19_EDS</name>
              <description>EXTI19_EDS  field description</description>
              <bitRange>[7:6]</bitRange>
              <access>read-write</access>
              <enumeratedValues>
                <enumeratedValue>
                  <name />
                  <description>rising</description>
                  <value>0</value>
                </enumeratedValue>
                <enumeratedValue>
                  <name />
                  <description>falling</description>
                  <value>1</value>
                </enumeratedValue>
                <enumeratedValue>
                  <name />
                  <description>both</description>
                  <value>2</value>
                </enumeratedValue>
                <enumeratedValue>
                  <name />
                  <description>disable</description>
                  <value>3</value>
                </enumeratedValue>
              </enumeratedValues>
            </field>
            <field>
              <name>EXTI18_EDS</name>
              <description>EXTI18_EDS  field description</description>
              <bitRange>[5:4]</bitRange>
              <access>read-write</access>
              <enumeratedValues>
                <enumeratedValue>
                  <name />
                  <description>rising</description>
                  <value>0</value>
                </enumeratedValue>
                <enumeratedValue>
                  <name />
                  <description>falling</description>
                  <value>1</value>
                </enumeratedValue>
                <enumeratedValue>
                  <name />
                  <description>both</description>
                  <value>2</value>
                </enumeratedValue>
                <enumeratedValue>
                  <name />
                  <description>disable</description>
                  <value>3</value>
                </enumeratedValue>
              </enumeratedValues>
            </field>
            <field>
              <name>EXTI17_EDS</name>
              <description>EXTI17_EDS  field description</description>
              <bitRange>[3:2]</bitRange>
              <access>read-write</access>
              <enumeratedValues>
                <enumeratedValue>
                  <name />
                  <description>rising</description>
                  <value>0</value>
                </enumeratedValue>
                <enumeratedValue>
                  <name />
                  <description>falling</description>
                  <value>1</value>
                </enumeratedValue>
                <enumeratedValue>
                  <name />
                  <description>both</description>
                  <value>2</value>
                </enumeratedValue>
                <enumeratedValue>
                  <name />
                  <description>disable</description>
                  <value>3</value>
                </enumeratedValue>
              </enumeratedValues>
            </field>
            <field>
              <name>EXTI16_EDS</name>
              <description>EXTI16_EDS  field description</description>
              <bitRange>[1:0]</bitRange>
              <access>read-write</access>
              <enumeratedValues>
                <enumeratedValue>
                  <name />
                  <description>rising</description>
                  <value>0</value>
                </enumeratedValue>
                <enumeratedValue>
                  <name />
                  <description>falling</description>
                  <value>1</value>
                </enumeratedValue>
                <enumeratedValue>
                  <name />
                  <description>both</description>
                  <value>2</value>
                </enumeratedValue>
                <enumeratedValue>
                  <name />
                  <description>disable</description>
                  <value>3</value>
                </enumeratedValue>
              </enumeratedValues>
            </field>
          </fields>
        </register>
        <register>
          <name>EXTIDF</name>
          <description>External Interrupt Digital Filter Register</description>
          <addressOffset>0x10</addressOffset>
          <size>32</size>
          <access>read-write</access>
          <resetValue>0x00000000</resetValue>
          <fields>
            <field>
              <name>EXTI_DF</name>
              <description>EXTI_DF  field description</description>
              <bitRange>[23:0]</bitRange>
              <access>read-write</access>
              <enumeratedValues>
                <enumeratedValue>
                  <name />
                  <description>关闭EXTI数字滤波</description>
                  <value>0</value>
                </enumeratedValue>
                <enumeratedValue>
                  <name />
                  <description>使能EXTI数字滤波</description>
                  <value>1</value>
                </enumeratedValue>
              </enumeratedValues>
            </field>
          </fields>
        </register>
        <register>
          <name>EXTIISR</name>
          <description>External Interrupt and Status Register</description>
          <addressOffset>0x14</addressOffset>
          <size>32</size>
          <access>read-write</access>
          <resetValue>0x00000000</resetValue>
          <fields>
            <field>
              <name>EXTI</name>
              <description>EXTI  field description</description>
              <bitRange>[23:0]</bitRange>
              <access>read-write</access>
              <enumeratedValues />
            </field>
          </fields>
        </register>
        <register>
          <name>EXTIDI</name>
          <description>External Interrupt Data Input Register</description>
          <addressOffset>0x18</addressOffset>
          <size>32</size>
          <access>read-write</access>
          <resetValue>0x00000000</resetValue>
          <fields>
            <field>
              <name>EXTI_DI</name>
              <description>EXTI_DI  field description</description>
              <bitRange>[23:0]</bitRange>
              <access>read-only</access>
              <enumeratedValues>
                <enumeratedValue>
                  <name />
                  <description>当使能了数字滤波后，软件可以从这个寄存器读取到某个IO输入信号滤波后的状态。</description>
                  <value>0</value>
                </enumeratedValue>
              </enumeratedValues>
            </field>
          </fields>
        </register>
        <register>
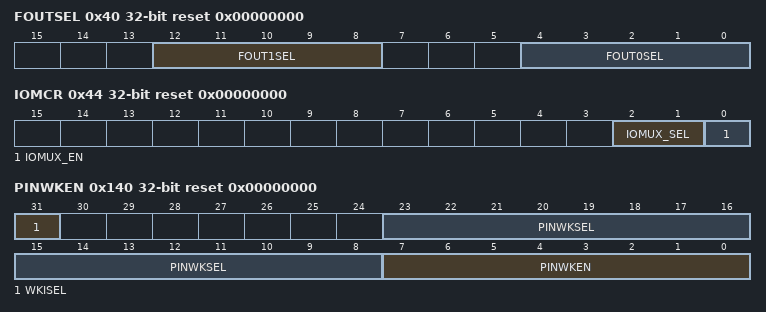
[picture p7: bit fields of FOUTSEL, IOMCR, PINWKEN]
          <name>FOUTSEL</name>
          <description>Frequency Output Select Register</description>
          <addressOffset>0x40</addressOffset>
          <size>32</size>
          <access>read-write</access>
          <resetValue>0x00000000</resetValue>
          <fields>
            <field>
              <name>FOUT1SEL</name>
              <description>FOUT1SEL  field description</description>
              <bitRange>[12:8]</bitRange>
              <access>read-write</access>
              <enumeratedValues>
                <enumeratedValue>
                  <name />
                  <description>XTLF</description>
                  <value>0</value>
                </enumeratedValue>
                <enumeratedValue>
                  <name />
                  <description>RCLP</description>
                  <value>1</value>
                </enumeratedValue>
                <enumeratedValue>
                  <name />
                  <description>RCHF/64</description>
                  <value>2</value>
                </enumeratedValue>
                <enumeratedValue>
                  <name />
                  <description>LSCLK</description>
                  <value>3</value>
                </enumeratedValue>
                <enumeratedValue>
                  <name />
                  <description>AHBCLK/64</description>
                  <value>4</value>
                </enumeratedValue>
                <enumeratedValue>
                  <name />
                  <description>RTC_TM</description>
                  <value>5</value>
                </enumeratedValue>
                <enumeratedValue>
                  <name />
                  <description>PLL_H/64</description>
                  <value>6</value>
                </enumeratedValue>
                <enumeratedValue>
                  <name />
                  <description>RTCCLK64Hz</description>
                  <value>7</value>
                </enumeratedValue>
                <enumeratedValue>
                  <name />
                  <description>APBCLK/64</description>
                  <value>8</value>
                </enumeratedValue>
                <enumeratedValue>
                  <name />
                  <description>PLL_L</description>
                  <value>9</value>
                </enumeratedValue>
                <enumeratedValue>
                  <name />
                  <description>RCMF</description>
                  <value>a</value>
                </enumeratedValue>
                <enumeratedValue>
                  <name />
                  <description>RCHF</description>
                  <value>b</value>
                </enumeratedValue>
                <enumeratedValue>
                  <name />
                  <description>XTHF/64</description>
                  <value>c</value>
                </enumeratedValue>
                <enumeratedValue>
                  <name />
                  <description>ADCCLK</description>
                  <value>d</value>
                </enumeratedValue>
                <enumeratedValue>
                  <name />
                  <description>PLL_H</description>
                  <value>e</value>
                </enumeratedValue>
                <enumeratedValue>
                  <name />
                  <description>Reserved</description>
                  <value>f</value>
                </enumeratedValue>
                <enumeratedValue>
                  <name />
                  <description>Boost Flag</description>
                  <value>10</value>
                </enumeratedValue>
                <enumeratedValue>
                  <name />
                  <description>Autotrim output</description>
                  <value>11</value>
                </enumeratedValue>
                <enumeratedValue>
                  <name />
                  <description>Reserved</description>
                  <value>12</value>
                </enumeratedValue>
                <enumeratedValue>
                  <name />
                  <description>Reserved</description>
                  <value>13</value>
                </enumeratedValue>
              </enumeratedValues>
            </field>
            <field>
              <name>FOUT0SEL</name>
              <description>FOUT0SEL  field description</description>
              <bitRange>[4:0]</bitRange>
              <access>read-write</access>
              <enumeratedValues>
                <enumeratedValue>
                  <name />
                  <description>XTLF</description>
                  <value>0</value>
                </enumeratedValue>
                <enumeratedValue>
                  <name />
                  <description>RCLP</description>
                  <value>1</value>
                </enumeratedValue>
                <enumeratedValue>
                  <name />
                  <description>RCHF/64</description>
                  <value>2</value>
                </enumeratedValue>
                <enumeratedValue>
                  <name />
                  <description>LSCLK</description>
                  <value>3</value>
                </enumeratedValue>
                <enumeratedValue>
                  <name />
                  <description>AHBCLK/64</description>
                  <value>4</value>
                </enumeratedValue>
                <enumeratedValue>
                  <name />
                  <description>RTC_TM</description>
                  <value>5</value>
                </enumeratedValue>
                <enumeratedValue>
                  <name />
                  <description>PLL_H/64</description>
                  <value>6</value>
                </enumeratedValue>
                <enumeratedValue>
                  <name />
                  <description>RTCCLK64Hz</description>
                  <value>7</value>
                </enumeratedValue>
                <enumeratedValue>
                  <name />
                  <description>APBCLK/64</description>
                  <value>8</value>
                </enumeratedValue>
                <enumeratedValue>
                  <name />
                  <description>PLL_L</description>
                  <value>9</value>
                </enumeratedValue>
                <enumeratedValue>
                  <name />
                  <description>RCMF</description>
                  <value>a</value>
                </enumeratedValue>
                <enumeratedValue>
                  <name />
                  <description>RCHF</description>
                  <value>b</value>
                </enumeratedValue>
                <enumeratedValue>
                  <name />
                  <description>XTHF/64</description>
                  <value>c</value>
                </enumeratedValue>
                <enumeratedValue>
                  <name />
                  <description>ADCCLK</description>
                  <value>d</value>
                </enumeratedValue>
                <enumeratedValue>
                  <name />
                  <description>PLL_H</description>
                  <value>e</value>
                </enumeratedValue>
                <enumeratedValue>
                  <name />
                  <description>Reserved</description>
                  <value>f</value>
                </enumeratedValue>
                <enumeratedValue>
                  <name />
                  <description>Boost Flag</description>
                  <value>10</value>
                </enumeratedValue>
                <enumeratedValue>
                  <name />
                  <description>Reserved</description>
                  <value>11</value>
                </enumeratedValue>
                <enumeratedValue>
                  <name />
                  <description>Reserved</description>
                  <value>12</value>
                </enumeratedValue>
                <enumeratedValue>
                  <name />
                  <description>Reserved</description>
                  <value>13</value>
                </enumeratedValue>
              </enumeratedValues>
            </field>
          </fields>
        </register>
        <register>
          <name>IOMCR</name>
          <description>IO MUX Control Register</description>
          <addressOffset>0x44</addressOffset>
          <size>32</size>
          <access>read-write</access>
          <resetValue>0x00000000</resetValue>
          <fields>
            <field>
              <name>IOMUX_SEL</name>
              <description>IOMUX_SEL  field description</description>
              <bitRange>[2:1]</bitRange>
              <access>read-write</access>
              <enumeratedValues>
                <enumeratedValue>
                  <name />
                  <description>PD6</description>
                  <value>0</value>
                </enumeratedValue>
                <enumeratedValue>
                  <name />
                  <description>PD7</description>
                  <value>1</value>
                </enumeratedValue>
                <enumeratedValue>
                  <name />
                  <description>PG2</description>
                  <value>2</value>
                </enumeratedValue>
                <enumeratedValue>
                  <name />
                  <description>PG3</description>
                  <value>3</value>
                </enumeratedValue>
              </enumeratedValues>
            </field>
            <field>
              <name>IOMUX_EN</name>
              <description>IOMUX_EN  field description</description>
              <bitRange>[0:0]</bitRange>
              <access>read-write</access>
              <enumeratedValues>
                <enumeratedValue>
                  <name />
                  <description>关闭IO MUX功能</description>
                  <value>0</value>
                </enumeratedValue>
                <enumeratedValue>
                  <name />
                  <description>使能IO MUX功能</description>
                  <value>1</value>
                </enumeratedValue>
              </enumeratedValues>
            </field>
          </fields>
        </register>
        <register>
          <name>PINWKEN</name>
          <description>Wakeup Enable Register</description>
          <addressOffset>0x140</addressOffset>
          <size>32</size>
          <access>read-write</access>
          <resetValue>0x00000000</resetValue>
          <fields>
            <field>
              <name>WKISEL</name>
              <description>WKISEL  field description</description>
              <bitRange>[31:31]</bitRange>
              <access>read-write</access>
              <enumeratedValues>
                <enumeratedValue>
                  <name />
                  <description>NMI中断</description>
                  <value>0</value>
                </enumeratedValue>
                <enumeratedValue>
                  <name />
                  <description>#38入口</description>
                  <value>1</value>
                </enumeratedValue>
              </enumeratedValues>
            </field>
            <field>
              <name>PINWKSEL</name>
              <description>PINWKSEL  field description</description>
              <bitRange>[23:8]</bitRange>
              <access>read-write</access>
              <enumeratedValues>
                <enumeratedValue>
                  <name />
                  <description>对应的WKUP引脚为下降沿唤醒</description>
                  <value>0</value>
                </enumeratedValue>
                <enumeratedValue>
                  <name />
                  <description>对应的WKUP引脚为上升沿唤醒</description>
                  <value>1</value>
                </enumeratedValue>
                <enumeratedValue>
                  <name />
                  <description>对应的WKUP引脚为上升、下降沿唤醒</description>
                  <value>2</value>
                </enumeratedValue>
                <enumeratedValue>
                  <name />
                  <description>对应的WKUP引脚为上升、下降沿唤醒</description>
                  <value>3</value>
                </enumeratedValue>
              </enumeratedValues>
            </field>
            <field>
              <name>PINWKEN</name>
              <description>PINWKEN  field description</description>
              <bitRange>[7:0]</bitRange>
              <access>read-write</access>
              <enumeratedValues>
                <enumeratedValue>
                  <name />
                  <description>对应的WKUP引脚功能有效</description>
                  <value>1</value>
                </enumeratedValue>
                <enumeratedValue>
                  <name />
                  <description>对应的WKUP引脚功能无效</description>
                  <value>0</value>
                </enumeratedValue>
              </enumeratedValues>
            </field>
          </fields>
        </register>
      </registers>
    </peripheral>
    <peripheral>
      <name>GPIOH</name>
      <description>GPIOH module information</description>
      <groupName>GPIOH</groupName>
      <baseAddress>0x4001fc00</baseAddress>
      <size>32</size>
      <access>read-write</access>
      <addressBlock>
        <offset>0</offset>
        <size>0x14</size>
        <usage>registers</usage>
      </addressBlock>
      <registers>
        <register>
          <name>INEN</name>
          <description>GPIOH Input Enable Register</description>
          <addressOffset>0x0</addressOffset>
          <size>32</size>
          <access>read-write</access>
          <resetValue>0x00000000</resetValue>
          <fields>
            <field>
              <name>PHINEN</name>
              <description>PHINEN  field description</description>
              <bitRange>[3:0]</bitRange>
              <access>read-write</access>
              <enumeratedValues>
                <enumeratedValue>
                  <name />
                  <description>关闭输入使能</description>
                  <value>0</value>
                </enumeratedValue>
                <enumeratedValue>
                  <name />
                  <description>打开输入使能</description>
                  <value>1</value>
                </enumeratedValue>
              </enumeratedValues>
            </field>
          </fields>
        </register>
        <register>
          <name>PUEN</name>
          <description>GPIOH Pull-Up Enable Register</description>
          <addressOffset>0x4</addressOffset>
          <size>32</size>
          <access>read-write</access>
          <resetValue>0x00000000</resetValue>
          <fields>
            <field>
              <name>PHPUEN</name>
              <description>PHPUEN  field description</description>
              <bitRange>[3:0]</bitRange>
              <access>read-write</access>
              <enumeratedValues>
                <enumeratedValue>
                  <name />
                  <description>关闭上拉</description>
                  <value>0</value>
                </enumeratedValue>
                <enumeratedValue>
                  <name />
                  <description>使能上拉</description>
                  <value>1</value>
                </enumeratedValue>
              </enumeratedValues>
            </field>
          </fields>
        </register>
        <register>
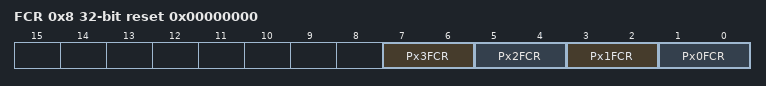
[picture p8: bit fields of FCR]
          <name>FCR</name>
          <description>GPIOH Function Control Register</description>
          <addressOffset>0x8</addressOffset>
          <size>32</size>
          <access>read-write</access>
          <resetValue>0x00000000</resetValue>
          <fields>
            <field>
              <name>Px3FCR</name>
              <description>Px3FCR  field description</description>
              <bitRange>[7:6]</bitRange>
              <access>read-write</access>
              <enumeratedValues>
                <enumeratedValue>
                  <name />
                  <description>GPIO输入</description>
                  <value>0</value>
                </enumeratedValue>
                <enumeratedValue>
                  <name />
                  <description>GPIO输出</description>
                  <value>1</value>
                </enumeratedValue>
                <enumeratedValue>
                  <name />
                  <description>Digital function (Tamper1)</description>
                  <value>2</value>
                </enumeratedValue>
                <enumeratedValue>
                  <name />
                  <description>Analog function (ADC_IN12)</description>
                  <value>3</value>
                </enumeratedValue>
              </enumeratedValues>
            </field>
            <field>
              <name>Px2FCR</name>
              <description>Px2FCR  field description</description>
              <bitRange>[5:4]</bitRange>
              <access>read-write</access>
              <enumeratedValues>
                <enumeratedValue>
                  <name />
                  <description>GPIO输入</description>
                  <value>0</value>
                </enumeratedValue>
                <enumeratedValue>
                  <name />
                  <description>GPIO输出</description>
                  <value>1</value>
                </enumeratedValue>
                <enumeratedValue>
                  <name />
                  <description>Digital function (Tamper0)</description>
                  <value>2</value>
                </enumeratedValue>
                <enumeratedValue>
                  <name />
                  <description>Analog function (ADC_IN11)</description>
                  <value>3</value>
                </enumeratedValue>
              </enumeratedValues>
            </field>
            <field>
              <name>Px1FCR</name>
              <description>Px1FCR  field description</description>
              <bitRange>[3:2]</bitRange>
              <access>read-write</access>
              <enumeratedValues>
                <enumeratedValue>
                  <name />
                  <description>GPIO输入</description>
                  <value>0</value>
                </enumeratedValue>
                <enumeratedValue>
                  <name />
                  <description>GPIO输出</description>
                  <value>1</value>
                </enumeratedValue>
                <enumeratedValue>
                  <name />
                  <description>Digital function (RTCTM)</description>
                  <value>2</value>
                </enumeratedValue>
                <enumeratedValue>
                  <name />
                  <description>Analog function (ADC_IN10)</description>
                  <value>3</value>
                </enumeratedValue>
              </enumeratedValues>
            </field>
            <field>
              <name>Px0FCR</name>
              <description>Px0FCR  field description</description>
              <bitRange>[1:0]</bitRange>
              <access>read-write</access>
              <enumeratedValues>
                <enumeratedValue>
                  <name />
                  <description>GPIO输入</description>
                  <value>0</value>
                </enumeratedValue>
                <enumeratedValue>
                  <name />
                  <description>GPIO输出</description>
                  <value>1</value>
                </enumeratedValue>
                <enumeratedValue>
                  <name />
                  <description>Digital function (RFU)</description>
                  <value>2</value>
                </enumeratedValue>
                <enumeratedValue>
                  <name />
                  <description>Analog function (ADC_IN9)</description>
                  <value>3</value>
                </enumeratedValue>
              </enumeratedValues>
            </field>
          </fields>
        </register>
        <register>
          <name>DO</name>
          <description>GPIOH Data Output Register</description>
          <addressOffset>0xc</addressOffset>
          <size>32</size>
          <access>read-write</access>
          <resetValue>0x00000000</resetValue>
          <fields>
            <field>
              <name>PHDO</name>
              <description>PHDO  field description</description>
              <bitRange>[3:0]</bitRange>
              <access>read-write</access>
              <enumeratedValues />
            </field>
          </fields>
        </register>
        <register>
          <name>DIN</name>
          <description>GPIOH Data Input Register</description>
          <addressOffset>0x10</addressOffset>
          <size>32</size>
          <access>read-write</access>
          <resetValue>0x00000000</resetValue>
          <fields>
            <field>
              <name>PHDIN</name>
              <description>PHDIN  field description</description>
              <bitRange>[3:0]</bitRange>
              <access>read-only</access>
              <enumeratedValues />
            </field>
          </fields>
        </register>
      </registers>
    </peripheral>
  </peripherals>
</device>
